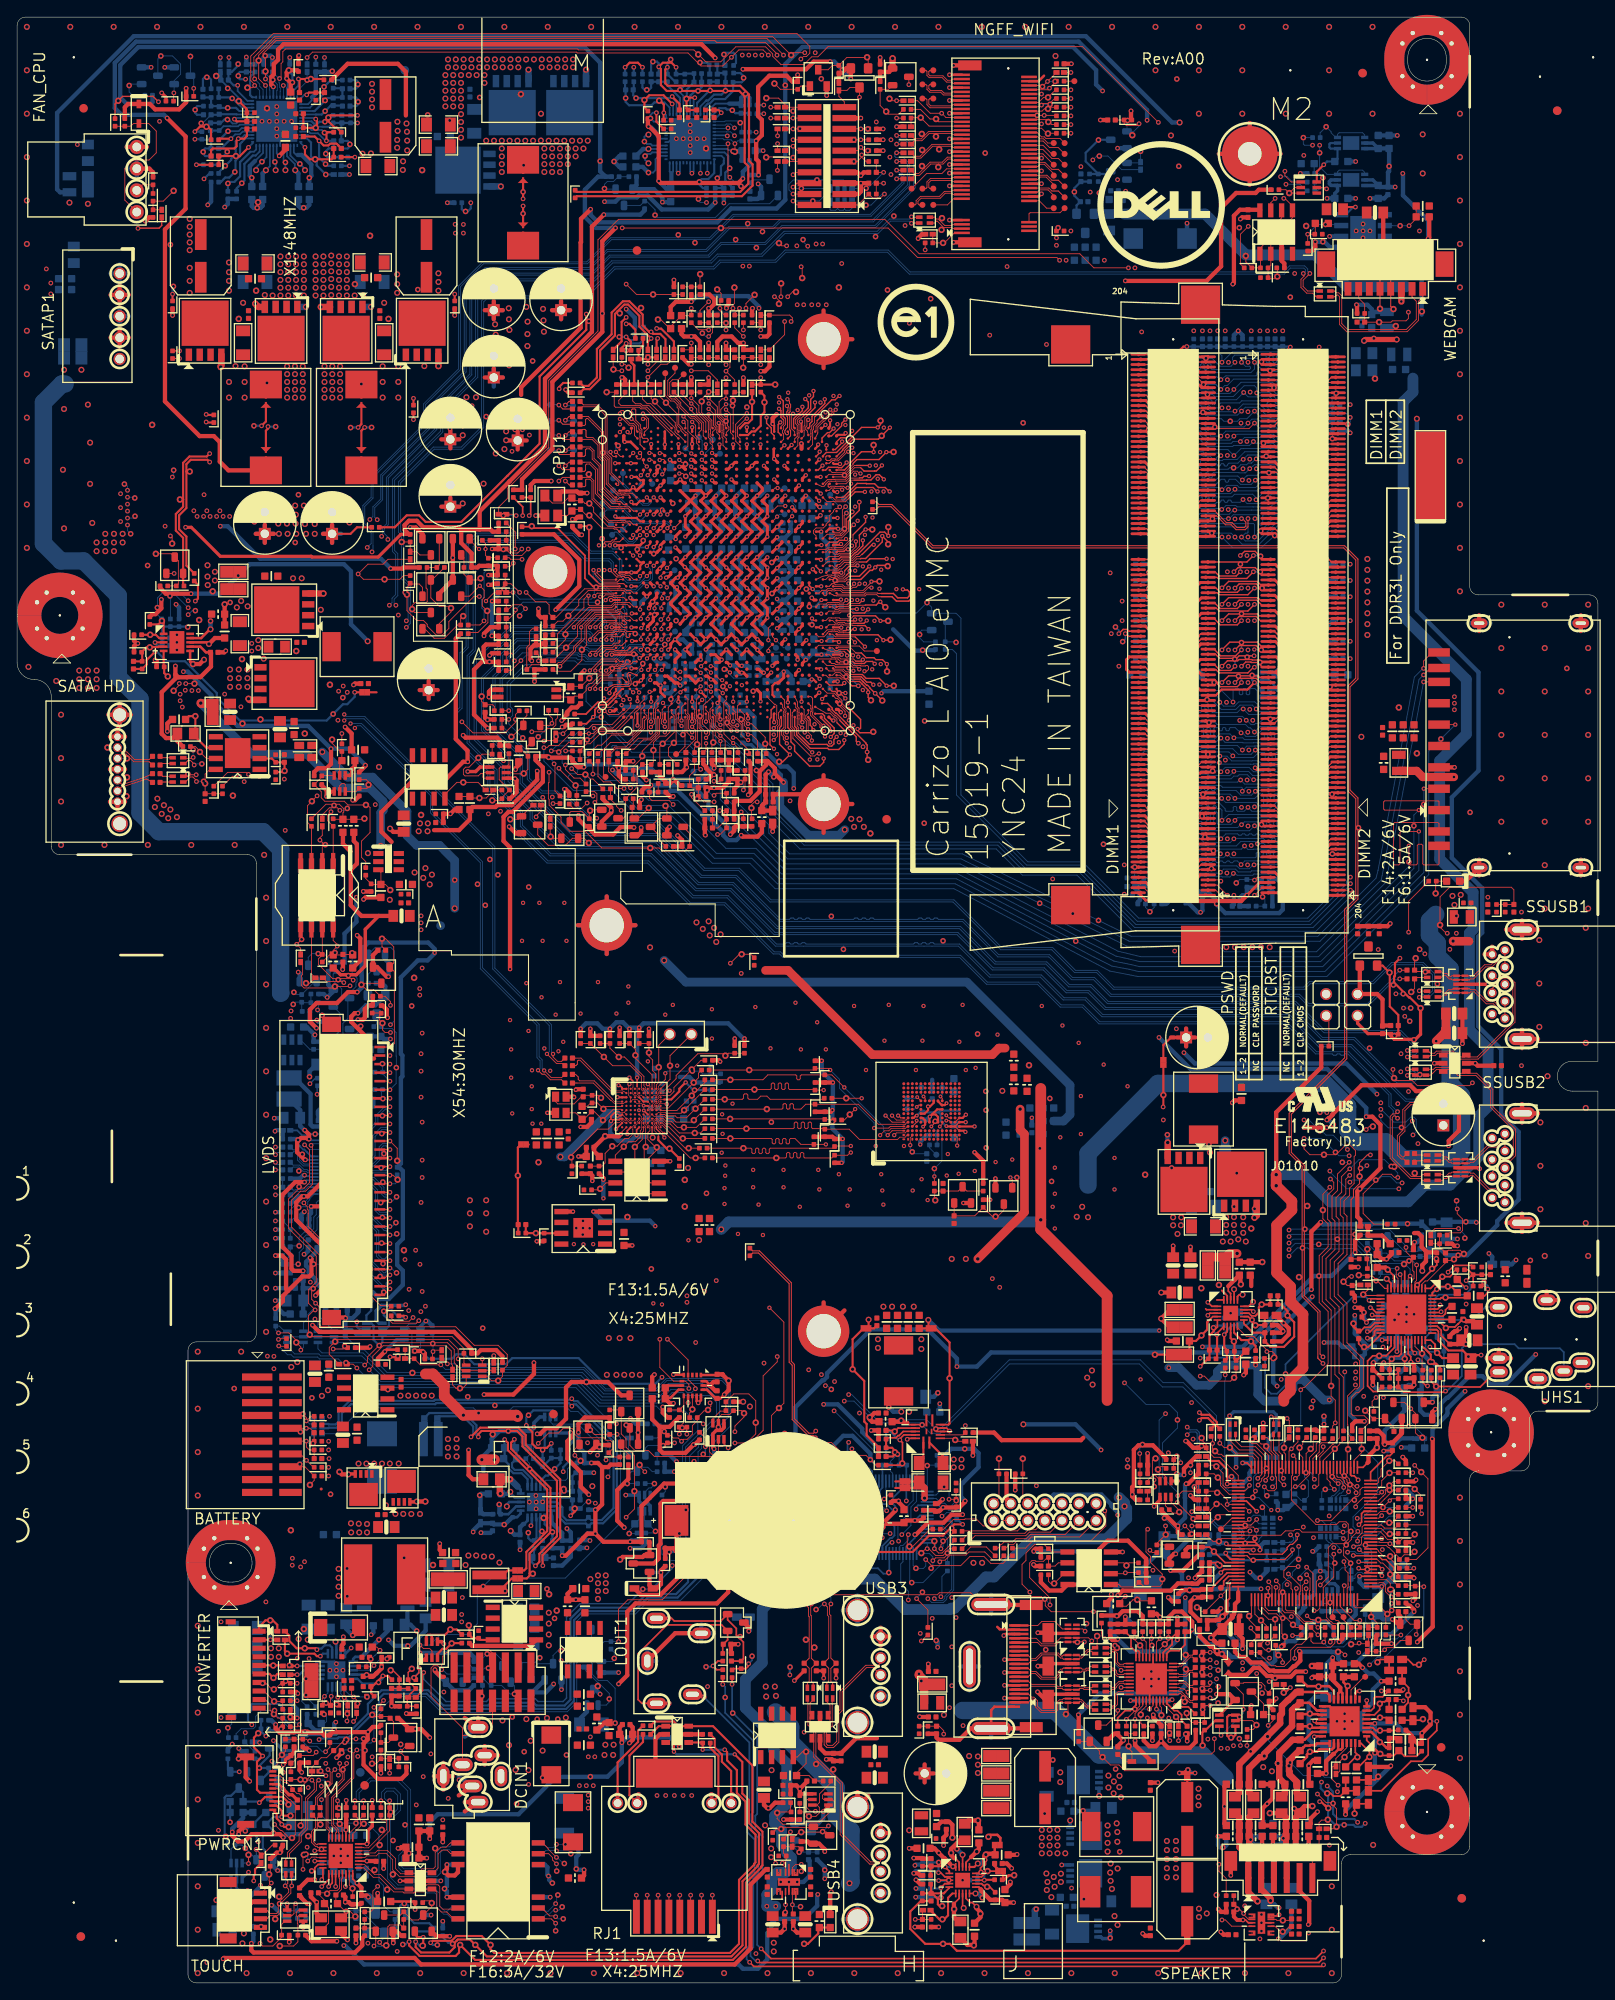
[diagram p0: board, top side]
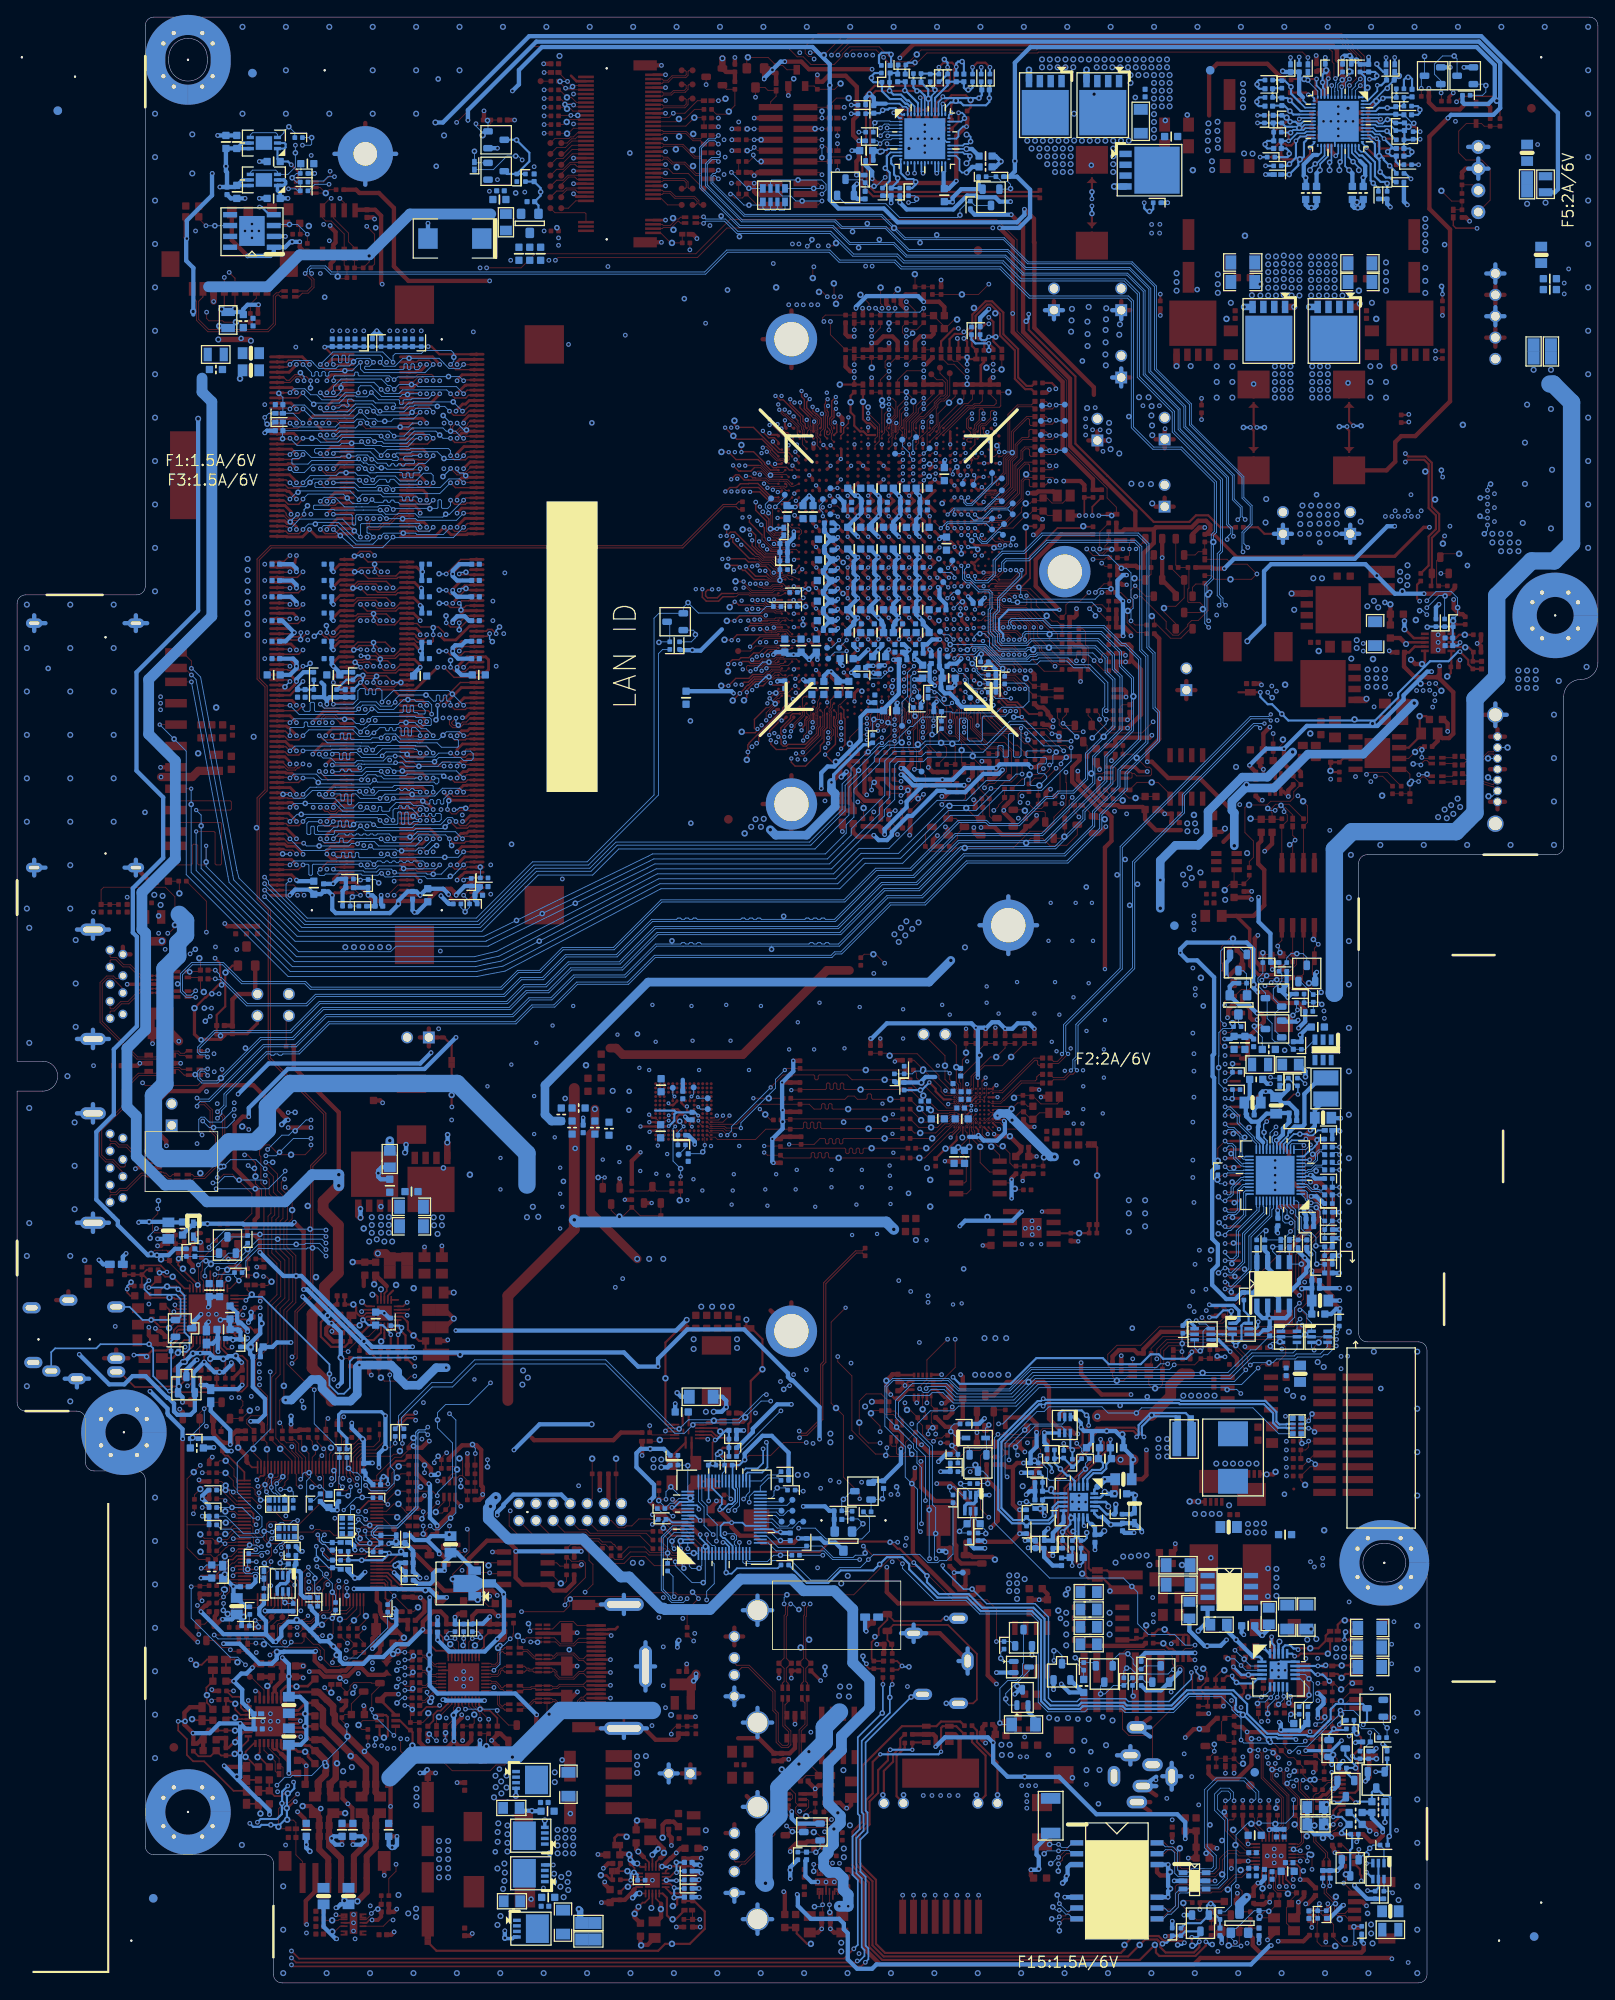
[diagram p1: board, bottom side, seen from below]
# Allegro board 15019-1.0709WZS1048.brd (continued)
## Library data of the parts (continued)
R358 = R402H16: tolerance: 64.56015.6DL
R376 = R603H22: tolerance: 63.10033.15L
R389 R79726 = R805H24: tolerance: 64.10025.16L
R396 R403 R415 R419 = R603H22: tolerance: 64.3R305.55L
R412 = R402H16: tolerance: 64.24915.6DL
R428 R429 = R402H16: tolerance: 63.47034.1DL
R495 R1617 R1623 = R402H16: tolerance: 63.30134.1DL
R511 = R402H16: tolerance: 64.12025.6DL
R558 = R402H16: tolerance: 64.16915.6DL
R617 R79721 = R402H16: tolerance: 63.33334.1DL
R724 R730 R735 R1751 R79612 = R603H22: tolerance: 64.75R05.55L
R1592 = R603H22: tolerance: 64.36R05.55L
R1593 R1594 R1596 R1598 R2085-R2090 = R402H16: tolerance: 64.47015.6DL
R1603 R1816 = R402H16: tolerance: 64.20015.6DL
R1671 = R603H22: tolerance: 63.20634.15L
R1677 R90067 = R402H16: tolerance: 63.47334.1DL
R1767 R1846 = R603H22: tolerance: 63.15234.15L
R1833 R1838 = R402H16: tolerance: 64.17825.6DL
R1847 = R603H22: tolerance: 64.10035.L0L
R1848 = R603H22: tolerance: 63.10333.15L
R1850 = R603H22: tolerance: 64.56025.55L
R1867 R1869 R1871 R1873 R2004 R2008 R2063 = R402H16: tolerance: 63.20234.1DL
R2003 = R402H16: tolerance: 64.19605.6DL
R2081 = R603H22: tolerance: 64.18005.55L
R2082 = R402H16: tolerance: 64.43015.6DL
R4707 R4708 = R402H16: tolerance: 64.11015.6DL
R79619 = R805H24: tolerance: 63.1R031.16L
R79630 = R805H24: tolerance: 63.20131.16L
R79675 = R402H16: tolerance: 063.10434.01DV
R90006 R90007 = R402H14: tolerance: 63.10034.1DL
R90030 = R402H16: tolerance: 64.25525.6DL
R90076 = R402H16: tolerance: 64.68005.6DL
RJ1 = 23-01120-2A03-A: tolerance: 062.10032.0041
RN7 RN10 = ARES8-CN24-MUH20: tolerance: 66.10336.08L
RN8 RN9 = ARES2H18: tolerance: 66.10336.04L
RN12 = SMD-ARES8-1H26: tolerance: 66.10236.A8L
RN13 RN4301 = ARES8-CN24-UH20: tolerance: 66.33036.A8L
RT1-RT3 = NTC-402H22-U: tolerance: 69.60011.121
RV1 = TVS5436-1121H105: tolerance: 069.A0007.0001
SATAP1 = CI2505P1H00-LF-U: tolerance: 021.60197.0105
SPI1 = SOIC8-1H86: tolerance: 72.25640.D01
SPK1 = A1501WV0-6PS-5E: tolerance: 21.D0278.106
SPR1 = SPR10637H367: tolerance: 34.39S07.003
SRCON1 = SKT-SOIC8-092117H235: tolerance: 62.10089.001
SSUSB1 SSUSB2 = SKT-USB11-138165-1: tolerance: 022.10005.0391
TC1 = CT7343H75: tolerance: 77.23371.13L
TC7 TC8 = ECAP-100D6D3H237: tolerance: 09.1071D.A5L
TOUCH1 = 3703K-Q05N-11L: tolerance: 020.F0146.0005
TP6 TP8 TP9 TP24-TP26 TP28 TP37-TP39 TP62-TP84 TP174-TP184 TP186-TP190 TP192-TP196 TP198 TP199 TP208 TP210-TP215 TP4124-TP4130 TP4142-TP4149 TP5001-TP5017 = TPAD28: tolerance: ZZ.PAD28.XXX
TR1 TR3 TR4 TR10 TR14 = L125100-4P-4H28: tolerance: 68.01012.20B
TR9 TR12 = L125100-4P-1H37: tolerance: 68.01012.201
TR16-TR19 = L125100-4P-1H28: tolerance: 68.10129.201
U1 U105 = SOT-6-1H50: tolerance: 84.06402.B3D
U3 U5 U31 U116 U117 = DFN10G2510H26: tolerance: 75.01045.073
U6 = QFN48J6-G465H40: tolerance: 71.03661.003
U7 = SOIC8H69: tolerance: 72.25106.001
U10-U12 = SOT-6H58: tolerance: 75.09904.07C
U16 = QFN32J4-G2D85H36: tolerance: 71.08111.U03
U21 = QFN32-G3D55H40: tolerance: 74.03131.013
U25 = SOIC8H69: tolerance: 72.24C64.R01
U26 = QFN48J6-G4D55H40: tolerance: 71.02136.003
U52 U54 = SON14J3020-G2610H34: tolerance: 74.22966.093
U55 = QFN20G3D5-G2D15H40: tolerance: 74.24727.A73
U109 = LQFP128H63: tolerance: 071.08739.000G
U118 = QFN40J5-G3D65H32: tolerance: 071.08407.0003
U119 = SOT-89-4541-3PH63: tolerance: 074.01117.0038
U120 = QFN20-G2D1H32: tolerance: 074.00554.0073
U178 = SOIC8H69: tolerance: 074.03702.0021
U902 = CSP97G60-1H41: tolerance: 071.07882.000U
U903 = BGA153G115130-1H40: tolerance: 072.KMBG4.0C0U
U4101 = LQFP64H63: tolerance: 071.00948.000G
U6701 = LGA16G3-1H40: tolerance: 074.01010.00B3
U9001 = SOIC8-G2D3H70: tolerance: 74.09025.D3D
U9003 = SOIC8H69: tolerance: 72.25512.J01
UHS1 = 2SJ3082-038111F: tolerance: 022.10002.0881
UR5-UR7 = R402H16: tolerance: 64.33005.6DL
USB3 USB4 = SKT-USB6-135063: tolerance: 022.10005.01E1
WEBCM1 = A1251WR0-8PS-5E: tolerance: 20.F1245.008
X1 = OSC-3225-4P-4H36: tolerance: 82.30026.281
X2 = SMD49-6914-0403H56: tolerance: 82.30001.G11
X4 = OSC-3225-4P-4H36: tolerance: 82.30020.G71
X54 = SMD-OSC19H20: tolerance: 82.30060.171
XF1 XF2 = XFORM12A127097H91: tolerance: 68.68167.30D

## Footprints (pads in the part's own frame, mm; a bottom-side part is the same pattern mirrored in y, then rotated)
0R0402-PAD
  custom 0.14x0.14 smd: 1(0,0.445) 2(0,-0.445)
0R0402-PAD-1
  custom 0.14x0.14 smd: 1(0,0.445) 2(0,-0.445)
0R0603-PAD
  custom 0.216x0.216 smd: 1(0,0.851) 2(0,-0.673)
0R0603-PAD-1-U
  custom 0.216x0.216 smd: 1(0,0.762) 2(0,-0.762)
0R0805-PAD
  rect 1.397x1.562 smd: 1(0,0.965)
  rect 1.397x1.569 smd: 2(0,-0.965)
0R1206-PAD-1
  rect 1.651x2.057 smd: 1(0,1.397) 2(0,-1.397)
2DC3115-000111F
  oval 1.422x2.413 hole 0.711x1.702: 1(-1.1,1.46)
  oval 1.473x2.413 hole 0.762x1.702: 2(2.5,0) 5(4.375,0.7) 7(-4.375,0.7)
  oval 1.524x2.413 hole 0.813x1.702: 3(0,-1.13)
  oval 2.413x1.473 hole 1.702x0.762: 4(1.35,3.375) 6(1.35,-3.375)
2SJ3082-038111F
  round 0.254 hole 1.27 unplated: (0,0) (0,-6)
  oval 1.321x2.134 hole 0.61x1.422: 1(3.8,3.1) 2(-3.7,-4.5) 3(3.7,-6.8) 4(-2.7,-6.6) 5(-2.2,3.1) 6(-3.8,3.1) MS1(-4.6,-1.5) MS2(4.6,-2.5)
15-02070-5A61-A
  round 1.041 hole 0.762: 1(3.81,-0.25) 2(2.54,-0.25) 3(1.27,-0.25) 4(0,-0.25) 5(-1.27,-0.25) 6(-2.54,-0.25) 7(-3.81,-0.25)
  round 1.93 hole 1.524: 8(6.37,0) 9(-6.37,0)
23-01120-2A03-A
  rect 0.813x3.988 smd: 1(-4.445,13.3) 2(-3.175,13.3) 3(-1.905,13.3) 4(-0.635,13.3) 5(0.635,13.3) 6(1.905,13.3) 7(3.175,13.3) 8(4.445,13.3)
  round 1.321 hole 0.914: 9(-6.645,0) 10(-4.355,0) 11(4.355,0) 12(6.645,0)
  rect 8.992x3.404 smd: 13(0,-3.5)
156-5101902601
  round 0.254 hole 1.702 unplated: (-12.65,0) (12.65,0)
  rect 0.991x2.54 smd: 1(-7.57,8.245) 2(-5.07,8.245) 3(-2.57,8.245) 4(-0.07,8.245) 5(2.43,8.245) 6(4.93,8.245) 7(7.43,8.245) 8(9.055,8.245) 9(-10.07,8.245) 10(10.875,8.245) 11(-11.755,8.245)
  oval 1.118x1.93 hole 0.406x1.219: 12(-14.3,3.55) 13(14.3,3.55) 14(-14.3,-8.35) 15(14.3,-8.35)
3703K-Q05N-11L
  rect 0.61x1.549 smd: 1(-2,3.775) 2(-1,3.775) 3(0,3.775) 4(1,3.775) 5(2,3.775)
  rect 1.194x2.007 smd: 6(-3.3,0) 7(3.3,0)
50290-0100N-001
  rect 0.838x3.556 smd: 1A(-6.75,-3.9) 2A(-5.25,-3.9) 3A(-3.75,-3.9) 4A(-2.25,-3.9) 5A(-0.75,-3.9) 6A(0.75,-3.9) 7A(2.25,-3.9) 8A(3.75,-3.9) 9A(5.25,-3.9) 10A(6.75,-3.9)
  rect 0.838x2.642 smd: 1B(-6.75,0) 2B(-5.25,0) 3B(-3.75,0) 4B(-2.25,0) 5B(-0.75,0) 6B(0.75,0) 7B(2.25,0) 8B(3.75,0) 9B(5.25,0) 10B(6.75,0)
50524-0300N-001
  rect 0.305x1.295 smd: 1(-14.5,5.65) 2(-13.5,5.65) 3(-12.5,5.65) 4(-11.5,5.65) 5(-10.5,5.65) 6(-9.5,5.65) 7(-8.5,5.65) 8(-7.5,5.65) 9(-6.5,5.65) 10(-5.5,5.65) 11(-4.5,5.65) 12(-3.5,5.65) 13(-2.5,5.65) 14(-1.5,5.65) 15(-0.5,5.65) 16(0.5,5.65) 17(1.5,5.65) 18(2.5,5.65) 19(3.5,5.65) 20(4.5,5.65) 21(5.5,5.65) 22(6.5,5.65) 23(7.5,5.65) 24(8.5,5.65) 25(9.5,5.65) 26(10.5,5.65) 27(11.5,5.65) 28(12.5,5.65) 29(13.5,5.65) 30(14.5,5.65)
  rect 1.803x2.21 smd: 31(-17.15,0) 32(17.15,0)
51530-01041-W01
  rect 0.305x0.838 smd: 1(-2.25,3.175) 2(-1.75,3.175) 3(-1.25,3.175) 4(-0.75,3.175) 5(-0.25,3.175) 6(0.25,3.175) 7(0.75,3.175) 8(1.25,3.175) 9(1.75,3.175) 10(2.25,3.175)
  rect 0.813x2.007 smd: 11(-3.95,0) 12(3.95,0)
88314-077N
  rect 0.838x3.556 smd: 1(-4.5,-3.225) 2(-3,-3.225) 3(-1.5,-3.225) 4(0,-3.225) 5(1.5,-3.225) 6(3,-3.225) 7(4.5,-3.225)
  rect 0.838x2.642 smd: 8(-4.5,0.675) 9(-3,0.675) 10(-1.5,0.675) 11(0,0.675) 12(1.5,0.675) 13(3,0.675) 14(4.5,0.675)
2199230-7
  round 0.254 hole 1.6 unplated: (-10,0)
  round 0.254 hole 1.118 unplated: (10,0)
  rect 0.305x1.854 smd: 1(9.25,-5.423) 2(9,2.423) 3(8.75,-5.423) 4(8.5,2.423) 5(8.25,-5.423) 6(8,2.423) 7(7.75,-5.423) 16(5.5,2.423) 17(5.25,-5.423) 18(5,2.423) 19(4.75,-5.423) 20(4.5,2.423) 21(4.25,-5.423) 22(4,2.423) 23(3.75,-5.423) 24(3.5,2.423) 25(3.25,-5.423) 26(3,2.423) 27(2.75,-5.423) 28(2.5,2.423) 29(2.25,-5.423) 30(2,2.423) 31(1.75,-5.423) 32(1.5,2.423) 33(1.25,-5.423) 34(1,2.423) 35(0.75,-5.423) 36(0.5,2.423) 37(0.25,-5.423) 38(0,2.423) 39(-0.25,-5.423) 40(-0.5,2.423) 41(-0.75,-5.423) 42(-1,2.423) 43(-1.25,-5.423) 44(-1.5,2.423) 45(-1.75,-5.423) 46(-2,2.423) 47(-2.25,-5.423) 48(-2.5,2.423) 49(-2.75,-5.423) 50(-3,2.423) 51(-3.25,-5.423) 52(-3.5,2.423) 53(-3.75,-5.423) 54(-4,2.423) 55(-4.25,-5.423) 56(-4.5,2.423) 57(-4.75,-5.423) 58(-5,2.423) 59(-5.25,-5.423) 60(-5.5,2.423) 61(-5.75,-5.423) 62(-6,2.423) 63(-6.25,-5.423) 64(-6.5,2.423) 65(-6.75,-5.423) 66(-7,2.423) 67(-7.25,-5.423) 68(-7.5,2.423) 69(-7.75,-5.423) 70(-8,2.423) 71(-8.25,-5.423) 72(-8.5,2.423) 73(-8.75,-5.423) 74(-9,2.423) 75(-9.25,-5.423)
  rect 1.194x2.743 smd: 76(10.35,-4.5) 77(-10.35,-4.5)
14300002
  round 1.397 hole 0.991: 1(1.27,0) 2(-1.27,0)
A1251WR0-8PS-5E
  rect 0.813x1.6 smd: 1(-4.375,2.9) 2(-3.125,2.9) 3(-1.875,2.9) 4(-0.625,2.9) 5(0.625,2.9) 6(1.875,2.9) 7(3.125,2.9) 8(4.375,2.9)
  rect 2.108x2.997 smd: 9(-6.925,0) 10(6.925,0)
A1501WV0-6PS-5E
  rect 0.711x3.505 smd: 1(3.75,2) 2(2.25,2) 3(0.75,2) 4(-0.75,2) 5(-2.25,2) 6(-3.75,2)
  rect 1.499x2.311 smd: 7(5.8,0) 8(-5.8,0)
A2541WV0-1EX2PA-6T
  round 1.397 hole 0.991: 1(-1.27,0) 2(1.27,0)
AAA-BAT-034-K01
  round 0.254 hole 1.067 unplated: (-7.5,0)
  round 0.254 hole 1.372 unplated: (0,0)
  rect 2.794x3.607 smd: 1(6.2,0)
  rect 2.997x2.591 smd: 2(-15.1,0)
AFTE14P-75
  round 0.356 smd: 1(0,0)
ARES2H18
  rect 0.356x0.66 smd: 1(-0.325,-0.599) 2(0.325,-0.599) 3(0.325,0.599) 4(-0.325,0.599)
ARES8-CN24-MUH20
  rect 0.61x0.66 smd: 1(-0.9,-0.486) 4(0.9,-0.486) 5(0.9,0.486) 8(-0.9,0.486)
  rect 0.305x0.66 smd: 2(-0.25,-0.486) 3(0.25,-0.486) 6(0.25,0.486) 7(-0.25,0.486)
ARES8-CN24-UH20
  rect 0.61x0.66 smd: 1(-0.9,-0.486) 4(0.9,-0.486) 5(0.9,0.486) 8(-0.9,0.486)
  rect 0.305x0.66 smd: 2(-0.25,-0.486) 3(0.25,-0.486) 6(0.25,0.486) 7(-0.25,0.486)
AS0A621-J4R6-7H-U
  round 0.254 hole 1.118 unplated: (-33.4,0)
  round 0.254 hole 1.6 unplated: (33.4,0)
  custom 0.114x0.114 smd: 1(31.65,4.1) 2(31.35,-4.1) 3(31.05,4.1) 4(30.751,-4.1) 5(30.45,4.1) 6(30.15,-4.1) 7(29.85,4.1) 8(29.55,-4.1) 9(29.251,4.1) 10(28.95,-4.1) 11(28.65,4.1) 12(28.35,-4.1) 13(28.051,4.1) 14(27.751,-4.1) 15(27.45,4.1) 16(27.15,-4.1) 17(26.851,4.1) 18(26.551,-4.1) 19(26.25,4.1) 20(25.95,-4.1) 21(25.65,4.1) 22(25.35,-4.1) 23(25.051,4.1) 24(24.75,-4.1) 25(24.45,4.1) 26(24.15,-4.1) 27(23.851,4.1) 28(23.55,-4.1) 29(23.25,4.1) 30(22.95,-4.1) 31(22.651,4.1) 32(22.351,-4.1) 33(22.05,4.1) 34(21.75,-4.1) 35(21.451,4.1) 36(21.151,-4.1) 37(20.85,4.1) 38(20.55,-4.1) 39(20.25,4.1) 40(19.95,-4.1) 41(19.65,4.1) 42(19.35,-4.1) 43(19.049,4.1) 44(18.749,-4.1) 45(18.45,4.1) 46(18.15,-4.1) 47(17.85,4.1) 48(17.549,-4.1) 49(17.25,4.1) 50(16.95,-4.1) 51(16.65,4.1) 52(16.349,-4.1) 53(16.049,4.1) 54(15.75,-4.1) 55(15.45,4.1) 56(15.15,-4.1) 57(14.849,4.1) 58(14.549,-4.1) 59(14.25,4.1) 60(13.95,-4.1) 61(13.649,4.1) 62(13.349,-4.1) 63(13.05,4.1) 64(12.75,-4.1) 65(12.45,4.1) 66(12.149,-4.1) 67(11.85,4.1) 68(11.55,-4.1) 69(11.25,4.1) 70(10.95,-4.1) 71(10.649,4.1) 72(10.349,-4.1) 73(7.65,4.1) 74(7.35,-4.1) 75(7.049,4.1) 76(6.749,-4.1) 77(6.45,4.1) 78(6.15,-4.1) 79(5.85,4.1) 80(5.549,-4.1) 81(5.25,4.1) 82(4.95,-4.1) 83(4.65,4.1) 84(4.349,-4.1) 85(4.05,4.1) 86(3.75,-4.1) 87(3.45,4.1) 88(3.15,-4.1) 89(2.849,4.1) 90(2.549,-4.1) 91(2.25,4.1) 92(1.95,-4.1) 93(1.649,4.1) 94(1.349,-4.1) 95(1.05,4.1) 96(0.75,-4.1) 97(0.45,4.1) 98(0.149,-4.1) 99(-0.15,4.1) 100(-0.45,-4.1) 101(-0.75,4.1) 102(-1.051,-4.1) 103(-1.351,4.1) 104(-1.65,-4.1) 105(-1.95,4.1) 106(-2.25,-4.1) 107(-2.551,4.1) 108(-2.851,-4.1) 109(-3.15,4.1) 110(-3.45,-4.1) 111(-3.751,4.1) 112(-4.051,-4.1) 113(-4.35,4.1) 114(-4.65,-4.1) 115(-4.95,4.1) 116(-5.251,-4.1) 117(-5.55,4.1) 118(-5.85,-4.1) 119(-6.15,4.1) 120(-6.451,-4.1) 121(-6.751,4.1) 122(-7.051,-4.1) 123(-7.35,4.1) 124(-7.65,-4.1) 125(-7.951,4.1) 126(-8.251,-4.1) 127(-8.55,4.1) 128(-8.85,-4.1) 129(-9.15,4.1) 130(-9.451,-4.1) 131(-9.75,4.1) 132(-10.05,-4.1) 133(-10.35,4.1) 134(-10.651,-4.1) 135(-10.95,4.1) 136(-11.25,-4.1) 137(-11.55,4.1) 138(-11.85,-4.1) 139(-12.151,4.1) 140(-12.451,-4.1) 141(-12.75,4.1) 142(-13.05,-4.1) 143(-13.351,4.1) 144(-13.651,-4.1) 145(-13.95,4.1) 146(-14.25,-4.1) 147(-14.55,4.1) 148(-14.851,-4.1) 149(-15.15,4.1) 150(-15.45,-4.1) 151(-15.75,4.1) 152(-16.051,-4.1) 153(-16.35,4.1) 154(-16.65,-4.1) 155(-16.95,4.1) 156(-17.25,-4.1) 157(-17.551,4.1) 158(-17.851,-4.1) 159(-18.15,4.1) 160(-18.45,-4.1) 161(-18.751,4.1) 162(-19.051,-4.1) 163(-19.35,4.1) 164(-19.65,-4.1) 165(-19.95,4.1) 166(-20.251,-4.1) 167(-20.55,4.1) 168(-20.85,-4.1) 169(-21.15,4.1) 170(-21.451,-4.1) 171(-21.751,4.1) 172(-22.051,-4.1) 173(-22.35,4.1) 174(-22.65,-4.1) 175(-22.951,4.1) 176(-23.251,-4.1) 177(-23.55,4.1) 178(-23.85,-4.1) 179(-24.151,4.1) 180(-24.451,-4.1) 181(-24.75,4.1) 182(-25.05,-4.1) 183(-25.35,4.1) 184(-25.651,-4.1) 185(-25.95,4.1) 186(-26.25,-4.1) 187(-26.55,4.1) 188(-26.851,-4.1) 189(-27.151,4.1) 190(-27.451,-4.1) 191(-27.75,4.1) 192(-28.05,-4.1) 193(-28.351,4.1) 194(-28.651,-4.1) 195(-28.95,4.1) 196(-29.25,-4.1) 197(-29.55,4.1) 198(-29.851,-4.1) 199(-30.15,4.1) 200(-30.45,-4.1) 201(-30.75,4.1) 202(-31.05,-4.1) 203(-31.349,4.1) 204(-31.649,-4.1)
  rect 4.496x4.597 smd: 205(32.8,12) 206(-32.8,12)
AS0A626-J8R6-7H
  round 0.254 hole 1.067 unplated: (-33.4,0)
  round 0.254 hole 1.6 unplated: (33.4,0)
  custom 0.114x0.114 smd: 1(31.65,4.1) 2(31.35,-4.1) 3(31.05,4.1) 4(30.75,-4.1) 5(30.45,4.1) 6(30.15,-4.1) 7(29.85,4.1) 8(29.55,-4.1) 9(29.25,4.1) 10(28.95,-4.1) 11(28.65,4.1) 12(28.35,-4.1) 13(28.05,4.1) 14(27.75,-4.1) 15(27.45,4.1) 16(27.15,-4.1) 17(26.85,4.1) 18(26.55,-4.1) 19(26.25,4.1) 20(25.95,-4.1) 21(25.65,4.1) 22(25.35,-4.1) 23(25.05,4.1) 24(24.75,-4.1) 25(24.45,4.1) 26(24.15,-4.1) 27(23.85,4.1) 28(23.55,-4.1) 29(23.25,4.1) 30(22.95,-4.1) 31(22.65,4.1) 32(22.35,-4.1) 33(22.05,4.1) 34(21.75,-4.1) 35(21.45,4.1) 36(21.15,-4.1) 37(20.85,4.1) 38(20.55,-4.1) 39(20.25,4.1) 40(19.95,-4.1) 41(19.65,4.1) 42(19.35,-4.1) 43(19.05,4.1) 44(18.75,-4.1) 45(18.45,4.1) 46(18.15,-4.1) 47(17.85,4.1) 48(17.55,-4.1) 49(17.25,4.1) 50(16.95,-4.1) 51(16.65,4.1) 52(16.35,-4.1) 53(16.05,4.1) 54(15.75,-4.1) 55(15.45,4.1) 56(15.15,-4.1) 57(14.85,4.1) 58(14.55,-4.1) 59(14.25,4.1) 60(13.95,-4.1) 61(13.65,4.1) 62(13.35,-4.1) 63(13.05,4.1) 64(12.75,-4.1) 65(12.45,4.1) 66(12.15,-4.1) 67(11.85,4.1) 68(11.55,-4.1) 69(11.25,4.1) 70(10.95,-4.1) 71(10.65,4.1) 72(10.35,-4.1) 73(7.65,4.1) 74(7.35,-4.1) 75(7.05,4.1) 76(6.75,-4.1) 77(6.45,4.1) 78(6.15,-4.1) 79(5.85,4.1) 80(5.55,-4.1) 81(5.25,4.1) 82(4.95,-4.1) 83(4.65,4.1) 84(4.35,-4.1) 85(4.05,4.1) 86(3.75,-4.1) 87(3.45,4.1) 88(3.15,-4.1) 89(2.85,4.1) 90(2.55,-4.1) 91(2.25,4.1) 92(1.95,-4.1) 93(1.65,4.1) 94(1.35,-4.1) 95(1.05,4.1) 96(0.75,-4.1) 97(0.45,4.1) 98(0.15,-4.1) 99(-0.15,4.1) 100(-0.45,-4.1) 101(-0.75,4.1) 102(-1.05,-4.1) 103(-1.35,4.1) 104(-1.65,-4.1) 105(-1.95,4.1) 106(-2.25,-4.1) 107(-2.55,4.1) 108(-2.85,-4.1) 109(-3.15,4.1) 110(-3.45,-4.1) 111(-3.75,4.1) 112(-4.05,-4.1) 113(-4.35,4.1) 114(-4.65,-4.1) 115(-4.95,4.1) 116(-5.25,-4.1) 117(-5.55,4.1) 118(-5.85,-4.1) 119(-6.15,4.1) 120(-6.45,-4.1) 121(-6.75,4.1) 122(-7.05,-4.1) 123(-7.35,4.1) 124(-7.65,-4.1) 125(-7.95,4.1) 126(-8.25,-4.1) 127(-8.55,4.1) 128(-8.85,-4.1) 129(-9.15,4.1) 130(-9.45,-4.1) 131(-9.75,4.1) 132(-10.05,-4.1) 133(-10.35,4.1) 134(-10.65,-4.1) 135(-10.95,4.1) 136(-11.25,-4.1) 137(-11.55,4.1) 138(-11.85,-4.1) 139(-12.15,4.1) 140(-12.45,-4.1) 141(-12.75,4.1) 142(-13.05,-4.1) 143(-13.35,4.1) 144(-13.65,-4.1) 145(-13.95,4.1) 146(-14.25,-4.1) 147(-14.55,4.1) 148(-14.85,-4.1) 149(-15.15,4.1) 150(-15.45,-4.1) 151(-15.75,4.1) 152(-16.05,-4.1) 153(-16.35,4.1) 154(-16.65,-4.1) 155(-16.95,4.1) 156(-17.25,-4.1) 157(-17.55,4.1) 158(-17.85,-4.1) 159(-18.15,4.1) 160(-18.45,-4.1) 161(-18.75,4.1) 162(-19.05,-4.1) 163(-19.35,4.1) 164(-19.65,-4.1) 165(-19.95,4.1) 166(-20.25,-4.1) 167(-20.55,4.1) 168(-20.85,-4.1) 169(-21.15,4.1) 170(-21.45,-4.1) 171(-21.75,4.1) 172(-22.05,-4.1) 173(-22.35,4.1) 174(-22.65,-4.1) 175(-22.95,4.1) 176(-23.25,-4.1) 177(-23.55,4.1) 178(-23.85,-4.1) 179(-24.15,4.1) 180(-24.45,-4.1) 181(-24.75,4.1) 182(-25.05,-4.1) 183(-25.35,4.1) 184(-25.65,-4.1) 185(-25.95,4.1) 186(-26.25,-4.1) 187(-26.55,4.1) 188(-26.85,-4.1) 189(-27.15,4.1) 190(-27.45,-4.1) 191(-27.75,4.1) 192(-28.05,-4.1) 193(-28.35,4.1) 194(-28.65,-4.1) 195(-28.95,4.1) 196(-29.25,-4.1) 197(-29.55,4.1) 198(-29.85,-4.1) 199(-30.15,4.1) 200(-30.45,-4.1) 201(-30.75,4.1) 202(-31.05,-4.1) 203(-31.35,4.1) 204(-31.65,-4.1)
  rect 4.496x4.597 smd: 205(-37.45,12) 206(37.45,12)
ASP-137098-05
  rect 0.737x2.794 smd: 1(-5.715,-2.035) 2(-5.715,2.035) 3(-4.445,-2.035) 4(-4.445,2.035) 5(-3.175,-2.035) 6(-3.175,2.035) 7(-1.905,-2.035) 8(-1.905,2.035) 9(-0.635,-2.035) 10(-0.635,2.035) 11(0.635,-2.035) 12(0.635,2.035) 13(1.905,-2.035) 14(1.905,2.035) 15(3.175,-2.035) 16(3.175,2.035) 17(4.445,-2.035) 18(4.445,2.035) 19(5.715,-2.035) 20(5.715,2.035)
BGA153G115130-1H40
  oval 0.229x0.356 smd: A1(-3.25,3.25) A2(-2.75,3.25) A3(-2.25,3.25) A4(-1.75,3.25) A5(-1.25,3.25) A6(-0.75,3.25)
  round 0.356 smd: A7(-0.25,3.25) A8(0.25,3.25) A9(0.75,3.25) A10(1.25,3.25) A11(1.75,3.25) A12(2.25,3.25) A13(2.75,3.25) A14(3.25,3.25) B2(-2.75,2.75) B3(-2.25,2.75) B4(-1.75,2.75) B5(-1.25,2.75) B6(-0.75,2.75) B7(-0.25,2.75) B8(0.25,2.75) B9(0.75,2.75) B10(1.25,2.75) B11(1.75,2.75) B12(2.25,2.75) B13(2.75,2.75) B14(3.25,2.75) C2(-2.75,2.25) C3(-2.25,2.25) C4(-1.75,2.25) C5(-1.25,2.25) C6(-0.75,2.25) C7(-0.25,2.25) C8(0.25,2.25) C9(0.75,2.25) C10(1.25,2.25) C11(1.75,2.25) C12(2.25,2.25) C13(2.75,2.25) C14(3.25,2.25) D1(-3.25,1.75) D2(-2.75,1.75) D3(-2.25,1.75) D4(-1.75,1.75) D12(2.25,1.75) D13(2.75,1.75) D14(3.25,1.75) E1(-3.25,1.25) E2(-2.75,1.25) E3(-2.25,1.25) E5(-1.25,1.25) E6(-0.75,1.25) E7(-0.25,1.25) E8(0.25,1.25) E9(0.75,1.25) E10(1.25,1.25) E12(2.25,1.25) E13(2.75,1.25) E14(3.25,1.25) F1(-3.25,0.75) F2(-2.75,0.75) F3(-2.25,0.75) F5(-1.25,0.75) F10(1.25,0.75) F12(2.25,0.75) F13(2.75,0.75) F14(3.25,0.75) G1(-3.25,0.25) G2(-2.75,0.25) G3(-2.25,0.25) G5(-1.25,0.25) G10(1.25,0.25) G12(2.25,0.25) G13(2.75,0.25) G14(3.25,0.25) H1(-3.25,-0.25) H2(-2.75,-0.25) H3(-2.25,-0.25) H5(-1.25,-0.25) H10(1.25,-0.25) H12(2.25,-0.25) H13(2.75,-0.25) H14(3.25,-0.25) J1(-3.25,-0.75) J2(-2.75,-0.75) J3(-2.25,-0.75) J5(-1.25,-0.75) J10(1.25,-0.75) J12(2.25,-0.75) J13(2.75,-0.75) J14(3.25,-0.75) K1(-3.25,-1.25) K2(-2.75,-1.25) K3(-2.25,-1.25) K5(-1.25,-1.25) K6(-0.75,-1.25) K7(-0.25,-1.25) K8(0.25,-1.25) K9(0.75,-1.25) K10(1.25,-1.25) K12(2.25,-1.25) K13(2.75,-1.25) K14(3.25,-1.25) L1(-3.25,-1.75) L2(-2.75,-1.75) L3(-2.25,-1.75) L12(2.25,-1.75) L13(2.75,-1.75) L14(3.25,-1.75) M2(-2.75,-2.25) M3(-2.25,-2.25) M4(-1.75,-2.25) M5(-1.25,-2.25) M6(-0.75,-2.25) M7(-0.25,-2.25) M8(0.25,-2.25) M9(0.75,-2.25) M10(1.25,-2.25) M11(1.75,-2.25) M12(2.25,-2.25) M13(2.75,-2.25) M14(3.25,-2.25) N2(-2.75,-2.75) N3(-2.25,-2.75) N4(-1.75,-2.75) N5(-1.25,-2.75) N6(-0.75,-2.75) N7(-0.25,-2.75) N8(0.25,-2.75) N9(0.75,-2.75) N10(1.25,-2.75) N11(1.75,-2.75) N12(2.25,-2.75) N13(2.75,-2.75) N14(3.25,-2.75) P2(-2.75,-3.25) P3(-2.25,-3.25) P4(-1.75,-3.25) P5(-1.25,-3.25) P6(-0.75,-3.25) P7(-0.25,-3.25) P8(0.25,-3.25) P9(0.75,-3.25) P10(1.25,-3.25) P11(1.75,-3.25) P12(2.25,-3.25) P13(2.75,-3.25) P14(3.25,-3.25)
  oval 0.356x0.229 smd: B1(-3.25,2.75) C1(-3.25,2.25) M1(-3.25,-2.25) N1(-3.25,-2.75) P1(-3.25,-3.25)
BGA968M2937H74
  round 0.4 smd: A2(-12,16.9) A3(-11.1,16.9) A31(11.1,16.9) A32(12,16.9) AB5(-9.7,0) AB6(-8.9,0) AB7(-8.1,0) AB8(-7.3,0) AB9(-6.5,0) AB10(-5.4,0) AB12(-4.2,0) AB13(-3,0) AB15(-1.8,0) AB16(-0.6,0) AB18(0.6,0) AB19(1.8,0) AB21(3,0) AB22(4.2,0) AB24(5.4,0) AB25(6.5,0) AB26(7.3,0) AB27(8.1,0) AB28(8.9,0) AB29(9.7,0) AD5(-9.7,-1.2) AD6(-8.9,-1.2) AD7(-8.1,-1.2) AD8(-7.3,-1.2) AD9(-6.5,-1.2) AD10(-5.4,-1.2) AD12(-4.2,-1.2) AD13(-3,-1.2) AD15(-1.8,-1.2) AD16(-0.6,-1.2) AD18(0.6,-1.2) AD19(1.8,-1.2) AD21(3,-1.2) AD22(4.2,-1.2) AD24(5.4,-1.2) AD25(6.5,-1.2) AD26(7.3,-1.2) AD27(8.1,-1.2) AD28(8.9,-1.2) AD29(9.7,-1.2) AE5(-9.7,-2.4) AE6(-8.9,-2.4) AE7(-8.1,-2.4) AE8(-7.3,-2.4) AE9(-6.5,-2.4) AE10(-5.4,-2.4) AE12(-4.2,-2.4) AE13(-3,-2.4) AE15(-1.8,-2.4) AE16(-0.6,-2.4) AE18(0.6,-2.4) AE19(1.8,-2.4) AE21(3,-2.4) AE22(4.2,-2.4) AE24(5.4,-2.4) AE25(6.5,-2.4) AE26(7.3,-2.4) AE27(8.1,-2.4) AE28(8.9,-2.4) AE29(9.7,-2.4) AG5(-9.7,-3.6) AG6(-8.9,-3.6) AG7(-8.1,-3.6) AG8(-7.3,-3.6) AG9(-6.5,-3.6) AG10(-5.4,-3.6) AG12(-4.2,-3.6) AG13(-3,-3.6) AG15(-1.8,-3.6) AG16(-0.6,-3.6) AG18(0.6,-3.6) AG19(1.8,-3.6) AG21(3,-3.6) AG22(4.2,-3.6) AG24(5.4,-3.6) AG25(6.5,-3.6) AG26(7.3,-3.6) AG27(8.1,-3.6) AG28(8.9,-3.6) AG29(9.7,-3.6) AH5(-9.7,-4.8) AH6(-8.9,-4.8) AH7(-8.1,-4.8) AH8(-7.3,-4.8) AH9(-6.5,-4.8) AH10(-5.4,-4.8) AH12(-4.2,-4.8) AH13(-3,-4.8) AH15(-1.8,-4.8) AH16(-0.6,-4.8) AH18(0.6,-4.8) AH19(1.8,-4.8) AH21(3,-4.8) AH22(4.2,-4.8) AH24(5.4,-4.8) AH25(6.5,-4.8) AH26(7.3,-4.8) AH27(8.1,-4.8) AH28(8.9,-4.8) AH29(9.7,-4.8) AK5(-9.7,-6) AK6(-8.9,-6) AK7(-8.1,-6) AK8(-7.3,-6) AK9(-6.5,-6) AK10(-5.4,-6) AK12(-4.2,-6) AK13(-3,-6) AK15(-1.8,-6) AK16(-0.6,-6) AK18(0.6,-6) AK19(1.8,-6) AK21(3,-6) AK22(4.2,-6) AK24(5.4,-6) AK25(6.5,-6) AK26(7.3,-6) AK27(8.1,-6) AK28(8.9,-6) AK29(9.7,-6) AL5(-9.7,-7.2) AL6(-8.9,-7.2) AL7(-8.1,-7.2) AL8(-7.3,-7.2) AL9(-6.5,-7.2) AL10(-5.4,-7.2) AL12(-4.2,-7.2) AL13(-3,-7.2) AL15(-1.8,-7.2) AL16(-0.6,-7.2) AL18(0.6,-7.2) AL19(1.8,-7.2) AL21(3,-7.2) AL22(4.2,-7.2) AL24(5.4,-7.2) AL25(6.5,-7.2) AL26(7.3,-7.2) AL27(8.1,-7.2) AL28(8.9,-7.2) AL29(9.7,-7.2) AN5(-9.7,-8.4) AN6(-8.9,-8.4) AN7(-8.1,-8.4) AN8(-7.3,-8.4) AN9(-6.5,-8.4) AN10(-5.4,-8.4) AN12(-4.2,-8.4) AN13(-3,-8.4) AN15(-1.8,-8.4) AN16(-0.6,-8.4) AN18(0.6,-8.4) AN19(1.8,-8.4) AN21(3,-8.4) AN22(4.2,-8.4) AN24(5.4,-8.4) AN25(6.5,-8.4) AN26(7.3,-8.4) AN27(8.1,-8.4) AN28(8.9,-8.4) AN29(9.7,-8.4) AP5(-9.7,-9.6) AP6(-8.9,-9.6) AP7(-8.1,-9.6) AP8(-7.3,-9.6) AP9(-6.5,-9.6) AP10(-5.4,-9.6) AP12(-4.2,-9.6) AP13(-3,-9.6) AP15(-1.8,-9.6) AP16(-0.6,-9.6) AP18(0.6,-9.6) AP19(1.8,-9.6) AP21(3,-9.6) AP22(4.2,-9.6) AP24(5.4,-9.6) AP25(6.5,-9.6) AP26(7.3,-9.6) AP27(8.1,-9.6) AP28(8.9,-9.6) AP29(9.7,-9.6) AR5(-9.7,-10.8) AR6(-8.9,-10.8) AR7(-8.1,-10.8) AR8(-7.3,-10.8) AR9(-6,-10.5) AR11(-4.8,-10.5) AR12(-3.6,-10.5) AR14(-2.4,-10.5) AR15(-1.2,-10.5) AR17(0,-10.5) AR19(1.2,-10.5) AR20(2.4,-10.5) AR22(3.6,-10.5) AR23(4.8,-10.5) AR25(6,-10.5) AR26(7.3,-10.8) AR27(8.1,-10.8) AR28(8.9,-10.8) AR29(9.7,-10.8) AT9(-6,-11.3) AT11(-4.8,-11.3) AT12(-3.6,-11.3) AT14(-2.4,-11.3) AT15(-1.2,-11.3) AT17(0,-11.3) AT19(1.2,-11.3) AT20(2.4,-11.3) AT22(3.6,-11.3) AT23(4.8,-11.3) AT25(6,-11.3) AU5(-9.7,-12) AU6(-8.9,-12) AU7(-8.1,-12) AU8(-7.2,-12.1) AU9(-6,-12.1) AU11(-4.8,-12.1) AU12(-3.6,-12.1) AU14(-2.4,-12.1) AU15(-1.2,-12.1) AU17(0,-12.1) AU19(1.2,-12.1) AU20(2.4,-12.1) AU22(3.6,-12.1) AU23(4.8,-12.1) AU25(6,-12.1) AU26(7.2,-12.1) AU27(8.1,-12) AU28(8.9,-12) AU29(9.7,-12) AV5(-9.7,-13.2) AV7(-8.4,-12.9) AV8(-7.2,-12.9) AV9(-6,-12.9) AV11(-4.8,-12.9) AV12(-3.6,-12.9) AV14(-2.4,-12.9) AV15(-1.2,-12.9) AV17(0,-12.9) AV19(1.2,-12.9) AV20(2.4,-12.9) AV22(3.6,-12.9) AV23(4.8,-12.9) AV25(6,-12.9) AV26(7.2,-12.9) AV27(8.4,-12.9) AV29(9.7,-13.2) AW7(-8.4,-13.7) AW8(-7.2,-13.7) AW9(-6,-13.7) AW11(-4.8,-13.7) AW12(-3.6,-13.7) AW14(-2.4,-13.7) AW15(-1.2,-13.7) AW17(0,-13.7) AW19(1.2,-13.7) AW20(2.4,-13.7) AW22(3.6,-13.7) AW23(4.8,-13.7) AW25(6,-13.7) AW26(7.2,-13.7) AW27(8.4,-13.7) B1(-12.9,16) B2(-12,16) B32(12,16) B33(12.9,16) BA1(-12.9,-15.1) BA33(12.9,-15.1) BB1(-12.9,-16) BB2(-12,-16) BB32(12,-16) BB33(12.9,-16) BC2(-12,-16.9) BC3(-11.1,-16.9) BC31(11.1,-16.9) BC32(12,-16.9) C1(-12.9,15.1) C33(12.9,15.1) E7(-8.4,13.7) E8(-7.2,13.7) E9(-6,13.7) E11(-4.8,13.7) E12(-3.6,13.7) E14(-2.4,13.7) E15(-1.2,13.7) E17(0,13.7) E19(1.2,13.7) E20(2.4,13.7) E22(3.6,13.7) E23(4.8,13.7) E25(6,13.7) E26(7.2,13.7) E27(8.4,13.7) F5(-9.7,13.2) F7(-8.4,12.9) F8(-7.2,12.9) F9(-6,12.9) F11(-4.8,12.9) F12(-3.6,12.9) F14(-2.4,12.9) F15(-1.2,12.9) F17(0,12.9) F19(1.2,12.9) F20(2.4,12.9) F22(3.6,12.9) F23(4.8,12.9) F25(6,12.9) F26(7.2,12.9) F27(8.4,12.9) F29(9.7,13.2) G5(-9.7,12) G6(-8.9,12) G7(-8.1,12) G8(-7.2,12.1) G9(-6,12.1) G11(-4.8,12.1) G12(-3.6,12.1) G14(-2.4,12.1) G15(-1.2,12.1) G17(0,12.1) G19(1.2,12.1) G20(2.4,12.1) G22(3.6,12.1) G23(4.8,12.1) G25(6,12.1) G26(7.2,12.1) G27(8.1,12) G28(8.9,12) G29(9.7,12) H9(-6,11.3) H11(-4.8,11.3) H12(-3.6,11.3) H14(-2.4,11.3) H15(-1.2,11.3) H17(0,11.3) H19(1.2,11.3) H20(2.4,11.3) H22(3.6,11.3) H23(4.8,11.3) H25(6,11.3) J5(-9.7,10.8) J6(-8.9,10.8) J7(-8.1,10.8) J8(-7.3,10.8) J9(-6,10.5) J11(-4.8,10.5) J12(-3.6,10.5) J14(-2.4,10.5) J15(-1.2,10.5) J17(0,10.5) J19(1.2,10.5) J20(2.4,10.5) J22(3.6,10.5) J23(4.8,10.5) J25(6,10.5) J26(7.3,10.8) J27(8.1,10.8) J28(8.9,10.8) J29(9.7,10.8) K5(-9.7,9.6) K6(-8.9,9.6) K7(-8.1,9.6) K8(-7.3,9.6) K9(-6.5,9.6) K10(-5.4,9.6) K12(-4.2,9.6) K13(-3,9.6) K15(-1.8,9.6) K16(-0.6,9.6) K18(0.6,9.6) K19(1.8,9.6) K21(3,9.6) K22(4.2,9.6) K24(5.4,9.6) K25(6.5,9.6) K26(7.3,9.6) K27(8.1,9.6) K28(8.9,9.6) K29(9.7,9.6) L5(-9.7,8.4) L6(-8.9,8.4) L7(-8.1,8.4) L8(-7.3,8.4) L9(-6.5,8.4) L10(-5.4,8.4) L12(-4.2,8.4) L13(-3,8.4) L15(-1.8,8.4) L16(-0.6,8.4) L18(0.6,8.4) L19(1.8,8.4) L21(3,8.4) L22(4.2,8.4) L24(5.4,8.4) L25(6.5,8.4) L26(7.3,8.4) L27(8.1,8.4) L28(8.9,8.4) L29(9.7,8.4) N5(-9.7,7.2) N6(-8.9,7.2) N7(-8.1,7.2) N8(-7.3,7.2) N9(-6.5,7.2) N10(-5.4,7.2) N12(-4.2,7.2) N13(-3,7.2) N15(-1.8,7.2) N16(-0.6,7.2) N18(0.6,7.2) N19(1.8,7.2) N21(3,7.2) N22(4.2,7.2) N24(5.4,7.2) N25(6.5,7.2) N26(7.3,7.2) N27(8.1,7.2) N28(8.9,7.2) N29(9.7,7.2) P5(-9.7,6) P6(-8.9,6) P7(-8.1,6) P8(-7.3,6) P9(-6.5,6) P10(-5.4,6) P12(-4.2,6) P13(-3,6) P15(-1.8,6) P16(-0.6,6) P18(0.6,6) P19(1.8,6) P21(3,6) P22(4.2,6) P24(5.4,6) P25(6.5,6) P26(7.3,6) P27(8.1,6) P28(8.9,6) P29(9.7,6) T5(-9.7,4.8) T6(-8.9,4.8) T7(-8.1,4.8) T8(-7.3,4.8) T9(-6.5,4.8) T10(-5.4,4.8) T12(-4.2,4.8) T13(-3,4.8) T15(-1.8,4.8) T16(-0.6,4.8) T18(0.6,4.8) T19(1.8,4.8) T21(3,4.8) T22(4.2,4.8) T24(5.4,4.8) T25(6.5,4.8) T26(7.3,4.8) T27(8.1,4.8) T28(8.9,4.8) T29(9.7,4.8) U5(-9.7,3.6) U6(-8.9,3.6) U7(-8.1,3.6) U8(-7.3,3.6) U9(-6.5,3.6) U10(-5.4,3.6) U12(-4.2,3.6) U13(-3,3.6) U15(-1.8,3.6) U16(-0.6,3.6) U18(0.6,3.6) U19(1.8,3.6) U21(3,3.6) U22(4.2,3.6) U24(5.4,3.6) U25(6.5,3.6) U26(7.3,3.6) U27(8.1,3.6) U28(8.9,3.6) U29(9.7,3.6) W5(-9.7,2.4) W6(-8.9,2.4) W7(-8.1,2.4) W8(-7.3,2.4) W9(-6.5,2.4) W10(-5.4,2.4) W12(-4.2,2.4) W13(-3,2.4) W15(-1.8,2.4) W16(-0.6,2.4) W18(0.6,2.4) W19(1.8,2.4) W21(3,2.4) W22(4.2,2.4) W24(5.4,2.4) W25(6.5,2.4) W26(7.3,2.4) W27(8.1,2.4) W28(8.9,2.4) W29(9.7,2.4) Y5(-9.7,1.2) Y6(-8.9,1.2) Y7(-8.1,1.2) Y8(-7.3,1.2) Y9(-6.5,1.2) Y10(-5.4,1.2) Y12(-4.2,1.2) Y13(-3,1.2) Y15(-1.8,1.2) Y16(-0.6,1.2) Y18(0.6,1.2) Y19(1.8,1.2) Y21(3,1.2) Y22(4.2,1.2) Y24(5.4,1.2) Y25(6.5,1.2) Y26(7.3,1.2) Y27(8.1,1.2) Y28(8.9,1.2) Y29(9.7,1.2)
  round 0.3 smd: A4(-10.4,16.5) A5(-9.6,16.9) A6(-8.8,16.5) A7(-8,16.9) A8(-7.2,16.5) A9(-6.4,16.9) A10(-5.6,16.5) A11(-4.8,16.9) A12(-4,16.5) A13(-3.2,16.9) A14(-2.4,16.5) A15(-1.6,16.9) A16(-0.8,16.5) A17(0,16.9) A18(0.8,16.5) A19(1.6,16.9) A20(2.4,16.5) A21(3.2,16.9) A22(4,16.5) A23(4.8,16.9) A24(5.6,16.5) A25(6.4,16.9) A26(7.2,16.5) A27(8,16.9) A28(8.8,16.5) A29(9.6,16.9) A30(10.4,16.5) AA1(-12.9,0.8) AA2(-12.1,0.8) AA3(-11.3,0.8) AA4(-10.5,0.8) AA30(10.5,0.8) AA31(11.3,0.8) AA32(12.1,0.8) AA33(12.9,0.8) AB1(-12.5,0) AB2(-11.7,0) AB4(-10.5,0) AB30(10.5,0) AB32(11.7,0) AB33(12.5,0) AC1(-12.9,-0.8) AC2(-12.1,-0.8) AC3(-11.3,-0.8) AC4(-10.5,-0.8) AC30(10.5,-0.8) AC31(11.3,-0.8) AC32(12.1,-0.8) AC33(12.9,-0.8) AD1(-12.5,-1.6) AD2(-11.7,-1.6) AD4(-10.5,-1.6) AD30(10.5,-1.6) AD32(11.7,-1.6) AD33(12.5,-1.6) AE1(-12.9,-2.4) AE2(-12.1,-2.4) AE3(-11.3,-2.4) AE4(-10.5,-2.4) AE30(10.5,-2.4) AE31(11.3,-2.4) AE32(12.1,-2.4) AE33(12.9,-2.4) AF1(-12.5,-3.2) AF2(-11.7,-3.2) AF4(-10.5,-3.2) AF30(10.5,-3.2) AF32(11.7,-3.2) AF33(12.5,-3.2) AG1(-12.9,-4) AG2(-12.1,-4) AG3(-11.3,-4) AG4(-10.5,-4) AG30(10.5,-4) AG31(11.3,-4) AG32(12.1,-4) AG33(12.9,-4) AH1(-12.5,-4.8) AH2(-11.7,-4.8) AH4(-10.5,-4.8) AH30(10.5,-4.8) AH32(11.7,-4.8) AH33(12.5,-4.8) AJ1(-12.9,-5.6) AJ2(-12.1,-5.6) AJ3(-11.3,-5.6) AJ4(-10.5,-5.6) AJ30(10.5,-5.6) AJ31(11.3,-5.6) AJ32(12.1,-5.6) AJ33(12.9,-5.6) AK1(-12.5,-6.4) AK2(-11.7,-6.4) AK4(-10.5,-6.4) AK30(10.5,-6.4) AK32(11.7,-6.4) AK33(12.5,-6.4) AL1(-12.9,-7.2) AL2(-12.1,-7.2) AL3(-11.3,-7.2) AL4(-10.5,-7.2) AL30(10.5,-7.2) AL31(11.3,-7.2) AL32(12.1,-7.2) AL33(12.9,-7.2) AM1(-12.5,-8) AM2(-11.7,-8) AM4(-10.5,-8) AM30(10.5,-8) AM32(11.7,-8) AM33(12.5,-8) AN1(-12.9,-8.8) AN2(-12.1,-8.8) AN3(-11.3,-8.8) AN4(-10.5,-8.8) AN30(10.5,-8.8) AN31(11.3,-8.8) AN32(12.1,-8.8) AN33(12.9,-8.8) AP1(-12.5,-9.6) AP2(-11.7,-9.6) AP4(-10.5,-9.6) AP30(10.5,-9.6) AP32(11.7,-9.6) AP33(12.5,-9.6) AR1(-12.9,-10.4) AR2(-12.1,-10.4) AR3(-11.3,-10.4) AR4(-10.5,-10.4) AR30(10.5,-10.4) AR31(11.3,-10.4) AR32(12.1,-10.4) AR33(12.9,-10.4) AT1(-12.5,-11.2) AT2(-11.7,-11.2) AT4(-10.5,-11.2) AT30(10.5,-11.2) AT32(11.7,-11.2) AT33(12.5,-11.2) AU1(-12.9,-12) AU2(-12.1,-12) AU3(-11.3,-12) AU4(-10.5,-12) AU30(10.5,-12) AU31(11.3,-12) AU32(12.1,-12) AU33(12.9,-12) AV1(-12.5,-12.8) AV2(-11.7,-12.8) AV4(-10.5,-12.8) AV30(10.5,-12.8) AV32(11.7,-12.8) AV33(12.5,-12.8) AW1(-12.9,-13.6) AW2(-12.1,-13.6) AW3(-11.3,-13.6) AW4(-10.5,-13.6) AW30(10.5,-13.6) AW31(11.3,-13.6) AW32(12.1,-13.6) AW33(12.9,-13.6) AY1(-12.5,-14.4) AY2(-11.7,-14.4) AY4(-10.4,-14.5) AY5(-9.6,-14.5) AY6(-8.8,-14.5) AY7(-8,-14.5) AY8(-7.2,-14.5) AY9(-6.4,-14.5) AY10(-5.6,-14.5) AY11(-4.8,-14.5) AY12(-4,-14.5) AY13(-3.2,-14.5) AY14(-2.4,-14.5) AY15(-1.6,-14.5) AY16(-0.8,-14.5) AY17(0,-14.5) AY18(0.8,-14.5) AY19(1.6,-14.5) AY20(2.4,-14.5) AY21(3.2,-14.5) AY22(4,-14.5) AY23(4.8,-14.5) AY24(5.6,-14.5) AY25(6.4,-14.5) AY26(7.2,-14.5) AY27(8,-14.5) AY28(8.8,-14.5) AY29(9.6,-14.5) AY30(10.4,-14.5) AY32(11.7,-14.4) AY33(12.5,-14.4) B4(-10.4,15.7) B5(-9.6,16.1) B6(-8.8,15.7) B7(-8,16.1) B8(-7.2,15.7) B9(-6.4,16.1) B10(-5.6,15.7) B11(-4.8,16.1) B12(-4,15.7) B13(-3.2,16.1) B14(-2.4,15.7) B15(-1.6,16.1) B16(-0.8,15.7) B17(0,16.1) B18(0.8,15.7) B19(1.6,16.1) B20(2.4,15.7) B21(3.2,16.1) B22(4,15.7) B23(4.8,16.1) B24(5.6,15.7) B25(6.4,16.1) B26(7.2,15.7) B27(8,16.1) B28(8.8,15.7) B29(9.6,16.1) B30(10.4,15.7) BA3(-11.2,-15.3) BA5(-9.6,-15.3) BA7(-8,-15.3) BA9(-6.4,-15.3) BA11(-4.8,-15.3) BA13(-3.2,-15.3) BA15(-1.6,-15.3) BA17(0,-15.3) BA19(1.6,-15.3) BA21(3.2,-15.3) BA23(4.8,-15.3) BA25(6.4,-15.3) BA27(8,-15.3) BA29(9.6,-15.3) BA31(11.2,-15.3) BB4(-10.4,-15.7) BB5(-9.6,-16.1) BB6(-8.8,-15.7) BB7(-8,-16.1) BB8(-7.2,-15.7) BB9(-6.4,-16.1) BB10(-5.6,-15.7) BB11(-4.8,-16.1) BB12(-4,-15.7) BB13(-3.2,-16.1) BB14(-2.4,-15.7) BB15(-1.6,-16.1) BB16(-0.8,-15.7) BB17(0,-16.1) BB18(0.8,-15.7) BB19(1.6,-16.1) BB20(2.4,-15.7) BB21(3.2,-16.1) BB22(4,-15.7) BB23(4.8,-16.1) BB24(5.6,-15.7) BB25(6.4,-16.1) BB26(7.2,-15.7) BB27(8,-16.1) BB28(8.8,-15.7) BB29(9.6,-16.1) BB30(10.4,-15.7) BC4(-10.4,-16.5) BC5(-9.6,-16.9) BC6(-8.8,-16.5) BC7(-8,-16.9) BC8(-7.2,-16.5) BC9(-6.4,-16.9) BC10(-5.6,-16.5) BC11(-4.8,-16.9) BC12(-4,-16.5) BC13(-3.2,-16.9) BC14(-2.4,-16.5) BC15(-1.6,-16.9) BC16(-0.8,-16.5) BC17(0,-16.9) BC18(0.8,-16.5) BC19(1.6,-16.9) BC20(2.4,-16.5) BC21(3.2,-16.9) BC22(4,-16.5) BC23(4.8,-16.9) BC24(5.6,-16.5) BC25(6.4,-16.9) BC26(7.2,-16.5) BC27(8,-16.9) BC28(8.8,-16.5) BC29(9.6,-16.9) BC30(10.4,-16.5) C3(-11.2,15.3) C5(-9.6,15.3) C7(-8,15.3) C9(-6.4,15.3) C11(-4.8,15.3) C13(-3.2,15.3) C15(-1.6,15.3) C17(0,15.3) C19(1.6,15.3) C21(3.2,15.3) C23(4.8,15.3) C25(6.4,15.3) C27(8,15.3) C29(9.6,15.3) C31(11.2,15.3) D1(-12.5,14.4) D2(-11.7,14.4) D4(-10.4,14.5) D5(-9.6,14.5) D6(-8.8,14.5) D7(-8,14.5) D8(-7.2,14.5) D9(-6.4,14.5) D10(-5.6,14.5) D11(-4.8,14.5) D12(-4,14.5) D13(-3.2,14.5) D14(-2.4,14.5) D15(-1.6,14.5) D16(-0.8,14.5) D17(0,14.5) D18(0.8,14.5) D19(1.6,14.5) D20(2.4,14.5) D21(3.2,14.5) D22(4,14.5) D23(4.8,14.5) D24(5.6,14.5) D25(6.4,14.5) D26(7.2,14.5) D27(8,14.5) D28(8.8,14.5) D29(9.6,14.5) D30(10.4,14.5) D32(11.7,14.4) D33(12.5,14.4) E1(-12.9,13.6) E2(-12.1,13.6) E3(-11.3,13.6) E4(-10.5,13.6) E30(10.5,13.6) E31(11.3,13.6) E32(12.1,13.6) E33(12.9,13.6) F1(-12.5,12.8) F2(-11.7,12.8) F4(-10.5,12.8) F30(10.5,12.8) F32(11.7,12.8) F33(12.5,12.8) G1(-12.9,12) G2(-12.1,12) G3(-11.3,12) G4(-10.5,12) G30(10.5,12) G31(11.3,12) G32(12.1,12) G33(12.9,12) H1(-12.5,11.2) H2(-11.7,11.2) H4(-10.5,11.2) H30(10.5,11.2) H32(11.7,11.2) H33(12.5,11.2) J1(-12.9,10.4) J2(-12.1,10.4) J3(-11.3,10.4) J4(-10.5,10.4) J30(10.5,10.4) J31(11.3,10.4) J32(12.1,10.4) J33(12.9,10.4) K1(-12.5,9.6) K2(-11.7,9.6) K4(-10.5,9.6) K30(10.5,9.6) K32(11.7,9.6) K33(12.5,9.6) L1(-12.9,8.8) L2(-12.1,8.8) L3(-11.3,8.8) L4(-10.5,8.8) L30(10.5,8.8) L31(11.3,8.8) L32(12.1,8.8) L33(12.9,8.8) M1(-12.5,8) M2(-11.7,8) M4(-10.5,8) M30(10.5,8) M32(11.7,8) M33(12.5,8) N1(-12.9,7.2) N2(-12.1,7.2) N3(-11.3,7.2) N4(-10.5,7.2) N30(10.5,7.2) N31(11.3,7.2) N32(12.1,7.2) N33(12.9,7.2) P1(-12.5,6.4) P2(-11.7,6.4) P4(-10.5,6.4) P30(10.5,6.4) P32(11.7,6.4) P33(12.5,6.4) R1(-12.9,5.6) R2(-12.1,5.6) R3(-11.3,5.6) R4(-10.5,5.6) R30(10.5,5.6) R31(11.3,5.6) R32(12.1,5.6) R33(12.9,5.6) T1(-12.5,4.8) T2(-11.7,4.8) T4(-10.5,4.8) T30(10.5,4.8) T32(11.7,4.8) T33(12.5,4.8) U1(-12.9,4) U2(-12.1,4) U3(-11.3,4) U4(-10.5,4) U30(10.5,4) U31(11.3,4) U32(12.1,4) U33(12.9,4) V1(-12.5,3.2) V2(-11.7,3.2) V4(-10.5,3.2) V30(10.5,3.2) V32(11.7,3.2) V33(12.5,3.2) W1(-12.9,2.4) W2(-12.1,2.4) W3(-11.3,2.4) W4(-10.5,2.4) W30(10.5,2.4) W31(11.3,2.4) W32(12.1,2.4) W33(12.9,2.4) Y1(-12.5,1.6) Y2(-11.7,1.6) Y4(-10.5,1.6) Y30(10.5,1.6) Y32(11.7,1.6) Y33(12.5,1.6)
C402H20
  custom 0.152x0.152 smd: 1(0,0.445) 2(0,-0.445)
C402H22
  custom 0.152x0.152 smd: 1(0,0.445) 2(0,-0.445)
C603H35
  custom 0.216x0.216 smd: 1(0,0.762) 2(0,-0.762)
C603H36
  custom 0.216x0.216 smd: 1(0,0.762) 2(0,-0.762)
C603H38
  custom 0.216x0.216 smd: 1(0,0.762) 2(0,-0.762)
C603H40
  custom 0.216x0.216 smd: 1(0,0.762) 2(0,-0.762)
C805H50
  rect 1.397x1.143 smd: 1(0,0.965) 2(0,-0.965)
C805H54
  rect 1.397x1.143 smd: 1(0,0.965) 2(0,-0.965)
C805H58
  rect 1.397x1.143 smd: 1(0,0.965) 2(0,-0.965)
C1206H71
  rect 1.651x1.27 smd: 1(0,1.397) 2(0,-1.397)
C1206H75
  rect 1.651x1.27 smd: 1(0,1.397) 2(0,-1.397)
C1808H87
  rect 2.286x1.27 smd: 1(0,2.032) 2(0,-2.032)
CI1410M1HRL-NH
  rect 0.61x1.549 smd: 1(-4.5,3.325) 2(-3.5,3.325) 3(-2.5,3.325) 4(-1.5,3.325) 5(-0.5,3.325) 6(0.5,3.325) 7(1.5,3.325) 8(2.5,3.325) 9(3.5,3.325) 10(4.5,3.325)
  rect 0.61x1.194 smd: 11(-5.6,0) 12(5.6,0)
CI2505P1H00-LF-U
  round 1.422 hole 1.016: 1(-5,0) 2(-2.5,0) 3(0,0) 4(2.5,0) 5(5,0)
CON2C-U
  custom 0.171x0.171 smd: 1(0,0.533) 2(0,-0.533)
CSP97G60-1H41
  round 0.271 smd: A1(-2.25,2.25) A2(-1.75,2.25) A3(-1.25,2.25) A4(-0.75,2.25) A5(-0.25,2.25) A6(0.25,2.25) A7(0.75,2.25) A8(1.25,2.25) A9(1.75,2.25) A10(2.25,2.25) B1(-2.25,1.75) B2(-1.75,1.75) B3(-1.25,1.75) B4(-0.75,1.75) B5(-0.25,1.75) B6(0.25,1.75) B7(0.75,1.75) B8(1.25,1.75) B9(1.75,1.75) B10(2.25,1.75) C1(-2.25,1.25) C2(-1.75,1.25) C3(-1.25,1.25) C4(-0.75,1.25) C5(-0.25,1.25) C6(0.25,1.25) C7(0.75,1.25) C8(1.25,1.25) C9(1.75,1.25) C10(2.25,1.25) D1(-2.25,0.75) D2(-1.75,0.75) D3(-1.25,0.75) D4(-0.75,0.75) D5(-0.25,0.75) D6(0.25,0.75) D7(0.75,0.75) D8(1.25,0.75) D9(1.75,0.75) D10(2.25,0.75) E1(-2.25,0.25) E2(-1.75,0.25) E3(-1.25,0.25) E4(-0.75,0.25) E5(-0.25,0.25) E7(0.75,0.25) E8(1.25,0.25) E9(1.75,0.25) E10(2.25,0.25) F1(-2.25,-0.25) F2(-1.75,-0.25) F3(-1.25,-0.25) F4(-0.75,-0.25) F7(0.75,-0.25) F8(1.25,-0.25) F9(1.75,-0.25) F10(2.25,-0.25) G1(-2.25,-0.75) G2(-1.75,-0.75) G3(-1.25,-0.75) G4(-0.75,-0.75) G5(-0.25,-0.75) G6(0.25,-0.75) G7(0.75,-0.75) G8(1.25,-0.75) G9(1.75,-0.75) G10(2.25,-0.75) H1(-2.25,-1.25) H2(-1.75,-1.25) H3(-1.25,-1.25) H4(-0.75,-1.25) H5(-0.25,-1.25) H6(0.25,-1.25) H7(0.75,-1.25) H8(1.25,-1.25) H9(1.75,-1.25) H10(2.25,-1.25) J1(-2.25,-1.75) J2(-1.75,-1.75) J3(-1.25,-1.75) J4(-0.75,-1.75) J5(-0.25,-1.75) J6(0.25,-1.75) J7(0.75,-1.75) J8(1.25,-1.75) J9(1.75,-1.75) J10(2.25,-1.75) K1(-2.25,-2.25) K2(-1.75,-2.25) K3(-1.25,-2.25) K4(-0.75,-2.25) K5(-0.25,-2.25) K6(0.25,-2.25) K7(0.75,-2.25) K8(1.25,-2.25) K9(1.75,-2.25) K10(2.25,-2.25)
CT7343H75
  rect 2.413x2.286 smd: 1(0,3.15) 2(0,-3.15)
D1608-035030AKH28
  rect 0.559x0.991 smd: A(0,0.691) K(0,-0.691)
D4724AKH44
  rect 2.007x1.549 smd: A(0,2.221) K(0,-2.221)
DFN6F2030-G1619H26
  rect 0.406x0.838 smd: 1(0.65,1.589) 2(0,1.589) 3(-0.65,1.589) 4(-0.65,-1.589) 5(0,-1.589) 6(0.65,-1.589)
  rect 1.6x1.93 smd: 7(0,0)
DFN10G3-G265175H32
  rect 0.305x0.914 smd: 1(1,1.549) 2(0.5,1.549) 3(0,1.549) 4(-0.5,1.549) 5(-1,1.549) 6(-1,-1.549) 7(-0.5,-1.549) 8(0,-1.549) 9(0.5,-1.549) 10(1,-1.549)
  rect 2.642x1.753 smd: 11(0,0)
DFN10G2510H26
  rect 0.305x0.787 smd: 1(1,0.494) 5(-1,0.494) 6(-1,-0.494) 10(1,-0.494)
  rect 0.254x0.787 smd: 2(0.521,0.494) 4(-0.521,0.494) 7(-0.521,-0.494) 9(0.521,-0.494)
  rect 0.025x0.025 smd: 3(0,0.494)
  rect 0.406x1.753 smd: 8(0,-0.494)
DO214AAAK-1121H97
  rect 2.311x2.032 smd: A(0,2.322) K(0,-2.322)
ECAP-100D6D3H237
  rect 1.397x1.397 hole 0.991: 1(0,-1.27)
  round 1.397 hole 0.991: 2(0,1.27)
ECAP-100D6D3H355
  rect 1.397x1.397 hole 0.991: 1(0,-1.27)
  round 1.397 hole 0.991: 2(0,1.27)
ECAP-100D6D3H375
  rect 1.397x1.397 hole 0.991: 1(0,-1.27)
  round 1.397 hole 0.991: 2(0,1.27)
FUSE-1608H22
  custom 0.216x0.216 smd: 1(0,0.762) 2(0,-0.762)
GAP-CLOSE-PWR
  rect 0.66x0.762 smd: 1(-0.305,0) 2(0.305,0)
GAP-CLOSE-PWR-3
  rect 0.66x0.762 smd: 1(-0.305,0) 2(0.305,0)
GEN8D5X8R5X4D5-8-F-A
  round 0.254 hole 5.004x4.521 unplated: (0,0)
  round 0.864 hole 0.508: 1(3.136,1.664) 2(1.918,2.882) 3(-1.918,2.882) 4(-3.136,1.664) 5(-3.136,-1.664) 6(-1.918,-2.882) 7(1.918,-2.882) 8(3.136,-1.664)
GEN315R138-8-F-A-1
  round 0.254 hole 3.505 unplated: (0,0)
  round 0.864 hole 0.508: 1(2.667,1.54) 2(1.54,2.667) 3(-1.54,2.667) 4(-2.667,1.54) 5(-2.667,-1.54) 6(-1.54,-2.667) 7(1.54,-2.667) 8(2.667,-1.54)
GEN315R138-8-F-A-2-S
  round 0.254 hole 3.505 unplated: (0,0)
  round 0.864 hole 0.508: 1(2.667,1.54) 2(1.54,2.667) 3(-1.54,2.667) 4(-2.667,1.54) 5(-2.667,-1.54) 6(-1.54,-2.667) 7(1.54,-2.667) 8(2.667,-1.54)
GEN315R178-8-F-A-1
  round 0.254 hole 4.521 unplated: (0,0)
  round 0.864 hole 0.508: 1(2.882,1.664) 2(1.664,2.882) 3(-1.664,2.882) 4(-2.882,1.664) 5(-2.882,-1.664) 6(-1.664,-2.882) 7(1.664,-2.882) 8(2.882,-1.664)
HF1804H
  round 1.651 hole 1.016: 1(-3.81,0) 2(-1.27,0) 3(1.27,0) 4(3.81,0)
HL5507F
  round 0.254 hole 1.016 unplated: (5,0)
  round 1.321 hole 0.914: 1(-6,-1) 2(-6,1) 3(-4,-1) 4(-4,1) 5(-2,-1) 6(-2,1) 7(0,-1) 8(0,1) 9(2,-1) 10(2,1) 11(4,-1) 12(4,1) 13(6,-1) 14(6,1)
HOLE237R158
  round 6.02 hole 4.013: 1(0,0)
JAC331-0140A8B-9H
  oval 1.321x2.235 hole 0.61x1.524: 1(-4.95,2.1) 4(5,2.1) P(3.25,-3.15) Q(-3.9,-2.1)
  oval 2.235x1.422 hole 1.524x0.711: 5(0,3.17)
L402H22
  custom 0.14x0.14 smd: 1(0,0.445) 2(0,-0.445)
L402H24
  custom 0.14x0.14 smd: 1(0,0.445) 2(0,-0.445)
L603H38
  custom 0.216x0.216 smd: 1(0,0.762) 2(0,-0.762)
L1608-UH38
  custom 0.216x0.216 smd: 1(0,0.762) 2(0,-0.762)
L3030-2709H41
  rect 2.946x1.778 smd: 1(0,1.235) 2(0,-1.235)
L7066-1830-UH119
  rect 3.505x2.921 smd: 1(0,2.78) 2(0,-2.78)
L8080-6522-1H166
  rect 7.036x3.327 smd: 1(0,3.108) 2(0,-3.108)
L20125H42
  rect 1.397x1.143 smd: 1(0,0.965) 2(0,-0.965)
L115100-2H158
  rect 3.759x3.251 smd: 1(0,5.022) 2(0,-5.022)
L125100-4P-1H28
  rect 0.762x0.432 smd: 1(0.625,0.341) 2(-0.625,0.341) 3(-0.625,-0.341) 4(0.625,-0.341)
L125100-4P-1H36
  rect 0.762x0.432 smd: 1(0.625,0.341) 2(-0.625,0.341) 3(-0.625,-0.341) 4(0.625,-0.341)
L125100-4P-1H37
  rect 0.762x0.432 smd: 1(0.625,0.341) 2(-0.625,0.341) 3(-0.625,-0.341) 4(0.625,-0.341)
L125100-4P-4H28
  rect 0.762x0.432 smd: 1(-0.625,0.341) 2(0.625,0.341) 3(0.625,-0.341) 4(-0.625,-0.341)
L686647-127318H119
  rect 3.683x2.413 smd: 1(0,2.986) 2(0,-2.986)
L686647H119
  rect 2.159x3.429 smd: 1(-3.111,0) 2(3.111,0)
LED1608AKH30
  custom 0.216x0.216 smd: A(0,0.762) K(0,-0.762)
LFCSP52J6-G4D8H40
  rect 0.203x0.356 smd: 1(2.4,2.812) 13(-2.4,2.812) 27(-2.4,-2.812) 39(2.4,-2.812)
  rect 0.203x0.381 smd: 2(2,2.812) 3(1.6,2.812) 4(1.2,2.812) 5(0.8,2.812) 6(0.4,2.812) 7(0,2.812) 8(-0.4,2.812) 9(-0.8,2.812) 10(-1.2,2.812) 11(-1.6,2.812) 12(-2,2.812) 28(-2,-2.812) 29(-1.6,-2.812) 30(-1.2,-2.812) 31(-0.8,-2.812) 32(-0.4,-2.812) 33(0,-2.812) 34(0.4,-2.812) 35(0.8,-2.812) 36(1.2,-2.812) 37(1.6,-2.812) 38(2,-2.812)
  rect 0.356x0.203 smd: 14(-2.812,2.4) 26(-2.812,-2.4) 40(2.812,-2.4) 52(2.812,2.4)
  rect 0.381x0.203 smd: 15(-2.812,2) 16(-2.812,1.6) 17(-2.812,1.2) 18(-2.812,0.8) 19(-2.812,0.4) 20(-2.812,0) 21(-2.812,-0.4) 22(-2.812,-0.8) 23(-2.812,-1.2) 24(-2.812,-1.6) 25(-2.812,-2) 41(2.812,-2) 42(2.812,-1.6) 43(2.812,-1.2) 44(2.812,-0.8) 45(2.812,-0.4) 46(2.812,0) 47(2.812,0.4) 48(2.812,0.8) 49(2.812,1.2) 50(2.812,1.6) 51(2.812,2)
  rect 4.801x4.801 smd: 53(0,0)
LGA16G3-1H40
  rect 0.305x0.559 smd: 1(1,1.221) 2(0.5,1.221) 3(0,1.221) 4(-0.5,1.221) 5(-1,1.221) 9(-1,-1.221) 10(-0.5,-1.221) 11(0,-1.221) 12(0.5,-1.221) 13(1,-1.221)
  rect 0.559x0.305 smd: 6(-1.221,0.5) 7(-1.221,0) 8(-1.221,-0.5) 14(1.221,-0.5) 15(1.221,0) 16(1.221,0.5)
LQFP64H63
  rect 0.203x1.524 smd: 1(3,4.242) 2(2.6,4.242) 3(2.2,4.242) 4(1.8,4.242) 5(1.4,4.242) 6(0.999,4.242) 7(0.599,4.242) 8(0.199,4.242) 9(-0.199,4.242) 10(-0.599,4.242) 11(-0.999,4.242) 12(-1.4,4.242) 13(-1.8,4.242) 14(-2.2,4.242) 15(-2.6,4.242) 16(-3,4.242) 33(-3,-4.242) 34(-2.6,-4.242) 35(-2.2,-4.242) 36(-1.8,-4.242) 37(-1.4,-4.242) 38(-0.999,-4.242) 39(-0.599,-4.242) 40(-0.199,-4.242) 41(0.199,-4.242) 42(0.599,-4.242) 43(0.999,-4.242) 44(1.4,-4.242) 45(1.8,-4.242) 46(2.2,-4.242) 47(2.6,-4.242) 48(3,-4.242)
  rect 1.524x0.203 smd: 17(-4.242,3) 18(-4.242,2.6) 19(-4.242,2.2) 20(-4.242,1.8) 21(-4.242,1.4) 22(-4.242,0.999) 23(-4.242,0.599) 24(-4.242,0.199) 25(-4.242,-0.199) 26(-4.242,-0.599) 27(-4.242,-0.999) 28(-4.242,-1.4) 29(-4.242,-1.8) 30(-4.242,-2.2) 31(-4.242,-2.6) 32(-4.242,-3) 49(4.242,-3) 50(4.242,-2.6) 51(4.242,-2.2) 52(4.242,-1.8) 53(4.242,-1.4) 54(4.242,-0.999) 55(4.242,-0.599) 56(4.242,-0.199) 57(4.242,0.199) 58(4.242,0.599) 59(4.242,0.999) 60(4.242,1.4) 61(4.242,1.8) 62(4.242,2.2) 63(4.242,2.6) 64(4.242,3)
LQFP128H63
  rect 0.203x1.524 smd: 1(6.2,7.747) 2(5.8,7.747) 3(5.4,7.747) 4(5,7.747) 5(4.6,7.747) 6(4.2,7.747) 7(3.8,7.747) 8(3.4,7.747) 9(3,7.747) 10(2.6,7.747) 11(2.2,7.747) 12(1.8,7.747) 13(1.4,7.747) 14(0.999,7.747) 15(0.599,7.747) 16(0.199,7.747) 17(-0.199,7.747) 18(-0.599,7.747) 19(-0.999,7.747) 20(-1.4,7.747) 21(-1.8,7.747) 22(-2.2,7.747) 23(-2.6,7.747) 24(-3,7.747) 25(-3.4,7.747) 26(-3.8,7.747) 27(-4.2,7.747) 28(-4.6,7.747) 29(-5,7.747) 30(-5.4,7.747) 31(-5.8,7.747) 32(-6.2,7.747) 65(-6.2,-7.747) 66(-5.8,-7.747) 67(-5.4,-7.747) 68(-5,-7.747) 69(-4.6,-7.747) 70(-4.2,-7.747) 71(-3.8,-7.747) 72(-3.4,-7.747) 73(-3,-7.747) 74(-2.6,-7.747) 75(-2.2,-7.747) 76(-1.8,-7.747) 77(-1.4,-7.747) 78(-0.999,-7.747) 79(-0.599,-7.747) 80(-0.199,-7.747) 81(0.199,-7.747) 82(0.599,-7.747) 83(0.999,-7.747) 84(1.4,-7.747) 85(1.8,-7.747) 86(2.2,-7.747) 87(2.6,-7.747) 88(3,-7.747) 89(3.4,-7.747) 90(3.8,-7.747) 91(4.2,-7.747) 92(4.6,-7.747) 93(5,-7.747) 94(5.4,-7.747) 95(5.8,-7.747) 96(6.2,-7.747)
  rect 1.524x0.203 smd: 33(-7.747,6.2) 34(-7.747,5.8) 35(-7.747,5.4) 36(-7.747,5) 37(-7.747,4.6) 38(-7.747,4.2) 39(-7.747,3.8) 40(-7.747,3.4) 41(-7.747,3) 42(-7.747,2.6) 43(-7.747,2.2) 44(-7.747,1.8) 45(-7.747,1.4) 46(-7.747,0.999) 47(-7.747,0.599) 48(-7.747,0.199) 49(-7.747,-0.199) 50(-7.747,-0.599) 51(-7.747,-0.999) 52(-7.747,-1.4) 53(-7.747,-1.8) 54(-7.747,-2.2) 55(-7.747,-2.6) 56(-7.747,-3) 57(-7.747,-3.4) 58(-7.747,-3.8) 59(-7.747,-4.2) 60(-7.747,-4.6) 61(-7.747,-5) 62(-7.747,-5.4) 63(-7.747,-5.8) 64(-7.747,-6.2) 97(7.747,-6.2) 98(7.747,-5.8) 99(7.747,-5.4) 100(7.747,-5) 101(7.747,-4.6) 102(7.747,-4.2) 103(7.747,-3.8) 104(7.747,-3.4) 105(7.747,-3) 106(7.747,-2.6) 107(7.747,-2.2) 108(7.747,-1.8) 109(7.747,-1.4) 110(7.747,-0.999) 111(7.747,-0.599) 112(7.747,-0.199) 113(7.747,0.199) 114(7.747,0.599) 115(7.747,0.999) 116(7.747,1.4) 117(7.747,1.8) 118(7.747,2.2) 119(7.747,2.6) 120(7.747,3) 121(7.747,3.4) 122(7.747,3.8) 123(7.747,4.2) 124(7.747,4.6) 125(7.747,5) 126(7.747,5.4) 127(7.747,5.8) 128(7.747,6.2)
LVDFH-02004-TP00
  rect 0.305x1.295 smd: 1(-4.75,-1.95) 2(-4.25,-1.95) 3(-3.75,-1.95) 4(-3.25,-1.95) 5(-2.75,-1.95) 6(-2.25,-1.95) 7(-1.75,-1.95) 8(-1.25,-1.95) 9(-0.75,-1.95) 10(-0.25,-1.95) 11(0.25,-1.95) 12(0.75,-1.95) 13(1.25,-1.95) 14(1.75,-1.95) 15(2.25,-1.95) 16(2.75,-1.95) 17(3.25,-1.95) 18(3.75,-1.95) 19(4.25,-1.95) 20(4.75,-1.95)
  rect 1.194x2.692 smd: 21(-7.15,0) 22(7.15,0)
  rect 2.261x1.346 smd: 23(3.9,1.975) 24(0,1.975) 25(-3.9,1.975)
NTC-402H22-U
  custom 0.14x0.14 smd: 1(0,0.445) 2(0,-0.445)
NTC-402H24-U
  custom 0.14x0.14 smd: 1(0,0.445) 2(0,-0.445)
OSC-3225-4P-4H36
  rect 1.397x1.067 smd: 1(-1.171,-0.756) 2(1.171,-0.756) 3(1.171,0.756) 4(-1.171,0.756)
POLYSW-2114H30
  rect 1.6x0.965 smd: 1(0,0.94) 2(0,-0.94)
PPAK-8P-3232H36
  rect 0.406x0.914 smd: 1(-0.975,-2.396) 2(-0.325,-2.396) 3(0.325,-2.396) 4(0.975,-2.396)
  rect 3.353x2.692 smd: 5(0,0)
  rect 0.025x0.025 smd: 6(0.65,0.838) 7(0,0.838) 8(-0.65,0.838)
PPAK-8P-5262H40
  rect 0.762x1.448 smd: 1(-1.905,-3.684) 2(-0.635,-3.684) 3(0.635,-3.684) 4(1.905,-3.684)
  rect 5.512x5.309 smd: 5(0,0)
  rect 0.025x0.025 smd: 6(0.635,2.146) 7(-0.635,2.146) 8(-1.905,2.146)
QFN16J3H24
  rect 0.254x1.422 smd: 1(0.525,1.297) 2(-0.175,1.297) 8(-0.525,-1.297) 9(0.175,-1.297)
  rect 1.092x0.203 smd: 3(-1.462,0.8) 4(-1.462,0.4) 5(-1.462,0) 6(-1.462,-0.4) 7(-1.462,-0.8) 10(1.462,-0.8) 11(1.462,-0.4) 12(1.462,0) 13(1.462,0.4) 14(1.462,0.8)
  rect 0.203x0.66 smd: 15(0.165,0) 16(-0.435,0)
QFN20-G1D75H32
  rect 0.203x0.914 smd: 1(0.8,1.551) 2(0.4,1.551) 3(0,1.551) 4(-0.4,1.551) 5(-0.8,1.551) 11(-0.8,-1.551) 12(-0.4,-1.551) 13(0,-1.551) 14(0.4,-1.551) 15(0.8,-1.551)
  rect 0.914x0.203 smd: 6(-1.551,0.8) 7(-1.551,0.4) 8(-1.551,0) 9(-1.551,-0.4) 10(-1.551,-0.8) 16(1.551,-0.8) 17(1.551,-0.4) 18(1.551,0) 19(1.551,0.4) 20(1.551,0.8)
  rect 1.753x1.753 smd: 21(0,0)
QFN20-G2D1H32
  rect 0.305x1.092 smd: 1(0.999,1.956) 5(-0.999,1.956) 11(-0.999,-1.956) 15(0.999,-1.956)
  rect 0.305x1.143 smd: 2(0.5,1.93) 3(0,1.93) 4(-0.5,1.93) 12(-0.5,-1.93) 13(0,-1.93) 14(0.5,-1.93)
  rect 1.092x0.305 smd: 6(-1.956,0.999) 10(-1.956,-0.999) 16(1.956,-0.999) 20(1.956,0.999)
  rect 1.143x0.305 smd: 7(-1.93,0.5) 8(-1.93,0) 9(-1.93,-0.5) 17(1.93,-0.5) 18(1.93,0) 19(1.93,0.5)
  rect 2.108x2.108 smd: 21(0,0)
QFN20G3D5-G2D15H40
  rect 0.305x0.914 smd: 1(1,1.801) 5(-1,1.801) 11(-1,-1.801) 15(1,-1.801)
  rect 0.305x0.965 smd: 2(0.5,1.775) 3(0,1.775) 4(-0.5,1.775) 12(-0.5,-1.775) 13(0,-1.775) 14(0.5,-1.775)
  rect 0.914x0.305 smd: 6(-1.801,1) 10(-1.801,-1) 16(1.801,-1) 20(1.801,1)
  rect 0.965x0.305 smd: 7(-1.775,0.5) 8(-1.775,0) 9(-1.775,-0.5) 17(1.775,-0.5) 18(1.775,0) 19(1.775,0.5)
  rect 2.159x2.159 smd: 21(0,0)
QFN32-G3D55H40
  rect 0.305x0.838 smd: 1(1.75,2.591) 8(-1.75,2.591) 17(-1.75,-2.591) 24(1.75,-2.591)
  rect 0.305x0.94 smd: 2(1.25,2.54) 3(0.751,2.54) 4(0.25,2.54) 5(-0.25,2.54) 6(-0.751,2.54) 7(-1.25,2.54) 18(-1.25,-2.54) 19(-0.751,-2.54) 20(-0.25,-2.54) 21(0.25,-2.54) 22(0.751,-2.54) 23(1.25,-2.54)
  rect 0.838x0.305 smd: 9(-2.591,1.75) 16(-2.591,-1.75) 25(2.591,-1.75) 32(2.591,1.75)
  rect 0.94x0.305 smd: 10(-2.54,1.25) 11(-2.54,0.751) 12(-2.54,0.25) 13(-2.54,-0.25) 14(-2.54,-0.751) 15(-2.54,-1.25) 26(2.54,-1.25) 27(2.54,-0.751) 28(2.54,-0.25) 29(2.54,0.25) 30(2.54,0.751) 31(2.54,1.25)
  rect 3.531x3.531 smd: 33(0,0)
QFN32J4-G2D85H36
  rect 0.203x0.864 smd: 1(1.4,2.085) 2(1,2.085) 3(0.6,2.085) 4(0.2,2.085) 5(-0.2,2.085) 6(-0.6,2.085) 7(-1,2.085) 8(-1.4,2.085) 17(-1.4,-2.085) 18(-1,-2.085) 19(-0.6,-2.085) 20(-0.2,-2.085) 21(0.2,-2.085) 22(0.6,-2.085) 23(1,-2.085) 24(1.4,-2.085)
  rect 0.864x0.203 smd: 9(-2.085,1.4) 10(-2.085,1) 11(-2.085,0.6) 12(-2.085,0.2) 13(-2.085,-0.2) 14(-2.085,-0.6) 15(-2.085,-1) 16(-2.085,-1.4) 25(2.085,-1.4) 26(2.085,-1) 27(2.085,-0.6) 28(2.085,-0.2) 29(2.085,0.2) 30(2.085,0.6) 31(2.085,1) 32(2.085,1.4)
  rect 2.845x2.845 smd: 33(0,0)
QFN40J5-G3D65H32
  rect 0.203x0.94 smd: 1(1.8,2.538) 10(-1.8,2.538) 21(-1.8,-2.538) 30(1.8,-2.538)
  rect 0.203x0.965 smd: 2(1.4,2.526) 3(1,2.526) 4(0.6,2.526) 5(0.2,2.526) 6(-0.2,2.526) 7(-0.6,2.526) 8(-1,2.526) 9(-1.4,2.526) 22(-1.4,-2.526) 23(-1,-2.526) 24(-0.6,-2.526) 25(-0.2,-2.526) 26(0.2,-2.526) 27(0.6,-2.526) 28(1,-2.526) 29(1.4,-2.526)
  rect 0.94x0.203 smd: 11(-2.538,1.8) 20(-2.538,-1.8) 31(2.538,-1.8) 40(2.538,1.8)
  rect 0.965x0.203 smd: 12(-2.526,1.4) 13(-2.526,1) 14(-2.526,0.6) 15(-2.526,0.2) 16(-2.526,-0.2) 17(-2.526,-0.6) 18(-2.526,-1) 19(-2.526,-1.4) 32(2.526,-1.4) 33(2.526,-1) 34(2.526,-0.6) 35(2.526,-0.2) 36(2.526,0.2) 37(2.526,0.6) 38(2.526,1) 39(2.526,1.4)
  rect 3.658x3.658 smd: 41(0,0)
QFN48J6-G4D55H40
  rect 0.203x1.016 smd: 1(2.2,3) 2(1.8,3) 3(1.4,3) 4(1,3) 5(0.6,3) 6(0.2,3) 7(-0.2,3) 8(-0.6,3) 9(-1,3) 10(-1.4,3) 11(-1.8,3) 12(-2.2,3) 25(-2.2,-3) 26(-1.8,-3) 27(-1.4,-3) 28(-1,-3) 29(-0.6,-3) 30(-0.2,-3) 31(0.2,-3) 32(0.6,-3) 33(1,-3) 34(1.4,-3) 35(1.8,-3) 36(2.2,-3)
  rect 1.016x0.203 smd: 13(-3,2.2) 14(-3,1.8) 15(-3,1.4) 16(-3,1) 17(-3,0.6) 18(-3,0.2) 19(-3,-0.2) 20(-3,-0.6) 21(-3,-1) 22(-3,-1.4) 23(-3,-1.8) 24(-3,-2.2) 37(3,-2.2) 38(3,-1.8) 39(3,-1.4) 40(3,-1) 41(3,-0.6) 42(3,-0.2) 43(3,0.2) 44(3,0.6) 45(3,1) 46(3,1.4) 47(3,1.8) 48(3,2.2)
  rect 4.547x4.547 smd: 49(0,0)
QFN48J6-G465H40
  rect 0.203x0.965 smd: 1(2.2,3.025) 2(1.8,3.025) 3(1.4,3.025) 4(1,3.025) 5(0.6,3.025) 6(0.2,3.025) 7(-0.2,3.025) 8(-0.6,3.025) 9(-1,3.025) 10(-1.4,3.025) 11(-1.8,3.025) 12(-2.2,3.025) 25(-2.2,-3.025) 26(-1.8,-3.025) 27(-1.4,-3.025) 28(-1,-3.025) 29(-0.6,-3.025) 30(-0.2,-3.025) 31(0.2,-3.025) 32(0.6,-3.025) 33(1,-3.025) 34(1.4,-3.025) 35(1.8,-3.025) 36(2.2,-3.025)
  rect 0.965x0.203 smd: 13(-3.025,2.2) 14(-3.025,1.8) 15(-3.025,1.4) 16(-3.025,1) 17(-3.025,0.6) 18(-3.025,0.2) 19(-3.025,-0.2) 20(-3.025,-0.6) 21(-3.025,-1) 22(-3.025,-1.4) 23(-3.025,-1.8) 24(-3.025,-2.2) 37(3.025,-2.2) 38(3.025,-1.8) 39(3.025,-1.4) 40(3.025,-1) 41(3.025,-0.6) 42(3.025,-0.2) 43(3.025,0.2) 44(3.025,0.6) 45(3.025,1) 46(3.025,1.4) 47(3.025,1.8) 48(3.025,2.2)
  rect 4.648x4.648 smd: 49(0,0)
R402H14
  custom 0.14x0.14 smd: 1(0,0.445) 2(0,-0.445)
R402H16
  custom 0.14x0.14 smd: 1(0,0.445) 2(0,-0.445)
R603H22
  custom 0.216x0.216 smd: 1(0,0.762) 2(0,-0.762)
R805H24
  rect 1.397x1.143 smd: 1(0,0.965) 2(0,-0.965)
R1206H26
  rect 1.651x1.27 smd: 1(0,1.397) 2(0,-1.397)
R1206H28
  rect 1.651x1.27 smd: 1(0,1.397) 2(0,-1.397)
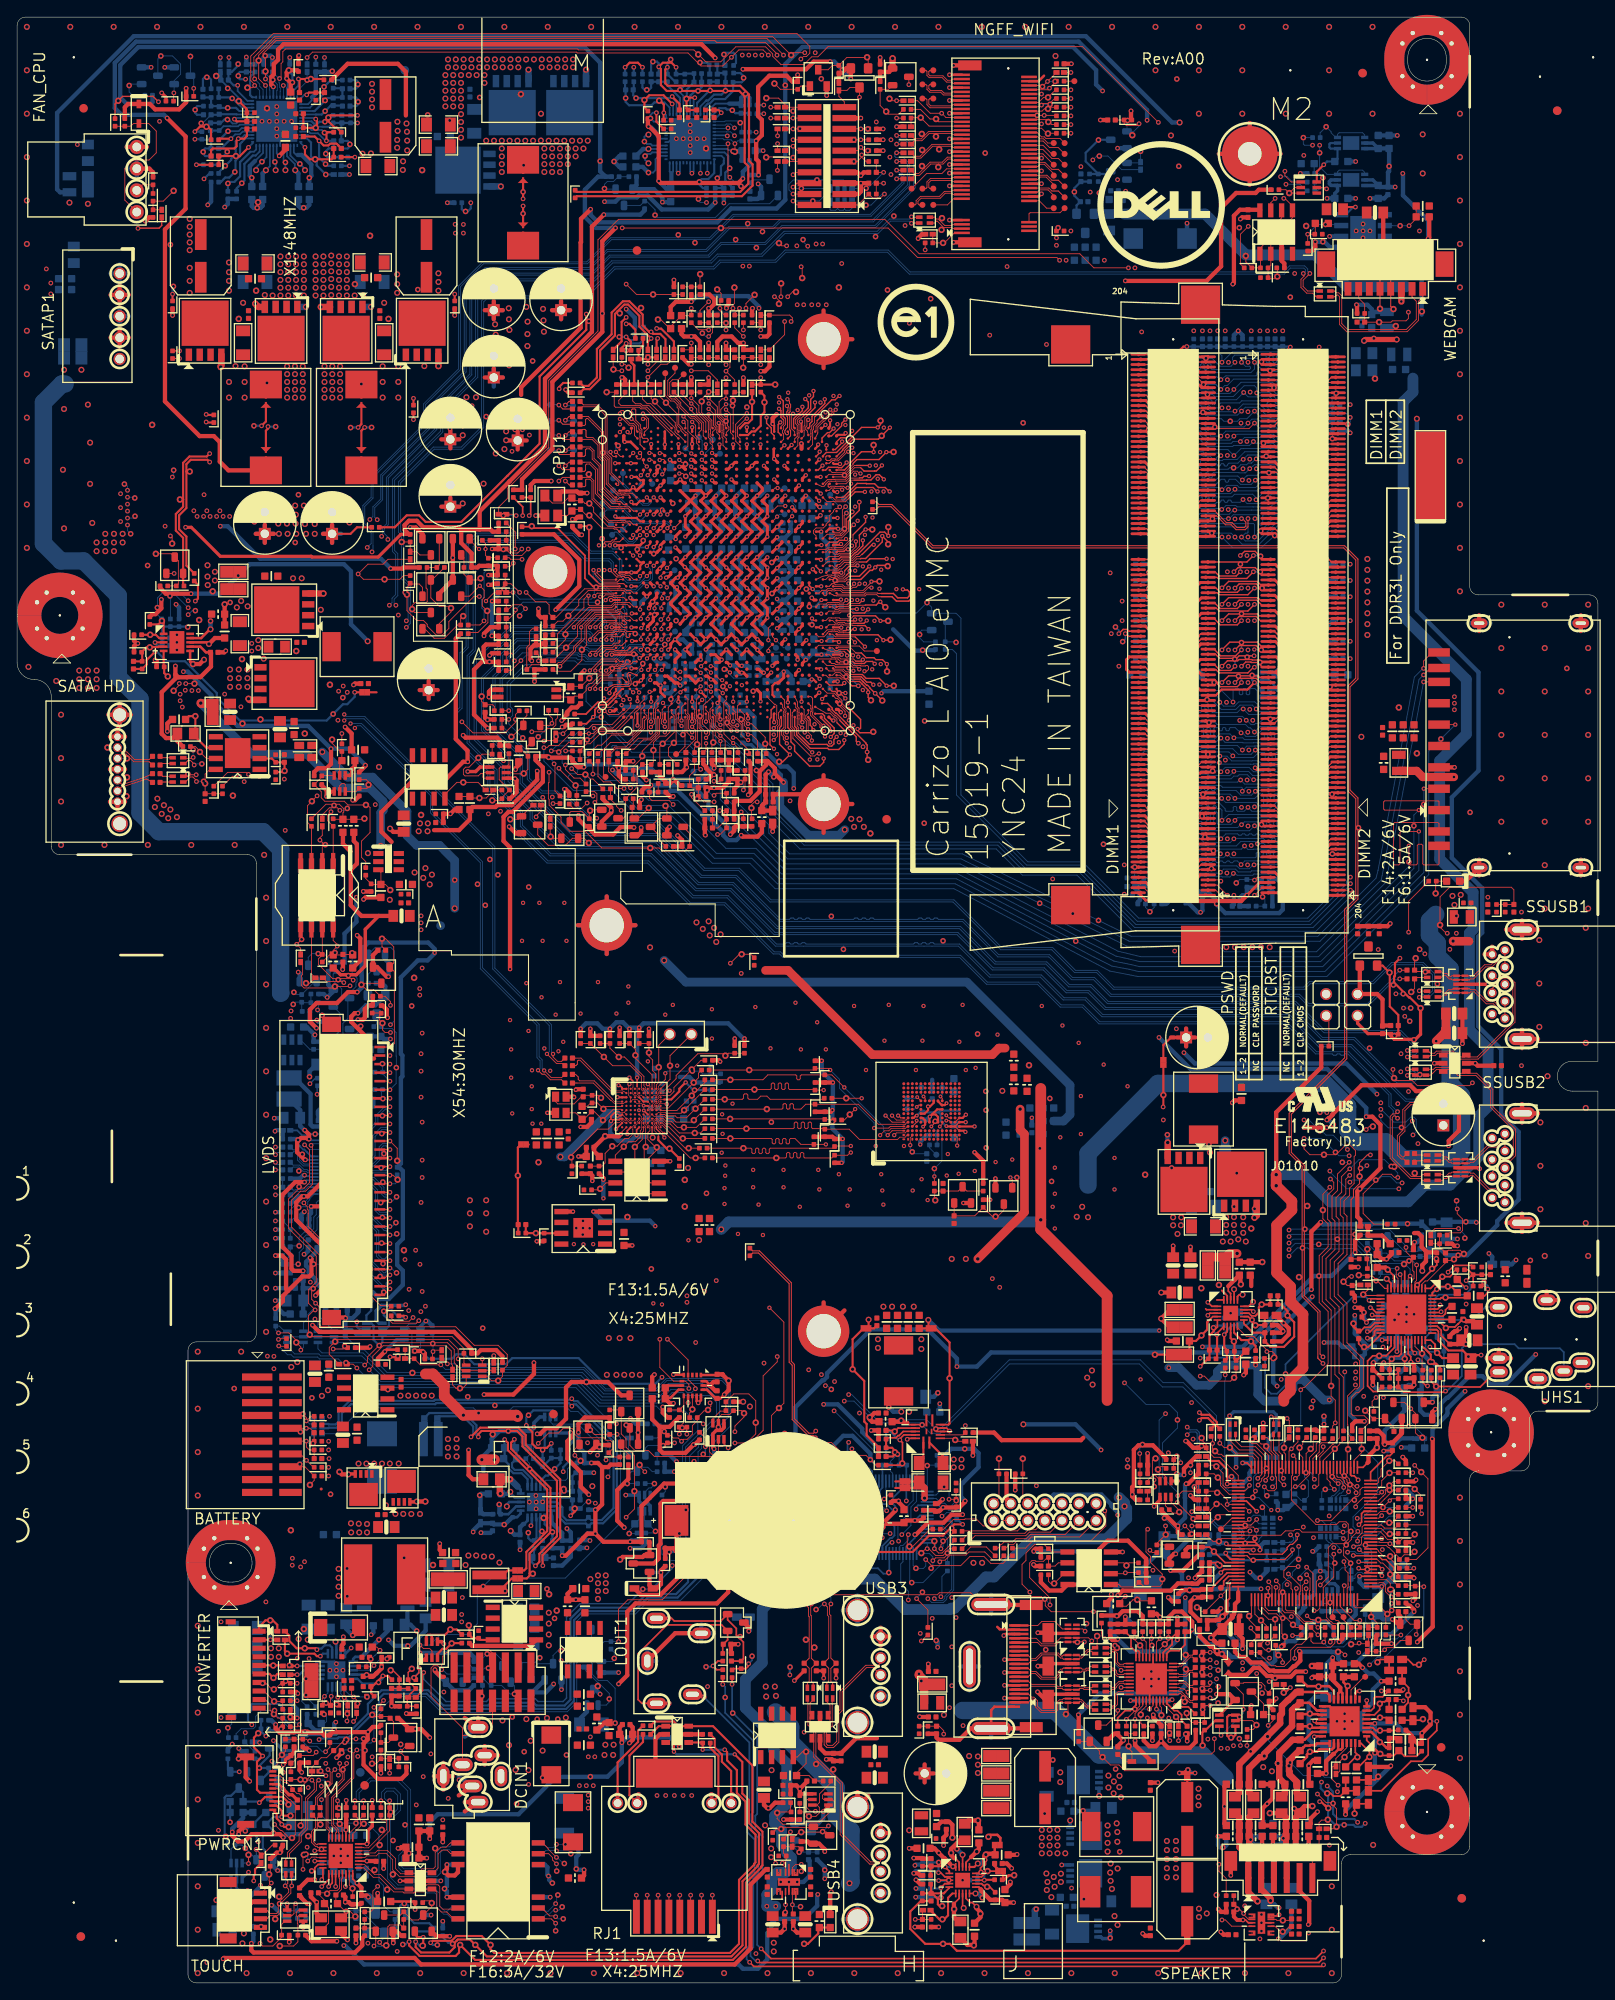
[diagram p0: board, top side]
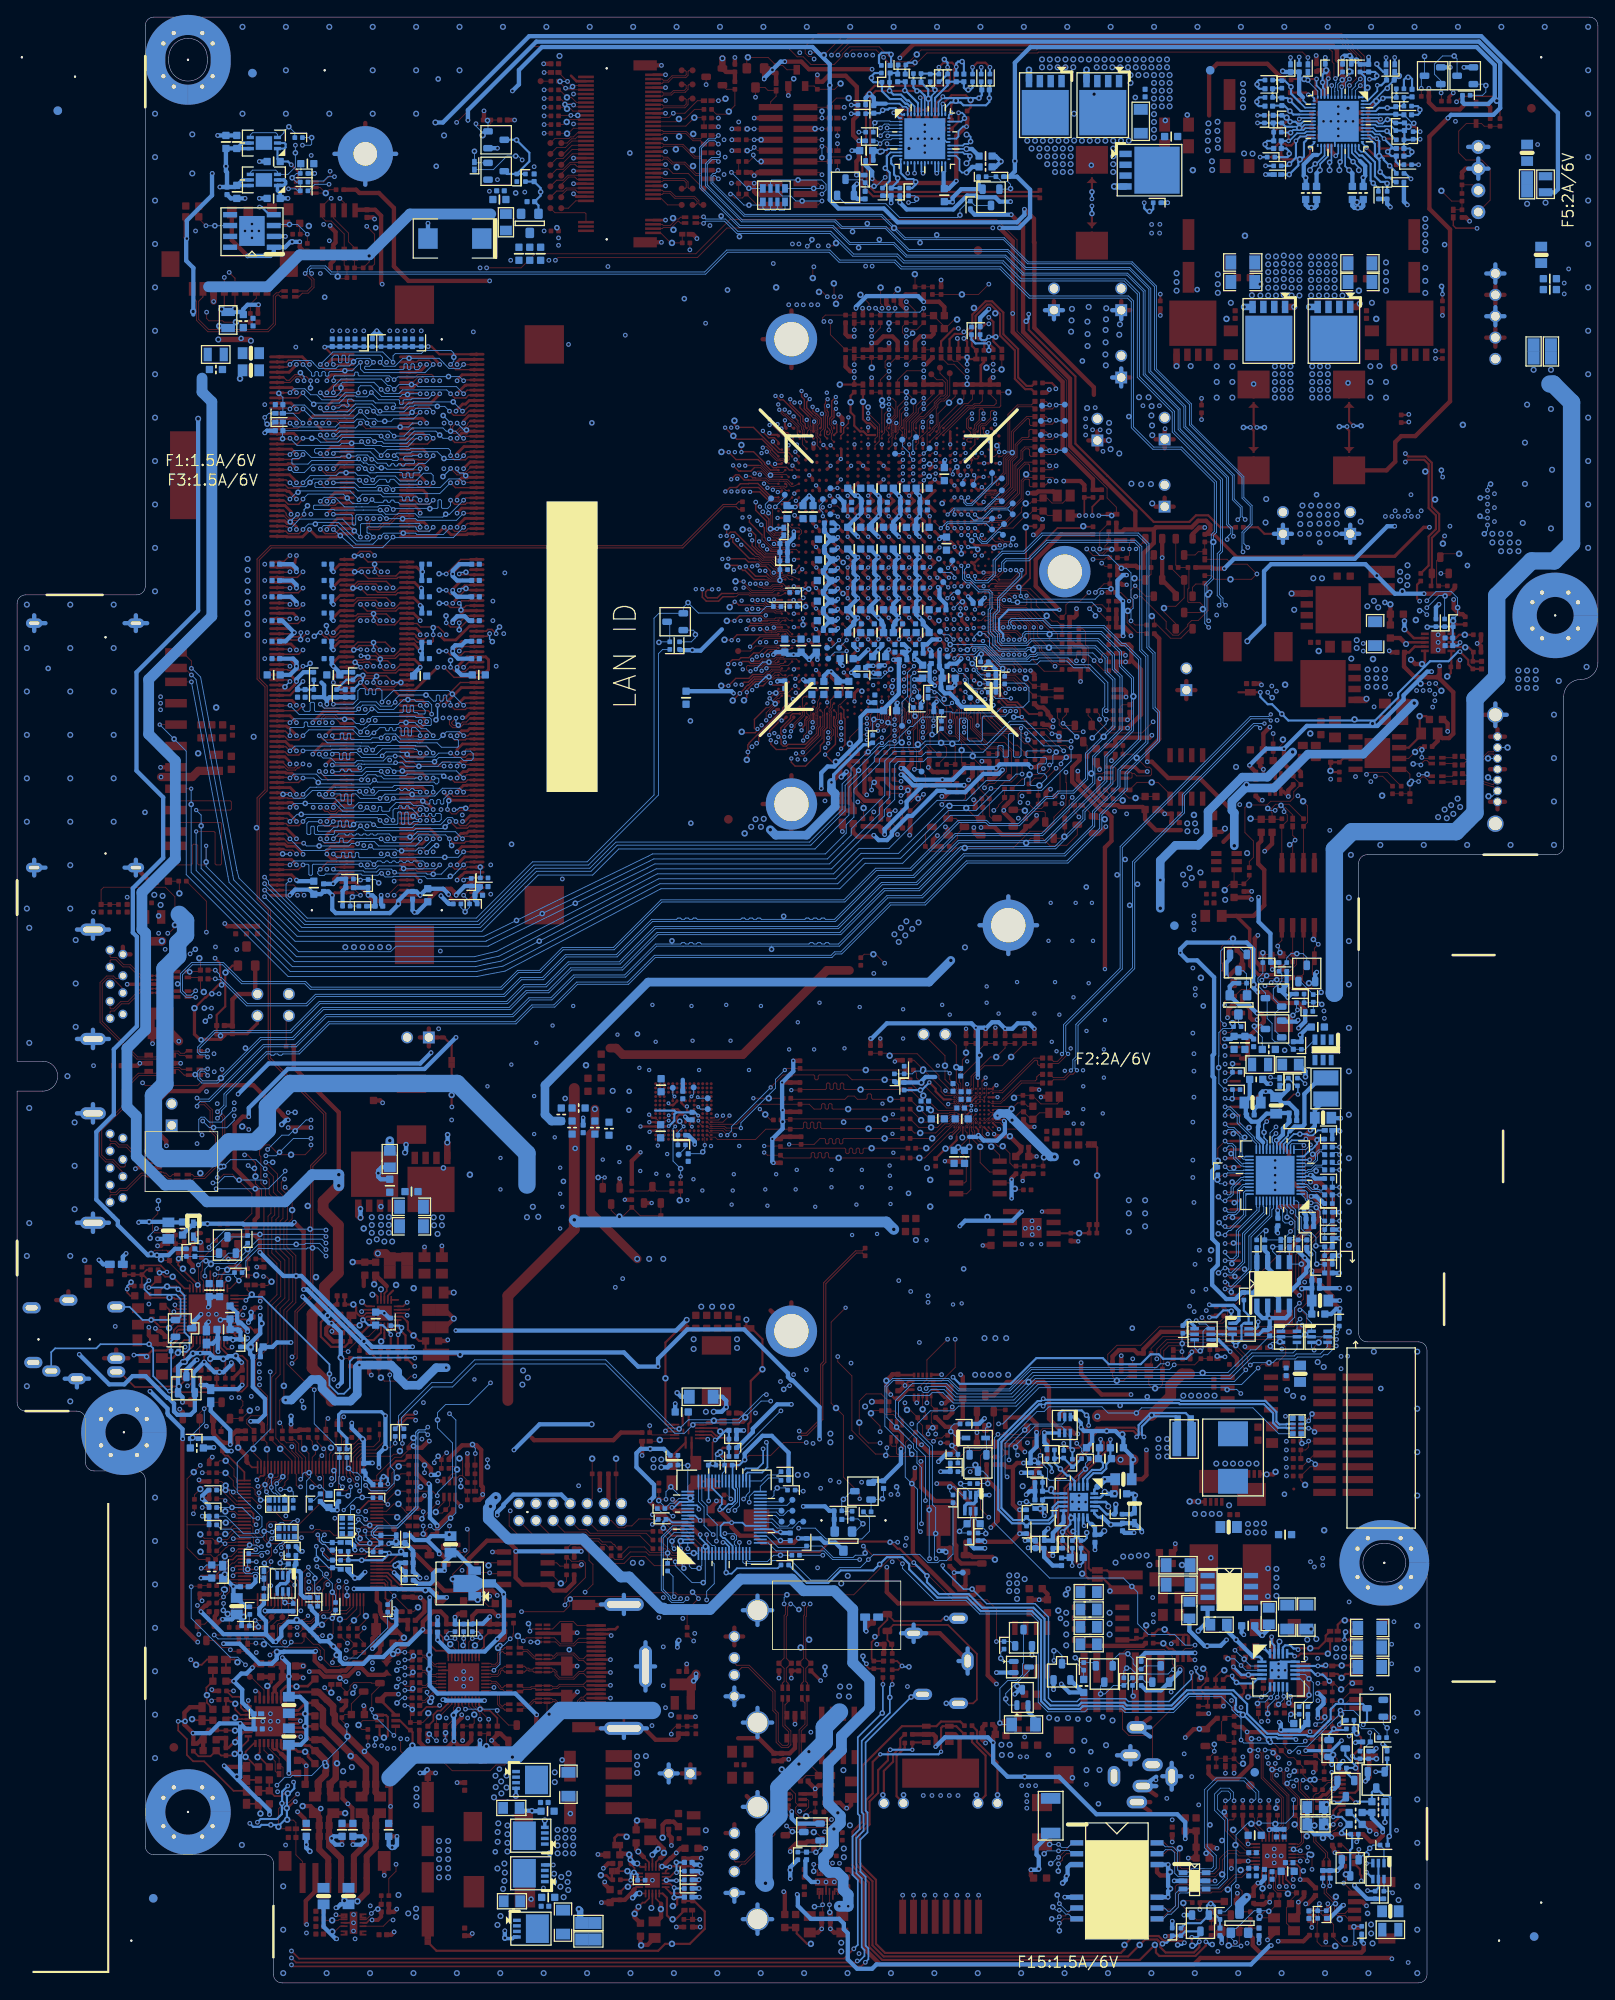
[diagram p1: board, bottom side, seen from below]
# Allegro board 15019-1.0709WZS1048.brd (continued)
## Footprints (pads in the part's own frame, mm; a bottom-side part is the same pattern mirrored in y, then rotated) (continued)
R3720H40
  rect 4.013x1.041 smd: 1(0,0.867) 2(0,-0.867)
SE331721H237
  rect 1.422x3.556 smd: 1(0,2.574) 2(0,-2.574)
SE361414H241
  rect 1.372x3.607 smd: 1(0,2.499) 2(0,-2.499)
SKT-HDMI22-150077
  rect 0.305x2.007 smd: 1(4.21,3.37) 2(3.71,3.37) 3(3.21,3.37) 4(2.71,3.37) 5(2.21,3.37) 6(1.71,3.37) 7(1.21,3.37) 8(0.71,3.37) 9(0.21,3.37) 10(-0.29,3.37) 11(-0.79,3.37) 12(-1.29,3.37) 13(-1.79,3.37) 14(-2.29,3.37) 15(-2.79,3.37) 16(-3.29,3.37) 17(-3.79,3.37) 18(-4.29,3.37) 19(-4.79,3.37)
  oval 4.928x1.524 hole 4.216x0.813: 20(0,-2.53)
  oval 1.524x4.674 hole 0.813x3.962: 21(-7.25,0) 22(7.25,0)
SKT-SOIC8-092117H235
  rect 0.508x1.702 smd: 1(1.905,4.1) 2(0.635,4.1) 3(-0.635,4.1) 4(-1.905,4.1) 5(-1.905,-4.1) 6(-0.635,-4.1) 7(0.635,-4.1) 8(1.905,-4.1)
SKT-USB6-135063
  round 1.346 hole 0.94: 1(3.5,-2.71) 2(1,-2.71) 3(-1,-2.71) 4(-3.5,-2.71)
  round 2.718 hole 2.311: 5(6.57,0) 6(-6.57,0)
SKT-USB11-138165-1
  round 1.067 hole 0.711: 1(3.5,3.5) 2(1,3.5) 3(-1,3.5) 4(-3.5,3.5) 5(-4,2) 6(-2,2) 7(0,2) 8(2,2) 9(4,2)
  oval 1.422x3.023 hole 0.711x2.311: 10(-6.4,0) 11(6.4,0)
SMD49-6914-0403H56
  rect 1.168x0.559 smd: 1(-3.38,-0.427) 2(3.38,-0.427) 3(3.38,0.427) 4(-3.38,0.427)
SMD-ARES8-1H26
  rect 0.686x1.016 smd: 1(-1.295,-0.787) 4(1.295,-0.787) 5(1.295,0.787) 8(-1.295,0.787)
  rect 0.508x1.016 smd: 2(-0.406,-0.787) 3(0.406,-0.787) 6(0.406,0.787) 7(-0.406,0.787)
SMD-OSC19H20
  rect 1.194x0.838 smd: 1(-0.945,-0.617) 2(0.945,-0.617) 3(0.945,0.617) 4(-0.945,0.617)
SOD80CH36
  rect 0.762x1.168 smd: 1(0,1.067) 2(0,-1.067)
SOD323AKH38
  rect 0.559x1.016 smd: A(0,1.143) K(0,-1.143)
SOD323AKH42
  rect 0.559x1.016 smd: A(0,1.143) K(0,-1.143)
SOD523AKH28
  rect 0.559x1.016 smd: A(0,0.762) K(0,-0.762)
SOIC8-1H86
  rect 0.635x1.651 smd: 1(-1.905,-3.493) 2(-0.635,-3.493) 3(0.635,-3.493) 4(1.905,-3.493) 5(1.905,3.493) 6(0.635,3.493) 7(-0.635,3.493) 8(-1.905,3.493)
SOIC8-G2D3H70
  rect 0.635x1.651 smd: 1(-1.905,-2.553) 2(-0.635,-2.553) 3(0.635,-2.553) 4(1.905,-2.553) 5(1.905,2.553) 6(0.635,2.553) 7(-0.635,2.553) 8(-1.905,2.553)
  rect 2.311x2.311 smd: 9(0,0)
SOIC8-G3530H63
  rect 0.635x1.651 smd: 1(-1.905,-2.555) 2(-0.635,-2.555) 3(0.635,-2.555) 4(1.905,-2.555) 5(1.905,2.555) 6(0.635,2.555) 7(-0.635,2.555) 8(-1.905,2.555)
  rect 3.505x2.997 smd: 9(0,0)
SOIC8H69
  rect 0.635x1.651 smd: 1(-1.905,-2.54) 2(-0.635,-2.54) 3(0.635,-2.54) 4(1.905,-2.54) 5(1.905,2.54) 6(0.635,2.54) 7(-0.635,2.54) 8(-1.905,2.54)
SON14J3020-G2610H34
  rect 0.025x0.025 smd: 1(1.2,1.105) 6(-0.8,1.105) 9(-0.8,-1.105) 14(1.2,-1.105)
  custom 0.151x0.151 smd: 2(0.8,1.105) 7(-1.2,1.105) 8(-1.2,-1.105) 13(0.8,-1.105)
  rect 0.203x0.813 smd: 3(0.4,1.105) 4(0,1.105) 5(-0.4,1.105) 10(-0.4,-1.105) 11(0,-1.105) 12(0.4,-1.105)
  rect 2.591x0.889 smd: 15(0,0)
SOT23-2D4-312H44
  custom 0.191x0.191 smd: 1(-0.984,-0.953) 2(0.984,-0.953) 3(0,0.953)
SOT23-2D4-312H46
  custom 0.191x0.191 smd: 1(-0.984,-0.953) 2(0.984,-0.953) 3(0,0.953)
SOT23-2D4-312H48
  custom 0.191x0.191 smd: 1(-0.984,-0.953) 2(0.984,-0.953) 3(0,0.953)
SOT23-2D8-312H58
  custom 0.254x0.254 smd: 1(-1.016,-1.118) 2(1.016,-1.118) 3(0,1.118)
SOT23CBE2D4H44
  custom 0.191x0.191 smd: B(-0.984,-0.953) C(0,0.953) E(0.984,-0.953)
SOT23DGS2D4H35
  custom 0.191x0.191 smd: D(0,0.953) G(-0.984,-0.953) S(0.984,-0.953)
SOT23DGS2D4H44
  custom 0.191x0.191 smd: D(0,0.953) G(-0.984,-0.953) S(0.984,-0.953)
SOT23DGS2D4H48
  custom 0.191x0.191 smd: D(0,0.953) G(-0.984,-0.953) S(0.984,-0.953)
SOT23DGS2D8H50
  custom 0.254x0.254 smd: D(0,1.118) G(-1.016,-1.118) S(1.016,-1.118)
SOT323CBE2D2H44
  custom 0.152x0.152 smd: B(-0.65,-0.902) C(0,0.902) E(0.65,-0.902)
SOT-6-1H50
  rect 0.584x1.219 smd: 1(-0.95,-1.194) 2(0,-1.194) 3(0.95,-1.194) 4(0.95,1.194) 5(0,1.194) 6(-0.95,1.194)
SOT-6H44
  rect 0.584x1.016 smd: 1(-0.953,-1.346) 2(0,-1.346) 3(0.953,-1.346) 4(0.953,1.346) 5(0,1.346) 6(-0.953,1.346)
SOT-6H58
  rect 0.584x1.016 smd: 1(-0.953,-1.346) 2(0,-1.346) 3(0.953,-1.346) 4(0.953,1.346) 5(0,1.346) 6(-0.953,1.346)
SOT-23-10H44
  rect 0.762x1.143 smd: 1(-0.984,-0.953) 2(0.984,-0.953) 3(0,0.953)
SOT-89-4541-3PH63
  rect 0.991x1.499 smd: 1(-1.5,0) 3(1.5,0)
  custom 0.502x0.502 smd: 2(0,0)
SOT-363H44
  rect 0.406x1.016 smd: 1(-0.65,-0.94) 2(0,-0.94) 3(0.65,-0.94) 4(0.65,0.94) 5(0,0.94) 6(-0.65,0.94)
SPR10637H367
  rect 10.287x3.404 smd: 1(-2.146,0)
STF256R109H99
  round 6.502 hole 2.769: 1(0,0)
TPAD28
  round 0.711 smd: 1(0,0)
TVS5436-1121H105
  rect 2.337x2.007 smd: 1(0,2.299) 2(0,-2.299)
unnamed
  round 1.016 smd: (0,0)
XFORM12A127097H91
  rect 0.635x1.524 smd: 1(-4.445,-4.699) 2(-3.175,-4.699) 3(-1.905,-4.699) 4(1.905,-4.699) 5(3.175,-4.699) 6(4.445,-4.699) 7(4.445,4.699) 8(3.175,4.699) 9(1.905,4.699) 10(-1.905,4.699) 11(-3.175,4.699) 12(-4.445,4.699)

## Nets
0.775V_TRACK_GATE: Q6704.3 Q6704.4 R4707.2
3V_5V_POK: PC96.1 PR190.1 R31.2 R77.2 R1762.1
3V_VA: C483.1 C485.1 C493.1 C495.2 L21.2 U6.23 U6.25
19V_AMP_AVCC: C208.1 R376.2 U21.12
19V_AMP_PVCC: C543.1 C545.1 C551.1 C552.1 L10.2 R376.1 U21.13 U21.14 U21.27 U21.28
+3VL: PG4904.2
+5VL: PG4901.2 PR4918.1
AGND: C134.2 C140.2 C144.2 C145.1 C146.2 C147.1 C154.2 C155.2 C157.2 C159.2 C160.2 C267.2 C268.2 C450.2 C483.2 C485.2 C493.2 C495.1 C1491.2 LOUT1.5 LOUT1.P Q28.S R215.2 R216.2 R221.2 R268.2 R281.2 R300.2 R301.2 R1182.2 R1193.2 U6.22 U6.28 U6.42 UHS1.5
AVCC33_2136: C292.1 C293.1 C298.1 L17.2 U26.5
AVCC_EC: C4102.1 L4101.2 R79721.1 R79723.1 U4101.52
DVCC1_O2: C9009.1 C9013.1 C9014.1 C9022.1 C9023.1 C9038.1 C9039.1 C9040.1 PG9001.2 U902.C3 U902.D3 U902.D5 U902.D8 U902.G1 U902.G7 U902.H2 U902.H4 U902.J4 U9001.6
DVCC1D8V: C9037.1 R90002.1 R90010.2 R90011.2 R90013.2 R90014.2 R90015.2 R90016.2 R90017.2 R90018.2 R90019.2 R90020.2 R90021.2 R90067.1
DVCC1D8V_O2: R90071.2 R90072.2
DVCC3: R90001.1 R90008.2 R90009.2
DVCC3_O2: C9007.1 C9010.1 C9011.1 C9012.1 C9017.1 C9018.1 C9020.1 C9021.1 R90032.1 R90040.1 R90041.1 R90046.1 R90047.1 R90051.1 R90055.1 R90056.1 R90065.1 R90069.2 R90070.2 R90074.1 R90075.1 U902.C6 U902.D4 U902.E7 U902.F2 U902.G2 U902.H1 U902.J3 U902.K5 U902.K8 U9001.2 U9001.3 U9003.3 U9003.8
DVCC33_2136: C283.1 C284.1 C289.1 C290.2 C291.1 L16.2 R54.1 R69.1 R1074.1 U26.18 U26.22
GND: AFTP1.1 BAT2.9B BAT2.10B BT1.2 BTRST1.1 C1.2 C2.2 C3.2 C6.2 C7.2 C9.2 C11.2 C14.1 C15.2 C20.2 C32.2 C33.2 C35.2 C36.2 C37.2 C38.2 C39.2 C40.2 C46.2 C48.2 C50.2 C52.2 C55.2 C57.2 C58.2 C60.2 C61.2 C65.1 C66.2 C67.2 C72.2 C73.1 C74.1 C75.2 C76.1 C77.2 C78.2 C84.2 C87.2 C88.2 C95.2 C99.2 C100.2 C101.2 C103.2 C104.2 C105.1 C106.2 C109.2 C110.2 C112.2 C121.1 C126.1 C127.2 C129.2 C131.2 C132.1 C170.2 C190.2 C194.2 C197.1 C202.2 C204.2 C209.2 C213.2 C222.2 C225.2 C226.2 C227.2 C235.2 C236.2 C238.2 C239.2 C243.2 C247.2 C248.2 C255.2 C256.2 C258.2 C262.2 C263.2 C283.2 C284.2 C289.2 C290.1 C291.2 C292.2 C293.2 C295.2 C296.2 C297.2 C298.2 C299.1 C315.2 C316.1 C326.2 C330.2 C337.2 C353.2 C356.2 C392.2 C395.2 C474.2 C478.2 C509.2 C516.2 C521.2 C525.1 C531.1 C542.2 C543.2 C545.2 C548.1 C549.1 C550.1 C551.2 C552.2 C562.2 C565.2 C570.2 C572.2 C574.2 C579.2 C580.2 C582.2 C583.2 C584.2 C585.2 C587.2 C589.2 C591.2 C592.2 C593.2 C595.2 C597.2 C714.1 C721.1 C857.2 C862.2 C863.2 C864.2 C865.1 C866.2 C869.2 C871.2 C872.2 C1608.2 C1609.1 C1615.2 C1616.2 C1617.2 C1638.2 C1639.2 C1644.2 C1645.2 C1646.2 C1647.2 C1648.2 C1649.2 C1650.2 C1651.2 C1652.2 C1653.2 C1654.2 C1655.2 C1656.2 C1657.2 C1658.2 C1659.2 C1660.2 C1661.2 C1662.2 C1663.2 C1664.2 C1665.2 C1666.2 C1667.2 C1668.2 C1669.2 C1670.2 C1671.2 C1672.2 C1673.2 C1674.2 C1677.2 C1678.2 C1679.2 C1680.2 C1681.2 C1682.2 C1683.2 C1684.2 C1685.2 C1686.2 C1687.2 C1688.2 C1689.2 C1690.2 C1691.2 C1692.2 C1693.2 C1694.2 C1695.2 C1696.2 C1697.2 C1698.2 C1699.2 C1700.2 C1701.2 C1702.2 C1703.2 C1704.2 C1705.2 C1706.2 C1707.2 C1708.2 C1714.2 C1715.2 C1716.2 C1721.1 C1722.1 C1723.2 C1724.2 C1725.2 C1726.2 C1727.1 C1728.2 C1729.2 C1730.2 C1731.1 C1732.2 C1733.1 C1734.2 C1735.2 C1736.2 C1737.1 C1738.2 C1739.2 C1741.2 C1742.2 C1743.2 C1744.2 C1745.2 C1746.1 C1747.2 C1748.1 C1752.1 C1753.1 C1754.1 C1755.2 C1756.2 C1758.1 C1760.2 C1764.1 C1768.1 C1769.2 C1770.2 C1771.2 C1773.2 C1774.2 C1796.2 C1797.2 C1798.2 C1799.2 C1800.2 C1801.2 C1802.2 C1803.2 C1804.2 C1806.2 C1807.2 C1820.1 C1821.2 C1823.2 C1824.2 C1826.1 C1827.2 C1828.2 C1829.2 C1830.2 C1831.2 C1832.2 C1833.2 C1834.2 C1835.2 C1836.2 C1837.2 C1870.1 C1871.2 C1872.2 C1873.2 C1874.2 C1875.2 C1876.2 C1877.2 C1925.2 C1926.2 C1927.2 C1928.2 C1929.2 C1930.2 C1934.2 C1935.2 C1936.2 C1937.2 C1938.2 C1939.2 C1940.2 C1941.2 C1942.2 C1943.2 C1944.2 C1945.2 C1946.2 C1947.2 C1948.2 C1949.2 C1950.2 C1951.2 C1952.2 C1953.2 C1954.2 C1956.2 C1957.2 C1958.2 C1959.2 C1960.2 C1961.2 C1962.2 C1963.2 C1964.2 C1965.2 C1966.2 C1967.2 C1968.2 C1969.2 C1970.2 C1971.2 C1972.2 C1973.2 C1974.2 C1975.2 C1976.2 C1977.2 C1978.2 C1979.1 C1980.1 C1981.1 C1982.1 C3131.2 C3366.2 C3367.2 C3376.1 C3377.2 C3378.2 C3379.2 C3380.1 C3381.1 C3382.2 C3383.2 C3452.2 C3453.2 C3454.2 C3459.2 C3460.2 C4101.1 C4102.2 C6701.2 C6702.2 C6703.2 C6712.2 C6714.2 C6715.2 C6718.2 C6719.2 C6720.2 C6721.2 C6722.1 C6724.1 C6726.2 C6727.2 C6728.2 C6729.2 C9006.1 C9007.2 C9009.2 C9010.2 C9011.2 C9012.2 C9013.2 C9014.2 C9015.2 C9016.2 C9017.2 C9018.2 C9019.2 C9020.2 C9021.2 C9022.2 C9023.2 C9024.2 C9025.2 C9031.2 C9032.2 C9034.2 C9035.2 C9036.2 C9037.2 C9038.2 C9039.2 C9040.2 C9041.2 CONVT1.10 CONVT1.11 CONVT1.12 CPU1.A8 CPU1.A12 CPU1.A16 CPU1.A20 CPU1.A24 CPU1.A28 CPU1.A32 CPU1.AB1 CPU1.AB2 CPU1.AB4 CPU1.AB10 CPU1.AB13 CPU1.AB16 CPU1.AB19 CPU1.AB22 CPU1.AD4 CPU1.AD9 CPU1.AD12 CPU1.AD15 CPU1.AD18 CPU1.AD21 CPU1.AD24 CPU1.AE10 CPU1.AE13 CPU1.AE16 CPU1.AE19 CPU1.AE22 CPU1.AF1 CPU1.AF4 CPU1.AG9 CPU1.AG12 CPU1.AG15 CPU1.AG18 CPU1.AG21 CPU1.AH4 CPU1.AH10 CPU1.AH13 CPU1.AH16 CPU1.AH19 CPU1.AH22 CPU1.AK1 CPU1.AK4 CPU1.AK12 CPU1.AK15 CPU1.AK18 CPU1.AK21 CPU1.AL10 CPU1.AL16 CPU1.AL19 CPU1.AL22 CPU1.AM4 CPU1.AN9 CPU1.AN10 CPU1.AN15 CPU1.AN18 CPU1.AN21 CPU1.AN25 CPU1.AN28 CPU1.AP1 CPU1.AP2 CPU1.AP4 CPU1.AP7 CPU1.AP22 CPU1.AP27 CPU1.AP30 CPU1.AP33 CPU1.AR6 CPU1.AR25 CPU1.AR28 CPU1.AT4 CPU1.AT19 CPU1.AT22 CPU1.AT30 CPU1.AU5 CPU1.AU8 CPU1.AU11 CPU1.AU14 CPU1.AU20 CPU1.AU23 CPU1.AU27 CPU1.AV4 CPU1.AV7 CPU1.AV9 CPU1.AV12 CPU1.AV15 CPU1.AV25 CPU1.AV30 CPU1.AV33 CPU1.AW22 CPU1.AY4 CPU1.AY6 CPU1.AY8 CPU1.AY10 CPU1.AY12 CPU1.AY14 CPU1.AY16 CPU1.AY20 CPU1.AY22 CPU1.AY24 CPU1.AY26 CPU1.AY28 CPU1.AY30 CPU1.B2 CPU1.B8 CPU1.B12 CPU1.B33 CPU1.BB1 CPU1.BB33 CPU1.BC4 CPU1.BC8 CPU1.BC12 CPU1.BC16 CPU1.BC20 CPU1.BC24 CPU1.BC28 CPU1.BC32 CPU1.C3 CPU1.D4 CPU1.D6 CPU1.D8 CPU1.D10 CPU1.D12 CPU1.D14 CPU1.D16 CPU1.D18 CPU1.D20 CPU1.D22 CPU1.D24 CPU1.D26 CPU1.D28 CPU1.D30 CPU1.F1 CPU1.F2 CPU1.F4 CPU1.F9 CPU1.F19 CPU1.F22 CPU1.F25 CPU1.F30 CPU1.F33 CPU1.G7 CPU1.G17 CPU1.G20 CPU1.G23 CPU1.G26 CPU1.H4 CPU1.H30 CPU1.J5 CPU1.J15 CPU1.J19 CPU1.J22 CPU1.J25 CPU1.J28 CPU1.K1 CPU1.K2 CPU1.K4 CPU1.K10 CPU1.K22 CPU1.K27 CPU1.K30 CPU1.K33 CPU1.L5 CPU1.L12 CPU1.L15 CPU1.L18 CPU1.L21 CPU1.L24 CPU1.L25 CPU1.L28 CPU1.M4 CPU1.M30 CPU1.N10 CPU1.N13 CPU1.N16 CPU1.N19 CPU1.N22 CPU1.N27 CPU1.P1 CPU1.P2 CPU1.P4 CPU1.P5 CPU1.P12 CPU1.P15 CPU1.P18 CPU1.P21 CPU1.P30 CPU1.P33 CPU1.T4 CPU1.T10 CPU1.T13 CPU1.T16 CPU1.T19 CPU1.T22 CPU1.T30 CPU1.U5 CPU1.U12 CPU1.U15 CPU1.U18 CPU1.U21 CPU1.U24 CPU1.V1 CPU1.V2 CPU1.V4 CPU1.W10 CPU1.W13 CPU1.W16 CPU1.W19 CPU1.W22 CPU1.Y4 CPU1.Y5 CPU1.Y12 CPU1.Y15 CPU1.Y18 CPU1.Y21 CPU1.Y24 D4.2 D16.A D19.1 D21.A D24.2 DCIN1.2 DCIN1.4 DCIN1.5 DCIN1.6 DCIN1.7 DCIN2.5 DCIN2.6 DCIN2.7 DCIN2.12 DCIN2.13 DCIN2.14 DIMM1.2 DIMM1.3 DIMM1.8 DIMM1.9 DIMM1.13 DIMM1.14 DIMM1.19 DIMM1.20 DIMM1.25 DIMM1.26 DIMM1.31 DIMM1.32 DIMM1.37 DIMM1.38 DIMM1.43 DIMM1.44 DIMM1.48 DIMM1.49 DIMM1.54 DIMM1.55 DIMM1.60 DIMM1.61 DIMM1.65 DIMM1.66 DIMM1.71 DIMM1.72 DIMM1.127 DIMM1.128 DIMM1.133 DIMM1.134 DIMM1.138 DIMM1.139 DIMM1.144 DIMM1.145 DIMM1.150 DIMM1.151 DIMM1.155 DIMM1.156 DIMM1.161 DIMM1.162 DIMM1.167 DIMM1.168 DIMM1.172 DIMM1.173 DIMM1.178 DIMM1.179 DIMM1.184 DIMM1.185 DIMM1.189 DIMM1.190 DIMM1.195 DIMM1.196 DIMM1.205 DIMM1.206 DIMM2.2 DIMM2.3 DIMM2.8 DIMM2.9 DIMM2.13 DIMM2.14 DIMM2.19 DIMM2.20 DIMM2.25 DIMM2.26 DIMM2.31 DIMM2.32 DIMM2.37 DIMM2.38 DIMM2.43 DIMM2.44 DIMM2.48 DIMM2.49 DIMM2.54 DIMM2.55 DIMM2.60 DIMM2.61 DIMM2.65 DIMM2.66 DIMM2.71 DIMM2.72 DIMM2.127 DIMM2.128 DIMM2.133 DIMM2.134 DIMM2.138 DIMM2.139 DIMM2.144 DIMM2.145 DIMM2.150 DIMM2.151 DIMM2.155 DIMM2.156 DIMM2.161 DIMM2.162 DIMM2.167 DIMM2.168 DIMM2.172 DIMM2.173 DIMM2.178 DIMM2.179 DIMM2.184 DIMM2.185 DIMM2.189 DIMM2.190 DIMM2.195 DIMM2.196 DIMM2.205 DIMM2.206 FANC3.1 H1.1 H2.1 H3.1 H4.1 H5.1 H6.1 H6.2 H6.3 H6.4 H6.5 H6.6 H6.7 H6.8 H7.1 H7.2 H7.3 H7.4 H7.5 H7.6 H7.7 H7.8 H9.1 H9.2 H9.3 H9.4 H9.5 H9.6 H9.7 H9.8 H10.1 H10.2 H10.3 H10.4 H10.5 H10.6 H10.7 H10.8 H11.1 H11.2 H11.3 H11.4 H11.5 H11.6 H11.7 H11.8 HDD1.1 HDD1.4 HDD1.7 HDD1.8 HDD1.9 HDMI1.2 HDMI1.5 HDMI1.8 HDMI1.11 HDMI1.17 HDMI1.20 HDMI1.21 HDMI1.22 HDMI2.3 HDMI2.9 HDMI2.12 HDMI2.15 HDMI2.18 HDMI2.20 HDMI2.21 HDMI2.22 HDMI2.23 HDMI2.24 HDMI2.25 HDT1.3 HDT1.5 HDT1.7 HDT1.17 HS6.1 LED2.K LED3.K LPC1.12 LPC1.14 LVDS1.7 LVDS1.14 LVDS1.31 LVDS1.32 MEMCD1.3 MEMCD1.6 MEMCD1.12 MEMCD1.13 MEMCD1.14 MEMCD1.15 NGFF1.7 NGFF1.18 NGFF1.23 NGFF1.24 NGFF1.29 NGFF1.30 NGFF1.33 NGFF1.36 NGFF1.39 NGFF1.45 NGFF1.57 NGFF1.63 NGFF1.69 NGFF1.75 NGFF1.76 NGFF1.77 PC34.2 PC48.2 PC49.2 PC50.2 PC51.2 PC52.2 PC96.2 PC126.1 PC2127.1 PC4301.2 PC4302.2 PC4303.2 PC4304.2 PC4305.2 PC4401.2 PC4405.2 PC4406.2 PC4407.2 PC4602.2 PC4606.2 PC4607.1 PC4608.2 PC4609.1 PC4614.2 PC4616.2 PC4619.1 PC4622.2 PC4701.2 PC4702.2 PC4703.2 PC4705.2 PC4706.2 PC4707.2 PC4708.2 PC4709.2 PC4711.2 PC4712.2 PC4713.2 PC4801.2 PC4802.2 PC4803.2 PC4804.2 PC4808.2 PC4901.2 PC4902.2 PC4903.2 PC4904.2 PC4905.2 PC4906.2 PC4909.2 PC4910.2 PC4912.2 PC4914.1 PC4915.2 PC4916.2 PC4917.2 PC4918.2 PC5001.2 PC5009.2 PC5011.2 PC5012.2 PC5014.2 PC5016.2 PC5017.2 PC5018.2 PC5019.2 PC5020.2 PC5021.2 PC5022.2 PC5202.2 PC5204.2 PC5205.2 PC5209.2 PC5210.2 PC5211.2 PC5212.2 PC5213.2 PC5214.2 PC5233.1 PC5237.2 PC5240.2 PC5241.2 PC5242.2 PC5243.2 PC5245.2 PC5246.2 PC5247.2 PC5248.2 PC5401.2 PC5402.2 PC5403.2 PC5404.2 PC5405.2 PC5413.2 PC5420.2 PC5421.2 PC5422.1 PC5423.1 PC5424.2 PC5427.2 PC5428.2 PC5429.2 PL4301.2 PL4302.2 PL4303.2 PQ4204.E PQ4206.S PQ4406.1 PQ4406.4 PQ4408.S PQ5003.S PQ5004.S PQ5005.1 PQ5005.4 PR4413.1 PR4433.2 PR4451.2 PR4603.2 PR4605.1 PR4610.1 PR4611.1 PR4613.1 PR4614.2 PR4627.2 PR4629.1 PR4630.1 PR4635.2 PR4802.1 PR4806.2 PR4807.2 PR4816.2 PR4917.2 PR4919.2 PR4920.2 PR4922.2 PR4924.2 PR4925.2 PR5009.2 PR5209.2 PR5223.2 PR5274.1 PR5285.2 PR5292.1 PR5298.2 PR5402.2 PR5411.1 PR5412.2 PR5416.1 PR5419.2 PR5421.1 PR5423.1 PR5472.2 PSWD1.1 PT4701.2 PT4702.2 PT4703.2 PT4704.2 PT4708.2 PT4709.2 PT4712.2 PT4801.2 PT4901.2 PT4902.2 PT4903.2 PT5007.2 PT5401.2 PT5402.2 PT5403.2 PT5405.2 PU4.1 PU5.2 PU5.9 PU4405.1 PU4405.2 PU4405.3 PU4601.32 PU4601.53 PU4703.1 PU4703.2 PU4703.3 PU4704.1 PU4704.2 PU4704.3 PU4705.1 PU4705.2 PU4705.3 PU4706.1 PU4706.2 PU4706.3 PU4801.1 PU4801.2 PU4801.3 PU4803.11 PU4901.21 PU4903.1 PU4903.2 PU4903.3 PU4905.1 PU4905.2 PU4905.3 PU5001.1 PU5001.3 PU5001.14 PU5001.21 PU5007.1 PU5007.2 PU5007.3 PU5201.2 PU5201.5 PU5201.6 PU5201.14 PU5206.1 PU5402.1 PU5402.2 PU5402.3 PU5403.1 PU5403.2 PU5403.3 PU5407.15 PU5407.17 PU5407.19 PU5407.20 PU5407.23 PU5407.24 PU5407.32 PU5407.53 PWRCN1.4 PWRCN1.11 PWRCN1.12 Q1.S Q3.S Q5.S Q10.E Q12.1 Q12.4 Q13.1 Q13.4 Q18.1 Q18.4 Q22.E Q24.3 Q31.E Q36.1 Q36.4 Q37.1 Q37.4 Q38.E Q45.E Q46.3 Q50.2 Q51.S Q52.E Q57.3 Q63.1 Q64.S Q65.1 Q65.4 Q68.S Q79.S Q100.E Q101.E Q102.E Q103.S Q104.S Q105.S Q107.S Q128.E Q1208.E Q1209.S Q1212.S Q1213.E Q1214.E Q1217.1 Q1217.4 Q1226.1 Q1226.4 Q1227.S Q1240.S Q1241.E Q1244.S Q1245.S Q1246.S Q1247.S Q1248.S Q1249.S Q4701.4 Q6701.1 Q6701.4 Q9648.S Q9650.S Q90001.S Q90002.S R1.2 R19.2 R27.2 R30.2 R33.2 R37.1 R73.1 R78.2 R107.2 R115.2 R122.2 R132.2 R144.2 R152.2 R154.2 R163.2 R172.2 R178.1 R181.2 R210.2 R215.1 R216.1 R300.1 R301.1 R360.2 R368.2 R370.2 R406.2 R412.1 R433.2 R501.2 R507.1 R511.2 R512.2 R513.2 R523.2 R533.2 R542.1 R545.2 R656.2 R666.2 R709.2 R722.2 R732.2 R762.2 R1079.2 R1179.1 R1182.1 R1193.1 R1209.2 R1592.2 R1603.2 R1604.2 R1605.2 R1606.2 R1607.2 R1608.2 R1609.2 R1619.2 R1623.1 R1629.2 R1631.2 R1635.2 R1644.1 R1648.2 R1649.2 R1658.1 R1660.2 R1663.2 R1670.2 R1685.2 R1688.2 R1690.1 R1691.1 R1700.1 R1702.2 R1703.2 R1705.2 R1707.2 R1709.2 R1724.2 R1727.2 R1729.2 R1779.2 R1781.2 R1782.2 R1817.2 R1819.2 R1834.2 R1848.2 R1850.2 R1853.2 R1867.2 R1869.2 R1871.2 R1873.2 R1988.1 R1999.2 R2001.2 R2003.2 R2004.2 R2008.2 R2056.2 R2058.2 R2060.2 R2062.2 R2063.2 R2082.2 R2085.2 R2086.2 R2089.2 R2090.2 R4706.2 R79622.2 R79647.1 R79648.1 R79650.2 R79651.2 R79652.2 R79653.2 R79654.2 R79659.2 R79668.2 R79677.2 R79678.1 R79679.1 R79680.1 R79681.1 R79705.2 R79720.2 R79722.2 R80215.2 R80218.2 R80225.2 R80227.1 R90012.2 R90031.2 R90039.1 R90048.2 R90050.2 R90052.2 R90053.2 R90054.2 R90064.2 R90073.2 RJ1.13 RV1.1 SATAP1.2 SATAP1.4 SPI1.4 SPK1.5 SPK1.7 SPK1.8 SPR1.1 SRCON1.4 SSUSB1.4 SSUSB1.7 SSUSB1.10 SSUSB1.11 SSUSB2.4 SSUSB2.7 SSUSB2.10 SSUSB2.11 TC1.2 TC7.2 TC8.2 TOUCH1.2 U3.3 U3.8 U5.3 U5.8 U6.49 U7.4 U10.2 U11.2 U12.2 U16.33 U21.8 U21.9 U21.10 U21.17 U21.20 U21.21 U21.24 U21.33 U25.1 U25.2 U25.4 U25.7 U26.6 U26.49 U31.3 U31.8 U52.11 U52.15 U54.11 U54.15 U55.14 U55.21 U109.4 U109.35 U109.71 U116.3 U116.8 U117.3 U117.8 U118.8 U118.15 U118.35 U118.41 U120.20 U178.4 U902.A1 U902.A2 U902.B10 U902.C1 U902.C2 U902.C5 U902.D6 U902.D7 U902.E2 U902.E3 U902.E4 U902.E5 U902.F3 U902.F4 U902.F7 U902.G3 U902.G4 U902.G5 U902.J1 U902.J5 U902.J7 U902.K3 U902.K9 U903.A6 U903.C4 U903.E7 U903.G5 U903.H10 U903.J5 U903.K8 U903.N2 U903.N5 U903.P4 U903.P6 U4101.10 U4101.21 U4101.45 U4101.53 U6701.5 U6701.10 U6701.12 U6701.13 U6701.15 U6701.16 U9001.1 U9001.5 U9001.8 U9001.9 U9003.4 UHS1.MS1 UHS1.MS2 USB3.4 USB3.5 USB3.6 USB4.4 USB4.5 USB4.6 WEBCM1.6 WEBCM1.8 WEBCM1.9 WEBCM1.10 X1.2 X1.4 X2.2 X2.3 X4.2 X4.4 X54.2 X54.4
GND_AUD: C144.1 C145.2 U6.40
VBAT1: BT1.1 R1683.2 TP189.1
VBAT1_R: D23.1 D33.1 R1683.1 TP188.1
VBAT2: D33.2 R707.2
VBAT_SB_N: C871.1 PU4.2 R1721.2
VBAT_SIO: C1821.1 R707.1 U109.66
VCC: C20.1 C714.2 C1832.1 C1833.1 D31.A F5.1 F13.1 LPC1.8 R101.2 R183.1 R185.1 R617.1 R1838.2 R1849.1 R2080.1 R6705.1 U1.1 U1.2 U1.5 U1.6 U52.13 U52.14
VCC3: C474.1 C478.1 C509.1 C516.1 C1714.1 C1729.1 C1730.1 C1834.1 C1835.1 C1975.1 C1976.1 C3367.1 C3379.1 C3380.2 CPU1.AP19 CPU1.AP21 D1.K D19.2 DIMM1.199 DIMM2.199 F1.1 F6.2 L16.1 L17.1 L21.1 LPC1.4 PR4624.1 PR4632.1 PR5463.1 R12.1 R24.1 R32.1 R41.1 R46.1 R47.1 R57.1 R58.1 R71.1 R134.1 R138.1 R143.1 R159.2 R160.1 R162.2 R165.1 R206.1 R213.1 R294.1 R308.2 R316.2 R334.2 R341.2 R350.2 R351.2 R366.1 R377.1 R381.2 R482.1 R508.1 R517.1 R524.1 R530.2 R634.2 R680.2 R689.2 R1183.2 R1593.1 R1594.1 R1596.1 R1598.1 R1634.1 R1650.1 R1657.2 R1659.1 R1661.1 R1662.1 R1673.2 R1674.2 R1684.1 R1687.1 R1699.1 R1701.1 R1716.2 R1749.2 R1757.1 R1776.1 R1829.2 R1837.2 R1845.2 R1846.1 R1860.1 R1868.1 R1870.1 R1872.1 R1926.2 R1986.2 R2025.2 R2026.1 R2055.1 R2061.1 R2077.1 R2087.1 R2088.1 R6701.1 R6703.1 R6704.1 R79655.2 R79672.2 R79676.2 R79694.2 R79714.2 R90009.1 R90070.1 RN7.5(B) RN7.6(B) RN7.7(B) RN7.8(B) U6.11 U25.3 U25.8 U52.8 U52.9 U118.11 U118.37 U119.3 U4101.4
VCC3_CAM: C1.1 C1770.1 C1771.1 F1.2 F3.2 R24.2 R1784.2 WEBCM1.3
VCC5_33_CT1: C1837.1 U52.12
VCC5_33_CT2: C1836.1 U52.10
VCC5_33_EN: C1831.1 R1878.1 U52.3 U52.5
VCC5_DDC_HDMI: C6721.1 D31.K R2083.1 R2084.1
VCC5_PANEL: C2.1 C3.1 C6.1 F2.2 LVDS1.2 LVDS1.3 Q9647.S R481.1 R1163.1 R80233.2
VCC5_USB: C227.1 C249.2 C1769.1 F12.1 F14.1 F15.1 Q43.1 Q43.2 Q43.3 R433.1 R1729.1 R1782.1
VCC_FAN: C48.1 F5.2 FANC3.2 R80.1 R101.1
VCC_VTT: PC5001.1 PC5016.1 PR5018.1 PR5019.1 PU5001.2 PU5001.20
VDD_095_FB_H: Q14.S R110.2 R1612.2
VDD_095_FB_H_CTL: PR83.2 Q14.D R110.1
VDD_095_FB_L: R1861.2 R80227.2
VDDCR_APU_FB_H: PR4604.2 PR4628.2 R1611.2
VDDCR_APU_FB_L: PR4606.2 PR4611.2 R528.2
VDDCR_CPU_SENSE: CPU1.G12 R1611.1
VDDCR_GFX_FB_H: PR5410.2 PR5420.2 R1953.2
VDDCR_GFX_FB_L: PR5416.2 PR5422.2 R1954.2
VDDCR_GFX_SENSE: CPU1.H11 R1953.1
VDDCR_NB_FB_H: PR4642.2 PR4643.2 R1613.2
VDDCR_NB_FB_L: PC4601.2 PC4605.2 PR4606.1 PU4601.52 R529.2
VDDCR_NB_SENSE: CPU1.J12 R1613.1
VDDGFX_EN: C1930.1 PU5407.9 Q1240.D R1986.1
VDDGFX_EN_1: Q1240.G Q1241.C R1987.1
VDDGFX_EN_2: Q1241.B R1988.2 R1989.2
VDDGFX_PD: CPU1.AD8 TP214.1
VDDGFX_PWROK: PR5466.1 PU5407.2
VDDNB: C326.1 C1653.1 C1654.1 C1655.1 C1656.1 C1665.1 C1666.1 C1667.1 C1668.1 C1669.1 C1670.1 C1671.1 C1672.1 CPU1.AL12 CPU1.AL13 CPU1.AL15 CPU1.AL18 CPU1.AL21 CPU1.AN13 CPU1.AN16 CPU1.AN19 CPU1.AN22 PC5427.1 PG4704.1 PL4702.2 PR4643.1 PT4703.1 PT4704.1 Q6703.1 Q6703.2 R79724.2 U178.3
VDDNB_TRACK_GATE: Q6703.3 Q6703.4 R4708.2
VDDP_SENSE: CPU1.AY18 R1612.1
VSS_SENSE: CPU1.H12 R528.1 R529.1 R1861.1 R1954.1 R80225.1
0D95V_S0: C94.2 C95.1 C101.1 C1695.1 C1696.1 C1697.1 C1704.1 C1705.1 C1706.1 C1707.1 C1708.1 CPU1.AE5 CPU1.AE6 CPU1.AU17 CPU1.AU19 CPU1.AV17 CPU1.AV19 CPU1.AW17 CPU1.AW19 R178.2 R527.2 R557.2 R558.1 R586.1 R1989.1 U2.1 U2.2 U2.3
0D95V_S0_EN: R174.2 U2.4
0D95V_S5: C1702.1 C1703.1 CPU1.AN12 CPU1.AP12 PC4802.1 PG4801.2 PL4802.2 PR83.1 PT4801.1 R559.2 U2.5 U2.6 U2.7 U2.8
0P95V_MAIN_APU_M: Q52.B R527.1
1D5V_S3_PG_1: D20.1 R1774.1
1D5V_S5: PR5291.1 PR5296.1 R205.1 R1601.2
1D8V_S0: C315.1 C316.2 C1673.1 C1674.1 CPU1.AP16 CPU1.AP18 PU4601.6 PU5407.6 Q1210.S R495.1 R504.1 R542.2 R1610.2 R1617.1 R1628.2 R1630.2 R1632.2 R1698.1 R1720.2 R1998.2 R2000.2 R2002.2 R2022.2 R2023.1 R2028.1 R2031.2 R2032.2 R90011.1 R90072.1 U105.4
1D8V_S5: C1677.1 C1828.1 C1957.1 CPU1.AP10 CPU1.AR9 PC52.1 PC5205.1 PC5210.1 PC5211.1 PC5212.1 PC5213.1 PG5211.1 PG5212.1 PL5202.2 PR5290.1 PR5473.1 PU5.1 R1595.1 R1677.1 R90010.1 R90071.1 U105.1 U105.2 U105.5 U105.6
1D35V_S3: C46.1 C55.1 C60.1 C337.1 C353.1 C356.1 C392.1 C1678.1 C1679.1 C1680.1 C1681.1 C1682.1 C1683.1 C1684.1 C1685.1 C1686.1 C1687.1 C1688.1 C1689.1 C1690.1 C1691.1 C1692.1 C1693.1 C1694.1 C1723.1 C1725.1 C1871.1 C1872.1 C1873.1 C1874.1 C1875.1 C1876.1 C1961.1 C1962.1 C1963.1 C1964.1 C1965.1 C1966.1 C1967.1 C1968.1 C1969.1 C1970.1 C1972.1 C1973.1 C1974.1 C1978.1 CPU1.AB24 CPU1.AB27 CPU1.AB30 CPU1.AB33 CPU1.AD25 CPU1.AD28 CPU1.AD30 CPU1.AE24 CPU1.AE27 CPU1.AF30 CPU1.AF33 CPU1.AG25 CPU1.AG28 CPU1.AH24 CPU1.AH27 CPU1.AH30 CPU1.AK25 CPU1.AK28 CPU1.AK30 CPU1.AK33 CPU1.AL27 CPU1.AM30 CPU1.P25 CPU1.P28 CPU1.T24 CPU1.T27 CPU1.U25 CPU1.U28 CPU1.V30 CPU1.V33 CPU1.W24 CPU1.W27 CPU1.Y25 CPU1.Y28 CPU1.Y30 DIMM1.75 DIMM1.76 DIMM1.81 DIMM1.82 DIMM1.87 DIMM1.88 DIMM1.93 DIMM1.94 DIMM1.99 DIMM1.100 DIMM1.105 DIMM1.106 DIMM1.111 DIMM1.112 DIMM1.117 DIMM1.118 DIMM1.123 DIMM1.124 DIMM2.75 DIMM2.76 DIMM2.81 DIMM2.82 DIMM2.87 DIMM2.88 DIMM2.93 DIMM2.94 DIMM2.99 DIMM2.100 DIMM2.105 DIMM2.106 DIMM2.111 DIMM2.112 DIMM2.117 DIMM2.118 DIMM2.123 DIMM2.124 PC5012.1 PG5001.1 PL5001.2 PR5020.1 PR5021.1 PT5007.1 R120.1 R121.2 R1584.1 R1586.1 R1588.1 R1633.1 R1696.2 R2057.1 R2059.1
1P5_5930_EN: PC5245.1 PU5206.8 R31.1 R1930.2
1P5_5930_FB: PC5244.2 PR5292.2 PR5293.1 PU5206.2
1P5_5930_PG: PR5295.2 PU5206.7
1P5_5930_VCNTL: PC5243.1 PR5294.2 PU5206.6
1P5V_LPS_APU: BTRST1.2 C1736.1 C1741.1 CPU1.AR17 R1185.2 R1721.1
1P5V_S3_PG: PR5005.2 PU5001.10 R1774.2
1P8V_PWR_PG: PR5206.2 PU5201.4 R1763.1 R1930.1
3D3V_AUX_EC: L4101.1 PR8519.1 PR8520.1 Q9649.D R79706.1 R79707.2 R80230.2 U4101.11 U4101.22 U4101.38 U4101.44 U4101.56
3D3V_RUN_FFS: C6701.1 C6702.1 C6703.1 R6701.2 U6701.1 U6701.7 U6701.8 U6701.14
1117_ADJ: R1592.1 R2081.2 U119.1
A20GATE: CPU1.BC19 R350.1 R80231.2
AC_IN: PQ5004.D PQ5005.2 PR5281.2
AC_IN_KBC#: TP4124.1 U4101.29
AC_OK#: PQ5004.G PR4427.2 R80209.1 U55.5 U4101.37
AC_OK#_ECIO: R80209.2 U109.99
AC_PRES: CPU1.AG3 R582.1
AC_PROTECT: PQ4408.G PR5287.1 PR5289.2 PR5297.2 PR5298.1 U55.3
AD+_2: C260.2 PQ4205.C R1847.2 R1850.1 U110.4
AD+_G_1: PQ5005.5 PQ5005.6 PR5272.2
AD+_G_2: PR5272.1 PR5275.2 PU5204.4
AD+_TO_SYS: PG4907.1 PR5275.1 PR5276.1 PU5204.1 PU5204.2 PU5204.3 R79643.2 R79644.2 R79645.2 R79646.2 R79656.2
AD_IA: PR5288.2 R80216.1 U4101.48
AD_IA_HW1: PQ5006.2 R79637.1 U109.106 U4101.59
AD_IA_HW2: PQ5006.5 R79638.1 U109.107 U4101.60
AD_JK: C260.1 C262.1 C597.1 D16.K DCIN1.1 DCIN2.1 DCIN2.2 DCIN2.3 DCIN2.8 DCIN2.9 DCIN2.10 PQ4205.E PR4214.1 R1847.1 U110.1 U110.2 U110.3
AD_OFF: R2013.1 R80211.1 U4101.36
AD_OFF_ECIO: R80211.2 U109.97
AD_OFF_L: PQ4204.C PQ4205.B
ADAPTOR_PSID: D19.3 R1846.2 R1851.2 R80213.1 U109.119
ADAPTOR_PSID_R: Q47.S R1851.1
AGPIO3: CPU1.AL5 R2008.1 R2010.2
AGPIO8: CPU1.AJ4 R79650.1
AGPIO11: CPU1.AN5 R2063.1 R2064.2
AGPIO13: CPU1.AD5 R79673.1
AGPIO14: CPU1.AL8 TP198.1
AGPIO15: CPU1.AN8 TP199.1
AGPIO24: CPU1.AL9 R79671.1
AGPIO40: CPU1.AG8 R79651.1
AGPIO66: CPU1.AT15 R159.1
AGPIO84: CPU1.BC18 R79714.1
AGPIO88: CPU1.BC11 TP186.1
AGPIO89: CPU1.BB14 R79672.1
AMP_GND: C192.2 C193.2 C208.2 C531.2 R344.1 R346.1 R347.1 R355.2 R358.2 R365.2 R666.1 U21.4
AMP_SPKR_L: C199.1 R355.1 R356.2
AMP_SPKR_R: C210.1 R365.1 R367.2
APU_ALERT#: CPU1.B17 R1616.2
APU_DBRDY: CPU1.C13 HDT1.14
APU_DBREQ: HDT1.16 R1746.1
APU_DBREQ#: C1739.1 CPU1.A11 R1704.2 R1746.2
APU_DIS_1: C866.1 Q104.G R1185.1
APU_DIS_2: Q104.D Q105.G R1186.1
APU_DIS_3: Q105.D R1981.1
APU_LVDS_BL_ADJ: CPU1.F11 R502.2
APU_M_VREF_SUS: C1608.1 C1609.2 R115.1 R1588.2 R1912.1
APU_M_VREFDQ_SUS: C15.1 C1727.2 C1728.1 C1731.2 C1959.1 C1960.1 C1981.2 C1982.2 DIMM1.1 DIMM2.1 R78.1 R81.1 R1633.2 R1697.1 R2057.2 R2058.1
APU_PROCHOT#: CPU1.A15 PQ4408.D PR24.2 PR4455.1 PR5464.2 R1615.2 R80226.1 U4101.14
APU_PWNBTN_N: CPU1.AE1 R1653.2
APU_PWRGD: C1722.2 CPU1.C19 R495.2 R1720.1 R1744.2 R1904.1
APU_PWRGD_BUF: HDT1.10 R1744.1
APU_S5_MUX_CTRL: CPU1.AH8 R4230.1
APU_S5_MUX_CTRL_D: Q4701.2 Q4701.3 R4702.2
APU_S5_MUX_CTRL_R: PC5429.1 Q4701.5 R4230.2 R79674.2 R79675.2
APU_SATA_LED_N: CPU1.BB15 Q9646.4 R1754.1 R2077.2
APU_SIC: CPU1.B18 R93.2 U109.51
APU_SID: CPU1.C17 R1614.2 U109.50
APU_SPKR: CPU1.BA17 R208.1
APU_SVC: CPU1.D17 R1628.1 R1902.1
APU_SVD: CPU1.D19 R1630.1 R1903.1
APU_SVT: CPU1.C15 R1632.1 R1901.1
APU_TCK: CPU1.D13 HDT1.2 RN12.2(A)
APU_TDI: CPU1.H15 HDT1.6 RN12.1(A)
APU_TDO: CPU1.H14 HDT1.8
APU_TEST0: CPU1.AH6 R1658.2 R1664.2
APU_TEST1: CPU1.AK8 R1665.2 R1690.2
APU_TEST2: CPU1.AE3 R1666.2 R1691.2
APU_TEST4: CPU1.P24 TP176.1
APU_TEST5: CPU1.N24 TP177.1
APU_TEST6: CPU1.AN24 TP178.1
APU_TEST9: CPU1.AB8 TP179.1
APU_TEST10: CPU1.Y9 TP180.1
APU_TEST11: CPU1.B11 R1607.1
APU_TEST14: CPU1.B10 R1604.1
APU_TEST15: CPU1.D11 TP181.1
APU_TEST16: CPU1.A10 R1605.1
APU_TEST17: CPU1.C11 R1606.1
APU_TEST28_H: CPU1.A13 TP182.1
APU_TEST28_L: CPU1.B13 TP183.1
APU_TEST31: CPU1.P26 TP184.1
APU_TEST37: CPU1.A17 R545.1 R1610.1
APU_TEST410: CPU1.AK24 TP37.1
APU_TEST411: CPU1.AL24 TP175.1
APU_TMS: CPU1.G15 HDT1.4 RN12.3(A)
APU_TRST: C1870.2 CPU1.J14 R1743.2 RN12.4(A)
APU_VDD_33_18_SEL: R93.1 R1614.1 R1615.1 R1616.1 R2022.1 R2025.1
APU_VDDIO_AZ: C395.1 C1638.1 C1639.1 CPU1.AR19 R1595.2 R1601.1
APU_VRM_PWRGD: PR4624.2 PU4601.7
AUD_BEEP_C: C130.2 U6.2
AUD_BEEP_R: C130.1 R207.2 R208.2 R210.1
AUD_DMIC_CLK: C121.2 L54.2 WEBCM1.4
AUD_DMIC_CLK_R: R212.1 U6.12
AUD_DMIC_CLK_R_1: L54.1 R212.2
AUD_DMIC_DATA: C132.2 R222.1 WEBCM1.5
AUD_DMIC_DATA_R: R222.2 U6.13
AUD_DVDD: C127.1 C131.1 R205.2 R206.2 R79649.2 U6.7
AUD_GP3: R213.2 U6.3
AUD_LINK_BCLK: C126.2 R79684.1 U6.5
AUD_LINK_RST_N: C61.1 R314.1 R79682.1 U6.6
AUD_LINK_RST_N_2: Q63.4 Q63.6
AUD_LINK_RST_N_R: C170.1 Q31.B R314.2
AUD_LINK_SDIN: CPU1.AR8 R209.1 R79678.2
AUD_LINK_SDIN_1: R209.2 U6.8
AUD_LINK_SDO: C1780.2 Q56.D R618.2 R79685.1
AUD_LINK_SDO_1: C1780.1 Q56.G R617.2
AUD_LINK_SDO_N: Q56.S R618.1 U6.4
AUD_LINK_SYNC: R79683.1 U6.9
AUD_REGREF: C129.1 U6.10
AZ_BCLK_M: CPU1.AU6 R79681.2 R79684.2
AZ_RST_N_M: CPU1.AU9 R79682.2
AZ_SDIN1: CPU1.AP6 R79679.2
AZ_SDIN2: CPU1.AR5 R79680.2
AZ_SDOUT_M: CPU1.AR7 R79685.2
AZ_SYNC_M: CPU1.AT9 R79683.2
BAT_ALERT: BAT2.8B R79648.2
BAT_IN#: R2014.1 R80210.1 RN4301.4(A) U4101.5
BAT_IN#_1: BAT2.6B PC4304.1 PL4301.1 RN4301.5(B)
BAT_IN#_ECIO: R80210.2 U109.98
BATA_SCL_1: BAT2.4B PC4305.1 PL4302.1 RN4301.7(B)
BATA_SDA_1: BAT2.5B PC4301.1 PL4303.1 RN4301.6(B)
BATT_AMBER_LED#: R79710.2 U4101.9
BATT_AMBER_LED#_C: PWRCN1.10 R389.2 R79710.1
BATT_WHITE_LED#: R79711.2 U4101.58
BATT_WHITE_LED#_C: PWRCN1.8 Q38.C Q1214.C R79711.1 R79726.2
BIST_DISABLE: R531.2 R533.1 R536.1 U109.112
BIST_DISABLE_1: Q12.5 R536.2
BIST_EN: Q12.3 Q12.6 Q13.2 R524.2
BIST_EN_INV: Q13.3 Q13.6 R513.1 R517.2 R80232.2 U26.2
BIST_EN_SIO: R1826.1 R80232.1 U109.25
BIST_ENABLE: R515.1 U109.113
BIST_ENABLE_1: Q13.5 R514.2 R515.2 R523.1
BIST_PIN25: Q9650.G R682.2 U109.24
BKLT_ADJ: C33.1 C87.1 R133.2 R79621.2
BKLT_EN: C88.1 Q22.C R138.2 R139.2 R79625.2
BKLT_EN1: Q22.B R135.2
BOARD1: CPU1.BB9 R1661.2 R1663.1
BOARD2: CPU1.AW15 R152.1 R1662.2
BOARD3: CPU1.AU15 R1659.2 R1660.1
BQ24737_CSON_1: PC5236.2 PC5238.1 PG4908.1 PR5277.2
BQ24737_CSOP_1: PC5236.1 PG4906.1 PR5283.2
BQ24737_REGN: PC5233.2 PD4401.A PR5297.1 U55.16
BT+: BAT2.1B BAT2.2B BAT2.3B PC4302.1 PC4303.1 PC4401.1 PC5240.1 PC5241.1 PC5242.1 PG4908.2 PR5269.2 PU5205.5 PU5205.6 PU5205.7 PU5205.8
BT+_R: PG4906.2 PL5003.2 PR5269.1
BUFFER1_M4: Q51.G Q52.C R526.1
BUZZER_SPKR_R: C203.1 R207.1
C_GPP_TXN3: C41.1 CPU1.N3
C_GPP_TXP3: C42.1 CPU1.N4
CAGND: C4.1 C5.2 C8.2 C10.2 C43.2 C3455.2 C3456.2 C3457.2 C3458.2 R37.2 R61.2 R82.2 R79623.2 R79627.2 R79628.2 U120.15 U120.21
CBN: C150.2 U6.21
CBP: C150.1 U6.24
CFG: R1594.2 U118.23
CHG_AGND: PC4403.2 PC4404.2 PC4408.2 PC5232.2 PC5238.2 PC5239.2 PQ5006.1 PQ5006.4 PR4412.2 PR5268.2 PR5274.2 PR5468.2
CHG_ON#: PQ5003.G PR5273.2 R80207.1 U4101.17
CHG_ON#_ECIO: R80207.2 U109.101
CHG_SMB2_CLK: PR4425.2 R715.1 RN4301.2(A) U55.9 U4101.35
CHG_SMB2_DATA: PR4426.2 R716.1 RN4301.3(A) U55.8 U4101.34
CK_48M_SIO: C1733.2 R310.2 R1645.1 R2067.2
CK_GLAN_DN: CPU1.U2 U16.16
CK_GLAN_DP: CPU1.U1 U16.15
CK_M_DDR0_A_DN: CPU1.AE32 DIMM1.103
CK_M_DDR0_A_DP: CPU1.AE33 DIMM1.101
CK_M_DDR0_B_DN: CPU1.AD33 DIMM2.103
CK_M_DDR0_B_DP: CPU1.AD32 DIMM2.101
CK_M_DDR1_A_DN: CPU1.AE31 DIMM1.104
CK_M_DDR1_A_DP: CPU1.AE30 DIMM1.102
CK_M_DDR1_B_DN: CPU1.AC32 DIMM2.104
CK_M_DDR1_B_DP: CPU1.AC33 DIMM2.102
CK_P_33M_EC: R79699.1 U4101.2
CK_P_33M_SIO: C1734.1 R1646.1 R1867.1 R1868.2 R1877.2 R79699.2 U109.44
CK_PCIEX1_WLAN_DN: CPU1.W3 R23.2
CK_PCIEX1_WLAN_DP: CPU1.W4 R22.2
CK_PE_100M_16PORT_DN: CPU1.U3 TP5002.1
CK_PE_100M_16PORT_DP: CPU1.U4 TP5001.1
CLINK_CLK_LAN: NGFF1.42 TP67.1
CLINK_DATA_LAN: NGFF1.40 TP66.1
CLINK_RST_LAN_N: NGFF1.38 TP65.1
CLK_48M_SIO_C: R310.1 U109.34
COMP_OUT1: R4708.1 R79725.1 U178.1 U178.6
COMP_OUT2: R4707.1 U178.7
COMPNB_R: PC4611.1 PR4623.2
CORETYPE: CPU1.K24 TP213.1
CPU_BST1_SW1: PC4704.1 PR4701.2
CPU_BST2_SW2: PC4710.1 PR4703.2
CPU_FAN_CTRL_SIO: R68.1 U109.6
CPU_FAN_TACH_SIO: R74.1 U109.5
CPU_VCORE: C330.1 C1644.1 C1645.1 C1646.1 C1647.1 C1648.1 C1649.1 C1650.1 C1651.1 C1652.1 C1657.1 C1658.1 C1659.1 C1660.1 C1661.1 C1662.1 C1663.1 C1664.1 CPU1.AB7 CPU1.AB9 CPU1.AB12 CPU1.AB15 CPU1.AB18 CPU1.AB21 CPU1.AD6 CPU1.AD10 CPU1.AD13 CPU1.AD16 CPU1.AD19 CPU1.AD22 CPU1.AE7 CPU1.AE12 CPU1.AE15 CPU1.AE18 CPU1.AE21 CPU1.AG6 CPU1.AG10 CPU1.AG13 CPU1.AG16 CPU1.AG19 CPU1.AG22 CPU1.AH7 CPU1.AH12 CPU1.AH15 CPU1.AH18 CPU1.AH21 CPU1.AK6 CPU1.AK9 CPU1.AK10 CPU1.AK13 CPU1.AK16 CPU1.AK19 CPU1.AK22 CPU1.AL7 CPU1.AN6 CPU1.U8 CPU1.W7 CPU1.W12 CPU1.W15 CPU1.W18 CPU1.W21 CPU1.Y8 CPU1.Y10 CPU1.Y13 CPU1.Y16 CPU1.Y19 CPU1.Y22 G5.1 PG4702.1 PL4701.2 PR4628.1 PT4702.1 PT4708.1 PT4709.1
CPVEE: C1491.1 U6.20
D2_M: D23.2 R1672.1
DC_19V: C258.1 PC5235.2 PR4431.1 PR5270.1 PR5282.1 PR5284.1 PR5285.1 PU5204.5 PU5204.6 PU5204.7 PU5204.8 PU5205.4 R1848.1 R79643.1 R79644.1 R79645.1 R79646.1 R79656.1 U110.5 U110.6 U110.7 U110.8
DC_IN_D: PQ5005.3 PR5282.2
DCBATOUT: C32.1 C6718.1 C6719.1 C6720.1 F16.1 L10.1 PC4405.1 PC4406.1 PC4407.1 PC4701.1 PC4702.1 PC4703.1 PC4705.1 PC4707.1 PC4708.1 PC4709.1 PC4711.1 PC4903.1 PC5019.1 PC5020.1 PC5021.1 PC5022.1 PC5235.1 PC5401.1 PC5402.1 PC5403.1 PC5404.1 PG4905.1 PG5205.1 PG5210.1 PR4458.1 PR4616.1 PR4814.1 PR4815.1 PR4901.1 PR4927.1 PR4929.1 PR4930.1 PR4931.1 PR4932.1 PR4933.1 PR5007.1 PR5276.2 PR5424.1 PT4701.1 PT4712.1 PT5405.1 PU4403.5 PU4403.6 PU4403.7 PU4403.8 PU4702.5 PU4702.6 PU4702.7 PU4702.8 PU4901.11 PU5006.5 PU5006.6 PU5006.7 PU5006.8 PU5205.1 PU5205.2 PU5205.3 PU5207.5 PU5207.6 PU5207.7 PU5207.8 PU5401.5 PU5401.6 PU5401.7 PU5401.8 R20.1 R26.1 R171.1 R179.1 R657.1 R733.1 R1777.1 R1778.1 R1780.1 R4702.1 R79631.1
DCIN_EN: R2087.2 U118.13
DDCBUF: R1598.2 R2089.1 U118.14
DDR3_DRAMRST_N: CPU1.T33 R99.1 R2054.1
DDR3_DRAMRST_N_A_1: C1726.1 DIMM1.30 R99.2
DDR3_DRAMRST_N_B_1: C1958.1 DIMM2.30 R2054.2
DDR_VREF_S3: PR5032.1
DIFFNB_R: PC4610.1 PR4622.2
DIMM_APU_VREF: CPU1.T32 R1912.2
DIMM_DQ_APU_VREF_MA: CPU1.B19 R81.2
DIMM_DQ_APU_VREF_MB: CPU1.A19 R1697.2
DIMM_TMPIN2+: C231.2 R397.1 RT1.1 U109.86
DIMM_TMPIN2-: C231.1 R399.2 RT1.2
DP0_AUXN: C305.1 CPU1.E8 R1074.2
DP0_AUXP: C304.1 CPU1.F8 R1079.1
DP0_HPD: CPU1.G8 R510.2 R512.1 R530.1
DP0_TXN0: C301.1 CPU1.E1
DP0_TXN1: C303.1 CPU1.E4
DP0_TXP0: C300.1 CPU1.E2
DP0_TXP1: C302.1 CPU1.E3
DP_2K_ZVSS: CPU1.A9 R1603.1
DP_150_ZVSS: CPU1.B9 R107.1
DP_AUXN: NGFF1.20 TP73.1
DP_AUXP: NGFF1.22 TP72.1
DP_HPD: NGFF1.31 TP78.1
DP_ML0N: NGFF1.32 TP69.1
DP_ML0P: NGFF1.34 TP68.1
DP_ML1N: NGFF1.26 TP71.1
DP_ML1P: NGFF1.28 TP70.1
DP_ML2N: NGFF1.25 TP76.1
DP_ML2P: NGFF1.27 TP77.1
DP_ML3N: NGFF1.19 TP74.1
DP_ML3P: NGFF1.21 TP75.1
DP_STEREOSYNC: CPU1.E11 R1618.1 R1619.1
DP_STEREOSYNC_PU: R1618.2 R2023.2 R2026.2
DPLVDS_AUXN: C305.2 U26.3
DPLVDS_AUXP: C304.2 U26.4
DPLVDS_BL_EN: R1985.2 R79686.1 U26.44
DPLVDS_EDIDCLK: C1827.1 R32.2 R35.2 U26.46
DPLVDS_EDIDCLK_C: R35.1 U25.6
DPLVDS_EDIDSDA: C7.1 R46.2 R1858.2 U26.45
DPLVDS_EDIDSDA_C: R1858.1 U25.5
DPLVDS_FWCLK: C9.1 R47.2 U26.48
DPLVDS_FWSDA: C11.1 R58.2 U26.47
DPLVDS_HPD: R510.1 U26.1
DPLVDS_ISPCLK: Q7.1 Q95.4 R69.2 U26.13
DPLVDS_ISPDAT: Q4.1 Q95.1 R54.2 U26.14
DPLVDS_PANEL_VCC: R39.2 U26.20
DPLVDS_PIN12: R511.1 U26.12
DPLVDS_PIN16: R507.2 U26.16
DPLVDS_PWMIN: R501.1 R502.1 R503.2 U26.21
DPLVDS_PWMOUT: R1984.2 U26.19
DRX0N: C301.2 U26.8
DRX0P: C300.2 U26.7
DRX1N: C303.2 U26.10
DRX1P: C302.2 U26.9
EAPD_DEPOP: R635.1 U6.14
EAPD_DEPOP_1: R634.1 R635.2 R636.1
EAPD_DEPOP_2: Q63.2 R636.2
EC_3P3_CTL: C6724.2 PR8521.2 Q9648.G
EC_3P3_CTL_2: C6725.1 Q9649.G R80229.2
EC_3P3_CTL_3: Q9648.D R80228.1 R80229.1
EC_A20GATE: R80231.1 U109.43
EC_EUP: R674.1 R675.1 U109.127
EC_EUP_EN: C542.1 Q1227.G R674.2 R1199.2
EC_HDMI_PD_N: Q1249.G R2091.2 U109.105
EC_IMS: R79691.2 U109.52
EC_LAN_DISABLE_N: R1194.1 R1840.1 U109.58
EC_PSID: R80213.2 U4101.12
EC_PWREN: PR8521.1 R702.2 R1834.1 U109.57
EC_SCI: R79709.1 U4101.15
EC_SMB2_CLK: PR8519.2 R80220.1 U4101.32
EC_SMB2_DATA: PR8520.2 R80219.1 U4101.33
EC_VCORF: C4101.2 U4101.20
ECIO_APU_PROCHOT#: R80226.2 U109.8
ECIO_IO_SMI_N: R80223.2 U109.9
ECIO_LPC_PME_N: R80224.1 U109.70
EGPIO67: CPU1.AT17 R79653.1
EGPIO70: CPU1.AT12 R79654.1
EGPIO119: CPU1.AW7 TP8.1
EGPIO131: CPU1.BB18 R79670.1
EGPIO132: CPU1.BB16 R79635.1
EGPIO145: CPU1.BB10 R79652.1
EMMC_CLK: R90004.1 R90037.1
EMMC_CLK_C: R90037.2 U902.G10
EMMC_CLK_M: R90004.2 U903.M6
EMMC_CMD: R90005.1 R90013.1 R90038.1
EMMC_CMD_C: R90038.2 U902.H10
EMMC_CMD_M: R90005.2 U903.M5
EMMC_D0: R90033.2 U902.F10
EMMC_D1: R90034.2 U902.F9
EMMC_D2: R90035.2 U902.G9
EMMC_D3: R90036.2 U902.H9
EMMC_D4: R90042.2 U902.J10
EMMC_D5: R90043.2 U902.J9
EMMC_D6: R90044.2 U902.G8
EMMC_D7: R90045.2 U902.H8
EMMC_DATA_0: R90014.1 R90033.1 U903.A3
EMMC_DATA_1: R90015.1 R90034.1 U903.A4
EMMC_DATA_2: R90016.1 R90035.1 U903.A5
EMMC_DATA_3: R90017.1 R90036.1 U903.B2
EMMC_DATA_4: R90018.1 R90042.1 U903.B3
EMMC_DATA_5: R90019.1 R90043.1 U903.B4
EMMC_DATA_6: R90020.1 R90044.1 U903.B5
EMMC_DATA_7: R90021.1 R90045.1 U903.B6
EMMC_E9: TP5014.1 U903.E9
EMMC_E10: TP5015.1 U903.E10
EMMC_F10: TP5016.1 U903.F10
EMMC_K10: TP5017.1 U903.K10
EMMC_RCLK: R90006.1 TP5013.1
EMMC_RCLK_M: R90006.2 R90012.1 U903.H5
EMMC_RESET#: C9036.1 Q90002.D R90007.1 R90067.2
EMMC_RESET#_1: C9041.1 Q90001.D Q90002.G R90066.1
EMMC_RESET#_M: R90007.2 U903.K5
EMMC_RESET_SIO: Q90001.G RN13.3(A)
EMMC_REXT: R90039.2 U902.E8
EMMC_VCC: C9032.1 C9034.1 R90001.2 U903.E6 U903.F5 U903.J10 U903.K9
EMMC_VCC1N: R90040.2 U902.H7
EMMC_VCC2N: R90041.2 U902.J8
EMMC_VCCQ: C9031.1 C9035.1 R90002.2 U903.C6 U903.M4 U903.N4 U903.P3 U903.P5
EMMC_VDDI: C9006.2 U903.C2
EQ: R1593.2 R2085.1 U118.17
EVAL_PE_L: CPU1.AR14 TP5003.1
EVAL_PWREN: CPU1.BC13 TP5004.1
EVAL_PWRGD: CPU1.BC17 R79694.1
EXT_RST#: R79705.1 R79706.2 U4101.41
F_USB0N: C6729.1 CPU1.AR1 TR10.1
F_USB0P: C6728.1 CPU1.AR2 TR10.4
F_USB1N: C6726.1 CPU1.AR4 TR14.1
F_USB1P: C6727.1 CPU1.AR3 TR14.4
F_USB3N: CPU1.AN4 TR9.4
F_USB3P: CPU1.AN3 TR9.1
F_USB4N: CPU1.AM2 TR1.1
F_USB4P: CPU1.AM1 TR1.4
F_USB5N: CPU1.AL1 TR12.4
F_USB5P: CPU1.AL2 TR12.1
F_USB6N: CPU1.AL4 TR3.4
F_USB6P: CPU1.AL3 TR3.1
F_USB7N: CPU1.AJ2 TR4.4
F_USB7P: CPU1.AK2 TR4.1
FALL_INT2: Q6701.2 Q6701.3 R6703.2
FCH_0.775_S5: C1953.1 C1954.1 C1956.1 C6712.1 C6714.1 C6715.1 CPU1.AP13 CPU1.AR12 Q6703.5 Q6703.6 Q6704.5 Q6704.6
FCH_S5_POWER_COMP: Q4701.1 R4706.1 R79724.1 R79725.2 U178.2 U178.5
FFS_INT1: CPU1.AJ1 R6702.2 R79658.2 U109.110
FFS_INT1_C: R79658.1 U6701.11
FFS_INT2_APU: CPU1.AK5 R79657.2
FFS_INT2_C: Q6701.5 R6704.2 R6706.1 R79657.1 R79668.1 U6701.9
FFS_INT2_Q: Q6701.6 R6705.2 R6706.2 SATAP1.5
FP_RST_N: C1735.1 CPU1.AF2 R1679.1 R2004.1 R2012.2
FWH_ID0: LPC1.6 R1700.2
GFX_SVC: CPU1.B16 R1994.1 R1998.1
GFX_SVD: CPU1.A18 R1995.1 R2000.1
GFX_SVT: CPU1.B15 R1993.1 R2002.1
GFX_VCORE: C1934.1 C1935.1 C1936.1 C1937.1 C1938.1 C1939.1 C1940.1 C1941.1 C1942.1 C1943.1 C1944.1 C1945.1 C1946.1 C1947.1 C1948.1 C1949.1 C1950.1 C1951.1 C1952.1 CPU1.F12 CPU1.F15 CPU1.G11 CPU1.G14 CPU1.J8 CPU1.J9 CPU1.J11 CPU1.K7 CPU1.K12 CPU1.K13 CPU1.K15 CPU1.K16 CPU1.K19 CPU1.L8 CPU1.L13 CPU1.L16 CPU1.L19 CPU1.L22 CPU1.N7 CPU1.N12 CPU1.N15 CPU1.N18 CPU1.N21 CPU1.P8 CPU1.P13 CPU1.P16 CPU1.P19 CPU1.P22 CPU1.T7 CPU1.T12 CPU1.T15 CPU1.T18 CPU1.T21 CPU1.U13 CPU1.U16 CPU1.U19 CPU1.U22 PG5402.1 PL5401.2 PR5410.1 PT5401.1 PT5402.1 PT5403.1
GFX_VRM_PWRGD: PR5463.2 PU5407.7
GP11: R679.1 U109.31
GP14: R90068.1 U109.28
GP24: R297.1 U109.20
GP26: R1188.1 U109.18
GP27: R1864.1 U109.17
GP32: R307.2 U109.14
GP33: R80222.1 U109.13
GP34: R80221.1 U109.12
GP63: R1863.1 U109.3
GPU_DMINUS: C524.2 R651.2 RT2.2
GPU_DPLUS: C524.1 R658.1 RT2.1 U109.85
HDMI1_CLK_APU: CPU1.F7 R79639.2
HDMI1_CLK_APU_SRC: R79639.1 U118.38
HDMI1_CLK_CON: HDMI1.15 HDMI2.5 R2083.2 U117.1 U117.10 U118.32
HDMI1_DATA_APU: CPU1.E7 R79640.2
HDMI1_DATA_APU_N0: C3371.1 CPU1.A3
HDMI1_DATA_APU_N1: C3372.1 CPU1.A4
HDMI1_DATA_APU_N2: C3373.1 CPU1.C5
HDMI1_DATA_APU_N3: C3374.1 CPU1.B5
HDMI1_DATA_APU_P0: C3368.1 CPU1.A2
HDMI1_DATA_APU_P1: C3370.1 CPU1.B4
HDMI1_DATA_APU_P2: C3369.1 CPU1.D5
HDMI1_DATA_APU_P3: C3375.1 CPU1.A5
HDMI1_DATA_APU_SRC: R79640.1 U118.39
HDMI1_DATA_CON: HDMI1.16 HDMI2.4 R2084.2 U117.2 U117.9 U118.33
HDMI1_DATA_CON_N0: HDMI1.3 HDMI2.17 TR16.2 U116.2 U116.9
HDMI1_DATA_CON_N1: HDMI1.6 HDMI2.14 TR17.2 U116.5 U116.6
HDMI1_DATA_CON_N2: HDMI1.9 HDMI2.11 TR18.2 U31.4 U31.7
HDMI1_DATA_CON_N3: HDMI1.12 HDMI2.8 TR19.2 U31.1 U31.10
HDMI1_DATA_CON_P0: HDMI1.1 HDMI2.19 TR16.3 U116.1 U116.10
HDMI1_DATA_CON_P1: HDMI1.4 HDMI2.16 TR17.3 U116.4 U116.7
HDMI1_DATA_CON_P2: HDMI1.7 HDMI2.13 TR18.3 U31.5 U31.6
HDMI1_DATA_CON_P3: HDMI1.10 HDMI2.10 TR19.3 U31.2 U31.9
HDMI1_DATA_IC_N0: C3371.2 U118.2
HDMI1_DATA_IC_N1: C3372.2 U118.5
HDMI1_DATA_IC_N2: C3373.2 U118.7
HDMI1_DATA_IC_N3: C3374.2 U118.10
HDMI1_DATA_IC_P0: C3368.2 U118.1
HDMI1_DATA_IC_P1: C3370.2 U118.4
HDMI1_DATA_IC_P2: C3369.2 U118.6
HDMI1_DATA_IC_P3: C3375.2 U118.9
HDMI1_DET_APU: CPU1.F5 U118.3
HDMI1_DET_CON: HDMI1.19 HDMI2.1 U117.4 U117.7 U118.28
HDMI_LANE0_IC_DN: TR16.1 U118.29
HDMI_LANE0_IC_DP: TR16.4 U118.30
HDMI_LANE1_IC_DN: TR17.1 U118.26
HDMI_LANE1_IC_DP: TR17.4 U118.27
HDMI_LANE2_IC_DN: TR18.1 U118.24
HDMI_LANE2_IC_DP: TR18.4 U118.25
HDMI_LANE3_IC_DN: TR19.1 U118.21
HDMI_LANE3_IC_DP: TR19.4 U118.22
HDT_C_M1: HDT1.11 R1702.1
HDT_C_M2: HDT1.13 R1703.1
HDT_C_M3: HDT1.15 R1705.1
HDT_PW_M3: Q50.1 R1701.2
HDT_PW_M4: Q50.3 Q1210.G R504.2
HDT_RST0: HDT1.18 R1747.1
HDT_RST1: HDT1.20 R1748.1
HDT_TRST: HDT1.9 R1743.1
HDT_VDDIO_SUS: HDT1.1 HDT1.19 Q1210.D R1698.2 R1704.1 RN12.5(B) RN12.6(B) RN12.7(B) RN12.8(B)
HM_VCCP: G5.2 R1832.1
HM_VCCP_R: C558.2 R1832.2 U109.95
HPOL_CON: C134.1 Q57.1 R220.2 R221.1 R223.2 R225.2 UHS1.1
HPOR_CON: C159.1 Q57.2 R262.2 R281.1 R284.2 R627.2 UHS1.2
HPOUT-JD: R267.1 UHS1.6
HPOUT-L: R220.1 U6.26
HPOUT-R: R284.1 U6.27
HSI_C_DN3: CPU1.P6 R1712.2
HSI_C_DP3: CPU1.P7 R1711.2
HSI_LAN_DN1: C1808.2 CPU1.T5
HSI_LAN_DN1_R: C1808.1 U16.18
HSI_LAN_DP1: C1805.2 CPU1.T6
HSI_LAN_DP1_R: C1805.1 U16.17
HSO_C_BLAN_DN1: C45.1 CPU1.R3
HSO_C_BLAN_DP1: C44.1 CPU1.R4
HSO_C_DN3: C41.2 R1714.2
HSO_C_DP3: C42.2 R1713.2
HSO_C_LAN_DN1: C45.2 U16.14
HSO_C_LAN_DP1: C44.2 U16.13
ICH_RSMRST_N_R: R374.2 U109.82
ILIM_R: PR4619.2 PR4620.1 PR4637.2
ILIMNB_R: PR4639.2 PR4640.2 PR4644.1
IMS: LVDS1.4 R79659.1 R79661.2 R79691.1
INIT_3V: LPC1.2 R1699.2
IO_SMI_N: CPU1.BB13 R313.2 R80223.1 U4101.13
ISEN1: R51.2 U120.17
ISEN2: R53.2 U120.16
ISEN3: R56.2 U120.14
ISEN4: R59.2 U120.13
ISET: R1596.2 R2086.1 U118.34
ISP_CLK1: Q7.3 Q7.6 R1860.2
ISP_DAT1: Q4.3 Q4.6 R57.2
ISW: C10.1 R79630.2 U120.19
ISW_1: Q1250.1 Q1250.2 Q1250.3 R27.1 R79622.1 R79630.1
JACK_PSID: DCIN1.3 DCIN2.4 DCIN2.11 L15.1
JDREF: R268.1 U6.35
JENK#: TP4125.1 U4101.28
KBCLK: RN10.3(A) U109.78
KBRST_N: CPU1.AY15 R1845.1 U109.42
KDAT: RN10.4(A) U109.77
LAD0_FWH0: CPU1.BB11 LPC1.5 R79703.2 RN7.4(A) U109.38
LAD0_FWH0_EC: R79703.1 U4101.62
LAD1_FWH1: CPU1.BA11 LPC1.7 R79702.2 RN7.3(A) U109.39
LAD1_FWH1_EC: R79702.1 U4101.63
LAD2_FWH2: CPU1.AY11 LPC1.9 R79701.2 RN7.2(A) U109.40
LAD2_FWH2_EC: R79701.1 U4101.64
LAD3_FWH3: CPU1.BA13 LPC1.11 R79700.2 RN7.1(A) U109.41
LAD3_FWH3_EC: R79700.1 U4101.1
LAN_DISABLE_N: CPU1.AH2 R774.1 R777.2 R1670.1
LAN_DISABLE_N_1: C591.1 Q102.B R774.2 R1180.1
LAN_DISABLE_N_2: Q101.B Q102.C R764.1 R1180.2
LAN_DISABLE_N_3: Q100.C Q101.C R775.2 R776.1
LAN_DISABLE_N_4: C593.1 PC140.2 Q44.G R776.2
LAN_DISABLE_V3: C863.1 Q100.B R1183.1 R1194.2
LAN_LEDACT_R#: RJ1.10 UR5.2
LAN_MDI0_C_DN: RJ1.2 XF1.2
LAN_MDI0_C_DP: RJ1.1 XF1.1
LAN_MDI0_DN: U10.3 U16.2 XF1.11
LAN_MDI0_DP: U10.4 U16.1 XF1.12
LAN_MDI1_C_DN: RJ1.6 XF1.6
LAN_MDI1_C_DP: RJ1.3 XF1.5
LAN_MDI1_DN: U10.1 U16.5 XF1.7
LAN_MDI1_DP: U10.6 U16.4 XF1.8
LAN_MDI2_C_DN: RJ1.5 XF2.5
LAN_MDI2_C_DP: RJ1.4 XF2.6
LAN_MDI2_DN: PR5250.2 U11.3 XF2.8
LAN_MDI2_DN_R: PR5250.1 U16.7
LAN_MDI2_DP: PR5249.2 U11.4 XF2.7
LAN_MDI2_DP_R: PR5249.1 U16.6
LAN_MDI3_C_DN: RJ1.8 XF2.1
LAN_MDI3_C_DP: RJ1.7 XF2.2
LAN_MDI3_DN: PR5248.2 U11.1 XF2.12
LAN_MDI3_DN_R: PR5248.1 U16.10
LAN_MDI3_DP: PR5247.2 U11.6 XF2.11
LAN_MDI3_DP_R: PR5247.1 U16.9
LAN_RSET: R412.2 U16.31
LAN_XTALI: C1800.1 R407.2 U16.28 X4.1
LAN_XTALO: C1799.1 R407.1 U16.29 X4.3
LANCLK_REQ_N: CPU1.BC15 R413.2 R1674.1
LANCLK_REQ_U_N: R413.1 U16.12
LDO_VDD33_18: C9015.1 C9016.1 U902.F8 U902.K2
LDR: R65.2 U120.1
LDR_1: Q1250.4 R65.1
LDRQ#: CPU1.BA1 R316.1 R79704.2 U109.2
LDRQ#_EC: R79704.1 U4101.61
LDT_RST: C1721.2 CPU1.D15 R1617.2 R1745.2
LDT_RST#_BUF: HDT1.12 R1745.1
LED_5VSB: LED2.A R1767.2
LEDC_ISET: R82.1 U120.12
LFRAMEJ_FW4: CPU1.AV14 LPC1.13 R1871.1 R1872.2 R1875.2 R79698.2 U109.37
LFRAMEJ_FW4_EC: R79698.1 U4101.3
LINE2-VREFO: R261.1 R272.1 U6.29
LINEOUT-JD: LOUT1.Q R266.1
LINEOUT-L: R429.1 U6.19
LINEOUT-R: R428.1 U6.18
LINEOUT_C-L: L62.1 R429.2
LINEOUT_C-R: L20.1 R428.2
LINEOUT_CON-L: C268.1 L62.2 LOUT1.4 Q46.1
LINEOUT_CON-R: C267.1 L20.2 LOUT1.1 Q46.2
LINK_ACTIVITY_N: U12.4 U16.27 UR5.1
LINK_PWR: R79618.2 RJ1.9
LPC_CLK0_R: CPU1.AW14 R1646.2
LPC_CLK1: C66.1 LPC1.1 R123.1 R1869.1 R1870.2 R1876.2
LPC_CLK1_R: CPU1.AY13 R123.2
LPC_PD_N: CPU1.AE9 TP9.1
LPC_PME_N: R568.1 R1843.2 R79709.2 R80224.2
LPC_TPM: CPU1.AW12 TP187.1
LPF: C3455.1 U120.9
LVDS_BL_ADJ: R131.1 R132.1 R133.1 R134.2 R1984.1
LVDS_BL_EN_1: R79686.2 U109.54
LVDS_DET_A*: LVDS1.17 R482.2 U109.116
LVDS_DET_B*: Q103.D R483.2 U109.117
LVDS_DET_B_C*: C869.1 LVDS1.1 Q103.G
LVDS_PU_5: LVDS1.5 R1163.2
LVDS_PU_5_1: Q9647.D R484.1
LVDS_PU_5_2: Q9647.G Q9650.D R80233.1
LVDS_PU_6: LVDS1.6 R484.2
LVDS_PU_24: LVDS1.24 R481.2
LX: D32.A L61.2 Q1250.5 Q1250.6 Q1250.7 Q1250.8 R79619.1
M1_SMB_CLK: NGFF1.60 R14.2
M1_SMB_DATA: NGFF1.58 R1622.2
M_CAS_A_N: CPU1.AK32 DIMM1.115 DIMM2.115
M_DATA_A0: CPU1.A25 DIMM1.5 DIMM2.5
M_DATA_A1: CPU1.C25 DIMM1.7 DIMM2.7
M_DATA_A2: CPU1.C27 DIMM1.15 DIMM2.15
M_DATA_A3: CPU1.D27 DIMM1.17 DIMM2.17
M_DATA_A4: CPU1.B24 DIMM1.4 DIMM2.4
M_DATA_A5: CPU1.B25 DIMM1.6 DIMM2.6
M_DATA_A6: CPU1.B27 DIMM1.16 DIMM2.16
M_DATA_A7: CPU1.A27 DIMM1.18 DIMM2.18
M_DATA_A8: CPU1.A29 DIMM1.21 DIMM2.21
M_DATA_A9: CPU1.C29 DIMM1.23 DIMM2.23
M_DATA_A10: CPU1.B32 DIMM1.33 DIMM2.33
M_DATA_A11: CPU1.D32 DIMM1.35 DIMM2.35
M_DATA_A12: CPU1.B28 DIMM1.22 DIMM2.22
M_DATA_A13: CPU1.B29 DIMM1.24 DIMM2.24
M_DATA_A14: CPU1.A31 DIMM1.34 DIMM2.34
M_DATA_A15: CPU1.C31 DIMM1.36 DIMM2.36
M_DATA_A16: CPU1.E30 DIMM1.39 DIMM2.39
M_DATA_A17: CPU1.E31 DIMM1.41 DIMM2.41
M_DATA_A18: CPU1.G33 DIMM1.51 DIMM2.51
M_DATA_A19: CPU1.G32 DIMM1.53 DIMM2.53
M_DATA_A20: CPU1.C33 DIMM1.40 DIMM2.40
M_DATA_A21: CPU1.D33 DIMM1.42 DIMM2.42
M_DATA_A22: CPU1.G30 DIMM1.50 DIMM2.50
M_DATA_A23: CPU1.G31 DIMM1.52 DIMM2.52
M_DATA_A24: CPU1.J30 DIMM1.57 DIMM2.57
M_DATA_A25: CPU1.J31 DIMM1.59 DIMM2.59
M_DATA_A26: CPU1.L33 DIMM1.67 DIMM2.67
M_DATA_A27: CPU1.L32 DIMM1.69 DIMM2.69
M_DATA_A28: CPU1.H32 DIMM1.56 DIMM2.56
M_DATA_A29: CPU1.H33 DIMM1.58 DIMM2.58
M_DATA_A30: CPU1.L30 DIMM1.68 DIMM2.68
M_DATA_A31: CPU1.L31 DIMM1.70 DIMM2.70
M_DATA_A32: CPU1.AN31 DIMM1.129 DIMM2.129
M_DATA_A33: CPU1.AP32 DIMM1.131 DIMM2.131
M_DATA_A34: CPU1.AT32 DIMM1.141 DIMM2.141
M_DATA_A35: CPU1.AU32 DIMM1.143 DIMM2.143
M_DATA_A36: CPU1.AN33 DIMM1.130 DIMM2.130
M_DATA_A37: CPU1.AN32 DIMM1.132 DIMM2.132
M_DATA_A38: CPU1.AR31 DIMM1.140 DIMM2.140
M_DATA_A39: CPU1.AT33 DIMM1.142 DIMM2.142
M_DATA_A40: CPU1.AU30 DIMM1.147 DIMM2.147
M_DATA_A41: CPU1.AV32 DIMM1.149 DIMM2.149
M_DATA_A42: CPU1.BA33 DIMM1.157 DIMM2.157
M_DATA_A43: CPU1.AY32 DIMM1.159 DIMM2.159
M_DATA_A44: CPU1.AU33 DIMM1.146 DIMM2.146
M_DATA_A45: CPU1.AU31 DIMM1.148 DIMM2.148
M_DATA_A46: CPU1.AW31 DIMM1.158 DIMM2.158
M_DATA_A47: CPU1.AY33 DIMM1.160 DIMM2.160
M_DATA_A48: CPU1.BC31 DIMM1.163 DIMM2.163
M_DATA_A49: CPU1.BB30 DIMM1.165 DIMM2.165
M_DATA_A50: CPU1.BB28 DIMM1.175 DIMM2.175
M_DATA_A51: CPU1.AY27 DIMM1.177 DIMM2.177
M_DATA_A52: CPU1.BB32 DIMM1.164 DIMM2.164
M_DATA_A53: CPU1.BA31 DIMM1.166 DIMM2.166
M_DATA_A54: CPU1.BC29 DIMM1.174 DIMM2.174
M_DATA_A55: CPU1.BB29 DIMM1.176 DIMM2.176
M_DATA_A56: CPU1.BB27 DIMM1.181 DIMM2.181
M_DATA_A57: CPU1.BB26 DIMM1.183 DIMM2.183
M_DATA_A58: CPU1.BB24 DIMM1.191 DIMM2.191
M_DATA_A59: CPU1.AY23 DIMM1.193 DIMM2.193
M_DATA_A60: CPU1.BA27 DIMM1.180 DIMM2.180
M_DATA_A61: CPU1.BC27 DIMM1.182 DIMM2.182
M_DATA_A62: CPU1.BC25 DIMM1.192 DIMM2.192
M_DATA_A63: CPU1.BB25 DIMM1.194 DIMM2.194
M_DQS_A_DN0: CPU1.A26 DIMM1.10 DIMM2.10
M_DQS_A_DN1: CPU1.A30 DIMM1.27 DIMM2.27
M_DQS_A_DN2: CPU1.E32 DIMM1.45 DIMM2.45
M_DQS_A_DN3: CPU1.J32 DIMM1.62 DIMM2.62
M_DQS_A_DN4: CPU1.AR33 DIMM1.135 DIMM2.135
M_DQS_A_DN5: CPU1.AW33 DIMM1.152 DIMM2.152
M_DQS_A_DN6: CPU1.AY29 DIMM1.169 DIMM2.169
M_DQS_A_DN7: CPU1.AY25 DIMM1.186 DIMM2.186
M_DQS_A_DP0: CPU1.B26 DIMM1.12 DIMM2.12
M_DQS_A_DP1: CPU1.B30 DIMM1.29 DIMM2.29
M_DQS_A_DP2: CPU1.F32 DIMM1.47 DIMM2.47
M_DQS_A_DP3: CPU1.K32 DIMM1.64 DIMM2.64
M_DQS_A_DP4: CPU1.AR32 DIMM1.137 DIMM2.137
M_DQS_A_DP5: CPU1.AW32 DIMM1.154 DIMM2.154
M_DQS_A_DP6: CPU1.BA29 DIMM1.171 DIMM2.171
M_DQS_A_DP7: CPU1.BA25 DIMM1.188 DIMM2.188
M_MA_DM0: CPU1.D25 DIMM1.11 DIMM2.11
M_MA_DM1: CPU1.D29 DIMM1.28 DIMM2.28
M_MA_DM2: CPU1.E33 DIMM1.46 DIMM2.46
M_MA_DM3: CPU1.J33 DIMM1.63 DIMM2.63
M_MA_DM4: CPU1.AR30 DIMM1.136 DIMM2.136
M_MA_DM5: CPU1.AW30 DIMM1.153 DIMM2.153
M_MA_DM6: CPU1.BC30 DIMM1.170 DIMM2.170
M_MA_DM7: CPU1.BC26 DIMM1.187 DIMM2.187
M_MAA_A0: CPU1.AG31 DIMM1.98 DIMM2.98
M_MAA_A1: CPU1.AC30 DIMM1.97 DIMM2.97
M_MAA_A2: CPU1.AC31 DIMM1.96 DIMM2.96
M_MAA_A3: CPU1.AB32 DIMM1.95 DIMM2.95
M_MAA_A4: CPU1.AA32 DIMM1.92 DIMM2.92
M_MAA_A5: CPU1.AA33 DIMM1.91 DIMM2.91
M_MAA_A6: CPU1.AA31 DIMM1.90 DIMM2.90
M_MAA_A7: CPU1.Y33 DIMM1.86 DIMM2.86
M_MAA_A8: CPU1.AA30 DIMM1.89 DIMM2.89
M_MAA_A9: CPU1.W32 DIMM1.85 DIMM2.85
M_MAA_A10: CPU1.AG32 DIMM1.107 DIMM2.107
M_MAA_A11: CPU1.Y32 DIMM1.84 DIMM2.84
M_MAA_A12: CPU1.W33 DIMM1.83 DIMM2.83
M_MAA_A13: CPU1.AL31 DIMM1.119 DIMM2.119
M_MAA_A14: CPU1.W30 DIMM1.80 DIMM2.80
M_MAA_A15: CPU1.V32 DIMM1.78 DIMM2.78
M_ODT_A0: CPU1.AL30 DIMM1.116
M_ODT_A1: CPU1.AM32 DIMM1.120
M_ODT_B0: CPU1.AJ32 DIMM2.116
M_ODT_B1: CPU1.AM33 DIMM2.120
M_RAS_A_N: CPU1.AH33 DIMM1.110 DIMM2.110
M_SBS_A0: CPU1.AH32 DIMM1.109 DIMM2.109
M_SBS_A1: CPU1.AG33 DIMM1.108 DIMM2.108
M_SBS_A2: CPU1.W31 DIMM1.79 DIMM2.79
M_SCKE_A0: CPU1.U32 DIMM1.73 DIMM2.73
M_SCKE_A1: CPU1.U33 DIMM1.74 DIMM2.74
M_SCS_A_N0: CPU1.AJ33 DIMM1.114
M_SCS_A_N1: CPU1.AL32 DIMM1.121
M_SCS_B_N0: CPU1.AJ30 DIMM2.114
M_SCS_B_N1: CPU1.AL33 DIMM2.121
M_WE_A_N: CPU1.AJ31 DIMM1.113 DIMM2.113
MCLK: RN10.1(A) U109.80
MCT_R: R79612.2 RV1.2 XF1.3 XF1.4 XF2.3 XF2.4
MCT_R_1: C3131.1 R79612.1
MDAT: RN10.2(A) U109.79
MEM_MA_EVENT_L: CPU1.AG30 DIMM1.198 DIMM2.198 Q1207.E R1584.2
MEM_MA_ZVDDIO: CPU1.AD29 R1696.1
MEM_MB_ZVDDIO: CPU1.AF32 R121.1
MEM_VREFCA_SUS: C65.2 C1746.2 C1979.2 C1980.2 DIMM1.126 DIMM2.126 R120.2 R122.1 R2059.2 R2060.1
MIC2-L: C139.1 U6.47
MIC2-L-1: C139.2 R225.1
MIC2-R: C138.1 U6.48
MIC2-R-1: C138.2 R627.1
MIC2-VREFO-L: R223.1 U6.1
MIC2-VREFO-R: R262.1 U6.30
MIC-CAP: C154.1 U6.36
MINI_POWER_CTRL: R15.1 RN8.4(B) U109.55
MODEL_ID_DET: R79722.1 R79723.2 U4101.50
MPCIE_DISABLE_N: R1620.1 RN8.3(B) U109.56
NB_VRM_PWRGD: PR4632.2 PU4601.8 R79674.1
NC#7: R90032.2 U9003.7
NGFF_ALERT#: CPU1.BB19 R1717.1 R1749.1
NGFF_ALERT_N: NGFF1.62 R1717.2
NGFF_BT_DISABLE: R1621.1 R1933.1 U109.125
NGFF_CLKREQ0_N: NGFF1.53 R1931.1
NGFF_CLKREQ0_NGFF#: Q1229.S R1931.2 R1932.2
NGFF_CLKREQ1_APU#: CPU1.BB17 Q1229.D
NGFF_CLKREQ1_N: NGFF1.68 R1925.2
NGFF_CLKREQ1_N_TP: R1925.1 TP208.1
NGFF_DETECT_PCIE: CPU1.BA19 R1155.2 R1926.1
NGFF_DETECT_PCIE_C: NGFF1.51 R1155.1 R1709.1
NGFF_DETECT_USB: R1154.2 R1935.2 U109.126
NGFF_DETECT_USB_C: NGFF1.1 R1154.1 R1209.1
NGFF_PCIE0_RXN: NGFF1.43 R1712.1
NGFF_PCIE0_RXP: NGFF1.41 R1711.1
NGFF_PCIE0_TXN: NGFF1.37 R1714.1
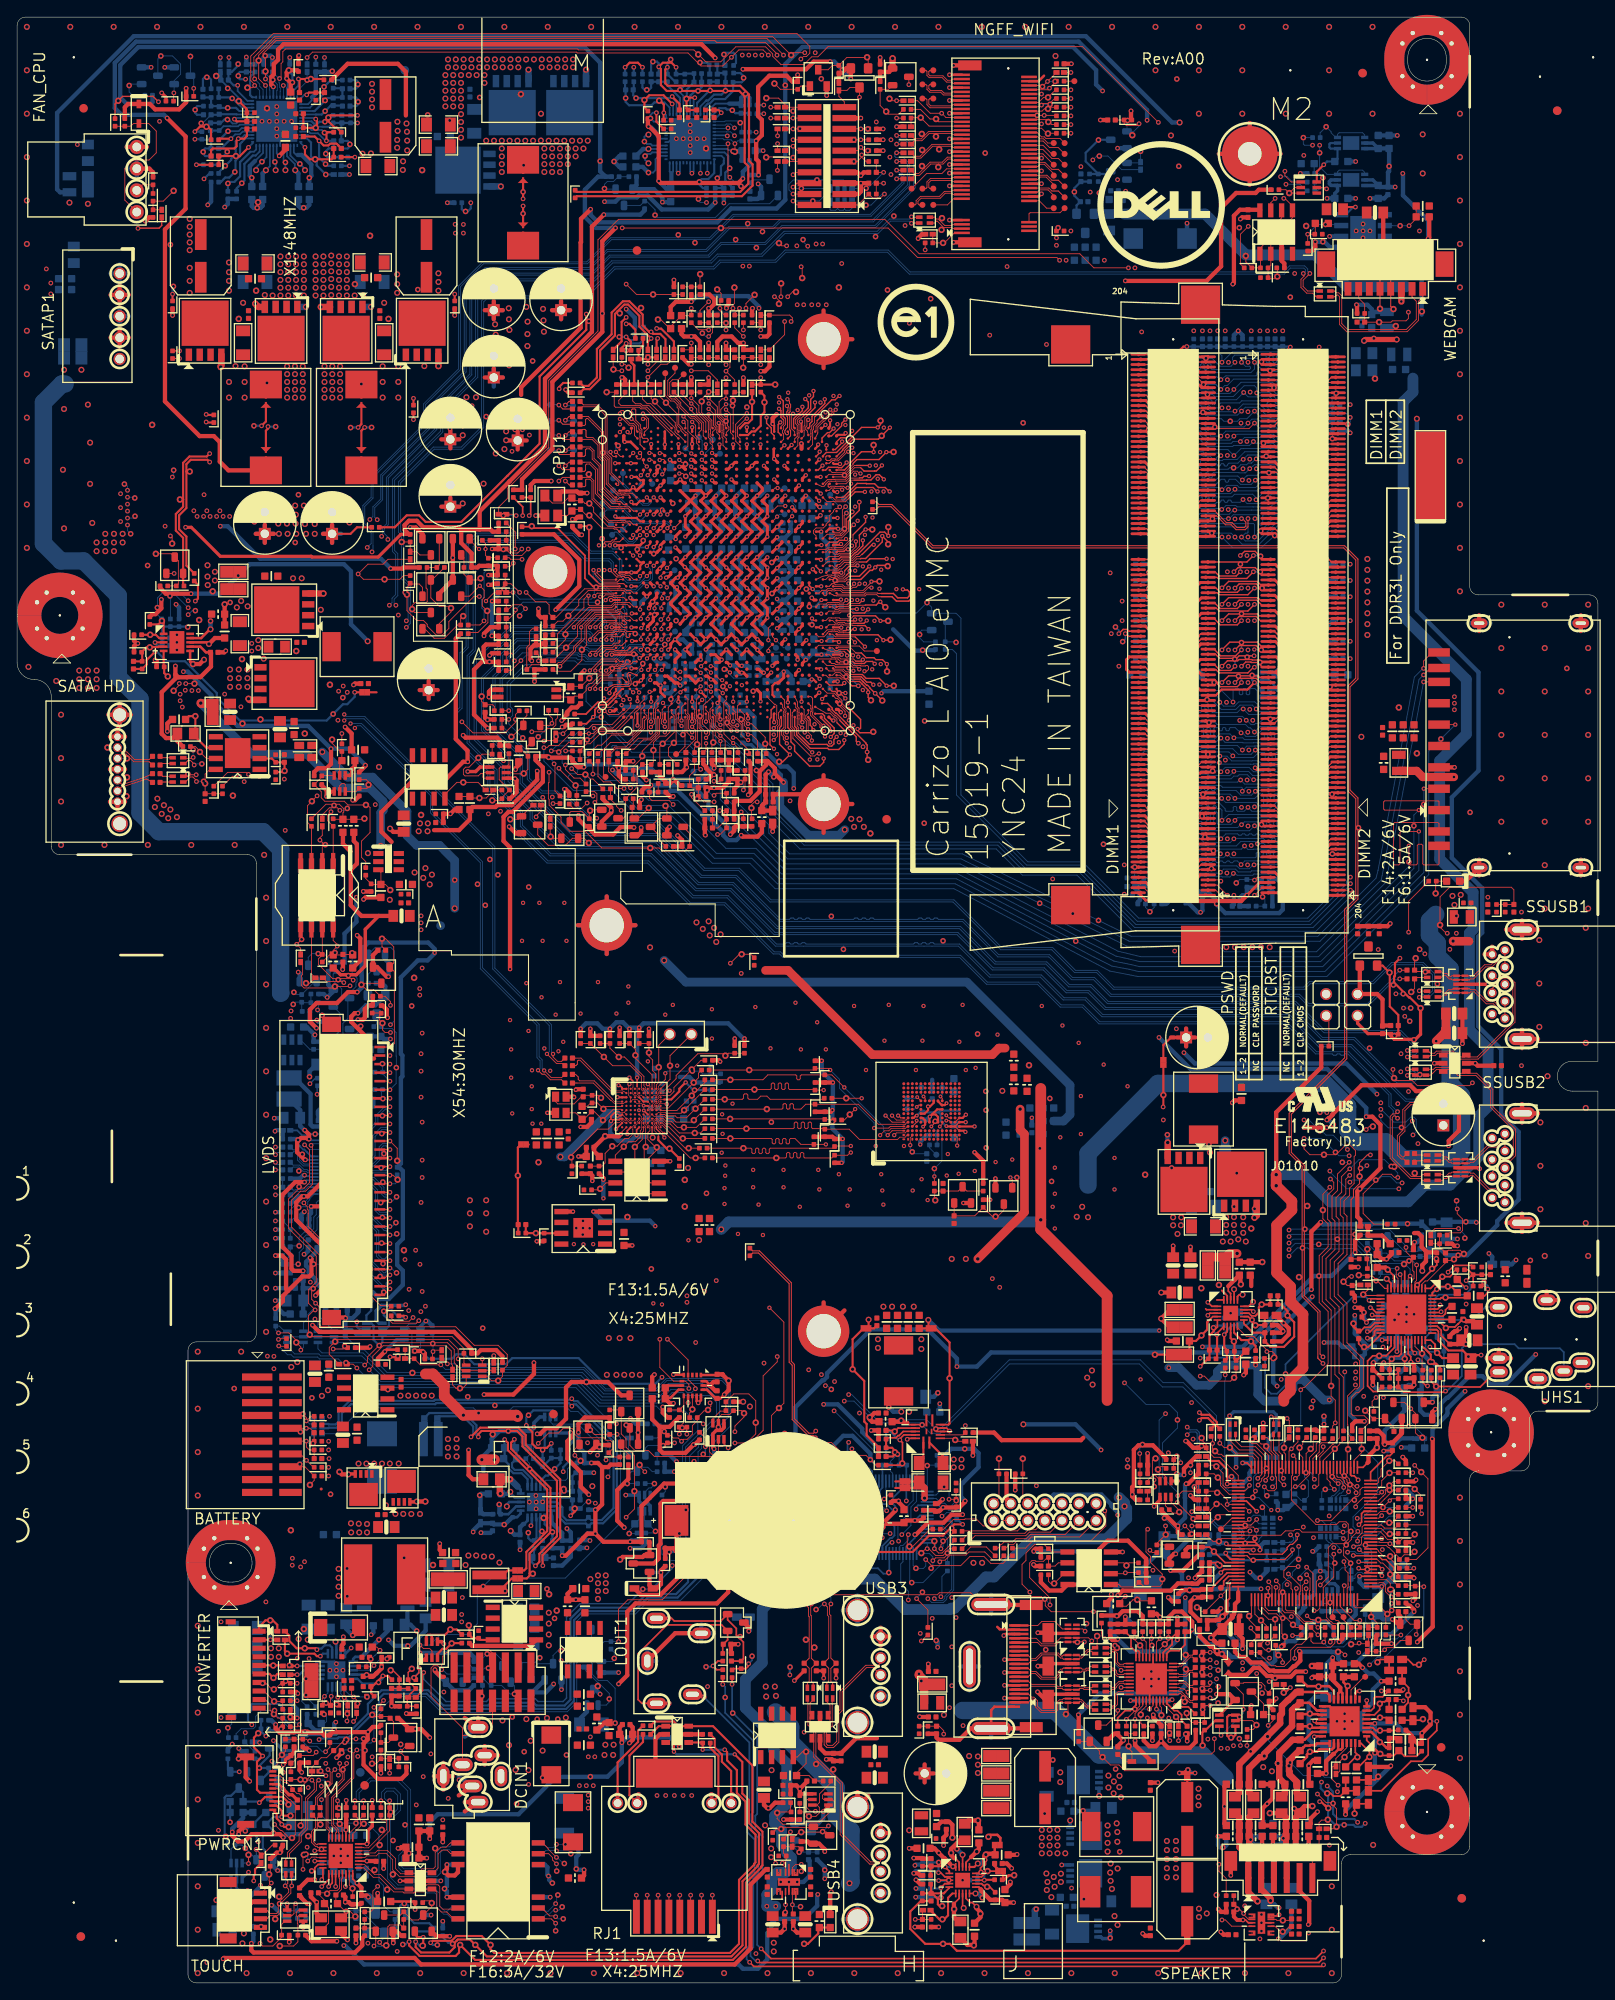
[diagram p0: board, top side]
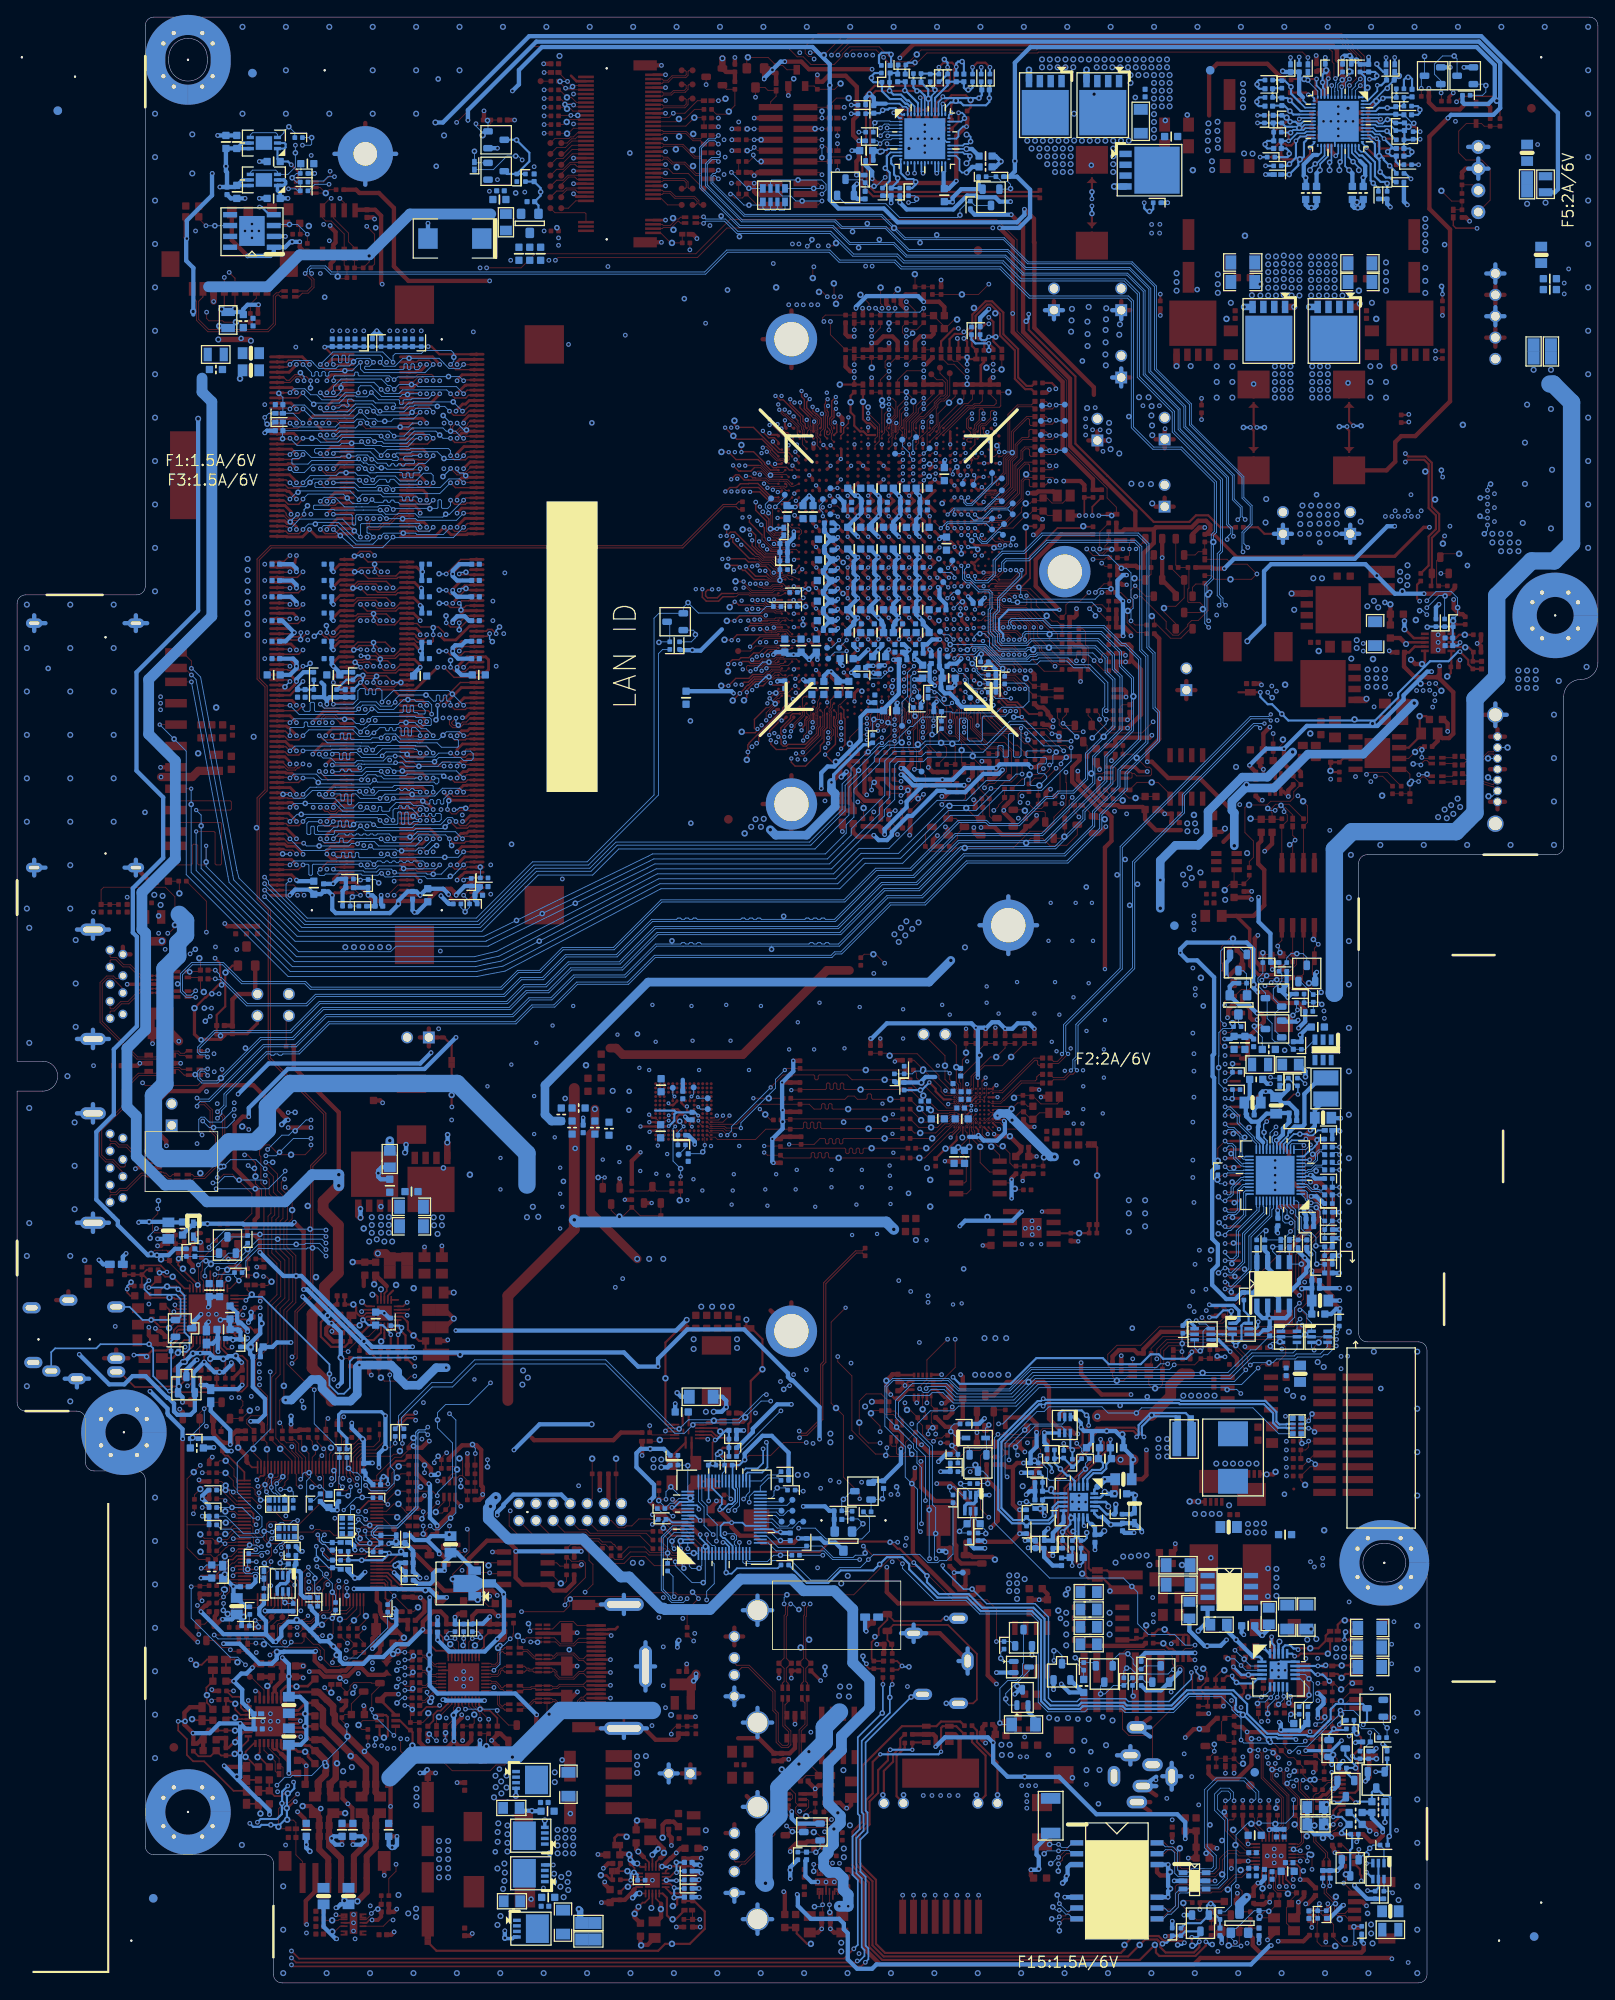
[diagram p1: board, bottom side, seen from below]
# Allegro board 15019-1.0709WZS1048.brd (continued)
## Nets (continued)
NGFF_PCIE0_TXP: NGFF1.35 R1713.1
NGFF_PCIE1_RXN: NGFF1.67 TP82.1
NGFF_PCIE1_RXP: NGFF1.65 TP81.1
NGFF_PCIE1_TXN: NGFF1.61 TP80.1
NGFF_PCIE1_TXP: NGFF1.59 TP79.1
NGFF_PEWAKE0_N: NGFF1.55 NGFF1.70 R1718.2 R1719.1
NGFF_POWER_CTRL_1: Q3.G R15.2
NGFF_POWER_CTRL_V2: C864.1 Q128.B R1716.1
NGFF_REFCLKN0: NGFF1.49 R23.1
NGFF_REFCLKN1: NGFF1.73 TP84.1
NGFF_REFCLKP0: NGFF1.47 R22.1
NGFF_REFCLKP1: NGFF1.71 TP83.1
NGFF_W_DISABLE1_N: NGFF1.56 R1620.2
NGFF_W_DISABLE2_N: NGFF1.54 R1621.2
OGPIO0: R90047.2 R90048.1 U902.B9
OGPIO1: R90073.1 R90074.2 U902.C8
OGPIO2: R90050.1 R90075.2 U902.B8
OGPIO3: R90051.2 R90054.1 U902.A8
OGPIO4: R90052.1 R90055.2 U902.C7
OGPIO5: R90053.1 R90056.2 U902.B7
OSD_BIST_N: R535.1 R744.2
OSD_BIST_N_1: Q12.2 R535.2
OSD_DN: C238.1 CPU1.AL6 R1755.1 R1758.1
OSD_DN_R: PWRCN1.2 R1755.2
OSD_MENU: C585.1 CPU1.AH1 R755.1 R758.1 R80206.1
OSD_MENU_R: PWRCN1.1 R758.2
OSD_MENU_SIO: R80206.2 U109.109
OSD_UP: C582.1 CPU1.AJ3 R742.2 R743.1 R744.1
OSD_UP_R: PWRCN1.3 R743.2
OZ554_ENA: C3458.1 R79625.1 R79627.1 U120.3
OZ554_PWM: C8.1 R79621.1 R79623.1 U120.5
OZ554_VIN: C3457.1 R5.2 U120.4
P_GFX_TXN0: C1811.1 CPU1.M1
P_GFX_TXN1: C1813.1 CPU1.L2
P_GFX_TXN2: C1814.1 CPU1.L3
P_GFX_TXN3: C122.1 CPU1.J2
P_GFX_TXP0: C1809.1 CPU1.M2
P_GFX_TXP1: C1810.1 CPU1.L1
P_GFX_TXP2: C1812.1 CPU1.L4
P_GFX_TXP3: C1815.1 CPU1.J1
P_RX_ZVDD: CPU1.U6 R557.1 R2003.1
P_TX_ZVDD: CPU1.U7 R558.2
PANEL_ON_1: R33.1 R39.1 R41.2 R42.1
PANEL_ON_2: Q10.B R42.2
PANEL_ON_3: C14.2 Q5.D R19.1 R20.2 U1.3
PANEL_ON_4: Q1.G Q5.G Q10.C R26.2 R30.1
PANEL_ON_5: Q1.D R8.1
PANEL_SEL1_CABLE: CONVT1.7 R1730.2 R1734.2
PANEL_SEL1_CABLE_EC: R1730.1 U109.102
PANEL_SEL2_CABLE: CONVT1.8 R287.2 R1731.2
PANEL_SEL2_CABLE_EC: R287.1 U109.103
PANEL_SEL3_CABLE: CONVT1.9 R1732.2 R1733.2
PANEL_SEL3_CABLE_EC: R1732.1 U109.104
PB_IN_N_1: C197.2 R379.2 R385.2 R79669.1 U109.72
PB_IN_N_2: R79669.2 U109.111
PB_IN_SW1: PWRCN1.6 R1756.1 R1760.2
PCB_VER_ID: R79720.1 R79721.2 U4101.49
PCH_AUD_RST_N: R289.1 R637.1 U109.19
PCH_AUD_RST_N_1: Q63.5 R637.2
PCH_CLK48_F: CPU1.BC10 R1645.2
PCH_SATA_LED_1: Q38.B Q1213.C R1759.2
PCH_SATA_LED_R: Q1213.B R1754.2
PCIE_RST#: NGFF1.52 NGFF1.66 RN13.1(A)
PCIE_RST_N: CPU1.AN7 R1678.2
PCIE_RST_N_A: C1738.1 R1678.1
PCIRST1#: R79690.1 RN13.6(B) U109.30
PCIRST3#: R79689.1 RN13.7(B) RN13.8(B) U109.81
PD4405_A: PD4405.A PQ4409.B
PD4405_K: PD4405.K PR4458.2
PD_N: Q1249.D U118.36
PEG_RXN0: CPU1.P9 TP5006.1
PEG_RXN1: CPU1.N5 TP5008.1
PEG_RXN2: CPU1.N8 TP5010.1
PEG_RXN3: CPU1.L6 TP5012.1
PEG_RXP0: CPU1.P10 TP5005.1
PEG_RXP1: CPU1.N6 TP5007.1
PEG_RXP2: CPU1.N9 TP5009.1
PEG_RXP3: CPU1.L7 TP5011.1
PEG_TXN0: C1811.2 TP4143.1
PEG_TXN1: C1813.2 TP4145.1
PEG_TXN2: C1814.2 TP4147.1
PEG_TXN3: C122.2 TP4149.1
PEG_TXP0: C1809.2 TP4142.1
PEG_TXP1: C1810.2 TP4144.1
PEG_TXP2: C1812.2 TP4146.1
PEG_TXP3: C1815.2 TP4148.1
PLTRST*_EC: R79697.1 U4101.6
PLTRST*_SIO: C76.2 R351.1 R352.1 U109.46
PLTRST_LAN_N: RN13.2(A) U16.19
PLTRST_N: C77.1 CPU1.BB12 LPC1.3 R352.2 R79697.2
PME#_M: CPU1.AD7 R568.2
PORTC_SPK_L: R345.1 U6.43
PORTC_SPK_L_1: R345.2 R356.1
PORTC_SPK_R: R359.1 U6.44
PORTC_SPK_R_1: R359.2 R367.1
PQ4206_D: PQ4206.D PR4214.2
PQ4406_2: PQ4406.2 PR4462.2
PQ4406_3: PQ4406.3 PR4455.2
PQ4406_5: PC4426.1 PQ4406.5 PR4413.2
PQ4406_6: PC4426.2 PQ4406.6 PR4450.1
PQ4409_C: PQ4409.C PR4451.1 PR4462.1
PQ4409_E: PQ4409.E PR4431.2 PR4433.1
PRE: R2088.2 R2090.1 U118.16
PSID_D: L15.2 Q47.D R1852.1
PSID_D_1: Q45.B R1852.2 R1853.1
PSID_G: Q45.C Q47.G R1849.2
PW_CLEAR: CPU1.AE2 PSWD1.2 R184.1
PWR_1D8V_BOOT: PR5205.1 PU5201.10
PWR_1D8V_BOOT_A: PC5217.1 PR5205.2
PWR_1D8V_EN: PC34.1 PR57.2 PR62.2 PR5223.1 PU5201.13 R77.1
PWR_1D8V_FB: PC5203.2 PR5201.2 PR5209.1 PU5201.12
PWR_1D8V_FB_1: PC5203.1 PG5211.2 PR5201.1
PWR_1D8V_LX: PC5217.2 PL5202.1 PR5204.1 PU5201.8 PU5201.9 PU5201.15 PU5201.16
PWR_1D8V_SNB: PC5202.1 PR5204.2
PWR_1D8V_VCC: PC5204.1 PU5201.11
PWR_1D8V_VOUT: PG5212.2 PU5201.7
PWR_3D3V_BOOT2: PR4902.2 PU4901.7
PWR_3D3V_BOOT2_R: PC4907.2 PR4902.1
PWR_3D3V_ENTRIP2: PC4918.1 PR4924.1 PU4901.4
PWR_3D3V_FB: PC4911.2 PG4902.1 PR4914.1
PWR_3D3V_FB2: PC4911.1 PR4914.2 PR4917.1 PU4901.5
PWR_3D3V_LDO3: PC4914.2 PG4904.1 PU4901.15
PWR_3D3V_LGATE2: PU4901.10 PU4903.4
PWR_3D3V_PHASE2: PC4907.1 PL4903.2 PR4911.1 PU4901.9 PU4902.1 PU4902.2 PU4902.3 PU4903.5 PU4903.6 PU4903.7 PU4903.8
PWR_3D3V_SNB: PC4916.1 PR4911.2
PWR_3D3V_UGATE2: PU4901.8 PU4902.4
PWR_5V3V_EMN: PR4918.2 PR4920.1 PU4901.13
PWR_5V3V_ENLDO: PR4901.2 PU4901.12
PWR_5V3V_LDO5: PC4906.1 PG4901.1 PU4901.14
PWR_5V3V_PGOOD: PU4901.6 R1762.2
PWR_5V3V_TON: PR4919.1 PU4901.3
PWR_5V_BOOT1: PR4903.1 PU4901.19
PWR_5V_BOOT1_R: PC4908.1 PR4903.2
PWR_5V_BYP1: PC4912.1 PC4913.1 PG4903.2 PR4921.2 PU4901.20
PWR_5V_ENTRIP1: PC4917.1 PR4925.1 PU4901.2
PWR_5V_FB1: PC4913.2 PR4921.1 PR4922.1 PU4901.1
PWR_5V_LGATE1: PU4901.16 PU4905.4
PWR_5V_PHASE1: PC4908.2 PL4904.1 PR4912.1 PU4901.17 PU4904.1 PU4904.2 PU4904.3 PU4905.5 PU4905.6 PU4905.7 PU4905.8
PWR_5V_SNB: PC4915.1 PR4912.2
PWR_5V_UGATE1: PU4901.18 PU4904.4
PWR_CHG_ACDET: PC5232.1 PR4412.1 PR5270.2 U55.6
PWR_CHG_ACN: PC4402.1 PC4404.1 PG4905.2 U55.1
PWR_CHG_ACP: PC4402.2 PC4403.1 PG4907.2 U55.2
PWR_CHG_AD_OFF: PQ4206.G PR4210.1 R80230.1 U4101.19
PWR_CHG_AD_OFF_R: PQ4204.B PR4210.2
PWR_CHG_BTST: PR5279.1 U55.17
PWR_CHG_BTST_1: PC5234.1 PD4401.K PR5279.2
PWR_CHG_CMPIN: PR5287.2 PR5467.2 PR5468.1 PR5469.2 PR5470.1 U55.4
PWR_CHG_CMPIN_R: PQ5006.6 PR5470.2
PWR_CHG_CMPIN_RR: PQ5006.3 PR5469.1
PWR_CHG_HIDRV: PU4403.4 U55.18
PWR_CHG_ILIM: PQ5003.D PR5268.1 PR5278.2 U55.10
PWR_CHG_IOUT: PC5239.1 PR5288.1 PR5467.1 U55.7
PWR_CHG_LODRV: PC5237.1 PU4405.4 U55.15
PWR_CHG_NC: PR5286.1 U55.11
PWR_CHG_PHASE: PC5234.2 PL5003.1 PU4403.1 PU4403.2 PU4403.3 PU4405.5 PU4405.6 PU4405.7 PU4405.8 U55.19
PWR_CHG_SRN: PR5277.1 U55.12
PWR_CHG_SRP: PR5283.1 U55.13
PWR_CHG_VCC: PC4408.1 PR5284.2 U55.20
PWR_COMP_R: PC4626.1 PR4645.2
PWR_CPU_BST1: PR4701.1 PU4601.28
PWR_CPU_BST2: PR4703.1 PU4601.37
PWR_CPU_COMP: PC4626.2 PC4627.2 PU4601.48
PWR_CPU_COMPNB: PC4611.2 PC4612.2 PU4601.18
PWR_CPU_CSCOMP: PC4603.2 PC4615.2 PC4618.1 PR4601.2 PR4619.1 PR4626.2 PR4637.1 PU4601.45
PWR_CPU_CSCOMPNB: PC4613.1 PC4617.2 PC4624.2 PR4609.2 PR4638.2 PR4639.1 PR4640.1 PU4601.21
PWR_CPU_CSN1: PG4702.2 PR4618.2
PWR_CPU_CSN1NB: PG4704.2 PR4612.2
PWR_CPU_CSP1: PC4628.2 PR4615.1 PU4601.40
PWR_CPU_CSP1NB: PC4623.1 PR4608.1 PU4601.26
PWR_CPU_CSP2: PR4631.1 PU4601.41
PWR_CPU_CSP2NB: PR4633.1 PU4601.25
PWR_CPU_CSREF: PC4606.1 PC4628.1 PR4618.1 PU4601.42
PWR_CPU_CSREFNB: PC4622.1 PC4623.2 PR4612.1 PU4601.24
PWR_CPU_CSSUM: PC4615.1 PC4618.2 PR4620.2 PR4641.1 PU4601.43
PWR_CPU_CSSUMNB: PC4613.2 PC4617.1 PR4625.1 PR4644.2 PU4601.23
PWR_CPU_DIFF: PR4634.1 PR4636.1 PU4601.50
PWR_CPU_DIFFNB: PR4621.1 PR4622.1 PU4601.16
PWR_CPU_DROOP: PC4603.1 PR4601.1 PU4601.46
PWR_CPU_DROOPNB: PC4624.1 PR4638.1 PU4601.20
PWR_CPU_FB: PC4621.2 PC4627.1 PR4636.2 PR4645.1 PU4601.49
PWR_CPU_FBNB: PC4610.2 PC4612.1 PR4621.2 PR4623.1 PU4601.17
PWR_CPU_HG1: PU4601.29 PU5207.4
PWR_CPU_HG2: PU4601.36 PU4702.4
PWR_CPU_ILIM: PR4626.1 PU4601.44
PWR_CPU_ILIMNB: PR4609.1 PU4601.22
PWR_CPU_IOUT: PC4609.2 PR4614.1 PU4601.47
PWR_CPU_IOUTNB: PC4616.1 PR4627.1 PU4601.19
PWR_CPU_LG1: PU4601.31 PU4705.4 PU4706.4
PWR_CPU_LG2: PU4601.34 PU4703.4 PU4704.4
PWR_CPU_PHCONFIG: PR4635.1 PU4601.38
PWR_CPU_ROSC: PR4610.2 PU4601.11
PWR_CPU_SNBNB: PC4712.1 PR4704.2
PWR_CPU_SNBVDD1: PC4706.1 PR4702.2
PWR_CPU_SR: PR4603.1 PU4601.39
PWR_CPU_SW1: PC4704.2 PG4701.1 PL4701.1 PR4702.1 PU4601.30 PU4705.5 PU4705.6 PU4705.7 PU4705.8 PU4706.5 PU4706.6 PU4706.7 PU4706.8 PU5207.1 PU5207.2 PU5207.3
PWR_CPU_SW2: PC4710.2 PG4703.1 PL4702.1 PR4704.1 PU4601.35 PU4702.1 PU4702.2 PU4702.3 PU4703.5 PU4703.6 PU4703.7 PU4703.8 PU4704.5 PU4704.6 PU4704.7 PU4704.8
PWR_CPU_SWN1: PG4701.2 PR4615.2 PR4641.2
PWR_CPU_SWN1NB: PG4703.2 PR4608.2 PR4625.2
PWR_CPU_TEENSE: PC4607.2 PR4605.2 PR4613.2 PU4601.1
PWR_CPU_TSENSENB: PC4619.2 PR4629.2 PR4630.2 PU4601.14
PWR_CPU_VCC: PC4602.1 PR4602.2 PU4601.10
PWR_CPU_VDD: PC4601.1 PR4604.1 PU4601.51
PWR_CPU_VDDNB: PC4605.1 PR4642.1 PU4601.15
PWR_CPU_VRMP: PC4614.1 PR4616.2 PU4601.12
PWR_DCBATOUT_1D8V: PC5209.1 PC5214.1 PG5205.2 PG5210.2 PU5201.1
PWR_DCBATOUT_3V: PC4901.1 PC4902.1 PR4927.2 PR4929.2 PU4902.5 PU4902.6 PU4902.7 PU4902.8
PWR_DCBATOUT_5V: PC4904.1 PC4905.1 PR4930.2 PR4931.2 PR4932.2 PR4933.2 PT4901.1 PU4904.5 PU4904.6 PU4904.7 PU4904.8
PWR_DCBATOUT_VDDP: PC4713.1 PC4801.1 PC4808.1 PR4814.2 PR4815.2 PU4802.5 PU4802.6 PU4802.7 PU4802.8
PWR_DIFF_R: PC4621.1 PR4634.2
PWR_FCH_REF: PC51.1 PR5472.1 PR5473.2 PU5.3
PWR_FCH_S5: PC50.1 PC5428.1 PU5.4 Q4701.6 Q6704.1 Q6704.2
PWR_FCH_VCNTL: PC49.1 PR5475.2 PU5.6
PWR_GFX_BST1: PR5404.1 PU5407.28
PWR_GFX_BST1_SW1: PC5411.1 PR5404.2
PWR_GFX_COMP: PC5416.2 PC5417.2 PU5407.48
PWR_GFX_COMP_FB: PC5417.1 PR5415.2
PWR_GFX_CSCOMP: PC5414.1 PC5419.2 PC5425.2 PR5414.1 PR5417.2 PR5425.1 PR5428.2 PU5407.45
PWR_GFX_CSN1: PG5402.2 PR4685.2
PWR_GFX_CSP1: PC5426.1 PR5408.1 PU5407.40
PWR_GFX_CSP2: PR5429.1 PU5407.41
PWR_GFX_CSREF: PC5413.1 PC5426.2 PR4685.1 PU5407.42
PWR_GFX_CSSUM: PC5414.2 PC5425.1 PR5409.1 PR5426.2 PU5407.43
PWR_GFX_DIFF: PR5407.1 PR5413.1 PU5407.50
PWR_GFX_DIFF_R: PC5415.1 PR5407.2
PWR_GFX_DROOP: PC5419.1 PR5417.1 PU5407.46
PWR_GFX_FB: PC5415.2 PC5416.1 PR5413.2 PR5415.1 PU5407.49
PWR_GFX_HG1: PU5401.4 PU5407.29
PWR_GFX_ILIM: PR5428.1 PU5407.44
PWR_GFX_ILIM_R: PR5414.2 PR5425.2 PR5426.1
PWR_GFX_IOUT: PC5423.2 PR5402.1 PU5407.47
PWR_GFX_LG1: PU5402.4 PU5403.4 PU5407.31
PWR_GFX_PHCONFIG: PR5412.1 PU5407.38
PWR_GFX_ROSC: PR5411.2 PU5407.11
PWR_GFX_SNB1: PC5405.1 PR5401.2
PWR_GFX_SR: PR5419.1 PU5407.39
PWR_GFX_SW1: PC5411.2 PG5401.1 PL5401.1 PR5401.1 PU5401.1 PU5401.2 PU5401.3 PU5402.5 PU5402.6 PU5402.7 PU5402.8 PU5403.5 PU5403.6 PU5403.7 PU5403.8 PU5407.30
PWR_GFX_SWN1: PG5401.2 PR5408.2 PR5409.2
PWR_GFX_TSENSE: PC5422.2 PR5421.2 PR5423.2 PU5407.1
PWR_GFX_VCC: PC5420.1 PR5418.2 PU5407.10
PWR_GFX_VDD: PC5418.1 PR5420.1 PU5407.51
PWR_GFX_VR_HOT: PR5464.1 PU5407.13
PWR_GFX_VRMP: PC5424.1 PR5424.2 PU5407.12
PWR_GFX_VSS: PC5418.2 PR5422.1 PU5407.52
PWR_LED_YELLOW_C: PWRCN1.9 Q1212.D R1751.2 R1761.1
PWR_LED_YELLOW_C2: R724.2 R1751.1
PWR_VDDP_BOOT: PR4812.1 PU4803.10
PWR_VDDP_BOOT_R: PC4806.2 PR4812.2
PWR_VDDP_CS: PR4802.2 PU4803.2
PWR_VDDP_EN: PC48.1 PC4804.1 PU4803.3 R125.1 R1763.2 R1764.1
PWR_VDDP_FB: PC4805.2 PR4803.2 PR4816.1 PU4803.4
PWR_VDDP_FB_R: PC4805.1 PG4801.1 PR4803.1
PWR_VDDP_LGATE: PU4801.4 PU4803.6
PWR_VDDP_PG: PR4805.2 PU4803.1
PWR_VDDP_PHASE: PC4806.1 PC4807.1 PL4802.1 PU4801.5 PU4801.6 PU4801.7 PU4801.8 PU4802.1 PU4802.2 PU4802.3 PU4803.8
PWR_VDDP_RF: PR4807.1 PU4803.5
PWR_VDDP_SNB: PC4807.2 PR4806.1
PWR_VDDP_UGATE: PU4802.4 PU4803.9
PWR_VDDQ_BOOT: PR5006.1 PU5001.18
PWR_VDDQ_BOOT_L: PC5010.1 PR5006.2
PWR_VDDQ_CS: PC5003.2 PR5003.2 PU5001.13
PWR_VDDQ_EN: C1796.1 PU5001.8 R1808.2 R1810.2
PWR_VDDQ_FB: PC5013.2 PR5009.1 PR5023.2 PU5001.6
PWR_VDDQ_LGATE: PU5001.15 PU5007.4
PWR_VDDQ_PHASE: PC5010.2 PL5001.1 PR5034.1 PU5001.16 PU5006.1 PU5006.2 PU5006.3 PU5007.5 PU5007.6 PU5007.7 PU5007.8
PWR_VDDQ_SENSE: PC5013.1 PG5001.2 PR5023.1 PU5001.5
PWR_VDDQ_SNB: PC5017.1 PR5034.2
PWR_VDDQ_TON: PR5007.2 PU5001.9
PWR_VDDQ_UGATE: PU5001.17 PU5006.4
PWR_VDDQ_VDD: PC5003.1 PC5018.1 PR5002.1 PR5003.1 PU5001.11
PWR_VDDQ_VDDP: PC5009.1 PR5004.1 PU5001.12
PWR_VDDQ_VTTIN: PC5011.1 PR5020.2 PR5021.2 PU5001.19
PWR_VDDQ_VTTREF: PC5014.1 PR5032.2 PU5001.4
PWR_VTT_EN: C1797.1 PU5001.7 R1809.2 R1810.1
PWRBTN_N: C1760.1 R385.1 R1756.2 U4101.47
PWRCN_DET_N: C6722.2 PWRCN1.5 R1669.1 U109.124
PWRGD_3V: C194.1 R368.1 R369.1 R1668.1 R1857.2
PWRGD_3V_B_1: Q37.5 Q37.6 R380.2
PWRGD_3V_D: Q78.S Q1246.D
PWRGD_3V_G: Q1246.G R1668.2
PWRGD_3V_LL: Q37.3 R369.2
PWRGD_PS_L: C525.2 Q1226.2 R656.1 R657.2
PWRGD_PS_L1: Q1226.5 Q1226.6 R1831.2
PWRGD_PS_L2: Q1226.3 R1842.1
PWROK3_1: R309.2 U109.29
PWROK3_1_R: R309.1 R366.2 R1857.1
PWROK3_2: R373.1 U109.75
PWROK3_2_R: R373.2 R381.1 R384.1
RDY#: TP4126.1 U4101.23
REMOTE1+: C211.2 R404.1 RT3.1 U109.87
REMOTE1-: C211.1 R400.2 RT3.2
REXT: R2082.1 U118.18
RING2: C157.1 Q24.2 R261.2 U6.31 UHS1.3
ROM_RST#: CPU1.AW11 R1647.1
RSMRST*_R: Q37.2 R384.2
RSMRST_N: Q1247.G R374.1 R382.2
RSMRST_N_1: Q1247.D Q1248.G R2066.1
RSMRST_N_FCH: C78.1 CPU1.AE4 Q1248.D R1677.2
RST#: C9019.1 R90046.2 U902.H5
RSVD_AN30: CPU1.AN30 TP212.1
RSVD_U30: CPU1.U30 TP210.1
RSVD_U31: CPU1.U31 TP211.1
RT: R79628.1 U120.10
RT9025_ADJ: C9008.1 PG9001.1 R90030.1
RT9025_ADJ_FB: C9008.2 R90030.2 R90031.1 U9001.7
RTL_ISOLATE_N: Q36.6 R377.2 R1817.1 U16.20
RTL_ISOLATE_N_1: C1798.1 Q36.5 R406.1 R1816.2
RTL_ISOLATE_N_2: Q36.2 Q36.3 R378.2
RTN1: CONVT1.1 R51.1
RTN2: CONVT1.2 R53.1
RTN3: CONVT1.5 R56.1
RTN4: CONVT1.6 R59.1
RUN_0P95_EN1: Q18.2 Q18.3 R179.2 R181.1
RUN_0P95_EN2: Q18.6 R171.2 R172.1 R175.1
RUN_0P95_EN3: C1768.2 D20.3 Q18.5 R1776.2
RUN_0P95_EN4: C94.1 C857.1 R174.1 R175.2
RUN_EN1: Q65.2 Q65.3 R732.1 R733.2
RUN_EN2: Q65.6 R722.1 R1178.1 R1778.2
RUN_EN_1P8V: C862.1 R1178.2 R1179.2 U105.3
RUNPWR_R6: C865.2 Q65.5 R718.2
S0A3_GPIO: CPU1.AE8 R1724.1 R1813.1 R2021.2
S0A3_GPIO_G: Q1243.G R2021.1
S_LVDS_BL_EN: R135.1 R139.1 R143.2 R144.1 R1985.1
S_TXE0+: LVDS1.18 U26.31
S_TXE0-: LVDS1.19 U26.32
S_TXE1+: LVDS1.15 U26.29
S_TXE1-: LVDS1.16 U26.30
S_TXE2+: LVDS1.12 U26.27
S_TXE2-: LVDS1.13 U26.28
S_TXE3+: LVDS1.8 U26.23
S_TXE3-: LVDS1.9 U26.24
S_TXEC+: LVDS1.10 U26.25
S_TXEC-: LVDS1.11 U26.26
S_TXO0+: LVDS1.29 U26.41
S_TXO0-: LVDS1.30 U26.42
S_TXO1+: LVDS1.27 U26.39
S_TXO1-: LVDS1.28 U26.40
S_TXO2+: LVDS1.25 U26.37
S_TXO2-: LVDS1.26 U26.38
S_TXO3+: LVDS1.20 U26.33
S_TXO3-: LVDS1.21 U26.34
S_TXOC+: LVDS1.22 U26.35
S_TXOC-: LVDS1.23 U26.36
SA0_DIM1: DIMM1.197 R163.1 R165.2
SA0_DIM2: DIMM2.197 R2055.2 R2056.1
SA1_DIM1: DIMM1.201 R1634.2 R1635.1
SA1_DIM2: DIMM2.201 R2061.2 R2062.1
SATA__RXN0_C: C149.2 HDD1.5
SATA__RXP0_C: C151.2 HDD1.6
SATA__TXN0_C: C142.2 HDD1.3
SATA__TXP0_C: C141.2 HDD1.2
SATA_CALRN: CPU1.AW2 R586.2
SATA_CALRP: CPU1.AW1 R1644.2
SATA_LED_N_C_1: Q9646.3 Q9646.6 R80201.2
SATA_X1: C9025.1 R90057.2 U902.F1 X54.3
SATA_X2: R90057.1 R90076.1 U902.E1
SATA_X2_R: C9024.1 R90076.2 X54.1
SATAHDR_RX_DN0: CPU1.AV1 L4103.4
SATAHDR_RX_DN0_EMI: C149.1 L4103.3
SATAHDR_RX_DN1: C9029.1 CPU1.AW4
SATAHDR_RX_DN1_R: C9029.2 U902.B2
SATAHDR_RX_DP0: CPU1.AV2 L4103.1
SATAHDR_RX_DP0_EMI: C151.1 L4103.2
SATAHDR_RX_DP1: C9028.1 CPU1.AW3
SATAHDR_RX_DP1_R: C9028.2 U902.B1
SATAHDR_TX_DN0: CPU1.AU4 L4102.1
SATAHDR_TX_DN0_EMI: C142.1 L4102.2
SATAHDR_TX_DN1: C9027.1 CPU1.AY1
SATAHDR_TX_DN1_R: C9027.2 U902.D2
SATAHDR_TX_DP0: CPU1.AU3 L4102.4
SATAHDR_TX_DP0_EMI: C141.1 L4102.3
SATAHDR_TX_DP1: C9026.1 CPU1.AY2
SATAHDR_TX_DP1_R: C9026.2 U902.D1
SB3V: C579.1 C595.1 C1615.1 C1617.1 C1701.1 C1715.1 C1716.1 C1925.1 CPU1.AP15 CPU1.AR15 F3.1 PC1.1 PC140.1 PR5005.1 PR5206.1 PR5475.1 Q44.S Q1211.S R10.1 R137.2 R184.2 R297.2 R305.2 R307.1 R312.2 R313.1 R364.1 R371.2 R378.1 R380.1 R382.1 R483.1 R514.1 R526.2 R531.1 R582.2 R679.2 R682.1 R683.1 R717.1 R731.1 R742.1 R755.2 R764.2 R775.1 R777.1 R1664.1 R1665.1 R1666.1 R1669.2 R1675.2 R1676.2 R1679.2 R1708.1 R1731.1 R1733.1 R1734.1 R1752.1 R1758.2 R1784.1 R1785.1 R1813.2 R1825.2 R1826.2 R1831.1 R1840.2 R1843.1 R1863.2 R1864.2 R1874.1 R1875.1 R1876.1 R1877.1 R1933.2 R1935.1 R1987.2 R2010.1 R2012.1 R2029.2 R2030.2 R2064.1 R2065.2 R2066.2 R2091.1 R6702.1 R79635.2 R79661.1 R79670.2 R79671.2 R79673.2 R79675.1 R79689.2 R79690.2 R80201.1 R80202.1 R90008.1 R90066.2 R90068.2 R90069.1 RN9.1(A) RN9.2(A) U54.8 U54.9
SB3V_EN: C1700.1 PR5431.2 R1980.2 R1981.2 U54.3 U54.5
SB5_33_CT1: C1929.1 U54.12
SB5_33_CT2: C1928.1 U54.10
SB5V: C103.1 C1926.1 C1927.1 PC4608.1 PC4803.1 PC5421.1 PR57.1 PR4602.1 PR4631.2 PR4633.2 PR5002.2 PR5004.2 PR5294.1 PR5295.1 PR5418.1 PR5429.2 PU4601.33 PU4803.7 PU5407.25 PU5407.26 PU5407.33 R118.2 R119.1 R125.2 R389.1 R724.1 R735.1 R1759.1 R1767.1 R1833.2 R79726.1 RN10.5(B) RN10.6(B) RN10.7(B) RN10.8(B) U54.13 U54.14 U178.8
SCALAR_SIO_PU: R276.2 R289.2 R305.1 R317.2 R1188.2 R1844.1 R2013.2 R2014.2 R79637.2 R79638.2 R80221.2 R80222.2 RN8.1(A) RN8.2(A)
SD_CD_BD: CPU1.BC2 MEMCD1.11
SD_CLK_BD: MEMCD1.5 R1735.2
SD_CLK_CH_C: CPU1.BB4 R1735.1
SD_CMD_BD: MEMCD1.2 R570.2
SD_CMD_CH_C: CPU1.AY5 R570.1 R1650.2
SD_DATA0_BD: MEMCD1.7 R585.2
SD_DATA0_CH_C: CPU1.BC3 R585.1
SD_DATA1_BD: MEMCD1.8 R584.2
SD_DATA1_CH_C: CPU1.BA3 R584.1
SD_DATA2_BD: MEMCD1.9 R1686.2
SD_DATA2_CH_C: CPU1.BC5 R1686.1
SD_DATA3_BD: MEMCD1.1 R571.2
SD_DATA3_CH_C: CPU1.BA5 R571.1
SD_LED_BD: CPU1.BB6 R111.1
SD_LED_BD_A: LED3.A R111.2
SD_PWRCTL_CH: CPU1.BB5 TP190.1
SD_WP_BD: CPU1.BB2 MEMCD1.10
SENSE_B: R266.2 R267.2 U6.33
SER_IRQ: CPU1.BC14 R680.1 U109.36
SIDE_USB3_RX2+: L5.3 SSUSB1.6 U3.2 U3.9
SIDE_USB3_RX2-: L5.2 SSUSB1.5 U3.1 U3.10
SIDE_USB3_RX3+: L57.3 SSUSB2.6 U5.2 U5.9
SIDE_USB3_RX3-: L57.2 SSUSB2.5 U5.1 U5.10
SIDE_USB3_TX2+: L4.3 SSUSB1.9 U3.5 U3.6
SIDE_USB3_TX2-: L4.2 SSUSB1.8 U3.4 U3.7
SIDE_USB3_TX3+: L56.3 SSUSB2.9 U5.5 U5.6
SIDE_USB3_TX3-: L56.2 SSUSB2.8 U5.4 U5.7
SIO_AGND: C558.1 C1816.1 C1817.1 C1818.1 C1825.2 R399.1 R400.1 R651.1 R709.1 R1830.2 R1835.2 R1841.2 U109.83 U109.84
SIO_AMD_SVID_EN: R308.1 U109.26
SIO_ATXPG: R294.2 R1842.2 U109.16
SIO_AVCC3: C562.1 C565.1 L60.1 U109.96
SIO_CE_N: R1823.1 U7.1 U109.27
SIO_CLK_DB: R79688.1 U109.48
SIO_COPEN#: R370.1 U109.65
SIO_DAT_DB: R79687.1 U109.49
SIO_DEBUG_RX: R341.1 TP25.1 U109.122
SIO_DEBUG_TX: R1829.1 TP26.1 U109.121
SIO_EUP_EN#: PR62.1 Q1227.D R668.1 R1199.1 R1764.2 R1980.1
SIO_GREEN: Q9646.2 Q9646.5 R80202.2 U109.23
SIO_GREEN_PWM: R723.1 U109.15
SIO_GREEN_PWM_C_1: Q1212.G Q9646.1 R723.2 R729.1 R1752.2
SIO_HDD_LED: R1753.1 R1757.2 U109.11
SIO_HDD_LED_1: Q1214.B R1753.2
SIO_HOLD#: R644.1 U7.7
SIO_INT#: R80208.1 R80212.1 U4101.39
SIO_INT_C: R80208.2 U109.100
SIO_LVDS_BL_ADJ: R131.2 R312.1 R503.1 U109.10
SIO_MAIN_VCC3: Q107.D R1837.1 U109.89
SIO_MEM_EVENT_L: R683.2 R1585.1 U109.53
SIO_MEM_EVENT_L_B: Q1207.B R1586.2
SIO_MEM_EVENT_L_C: Q1207.C R1585.2
SIO_PCIRSTIN#: R317.1 U109.128
SIO_PSON_N: Q107.G R1844.2 U109.73
SIO_PWNBTN_N: R375.2 R379.1 R1653.1
SIO_SCK: C1823.1 R306.2 R650.1 U7.6
SIO_SCK_R: R306.1 U109.22
SIO_SI: R655.1 U7.5 U109.21
SIO_SMB2_CLK: R715.2 R80220.2 U109.63
SIO_SMB2_DATA: R716.2 R80219.2 U109.62
SIO_SMCLK0: R60.2 R79633.2 RN9.4(B) U109.60
SIO_SMCLK0_D: Q95.3 R60.1
SIO_SMDAT0: R43.2 R79634.2 RN9.3(B) U109.61
SIO_SMDAT0_D: Q95.6 R43.1
SIO_SO: R645.1 U7.2 U109.45
SIO_VCORE: C548.2 C549.2 U109.33
SIO_VIN1: R80215.1 R80216.2 U109.94
SIO_VIN2: TP28.1 U109.93
SIO_VIN3: C1816.2 R1830.1 R1833.1 U109.92
SIO_VIN4: C1817.2 R689.1 R1835.1 U109.91
SIO_VIN5: C1818.2 R1838.1 R1841.1 U109.90
SIO_VREF: C1825.1 R397.2 R404.2 R658.2 U109.88
SIO_WP#: R1824.1 U7.3
SIO_WRST#: C190.1 R353.2 U109.47
SIO_YELLOW: Q68.G R731.2 R1761.2 U109.7
SKEW1: CPU1.AT14 R1687.2 R1688.1
SKEW2: CPU1.BB7 R154.1 R160.2
SKEW3: CPU1.BC7 R1684.2 R1685.1
SLEEVE: C160.1 Q24.1 Q28.D R272.2 U6.32 UHS1.4
SLEEVE_G: Q28.G Q31.C R319.2 R322.1
SLP_S3_N: R718.1 R1184.2 R1809.1 R1878.2 R2017.1 R2053.1 R2078.2 R79712.1 U109.68
SLP_S3_N_1: D20.2 R1184.1
SLP_S3_N_EC: R79712.2 U4101.30
SLP_S3_N_G: Q78.G R2053.2
SLP_S3_N_R: CPU1.AK7 Q1244.G R2078.1
SLP_S3_N_R3: TP215.1 U109.76
SLP_S3_N_R_1: Q1243.S Q1244.D R2019.1
SLP_S3_N_R_2: Q1243.D Q1245.G R2018.1 R2019.2
SLP_S3_N_R_3: Q1245.D R2017.2 R2065.1
SLP_S5_N: CPU1.AH5 Q1217.5 R372.2 R1808.1 R79713.1
SLP_S5_N_C: R372.1 U109.74
SLP_S5_N_EC: R79713.2 U4101.51
SMB0_CLK: CPU1.BA15 DIMM1.202 DIMM2.202 Q7.4 R162.1 U6701.4
SMB0_CVT_CLK: C3456.1 R79633.1 U120.6
SMB0_CVT_DATA: C43.1 R79634.1 U120.7
SMB0_DATA: CPU1.AY17 DIMM1.200 DIMM2.200 Q4.4 R1673.1 U6701.6
SMB1_CLK: CPU1.AG5 R14.1 R1675.1
SMB1_DATA: CPU1.AG4 R1622.1 R1676.1
SMBUS_ISP: C1877.1 Q4.2 Q4.5 Q7.2 Q7.5 R2079.2 R79676.1 R79677.1 U109.115
SMBUS_ISP_G: Q95.2 Q95.5 R2079.1 R2080.2
SMBUS_MS: R334.1 R80217.2 R80218.1 U109.123
SNB: C35.1 R79619.2
SPEED_100*_CON: RJ1.12 UR6.2
SPEED_100_N: U12.6 U16.26 UR6.1
SPEED_1000*_CON: RJ1.11 UR7.2
SPEED_1000_N: U12.1 U16.25 UR7.1
SPI_33_18_PU1: R1736.1 R1738.1 R2030.1 R2031.1
SPI_33_18_PU2: C1758.2 R1737.1 R2029.1 R2032.1 SPI1.8 SRCON1.8
SPI_CLK: CPU1.BC6 R1741.2
SPI_CLK_1: R1741.1 SPI1.6 SRCON1.6
SPI_CS0_N: CPU1.BB8 R1738.2 SPI1.1 SRCON1.1
SPI_CS#: U902.J6 U9003.1
SPI_DATAIN: CPU1.BA9 R1740.1
SPI_DATAOUT: CPU1.AY7 R1739.2
SPI_MISO: U902.G6 U9003.2
SPI_MISO_ROM_1: R1740.2 SPI1.2 SRCON1.2
SPI_MOSI: U902.H6 U9003.5
SPI_MOSI_1: R1739.1 SPI1.5 SRCON1.5
SPI_SCK: U902.K6 U9003.6
SPI_WP#: R1647.2 R1736.2 SPI1.3 SRCON1.3
SPKR_DET: R1203.1 R1825.1 U109.59
SPKR_DET_C: PC2127.2 R1203.2 SPK1.6
SPKR_IN_L: C199.2 C203.2 U21.6
SPKR_IN_R: C210.2 U21.31
SPKR_L+_C: C226.1 L31.2 R396.1 SPK1.1
SPKR_L+_SNB: C222.1 R396.2
SPKR_L-_C: C236.1 L32.2 R403.1 SPK1.2
SPKR_L-_SNB: C239.1 R403.2
SPKR_OUT_L+: C224.2 C225.1 L31.1 U21.16
SPKR_OUT_L-: C228.2 C235.1 L32.1 U21.18
SPKR_OUT_R+: C223.2 C247.1 L33.1 U21.25
SPKR_OUT_R-: C229.2 C255.1 L34.1 U21.23
SPKR_R+_C: C248.1 L33.2 R415.1 SPK1.4
SPKR_R+_SNB: C243.1 R415.2
SPKR_R-_C: C256.1 L34.2 R419.1 SPK1.3
SPKR_R-_SNB: C263.1 R419.2
SST_HOLDJ_1: R576.2 R1737.2 SPI1.7 SRCON1.7
SST_HOLDJ_1_R: CPU1.BA7 R576.1
SSTCMP: R45.1 U120.11
SSTCMP_1: C5.1 R45.2
STATUS: R61.1 U120.8
SUS_LED_GREEN_C: PWRCN1.7 Q68.D R729.2 R730.2
SUS_LED_GREEN_C2: R730.1 R735.2
SUSCLK_32_APU: CPU1.AG7 R1934.2
SUSCLK_32_APU_C: R1710.1 R1873.1 R1874.2 R1934.1
SUSCLK_NGFF: NGFF1.50 R1710.2
SVC_VDD: PU4601.5 R1629.1 R1902.2
SVC_VDD_GFX: PU5407.5 R1994.2 R1999.1
SVD_VDD: PU4601.3 R1631.1 R1903.2
SVD_VDD_GFX: PU5407.3 R1995.2 R2001.1
SVT_VDD: PU4601.4 R1901.2
SVT_VDD_GFX: PU5407.4 R1993.2
SW_ON_N_SIO: R364.2 R375.1 U109.69
SWR_LX: L2.2 U26.17
SWR_V12: C295.1 C296.1 C297.1 C299.2 L2.1 U26.11 U26.15 U26.43
SYNC: TP24.1 U21.11
SYS_3VSB: R371.1 U109.67
SYS_FAN_TACH1_1: FANC3.3 R76.2 R80.2
SYS_FAN_TACH1_2: R73.2 R74.2 R76.1
SYS_PRES: BAT2.7B R79647.2
SYS_PWRGD: CPU1.BC9 Q79.D R124.2 R1657.1 R2028.2
SYS_PWRGD_G: Q78.D Q79.G R717.2
SYS_PWRGD_HV: Q14.G Q1209.D R119.2
SYS_PWRGD_HV_1: Q1208.C Q1209.G R118.1
SYS_PWRGD_HV_2: C67.1 Q1208.B R124.1
SYSTEM_FAN_PWM1_1: D1.A FANC3.4 R68.2 R71.2
T_DP_BLON: CPU1.G5 TP174.1
T_DP_DIGON: CPU1.G6 TP6.1
TCK: TP4130.1 U4101.27
TDI: TP4128.1 U4101.25
TDO: TP4127.1 U4101.24
TEMPIN0: CPU1.E15 TP192.1
TEMPIN1: CPU1.E14 TP193.1
TEMPIN2: CPU1.E12 TP194.1
TEMPINR: CPU1.F14 TP195.1
TEST18_M: CPU1.A14 R1608.1 R1748.2
TEST19_M: CPU1.B14 R1609.1 R1747.2
TMS: TP4129.1 U4101.26
TP_DET: R1785.2 TOUCH1.1 U109.118
TP_NGFF_COEX1: NGFF1.48 TP39.1
TP_NGFF_COEX2: NGFF1.46 TP38.1
TP_NGFF_COEX3: NGFF1.44 TP196.1
TP_NGFF_LED1: NGFF1.6 TP63.1
TP_NGFF_LED2: NGFF1.16 TP64.1
TP_NGFF_MLDIR: NGFF1.17 TP62.1
TPA3131_BSNL: C228.1 U21.19
TPA3131_BSNR: C229.1 U21.22
TPA3131_BSPL: C224.1 U21.15
TPA3131_BSPR: C223.1 U21.26
TPA3131_FAULT#: R383.2 U21.30
TPA3131_GAIN: R358.1 R361.2 U21.3
TPA3131_GVDD: C192.1 R357.2 R361.1 U21.2
TPA3131_LINN: C200.2 U21.5
TPA3131_LINN_1: C200.1 R346.2
TPA3131_MUTE: R360.1 R638.2 U21.7
TPA3131_PLIMIT: C193.1 R347.2 R357.1 U21.1
TPA3131_RINN: C198.2 U21.32
TPA3131_RINN_1: C198.1 R344.2
TPA3131_SD: Q63.3 Q64.G R638.1 R639.2
TPA3131_SD1#: C521.1 Q64.D R383.1 R643.2 U21.29
UART0_RXD: CN1.2 U902.A9
UART0_TXD: CN1.1 U902.A10
USB3_TX2_EMI_DN: C91.2 L4.1
USB3_TX2_EMI_DP: C1757.2 L4.4
USB3_TX3_EMI_DN: C113.2 L56.1
USB3_TX3_EMI_DP: C111.2 L56.4
USB30_RXN2: CPU1.Y7 L5.1
USB30_RXN3: CPU1.AB6 L57.1
USB30_RXP2: CPU1.Y6 L5.4
USB30_RXP3: CPU1.AB5 L57.4
USB30_TXN2: C91.1 CPU1.AC2
USB30_TXN3: C113.1 CPU1.AC3
USB30_TXP2: C1757.1 CPU1.AC1
USB30_TXP3: C111.1 CPU1.AC4
USB_COMP_M: CPU1.AP5 R1648.1
USB_EN: C249.1 C1764.2 Q43.4 R1783.2
USB_EN1: Q1217.2 Q1217.3 R1780.2 R1781.1
USB_EN2: Q1217.6 R1777.2 R1779.1 R1783.1
USB_PCH_DN3_NN: C1774.1 TOUCH1.4 TR9.3
USB_PCH_DN4_NN: TR1.2 WEBCM1.2
USB_PCH_DN5_NN: NGFF1.5 TR12.3
USB_PCH_DP3_PP: C1773.1 TOUCH1.3 TR9.2
USB_PCH_DP4_PP: TR1.3 WEBCM1.1
USB_PCH_DP5_PP: NGFF1.3 TR12.2
USBCLK_TP: CPU1.AP8 R2067.1
USBOC01*: C589.1 CPU1.AH9 R762.1 R1725.2
USBOC02*: C1756.1 CPU1.AG1 R1727.1 R1728.2
USBP0N_EXT: D24.6 TR10.2 USB3.2
USBP0P_EXT: D24.1 TR10.3 USB3.3
USBP1N_EXT: D24.3 TR14.2 USB4.2
USBP1P_EXT: D24.4 TR14.3 USB4.3
USBP6N_EXT: D4.1 SSUSB1.2 TR3.3
USBP6P_EXT: D4.6 SSUSB1.3 TR3.2
USBP7N_EXT: D4.3 SSUSB2.2 TR4.3
USBP7P_EXT: D4.4 SSUSB2.3 TR4.2
USBSS_CALRN: CPU1.AD2 R1649.1
USBSS_CALRP: CPU1.AD1 R559.1
USBVCC01: C1747.1 C1748.2 C1752.2 C1754.2 C1755.1 D24.5 F12.2 L55.2 R1725.1 TC7.1 USB3.1 USB4.1
USBVCC01_E: C872.1 L55.1
USBVCC23: C104.1 C105.2 C106.1 C1753.2 D4.5 F14.2 R1728.1 SSUSB1.1 SSUSB2.1 TC8.1
USBVCCTP: C592.1 F15.2 TOUCH1.5
V_0P675_S3: C1724.1 C1732.1 C1971.1 C1977.1 DIMM1.203 DIMM1.204 DIMM2.203 DIMM2.204 PR5018.2 PR5019.2
V_1P5_HDMI: C3366.1 C3376.2 C3377.1 C3378.1 C3381.2 C3382.1 C3383.1 R2081.1 R79649.1 U118.12 U118.19 U118.20 U118.31 U118.40 U119.2
V_1P05_LAN: C202.1 C204.1 C213.1 C570.1 C574.1 C580.1 C583.1 C584.1 C1801.1 U16.3 U16.8 U16.22 U16.24 U16.30
V_1P5_PWR: PC5244.1 PC5246.1 PC5248.1 PR5291.2 PR5293.2 PR5296.2 PU5206.3 PU5206.4
V_1P8_VDDIO: PC5247.1 PR5290.2 PU5206.5 PU5206.9
V_3_CARD_BD: C72.1 C73.2 C74.2 C75.1 F6.1 MEMCD1.4 R79655.1
V_3P0_BAT_VREG: C99.1 C100.1 C1737.2 D23.3 PU4.3 R322.2
V_3P3_A: C550.2 C1699.1 C1820.2 C1824.1 C1826.2 C1830.1 C6725.2 L60.2 PC4909.1 PG4902.2 PL4903.1 PR190.2 PR4425.1 PR4426.1 PR4427.1 PR4450.2 PR4805.1 PR5273.1 PR5278.1 PR5281.1 PR5286.2 PR5289.1 PR5431.1 PT4902.1 Q9649.S R276.1 R319.1 R353.1 R639.1 R643.1 R644.2 R645.2 R650.2 R655.2 R668.2 R675.2 R702.1 R1186.2 R1672.2 R1760.1 R1823.2 R1824.2 R2018.2 R79687.2 R79688.2 R79707.1 R80212.2 R80217.1 R80228.2 U7.8 U52.6 U52.7 U54.6 U54.7 U109.1 U109.32 U109.64
V_3P3_LAN: C84.1 C209.1 C572.1 C587.1 C1802.1 C1803.1 C1804.1 C1806.1 C1807.1 C3453.1 C3454.1 Q44.D R1816.1 R1819.1 R79618.1 U10.5 U11.5 U12.5 U16.11 U16.23 U16.32
V_3P3_PCIVAUX: C1742.1 C1743.1 C1744.1 C1745.1 NGFF1.2 NGFF1.4 NGFF1.72 NGFF1.74 Q1211.D Q1229.G R1.1 R1707.1 R1708.2 R1932.1 TC1.1
V_5_CODEC: C146.1 C147.2 C450.1 L19.1 U6.39
V_5_LCD1: L1.1 U1.4
V_5_LCD2: F2.1 L1.2 R8.2
V_5HDD: C109.1 C110.1 C112.1 R183.2 R185.2 SATAP1.1 SATAP1.3
V_5P0_A: C1698.1 C1829.1 D21.K L19.2 PC4910.1 PG4903.1 PL4904.2 PT4903.1 Q43.5 Q43.6 Q43.7 Q43.8 R79708.1 U52.1 U52.2 U52.4 U54.1 U54.2 U54.4 U9001.4
V_5P0_HDMI_CONN: C721.2 HDMI1.18 HDMI2.2 L46.1
V_5P0_HDMI_CONN_L: F13.2 L46.2
V_19_INV: C3459.1 C3460.1 F16.2 L61.1 R5.1 R79631.2
V_VCORE_EN: PU4601.9 Q51.D R508.2
VBYP_2: PU5201.3 R79708.2
VCORE_PWROK: PR5466.2 PU4601.2 R1623.2 R1904.2
VOUT_INV: C36.1 C37.1 C38.1 C39.1 C40.1 CONVT1.3 CONVT1.4 D32.K U120.18
VR_HOT: PR24.1 PU4601.13
VREF: C4.2 U120.2
VREF_1: C140.1 U6.41
VREG_PCIAUX_PCH: Q3.D Q128.C R10.2 R13.1
VREG_PCIAUX_PCH_1: C1616.1 PC1.2 Q1211.G R13.2
VRP: C155.1 U6.38
WAKE_N: R137.1 R1654.1 R1718.1 R1719.2 U16.21
WAKE_N_APU: CPU1.AG2 R1654.2
WEBCAM_DET: PC126.2 R12.2 U109.114 WEBCM1.7
WR2_EN: R90064.1 R90065.2 U902.J2
X32K_X1: C57.1 CPU1.AT1 R1671.1 X2.1
X32K_X2: C58.1 CPU1.AT2 R1671.2 X2.4
X48M_X1: C52.1 CPU1.T2 R113.1 X1.3
X48M_X2: C50.1 CPU1.T1 R113.2 X1.1
XRF_TDC2: C3452.1 XF1.9 XF1.10 XF2.9 XF2.10

Pads without a net: BAT2 1A 2A 3A 4A 5A 6A 7A 8A 9A 10A; CPU1 A6 A7 A21 A22 A23 AA1 AA2 AA3 AA4 AB25 AB26 AB28 AB29 AD26 AD27 AE25 AE26 AE28 AE29 AG24 AG26 AG27 AG29 AH25 AH26 AH28 AH29 AK26 AK27 AK29 AL25 AL26 AL28 AL29 AN1 AN2 AN26 AN27 AN29 AP9 AP24 AP25 AP26 AP28 AP29 AR11 AR20 AR22 AR23 AR26 AR27 AR29 AT11 AT20 AT23 AT25 AU1 AU2 AU7 AU12 AU22 AU25 AU26 AU28 AU29 AV5 AV8 AV11 AV20 AV22 AV23 AV26 AV27 AV29 AW8 AW9 AW20 AW23 AW25 AW26 AW27 AY9 AY19 AY21 B1 B6 B7 B20 B21 B22 B23 BA21 BA23 BB20 BB21 BB22 BB23 BC21 BC22 BC23 C1 C7 C9 C21 C23 D1 D2 D7 D9 D21 D23 E9 E17 E19 E20 E22 E23 E25 E26 E27 F17 F20 F23 F26 F27 F29 G1 G2 G3 G4 G9 G19 G22 G25 G27 G28 G29 H1 H2 H9 H17 H19 H20 H22 H23 H25 J3 J4 J6 J7 J17 J20 J23 J26 J27 J29 K5 K6 K8 K9 K18 K21 K25 K26 K28 K29 L9 L10 L26 L27 L29 M32 M33 N1 N2 N25 N26 N28 N29 N30 N31 N32 N33 P27 P29 P32 R1 R2 R30 R31 R32 R33 T8 T9 T25 T26 T28 T29 U9 U10 U26 U27 U29 W1 W2 W5 W6 W8 W9 W25 W26 W28 W29 Y1 Y2 Y26 Y27 Y29; DIMM1 77 122 125; DIMM2 77 122 125; HDMI1 13 14; HDMI2 6 7; LPC1 10; NGFF1 64; PU5 5 7 8; PU4601 27; PU5407 8 14 16 18 21 22 27 34 35 36 37; Q6703 7; Q6704 7; RN13 4 5; RN4301 1 8; TOUCH1 6 7; U6 15 16 17 34 37 45 46; U12 3; U109 108 120; U117 5 6; U902 A3 A4 A5 A6 A7 B3 B4 B5 B6 C4 C9 C10 D9 D10 E9 E10 H3 K1 K4 K7 K10; U903 A1 A2 A7 A8 A9 A10 A11 A12 A13 A14 B1 B7 B8 B9 B10 B11 B12 B13 B14 C1 C3 C5 C7 C8 C9 C10 C11 C12 C13 C14 D1 D2 D3 D4 D12 D13 D14 E1 E2 E3 E5 E8 E12 E13 E14 F1 F2 F3 F12 F13 F14 G1 G2 G3 G10 G12 G13 G14 H1 H2 H3 H12 H13 H14 J1 J2 J3 J12 J13 J14 K1 K2 K3 K6 K7 K12 K13 K14 L1 L2 L3 L12 L13 L14 M1 M2 M3 M7 M8 M9 M10 M11 M12 M13 M14 N1 N3 N6 N7 N8 N9 N10 N11 N12 N13 N14 P1 P2 P7 P8 P9 P10 P11 P12 P13 P14; U4101 7 8 16 18 31 40 42 43 46 54 55 57; U6701 2 3

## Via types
v1: diameter 0.762, hole 0.381, TOP to BOTTOM, 537 vias
v2: diameter 0.66, hole 0.33, TOP to BOTTOM, 813 vias
v3: diameter 0.508, hole 0.254, TOP to BOTTOM, 864 vias
v4: diameter 0.559, hole 0.305, TOP to BOTTOM, 2475 vias
v5: diameter 0.711, hole 0.356, TOP to BOTTOM, 1 via
v6: diameter 0.457, hole 0.203, TOP to BOTTOM, 16 vias
v7: diameter 0.711, hole 0.406, TOP to BOTTOM, 867 vias

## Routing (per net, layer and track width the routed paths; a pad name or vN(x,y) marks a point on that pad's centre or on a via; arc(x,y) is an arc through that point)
0.775V_TRACK_GATE: length 7.5
  BOTTOM w0.102: Q6704.4 157.71,216.22 157.44,216.48 154.72,216.48 154.53,216.28 Q6704.3 154.32,215.91 153.78,216.46 153.78,216.59 v2(153.2,217.17) 152.5,216.47 R4707.2
3V_5V_POK: length 245.5
  TOP w0.102: v4(105.11,7.43) PC96.1 ; PC96.1 PR190.1 ; PC96.1 105.95,8.45 R1762.1 ; v4(27.08,141.4) 27.04,141.4 26.8,141.63 24.63,141.63 R31.2
  L3 w0.127: v4(37.15,82.21) 37.15,77.04 43.62,70.56 61.14,70.56 63.49,72.91 86.21,72.91 87.95,71.17 v4(94.13,71.17)
  L4 w0.127: v4(105.11,7.43) 105.11,8.38 102.01,11.48 102.01,29.11 96.93,34.19 96.93,39.47 93.57,42.83 93.57,44.38 92.34,45.62 92.34,54.95 91.49,55.8 91.49,60.12 94.24,62.87 94.72,62.87 95.61,63.75 v4(95.61,66.93) 95.61,68.11 94.13,69.6 v4(94.13,71.17) ; v4(37.15,82.21) 37.56,82.62 37.56,83.7 39.75,85.89 39.75,105.86 39.03,106.57 39.03,115.32 37.64,116.71 37.64,117.41 38.62,118.39 38.62,121.36 37.37,122.61 37.37,134.24 37.37,134.24 37.37,134.55 37.37,135.41 31.18,141.6 27.29,141.6 v4(27.08,141.4) 26.1,142.38 26.1,147.23 23.28,150.05 23.28,151.48 20.7,154.06 20.7,158.72 20.02,159.39 v4(20.02,160.08)
  BOTTOM w0.102: v2(20.86,160.55) 20.49,160.55 v4(20.02,160.08) ; R77.2 100.43,61.98 100.43,62.14 95.64,66.93 v4(95.61,66.93)
3V_VA: length 10.2
  TOP w0.203: v4(159.75,75.21) U6.25 ; U6.23 159.06,76.43 158.86,76.23 158.86,75.82 158.48,75.44 v4(158.02,75.44)
  BOTTOM w0.254: C485.1 160.99,77.67 161.09,77.57 v2(161.2,77.57)
  BOTTOM w0.508: v4(158.02,75.44) 158.16,75.3 L21.2 ; C483.1 159.93,75.39 v4(159.75,75.21) 159.66,75.3 L21.2 ; L21.2 158.86,76.16 C495.2 159.15,76.45 C493.1 C485.1
19V_AMP_AVCC: length 4.2
  TOP w0.305: U21.12 155.6,34.64 v1(155.71,34.74) 155.66,34.74 155.23,35.18 R376.2
  TOP w0.508: C208.1 R376.2
19V_AMP_PVCC: length 31.3
  TOP w0.305: 154.6,27.29 U21.27 ; 154.6,27.29 154.91,27.29 155.1,27.49 U21.28 ; 154.6,27.29 154.11,26.8 ; U21.14 154.6,33.89 154.85,34.14 155.1,33.89 U21.13
  TOP w0.508: v4(153.96,38.05) L10.2 ; L10.2 C545.1 153.96,35.43 154.85,34.54 154.85,34.14 ; L10.2 154.21,37.34 R376.1 ; C552.1 152.81,24.51 152.81,24.51 v4(153.2,24.51) 153.2,25.95 154.03,26.78 154.09,26.78 154.11,26.8
  BOTTOM w0.508: v4(153.2,24.51) C551.1 151.81,27.86 151.15,28.52 151.15,32.73 151.9,33.48 C543.1 v2(153.2,35.86) 153.2,37.29 v4(153.96,38.05)
+3VL: length 2.5
  TOP w0.305: v1(113.67,17.09) 113.67,17.12 113.88,17.32 114.71,17.32 115.07,16.97 115.07,16.18 PG4904.2
+5VL: length 2.7
  TOP w0.305: PG4901.2 115.4,12.18 PR4918.1 115.53,12.06 116.03,12.57 116.66,12.57 v1(116.68,12.6)
AGND: length 52.3
  TOP w0.203: v4(161.48,73.86) 161.59,73.98 U6.28 ; C140.2 167.57,79.15 167.16,78.73 167.16,78.31 166.86,78.02 166.44,78.02 166.43,78.03 U6.42 ; U6.22 158.99,76.83 158.36,76.2 v4(158.02,76.2)
  TOP w0.508: C160.2 v4(158.66,69.95) ; C268.2 83.54,38.61 C267.2 v4(84.39,39.62) ; C147.1 167.67,75.72 168.05,76.1 168.1,76.1 168.26,76.26 168.48,76.26 168.8,76.58 v4(168.82,76.58) ; LOUT1.P 77.01,40.91 LOUT1.5 ; C1491.2 157.19,79 v4(156.55,79) ; UHS1.5 174.82,73.09 ; UHS1.5 173.4,74.11 ; UHS1.5 171.98,73.09 ; C159.2 163.42,70.74 C157.2 v4(163.48,69.95) 163.25,69.72 R281.2 ; v4(165.97,67.13) 165.62,66.78 165.62,66.03 Q28.S
  BOTTOM w0.508: 73.76,36.19 LOUT1.5 ; LOUT1.5 73.76,39.13 ; LOUT1.5 74.83,37.66 ; C483.2 161.51,76.37 C493.2 ; C483.2 162.1,74.8 R301.2 ; C483.2 161.51,73.9 v4(161.48,73.86) ; v4(158.02,76.2) 158.02,76.43 158.82,77.23 C495.1 159.24,77.43 159.24,78.36 C485.2 ; LOUT1.P 80.08,41.93 ; LOUT1.P 80.08,39.89 ; LOUT1.P 78.61,40.91 ; LOUT1.P 81.55,40.91 ; v4(158.66,69.95) 159.14,69.47 R300.2 162.82,69.95 v4(163.48,69.95) ; v4(172.25,85.34) 172.63,84.96 R1193.2 ; C450.2 v4(168.56,87.05)
  vias: v2(84.62,40.51) v4(80.81,34.67) v4(86.47,3.43) v4(169.58,79.43) v4(173.52,76.81)
AVCC33_2136: length 21.3
  TOP w0.508: v4(33.47,83.31) 32.37,83.31 32.11,83.57 32.11,85.06 31.02,86.16 31.02,92.18 32.54,93.69 v4(33.63,93.69)
  BOTTOM w0.203: v4(33.63,93.69) 33.84,93.9 U26.5
  BOTTOM w0.508: C298.1 C293.1 v4(33.47,83.31) ; C298.1 33.48,81.27 C292.1 L17.2 ; C298.1 34.6,81.28 v2(34.65,81.23)
AVCC_EC: length 18.7
  TOP w0.508: L4101.2 107.35,55.31 C4102.1 107.87,55.18 107.96,55.27 108.01,55.27 v4(108.36,55.63) 109.82,55.63 R79723.1 110.33,55.69 110.9,56.26 110.9,56.34 v4(110.95,56.39)
  BOTTOM w0.203: v4(108.36,55.63) 108.11,55.63 107.45,56.28 U4101.52
  BOTTOM w0.508: v4(110.95,56.39) 110.46,56.88 110.46,58.29 110.7,58.53 110.71,58.53 112.52,60.34 112.52,61.98 112.02,62.48 v2(110.9,62.48) 109.32,62.48 R79721.1
DVCC1_O2: length 20.7
  TOP w0.076: U902.C3 71.56,103.86 71.56,105.05 v3(71.66,105.16) ; U902.H2 71.45,101.11 71.7,100.86 72.06,100.86 U902.H4 ; U902.D8 74.06,103.36 74.06,104.92 v3(73.82,105.16) ; U902.D5 72.56,103.36 72.06,103.36 U902.D3
  TOP w0.089: U902.H2 U902.G1 ; U902.C3 U902.D3 ; U902.J4 U902.H4
  TOP w0.203: U902.G1 70.67,101.47 v3(70.26,101.47) ; v6(73.34,102.08) U902.G7
  TOP w0.254: PG9001.2 59.88,98.09
  L3 w0.508: v3(71.66,105.16) v3(73.82,105.16)
  BOTTOM w1.016: v3(70.26,101.47) 70.01,101.73 69.13,101.73 64.05,96.65 v7(63.58,96.65)
  vias: v1(61.02,96.01)
DVCC1D8V: length 42.5
  TOP w0.508: R90019.2 v3(96.49,95.95) ; R90067.1 113.06,96.16 v3(112.05,97.18) ; v3(96.62,98.74) R90021.2 95.41,99 R90017.2 R90018.2 ; R90015.2 v3(94.17,107.89) ; R90020.2 R90013.2 95.22,101.92 v3(95.41,102.11) ; v3(95.47,105.35) R90014.2 R90016.2
  L4 w0.508: v3(96.49,95.95) 110.82,95.95 v3(112.05,97.18)
  BOTTOM w0.508: v3(96.49,95.95) 96.62,96.08 v3(96.62,98.74) 95.41,99.95 v2(95.41,100.76) v3(95.41,102.11) 95.47,102.17 v3(95.47,105.35) 94.17,106.65 v3(94.17,107.89)
  vias: v2(113.42,97.71) v2(119.69,97.64)
DVCC1D8V_O2:
  vias: v2(120.86,103.48)
DVCC3:
  vias: v1(118.42,107.37)
DVCC3_O2: length 63.2
  TOP w0.076: 70.45,101.93 70.52,101.86 70.91,101.86 71.06,101.86 ; 71.06,101.86 U902.F2 ; 71.06,101.86 U902.G2 ; U902.H1 70.93,101.11 71.18,100.86 71.45,100.86 71.7,100.61 U902.J3 ; v6(73.32,102.64) 73.1,102.86 72.56,102.86 U902.D4 ; U902.C6 73.06,103.86 72.7,103.86 72.56,104.01 72.56,104.9
  TOP w0.152: U902.K8 74.32,100.1 74.32,98.97 v7(74.38,98.91) ; 70.45,101.93 70.04,101.93 69.87,101.76
  TOP w0.203: U902.K5 72.5,99.8 v3(72.5,99.19) ; v3(72.56,105.92) 72.56,104.9 ; v6(73.32,102.64) 73.35,102.61 U902.E7 ; U902.H1 70.59,101.11 70.46,100.99 69.65,100.99 v3(69.5,100.84) 69.5,101.39 69.87,101.76
  TOP w0.508: R90075.1 v3(72.8,111.76) ; R90074.1 v3(85.12,110.49) ; v3(68.61,93.98) 68.61,94.17 R90046.1 ; R90056.1 v3(69.38,111.63) ; R90055.1 v3(65.95,111.63) ; R90051.1 v3(71.66,111.63)
  L4 w0.406: v6(73.32,102.64) 73.67,102.64 74.07,102.23
  L4 w0.508: 74.07,102.23 74.07,100.76 v3(72.5,99.19)
  BOTTOM w0.508: R90047.1 82.2,105.35 R90040.1 79.32,105.35 78.67,105.99 77.55,105.99 ; v3(72.8,111.76) 73.31,112.27 83.22,112.27 85,110.49 v3(85.12,110.49) ; v3(72.8,111.76) 72.56,111.51 v3(72.56,105.92) ; v3(72.8,111.76) 71.79,111.76 v3(71.66,111.63) 70.9,112.39 70.14,112.39 v3(69.38,111.63) 68.54,111.63 67.9,112.27 66.58,112.27 v3(65.95,111.63) ; v3(68.61,93.98) v3(68.61,91.8) ; v3(69.5,100.84) 69.4,100.74 69.4,99.47 70.31,98.55 71.86,98.55 v3(72.5,99.19) 72.7,98.98 73.59,98.98
  vias: v1(71.43,89.61) v1(78.14,93.95) v1(78.14,90.83) v7(78.52,95.35)
DVCC33_2136: length 72.3
  TOP w0.508: v4(37.63,98.59) 36.15,97.12 36.15,94.16 34.02,92.02 v4(33.56,92.02) 33.36,92.02 32.67,91.33 32.67,89.28 33.64,88.32 33.64,88.31 35.97,85.98 35.97,81.48 v4(34.93,80.44) ; v4(34.58,76.96) 35.36,76.17 51.14,76.17 53.18,74.13 R69.1 53.88,73.66 54.26,74.04 56.06,74.04 56.8,73.3 R54.1
  L3 w0.508: v4(34.93,80.44) 34.91,80.44 34.2,79.72 34.2,77.22 34.45,76.96 v4(34.58,76.96)
  BOTTOM w0.203: v4(37.63,98.59) 37.58,98.54 U26.18 ; U26.22 39.18,98.34
  BOTTOM w0.508: 39.71,100.76 39.71,100.2 39.78,100.13 39.78,98.95 39.18,98.34 ; 39.71,100.76 38.77,101.7 C291.1 37.57,101.78 C284.1 C290.2 36.14,100.69 36.86,99.96 36.86,99.26 37.52,98.6 37.62,98.6 v4(37.63,98.59) ; 39.71,100.76 40.52,100.76 41.12,101.36 C289.1 41.21,101.64 41.21,102.82 C283.1 40.75,103.63 L16.2 ; v4(33.56,92.02) 32.94,92.02 32.43,91.52 32.37,91.52 32.04,91.19 R1074.1
GND: length 2089.7
  TOP w0.076: U902.C5 72.66,103.61 72.41,103.86 72.2,103.86 72.06,104.01 72.06,104.79 72.08,104.81 72.08,105.5 72.06,105.52 ; U902.G5 73.06,101.36 73.06,100.99 72.81,100.74 U902.J5 ; U902.F7 73.81,102.26 74.06,102.51 74.06,102.86 U902.D7 ; U902.K9 74.81,100.23 74.56,100.48 74.56,100.53 74.56,100.76 74.45,100.86 74.06,100.86 U902.J7
  TOP w0.089: v3(76.36,104.39) 76.08,104.11 U902.B10 ; v3(110.02,97.97) 110.02,98.96 U903.N2
  TOP w0.127: v6(105.28,100.88) 105.27,100.87 105.27,100.7 U903.C4 ; U903.A6 103.41,101.21 103.14,101.47 v3(103.11,101.47) ; U903.N5 U903.P6
  TOP w0.152: U902.K9 74.81,99.92 75.75,98.98 v3(75.75,98.91)
  TOP w0.203: U902.D7 U902.D6 U902.C5 ; v4(132.74,36.43) 132.74,37.01 132.94,37.21 U118.15 ; U118.8 133.74,36.57 v4(132.74,35.57) ; PU5001.14 144.46,78.76 v4(144.68,78.55) ; U902.A2 U902.A1 70.81,104.74 70.52,105.03 v3(70.39,105.03) ; v3(71.66,105.92) 72.06,105.52 ; v4(139.35,79.63) 139.82,79.16 PU5001.1 ; PU5201.5 109.07,64.52 v4(109.13,64.57) 108.78,64.92 PU5201.6 ; PU5201.14 104.34,63.72 104.22,63.6 v4(104.17,63.6) ; PU5001.3 139.61,78.36 v4(139.35,78.11) ; U118.35 132.54,34.04 132.74,34.24 v4(132.74,34.71) ; U109.71 143.87,56.38 v4(145.07,55.18) ; v3(71.41,99.31) 71.41,99.69 71.81,100.1 U902.K3 ; U902.J1 v3(70.09,99.89) ; U109.35 156.06,59.45 156.17,59.33 156.47,59.33 156.88,58.93 156.88,58.91 v4(156.94,58.85) ; U52.11 v4(145.63,7.04) ; U109.4 v4(157.11,47.58) ; U54.11 v4(90.33,11.81)
  TOP w0.25: v3(71.9,176.2) CPU1.H4 72.9,175.8 CPU1.J5 ; CPU1.AK4 71.91,158.6 v3(71.9,158.58) ; v3(85.55,147.96) 85.55,148.35 CPU1.BC20 ; CPU1.AV30 93.2,152.5 v3(92.99,152.5) ; v3(76.4,178.2) 76.7,177.9 CPU1.F9 ; CPU1.BC24 88.6,148.5 88.55,148.45 88.55,147.55 v3(88.6,147.5) ; CPU1.V4 CPU1.V2 CPU1.V1 70.26,168.2 v3(69.99,168.2) ; v3(90.64,179.93) 90.63,179.93 CPU1.D26 ; v3(74.2,149.9) CPU1.AY6 ; CPU1.AF4 72.02,161.8 v3(71.77,162.05) ; CPU1.AT30 93.97,153.8 94.09,153.68 v3(94.09,153.68) ; v3(75.8,147.6) 75.8,147.6 CPU1.BC8 ; CPU1.BC28 91.8,148.47 91.8,148.46 91.8,147.6 v3(91.9,147.5) ; v3(71.94,160.22) 71.96,160.22 71.98,160.2 CPU1.AH4 ; v3(72.6,149.96) 72.6,150.04 CPU1.AY4 ; CPU1.AY16 82.2,149.99 v3(81.97,149.76) ; v3(94.13,155.4) 94.13,155.4 CPU1.AP30 ; CPU1.AT4 v3(71.9,153.8) ; CPU1.F4 v3(71.83,177.8) CPU1.F2 ; CPU1.AV33 95.58,152.28 v3(96.03,152.28) ; CPU1.K1 70.5,174.6 71.3,174.6 CPU1.K2 ; CPU1.AF1 69.52,161.8 v3(69.51,161.79) ; v3(70.01,171.58) 70.19,171.4 CPU1.P1 CPU1.P2 CPU1.P4 72.9,171 CPU1.P5 ; CPU1.AK1 v3(69.6,158.6) ; v3(96.01,171.4) CPU1.P33 ; v3(94.05,174.25) 94.02,174.27 94.02,174.27 93.69,174.6 CPU1.K30 ; CPU1.B33 96.03,181.13 96.86,181.13 96.96,181.23 v3(96.96,181.33) ; CPU1.AY12 v3(79,149.9) ; CPU1.BC32 95.39,147.71 95.4,147.7 v3(95.54,147.7) ; v3(93.9,178.24) 93.5,177.84 CPU1.F30 ; v3(93.75,179.99) 93.7,179.94 93.7,179.8 CPU1.D30 ; CPU1.AV25 88.73,152.1 88.4,151.77 88.4,150.7 CPU1.AY24 ; CPU1.L5 72.9,173.4 CPU1.M4 72.1,173 71.89,173.21 v3(71.89,173.27) ; CPU1.F33 95.59,177.71 v3(96.3,177.71) ; CPU1.T30 v3(94.1,169.8) ; v3(82.31,147.83) 82.2,147.94 CPU1.BC16 ; CPU1.AY30 93.85,150.95 v3(93.88,150.95) ; CPU1.Y5 72.93,165.83 72.93,165.43 CPU1.AB4 72.3,165 72.28,165.01 v3(71.9,165.01) 71.35,165.01 71.34,165 CPU1.AB2 71.26,165 71.23,165.03 70.53,165.03 CPU1.AB1 ; CPU1.AY10 v3(77.4,149.9) ; CPU1.AY20 v3(85.4,149.91) ; v3(71.89,163.41) 71.89,163.4 CPU1.AD4 ; CPU1.AP1 v3(69.6,155.4) ; v3(88.42,182.4) 88.6,182.22 CPU1.A24 ; CPU1.AP33 v3(96.5,155.4) ; CPU1.K33 95.67,174.43 v3(95.98,174.43) ; v3(69.99,177.8) CPU1.F1 ; v3(71.97,157) CPU1.AM4 ; CPU1.BC12 v3(79,147.6) ; CPU1.AY28 v3(91.8,149.9) ; v3(90.2,149.82) CPU1.AY26
  TOP w0.254: U903.J5 107.77,101.33 107.5,101.6 107.07,101.6 ; v3(111.03,101.57) 110.66,101.21 U903.P6 ; U903.G5 106.77,101.3 v3(106.81,101.35) 107.07,101.6 ; CPU1.AP1 CPU1.AP2 CPU1.AP4 ; v3(91.72,182.68) 91.8,182.6 91.8,181.54 CPU1.A28 ; v3(95.14,182.82) 95.14,182.13 95,181.99 CPU1.A32 ; CPU1.BC4 v3(72.6,147.12) ; 107.07,101.6 107.67,102.21 U903.K8 ; CPU1.A12 v3(79,182.01) ; CPU1.Y5 72.9,166.2 CPU1.Y4 ; R80227.1 21.17,163.59 21.17,161.98 v4(20.86,161.67) ; v3(112.05,100.2) 112.04,100.2 110.28,100.2 U903.P4 ; PU5201.2 108.36,61.62 PC5214.2 ; U903.H10 107.27,102.97 106.84,102.54 v3(106.61,102.54) 106.61,102.11 106.21,101.71 U903.E7 ; U902.C2 U902.C1 70.28,103.61 v3(70.26,103.63) ; v3(72.1,175) 71.7,174.6 CPU1.K2 ; CPU1.A16 82.2,182.42 v3(82.11,182.51) ; CPU1.AY14 80.57,150.5 v3(80,151.06)
  TOP w0.305: v4(115.48,40.64) 115.66,40.82 HDMI2.3 HDMI1.17 ; CPU1.D14 v3(80.6,180.01) ; U21.8 v4(157.94,33.04) ; U21.21 152.1,30.36 151.85,30.61 v4(151.85,30.66) 152.05,30.86 U21.20 ; NGFF1.75 v4(109.12,223.25) ; CPU1.B12 v3(79,180.06) CPU1.D12 ; v4(137.83,187.45) 138.63,186.65 DIMM1.14 ; v3(77,157.18) 77.6,157.78 CPU1.AL10 ; v3(77,157.18) 77.58,156.6 CPU1.AN10 ; v3(77,157.18) 76.5,156.68 CPU1.AN9 76.5,156.28 v3(76.2,155.98) ; HDMI1.5 HDMI2.15 v4(115.56,34.82) ; v4(115.56,37.82) HDMI2.9 HDMI1.11 ; NGFF1.18 119.56,209 v4(119.88,209.32) ; CPU1.D8 v3(75.8,180.01) CPU1.B8 CPU1.A8 ; U21.24 151.87,28.86 v4(151.81,28.8) ; v3(73.85,153.62) 74.1,153.87 CPU1.AR6 ; v3(88.6,178.3) 88.55,178.35 88.55,179.45 CPU1.D24 ; v3(72.1,175) CPU1.K4 73.3,175.4 CPU1.J5 ; v4(157.1,34.15) 156.87,34.15 156.6,33.89 U21.10 ; v3(75.3,151.8) 75.3,151 CPU1.AY8 ; R80225.2 71.85,189.62 72.22,189.25 72.22,187.06 R1603.2 ; HDMI2.20 114.39,32.32 113.99,31.92 HDMI1.22 ; LVDS1.14 v4(43.63,96.5) ; CPU1.T4 v3(72.9,170.2) ; NGFF1.39 v4(109.12,214.25) ; v4(31.11,22.72) 31.11,22.77 30.63,23.25 PWRCN1.4 ; v4(155.35,30.61) 153.6,32.36 U21.17 ; U6701.13 80.03,68.18 v4(79.71,67.87) 79.53,68.05 U6701.12 ; CPU1.D16 v3(82.2,180.01) ; U10.2 v4(44.81,11.94) ; U6701.16 80.64,70.4 81.09,69.94 v4(81.09,69.9) U6701.15 ; C3454.2 v4(38.51,21.36) ; NGFF1.33 v4(109.12,212.75) ; CPU1.D10 77.4,179.96 77.4,179.96 v3(77.4,180.04) ; R533.2 43.26,74.09 v4(43.03,73.86) ; CPU1.P30 93.71,171.4 v4(94.01,171.7) ; NGFF1.24 v4(119.88,210.5) ; v3(71.1,180.3) CPU1.C3 CPU1.D4 ; LVDS1.7 40.04,103.5 39.25,104.29 v4(38.87,104.29) ; v3(74.2,180.04) CPU1.D6 ; CPU1.D20 v3(85.4,180.01) ; CPU1.M30 93.81,172.69 v4(93.93,172.69) ; CPU1.A20 v3(85.4,182.01) ; CPU1.V4 72.9,168.2 CPU1.U5 ; CPU1.D18 v3(83.8,180.01) ; v4(76.81,71.17) 77.98,71.17 U6701.5 ; NGFF1.57 v4(109.12,218.75) ; NGFF1.36 v4(119.88,213.5) ; NGFF1.7 v4(109.12,206.25) ; Q64.S 142.47,33.1 Q63.1 ; NGFF1.23 v4(109.12,210.25) ; NGFF1.30 v4(119.88,212) ; CPU1.AP7 74.9,155.34 v3(74.52,154.96) ; NGFF1.63 v4(109.12,220.25) ; CPU1.H30 v3(94.03,176.2) ; HDMI1.2 v4(115.56,33.32) ; NGFF1.69 v4(109.12,221.75) ; CPU1.AU5 73.3,152.69 v3(73.01,152.4) 72.81,152.2 CPU1.AV4 ; C213.2 v4(41.56,21.36) ; NGFF1.45 v4(109.12,215.75) ; U6701.10 v4(78.53,67.87) ; v3(87,180.01) CPU1.D22 ; NGFF1.29 v4(109.12,211.75) ; HDMI1.8 v4(115.56,36.32)
  TOP w0.33: DIMM2.139 148.1,146.75 148.88,145.97 v4(148.88,145.92) ; DIMM1.161 132.35,140.15 132.39,140.11 132.77,140.11 133.32,139.56 133.32,139.51 v4(133.51,139.32) ; DIMM2.55 147.8,174.35 148.56,173.59 148.56,173.55 v4(148.75,173.35) ; DIMM2.190 152.9,131.45 152.5,131.05 152.5,131 v4(152.31,130.81) ; DIMM2.145 149.26,144.95 150.21,144 150.21,143.95 v4(150.4,143.76) ; v4(133.51,130.81) 133.51,130.86 132.62,131.75 DIMM1.189 ; DIMM1.26 138.09,183.05 138.07,183.07 137.59,183.07 137.26,182.74 137.26,182.69 v4(137.07,182.5) ; DIMM1.184 137.63,133.25 137.26,133.62 137.26,133.67 v4(137.07,133.86) ; DIMM1.49 132.24,176.15 132.3,176.09 132.99,176.09 133.32,175.75 133.32,175.7 v4(133.51,175.51) ; v4(152.31,129.03) 152.5,129.22 152.5,129.27 152.88,129.65 DIMM2.196 ; v4(152.31,133.86) 152.38,133.98 153.45,135.05 DIMM2.178 ; v4(133.51,187.45) 133.51,187.55 132.91,188.15 DIMM1.9 ; v4(152.31,140.97) 152.5,141.16 152.5,141.21 152.83,141.54 153.52,141.54 153.62,141.65 DIMM2.156 ; DIMM2.134 153.06,148.25 152.5,147.68 152.5,147.64 v4(152.31,147.45) ; v4(152.31,173.61) 152.31,173.66 153.17,174.52 153.43,174.52 153.55,174.65 DIMM2.54 ; DIMM2.72 153.49,169.25 153.43,169.19 151.6,169.19 150.97,169.82 150.97,169.86 v4(150.78,170.05) 149.92,169.19 147.63,169.19 147.27,169.55 DIMM2.71 ; v4(150.78,189.36) 150.97,189.55 150.97,189.59 151.63,190.25 DIMM2.2 ; DIMM1.54 137.47,174.65 137.07,174.24 v4(137.07,173.48) ; DIMM2.60 153.66,172.85 152.94,172.13 v4(152.94,171.83) ; DIMM2.167 147.54,138.35 147.99,137.9 v4(147.99,137.54) ; DIMM2.172 153.22,136.85 152.5,136.13 152.5,136.08 v4(152.31,135.89) ; DIMM1.60 138.47,172.85 137.83,172.21 v4(137.83,171.96) ; v4(148.75,184.28) 148.75,184.4 148,185.15 DIMM2.19 ; v4(150.02,182.5) 149.99,182.47 149.99,182.4 149.88,182.28 149.88,182.26 149.55,181.93 149.52,181.93 149.27,181.67 147.75,181.67 147.63,181.55 DIMM2.31 ; DIMM1.3 133.2,189.95 133.51,189.64 v4(133.51,189.36) ; v4(148.75,133.86) 148.75,134.37 148.37,134.75 DIMM2.179 ; DIMM2.155 145.1,141.95 v4(144.89,142.16) ; v4(133.51,132.33) 133.32,132.52 133.32,132.57 132.94,132.95 DIMM1.185 ; DIMM2.48 153.12,176.45 152.31,175.64 v4(152.31,175.51) ; DIMM2.3 148.2,189.95 148.75,189.4 v4(148.75,189.36) ; v4(150.78,182.5) 150.76,182.52 150.76,182.91 150.38,183.29 150.31,183.35 DIMM2.25 ; v4(137.07,177.16) 137.26,177.36 137.26,177.4 137.59,177.74 138.07,177.74 138.15,177.65 DIMM1.44 ; DIMM2.185 148.26,132.95 148.75,132.46 v4(148.75,132.08) 148.56,131.89 148.56,131.84 148.22,131.51 147.75,131.51 147.51,131.75 DIMM2.189 ; v4(137.07,175.51) 137.26,175.7 137.26,175.75 137.95,176.45 DIMM1.48 ; DIMM1.13 132.44,186.95 132.49,186.91 132.58,186.91 133.51,185.97 v4(133.51,185.93) ; v4(137.07,178.69) 137.07,179.01 137.51,179.45 DIMM1.38 ; v4(133.64,183.9) 133.64,183.94 132.86,184.72 132.51,184.72 132.08,185.15 DIMM1.19 ; v4(152.31,184.15) 152.5,184.34 152.5,184.39 152.96,184.85 DIMM2.20 ; v4(152.31,189.36) 152.5,189.17 152.5,189.12 153.17,188.45 DIMM2.8 ; DIMM1.2 136.39,190.25 135.54,189.4 v4(135.54,189.36) ; DIMM2.161 147.84,140.15 148.88,139.11 v4(148.88,139.06) ; DIMM2.128 153.43,150.05 152.83,150.05 152.38,149.59 v4(152.31,149.48) ; DIMM1.61 132.97,172.55 133.51,172 v4(133.51,171.96) ; v4(152.31,139.06) 152.5,139.26 152.5,139.3 153.04,139.85 DIMM2.162 ; v4(148.01,128.6) 147.99,128.62 147.99,129.15 147.18,129.95 DIMM2.195 ; v4(137.07,139.32) 137.26,139.51 137.26,139.56 137.59,139.89 138.07,139.89 138.11,139.85 DIMM1.162 ; v4(135.54,185.93) 135.73,185.74 135.73,185.69 136.57,184.85 DIMM1.20 ; DIMM1.145 132.88,144.95 133.51,144.32 v4(133.51,143.89) ; v4(148.75,149.61) 148.75,149.73 148.13,150.35 DIMM2.127 ; v4(152.31,178.82) 152.5,179.01 152.5,179.05 152.89,179.45 DIMM2.38 ; v4(137.83,128.91) 138.45,129.65 DIMM1.196 ; v4(147.99,177.16) 147.2,177.95 DIMM2.43 ; DIMM2.61 147.57,172.55 147.63,172.49 148.14,172.49 148.75,171.88 v4(148.75,171.83) ; DIMM2.13 147.65,186.95 147.72,186.88 147.97,186.88 148.56,186.29 148.56,186.25 v4(148.75,186.06) ; DIMM2.65 147.5,171.35 148.75,170.1 v4(148.75,170.05) ; DIMM1.128 138.07,150.05 138.07,150.05 137.59,150.05 137.19,149.65 137.19,149.61 v4(137.07,149.48) ; v4(153.07,142.62) 153.07,142.86 153.66,143.45 DIMM2.150 ; v4(135.54,133.86) 135.73,134.05 135.73,134.09 136.69,135.05 DIMM1.178 ; DIMM2.133 147.33,148.55 147.52,148.74 149.15,148.74 150.21,147.68 150.21,147.64 v4(150.4,147.45) ; v4(137.07,189.36) 137.26,189.17 137.26,189.12 137.7,188.68 138.13,188.68 138.36,188.45 DIMM1.8 ; v4(152.31,170.05) 152.31,170.35 152.7,170.75 153.39,170.75 153.69,171.05 DIMM2.66 ; DIMM1.144 137.69,145.25 137.26,145.69 137.26,145.73 v4(137.07,145.92) ; DIMM1.155 132.14,141.95 132.37,141.72 132.8,141.72 133.51,141.02 v4(133.51,140.97) ; v4(148.75,178.95) 148.75,179.2 148.24,179.71 147.23,179.71 147.18,179.75 DIMM2.37 ; v4(148.75,135.89) 148.56,136.08 148.56,136.13 148.22,136.46 147.43,136.46 147.34,136.55 DIMM2.173 ; v4(152.31,137.54) 152.5,137.73 152.5,137.78 152.83,138.11 153.31,138.11 153.37,138.05 DIMM2.168 ; v4(132.88,148.03) 132.53,148.03 132.08,148.47 132.03,148.55 DIMM1.133 ; DIMM2.9 147.72,188.15 148.2,188.15 148.75,187.6 v4(148.75,187.45) ; v4(152.31,186.06) 152.31,186.1 152.85,186.65 DIMM2.14 ; DIMM1.150 138.2,143.45 138.07,143.32 137.59,143.32 137.26,143.65 137.26,143.7 v4(137.07,143.89) ; DIMM1.65 132.59,171.35 133.51,170.43 v4(133.51,170.31) ; v4(132.75,177.16) 132.75,177.19 131.98,177.95 DIMM1.43 ; v4(148.75,175.51) 148.75,175.64 148.31,176.09 147.54,176.09 147.48,176.15 DIMM2.49 ; DIMM1.151 132.27,143.15 132.48,142.94 132.98,142.94 133.51,142.41 v4(133.51,142.37) ; v4(135.03,139.32) 134.84,139.13 134.84,139.08 134.13,138.37 132.3,138.37 132.28,138.35 DIMM1.167 ; v4(152.31,144.15) 152.5,144.34 152.5,144.38 152.83,144.72 153.08,144.72 153.62,145.25 DIMM2.144 ; v4(151.53,132.05) 151.72,132.24 151.72,132.32 152.4,132.99 153.43,132.99 153.68,133.25 DIMM2.184 ; v4(133.51,173.48) 133.54,173.51 133.54,173.86 133.05,174.35 DIMM1.55 ; DIMM1.25 132.14,183.35 132.75,182.75 v4(132.75,182.5) ; v4(152.31,145.92) 152.5,146.11 152.5,146.16 153.21,146.88 153.31,146.88 153.48,147.05 DIMM2.138 ; v4(152.31,180.72) 152.31,180.97 152.62,181.29 153.31,181.29 153.35,181.25 DIMM2.32 ; DIMM2.44 153.39,177.65 153.31,177.74 152.83,177.74 152.5,177.4 152.5,177.36 v4(152.31,177.16) ; DIMM1.156 138.56,141.65 138.46,141.54 137.59,141.54 137.26,141.21 137.26,141.16 v4(137.07,140.97) ; DIMM1.138 138.11,147.05 138.07,147 137.59,147 137.26,147.34 137.26,147.38 v4(137.07,147.57) 137.26,147.76 137.26,147.81 137.69,148.25 DIMM1.134 ; DIMM1.173 131.99,136.55 132.65,135.89 v4(132.88,135.89) ; v4(136.3,137.29) 136.3,137.33 137.12,138.15 138.19,138.15 138.29,138.05 DIMM1.168 ; DIMM1.37 132.7,179.75 133.51,178.94 v4(133.51,178.69) ; v4(133.51,129.03) 133.32,129.22 133.32,129.27 132.99,129.6 132.94,129.6 132.6,129.95 132.39,129.95 132.39,129.95 DIMM1.195 ; DIMM1.71 132.28,169.55 132.39,169.44 134.22,169.44 135.03,170.26 v4(135.03,170.31) 136.09,169.25 DIMM1.72 ; DIMM1.179 132.14,134.75 132.37,134.52 132.74,134.52 132.77,134.49 133.05,134.49 133.64,133.9 v4(133.64,133.86) ; DIMM2.26 153.33,183.05 153.31,183.07 152.55,183.07 152.31,182.83 v4(152.31,182.5) ; v4(133.51,180.72) 133.51,180.77 132.95,181.33 132.39,181.33 132.17,181.55 DIMM1.31 ; v4(133.51,145.92) 133.51,145.97 132.98,146.49 132.3,146.49 132.05,146.75 DIMM1.139 ; v4(137.83,130.81) 138.27,131.25 138.28,131.25 138.47,131.45 DIMM1.190 ; DIMM1.66 138.45,171.05 138.28,170.88 137.38,170.88 137.07,170.56 v4(137.07,170.31) ; v4(133.51,149.48) 133.51,149.53 132.69,150.35 DIMM1.127 ; DIMM1.172 138.27,136.85 v4(137.83,137.29) ; v4(148.88,142.49) 148.69,142.68 148.69,142.73 148.27,143.15 DIMM2.151 ; v4(137.07,180.72) 137.07,180.85 137.47,181.25 137.55,181.25 137.59,181.29 138.07,181.29 138.11,181.25 DIMM1.32
  TOP w0.356: CPU1.F22 86.4,177.9 v3(86,177.5) 85.6,177.1 CPU1.G20 ; v3(79.4,174) CPU1.L12 CPU1.N13 v3(79.4,171.6) CPU1.P12 CPU1.T13 v3(79.4,169.2) CPU1.U12 ; CPU1.N27 90.71,172.59 v3(90.71,172.64) ; CPU1.L24 v3(88.95,173.95) ; CPU1.L25 89.5,173.6 v3(89.9,174) ; v3(88.25,153.31) 87.83,152.9 CPU1.AU23 ; CPU1.AR25 88.8,154.5 v3(88.4,154.1) ; CPU1.J22 87.2,174.9 CPU1.K22 v3(86.6,174) CPU1.L21 CPU1.N22 v3(86.6,171.6) CPU1.P21 CPU1.T22 v3(86.6,169.2) CPU1.U21 ; CPU1.K27 91.1,174.8 v3(91.5,175.2) ; CPU1.AT22 86.8,153.7 87.21,153.29 v3(87.38,153.29) ; v3(84.2,162) CPU1.AG18 CPU1.AH19 v3(84.2,159.73) CPU1.AK18 ; CPU1.G26 v3(89.8,177.5) ; CPU1.AL16 CPU1.AK15 v3(81.8,159.73) CPU1.AH16 CPU1.AG15 v3(81.8,162) ; v3(81.33,175.8) 81.63,175.5 CPU1.J15 ; CPU1.L28 91.9,173.6 v3(92.3,174) ; CPU1.J28 91.9,176 v3(92.3,176.4) ; CPU1.AV25 89.09,152.1 89.72,152.73 v3(89.72,153.42) ; v3(83.6,175.9) 84,175.5 CPU1.J19 ; v4(94.39,35.66) C6728.2 C6726.2 ; v3(69.39,148.81) 69.92,148.81 CPU1.BB1 ; CPU1.AB10 77.6,164.77 77.31,164.47 v3(77.31,164.41) 77.11,164.41 CPU1.AD9 76.5,163.75 76.95,163.3 v3(77.22,163.3) 77.22,163.03 77.6,162.65 CPU1.AE10 76.5,161.5 CPU1.AG9 76.5,161.3 CPU1.AH10 ; CPU1.AP27 91.35,155.15 v3(91.35,154.81) ; CPU1.AL22 CPU1.AK21 v3(86.6,159.73) CPU1.AH22 CPU1.AG21 v3(86.6,162) ; CPU1.AN18 v3(84.23,155.97) ; CPU1.AE22 CPU1.AD21 v3(86.6,164.4) CPU1.AB22 CPU1.Y21 v3(86.6,166.8) CPU1.W22 ; v3(92.3,154.8) 91.9,154.4 CPU1.AR28 ; CPU1.W16 v3(81.8,166.8) CPU1.Y15 CPU1.AB16 v3(81.8,164.4) CPU1.AD15 CPU1.AE16 ; v4(90.97,35.37) C6727.2 ; CPU1.G17 83.2,177.1 v3(83.6,177.5) 84,177.9 CPU1.F19 ; CPU1.Y24 v3(88.95,166.75) ; C6729.2 v4(95.84,35.66) ; v3(92.36,157.1) 91.9,156.64 CPU1.AN28 ; v3(84.2,174) CPU1.L18 CPU1.N19 v3(84.2,171.6) CPU1.P18 CPU1.T19 v3(84.2,169.2) CPU1.U18 ; CPU1.U24 v3(88.95,169.15) ; CPU1.AN25 89.5,156.8 v3(89.9,157.2) ; CPU1.W10 v3(77.05,167.95) ; CPU1.J25 v3(88.6,175.9) ; CPU1.AK12 v3(79.4,159.73) CPU1.AH13 ; CPU1.AP22 86.65,155.95 v3(86.65,155.96) 86.64,155.96 CPU1.AN21 ; v3(96.4,148.67) 96.39,148.68 96.39,148.69 96.08,149 CPU1.BB33 ; CPU1.AE13 CPU1.AD12 v3(79.4,164.4) CPU1.AB13 CPU1.Y12 v3(79.4,166.8) CPU1.W13 ; v3(77.07,168.94) 77.07,169.27 CPU1.T10 ; CPU1.AT19 84.6,153.3 v3(84.8,153.3) 85,153.3 CPU1.AU20 ; CPU1.W19 v3(84.2,166.8) CPU1.Y18 CPU1.AB19 v3(84.2,164.4) CPU1.AD18 CPU1.AE19 ; CPU1.AL19 84.2,158.4 ; v3(80,152.5) 79.8,152.5 CPU1.AV12 78.6,152.9 CPU1.AU11 ; CPU1.AV15 81.4,152.5 v3(81.2,152.5) 80.8,152.9 CPU1.AU14 ; CPU1.AG12 v3(79.4,162) ; CPU1.F25 v3(88.6,178.3) ; v3(87,149.94) CPU1.AY22 87,150.9 CPU1.AW22 ; v3(91.5,153.6) 91.1,153.2 CPU1.AU27 ; v3(81.8,174) CPU1.L15 CPU1.N16 v3(81.8,171.6) CPU1.P15 CPU1.T16 v3(81.8,169.2) CPU1.U15 ; CPU1.G23 v3(87.4,177.5) ; CPU1.AN15 v3(80.6,156)
  TOP w0.38: v3(77.6,151.79) 77.6,151.8 77.3,152.1 CPU1.AV9 76.5,152.6 76.4,152.6 76.1,152.9 CPU1.AU8 ; CPU1.N10 CPU1.L12 CPU1.K10 ; CPU1.AD24 v3(88.95,164.35) ; CPU1.G7 74.9,176.7 v3(74.6,176.4) ; 84.2,158.4 CPU1.AK18 ; CPU1.AV7 74.85,152.1 75.15,151.8 v3(75.3,151.8) ; CPU1.AH13 CPU1.AG12
  TOP w0.381: C6722.1 32.19,22.01 31.83,22.01 31.12,22.72 v4(31.11,22.72) ; C238.2 31.76,26.33 31.62,26.33 31.41,26.12 31.41,25.79 v4(31.15,25.53)
  TOP w0.406: Q36.4 v4(31.61,9.26) ; Q6701.4 82.73,64.95 82.42,64.64 81.82,64.64 81.42,64.25 Q6701.1 81.42,62.63 v4(81.57,62.48) ; v4(171.15,95.25) 171.03,95.38 U5.3 U5.8 ; v4(36.23,138.82) 36.81,139.4 Q65.1 ; HDMI2.23 121.28,33.78 U116.8 U116.3 ; U31.8 U31.3 120.95,37.36 HDMI2.24 ; Q18.4 58.21,140.95 v4(58.28,140.89) ; CPU1.B2 71,180.4 v3(71.1,180.3) ; R1779.2 91.81,22.11 Q1217.4 ; Q37.1 v4(135.8,58.72) ; HDMI2.25 120.74,40.89 U117.8 U117.3 ; v4(52.74,141.73) 53.67,141.73 54.19,142.26 Q18.1 ; Q65.4 38.95,141.27 39.15,141.48 v4(39.15,141.99) ; v4(133.07,55.76) 133.07,55.82 133.75,56.5 Q37.4 ; v4(47.16,37.8) 47.64,37.8 PQ5005.1 ; v4(94.34,20.04) 94.95,20.65 Q1217.1 ; PQ5005.4 49.68,39.93 v4(49.93,39.67) ; Q36.1 v4(33.48,6.49) ; U3.8 U3.3 v4(172.12,116.84)
  TOP w0.508: SPK1.5 150.09,10.73 151.21,9.6 151.21,6.93 v4(151.11,6.83) ; Q64.S 141.86,33.78 v4(140.37,33.78) ; 183,158.17 MEMCD1.15 183,160 ; R1619.2 v4(76.87,199.24) ; C6719.2 68.74,30.45 68.46,30.18 68.44,30.18 R1850.2 ; PR4630.1 v4(18.19,195.1) ; 99.61,21.86 USB4.5 98.35,22.31 ; v4(143.16,206.38) 143.35,206.57 C103.2 ; C247.2 151.16,23.37 v4(151.16,25.4) 151.16,25.53 151.67,26.04 C552.2 ; C579.2 v4(42.2,10.49) ; C197.1 137.83,56.52 v4(137.32,57.02) ; v4(135.59,50.19) 135.38,50.19 134.84,49.65 Q107.S ; HDD1.7 11.75,146.69 ; HDD1.7 12.63,145.81 ; HDD1.7 10.87,145.81 ; Q1245.S 47.44,169.51 46.67,170.28 v4(46.01,170.28) ; v4(63.74,147.7) 64.02,147.98 64.02,148.12 R1644.1 64.36,148.68 64.9,149.22 65.5,149.22 C58.2 ; C101.2 R178.1 v4(50.71,136.78) 51.21,137.29 C857.2 ; R722.2 35.66,140.1 36.23,139.53 36.23,138.82 v4(36.23,138.82) ; C1742.2 v4(123.38,224.54) ; C1758.1 38.13,118.75 38.11,118.72 v4(38.11,118.57) ; 12.63,142 HDD1.4 10.87,142 ; C9016.2 66.62,96.71 C9015.2 v3(65.69,96.7) ; v4(117.03,15.04) 116.97,14.99 PC4914.1 ; DCIN1.6 49.88,25.74 ; DCIN1.6 48.79,24.18 ; DCIN1.6 50.97,24.18 ; DCIN1.6 49.88,22.62 ; v4(142.22,102.97) 142.5,103.25 PC5012.2 ; C258.2 v4(65.39,44.83) R1848.2 64.42,45.52 C6718.2 ; R1604.2 71.15,187.58 70.9,187.83 v4(70.77,187.83) ; R1604.2 R1603.2 R1606.2 R1605.2 R1607.2 ; R1604.2 R107.2 ; 12,147.05 HDD1.9 ; HDD1.9 12,149.69 ; HDD1.9 10.68,148.37 ; HDD1.9 13.32,148.37 ; R1782.2 C1769.2 91.19,23.11 v4(91.6,22.71) ; X1.2 63.75,174.5 65.52,174.5 65.71,174.31 C52.2 v4(66.71,174.31) ; X4.2 37.91,5.79 v4(38.67,5.03) ; C127.2 C129.2 159.7,84.68 v4(160.27,84.68) 160.83,85.24 C131.2 ; R1179.1 40.53,127.7 v4(40.52,127.71) ; PC4906.2 115.83,13.97 v4(116.39,13.41) ; SSUSB1.11 177.99,123.24 ; SSUSB1.11 176.12,122.17 ; SSUSB1.11 176.12,124.31 ; SSUSB1.11 174.25,123.24 ; v4(56.93,143) 56.48,143.45 R181.2 ; v4(27.21,23.6) 26.75,24.06 PWRCN1.11 ; v4(57.59,135.28) 58.37,134.49 58.99,134.49 Q1246.S ; PR5209.2 PC5204.2 v4(99.96,64.64) ; D4.2 v4(165.86,107.6) ; SATAP1.2 13.07,197.5 ; SATAP1.2 10.93,197.5 ; SATAP1.2 12,198.57 ; SATAP1.2 12,196.43 ; v4(44.03,4.67) 44.03,5.54 43.94,5.62 Q100.E 44.42,6.03 44.93,5.52 C593.2 ; v4(106.64,37.31) 106.65,37.3 C721.1 ; v4(91.6,22.71) R1779.2 ; v4(91.6,22.71) 92.43,23.53 C1764.1 ; v4(58.28,140.89) 58.45,140.72 58.45,139.31 57.7,138.56 R172.2 ; Q1209.S 76.04,134.18 76.08,134.79 76.08,134.97 v4(76.36,135.25) ; R132.2 44.18,32.36 44.15,32.38 v4(43.82,32.38) C87.2 C33.2 ; PC4903.2 116.24,11.56 v4(116.24,11.81) ; C121.1 v4(156.95,83.76) ; PWRCN1.12 26.75,18.54 25.94,17.73 v4(25.94,17.4) ; C3378.2 v4(129.69,42.83) ; C3378.2 129.68,41.97 C3383.2 C3366.2 ; C3378.2 R2082.2 ; v4(37.4,26.36) 37.94,26.9 C582.2 ; X54.2 v3(62.06,101.8) ; C105.1 C104.2 v4(169.15,109.89) ; SATAP1.4 12,193.57 ; SATAP1.4 10.93,192.5 ; SATAP1.4 12,191.43 ; SATAP1.4 13.07,192.5 ; R360.2 162.06,34.16 v4(162.21,34.32) ; 10.87,138.19 HDD1.1 ; HDD1.1 11.75,137.31 ; HDD1.1 12.63,138.19 ; R1209.2 105.9,204.6 105.44,204.14 v4(105.44,204.09) ; 98.75,210.57 98.75,209.59 98.46,209.3 HDT1.3 ; 98.75,210.57 C1739.2 ; 98.75,210.57 v4(98.74,210.57) HDT1.5 ; C1799.2 38.41,10.07 v4(38.41,9.45) 38.81,9.45 39.05,9.21 R412.1 40.17,9.21 R1819.2 ; v4(48.29,28.7) 47.31,29.69 Q22.E 44.67,30.96 C88.2 ; C9025.2 67.22,100.66 66.71,100.15 v3(65.95,100.15) ; R1873.2 R1724.2 R79651.2 v3(55.58,167.77) ; 65.63,123.75 H4.1 ; H4.1 69,120.38 ; H4.1 72.37,123.75 ; H4.1 69,127.12 ; MEMCD1.12 169.52,128.91 LED3.K ; MEMCD1.12 171.1,129.58 ; MEMCD1.12 171.1,131.4 ; Q1247.S v4(50.99,166.75) Q1248.S 49.4,162.56 Q1244.S ; PC4802.2 39.53,152.02 v4(39.38,151.86) ; C872.2 108.75,17.32 108.43,17.01 R433.2 v4(108.43,16.08) ; PC5001.2 v7(133.9,80.77) ; C871.2 159.86,112.01 C1736.2 159.8,115.06 159.16,115.7 BTRST1.1 157.13,115.95 PU4.1 ; R90039.1 82.13,107.95 v3(82.28,107.8) ; v3(88.42,182.4) 88.42,183.06 v3(88.87,183.51) ; C1747.2 C1754.1 95.35,26.16 v4(94.7,26.16) ; v3(91.78,180.11) 91.8,180.09 CPU1.D28 ; PC96.2 v4(105.06,6.54) ; SSUSB1.10 177.99,110.44 ; SSUSB1.10 176.12,111.51 ; SSUSB1.10 176.12,109.37 ; v4(104.94,12.83) 105.44,12.83 105.7,12.57 PR4922.2 ; Q101.E 49.09,5.46 v4(50.63,5.46) ; R1690.1 C1735.2 R2004.2 55.41,158.62 54.64,157.86 v4(54.64,157.61) ; Q79.S 68.42,135.86 69.53,136.96 v4(69.53,137.19) 69.53,137.52 69.05,138 69.04,138 68.55,138.49 C61.2 ; SSUSB2.10 176.12,90.01 ; SSUSB2.10 176.12,87.87 ; SSUSB2.10 177.99,88.94 ; SSUSB2.10 174.25,88.94 ; HS6.1 147.86,214 ; HS6.1 140.64,214 ; HS6.1 144.25,217.61 ; HS6.1 144.25,210.39 ; v4(24.42,155.85) 24.24,155.68 PC4803.2 ; C248.2 151.38,18.63 151.38,19.23 v4(152.18,20.03) ; PR4802.1 13.69,157.04 14,156.72 ; C256.2 C236.2 145.77,18.48 145.77,20.43 v4(146.29,20.95) 146.91,21.58 146.91,23.18 C255.2 C235.2 ; C1831.2 C1829.2 140.9,8.31 v4(140.57,8.64) ; X54.4 65.13,103.69 v3(65.18,103.63) ; C6703.2 74.33,70.92 v4(74.58,71.17) ; HDMI2.23 120.31,33.17 v4(119.43,34.05) ; v4(16.15,154.79) 16.33,154.61 PR4807.2 ; v3(67.09,111.63) R90052.2 R90053.2 ; R90054.2 v3(70.52,111.76) ; C67.2 72.87,138.24 v4(73.06,138.43) ; C227.2 87.41,20.83 87.79,20.45 v4(87.92,20.45) 88.08,20.45 88.71,21.08 R1781.2 ; v4(80.55,134.29) 80.49,134.35 C1734.2 R1867.2 ; R1702.2 v4(101.35,214.38) ; C1925.2 89.39,5.89 v4(89.82,6.32) C1928.2 ; R370.2 137.64,62.61 136.85,63.4 v4(136.75,63.4) ; R90031.2 61.62,86.77 v3(60.82,86.77) ; C869.2 41.64,120.24 Q103.S 42.12,118.86 43.25,117.73 v4(43.47,117.73) ; C545.2 151.65,35.81 v4(151.52,35.69) ; C226.2 141.3,18.63 v4(141.3,20.65) 141.3,23.03 C225.2 ; HDMI1.21 114.05,44.22 HDMI2.21 ; C3379.2 135.8,41.98 C3381.1 v4(135.79,42.79) ; X4.4 35.06,8.12 v4(35.06,9.45) 35.01,9.45 34.39,10.07 C1800.2 ; 49.94,35.81 49.59,35.81 48.9,36.5 v4(48.9,36.65) ; NGFF1.76 v4(109.59,203.65) ; PC5016.2 v4(135.29,86.23) ; R1999.2 83.28,196.41 83.01,196.14 v4(83.01,195.94) ; R2008.2 55.55,155.57 v4(55.29,155.32) ; Q1249.S 128.41,29.16 C3377.2 128.8,29.04 v4(129.47,28.37) 128.81,27.71 C6721.2 ; 51.69,21.94 DCIN1.2 51.69,23.03 ; C862.2 40.77,127 v4(40.55,126.77) ; v4(78.9,189.38) 78.62,189.38 77.88,190.12 R1629.2 ; v4(108.3,56.58) 107.79,56.07 C4102.2 ; v4(58.33,141.96) 58.33,142.11 58.71,142.49 C1768.1 ; v4(64.99,171.25) 65.32,171.25 65.58,171.51 C50.2 ; PR4613.1 v4(51.21,195.1) ; PC5243.2 18.07,147.83 17.58,147.35 v4(17.58,146.43) ; Q50.2 v4(94.74,220.83) ; U9001.5 v3(65.06,90.25) ; R2003.2 60.1,175.26 60.56,175.72 v4(62.52,175.72) ; H3.1 93.24,139.06 C1639.2 C1638.2 ; H3.1 94.38,134.56 ; H3.1 97.75,137.93 ; H3.1 94.38,141.3 ; BT1.2 97.11,52.76 v4(95.66,52.76) ; C1870.1 99.09,211.84 98.74,211.48 v4(98.74,211.46) 98.71,211.46 98.33,211.84 HDT1.7 ; v3(66.39,153.54) 65.95,153.09 C57.2 ; R79668.2 76.12,66.15 75.56,66.71 v4(75.56,67.39) ; v4(119.46,37.06) 119.52,37.06 119.53,37.07 HDMI2.24 ; v4(143.42,39.12) 143.42,40.3 142.98,40.73 C565.2 142.98,42.81 C562.2 ; C549.1 C548.1 159.35,64.58 159.93,64 159.93,63.12 v4(160.05,62.99) 160.24,63.18 C550.1 162.02,64.26 C170.2 162.05,64.55 Q31.E ; C1830.2 141.21,5.64 v4(140.88,5.97) ; R1705.2 v4(101.35,216.92) ; R79681.1 64.61,139.26 64.2,139.66 v4(64.06,139.66) ; C3376.1 v4(136.93,28.3) ; 52.39,31 DCIN1.7 53.95,31 ; 180.42,79.89 UHS1.MS2 179,80.91 ; R1709.2 v4(102.93,217.17) ; R1663.2 R79652.2 77.82,141.67 v4(78.36,142.21) 78.27,142.31 C77.2 ; C574.2 v4(42.9,13.39) ; v4(39.15,141.99) 39.53,142.37 C865.1 ; C126.1 163.41,86.06 163.43,86.09 163.43,86.56 v4(163.53,86.66) ; 14,156.72 13.69,156.4 PR4816.2 ; 14,156.72 v4(14.13,156.72) ; v4(34.2,9.25) 33.97,9.25 33.24,9.97 33.24,10.03 C572.2 ; v4(105.19,12.06) 105.7,11.56 PR4917.2 ; PQ5003.S 72.67,65.77 72.68,65.76 72.68,64.4 v4(72.67,64.39) PQ4408.S ; U12.2 75.22,29.08 74.71,28.57 74.71,25.27 ; 96.82,78.68 H5.1 94.39,79.62 ; 171.1,160 MEMCD1.13 171.1,158.17 ; C1927.2 91.27,5.89 v4(90.84,6.32) C1929.2 ; C1737.1 C99.2 C100.2 160.38,123.63 v4(160.69,123.95) ; C95.2 44.03,134.67 v7(43.64,135.05) ; SPK1.7 v4(142.04,12.58) ; C1806.2 72.04,29.91 C1802.2 72.04,28.45 v4(71.66,28.07) ; v4(143.54,71.12) 143.8,71.37 C1796.2 ; v4(87.03,192.63) 87.76,192.63 88.04,192.91 R1631.2 ; v4(160.95,42.54) 161.07,42.54 161.64,41.97 Q1227.S 161.86,42.89 161.64,43.12 C542.2 ; v4(43.35,112.93) 43.26,113.02 43.26,113.87 42.79,114.34 R79659.2 ; 12.82,214.81 FANC3.1 15.18,214.81 ; PC5011.2 v4(137.32,86.11) ; v4(38.39,146.94) 39.15,146.18 C1702.2 ; v4(44.58,15.75) 44.84,15.75 44.97,15.88 C1803.2 C1807.2 ; v4(39.28,138.38) 39.54,138.38 R732.2 ; v4(72.09,142.94) R1685.2 71.22,142.88 R154.2 ; v4(168.56,86.23) 168.18,86.23 167.93,86.49 R210.2 ; SSUSB2.11 177.99,101.74 ; SSUSB2.11 176.12,100.67 ; SSUSB2.11 176.12,102.81 ; v3(67.32,93.83) 67.32,94.45 C9019.2 R90064.2 ; R762.2 C589.2 107.6,28.7 107.86,28.45 110.27,28.45 111.6,29.78 HDMI1.22 118.55,29.78 HDMI2.22 ; HDMI2.25 v4(119.46,40.97) ; X2.2 55.45,151.3 55.22,151.08 v4(55.22,150.45) X2.3 ; v4(118.96,48.95) 119.13,48.77 C1823.2 ; R1817.2 v4(31.85,4.78) ; v4(15.02,206.12) 15.46,206.57 R73.1 ; R80215.2 140.5,43.43 v4(140.88,43.81) ; v4(116.81,57.66) R1700.1 ; R90073.2 v3(83.98,110.49) ; v4(133.75,42.78) 133.36,43.18 R1592.2 ; R1649.2 64.99,170.27 65.85,169.42 v4(66.07,169.42) ; NGFF1.77 v4(109.59,224.35) ; R79650.2 R1670.2 v4(60.55,152.27) ; R1.2 v4(101,225.27) ; R90050.2 v3(73.95,111.63) ; v4(43.03,73.86) 42.24,73.07 PR5285.2 ; C1700.2 92.51,16.55 92.77,16.29 Q105.S 93.85,16.29 94.52,15.62 v4(94.52,15.37) ; Q1208.E 72.66,134.27 73.03,134.65 v4(73.03,135.18) ; v4(49.46,51.38) 49.46,50.67 C32.2 ; Q90002.S v3(110.74,91.25) ; PC5014.2 134.73,75.11 v4(134.6,75.23) ; R1609.2 R1608.2 C1721.1 v4(78.9,187.86) ; v4(144.43,32.44) 144.43,32.41 144.36,32.33 C521.2 ; v4(104.4,15.75) PC4912.2 ; TOUCH1.2 27.57,9.5 v4(27.08,9.02) ; D24.2 v4(93.97,30.28) ; HDT1.17 v4(98.74,218.19) ; R2063.2 55.1,147.83 v4(55.05,147.78) 54.77,148.06 C1738.2 ; R2086.2 v4(132.87,28.36) ; C9024.2 65.45,104.56 v3(65.39,104.5) ; 52.39,20.06 DCIN1.5 52.39,21.16 ; C132.1 156.55,80.4 v4(156.55,79.76) ; C9007.2 v3(71.99,86.28) ; PC4910.2 v4(133.51,23.43) ; PR4611.1 64.56,186.06 v4(64.2,186.42) ; R1691.1 C78.2 61.27,159.77 61.02,160.02 v4(61.02,160.78) ; C585.2 32.42,26.99 C238.2 ; PR5298.2 67.87,62.93 PQ5004.S 67.79,62.86 v4(67.06,62.13) ; C6701.2 81.72,69.28 v4(81.09,69.9) 81.51,70.32 C6702.2 ; H1.1 97.75,192.31 ; H1.1 94.38,195.68 ; H1.1 94.38,188.94 ; R545.2 v4(80.93,191.87) ; LVDS1.32 38.36,77.85 v4(38.44,77.77) ; v4(132.97,31.36) 132.97,31.05 133.88,30.13 C3380.1 ; v3(55.15,163.58) 55.66,163.58 55.79,163.7 R1658.1 ; PC5009.2 147.51,76.96 148.12,76.35 148.12,76.28 v4(148.16,76.23) 148.12,76.23 147.96,76.07 PC5018.2 ; R144.2 v4(42.58,24.54) ; 183,131.4 MEMCD1.14 183,129.58 ; MEMCD1.3 v4(168.21,142.22) ; C1722.1 R2001.2 v4(82.96,191.87) ; Q90001.S v3(114.49,94.11) ; v4(131.73,5.78) 131.99,5.52 PC4909.2 ; R368.2 C194.2 v4(132.3,61.95) ; Q46.3 85.63,41.59 v4(85.63,41.15) ; U9003.4 v3(76.42,96.14) ; R1623.1 88.04,189.1 87.51,188.57 v4(87.03,188.57) ; X1.4 v4(60.69,171.68) ; C864.2 v4(126.78,217.96) ; v4(95.28,10.67) 95.16,10.54 LED2.K ; C714.1 105.65,31.11 v4(105.62,31.14) ; R1703.2 v4(101.35,215.65) ; R1869.2 C66.2 v4(81.57,139.83) 82.58,139.83 83.28,140.53 R152.2 R1660.2 84.3,140.08 83.92,139.7 R1688.2 ; R1871.2 76.42,138.81 76.77,138.81 v4(76.78,138.82) ; U7.4 v4(129.37,50.42) ; C863.2 v4(39.66,4.67)
  L3 w0.508: 183,129.58 MEMCD1.14 ; MEMCD1.14 183,131.4 ; MEMCD1.14 181.68,130.49 ; MEMCD1.13 172.42,159.09 ; MEMCD1.13 171.1,160 ; MEMCD1.13 171.1,158.17 ; MEMCD1.13 169.78,159.09 ; 174.25,88.94 SSUSB2.10 ; SSUSB2.10 177.99,88.94 ; SSUSB2.10 176.12,90.01 ; SSUSB2.10 176.12,87.87 ; 28.14,50.03 H9.5 ; H9.5 28.92,50.81 ; H9.5 28.14,51.6 ; 7.67,162.33 H7.5 7.67,160.75 ; H7.6 7.33,162.67 ; H7.6 6.54,163.46 ; H7.6 5.75,162.67 ; 168.67,21.66 H10.5 168.49,22.27 ; MEMCD1.15 183,160 ; MEMCD1.15 181.68,159.09 ; MEMCD1.15 183,158.17 ; 12.63,142 HDD1.4 10.87,142 ; 6.54,156.54 H7.3 ; H7.3 7.33,157.33 ; H7.3 5.75,157.33 ; 3.46,156.54 H7.2 ; H7.2 2.67,157.33 ; H7.2 4.25,157.33 ; 162.12,222.29 H6.7 161.33,223.08 ; 11.08,146.48 HDD1.7 10.87,145.81 ; 1.54,158.46 H7.1 ; H7.1 2.33,157.67 ; H7.1 2.33,159.25 ; 21.08,47.49 H9.1 ; H9.1 21.86,46.7 ; H9.1 21.86,48.27 ; 175.78,66.58 H11.5 175.96,65.97 ; 1.54,161.54 H7.8 ; H7.8 2.33,160.75 ; H7.8 2.33,162.33 ; MEMCD1.12 171.1,131.4 ; MEMCD1.12 169.78,130.49 ; MEMCD1.12 172.42,130.49 ; MEMCD1.12 171.1,129.58 ; SSUSB1.11 177.99,123.24 ; SSUSB1.11 176.12,122.17 ; SSUSB1.11 174.25,123.24 ; SSUSB1.11 176.12,124.31 ; SSUSB1.10 177.99,110.44 ; SSUSB1.10 176.12,111.51 ; SSUSB1.10 176.12,109.37 ; SSUSB1.10 174.25,110.44 ; H6.1 167.45,221.86 ; H6.1 165.88,221.86 ; H6.1 166.66,221.08 ; 23.08,52.82 H9.7 22.29,52.03 ; SSUSB2.11 176.12,102.81 ; SSUSB2.11 177.99,101.74 ; SSUSB2.11 176.12,100.67 ; SSUSB2.11 174.25,101.74 ; DCIN1.6 50.97,24.18 ; DCIN1.6 48.79,24.18 ; DCIN1.6 49.88,22.62 ; DCIN1.6 49.88,25.74 ; HS6.1 146.19,214 ; HS6.1 144.25,212.06 ; HS6.1 144.25,215.94 ; HS6.1 142.31,214 ; 170.96,60.97 H11.2 170.35,61.15 ; 163.34,16.33 H10.2 162.73,16.51 ; 167.88,222.29 H6.2 168.67,223.08 ; 162.12,227.71 H6.6 161.33,226.92 ; 52.39,29.9 DCIN1.7 52.39,29.36 ; SATAP1.4 12,193.57 ; SATAP1.4 10.93,192.5 ; SATAP1.4 12,191.43 ; SATAP1.4 13.07,192.5 ; H9.8 21.86,51.6 ; H9.8 21.08,50.81 ; H9.8 21.86,50.03 ; v4(156.01,156.97) 155.86,157.12 v4(150.99,157.12) ; 166.66,16.33 H10.3 166.06,16.51 ; 167.88,227.71 H6.3 168.67,226.92 ; 28.14,46.7 H9.4 ; H9.4 28.14,48.27 ; H9.4 28.92,47.49 ; 168.67,18.34 H10.4 168.49,18.94 ; SATAP1.2 12,198.57 ; SATAP1.2 13.07,197.5 ; SATAP1.2 10.93,197.5 ; SATAP1.2 12,196.43 ; 163.34,221.08 H6.8 ; H6.8 162.55,221.86 ; H6.8 164.12,221.86 ; 165.88,228.14 H6.4 ; H6.4 167.45,228.14 ; H6.4 166.66,228.92 ; 2.67,162.67 H7.7 ; H7.7 4.25,162.67 ; H7.7 3.46,163.46 ; H6.5 164.12,228.14 ; H6.5 163.34,228.92 ; H6.5 162.55,228.14 ; HDD1.1 12.63,138.19 ; HDD1.1 11.75,137.31 ; HDD1.1 10.87,138.19 ; 22.29,46.27 H9.2 23.08,45.48 ; 174.04,60.97 H11.3 173.43,61.15 ; 27.71,46.27 H9.3 26.92,45.48 ; 26.92,52.82 H9.6 27.71,52.03 ; 175.78,63.5 H11.4 175.96,62.89 ; v4(165.34,74.4) 165.34,76.33 164.32,77.34 v4(162.59,77.34) ; 51.69,23.03 DCIN1.2 51.69,24.12 ; 7.67,159.25 H7.4 7.67,157.67
  L4 w0.508: 169.78,159.09 MEMCD1.13 ; MEMCD1.13 171.1,158.17 ; MEMCD1.13 171.1,160 ; MEMCD1.13 172.42,159.09 ; 174.25,110.44 SSUSB1.10 ; SSUSB1.10 176.12,109.37 ; SSUSB1.10 176.12,111.51 ; SSUSB1.10 177.99,110.44 ; 167.88,222.29 H6.2 168.67,223.08 ; MEMCD1.15 183,160 ; MEMCD1.15 181.68,159.09 ; MEMCD1.15 183,158.17 ; SATAP1.2 12,198.57 ; SATAP1.2 13.07,197.5 ; SATAP1.2 12,196.43 ; SATAP1.2 10.93,197.5 ; 12,191.43 SATAP1.4 ; SATAP1.4 13.07,192.5 ; SATAP1.4 10.93,192.5 ; SATAP1.4 12,193.57 ; HS6.1 146.19,214 ; HS6.1 144.25,215.94 ; HS6.1 144.25,212.06 ; HS6.1 142.31,214 ; DCIN1.6 50.97,24.18 ; DCIN1.6 49.88,25.74 ; DCIN1.6 49.88,22.62 ; DCIN1.6 48.79,24.18 ; 166.66,221.08 H6.1 ; H6.1 165.88,221.86 ; H6.1 167.45,221.86 ; 27.71,52.03 H9.6 26.92,52.82 ; MEMCD1.14 183,131.4 ; MEMCD1.14 181.68,130.49 ; MEMCD1.14 183,129.58 ; 167.88,227.71 H6.3 168.67,226.92 ; 5.75,162.67 H7.6 5.93,163.28 ; 163.34,16.33 H10.2 162.73,16.51 ; 23.08,52.82 H9.7 22.29,52.03 ; H7.2 4.25,157.33 ; H7.2 2.67,157.33 ; H7.2 3.46,156.54 ; SSUSB2.11 177.99,101.74 ; SSUSB2.11 176.12,100.67 ; SSUSB2.11 176.12,102.81 ; SSUSB2.11 174.25,101.74 ; 163.34,221.08 H6.8 ; H6.8 162.55,221.86 ; H6.8 164.12,221.86 ; 26.92,45.48 H9.3 27.71,46.27 ; 21.86,46.7 H9.1 ; H9.1 21.86,48.27 ; H9.1 21.08,47.49 ; 168.67,21.66 H10.5 168.49,22.27 ; 21.86,50.03 H9.8 ; H9.8 21.08,50.81 ; H9.8 21.86,51.6 ; H9.4 28.14,48.27 ; H9.4 28.14,46.7 ; H9.4 28.92,47.49 ; SSUSB2.10 177.99,88.94 ; SSUSB2.10 176.12,87.87 ; SSUSB2.10 174.25,88.94 ; SSUSB2.10 176.12,90.01 ; 2.33,157.67 H7.1 ; H7.1 2.33,159.25 ; H7.1 1.54,158.46 ; 165.88,228.14 H6.4 ; H6.4 167.45,228.14 ; H6.4 166.66,228.92 ; 52.39,29.9 DCIN1.7 52.39,29.36 ; 170.96,60.97 H11.2 170.35,61.15 ; 176.12,122.17 SSUSB1.11 ; SSUSB1.11 176.12,124.31 ; SSUSB1.11 174.25,123.24 ; SSUSB1.11 177.99,123.24 ; 174.04,60.97 H11.3 173.43,61.15 ; H6.5 164.12,228.14 ; H6.5 162.55,228.14 ; H6.5 163.34,228.92 ; v4(165.34,74.4) 165.25,74.4 163.94,73.08 v4(163.94,72.9) ; 175.78,63.5 H11.4 175.96,62.89 ; 171.1,129.58 MEMCD1.12 ; MEMCD1.12 169.78,130.49 ; MEMCD1.12 171.1,131.4 ; MEMCD1.12 172.42,130.49 ; H9.5 28.92,50.81 ; H9.5 28.14,51.6 ; H9.5 28.14,50.03 ; 166.06,16.51 H10.3 166.66,16.33 ; H4.1 71.57,123.75 ; H4.1 66.43,123.75 ; H4.1 69,126.32 ; H4.1 69,121.18 ; 162.12,222.29 H6.7 161.33,223.08 ; H7.7 4.25,162.67 ; H7.7 3.46,163.46 ; H7.7 2.67,162.67 ; 162.12,227.71 H6.6 161.33,226.92 ; H7.8 2.33,162.33 ; H7.8 1.54,161.54 ; H7.8 2.33,160.75 ; 51.69,21.94 DCIN1.2 51.69,23.03 ; 168.67,18.34 H10.4 168.49,18.94 ; 23.08,45.48 H9.2 22.29,46.27 ; 5.75,157.33 H7.3 5.93,156.72 ; 175.96,65.97 H11.5 175.78,66.58
  BOTTOM w0.203: U4101.53 105.45,55.88 105.21,55.65 v4(105.21,55.42) ; v4(104.07,56.39) U4101.45 104.07,60.54 R79705.2 ; PU5407.17 v4(79.97,211.73) ; v4(102.4,51.54) 102.18,51.54 101.67,51.03 U4101.10 ; v4(95.66,52.76) 96.22,52.76 96.55,53.08 U4101.21 ; PU5407.23 77.57,211.93 v4(77.37,211.73) 77.17,211.93 PU5407.24 ; PU5407.19 79.17,211.93 v4(78.97,211.73) 78.77,211.93 PU5407.20 ; PU5407.32 76.21,215.37 76.61,215.77 v4(77.15,215.77) ; U26.6 34.24,94.3 34.16,94.39 33.75,94.39 v4(33.63,94.51) ; v4(30.39,216.08) 30.79,215.68 PU4601.32 ; v4(80.77,211.73) PU5407.15
  BOTTOM w0.305: U120.20 38.44,38.53 v4(39.1,39.19) ; v4(60.13,53.49) 60.24,53.6 U55.14
  BOTTOM w0.356: Q12.4 39.65,75.88 39.15,76.38
  BOTTOM w0.406: Q12.1 42.36,77.18 42.02,77.52 42.02,78.64 42.65,79.27 45.39,79.27 v4(45.47,79.35) ; PQ4406.4 74.09,55.81 73.82,56.08 73.03,56.08 72.79,56.33 PQ4406.1 v4(71.23,57.07) ; v4(152.52,48.18) 153,48.18 153.26,47.93 Q1226.1 153.31,47.62 153.31,46.96 153.56,46.71 154.17,46.71 154.56,46.32 Q1226.4 ; Q13.4 47.2,76.81 v4(47.84,77.44) ; v4(43.03,73.86) 44.41,75.24 Q13.1
  BOTTOM w0.508: 174.25,88.94 SSUSB2.10 ; SSUSB2.10 177.99,88.94 ; SSUSB2.10 176.12,90.01 ; SSUSB2.10 176.12,87.87 ; Q1212.S 29.97,13.66 v4(30.49,13.14) C1773.2 C1774.2 ; C293.2 C298.2 v4(30.23,81.28) ; C1679.2 90.65,160.85 C1692.2 90.65,160.21 C1682.2 ; C1679.2 89.19,161.67 v3(88.93,161.93) ; C1679.2 90.65,162.5 C1691.2 90.41,163.06 90.41,163.27 89.82,163.85 C1678.2 ; 171.1,129.58 MEMCD1.12 ; MEMCD1.12 171.1,131.4 ; MEMCD1.12 172.42,130.49 ; v3(77.22,163.3) 77.05,163.12 77.05,162.06 76.3,161.3 C330.2 ; v3(77.4,149.9) 77.72,149.58 C1733.1 ; 51.69,23.03 DCIN1.2 51.69,24.12 ; R79720.2 108.62,60.58 108.87,60.33 v7(109.61,60.33) ; HDMI1.22 116.68,29.78 ; HDMI1.22 111.3,29.78 ; HDMI1.22 113.99,28.66 ; C1760.2 28.28,28.19 28.35,28.12 v4(28.38,28.12) ; U25.2 38.64,78 38.44,77.8 v4(38.44,77.77) ; R1635.2 134.46,126.24 134.59,126.37 134.64,126.4 135.4,127.16 v4(135.4,127.2) ; v4(85.63,41.15) 85.76,41.27 R1182.1 ; 96.64,30.46 USB3.6 ; USB3.6 98.35,28.74 ; USB3.6 100.07,30.46 ; USB3.6 98.35,32.17 ; 15.18,214.81 FANC3.1 12.82,214.81 ; v4(41.44,40.74) 41.69,41 C35.2 ; C20.2 33.92,111.84 34.83,110.92 v4(34.86,110.92) 34.7,110.77 R19.2 C14.1 ; D21.A 164.37,87.2 163.84,86.66 v4(163.53,86.66) ; 65.63,123.75 H4.1 ; H4.1 72.37,123.75 ; H4.1 69,127.12 ; H4.1 69,120.38 ; Q24.3 165.18,71.75 164.04,72.9 v4(163.94,72.9) ; PR5416.1 72.3,194.82 v4(71.28,195.83) ; v4(163.48,78.23) 164.31,77.41 164.31,76.83 Q57.3 ; PC5420.2 v4(87.31,214.38) ; C3367.2 136.55,52.27 137.01,51.82 ; 174.25,123.24 SSUSB1.11 ; SSUSB1.11 176.12,124.31 ; SSUSB1.11 176.12,122.17 ; SSUSB1.11 177.99,123.24 ; SSUSB1.10 177.99,110.44 ; SSUSB1.10 176.12,111.51 ; SSUSB1.10 176.12,109.37 ; SSUSB1.10 174.25,110.44 ; v4(104.94,12.83) 105.19,13.08 PR4925.2 ; C1654.2 83.6,158.81 C1671.2 83.79,159.32 v3(84.2,159.73) 85.12,160.65 C1648.2 85.12,161.08 v3(84.2,162) 84.68,162.48 C1659.2 84.68,163.92 v3(84.2,164.4) 84.68,164.88 C1658.2 84.68,166.32 v3(84.2,166.8) 85.12,167.72 C1650.2 ; PQ4206.S v4(66.23,38.33) ; 87.33,153.29 86.72,153.9 C395.2 ; 87.33,153.29 87.19,153.29 86.86,152.96 R79653.2 ; 87.33,153.29 v3(87.38,153.29) ; C1977.2 138.72,125.48 v4(138.5,125.26) 138.17,125.26 C1971.2 ; PC5233.1 55.39,52.65 54.31,52.65 v4(54.29,52.68) ; v4(48.9,36.65) 48.9,36.47 Q45.E 51.13,34.24 52.88,34.24 R1853.2 ; C290.1 C284.2 35.25,102.02 36.17,102.95 36.96,102.95 C291.2 ; v3(76.4,178.2) 76.49,178.11 C1950.2 ; C1678.2 89.22,164.08 v3(88.95,164.35) ; C1678.2 90.65,164.91 C1690.2 90.41,165.47 90.41,165.68 89.7,166.39 C1681.2 ; PR5411.1 PC5424.2 v4(82.71,208.25) ; C1687.2 94.74,172.69 v4(93.93,172.69) ; C1741.2 84.67,153.17 v3(84.8,153.3) ; v3(81.8,169.2) 82.46,169.86 C1935.2 82.46,170.94 v3(81.8,171.6) 81.63,171.77 C1941.2 C1946.2 81.63,173.83 v3(81.8,174) 82.46,174.66 C1948.2 ; C1976.2 142.4,126.17 v4(142.4,127.25) ; C1707.2 90.58,152.91 90.08,153.42 v3(89.72,153.42) 88.93,152.63 C1695.2 C1704.2 ; v3(88.4,154.1) 88.68,154.38 C1714.2 ; USB3.4 101.06,34.56 ; USB3.4 102.09,33.53 ; USB3.4 101.06,32.5 ; USB3.4 100.03,33.53 ; v3(77.07,168.94) 76.84,169.16 C1646.2 ; HS6.1 147.86,214 ; HS6.1 140.64,214 ; HS6.1 144.25,210.39 ; R511.2 R507.1 31.06,99.77 30.31,99.77 v4(30.18,99.64) ; MEMCD1.15 183,160 ; MEMCD1.15 181.68,159.09 ; MEMCD1.15 183,158.17 ; v3(85.4,149.91) 85.29,149.8 C1697.2 ; R523.2 48.03,77.44 v4(47.84,77.44) ; PR5274.1 65.86,51.79 67,51.79 v4(67.04,51.75) ; C1682.2 89.19,159.38 v3(88.93,159.64) ; C1682.2 90.65,158.56 C1693.2 ; MEMCD1.13 171.1,160 ; MEMCD1.13 171.1,158.17 ; MEMCD1.13 169.78,159.09 ; MEMCD1.13 172.42,159.09 ; 100.03,10.53 USB4.4 ; USB4.4 101.06,9.5 ; USB4.4 102.09,10.53 ; v4(30.09,101.17) 31.15,101.17 C296.2 ; C9.2 R512.2 v4(30.23,87.12) ; v4(152.95,74.93) 154.59,74.93 155.11,74.41 C509.2 156.53,74.09 C516.2 ; v3(74.52,154.96) 74.52,154.9 75.07,154.35 75.87,154.35 C1828.2 ; C291.2 38.31,104.29 v4(38.87,104.29) 39.25,104.29 39.45,104.09 C283.2 40.23,102.22 C289.2 ; C291.2 37.17,103.63 36.23,104.57 R501.2 ; C3381.1 v4(135.79,42.79) ; C1705.2 92.77,152.27 v3(92.99,152.5) ; v3(96.5,155.4) 96.2,155.7 C1684.2 94.86,155.4 v3(94.13,155.4) 93.55,155.4 C1685.2 93.2,155.7 v3(92.3,154.8) 92.3,154.87 C1683.2 91.35,155.57 v3(91.35,154.81) ; C76.1 148.81,55.63 C190.2 148.19,55.32 v4(147.53,55.32) 147.53,56.15 R1834.2 ; PC4917.2 105.76,13.84 105.17,13.84 v4(105.08,13.75) ; R30.2 36.42,116.78 Q5.S 37,116.01 v4(36.29,115.31) 35.9,115.7 R33.2 ; C1681.2 90.52,167.32 C1689.2 90.52,168.08 C1680.2 ; C1681.2 89.2,166.5 v3(88.95,166.75) ; v4(26.83,225.32) PC4607.1 PR4605.1 ; PC5427.2 v4(156.65,208.79) ; C1680.2 90.52,169.74 C356.2 C1694.2 ; C1680.2 89.19,168.91 v3(88.95,169.15) ; v4(24.29,207.77) 24.67,208.15 PR4603.2 PR4635.2 ; C1715.2 82.08,149.66 v3(81.97,149.76) ; v7(82.74,1.14) 82.71,1.17 ; C1665.2 87.09,156.4 v3(86.65,155.96) ; v4(162.62,79.07) 162.52,79.17 C478.2 C474.2 ; 107.69,24.51 TC7.2 ; TC7.2 109.8,24.51 ; TC7.2 108.75,25.57 ; TC7.2 108.75,23.46 ; v4(143.42,39.12) 140.62,41.91 140.62,43.56 v4(140.88,43.81) ; C11.2 v4(30.23,83.06) ; v4(32.9,118.26) 33.08,118.08 Q10.E ; R115.2 C1609.1 C1608.2 94.1,169.14 v3(94.1,169.8) ; R300.1 162.34,66.92 160.05,64.63 v4(160.05,62.99) ; PR4610.1 v4(31.91,225.27) ; PR4413.1 73.57,51.41 73.01,50.85 v4(71.74,50.85) ; v3(77,157.18) 77.93,157.18 78.5,156.61 78.94,156.61 C1668.2 C1954.2 ; Q1.S 36.88,112.47 35.26,112.47 v4(35.09,112.65) ; C1930.2 86.66,208.72 Q1240.S 87.07,210.15 v4(86.72,210.49) ; v4(157.11,47.58) 157.11,46.89 157.64,46.35 C1826.1 ; C1820.1 144.23,59.68 144.23,58.98 v4(144.22,58.97) 144.03,58.97 C1821.2 ; v4(135.59,50.19) 135.62,50.22 135.62,50.42 137.01,51.82 ; C1706.2 101.39,151.13 v3(101.15,150.89) ; v3(96.03,152.28) 95.97,152.34 C1708.2 ; Q9648.S 84.84,58.74 C6724.1 81.57,60.77 v4(81.57,62.48) ; 110.34,37.03 HDMI1.20 ; HDMI1.20 111.46,34.21 ; HDMI1.20 111.46,39.85 ; HDMI1.20 112.58,37.03 ; R2062.2 146.91,127.76 C1975.2 R2056.2 147.44,129.16 148.01,128.6 v4(148.01,128.6) 148.02,128.59 C1732.2 ; PR5009.2 141.45,77.79 v4(142.02,78.36) 142.15,78.49 C1797.2 ; 178,69.67 UHS1.MS1 ; UHS1.MS1 176.58,70.69 ; UHS1.MS1 179.42,70.69 ; PC5428.2 v4(156.65,213.11) ; 137.01,51.82 138.46,51.82 139.01,52.36 R709.2 ; C9037.2 v3(118.75,101.22) ; 149.39,152.15 149.07,151.83 149.07,150.43 ; C7.2 34.07,85.65 33.67,85.25 v4(33.58,85.25) ; v4(95.66,52.76) 95.55,52.64 C4101.1 ; v4(152.31,129.03) 152.18,128.91 C1724.2 ; v4(161.53,216.15) C1956.2 C6715.2 ; C292.2 v4(30.21,79.83) ; C863.2 v4(39.66,4.67) ; C1656.2 78.27,158.31 C326.2 78.96,159.29 v3(79.4,159.73) 79.79,160.12 C1644.2 79.79,161.61 v3(79.4,162) 79.85,162.45 C1660.2 79.85,163.95 v3(79.4,164.4) 79.85,164.85 C1664.2 79.85,166.35 v3(79.4,166.8) 79.79,167.19 C1652.2 ; v4(37.47,87.73) 37.57,87.83 37.57,88.46 C297.2 ; R80218.2 158.72,42.53 C1824.2 159.85,42.54 v4(160.95,42.54) ; DCIN1.6 50.97,24.18 ; DCIN1.6 49.88,22.62 ; DCIN1.6 48.79,24.18 ; DCIN1.6 49.88,25.74 ; v4(38.44,77.77) 36.53,77.77 36.1,78.21 U25.4 ; v4(38.44,77.77) 38.41,77.75 C1877.2 38.63,76.38 39.15,76.38 ; v4(38.44,77.77) 39.25,77.77 39.91,78.44 U25.1 ; 98.35,5.74 USB4.6 ; USB4.6 98.35,9.17 ; USB4.6 96.64,7.46 ; USB4.6 100.07,7.46 ; v4(99.96,64.64) PC5204.2 PR5209.2 ; Q68.S 26.93,23.88 v4(27.21,23.6) ; PQ4204.E v4(70.39,36.31) ; R79678.1 R79680.1 R79679.1 70.45,153.67 R1648.2 71.34,154.36 v3(71.9,153.8) ; C1957.2 75.56,151.54 v3(75.3,151.8) 75.22,151.88 C1677.2 ; PR4924.2 v4(105.19,11.05) ; 149.07,150.43 R2060.2 ; 149.07,150.43 148.75,150.11 ; C6.2 40.61,110.74 C2.2 C3.2 42.63,110.74 42.93,110.44 v4(43.69,110.44) ; v4(63.7,34.32) D19.1 ; v4(133.75,42.78) R2089.2 R2090.2 R2085.2 131.67,42.04 130.49,42.04 v4(129.69,42.83) ; C1703.2 78.21,154.17 78.21,152.35 77.65,151.79 v3(77.6,151.79) ; C1716.2 80.87,155.19 C1666.2 80.9,155.7 v3(80.6,156) 81.19,156.59 C1667.2 ; R1193.1 174.91,84.07 v4(175.42,84.58) ; 12,147.05 HDD1.9 ; HDD1.9 12,149.69 ; HDD1.9 10.68,148.37 ; v4(33.63,94.51) 33.49,94.51 33.09,94.11 R1079.2 ; v3(106.81,101.35) 106.45,100.98 C9031.2 ; C1688.2 91.85,173.55 v3(92.3,174) 93,173.3 93,172.87 C1686.2 ; C9032.2 107.09,105.66 ; 96.64,43.6 USB3.5 ; USB3.5 98.35,45.31 ; USB3.5 100.07,43.6 ; USB3.5 98.35,41.88 ; v4(94.34,20.04) 94.34,19.25 93.73,18.64 Q104.S ; MEMCD1.14 183,131.4 ; MEMCD1.14 183,129.58 ; MEMCD1.14 181.68,130.49 ; v4(158.33,208.79) C6714.2 159.99,208.79 C6712.2 ; v4(50.35,208.28) PR5423.1 ; Q9650.S 43.05,119.79 43.47,119.38 v4(43.47,117.73) ; v4(31.15,25.53) 31.15,26.19 31.4,26.45 Q1213.E ; R656.2 C525.1 152.51,48.88 152.51,48.29 152.52,48.28 v4(152.52,48.18) 152,48.18 151.8,47.98 151.8,45.47 151.42,45.09 R79677.2 ; v4(148.75,149.61) 148.75,150.11 ; 148.75,150.11 148.43,150.43 R122.2 C1746.1 C65.1 ; v4(33.61,90.23) 33.27,89.88 C299.1 C295.2 ; C1651.2 82.46,167.46 v3(81.8,166.8) 82.27,166.33 C1662.2 82.27,164.87 v3(81.8,164.4) 82.27,163.93 C1661.2 82.27,162.47 v3(81.8,162) 82.46,161.34 C1645.2 82.46,160.38 v3(81.8,159.73) 82.27,159.26 C1672.2 82.46,158.81 C1653.2 ; 52.39,28.81 DCIN1.7 52.39,29.9 ; R79654.2 79.22,149.68 v3(79,149.9) ; v3(84.2,169.2) 85.12,170.12 C1936.2 85.12,170.68 v3(84.2,171.6) 84.04,171.76 C1937.2 C1945.2 84.04,173.84 v3(84.2,174) 85.08,174.88 C1951.2 ; PR4919.2 v4(105.19,12.06) ; C1669.2 83.79,156.41 v3(84.23,155.97) 84.87,155.33 C1674.2 ; v4(162.59,77.34) 162.85,77.09 R301.1 ; v4(156.01,181.36) 155.76,181.61 C1726.2 ; v4(76.92,59.82) PR4451.2 PR4433.2 ; 98.35,22.31 USB4.5 100.07,20.6 ; 176.12,100.67 SSUSB2.11 ; SSUSB2.11 176.12,102.81 ; SSUSB2.11 177.99,101.74 ; v4(44.03,4.67) 44.03,5.32 C591.2 ; Q128.E v4(128.79,214.66) ; Q38.E 30.48,23.06 30.81,22.73 31.1,22.73 v4(31.11,22.72) ; R1988.1 72.49,210.34 Q1241.E 74.52,209.87 75.52,208.86 v4(75.52,208.36) 76.44,208.36 PC5421.2 ; v3(86.6,169.2) 87.71,170.31 C1938.2 87.79,170.41 v3(86.6,171.6) 86.2,172 C1939.2 C1944.2 86.2,173.6 v3(86.6,174) 86.91,174 C1949.2 ; v4(91.3,11.81) 92.03,11.81 92.74,12.52 92.74,14.29 C866.2 ; 113.99,43.16 HDMI1.21 ; HDMI1.21 113.99,45.4 ; HDMI1.21 116.68,44.28 ; TC1.2 v4(136.91,205.88) ; C1947.2 79.79,174.39 v3(79.4,174) 79.34,173.94 C1952.2 C1943.2 79.34,171.66 v3(79.4,171.6) 79.79,171.21 C1934.2 79.79,169.59 v3(79.4,169.2) ; Q102.E v4(48.45,7.94) ; C1655.2 87.79,158.31 C1670.2 87.09,159.24 v3(86.6,159.73) 86.86,159.73 C1647.2 87.79,160.81 v3(86.6,162) 87.09,162.49 C1663.2 87.09,163.91 v3(86.6,164.4) 87.09,164.89 C1657.2 87.09,166.31 v3(86.6,166.8) 86.82,166.8 C1649.2 ; PU5.2 v4(153.6,204.34) ; C1696.2 72.23,161.59 v3(71.77,162.05) ; PC4918.2 v4(105.16,10.03) ; Q52.E v4(15.68,224.12) ; v4(38.03,83.06) 38.64,83.67 U25.7 38.64,85.34 39,85.7 C1827.2 ; C1940.2 C1942.2 88.23,173.23 v3(88.95,173.95) ; R90012.2 106.46,99.19 105.7,98.42 v3(105.7,98.09) ; PC5202.2 v4(107.98,67.77) ; Q51.S v4(17.28,224.12) ; C1953.2 79.18,152.5 v3(80,152.5) ; PC5237.2 v4(58.86,50.67) ; U11.2 v4(49.59,11.94)
  vias: v1(15.81,182.3) v1(23.3,223.11) v1(25.26,138.91) v1(26.32,154.89) v1(27.97,197.99) v1(28.48,147.83) v1(29.24,219.33) v1(32.04,52.96) v1(39.53,198.75) v1(45.27,85.72) v1(46.46,117.6) v1(58.96,220.98) v1(80.63,214.63) v1(96.17,198.37) v1(99.86,134.49) v1(130.51,216.18) v1(144.43,88.27) v1(150.86,205.56) v1(158.91,187.71) v1(161.7,149.22) v2(17.94,203.38) v2(25.41,69.55) v2(36.69,57.18) v2(46.18,114.3) v2(46.64,29.72) v2(50.63,217.91) v2(54.49,76.61) v2(59.88,128.22) v2(74.23,83.54) v2(80.68,92.38) v2(88.27,100.71) v2(94.11,222.78) v2(106.92,197.05) v2(112.4,111.02) v2(113.29,214.1) v2(117.74,182.52) v2(120.25,19.81) v2(120.38,38.99) v2(121.06,93.78) v2(127.13,133.22) v2(135.72,222.76) v2(135.95,212.55) v2(142.43,90.83) v2(143.04,205.36) v2(149,197.23) v2(149.46,20.4) v2(156.98,135.15) v2(170.04,136.96) v2(177.1,84.53) v2(181.36,153.8) v3(57.69,112.65) v3(57.82,109.22) v3(57.82,105.92) v3(57.95,101.73) v3(59.09,121.92) v3(59.22,126.36) v3(59.6,116.97) v3(59.85,111.38) v3(60.23,104.9) v3(60.23,102.23) v3(60.26,106.78) v3(60.32,100.53) v3(61.12,126.36) v3(61.35,100.53) v3(61.37,115.32) v3(61.5,121.92) v3(61.7,109.33) v3(62.39,106.71) v3(63.03,113.28) v3(63.36,109) v3(63.53,117.09) v3(63.91,110.11) v3(64.04,126.36) v3(64.3,121.92) v3(65.16,86.44) v3(65.95,113.41) v3(66.28,86.41) v3(67.42,86.44) v3(67.98,117.09) v3(68.09,168.2) v3(68.3,151.4) v3(68.72,165.3) v3(70.14,113.41) v3(70.55,182.35) v3(71.53,116.59) v3(71.53,114.68) v3(73.82,107.82) v3(75.85,113.28) v3(76.74,114.43) v3(77.25,107.31) v3(78.57,86.89) v3(81.31,113.92) v3(81.31,110.49) v3(82.51,101.63) v3(82.46,97.13) v3(82.56,99.34) v3(82.79,92.99) v3(82.79,91.14) v3(82.89,95.63) v3(82.86,94.44) v3(83.73,102.87) v3(84.36,87.63) v3(86.14,95.12) v3(86.14,93.09) v3(86.39,114.17) v3(86.77,91.06) v3(87.28,87.5) v3(88.17,109.35) v3(88.55,146.05) v3(88.93,143.76) v3(89.17,184.91) v3(89.7,95.12) v3(89.7,93.09) v3(90.08,146.33) v3(90.24,186.06) v3(90.43,144.51) v3(91.09,114.68) v3(91.35,184.02) v3(91.6,90.81) v3(91.73,109.22) v3(92.54,145.79) v3(92.69,185.75) v3(92.77,143.13) v3(93.32,147.26) v3(93.63,112.39) v3(93.65,143.15) v3(93.76,95.12) v3(93.89,92.84) v3(94.02,184.9) v3(94.55,145.82) v3(94.62,183.75) v3(94.65,109.22) v3(95.15,145.15) v3(95.54,185.67) v3(95.92,184.68) v3(96.01,182.37) v3(96.17,145.16) v3(96.17,94.61) v3(96.38,146.22) v3(96.93,182.27) v3(97.2,149.71) v3(97.19,90.93) v3(97.44,92.84) v3(97.59,175.42) v3(97.88,178.98) v3(97.87,153.52) v3(97.88,147.14) v3(97.95,114.3) v3(98.08,176.47) v3(98.44,155.17) v3(98.97,151.26) v3(99.35,106.81) v3(99.98,174.5) v3(100.07,153.69) v3(100.5,177.55) v3(100.49,97.92) v3(100.72,175.99) v3(100.92,151.9) v3(101,179.1) v3(101.07,154.3) v3(101.13,94.61) v3(101.25,92.71) v3(101.43,181.97) v3(101.4,174.5) v3(101.38,91.06) v3(101.51,110.24) v3(102.01,114.43) v3(103.79,97.92) v3(104.81,92.71) v3(105.19,106.81) v3(105.85,94.03) v3(105.95,110.24) v3(106.08,114.3) v3(106.56,91.59) v3(108.8,94.46) v3(108.92,96.98) v3(110.19,94.67) v3(110.27,110.11) v3(110.65,114.43) v3(111.03,106.81) v3(112.07,95) v3(112.17,107.06) v3(114.51,96.04) v3(114.74,110.95) v3(116.46,96.33) v3(119.92,114.3) v3(121.19,90.81) v3(121.45,95.38) v3(121.45,92.33) v3(121.45,88.27) v3(122.08,98.93) v3(122.33,112.01) v3(124.24,109.98) v3(124.49,103.76) v3(124.49,99.31) v3(127.16,107.44) v3(128.43,96.52) v3(128.43,92.84) v3(129.95,104.9) v4(3.42,200.53) v4(3.94,198.88) v4(3.94,197.61) v4(7.06,215.09) v4(12.11,174.23) v4(12.11,172.61) v4(12.11,170.98) v4(18.7,157.73) v4(18.7,156.84) v4(18.7,155.96) v4(19.34,149.28) v4(19.68,151.24) v4(20.68,172.24) v4(22.21,172.24) v4(23.56,29.45) v4(23.56,17.85) v4(23.73,172.24) v4(23.87,42.25) v4(23.87,31.05) v4(24.14,39.62) v4(24.14,37.34) v4(24.29,150.79) v4(26.2,149.3) v4(27.47,156.72) v4(27.47,155.83) v4(28.37,141.14) v4(28.66,217.81) v4(29.12,44.58) v4(29.52,217.81) v4(30.39,219.53) v4(30.39,218.67) v4(30.39,217.81) v4(30.39,216.94) v4(31.25,217.81) v4(31.28,140.84) v4(31.38,134.85) v4(32.11,217.81) v4(32.8,37.97) v4(33.94,15.88) v4(34.17,37.95) v4(35.61,23.03) v4(36.12,25.68) v4(36.46,63.37) v4(36.46,62.36) v4(36.51,61.34) v4(36.46,60.33) v4(36.46,59.31) v4(36.56,66.29) v4(37.07,14.86) v4(37.55,147.73) v4(37.6,24.31) v4(37.78,96.23) v4(37.78,95.36) v4(37.78,94.5) v4(37.78,93.64) v4(37.78,92.77) v4(37.88,15.67) v4(37.88,14.86) v4(37.88,14.05) v4(38.71,26.43) v4(38.69,14.86) v4(39.87,26.5) v4(44.62,160.04) v4(45.88,81.15) v4(46.64,85.72) v4(47.12,116.34) v4(47.12,115.57) v4(47.15,84.07) v4(47.28,124.84) v4(47.28,124.03) v4(47.28,123.22) v4(47.28,108.71) v4(47.28,106.68) v4(47.28,103.63) v4(47.28,91.31) v4(47.4,118.75) v4(47.4,111.12) v4(47.4,100.71) v4(47.4,96.27) v4(47.4,94.23) v4(47.53,24.13) v4(48.42,26.8) v4(49.82,19.08) v4(49.94,34.04) v4(50.45,21.59) v4(51.26,205.76) v4(51.29,204.72) v4(51.72,23.75) v4(52.03,43.1) v4(52.03,42.24) v4(52.1,45.09) v4(52.23,205.74) v4(52.23,204.72) v4(59.95,56.26) v4(60.71,57.02) v4(60.74,56.26) v4(60.74,55.47) v4(61.5,56.29) v4(65.44,88.32) v4(65.8,23.08) v4(66.23,89.15) v4(66.23,88.32) v4(66.2,87.55) v4(66.62,23.08) v4(66.85,26.45) v4(66.84,21.97) v4(66.84,21.21) v4(66.84,20.45) v4(67.01,88.29) v4(67.09,28.78) v4(67.43,23.08) v4(67.61,26.45) v4(74.89,21.93) v4(75.9,21.93) v4(76.92,21.93) v4(77.94,21.93) v4(77.96,215.77) v4(78.77,217.4) v4(78.77,216.59) v4(78.77,215.77) v4(78.77,214.96) v4(78.77,214.15) v4(78.95,21.93) v4(79.59,215.77) v4(80.4,215.77) v4(89.36,11.81) v4(99,144.63) v4(102.14,213.61) v4(102.27,215.65) v4(102.27,211.58) v4(103.92,205.61) v4(104.43,194.18) v4(110.65,12.01) v4(113.83,192.79) v4(115.86,200.81) v4(120.47,191.7) v4(121.19,129.16) v4(122.77,201.55) v4(123.32,204.98) v4(123.4,11.1) v4(124.49,212.5) v4(127.24,201.55) v4(127.92,164.97) v4(128.05,157.86) v4(128.79,210.98) v4(128.94,154.05) v4(129.32,161.67) v4(129.32,159.38) v4(129.57,130.81) v4(129.57,127.38) v4(129.73,209.63) v4(131.61,193.17) v4(131.87,35.57) v4(132.9,136.65) v4(133.6,35.57) v4(135.03,182.5) v4(135.06,177.16) v4(135.16,148.01) v4(135.39,137.29) v4(135.54,187.45) v4(136.3,132.33) v4(136.3,130.84) v4(137.07,185.93) v4(137.07,183.77) v4(137.07,136.02) v4(137.7,193.29) v4(138.72,193.29) v4(139.61,193.29) v4(140.37,37.47) v4(140.37,35.56) v4(140.5,193.29) v4(140.83,132.11) v4(141.38,193.29) v4(141.4,143.07) v4(141.54,149.83) v4(141.64,187.57) v4(141.64,186.44) v4(141.64,180.98) v4(141.64,178.72) v4(141.64,145.61) v4(141.64,141.74) v4(141.64,133.86) v4(141.58,129.86) v4(141.74,172.38) v4(141.74,138.58) v4(141.77,189.61) v4(141.77,184.28) v4(141.77,174.73) v4(141.77,169.16) v4(141.77,136.02) v4(142.4,132.11) v4(142.53,171.28) v4(143.09,147.72) v4(143.23,182.5) v4(143.29,137.54) v4(143.46,177.15) v4(143.92,180.35) v4(143.94,140.74) v4(144.05,183.83) v4(144.03,146.33) v4(144,130.81) v4(144.05,189.61) v4(144.05,169.16) v4(144.05,135.36) v4(144.15,175.79) v4(144.23,173.58) v4(144.15,144.25) v4(144.15,139.42) v4(144.3,186.13) v4(144.25,178.28) v4(144.25,149) v4(144.43,193.29) v4(144.43,133.08) v4(144.61,147.73) v4(144.81,137.59) v4(144.86,171.32) v4(145.03,177.15) v4(145.45,193.29) v4(145.63,8) v4(145.63,6.07) v4(146.34,193.29) v4(147.23,193.29) v4(148.12,193.29) v4(148.12,147.45) v4(148.46,203.84) v4(148.75,181.1) v4(148.75,130.3) v4(148.88,143.76) v4(148.88,141.73) v4(149.13,205.74) v4(149.89,187.45) v4(150.34,177.11) v4(150.35,137.54) v4(150.58,213.82) v4(150.62,171.84) v4(150.79,142.49) v4(151.14,5.84) v4(152.18,187.45) v4(152.38,191.39) v4(153.58,16.13) v4(154.47,30.61) v4(155.35,31.5) v4(155.35,29.72) v4(156.01,184.66) v4(156.01,165.99) v4(156.01,164.08) v4(156.01,162.18) v4(156.01,159.38) v4(156.01,154.94) v4(156.24,30.61) v4(156.7,204.98) v4(157.51,205.79) v4(157.51,204.98) v4(157.51,204.17) v4(158.33,204.98) v4(161.58,102.87) v4(161.68,78.23) v4(161.93,106.6) v4(161.96,108.71) v4(162.59,78.23) v4(162.83,104.29) v4(164.12,204.98) v4(168.21,150.48) v4(168.21,149.72) v4(168.21,148.96) v4(172.12,127.03) v4(176.06,125.29) v4(176.06,107.31) v6(72.78,102.11) v7(1.14,228.86) v7(1.14,223.78) v7(1.14,218.7) v7(1.14,213.62) v7(1.14,208.54) v7(1.14,203.46) v7(1.14,198.38) v7(1.14,193.3) v7(1.14,188.22) v7(1.14,183.14) v7(1.14,178.06) v7(1.14,172.98) v7(1.14,167.9) v7(1.33,153.97) v7(4.58,152.32) v7(5.14,148.38) v7(5.14,143.3) v7(5.14,138.22) v7(5.14,133.14) v7(5.37,177.04) v7(5.49,184.15) v7(5.49,170.18) v7(6.22,228.86) v7(8.29,184.66) v7(8.54,180.21) v7(8.54,175.39) v7(8.8,170.81) v7(10.22,133.14) v7(11.3,228.86) v7(15.3,133.14) v7(16.38,228.86) v7(20.2,206.39) v7(20.2,205.47) v7(20.2,204.56) v7(20.2,203.64) v7(20.2,202.73) v7(20.38,133.14) v7(21.14,73.86) v7(21.14,67.18) v7(21.14,62.1) v7(21.14,57.02) v7(21.14,41.78) v7(21.14,36.7) v7(21.14,31.62) v7(21.14,26.54) v7(21.14,21.46) v7(21.14,16.38) v7(21.14,11.3) v7(21.14,6.22) v7(21.14,1.14) v7(21.46,228.86) v7(23.32,9.69) v7(24.93,153.67) v7(24.93,152.65) v7(24.93,151.64) v7(25.46,133.14) v7(25.94,153.67) v7(25.94,152.65) v7(25.94,151.64) v7(26.22,73.86) v7(26.45,196.57) v7(26.54,228.86) v7(26.86,1.14) v7(26.96,153.67) v7(26.96,152.65) v7(26.96,151.64) v7(28.23,157.1) v7(28.23,156.18) v7(28.86,154.94) v7(28.91,131.98) v7(28.99,197.49) v7(29.14,126.97) v7(29.14,121.89) v7(29.14,116.81) v7(29.14,111.73) v7(29.14,106.65) v7(29.14,101.57) v7(29.14,96.49) v7(29.14,91.41) v7(29.14,86.33) v7(29.14,81.25) v7(29.14,76.17) v7(29.9,197.42) v7(30.82,201.99) v7(30.82,201.08) v7(30.82,200.17) v7(30.82,199.25) v7(30.82,198.34) v7(30.82,197.42) v7(31.62,228.86) v7(31.73,201.99) v7(31.73,201.08) v7(31.73,200.17) v7(31.73,199.25) v7(31.73,198.34) v7(31.73,197.42) v7(31.94,1.14) v7(32.09,72.06) v7(32.29,164.34) v7(32.65,201.99) v7(32.65,201.08) v7(32.65,200.17) v7(32.65,199.25) v7(32.65,198.34) v7(32.65,197.42) v7(32.8,72.64) v7(33.31,164.34) v7(33.56,201.99) v7(33.56,201.08) v7(33.56,200.17) v7(33.56,199.25) v7(33.56,198.34) v7(33.56,197.42) v7(34.93,201.99) v7(34.93,201.08) v7(34.93,200.17) v7(34.93,199.25) v7(34.93,198.34) v7(34.93,197.42) v7(35.85,201.99) v7(35.85,201.08) v7(35.85,200.17) v7(35.85,199.25) v7(35.85,198.34) v7(35.85,197.42) v7(36.7,228.86) v7(36.76,202.1) v7(36.76,201.18) v7(36.76,200.27) v7(36.76,199.35) v7(36.76,198.44) v7(36.76,197.47) v7(37.02,1.14) v7(37.68,201.99) v7(37.68,201.08) v7(37.68,200.17) v7(37.68,199.25) v7(37.68,198.34) v7(37.68,197.42) v7(38.59,201.99) v7(38.59,201.08) v7(38.59,200.17) v7(38.59,199.25) v7(38.59,198.34) v7(38.59,197.42) v7(39.5,197.42) v7(40.42,214.02) v7(40.49,197.46) v7(41.41,214.05) v7(41.54,222.19) v7(41.54,221.27) v7(41.54,220.36) v7(41.54,219.45) v7(41.78,228.86) v7(42.1,1.14) v7(42.96,196.57) v7(43.16,55.88) v7(44.27,54.88) v7(45.19,54.88) v7(46.13,54.86) v7(46.86,228.86) v7(47.15,54.86) v7(47.18,1.14) v7(50.12,223.22) v7(50.12,222.3) v7(50.12,221.39) v7(50.12,220.47) v7(50.12,219.56) v7(50.43,225.04) v7(50.43,224.13) v7(51.04,223.22) v7(51.04,222.3) v7(51.04,221.39) v7(51.04,220.47) v7(51.04,219.56) v7(51.34,225.04) v7(51.34,224.13) v7(51.94,228.86) v7(51.95,223.22) v7(51.95,222.3) v7(51.95,221.39) v7(51.95,220.47) v7(51.95,219.56) v7(51.95,218.64) v7(51.95,217.73) v7(51.95,216.81) v7(51.95,215.9) v7(52.26,225.04) v7(52.26,224.13) v7(52.26,1.14) v7(52.87,223.22) v7(53.17,225.04) v7(53.17,224.13) v7(53.78,223.22) v7(54.08,225.04) v7(54.08,224.13) v7(54.69,223.22) v7(54.69,222.3) v7(55,225.04) v7(55,224.13) v7(55.91,225.04) v7(55.91,224.13) v7(56.83,225.04) v7(56.83,224.13) v7(57.02,228.86) v7(57.34,1.14) v7(57.74,225.04) v7(57.74,224.13) v7(58.66,225.04) v7(58.66,224.13) v7(59.57,225.04) v7(60.49,225.04) v7(61.4,225.04) v7(61.4,224.13) v7(62.1,228.86) v7(62.31,225.04) v7(62.31,224.13) v7(62.42,1.14) v7(63.23,225.04) v7(63.23,224.13) v7(64.14,225.04) v7(64.14,224.13) v7(65.06,225.04) v7(65.06,224.13) v7(67.18,228.86) v7(67.5,1.14) v7(72.26,228.86) v7(72.58,1.14) v7(77.34,228.86) v7(77.66,1.14) v7(82.42,228.86) v7(87.5,228.86) v7(87.82,1.14) v7(92.58,228.86) v7(92.9,1.14) v7(97.66,228.86) v7(97.98,1.14) v7(101.38,79.12) v7(102.4,79.12) v7(102.74,228.86) v7(103.06,1.14) v7(103.67,79.12) v7(104.94,79.12) v7(107.82,228.86) v7(108.14,1.14) v7(109.61,61.24) v7(110.52,61.24) v7(110.52,60.33) v7(112.9,228.86) v7(113.22,1.14) v7(117.98,228.86) v7(118.3,1.14) v7(119.92,17.91) v7(119.92,16.99) v7(119.92,16.08) v7(119.92,15.16) v7(120.45,12.8) v7(120.51,10.87) v7(120.58,11.81) v7(120.84,17.91) v7(120.84,16.99) v7(120.84,16.08) v7(120.84,15.16) v7(121.04,10.03) v7(121.32,12.4) v7(121.42,11.25) v7(121.75,17.91) v7(121.75,16.99) v7(121.75,16.08) v7(121.75,15.16) v7(122.16,12.78) v7(122.16,11.81) v7(122.66,15.16) v7(123.06,228.86) v7(123.38,1.14) v7(128.14,228.86) v7(128.46,1.14) v7(133.22,228.86) v7(133.22,223.78) v7(133.54,1.14) v7(134.56,16.6) v7(134.56,15.54) v7(134.56,14.48) v7(134.56,13.42) v7(134.56,12.35) v7(135.03,216.15) v7(135.62,16.6) v7(135.62,15.54) v7(135.62,14.48) v7(135.62,13.42) v7(135.62,12.35) v7(138.3,228.86) v7(138.3,223.78) v7(138.3,218.7) v7(138.62,1.14) v7(141.1,86.74) v7(141.49,89.6) v7(141.49,88.68) v7(141.49,87.77) v7(142.02,86.74) v7(142.41,89.6) v7(142.41,88.68) v7(142.41,87.77) v7(142.91,87) v7(143.38,228.86) v7(143.38,223.78) v7(143.38,218.7) v7(143.49,89.59) v7(143.49,88.67) v7(143.49,87.76) v7(143.7,1.14) v7(143.8,86.74) v7(148.46,228.86) v7(148.46,218.7) v7(148.78,1.14) v7(153.54,228.86) v7(153.54,223.78) v7(153.54,218.7) v7(153.86,11.3) v7(153.86,6.22) v7(153.86,1.14) v7(158.62,228.86) v7(158.62,218.7) v7(158.7,16.14) v7(164.5,216.28) v7(164.5,211.71) v7(168.86,218.7) v7(168.86,213.62) v7(168.86,208.54) v7(168.86,203.46) v7(168.86,198.38) v7(168.86,193.3) v7(168.86,188.22) v7(168.86,183.14) v7(168.86,178.06) v7(168.86,172.98) v7(168.86,167.9) v7(168.86,162.82) v7(168.86,56.78) v7(168.86,51.7) v7(168.86,46.62) v7(168.86,41.54) v7(168.86,36.46) v7(168.86,31.38) v7(168.86,26.3) v7(173.7,161.26) v7(173.7,156.18) v7(173.7,151.1) v7(173.7,146.02) v7(173.7,140.94) v7(173.7,135.86) v7(178.14,122.01) v7(178.14,116.93) v7(178.14,111.85) v7(178.27,100.68) v7(178.27,95.6) v7(178.27,90.52) v7(178.78,161.26) v7(178.78,156.18) v7(178.78,151.1) v7(178.78,146.02) v7(178.78,140.94) v7(178.78,135.86) v7(178.78,130.78) v7(178.78,125.7) v7(178.78,85.06) v7(178.78,68.04) v7(179.11,106.09) v7(183.58,123.44) v7(183.58,109.98) v7(183.58,102.36) v7(183.58,88.9) v7(183.86,161.26) v7(183.86,156.18) v7(183.86,151.1) v7(183.86,146.02) v7(183.86,140.94) v7(183.86,135.86) v7(183.86,125.7) v7(183.86,85.06) v7(183.86,69.82)
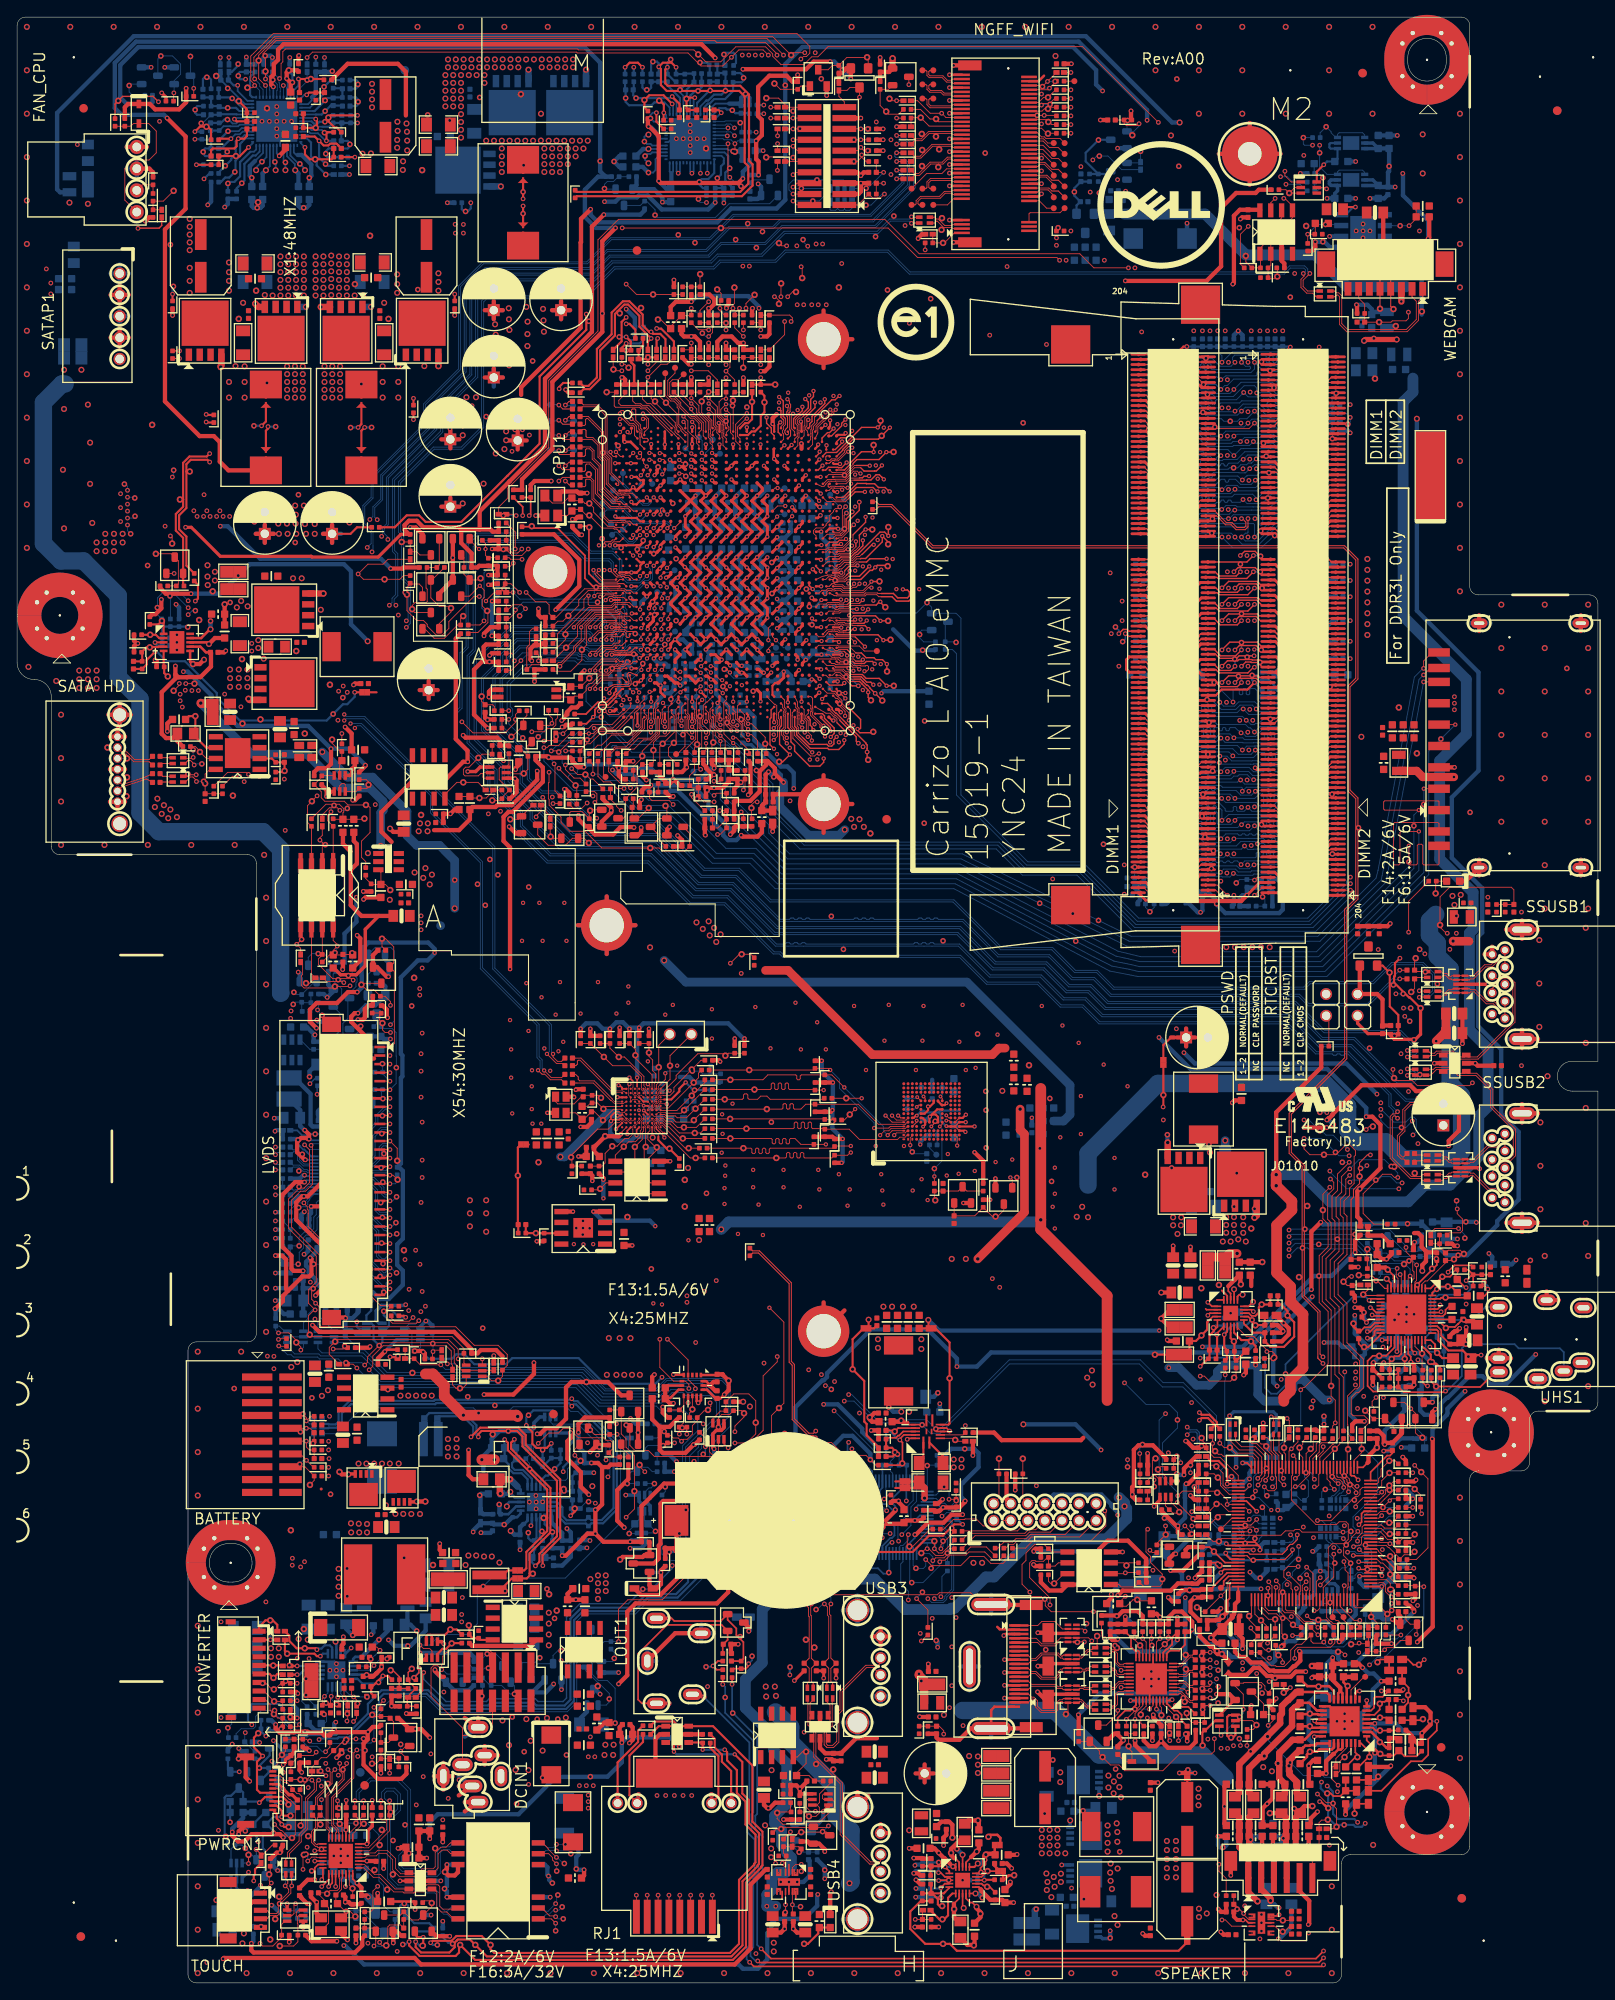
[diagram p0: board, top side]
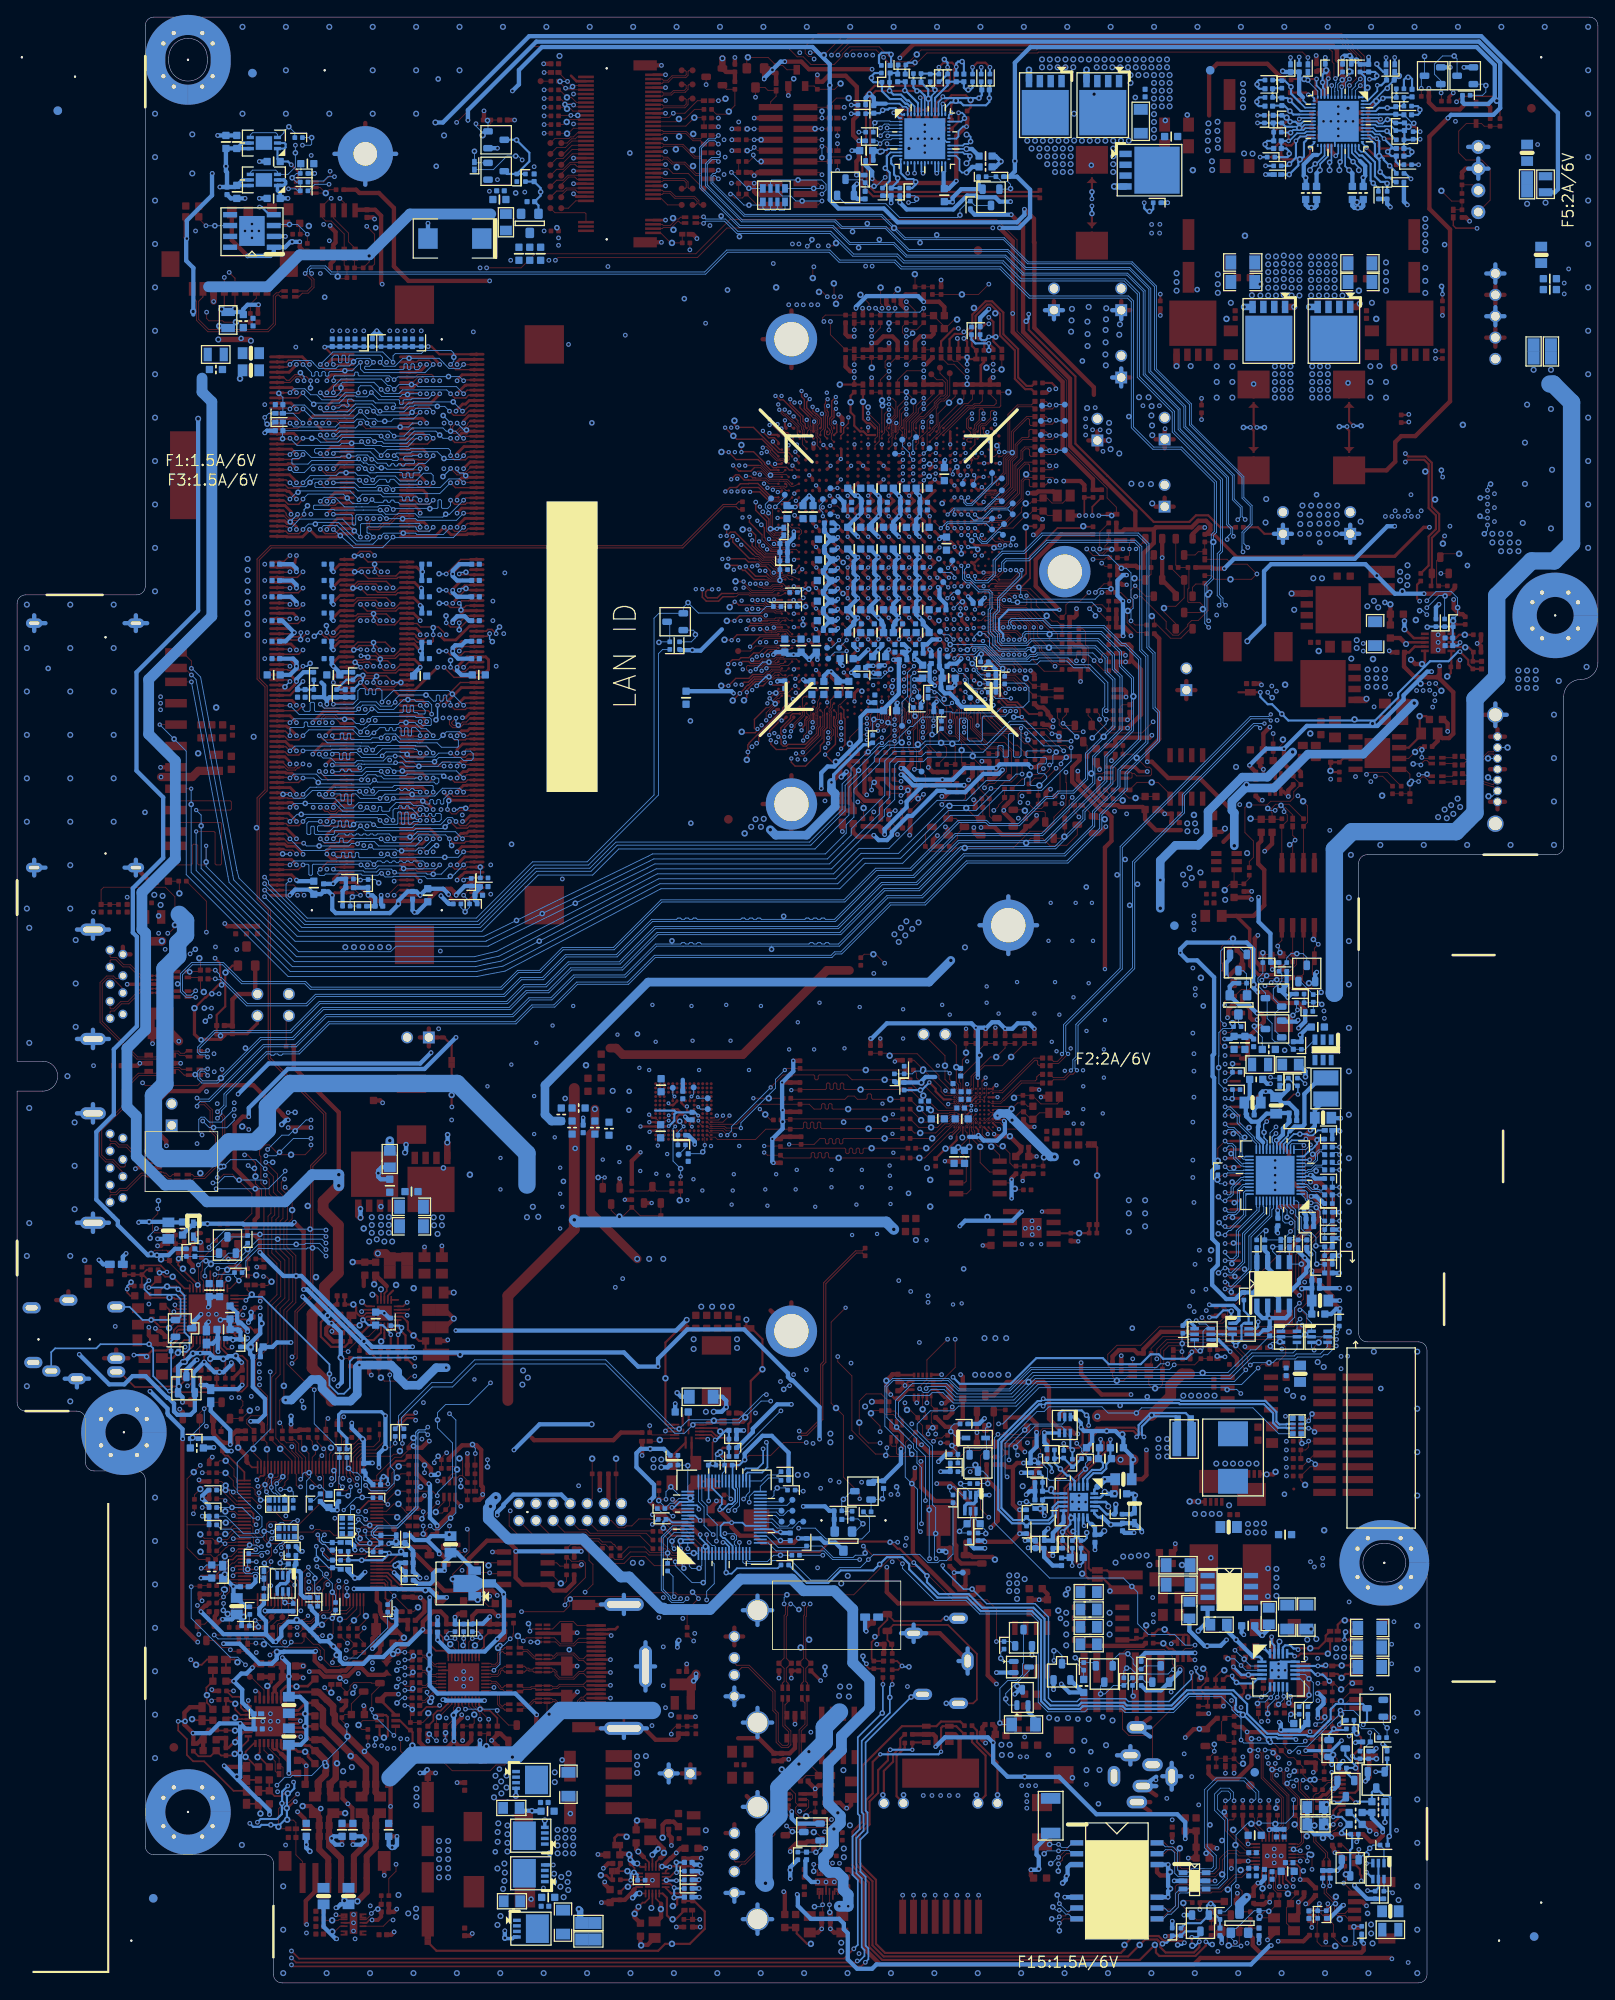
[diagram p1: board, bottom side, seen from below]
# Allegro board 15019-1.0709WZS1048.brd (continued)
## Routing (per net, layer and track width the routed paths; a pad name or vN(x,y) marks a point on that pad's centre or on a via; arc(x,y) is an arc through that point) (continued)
GND_AUD: length 6.2
  TOP w0.203: C145.2 168.63,77.09 168.61,77.09 168.26,76.75 167.33,76.75 v1(167.21,76.63) 167.2,76.63 166.59,77.23 U6.40
  TOP w0.508: C144.1 170.44,77.42 169.56,77.42 169.31,77.66 C145.2
VBAT1: length 7
  TOP w0.508: BT1.1 77.17,50.61 v4(77.11,50.55) 76.8,50.85 TP189.1 R1683.2
  BOTTOM w0.508: v4(77.11,50.55) 76.43,50.55 v2(76.31,50.42)
VBAT1_R: length 6.6
  TOP w0.508: R1683.1 75.34,48.25 v4(75.34,48.01) 75.34,46.66 74.84,46.15 D33.1 74.01,46.52 D23.1
  BOTTOM w0.305: TP188.1 v4(75.34,48.01)
VBAT2: length 82.7
  TOP w0.508: D33.2 73.01,45.39 75.27,45.39 80.17,50.29 80.17,58.8 79.94,59.03 v4(79.94,60.26) ; R707.2 137.98,61.59 136.56,60.17 v4(136.56,59.44)
  L3 w0.508: v4(79.94,60.26) 94.34,60.26 95.79,58.8 107.27,58.8 108.14,57.94 111.51,57.94 113.28,59.7 134.39,59.7 134.65,59.44 v4(136.56,59.44)
  BOTTOM w0.508: v2(135.71,59.56) 135.84,59.44 v4(136.56,59.44)
VBAT_SB_N: length 9.4
  TOP w0.254: PU4.2 159.8,119.02 v1(160.61,118.21) 160.64,118.18 160.64,114.25 161.64,113.25 C871.1 R1721.2
VBAT_SIO: length 8.5
  TOP w0.203: v4(141.61,58.38) U109.66
  TOP w0.254: v4(141.61,58.38) 141.61,60.06 140.61,61.07 139.69,61.07 R707.1
  BOTTOM w0.254: v4(141.61,58.38) 141.61,59.03 141.82,59.23 v2(142.12,59.23) 142.26,59.23 142.46,59.03 C1821.1
VCC: length 742.2
  TOP w0.203: U52.13 147.54,7.84 v4(147.68,7.98)
  TOP w0.508: v4(130.83,28.36) 130.83,27.82 D31.A ; v4(54.64,68.83) 58.07,68.83 60.49,71.25 v4(60.49,72.57) ; R6705.1 v7(84.97,68) ; R1838.2 138.53,47.12 138.13,46.71 137.53,46.71 137.51,46.74 135.85,46.74 135.01,45.9 129.37,45.9 v4(128.81,45.34) ; R2080.1 v4(55.79,73.38)
  L3 w0.508: v4(55.79,73.38) 56.6,72.57 v4(60.49,72.57) ; 54.52,67.21 54.52,68.71 v4(54.64,68.83) ; v7(163.81,183.01) 162.64,183.01 149.28,196.37 149.28,198.78 136.05,212.01 v7(136.05,217.67) ; v4(59.86,23.23) 58.31,23.23 55.07,19.99 47.56,19.99 v4(46.72,20.83)
  L3 w2.032: 32.01,111.15 32.01,78.11 32.8,77.32 32.8,76.47 35.63,73.64 35.63,72.94 41.36,67.21 56.6,67.21 57.46,68.07 61.94,68.07 64.1,65.91 65.37,65.91 67.91,68.45 72.3,68.45 74.84,65.91 76.1,65.91
  L4 w0.508: v4(47.15,38.61) 47.04,38.61 46.29,37.86 46.29,21.26 v4(46.72,20.83) ; v4(130.83,28.36) 130.83,29.91 131.49,30.57 131.49,31.12 130.24,32.37 130.03,32.37 129.64,32.76 129.64,34.08 129.86,34.3 129.86,34.84 128.01,36.69 128.01,43.65 128.81,44.45 v4(128.81,45.34) 128.81,46.35 128.04,47.12 128.04,50.03 128.81,50.79 v4(128.81,54.74) ; v4(59.86,23.23) 59.96,23.23 62.26,25.53 71.79,25.53 73.76,27.5 73.76,28.89 72.47,30.18 72.47,43.96 72.78,44.27 74.28,44.27 79.28,49.28 79.28,50.93 78.01,52.2 78.01,53.72 79.84,55.55 79.84,59.43 78.57,60.7 78.57,61.44 79.82,62.69 79.82,64.93 v4(80.3,65.41)
  L4 w2.032: 95.54,59.18 97.09,57.63 97.09,48.67 103.67,42.09 103.67,34.87 105.16,33.38 107.68,33.38 ; 147.67,10.77 148.39,11.49 148.39,22.73
  BOTTOM w0.508: R1849.1 53.45,38.12 52.97,38.61 v4(47.15,38.61) ; v4(128.81,54.74) 128.81,55.05 128.07,55.79 128.07,55.96 126.9,57.13 121.32,57.13 LPC1.8 ; C1833.1 147.14,9.19 147.54,8.79 v4(147.68,8.79) ; v7(136.05,217.67) 135.17,217.67 125.07,227.77 13.66,227.77 4.68,218.79 4.68,209.85 5.04,209.5 F5.1 ; v4(130.83,28.36) 130.83,26.79 130.72,26.67 ; v7(163.81,183.01) 163.81,160.55 171.03,153.34 171.03,141.83 167.9,138.71 167.9,131.62 171.46,128.07 171.46,122.89 170.98,122.4 170.98,111.94 173.68,109.23 173.68,101.61 173.68,101.61 175.72,99.57 175.72,91.65 173.77,89.69 173.21,89.13 173.21,88.66 169.69,85.14 v2(168.64,85.14) 167.27,85.14 166.52,85.89 R617.1
  BOTTOM w2.032: 141.36,24 138.69,26.67 126.63,26.67 121.42,31.88 110.65,31.88 ; 5.62,187.07 5.24,187.07 3.08,184.91 3.08,168.4 5.11,166.37 7.78,166.37 11.84,162.31 11.84,152.76 14.38,150.22 14.38,136.91 16.59,134.7 28.79,134.7 30.84,132.64 30.84,115.8 30.87,115.82
  vias: v4(32.01,112.85) v4(32.06,113.72) v4(109.12,32.2) v7(5.49,188.73) v7(6.13,208.29) v7(7.53,188.73) v7(8.29,208.15) v7(85.76,67.44) v7(92.62,59.44) v7(93.63,59.44) v7(108.47,31.36) v7(145.83,25.25) v7(146.85,24.77)
VCC3: length 1327.4
  TOP w0.203: U6.11 160.79,81.86 v7(160.28,82.37) ; U118.11 134.54,38.51 134.89,38.86 135.97,38.86 136.68,39.56 C3379.1 ; U118.37 v4(133.34,32.03)
  TOP w0.33: DIMM2.199 145.42,128.75 v4(143.92,127.25) ; DIMM1.199 132.12,128.75 v4(133.61,127.25)
  TOP w0.356: CPU1.AP19 v3(85.4,156) CPU1.AP21
  TOP w0.508: R366.1 130.92,56.52 130.51,56.92 v4(130.51,57.15) 130.51,57.65 130.49,57.68 130.49,57.99 130.69,58.19 130.69,62.36 131.23,62.9 132.93,62.9 134.46,61.36 R381.2 ; R12.1 156.81,196.28 v4(156.75,196.34) ; R308.2 163.53,58.67 v4(163.71,58.85) ; v4(133.88,28.31) 134.68,27.51 137.24,27.51 137.93,28.19 R634.2 ; v4(133.88,28.31) C3380.2 ; v4(133.88,28.31) 133.27,27.7 132.51,27.7 131.85,28.36 R1596.1 ; R143.1 45.56,24.46 44.98,23.88 42.2,23.88 40.55,25.53 40.55,28.02 41.03,28.5 41.03,29.34 ; v4(30.18,78.89) 30.23,78.89 31.1,79.76 31.1,80.37 31.71,80.98 ; v4(81.57,142.11) 81.57,142.37 81.31,142.62 R79672.2 R162.2 R1674.2 ; R160.1 70.83,140.84 70.42,141.25 v4(70.42,142.14) 70.42,142.21 70.26,142.37 R1684.1 ; R138.1 42.36,29.95 41.64,29.95 v4(41.05,29.36) 41.03,29.34 ; v4(130.36,219.02) 130.36,218.05 R1716.2 ; v4(34.3,84.84) 34.45,84.68 34.45,82.91 34.2,82.65 33.38,82.65 31.71,80.98 ; 164.88,85.6 164.88,84.43 164.45,84 v7(164.45,83.31) ; 164.88,85.6 165.01,85.47 166.09,85.47 R213.1 ; 164.88,85.6 164.37,86.11 164.37,87.33 163.96,87.73 163.48,87.73 ; R2025.2 76.49,196.09 77.1,196.7 v4(78.9,196.7) R2026.1 ; 41.03,29.34 36.93,29.34 R1757.1 36.55,28.96 35.97,28.96 35.64,29.29 34.09,29.29 33.99,29.39 v4(33.69,29.39) 32.47,29.39 32.4,29.31 30.72,29.31 30.26,29.77 v4(30.26,30.23) ; 75.2,65.06 75.2,62.37 75.56,62.01 78.21,62.01 v4(79.16,62.96) 79.19,62.99 79.32,62.99 R6703.1 ; 75.2,65.06 76.36,65.06 77.45,66.15 R6704.1 ; 75.2,65.06 74.33,65.94 R6701.1 ; v4(27.41,4.62) 27.41,3.81 27.67,3.56 39.56,3.56 40.39,4.39 40.39,5.25 R1183.2 ; v4(30.23,85.09) 31.02,85.09 31.48,84.63 31.48,81.2 31.71,80.98 ; v4(41.31,74.45) 41.18,74.32 R57.1 ; R1868.1 R159.2 R1687.1 84.04,138.3 85.8,138.3 86.9,139.4 86.9,141.76 87.66,142.52 R1749.2 ; v4(154.72,39.9) 155.1,40.28 R1829.2 R341.2 R334.2 ; v4(163.48,43.43) 163.48,43.64 163.01,44.12 162.86,44.12 R316.2 ; R1673.2 R1674.2 ; R1674.2 83.28,143 R1662.1 R1659.1 ; R71.1 12.61,219.46 12.99,219.84 D1.K 15.53,219.84 16.16,219.2 18.96,219.2 19.78,220.03 R508.1 v4(19.78,221.67) ; R1749.2 87.85,142.94 88.68,142.11 88.68,141.48 v4(89.7,140.46) ; R1749.2 R1926.2 ; v4(45.55,31.52) 45.59,31.48 R134.1 ; v4(35.03,111.71) 34.27,112.47 34.27,113.88 35.04,114.65 37.44,114.65 38.72,115.93 v4(39.81,115.93) ; v4(157.66,65.71) 156.62,65.71 156.24,65.33 R680.2 ; R1594.1 128.62,42.99 v4(128.68,42.93) 128.82,42.93 129.39,43.49 131.16,43.49 131.72,42.94 R1593.1 R2088.1 R1598.1 R2087.1 134.77,42.78 135.43,43.45 136.31,43.45 137.51,42.25 v4(137.51,41.35) 137.26,41.09 C3379.1 ; v4(70.39,34.98) 71.41,35.99 71.41,43.43 72.37,44.4 81.9,44.4 83.22,45.72 v4(83.22,48.64) ; R1699.1 115.79,56.58 LPC1.4 ; v4(143.92,127.25) 143.26,126.59 137.01,126.59 135.69,127.91 134.87,127.91 134.78,128.01 134.23,128.01 133.84,127.62 133.84,127.49 v4(133.61,127.25) ; R1657.2 R1661.1 75.22,141.22 75.85,140.59 75.85,140.4 R1872.1 76.41,140.34 76.72,140.64 v4(76.72,140.78) 76.89,140.78 77.55,140.12 77.79,140.12 R1870.1 ; v3(57.69,118.62) 57.69,132.84 56.93,133.61 56.93,136.43 57.5,137.01 58,137.01 61.53,140.53 61.53,142.21 60.68,143.07 R1776.1 62.04,143.51 62.19,143.36 64.76,143.36 R1650.1 64.99,142.91 65.21,142.69 65.56,142.34 65.59,142.34 65.69,142.24 v4(66.33,142.24) ; v4(91.35,223.24) R1701.1 90.75,222.44 90.05,223.14 88.03,223.14 86.72,221.83 86.72,218.42 87.16,217.99 87.16,216.18 v4(86.49,215.52) 86.49,213.39 86.77,213.11 v4(86.77,211.52) ; v3(134.98,48.25) 135.05,48.25 135.06,48.26 136.46,48.26 138.3,50.1 R1837.2 ; v4(110.65,54.78) 109.34,54.78 108.41,53.85 106.59,53.85 105.19,52.45 v4(105.06,52.45)
  TOP w0.965: v4(168.15,141.09) 164.51,141.09 163.79,141.81 F6.2
  TOP w1.016: 87.59,118.47 90.23,118.47 100.08,108.61 114.13,108.61 114.89,109.37 115.63,109.37
  L3 w0.254: v3(85.4,156) 86.05,155.35 87.84,155.35 89.01,154.17 89.01,150.93 89.21,150.73 89.21,144.65 89.7,144.17 v4(89.7,140.46)
  L3 w0.508: v4(86.16,58.58) 86.51,58.58 89.02,56.07 91.27,56.07 92.38,54.97 98.07,54.97 99.08,53.95 100.34,53.95 101.18,53.11 101.56,53.11 101.63,53.19 101.65,53.19 102.41,53.95 103.94,53.95 105.06,52.83 v4(105.06,52.45) ; v4(163.71,58.85) 159.41,58.85 157.06,56.49 155.86,56.49 154,54.64 v4(153.55,54.64) ; v4(33.69,29.39) 33.36,29.39 31.91,27.94 31.91,25.35 31.42,24.87 31.38,24.87 v4(31.15,24.64) ; v4(79.16,62.96) 79.19,62.99 79.41,62.99 80.25,63.83 v4(87.41,63.83) ; 133.61,127.32 132.89,128.04 127.78,128.04 121.53,134.29 97.49,134.29 v7(96.86,134.92) ; 133.61,127.32 v4(133.61,127.25) ; 133.61,127.32 133.61,127.39 134.87,128.65 136.64,128.65 138.6,130.61 142.53,130.61 143.16,129.97 146.9,129.97 147.23,129.64 150.5,129.64 150.78,129.92 153.11,129.92 153.84,130.65 153.84,142.38 157.26,145.8 v7(157.32,145.8) ; v4(93.4,225.84) 91.78,227.46 32.06,227.46 v4(29.88,225.27) 29.09,224.49 22.56,224.49 19.78,221.71 v4(19.78,221.67) ; v4(130.82,200.66) 130.82,216.79 130.36,217.25 v4(130.36,219.02) ; v4(162.85,65.12) 162.82,65.15 162.16,65.15 161.68,65.63 157.74,65.63 v4(157.66,65.71) ; v4(35.03,111.71) 35.14,111.71 35.54,111.3 35.54,109.27 37.5,107.31 37.5,105.85 38.14,105.21 v4(38.31,105.21) ; v4(156.55,78.11) 156.78,78.34 156.82,78.34 157.21,78.73 157.21,80.04 156.82,80.42 156.82,80.97 158.22,82.37 v7(160.28,82.37) ; v4(37.78,80.6) 37.78,77.22 40.55,74.45 v4(41.31,74.45) 41.31,73.69 43.86,71.13 60.91,71.13 63.25,73.48 86.7,73.48 87.41,72.77 v4(87.41,72.52) ; v4(86.82,195.94) 86.82,196.11 86.14,196.79 86.14,199.64 86.82,200.33 86.82,206.17 87.43,206.78 87.43,210.86 v4(86.77,211.52) ; v4(130.51,57.15) 130.13,57.53 121.95,57.53 121.56,57.13 117.75,57.13 116.7,56.09 LPC1.4 115.24,57.13 113.76,57.13 111.41,54.78 v4(110.65,54.78) ; v3(48.87,120.52) 50.77,118.62 v3(57.69,118.62) 84.23,118.62 v4(84.74,118.11) ; v4(70.39,34.98) v4(62.79,34.98) 49,34.98 v4(45.55,31.52) 43.39,29.36 v4(41.05,29.36)
  L3 w1.016: v4(156.75,196.34) 158.66,194.44 158.66,189.51 163.06,185.1 164.82,185.1 167.29,182.62 167.29,141.84 168.05,141.09 v4(168.15,141.09)
  L4 w0.508: 86.14,58.58 86.14,62.56 v4(87.41,63.83) v4(87.41,72.52) 87.41,74.4 83.04,78.77 83.04,81.99 79.81,85.22 v7(79.81,86.92) ; 86.14,58.58 v4(86.16,58.58) ; 86.14,58.58 85.12,57.57 85.12,50.55 v4(83.22,48.64) ; v4(156.75,196.34) 154.38,198.71 154.31,198.71 153.68,199.34 143.16,199.34 142.95,199.56 141.55,199.56 141.34,199.34 132.13,199.34 v4(130.82,200.66) ; v4(154.72,39.9) 154.72,42.25 154.19,42.79 154.19,43.33 153.9,43.62 153.9,48.48 153.73,48.65 153.73,49.23 153.17,49.79 153.17,54.09 153.55,54.47 v4(153.55,54.64) ; v4(133.34,32.03) 133.36,32.05 134.57,32.05 134.65,31.98 135.11,31.98 135.28,31.81 135.82,31.81 136.21,32.2 136.21,33.36 135.99,33.58 135.99,34.44 136.9,35.36 136.9,40.7 137.51,41.31 v4(137.51,41.35) 137.51,41.99 136.06,43.45 135.06,43.45 133.97,44.54 133.97,46.33 134.98,47.35 v3(134.98,48.25) ; v4(30.23,85.09) 30.89,85.75 30.89,87.48 v4(30.23,88.14) 30.89,88.8 30.89,89.51 v4(30.23,90.17) ; v4(163.48,43.43) 162.88,42.84 162.88,41.21 162.82,41.15 162.82,40.39 162.9,40.31 162.9,32.72 162.89,32.71 162.89,28.89 150.49,16.49 150.49,7.67 148.43,5.61 148.22,5.61 147.76,5.16 v4(147.61,5.16) ; v4(81.57,142.11) 86.6,142.11 88.25,140.46 v4(89.7,140.46) ; v4(128.68,42.93) 128.82,42.93 130.46,44.57 130.46,51.59 130.82,51.95 130.82,56.84 v4(130.51,57.15) ; v4(91.35,223.24) 93.4,225.3 v4(93.4,225.84) 94.83,227.26 122.12,227.26 v4(130.36,219.02) ; v4(27.41,4.62) 27.59,4.8 27.59,7.63 28.23,8.26 28.23,9.68 29.34,10.79 29.88,10.79 30.72,11.63 30.72,12.01 32.9,14.19 32.9,22.89 v4(31.15,24.64) ; v4(163.71,58.85) 163.63,58.77 163.32,58.77 162.67,59.42 162.67,59.97 162.87,60.17 162.87,63.5 162.87,65.1 v4(162.85,65.12)
  BOTTOM w0.203: v4(105.06,52.45) 105.06,52.07 104.07,51.08 U4101.4
  BOTTOM w0.381: v4(89.7,140.46) 89.44,140.72 89.44,141.35 85.92,144.87 85.33,144.87 85.1,145.1 R79714.2
  BOTTOM w0.508: v4(147.61,5.16) 147.71,5.16 149.13,6.58 C1835.1 ; PR4624.1 28.86,225.3 v2(29.04,225.48) 29.67,225.48 v4(29.88,225.27) PR4632.1 ; 155.89,40.81 160.85,40.81 v4(163.48,43.43) ; 155.89,40.81 155.87,40.82 155.87,42.33 156.65,43.1 156.65,43.82 156.12,44.36 R294.1 ; 155.89,40.81 154.99,39.9 v4(154.72,39.9) 154.08,40.54 154.08,41.44 153.27,42.25 151.76,42.25 150.72,41.21 ; R517.1 v4(30.23,90.17) ; v4(38.31,105.21) 38.72,105.21 L16.1 ; v4(37.78,80.6) 36.29,80.6 34.98,81.9 34.98,82.27 34.13,83.12 34.13,83.59 33.82,83.9 33.82,84.35 v4(34.3,84.84) 35.09,85.62 R46.1 ; v4(37.78,80.6) 37.37,80.19 U25.3 ; v4(37.78,80.6) 40.5,80.6 ; R32.1 39.91,86.02 U25.8 39.91,81.19 40.5,80.6 ; 30.21,78.87 v4(30.18,78.89) ; 30.21,78.87 30.26,78.82 R1860.1 ; 30.21,78.87 30.61,78.87 31.22,78.26 L17.1 ; v4(137.51,41.35) 139.24,39.62 140.62,39.62 140.7,39.55 140.72,39.55 142.15,38.13 143.69,38.13 144.48,37.34 146.84,37.34 147.23,37.72 147.23,38.61 v2(147.97,39.36) 148.6,39.98 149.53,39.98 149.92,40.37 149.92,40.41 150.72,41.21 ; R58.1 R47.1 v4(30.23,85.09) ; v4(133.61,127.25) 133.61,127.32 132.6,128.33 R165.1 130.84,128.33 C1730.1 130.78,128.14 131.41,127.5 C1729.1 131.41,126.71 131.16,126.46 R1634.1 ; R41.1 34.26,112.48 v4(35.03,111.71) ; R377.1 27.64,4.85 v4(27.41,4.62) ; R530.2 v4(30.23,88.14) ; C1975.1 143.99,128.14 R2055.1 v4(143.92,127.25) 143.42,127.25 143.1,126.94 C1976.1 R2061.1 ; U119.3 133.56,50.34 C3367.1 134.27,49.91 134.98,49.2 v3(134.98,48.25) 135.94,48.25 136.33,47.86 136.33,47.04 136.66,46.71 138.13,46.71 138.53,47.12 R689.2 ; C509.1 157.74,74.41 L21.1 ; C509.1 157.73,74.79 156.55,75.98 v4(156.55,78.11) ; C509.1 157.73,73.58 C516.1 157.42,69.75 155.99,68.33 155.99,66.5 156.78,65.71 v4(157.66,65.71) ; 150.72,41.21 149.89,42.04 149.89,43.02 150.5,43.63 150.5,43.85 R79676.2 ; v4(81.57,142.11) 81.24,142.11 79.9,140.78 v4(76.72,140.78) 75.49,140.78 74.12,142.14 v4(70.42,142.14) 69.98,142.57 66.66,142.57 v4(66.33,142.24) ; v4(133.34,32.03) 133.88,31.49 v4(133.88,28.31) ; v4(86.82,195.94) 86.82,196.11 85.57,197.36 79.56,197.36 v4(78.9,196.7) ; R1986.2 v4(86.77,211.52) ; R1846.1 60.28,33.98 ; 60.28,33.98 D19.2 ; 60.28,33.98 61.85,33.98 62.79,34.92 v4(62.79,34.98) ; v4(39.81,115.93) 40.34,116.46 40.34,117.79 40.32,117.81 40.32,120.94 41.1,121.72 48.12,121.72 48.87,120.97 v3(48.87,120.52) 48.87,120.46 48.04,119.63 46.9,119.63 44.92,117.65 44.92,108.69 45.09,108.51 45.09,106.07 44.91,105.89 44.91,95.87 R482.1 44.7,95.44 45.14,95 45.14,87.07 44.48,86.41 44.48,84 45.14,83.34 45.14,81.66 43.49,80.01 42.43,80.01 41.66,80.78 R524.1 40.69,80.78 40.5,80.6 ; v4(156.75,196.34) 158.02,196.34 158.53,195.83 R24.1 158.83,195.5 F1.1 ; v4(30.26,30.23) 29.75,30.73 R2077.1 ; C1714.1 86.46,154.94 v3(85.4,156) ; PR5463.1 v4(86.49,215.52)
  BOTTOM w1.016: v7(96.86,134.92) 96.22,134.28 92.6,134.28 89.26,137.62 89.26,139.14 89.7,139.57 v4(89.7,140.46)
  vias: v2(163.86,81.66)
VCC3_CAM: length 10
  TOP w0.61: v7(161.45,192.28) 157.77,192.28 157.64,192.15 v7(157.64,192.13)
  TOP w0.762: WEBCM1.3 v4(162,196.72)
  L3 w0.762: v7(161.45,192.28) 162,192.83 v4(162,196.72)
  vias: v2(158.78,192.41)
VCC5_33_CT1: length 2.5
  TOP w0.102: C1837.1 148.97,7.32 v1(148.13,7.32) 147.43,7.32 147.31,7.44 U52.12
VCC5_33_CT2: length 2.9
  TOP w0.102: C1836.1 148.93,6.6 148.32,5.99 v1(148.12,5.99) 147.84,5.99 147.19,6.64 U52.10
VCC5_33_EN: length 11.6
  TOP w0.102: U52.5 142.14,6.64 141.41,7.37 v4(141,7.37) ; R1878.1 C1831.1 142.48,9.19 v4(143.54,8.13) 143.54,8 144.11,7.44 U52.3
  L3 w0.127: v4(141,7.37) 141.77,8.13 v4(143.54,8.13)
  BOTTOM w0.102: v4(143.54,8.13) 143.04,8.64 v2(142.78,8.64)
VCC5_DDC_HDMI: length 6.5
  TOP w0.102: C6721.1 129.64,25.91 D31.K 130.46,27.05 130.08,27.43 v1(130.08,27.69) 130.08,28.89 R2083.1 R2084.1
VCC5_PANEL: length 13.5
  TOP w0.508: 41.77,108.15 41.36,108.15 40.98,108.53 40.98,110.57 39.1,112.45 39.1,113.06 39.5,113.46 v4(39.89,113.46)
  BOTTOM w0.508: R80233.2 42.71,116.97 43.09,116.59 Q9647.S 41.92,114.38 40.83,114.38 39.91,113.46 v4(39.89,113.46)
  vias: v2(43.67,109.58) v4(43.63,108.5) v4(43.63,107.5)
VCC5_USB: length 190.7
  L3 w0.508: v7(87.54,18.44) 87.54,17.91 86.65,17.02 86.65,13.72 86.27,13.34 86.27,6.14 83.43,3.3 44.86,3.3 v4(44.48,3.68)
  L4 w1.27: v7(87.54,18.44) 88.96,19.86 88.96,24.23 v7(88.3,24.89) ; v7(26.37,4.62) 26.37,3.78 26.88,3.28 44.08,3.28 v4(44.48,3.68)
  L4 w2.032: 87.41,45.59 87.41,36.59 86.11,35.29 86.11,32.92 88.3,30.73 v7(88.3,24.89)
  BOTTOM w2.032: 125.33,93.34 125.33,97.05 133.51,105.23 153.04,105.23 155.71,102.57 155.71,99.8 157.11,98.4 160.21,98.4 162.16,96.44 168.18,96.44 169.04,97.31 169.04,103.81 167.7,105.16 167.7,118.64 166.2,120.14 166.2,121.67 165.29,122.58 165.29,124.28 166.02,125.02
  vias: v2(168.44,124.84) v7(87.79,47.62) v7(88.55,46.74) v7(104.4,17.86) v7(111.92,49.15) v7(112.94,49.15) v7(124.01,89.64) v7(124.65,90.81) v7(125.23,70.82) v7(125.33,89.59) v7(125.79,71.65) v7(125.86,70) v7(167.98,127.18) v7(168.21,126.12) v7(168.94,127.3)
VCC_FAN: length 7.4
  TOP w0.508: R80.1 15.91,211.84 15.47,212.27 FANC3.2
  BOTTOM w0.508: FANC3.2 15.18,212.27 ; FANC3.2 14,213.45 ; FANC3.2 14,211.09 ; FANC3.2 12.82,212.27
VCC_VTT: length 2.2
  TOP w0.203: PU5001.2 139.21,78.76 139.1,78.87 ; PU5001.20 140.39,79.91
  vias: v1(138.59,81.28)
VDD_095_FB_H: length 80.5
  TOP w0.254: 19.43,173.56 19.43,177.85 20.17,178.59 22.2,178.59 v4(22.54,178.93) ; 19.43,173.56 v1(19.06,173.56) ; 19.43,173.56 19.43,172.72 18.58,171.86 18.58,169.93 19.43,169.07 Q14.S 19.43,163.54 R110.2 ; R1612.2 70.75,192.06 70.75,194.33 v4(71.28,194.87)
  L3 w0.254: v4(71.28,194.87) 71.09,194.68 64.45,194.68 53.5,183.72 53.5,181.38 51.51,179.39 49.28,179.39 48.96,179.39 48.16,178.58 22.89,178.58 v4(22.54,178.93)
VDD_095_FB_H_CTL: length 7
  TOP w0.102: v1(16.24,167.21) 18.06,167.21 Q14.D 18.87,166.39 18.87,163.68 R110.1 PR83.2
VDD_095_FB_L: length 76.7
  TOP w0.254: v4(71.28,194.11) 71.67,194.11 72.36,193.42 R1861.2 ; R80227.2 19.81,165.83 19.81,169.23 18.96,170.08 18.96,171.7 19.81,172.56 19.81,176.83 ; v1(20.2,176.83) 19.81,176.83 ; 19.81,176.83 19.81,177.69 20.33,178.21 22.27,178.21 v4(22.54,177.94)
  L3 w0.254: v4(71.28,194.11) 71.09,194.3 64.61,194.3 53.88,183.57 53.88,181.22 51.67,179.01 49.12,179.01 48.31,178.2 22.79,178.2 v4(22.54,177.94)
VDDCR_APU_FB_H: length 142.7
  TOP w0.254: v1(73.02,195.97) 72.73,195.68 ; 72.73,195.68 71.66,196.75 70.9,196.75 69.58,195.43 69.58,192.9 67.85,191.17 67.85,187.83 66.87,186.85 66.23,186.85 PR4628.2 ; 72.73,195.68 73.21,195.2 73.21,193.93 73.98,193.17 v4(74.2,193.17) 74.43,192.94 75.27,192.94 75.88,192.33 75.88,191.1 R1611.2
  L3 w0.254: v4(87.16,225.55) 87.16,225.49 86.96,225.3 86.96,223.59 91.45,219.1 94.08,216.48 94.08,203.64 v4(94.27,203.45)
  L4 w0.254: v4(23.78,225.27) 24.1,225.59 24.1,226.22 25.9,228.02 85.58,228.02 86.95,226.64 86.95,225.75 v4(87.16,225.55) ; v4(74.2,193.17) 73.98,193.17 73.64,193.51 73.64,198.03 77.01,201.39 92.65,201.39 94.27,203.01 v4(94.27,203.45)
  BOTTOM w0.254: PR4604.2 v4(23.78,225.27)
VDDCR_APU_FB_L: length 140.4
  TOP w0.254: PR4611.2 66.29,186.47 67.02,186.47 68.23,187.68 68.23,191.01 69.96,192.74 69.96,195.27 70.28,195.59 ; v1(70.52,195.35) 70.28,195.59 ; 70.28,195.59 71.06,196.37 71.5,196.37 72.83,195.04 72.83,193.78 v4(74.2,192.41) 73.82,192.02 R528.2
  L3 w0.254: v4(86.39,225.55) 86.58,225.36 86.58,223.43 93.7,216.32 93.7,203.64 v4(93.51,203.45)
  L4 w0.254: v4(24.8,225.27) 24.48,225.59 24.48,226.06 26.06,227.64 85.42,227.64 86.57,226.48 86.57,225.73 v4(86.39,225.55) ; v4(93.51,203.45) 93.51,202.79 92.49,201.78 76.85,201.78 73.26,198.18 73.26,193.35 v4(74.2,192.41)
  BOTTOM w0.254: PR4606.2 v4(24.8,225.27)
VDDCR_CPU_SENSE: length 17.8
  TOP w0.102: R1611.1 75.41,189.74 74.94,189.74 v4(73.82,188.62) ; CPU1.G12 79.19,177.1 v3(78.89,177.4)
  L4 w0.127: v4(73.82,188.62) 73.35,188.15 73.35,187.66 75.62,185.39 75.62,183.44 78.47,180.59 78.47,177.81 v3(78.89,177.4)
  BOTTOM w0.102: v2(78.22,177.69) 78.59,177.69 v3(78.89,177.4)
VDDCR_GFX_FB_H: length 55.2
  TOP w0.254: v4(71.28,191.82) 70.77,191.31 R1953.2
  L3 w0.254: v4(71.28,191.82) 71.09,192.01 70.25,192.01 69.99,191.76 69.99,191.06 70.42,190.63 86.87,190.63 87.66,191.42 87.66,196.42 87.34,196.74 87.34,197.83 88.07,198.56 88.07,211.12 87.84,211.35 87.84,216.47 86.85,217.46 86.85,219.18 v4(87.38,219.71)
  BOTTOM w0.254: PR5410.2 73.31,192.28 72.85,191.82 v4(71.28,191.82) v2(71.28,191.01) ; PR5420.2 v4(87.38,219.71)
VDDCR_GFX_FB_L: length 55.7
  TOP w0.254: R1954.2 71.81,191.05 71.81,192.05 v4(71.28,192.58)
  L3 w0.254: v4(71.28,192.58) 71.09,192.39 70.09,192.39 69.61,191.91 69.61,190.9 70.26,190.25 87.03,190.25 88.04,191.26 88.04,196.58 87.72,196.9 87.72,197.67 88.45,198.4 88.45,211.28 88.22,211.51 88.22,216.62 87.23,217.61 87.23,218.54 v4(87.38,218.69)
  BOTTOM w0.254: v2(70.47,192.58) v4(71.28,192.58) 71.66,192.2 72.1,192.2 72.3,192.39 PR5416.2 ; PR5422.2 v4(87.38,218.69)
VDDCR_GFX_SENSE: length 18.1
  TOP w0.102: R1953.1 v4(70.77,189.38) 71.13,189.38 71.53,188.98 v1(71.56,188.98) ; CPU1.H11 77.91,176.59 v3(77.5,176.59)
  L4 w0.127: v3(77.5,176.59) 76.82,177.28 76.82,178.48 76.22,179.08 76.22,181.68 74.67,183.22 74.67,184.11 73.29,185.49 73.29,185.7 72.6,186.39 72.39,186.6 72.07,186.92 72.07,188.09 v4(70.77,189.38)
VDDCR_NB_FB_H: length 149.5
  TOP w0.254: v4(74.85,193.57) 74.87,193.55 75.37,193.55 76.87,192.05 R1613.2 ; PR4643.2 44.2,170.31 45.6,171.7 47.04,171.7 47.8,170.94 51.99,170.94 57.38,176.33 57.38,176.33 61.15,180.09 61.15,187.95 66.61,193.41 v4(66.61,195.25)
  L3 w0.254: v4(84.94,200.86) 85.14,201.06 85.14,203.34 85.58,203.78 85.58,224.62 84.87,225.33 v4(84.87,225.55) ; v4(66.61,195.25) 68.44,197.08 71.8,197.08 74.85,194.03 v4(74.85,193.57)
  L4 w0.254: v4(74.85,193.57) 75.32,194.04 75.32,198.99 77.04,200.71 77.35,200.71 84.78,200.71 v4(84.94,200.86) ; v4(35.97,225.27) 35.97,225.8 36.92,226.75 84.91,226.75 85.12,226.54 85.12,225.81 v4(84.87,225.55)
  BOTTOM w0.254: v2(66.91,194.41) 66.61,194.71 v4(66.61,195.25) ; PR4642.2 v4(35.97,225.27)
VDDCR_NB_FB_L: length 116.3
  TOP w0.254: R529.2 74.84,192.28 v4(74.96,192.41)
  L3 w0.254: v4(25.81,222.02) 25.28,222.55 25.28,223.24 25.89,223.85 33.48,223.85 v4(34.96,225.32) ; v4(85.7,200.86) 85.52,201.04 85.52,203.18 85.96,203.63 85.96,224.77 85.63,225.1 v4(85.63,225.55)
  L4 w0.254: v4(74.96,192.41) 75.7,193.14 75.7,198.83 77.2,200.33 85.16,200.33 v4(85.7,200.86) ; v4(34.96,225.32) 36.76,227.13 85.07,227.13 85.5,226.69 85.5,225.68 v4(85.63,225.55)
  BOTTOM w0.203: v4(25.81,222.02) 25.81,221.35 26.95,220.21 PU4601.52
  BOTTOM w0.254: v2(25.86,224.51) 25.86,224.33 25.12,223.58 PR4606.1 24.73,223.52 PC4601.2 25.34,222.02 v4(25.81,222.02) ; v4(34.96,225.32) PC4605.2
VDDCR_NB_SENSE: length 21.1
  TOP w0.102: v3(78.89,175.8) 79.18,175.5 CPU1.J12 ; R1613.1 76.07,189.38 75.34,189.38 v4(73.82,187.86)
  L4 w0.127: v3(78.89,175.8) 79.42,176.33 79.42,180.29 77.95,181.76 77.62,181.76 76,183.38 76,185.67 v4(73.82,187.86)
  BOTTOM w0.102: v3(78.89,175.8) 78.87,175.8 78.4,176.27 v2(78.26,176.27) ; v4(73.82,187.86) v2(73.82,187.05)
VDDGFX_EN: length 12.2
  TOP w0.102: v4(83.41,211.25) 83.2,211.47 v4(83.2,215.19)
  BOTTOM w0.102: C1930.1 R1986.1 ; R1986.1 86.09,210.96 87.97,210.96 Q1240.D ; R1986.1 85.34,210.21 v2(84.72,210.21) 84.45,210.21 v4(83.41,211.25) ; PU5407.9 82.98,214.97 v4(83.2,215.19)
VDDGFX_EN_1: length 20.5
  BOTTOM w0.102: Q1240.G 88.07,208.17 83.33,208.17 81.72,206.55 74.94,206.55 v2(74.66,206.83) 74.66,207.47 73.65,208.47 R1987.1 72.93,207.96 Q1241.C
VDDGFX_EN_2: length 5.1
  BOTTOM w0.102: R1988.2 R1989.2 70.36,211.33 69.8,210.77 69.07,210.77 68.74,210.44 v2(68.74,209.93) 68.8,209.87 Q1241.B
VDDGFX_PD: length 1.5
  TOP w0.102: v3(76.03,163.27) 76.03,163.42 75.7,163.75 CPU1.AD8
  BOTTOM w0.102: TP214.1 76.56,163.8 v3(76.03,163.27)
VDDGFX_PWROK: length 4.3
  BOTTOM w0.102: PR5466.1 84.81,217.38 84.63,217.56 v2(84.63,217.64) 84.5,217.64 84.29,217.84 82.86,217.84 82.78,217.77 81.69,217.77 81.69,217.77 PU5407.2
VDDNB: length 269.4
  TOP w0.254: PT4703.1 39.02,169.54 39.78,170.31 PR4643.1
  TOP w0.356: v3(80.6,157.2) CPU1.AN13 v3(79.4,157.2) CPU1.AL12 ; v3(80.6,157.2) CPU1.AL15 v3(81.8,157.2) CPU1.AN16 v3(83,157.2) CPU1.AL18 v3(84.2,157.2) CPU1.AN19 v3(85.4,157.2) CPU1.AL21 86.6,157.2 v3(86.65,157.2) 87.2,156.65 CPU1.AN22 ; v3(80.6,157.2) CPU1.AL13
  TOP w0.508: 36.86,168.49 PT4703.1 ; PT4703.1 35.81,169.54 ; PT4703.1 36.86,170.6 ; 28.99,168.49 PT4704.1 ; PT4704.1 30.04,169.54 ; PT4704.1 28.99,170.6 ; PT4704.1 27.93,169.54 ; v4(148.37,205.61) 148.37,205.49 147.73,204.85 147.73,203.62 147.99,203.37 U178.3 147.99,201.49 148.31,201.17 R79724.2 ; PL4702.2 24.74,176.97 23.72,177.99 23.72,180.28 23.02,180.97 21.37,180.97 17.31,185.04 17.31,205.16 19.72,207.57 19.72,216.03 v4(17.56,218.19)
  L4 w0.508: v4(132.24,217.93) 132.24,216.3 140.22,208.32 142.35,206.2 144,204.54 147.3,204.54 v4(148.37,205.61) 148.37,205.91 150.96,208.5 153.01,208.5 v4(153.3,208.79) ; PT4704.1 28.99,170.6 ; PT4704.1 30.04,169.54 ; PT4704.1 27.93,169.54 ; PT4703.1 36.86,170.6 ; PT4703.1 35.81,169.54 ; PT4703.1 37.92,169.54
  BOTTOM w0.406: Q6703.2 153.76,210.95 153.58,210.76 153.58,210.5 153.76,210.31 154.51,210.31 Q6703.1 154.53,209.68 154.21,209.36 PC5427.1
  BOTTOM w0.508: 28.99,168.49 PT4704.1 ; PT4704.1 28.99,170.6 ; PT4704.1 27.93,169.54 ; PT4704.1 30.04,169.54 ; 35.81,169.54 PT4703.1 ; PT4703.1 36.86,168.49 ; PT4703.1 37.92,169.54 ; PT4703.1 36.86,170.6 ; PC5427.1 v4(153.3,208.79) ; v4(17.56,218.19) 17.18,218.57 12.23,218.57 11.44,219.35 11.44,224.65 13.92,227.13 124.23,227.13 132.24,219.12 v4(132.24,217.93)
  vias: v2(32.55,168.53) v2(32.93,174.12) v7(27.77,170.97) v7(30.51,172.85) v7(30.59,171.78) v7(30.56,170.74) v7(30.64,169.54) v7(31.53,172.85) v7(31.61,171.78) v7(31.58,170.74) v7(31.66,169.54) v7(32.55,172.85) v7(32.62,171.78) v7(32.6,170.74) v7(32.67,169.54) v7(33.56,172.85) v7(33.69,170.69) v7(33.76,171.78) v7(33.82,169.54) v7(34.58,172.85) v7(34.83,171.83) v7(34.83,170.69) v7(34.83,169.54) v7(38.82,173.61) v7(38.9,170.87)
VDDNB_TRACK_GATE: length 29
  TOP w0.102: v4(144.08,205.52) 143.16,204.6 143.16,201.1 R4708.2
  L3 w0.127: v4(144.08,205.52) 146.72,208.15 146.72,211.61 150.59,215.48 151.8,215.48 152.27,215.01 v4(152.43,215.01)
  BOTTOM w0.102: Q6703.4 157.71,211.84 157.45,212.09 154.72,212.09 154.53,211.9 Q6703.3 153.31,211.6 152.43,212.47 v2(152.43,214.12) v4(152.43,215.01)
VDDP_SENSE: length 73
  TOP w0.102: CPU1.AY18 v3(83.8,149.9) ; R1612.1 69.76,188.81 v1(69.79,188.77) 69.94,188.62 v4(70.77,188.62)
  L3 w0.127: v4(70.77,188.62) 73.06,186.33 85.23,186.33 86.27,185.29 86.27,182.05 90.52,177.79 90.52,174.79 91.13,174.19 91.13,171.44 91.08,171.39 91.08,169.49 88.98,167.39 78.19,167.39 77.73,166.92 77.73,158.28 79.54,156.47 81.39,156.47 82.88,154.99 82.88,154.13 83.27,153.73 83.59,153.73 83.84,153.49 83.84,149.94 v3(83.8,149.9)
VSS_SENSE: length 22.7
  TOP w0.267: R529.1 R528.1 ; R528.1 73.63,189.99 R80225.1 R1954.1 73.25,191.52 R1861.1 ; R528.1 v4(73.82,189.38) ; CPU1.H12 79.19,176.3 v3(78.89,176.6)
  L4 w0.267: v4(73.82,189.38) 73.6,189.16 73.6,189.16 72.9,188.46 72.9,187.27 72.98,187.19 74.12,186.05 74.12,185.76 75.27,184.6 75.27,183.37 77.99,180.65 77.99,177.49 v3(78.89,176.6)
  BOTTOM w0.267: v4(73.82,189.38) v2(73.82,190.2)
0D95V_S0: length 239.3
  TOP w0.356: CPU1.AE5 v3(73.7,162.2) CPU1.AE6
  TOP w0.508: v4(70.03,205.33) 68.49,203.79 v4(68.49,195.33) 68.49,193.17 62.64,187.32 62.64,179.47 59.09,175.91 R557.2 R558.1 ; v4(60.87,141.78) 60.87,140.77 57.89,137.79 56.19,137.79 55.98,137.58 53.29,137.58 C94.2 52.99,136.14 51.72,134.87 48.8,134.87 ; R586.1 64.87,147.19 64.24,147.19 63.99,146.94 v4(63.79,146.94)
  L3 w0.457: 77,160.05 77,158.12 79.69,155.42 80.65,155.42 81.87,154.19 81.87,154 83.42,152.45 v3(83.42,151.71) ; 77,160.05 77,162.48 76.64,162.84 76.64,164.85 77.34,165.54 77.34,167.27 77.85,167.78 87.95,167.78 88.71,168.53 89.19,168.53 90.08,169.42 90.08,171.25 89.32,172.01 89.32,173.04 89.66,173.38 90.44,173.38 90.74,173.68 90.74,174.02 90.13,174.63 90.13,175.6 86.42,179.31 86.42,179.83 85.53,180.72 77.54,180.72 73.83,184.43 73.27,184.43 69,188.7 69,192.17 70.26,193.42 71.49,193.42 71.92,193.84 71.92,196.1 71.54,196.47 69.63,196.47 v4(68.49,195.33) ; 77,160.05 75.64,161.4 75.17,161.4 74.37,162.2 v3(73.7,162.2)
  L4 w0.508: v4(63.79,146.94) 63.63,146.79 63.3,146.79 62.49,145.97 61.41,145.97 60.87,145.43 v4(60.87,141.78)
  BOTTOM w0.508: C1696.1 73.12,161.62 v3(73.7,162.2) ; 68.87,211.33 68.23,211.96 v2(68.23,213.16) 68.23,224.66 66.4,226.5 14.18,226.5 12.07,224.38 12.07,220.6 12.83,219.84 15.64,219.84 15.84,220.04 R527.2 ; 68.87,211.33 67.98,211.33 66.45,209.8 66.45,206.63 67.75,205.33 v4(70.03,205.33) ; 68.87,211.33 R1989.1
  vias: v1(47.28,136.65) v2(86.14,151.13) v2(106.21,147.65) v2(106.15,135.69) v3(84.82,151.84) v7(47,134.75) v7(47.15,135.66) v7(48.04,134.75) v7(48.06,135.66) v7(79.51,124.08) v7(80.25,123.32) v7(80.93,124.21) v7(81.06,122.56) v7(81.57,123.44) v7(81.82,121.79) v7(82.33,122.68) v7(97.62,136.19) v7(97.95,135.25) v7(98.59,136.14) v7(99.09,135.25)
0D95V_S0_EN: length 6.2
  TOP w0.102: 50.07,138.56 50.07,139.06 51.47,140.46 v1(52.22,140.46) 53.94,140.46 R174.2
0D95V_S5: length 121.9
  TOP w0.254: PG4801.2 42.07,151
  TOP w0.356: CPU1.AN12 v3(78.2,156) CPU1.AP12
  TOP w0.508: PT4801.1 48.17,152.31 ; PT4801.1 47.11,151.26 ; PT4801.1 49.22,151.26 ; PT4801.1 48.17,150.2 ; v4(20.35,162.53) 17.41,162.53 16.73,163.21 PR83.1 ; v3(63.03,160.66) 65.79,163.42 65.79,166.51 62.82,169.48 R559.2
  L3 w0.254: v3(69.6,157.15) 70.27,156.48 77.72,156.48 v3(78.2,156) 78.2,150.89 77.78,150.47 75.61,150.47 75.09,149.94 75.09,149.53 74.34,148.78 73.73,148.78 72.98,148.04 72.12,148.04 67.19,143.11 65.97,143.11 65.46,142.6 65.46,141.89 65.11,141.54 63.11,141.54 61.83,142.83 57.64,142.83 57.08,142.27 v7(42.35,142.27)
  BOTTOM w0.254: v3(69.6,157.15) 69.6,157.83 70.08,158.32 70.08,159.57 68.99,160.66 v3(63.03,160.66)
  BOTTOM w0.508: v7(41.03,156.97) 41.03,157 39.07,158.95 39.07,165.18 38.26,165.99 27.21,165.99 v2(25.88,164.66) 23.76,162.53 v4(20.35,162.53) ; C1703.1 78.01,155.81 v3(78.2,156)
0P95V_MAIN_APU_M: length 4.3
  BOTTOM w0.102: Q52.B 13.27,222.15 v2(13.11,222) 13.11,221.23 13.5,220.85 R527.1
1D5V_S3_PG_1: length 5.5
  TOP w0.102: D20.1 62.35,147.13 v4(62.59,147.37) 62.64,147.42 62.64,147.96 62.2,148.4 R1774.1
  BOTTOM w0.102: v4(62.59,147.37) 62.57,147.37 v2(60.99,145.8)
1D5V_S5: length 187.7
  TOP w0.508: R205.1 157.2,89.28 156.84,89.64 156.84,92.63 159.55,95.33 159.55,100.41 158.61,101.35 v4(157.89,101.35) ; R1601.2 v4(88.43,134.72)
  L3 w1.016: v7(51.21,125.73) 56.29,120.65 73.57,120.65 v7(74.07,121.16)
  L4 w1.016: v4(88.43,134.72) 85.19,131.48 77,131.48 74.07,128.56 v7(74.07,121.16) 74.07,118.62 76.11,116.59 127.67,116.59 v4(133.64,110.62)
  BOTTOM w0.508: v4(133.64,110.62) 137.32,106.93 153.32,106.93 157.89,102.36 v4(157.89,101.35)
  BOTTOM w1.016: v7(35.72,144.02) 38.67,141.07 41.61,141.07 45.63,137.06 45.63,134.24 46.77,133.1 49.44,133.1 51.21,131.32 v2(51.21,129.03) v7(51.21,125.73)
1D8V_S0: length 394.1
  TOP w0.356: CPU1.AP16 v3(83,156) CPU1.AP18
  TOP w0.406: 42.32,124.84 40.75,123.27 40.75,119 39.71,117.96 37.85,117.96 37.07,118.75 R2032.2
  TOP w0.508: R1698.1 R504.1 96.49,223.46 97.04,224 Q1210.S v4(97.57,222.76) ; R2028.1 73.19,141.2 v4(73.64,140.74) ; R2031.2 39.4,133.6 39.76,133.25 39.76,130.94 39.05,130.23 39.05,126.09 40.29,124.84 C315.1 ; v4(84.95,223.9) 92.33,223.9 93.22,224.79 v4(95.16,224.79) ; R1720.2 R495.1 v4(85,191.87) 84.39,191.87 83.62,192.63 82.56,192.63 81.95,192.02 R1610.2 ; v4(80.93,187.81) R1632.2 R1617.1 ; v4(86.06,195.94) 86.01,195.88 R1630.2 ; R2022.2 77.76,192.91 78.04,192.63 v4(78.9,192.63) 79.31,192.63 79.92,192.02 R1628.2 ; R2023.1 81.02,197.55 81.59,196.97 81.59,196.42 81.1,195.94 v4(80.93,195.94) R2002.2 R1998.2 ; R2000.2 v4(85,187.81) ; v4(81.69,225.22) 80.09,226.82 31.17,226.82 30.54,226.19 30.54,225 30.04,224.5 30.04,223.3 29.75,223.01 29.75,222.08 v4(29.99,221.85)
  L3 w0.457: v4(85,187.81) 86.81,185.99 86.81,182.06 89.56,179.32 89.75,179.32 90.92,178.15 90.92,174.96 91.72,174.16 91.72,173.7 92.08,173.33 92.08,158.16 90.44,156.51 87.67,156.51 87.61,156.58 83.58,156.58 v3(83,156)
  L3 w0.508: v4(80.93,195.94) 81.1,195.94 83.37,198.2 83.37,208.77 82.54,209.6 82.54,215.52 v4(83.12,216.1) 82.54,216.68 82.54,217.3 84.95,219.71 v4(84.95,223.9) ; v4(85,187.81) 84.34,187.15 81.59,187.15 v4(80.93,187.81) ; v4(85,191.87) 85.17,191.87 86.06,192.77 v4(86.06,195.94)
  L3 w0.762: v3(83,156) 83,155.67 83.73,154.94 85,154.94 86.1,153.85 86.1,152.82 87.82,151.1 87.82,143.49 88.6,142.7 88.6,142.7 88.73,142.57 88.73,140.03 v4(90.46,138.3)
  L3 w1.016: v7(43.62,126.72) 47.56,126.72 54.77,119.51 75.6,119.51 v7(75.73,119.63)
  L4 w0.508: v4(84.95,223.9) 83.01,223.9 v4(81.69,225.22) ; v4(73.64,140.74) 73.69,140.79 74.58,140.79 75.84,139.54 77.47,139.54 81.05,135.95 86.76,135.95 89.11,138.3 v4(90.46,138.3) ; v4(85,191.87) v4(85,187.81) ; v4(80.93,187.81) 81.59,188.47 81.59,195.28 v4(80.93,195.94) 80.93,194.49 79.07,192.63 v4(78.9,192.63)
  L4 w1.016: v4(90.46,138.3) 90.46,135.14 85.66,130.34 78.68,130.34 75.98,127.64 75.98,119.89 v7(75.73,119.63)
  BOTTOM w0.203: v4(83.12,216.1) 83.05,216.17 PU5407.6 ; v4(29.99,221.85) PU4601.6
  BOTTOM w0.508: v4(95.16,224.79) 95.64,224.79 v2(96.6,223.82) 97.57,222.86 v4(97.57,222.76) ; C1674.1 83.35,155.66 v3(83,156)
  BOTTOM w1.016: v7(75.73,119.63) 78.27,117.09 111.16,117.09 123.22,105.03 123.22,101.6 122.46,100.84 R90072.1
1D8V_S5: length 470.9
  TOP w0.254: v7(106.64,77.57) 106.66,77.55 PG5212.1 PC5211.1 ; PC5213.1 100.3,76.58 PG5211.1 v7(99.65,77.6)
  TOP w0.356: CPU1.AR9 77,154.8 CPU1.AP10 v3(77,156)
  TOP w0.508: 43.82,133.5 42.63,134.7 42.63,136.99 46.61,140.97 50.3,140.97 52.2,142.88 v4(52.74,142.88) 52.71,142.9 52.71,144.17 51.34,145.54 51.34,157.29 R1677.1 ; PC52.1 159.88,203.91 v4(158.02,202.06) ; v4(84.74,134.27) 84.9,134.11 86.65,134.11 87.16,134.62 R1595.1 ; v4(151.93,203.71) 151.93,203.07 151.48,202.63 PR5473.1
  TOP w1.016: PR5290.1 21.55,149.68 v7(21.5,149.73) ; v7(117.38,102.23) 117.38,99.82 117.89,99.31 117.89,90.17 v7(112.43,84.71)
  L3 w0.508: v4(52.74,142.88) 55.64,142.88 56.42,143.66 57.2,143.66 57.38,143.48 62.79,143.48 63.53,144.23 63.53,145.08 63.94,145.49 64.16,145.49 64.55,145.88 64.55,146.1 67.95,149.5 v3(70.75,149.5)
  L3 w2.032: 42.02,130.86 42.02,127.46 41.97,127.41 41.97,125.7 45.7,121.98 45.7,89.08 50.07,84.71 106.84,84.71
  L4 w0.508: v4(136.56,108.84) 135.03,107.32 135.03,100.58 133.17,98.72 133.17,80.23 134.63,78.77 134.63,77.29 v3(133.66,76.33) ; v4(159.14,103.99) 159.16,104.01 160.43,104.01 161.74,105.32 164.01,105.32 164.5,105.81 164.5,110.26 166.17,111.94 166.17,114.43 166.17,136.25 165.44,136.98 165.44,194.76 162.43,197.76 161.31,197.76 158.02,201.05 v4(158.02,202.06) ; v3(70.75,149.5) 70.65,149.4 70.65,145.11 69.68,144.15 v4(69.68,141.91)
  BOTTOM w0.508: v4(69.68,141.91) 70.14,141.45 71.92,141.45 74.05,139.32 76.29,139.32 76.45,139.48 77.32,139.48 80.26,136.54 80.73,136.54 82.63,134.64 82.63,134.27 83.2,133.71 84.17,133.71 v4(84.74,134.27) ; v4(159.14,103.99) 155.56,107.57 137.83,107.57 v4(136.56,108.84) ; v4(151.93,203.71) v2(152.81,203.71) 153,203.71 153.64,203.07 PU5.1 154.96,202.45 155.35,202.06 v4(158.02,202.06) ; v3(70.75,149.5) 70.96,149.29 74.45,149.29 74.98,149.81 74.98,150.01 75.84,150.88 76.43,150.88 76.88,151.33 C1957.1 76.88,152.51 C1677.1 76.74,153.52 77.06,153.84 C1828.1 77.06,155.94 v3(77,156) ; v7(106.64,77.57) 107.88,76.33 v3(133.66,76.33)
  BOTTOM w1.016: v7(42.55,133.04) 42.55,136.91 42.83,137.19 42.83,138.24 41.27,139.8 37.9,139.8 33.94,143.76 27.47,143.76 v7(21.5,149.73)
  vias: v7(41.05,132.18) v7(100.74,75.31) v7(100.74,74.3) v7(105.82,75.31) v7(105.82,74.17) v7(109.38,84.71) v7(111.03,84.71)
1D35V_S3: length 284.9
  TOP w0.25: CPU1.AB33 96.4,165 96.4,165 v3(96.45,165) ; CPU1.V30 94.11,168.2 v3(94.13,168.22) ; CPU1.AK30 94.06,158.6 v3(94.09,158.62) ; CPU1.V33 95.56,168.26 96.34,168.26 v3(96.43,168.35) ; CPU1.AK33 96.42,158.6 v3(96.45,158.57) ; CPU1.Y30 93.92,166.6 94.02,166.5 v3(94.08,166.5) ; CPU1.AF33 96.37,161.8 v3(96.42,161.85) ; v3(93.12,165.4) 93.12,165.38 CPU1.AB30 ; CPU1.AM30 v3(94.14,157) ; CPU1.AD30 v3(94.1,163.4) ; v3(94.1,160.2) CPU1.AH30
  TOP w0.254: PG5001.1 134.15,109.73 135.03,110.62
  TOP w0.33: v4(152.3,159.64) 152.3,159.66 152.31,159.66 152.31,159.87 152.69,160.25 DIMM2.94 ; v4(147.99,161.29) 147.99,161.55 147.18,162.35 DIMM2.87 ; v4(147.99,163.19) 147.99,163.35 147.18,164.15 DIMM2.81 ; v4(137.83,157.73) 137.83,157.99 138.29,158.45 DIMM1.100 ; v4(147.99,155.96) 147.99,156.21 147.25,156.95 DIMM2.105 ; 152.96,165.67 153.31,165.67 153.33,165.65 DIMM2.76 ; 152.96,165.67 152.83,165.67 152.5,165.34 152.5,165.29 v4(152.31,165.1) ; 152.96,165.67 152.5,166.13 152.5,166.18 v4(152.31,167) ; DIMM1.94 138.62,160.25 137.96,159.59 137.96,159.51 v4(137.83,159.38) ; v4(147.99,165.1) 147.99,165.23 147.26,165.95 DIMM2.75 ; DIMM1.106 138.52,156.65 138.52,156.65 v4(137.83,155.83) ; v4(152.31,155.96) 152.5,156.15 152.5,156.19 152.95,156.65 DIMM2.106 ; DIMM1.124 138.47,151.25 v4(135.8,153.92) ; DIMM1.75 133.04,165.95 134.02,164.97 v4(134.02,164.85) ; 147.29,153.35 v4(147.99,154.05) 147.99,154.51 147.34,155.15 DIMM2.111 ; 147.29,153.35 147.34,153.35 147.99,152.71 v4(147.99,152.15) 147.39,151.55 DIMM2.123 ; 147.29,153.35 DIMM2.117 ; DIMM1.82 138.48,163.85 137.83,163.19 v4(137.7,163.19) ; DIMM1.81 132.94,164.15 134.02,163.07 v4(134.02,162.94) ; DIMM2.88 153.02,162.05 152.5,161.53 152.5,161.48 v4(152.31,161.29) ; DIMM1.117 130.15,153.35 129.83,153.67 129.83,154.81 130.16,155.15 DIMM1.111 132.33,155.15 133.51,153.97 v4(133.51,153.92) ; v4(137.83,161.16) 137.83,161.29 138.59,162.05 DIMM1.88 ; v4(134.02,161.42) 134.02,161.46 133.4,162.08 132.34,162.08 132.07,162.35 DIMM1.87 ; v4(135.03,149.48) 135.03,149.53 133.01,151.55 DIMM1.123 ; DIMM2.93 147.18,160.55 147.99,159.75 v4(147.99,159.38) ; DIMM1.118 138.62,153.05 137.83,153.84 v4(137.83,153.92) 137.83,154.18 138.5,154.85 DIMM1.112 ; v4(152.31,154.05) 152.5,154.24 152.5,154.29 153.06,154.85 DIMM2.112 ; DIMM2.118 153.04,153.05 152.5,152.51 152.5,152.46 v4(152.31,152.27) 152.5,151.96 152.5,151.91 153.16,151.25 DIMM2.124 ; v4(135.54,157.73) 135.35,157.54 135.35,157.5 134.98,157.13 133.66,157.13 132.03,158.75 DIMM1.99 ; v4(137.55,165.1) 137.7,165.1 138.25,165.65 DIMM1.76 ; DIMM1.105 132.94,156.95 134.02,155.88 v4(134.02,155.83) ; DIMM2.99 147.23,158.75 v4(147.99,157.99) ; DIMM2.100 153.02,158.45 v4(152.56,157.99) ; DIMM1.93 132.65,160.55 134.02,159.18 v4(134.02,159.13) ; v4(152.31,163.19) 152.5,163.39 152.5,163.43 152.91,163.85 DIMM2.82
  TOP w0.356: CPU1.AH24 v3(88.95,160.75) 89.5,161.3 CPU1.AG25 ; v3(88.93,158.5) 89,158.5 CPU1.AK25 ; CPU1.AE27 91.1,162.8 v3(91.5,163.2) 91.9,163.6 CPU1.AD28 ; CPU1.AL27 91.1,158 v3(91.5,158.4) 91.9,158.8 CPU1.AK28 ; CPU1.AD25 89.5,163.7 v3(88.95,163.15) CPU1.AE24 ; CPU1.T27 91.1,170 v3(91.5,170.4) 91.9,170.8 CPU1.P28 ; CPU1.W27 91.1,167.6 v3(91.5,168) 91.9,168.4 CPU1.U28 ; CPU1.Y25 89.5,166.1 v3(88.95,165.55) CPU1.AB24 ; CPU1.AF30 93.25,161.8 v4(93,162.05) ; CPU1.AG28 91.9,161.2 v3(91.5,160.8) 91.1,160.4 CPU1.AH27 ; CPU1.W24 v3(88.95,167.95) 89.5,168.5 CPU1.U25 ; CPU1.T24 v4(88.95,170.35) 89.5,170.9 CPU1.P25 ; CPU1.Y28 91.9,166.03 v3(91.47,165.61) 91.1,165.24 CPU1.AB27
  TOP w0.508: 135.76,110.62 PT5007.1 ; PT5007.1 136.81,109.56 ; PT5007.1 137.87,110.62 ; PT5007.1 136.81,111.67 ; 135.03,110.62 135.42,110.62
  TOP w1.016: PR5021.1 PR5020.1 141.46,84.91 141.89,85.34 v7(142.78,85.34)
  L3 w0.508: v4(142.91,193.29) 145.96,190.25 153.11,190.25 156.75,186.61 156.75,176.91 155.86,176.02 155.86,171.83 152.31,168.28 v4(152.31,167)
  L3 w1.016: v4(134.15,100.97) 131.22,98.04 131.22,86.87 132.9,85.19 141.74,85.19 141.89,85.34 v7(142.78,85.34)
  L4 w1.016: PT5007.1 136.81,110.49 133.21,106.88 133.21,101.9 v4(134.15,100.97)
  BOTTOM w0.508: C46.1 132.11,159.38 132.62,159.89 133.51,159.89 134.02,159.38 v4(134.02,159.13) ; C1694.1 89.42,170.81 v4(88.95,170.35) 89.37,169.93 C356.1 ; v4(137.83,161.16) 137.64,160.97 C1872.1 ; C1874.1 137.64,163.13 v4(137.7,163.19) ; C1966.1 153.96,159.38 v4(152.56,157.99) 153.58,156.97 C1964.1 ; C1974.1 148.18,159.58 v4(147.99,159.38) ; C1873.1 137.64,156.02 v4(137.83,155.83) 137.64,155.64 C1871.1 ; v4(133.51,153.92) 133.51,153.54 133,153.03 C1725.1 ; v4(134.02,162.94) 134.02,162.69 133.51,162.18 C392.1 ; v3(88.95,163.15) 89.29,162.81 C1691.1 ; R1586.1 107.39,155.93 v2(105.98,155.93) 105.93,155.88 105.01,155.88 102.52,158.37 ; v4(147.99,163.19) 148.18,163.39 C1968.1 ; v4(147.99,165.1) 148.18,165.29 C1967.1 ; C1876.1 137.64,165.19 v4(137.55,165.1) 137.64,165.01 C1875.1 ; v4(152.31,161.29) 152.31,161.54 152.94,162.18 C1963.1 ; v3(88.95,160.75) 89.17,160.53 C1692.1 ; v4(152.31,165.1) 152.31,165.48 152.81,165.99 C1961.1 ; C1965.1 152.69,154.94 152.31,154.56 v4(152.31,154.05) 152.31,153.8 153.07,153.03 C1972.1 ; R1633.1 142.4,192.79 v4(142.91,193.29) 143.42,192.79 R2057.1 ; C1970.1 148.18,156.15 v4(147.99,155.96) ; C1969.1 148.18,161.48 v4(147.99,161.29) ; C1962.1 152.81,164.08 152.31,163.58 v4(152.31,163.19) ; C1723.1 133.38,154.94 134.02,155.57 v4(134.02,155.83) 134.02,156.21 133.73,156.5 132.97,156.5 132.49,156.97 C60.1 ; C337.1 133.26,165.99 134.02,165.23 v4(134.02,164.85) 134.02,164.59 133.51,164.08 C353.1 ; v4(152.31,152.27) 152.31,152.53 151.48,153.35 R2059.1 ; v3(88.93,158.5) 89.19,158.24 C1693.1 ; v3(88.95,167.95) 89.26,167.64 C1689.1 ; v3(88.95,165.55) 89.27,165.23 C1690.1 ; R120.1 146.91,153.35 C1973.1 147.23,153.29 v4(147.99,154.05) 148.18,154.24 C1978.1 ; v4(137.83,153.92) 138.59,153.16 C55.1
  vias: v3(97.29,163.73) v3(97.34,156.87) v3(97.38,160) v3(97.7,168.15) v3(98.08,172.72) v3(98.08,165.23) v3(98.33,161.8) v3(98.37,171.07) v3(98.71,159.51) v3(98.84,158.37) v3(98.98,165.73) v3(98.97,160.78) v3(99.22,169.42) v3(99.22,163.7) v3(100.11,171.45) v3(100.21,161.72) v3(100.33,159.36) v3(100.62,157.1) v3(100.71,168.82) v3(100.92,163.12) v3(101.12,165.34) v3(102.47,166.59) v3(102.67,169.28) v3(102.9,163.07) v3(105.57,163.07) v4(141.64,165.1) v4(141.77,163.19) v4(141.77,161.29) v4(141.77,159.38) v4(141.77,155.96) v4(141.77,154.05) v4(141.77,152.15) v4(143.92,167) v4(143.92,165.1) v4(144.05,163.19) v4(144.05,161.29) v4(144.05,159.38) v4(144.05,155.96) v4(144.05,154.05) v4(144.05,152.15) v4(144.81,159.38) v7(141.51,121.18) v7(142.53,121.18) v7(143.54,121.18) v7(144.56,121.18) v7(145.58,121.18) v7(146.59,121.18) v7(158.02,166.6) v7(158.02,165.33) v7(158.02,164.06) v7(158.02,162.79) v7(158.02,161.52) v7(158.02,160.25) v7(158.02,158.98) v7(158.02,157.71)
1P5_5930_EN: length 5.8
  TOP w0.102: PU5206.8 22.56,141.99 22,141.43 v1(22,140.34) PC5245.1 R31.1 R1930.2
1P5_5930_FB: length 5.2
  TOP w0.254: PR5292.2 31.16,141.67 v1(31.3,141.81) 31.3,142.79 PC5244.2 PR5293.1 29.81,143.26 PU5206.2
1P5_5930_PG: length 3.6
  TOP w0.102: PR5295.2 20.86,144.65 21.39,144.12 v1(21.39,144.02) 22.16,143.26 PU5206.7
1P5_5930_VCNTL: length 6.8
  TOP w0.254: PU5206.6 22.13,144.53 20.68,145.97 PR5294.2 20.86,146.35 v1(20.86,148.21) 20.1,148.21 PC5243.1
1P5V_LPS_APU: length 328.6
  TOP w0.254: v1(164.24,114.05) 162.99,115.3 162.89,115.3 161.15,117.04 161.15,117.75 161.25,117.85 161.25,119.3 v4(161.83,119.89)
  TOP w0.356: CPU1.AR17 83.1,154.5 v3(83.45,154.15)
  TOP w0.381: v1(164.24,114.05) 164.24,111 163.65,110.4 161.16,110.4 160.75,110.81 R1721.1 160.69,111.06 C1736.1 158.08,111.06 156.88,112.27 156.88,113.16
  L3 w0.254: v3(83.45,154.15) 83.57,154.03 83.72,154.03 84.28,153.46 84.28,150.35 86.77,147.85 86.77,141.94 88.08,140.63 88.08,139.78 94.08,133.78 121.32,133.78 135.42,119.68 161.63,119.68 v4(161.83,119.89)
  L3 w0.508: v4(168.44,122.81) 166.78,121.16 164.5,121.16 163.23,119.89 v4(161.83,119.89)
  L4 w0.508: v4(94.52,12.19) 94.52,10.03 93.76,9.27 93.76,4.5 95.37,2.9 149.12,2.9 151.81,5.58 151.81,16.45 154.41,19.05 155.73,19.05 163.53,26.85 163.53,28.28 163.82,28.56 164.68,28.56 165.07,28.95 165.07,29.5 163.79,30.78 163.79,38.81 165.64,40.67 165.64,59.41 163.51,61.54 163.51,63.77 163.51,66.36 164.24,67.09 164.24,69.97 166,71.72 166,78.14 165.87,78.26 165.87,79.6 170.11,83.84 170.11,91.63 168.77,92.98 168.77,108.58 169.81,109.62 169.81,121.44 v4(168.44,122.81)
  BOTTOM w0.508: v4(94.52,12.19) v2(94.52,13.21) 94.52,13.53 R1185.2 ; v3(83.45,154.15) 84.04,154.15 C1741.1
1P5V_S3_PG: length 157.6
  TOP w0.102: PR5005.2 147.01,73.06 v1(147.12,73.18) 147.12,73.63 146.9,73.86 v4(146.26,73.86) 146.26,74.04 145.08,75.23 145.08,75.28 144.75,75.61 144.71,75.61 144.68,75.64 143.85,75.64 142.82,76.67 PU5001.10 ; v4(60.23,146.38) 61.7,146.38 62.1,146.77 62.64,146.77 63.05,147.18 63.05,147.81 63.25,148.01 63.25,148.73 R1774.2
  L3 w0.127: v4(146.26,73.86) 148.29,73.86 150.29,75.86 150.29,95.7 149.38,96.61 149.38,100.79 148.79,101.37 148.79,104.9 145.73,107.97 133.03,107.97 119.17,121.83 88.67,121.83 82.52,127.98 80.89,127.98 76.33,132.54 76.19,132.69 74.78,134.09 74.78,135.9 71.75,138.93 68.55,138.93 68.16,139.33 66.64,139.33 65.79,138.48 62.9,138.48 v4(62.64,138.74)
  L4 w0.127: v4(60.23,146.38) 60.23,141.15 v4(62.64,138.74)
1P8V_PWR_PG: length 196.3
  TOP w0.102: PU5201.4 110.69,64.12 PR5206.2 v4(110.97,65.2) ; v4(26.05,141.17) 25.19,141.17 R1930.1
  L3 w0.127: v4(110.97,65.2) 110.97,64.91 110.02,63.96 108.39,63.96 107.49,63.06 105.51,63.06 99.91,63.06 99.35,63.62 99.35,65.91 v4(98.59,66.67) ; v4(37.09,82.97) 37.09,82.96 36.68,82.55 36.68,78.01 36.74,77.95 36.74,76.91 43.47,70.18 61.3,70.18 63.65,72.53 86.05,72.53 86.98,71.6 88.22,70.36 v4(95.66,70.36)
  L4 w0.127: v4(95.66,70.36) 96.46,70.36 98.59,68.23 v4(98.59,66.67) ; v4(37.09,82.97) 37.09,82.97 37.09,83.77 39.37,86.05 39.37,101.23 38.16,102.44 38.16,104.39 38.78,105.01 38.78,106.16 38.65,106.29 38.65,115.14 37.26,116.54 37.26,120.86 36.99,121.13 36.99,134.4 36.99,135.09 31.78,140.3 27.52,140.3 26.64,141.17 v4(26.05,141.17) 25.72,141.5 25.72,147.07 22.9,149.89 22.9,151.32 20.31,153.9 20.31,158.56 19.55,159.32 19.55,161.24 v4(20.02,161.71)
  BOTTOM w0.102: v4(20.02,161.71) 18.95,162.78 17.16,162.78 16.42,162.05 16.42,160.92 v2(16.42,160.91) 16.42,160.08 R1763.1
3D3V_AUX_EC: length 55.9
  TOP w0.508: v4(101.38,53.85) 102.78,55.24 v4(102.78,55.37) ; v4(101.38,53.85) 101.51,53.72 103.67,53.72 R79707.2 104.05,54.1 v4(105.06,54.1) 105.76,54.1 L4101.1 ; v4(101.38,53.85) 101.38,53.31 100.39,52.32 98.69,52.32 97.87,51.51 94.11,51.51 v4(93.58,52.04)
  BOTTOM w0.203: v4(105.06,54.1) 105.64,54.68 U4101.56 ; U4101.22 99.74,53.48 100.11,53.85 v4(101.38,53.85) 102.27,53.85 102.67,53.44 102.67,52.35 102.37,52.04 102.18,52.04 101.27,51.13 U4101.11 ; R79706.1 101.27,60.53 U4101.38 101.27,57.94 100.96,57.63 100.96,56.41 101.35,56.02 101.75,56.02 102.4,55.37 v4(102.78,55.37) 102.78,55.75 102.52,56.01 102.52,56.77 103.67,57.91 U4101.44
  BOTTOM w0.254: v2(99.86,61.21) 100.49,60.58 R79706.1
  BOTTOM w0.508: v4(93.58,52.04) 93.54,52.01 R80230.2 91,52.01 90.51,51.51 89.24,51.51 Q9649.D ; PR8519.1 PR8520.1 94.71,62.04 96.68,64.01 97.77,64.01 99.86,61.92 v2(99.86,61.21)
3D3V_RUN_FFS: length 21.8
  TOP w0.305: v4(82.76,68.83) 82.32,68.39 C6701.1 81.73,68.39 80.72,69.4 U6701.14 ; R6701.2 75.95,68.45 76.46,68.45 77.41,69.4 U6701.8 ; C6703.1 76.13,69.9 U6701.7 ; C6702.1 81.83,71.12 U6701.1
  TOP w0.508: v4(82.76,68.83) 83.27,69.34 v1(83.27,70.46) 82.57,71.16 82.57,71.21 C6702.1 ; C6703.1 R6701.2 76.39,67.82 v4(76.81,67.82)
  L3 w0.508: v4(76.81,67.82) 76.84,67.82 77.55,68.53 82.46,68.53 v4(82.76,68.83)
1117_ADJ: length 7.1
  TOP w0.102: R1592.1 131.22,44.7 v1(131.1,44.83) 130.59,44.83 129.83,44.07 129.34,44.07 R2081.2 129.04,44.58 v4(129.7,45.24)
  BOTTOM w0.102: U119.1 129.7,45.24 v4(129.7,45.24)
A20GATE: length 181.9
  TOP w0.102: v4(161.58,94.23) 161.2,94.23 160.82,94.61 159.8,94.61 157.53,92.34 157.53,90.03 158.78,88.77 R350.1 ; R80231.2 155.2,64.6 155.2,70.88 154.71,71.37 154.71,79.09 153.66,80.13 153.66,84.56 154.71,85.6 154.71,89.32 154.37,89.66 154.37,91.87 155.01,92.52 155.01,94.35 155.91,95.25 v4(155.96,95.25) ; v3(85.55,146.69) 85.15,147.09 85.15,147.5 84.6,148.05 CPU1.BC19
  L3 w0.127: v4(167.67,120.93) 167.01,120.27 166.02,120.27 162.76,117.01 161.41,117.01 159.56,118.86 135.08,118.86 120.98,132.96 93.42,132.96 87.26,139.12 87.26,140.29 85.95,141.6 85.95,144.46 86.23,144.74 86.23,146.47 86.01,146.69 v3(85.55,146.69)
  L4 w0.127: v4(161.58,94.23) 162.03,94.69 162.03,98.08 162.85,98.89 162.85,99.42 163.49,100.06 163.49,100.33 163.79,100.63 163.79,100.64 163.94,100.79 163.94,101.63 164.57,102.26 164.57,103.84 167.15,106.42 167.15,110.45 167.96,111.25 167.96,119.86 167.67,120.14 v4(167.67,120.93)
  BOTTOM w0.102: v4(161.58,94.23) 161.58,94.77 v2(160.82,95.53) 160.03,96.32 157.03,96.32 v4(155.96,95.25)
AC_IN: length 48.3
  TOP w0.102: v4(47.15,39.52) 47.56,39.12 48.29,39.12 48.55,38.86 PQ5005.2 ; PQ5004.D 67.55,64.17 PR5281.2 69.36,64.19 v4(70.21,64.19)
  BOTTOM w0.102: v4(70.21,64.19) 70.62,63.78 70.62,53.82 64.17,47.37 55.53,47.37 v2(54.54,46.38) 53.86,45.69 53.86,42.01 52.61,40.77 49.54,40.77 48.29,39.52 v4(47.15,39.52)
AC_IN_KBC#: length 2.6
  BOTTOM w0.102: U4101.29 95.77,56.28 TP4124.1
AC_OK#: length 124.4
  TOP w0.102: v4(146.34,39.75) 147.16,40.58 R80209.1 ; PQ5004.G 65.25,62.42 65.25,61.75 v4(65.28,61.72) 65.91,61.09 v1(65.95,61.09)
  L3 w0.127: v4(65.28,61.72) 65.28,61.39 66.31,60.35 68.02,60.35 68.68,59.7 68.68,58.99 69.5,58.17 72.59,58.17 80.44,50.32 86.53,50.32 90.14,46.71 95.68,46.71 96.7,45.69 100.04,45.69 102.36,43.37 109.27,43.37 v4(109.89,42.75) 110.1,42.53 124.71,42.53 126.47,40.78 127.31,40.78 135.91,40.78 136.56,40.13 137.35,40.13 138.57,41.35 142.3,41.35 144.03,39.62 146.21,39.62 v4(146.34,39.75)
  L4 w0.127: v4(101.76,55.24) 102.27,54.74 105.2,54.74 110.27,49.67 110.27,44.07 109.89,43.69 v4(109.89,42.75)
  BOTTOM w0.102: v4(101.76,55.24) 101.27,55.74 101.24,55.74 100.68,56.29 100.68,57.82 100.87,58.01 U4101.37 ; U55.5 61.74,58.66 61.88,58.8 64.17,58.8 64.42,59.05 64.42,60.15 65.11,60.83 PR4427.2 65.5,61.5 v4(65.28,61.72)
AC_OK#_ECIO: length 4.6
  TOP w0.102: U109.99 145.25,43.75 146.46,42.55 v1(147.23,42.55) R80209.2
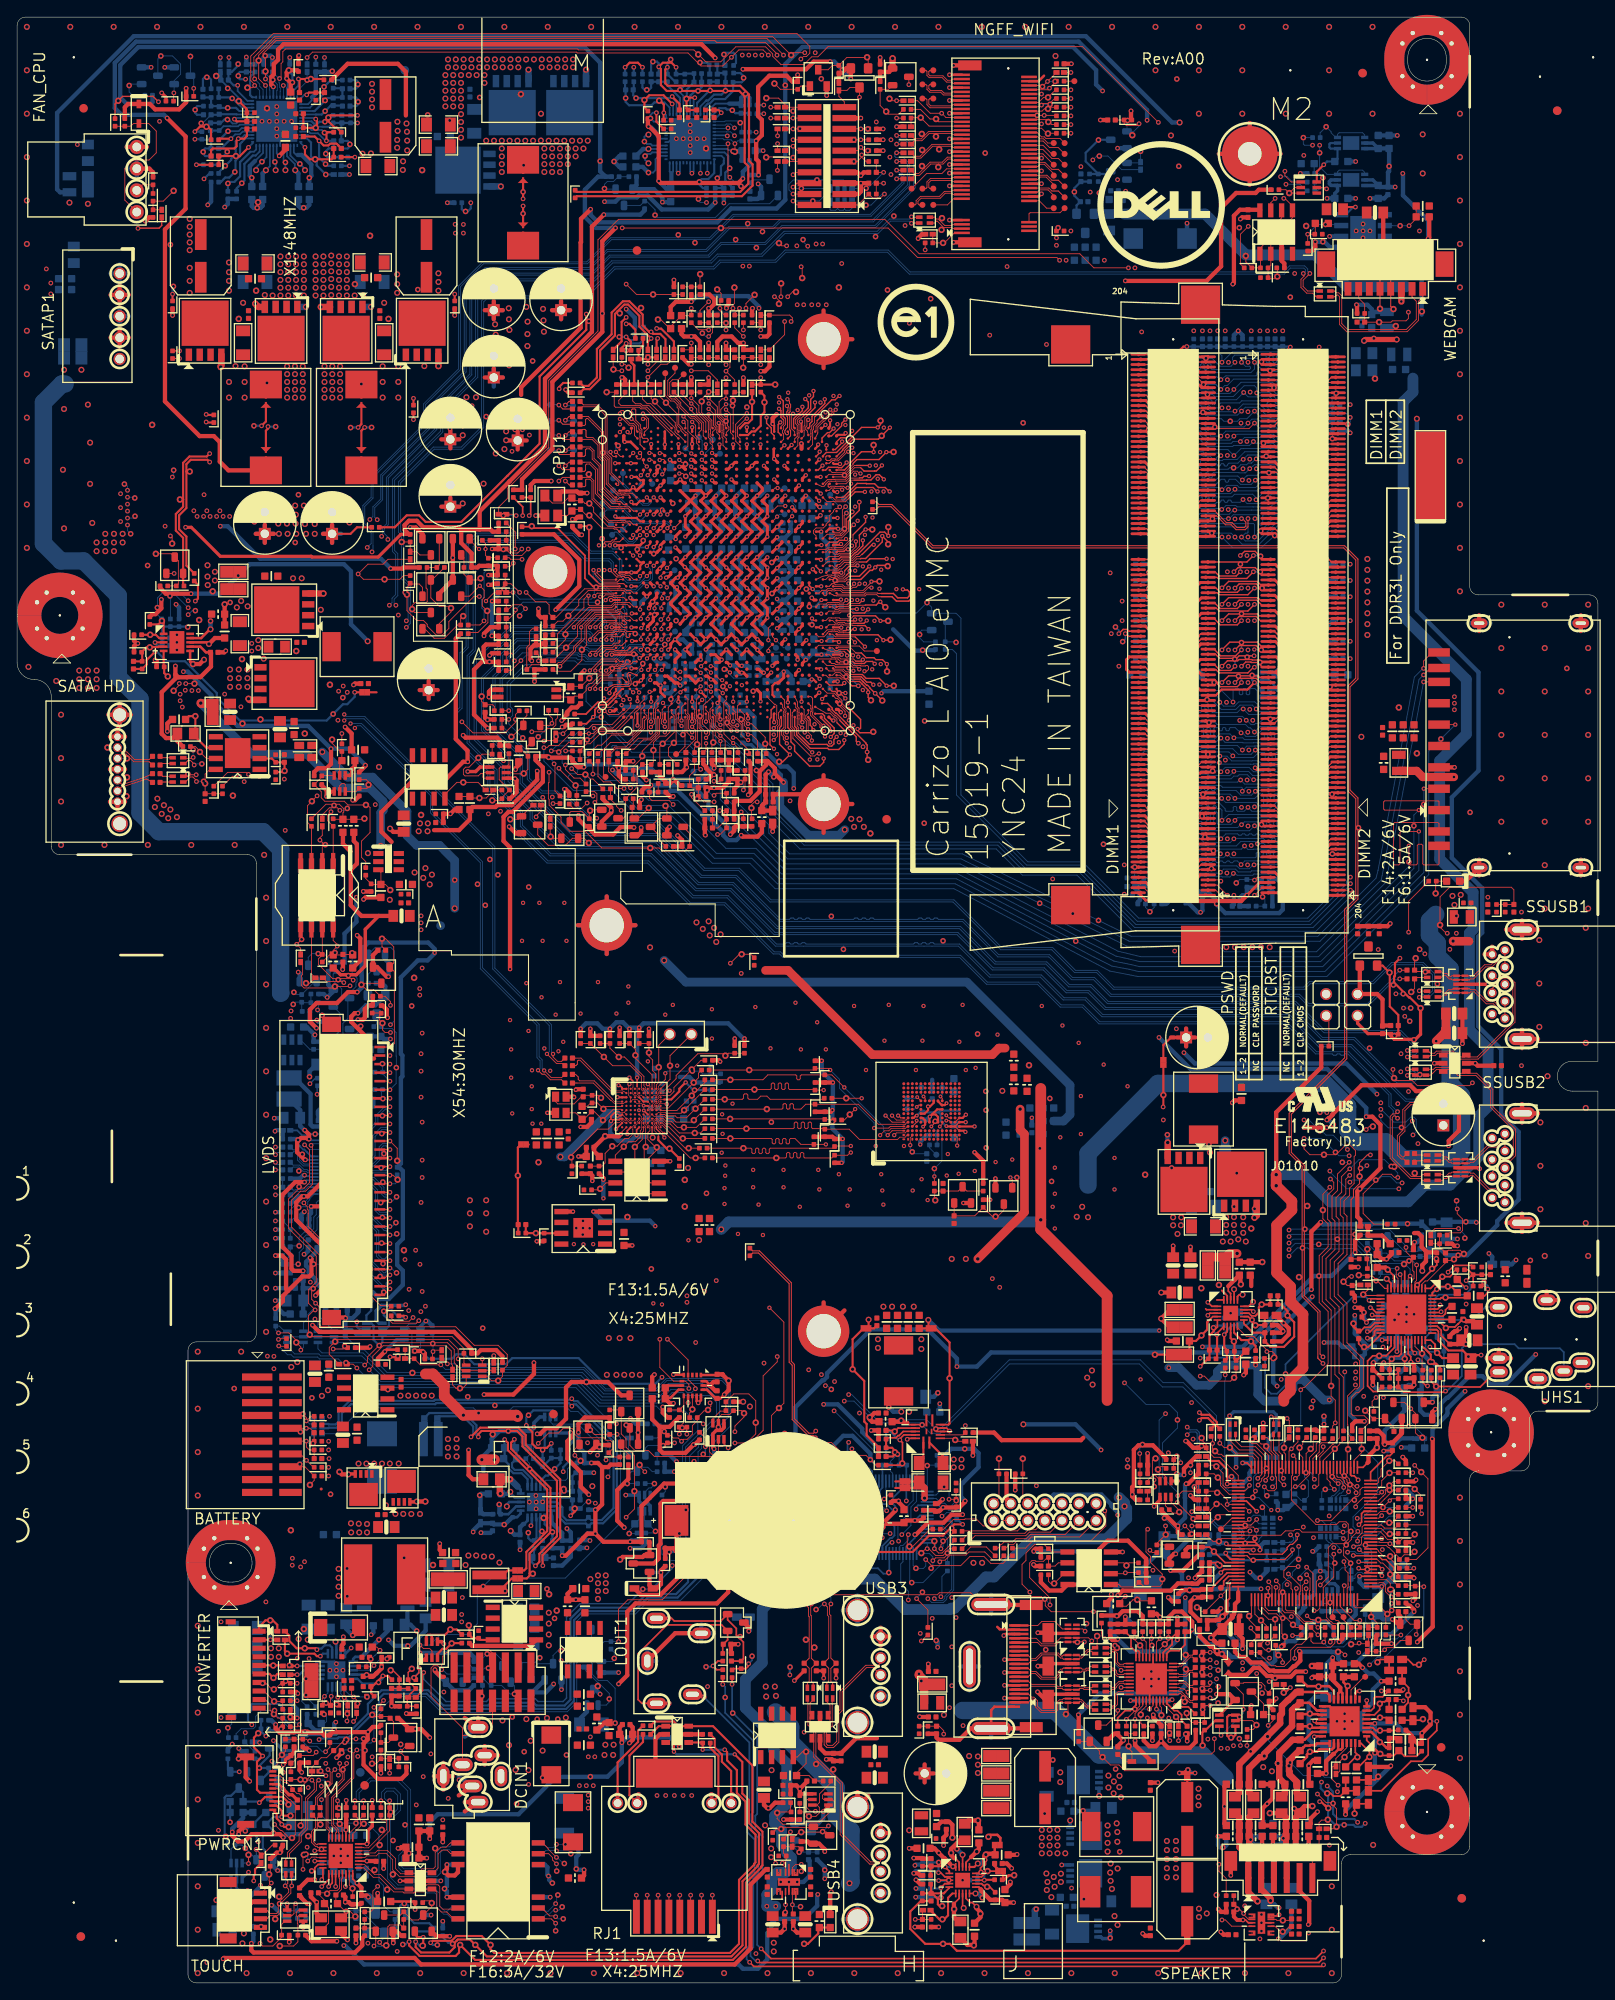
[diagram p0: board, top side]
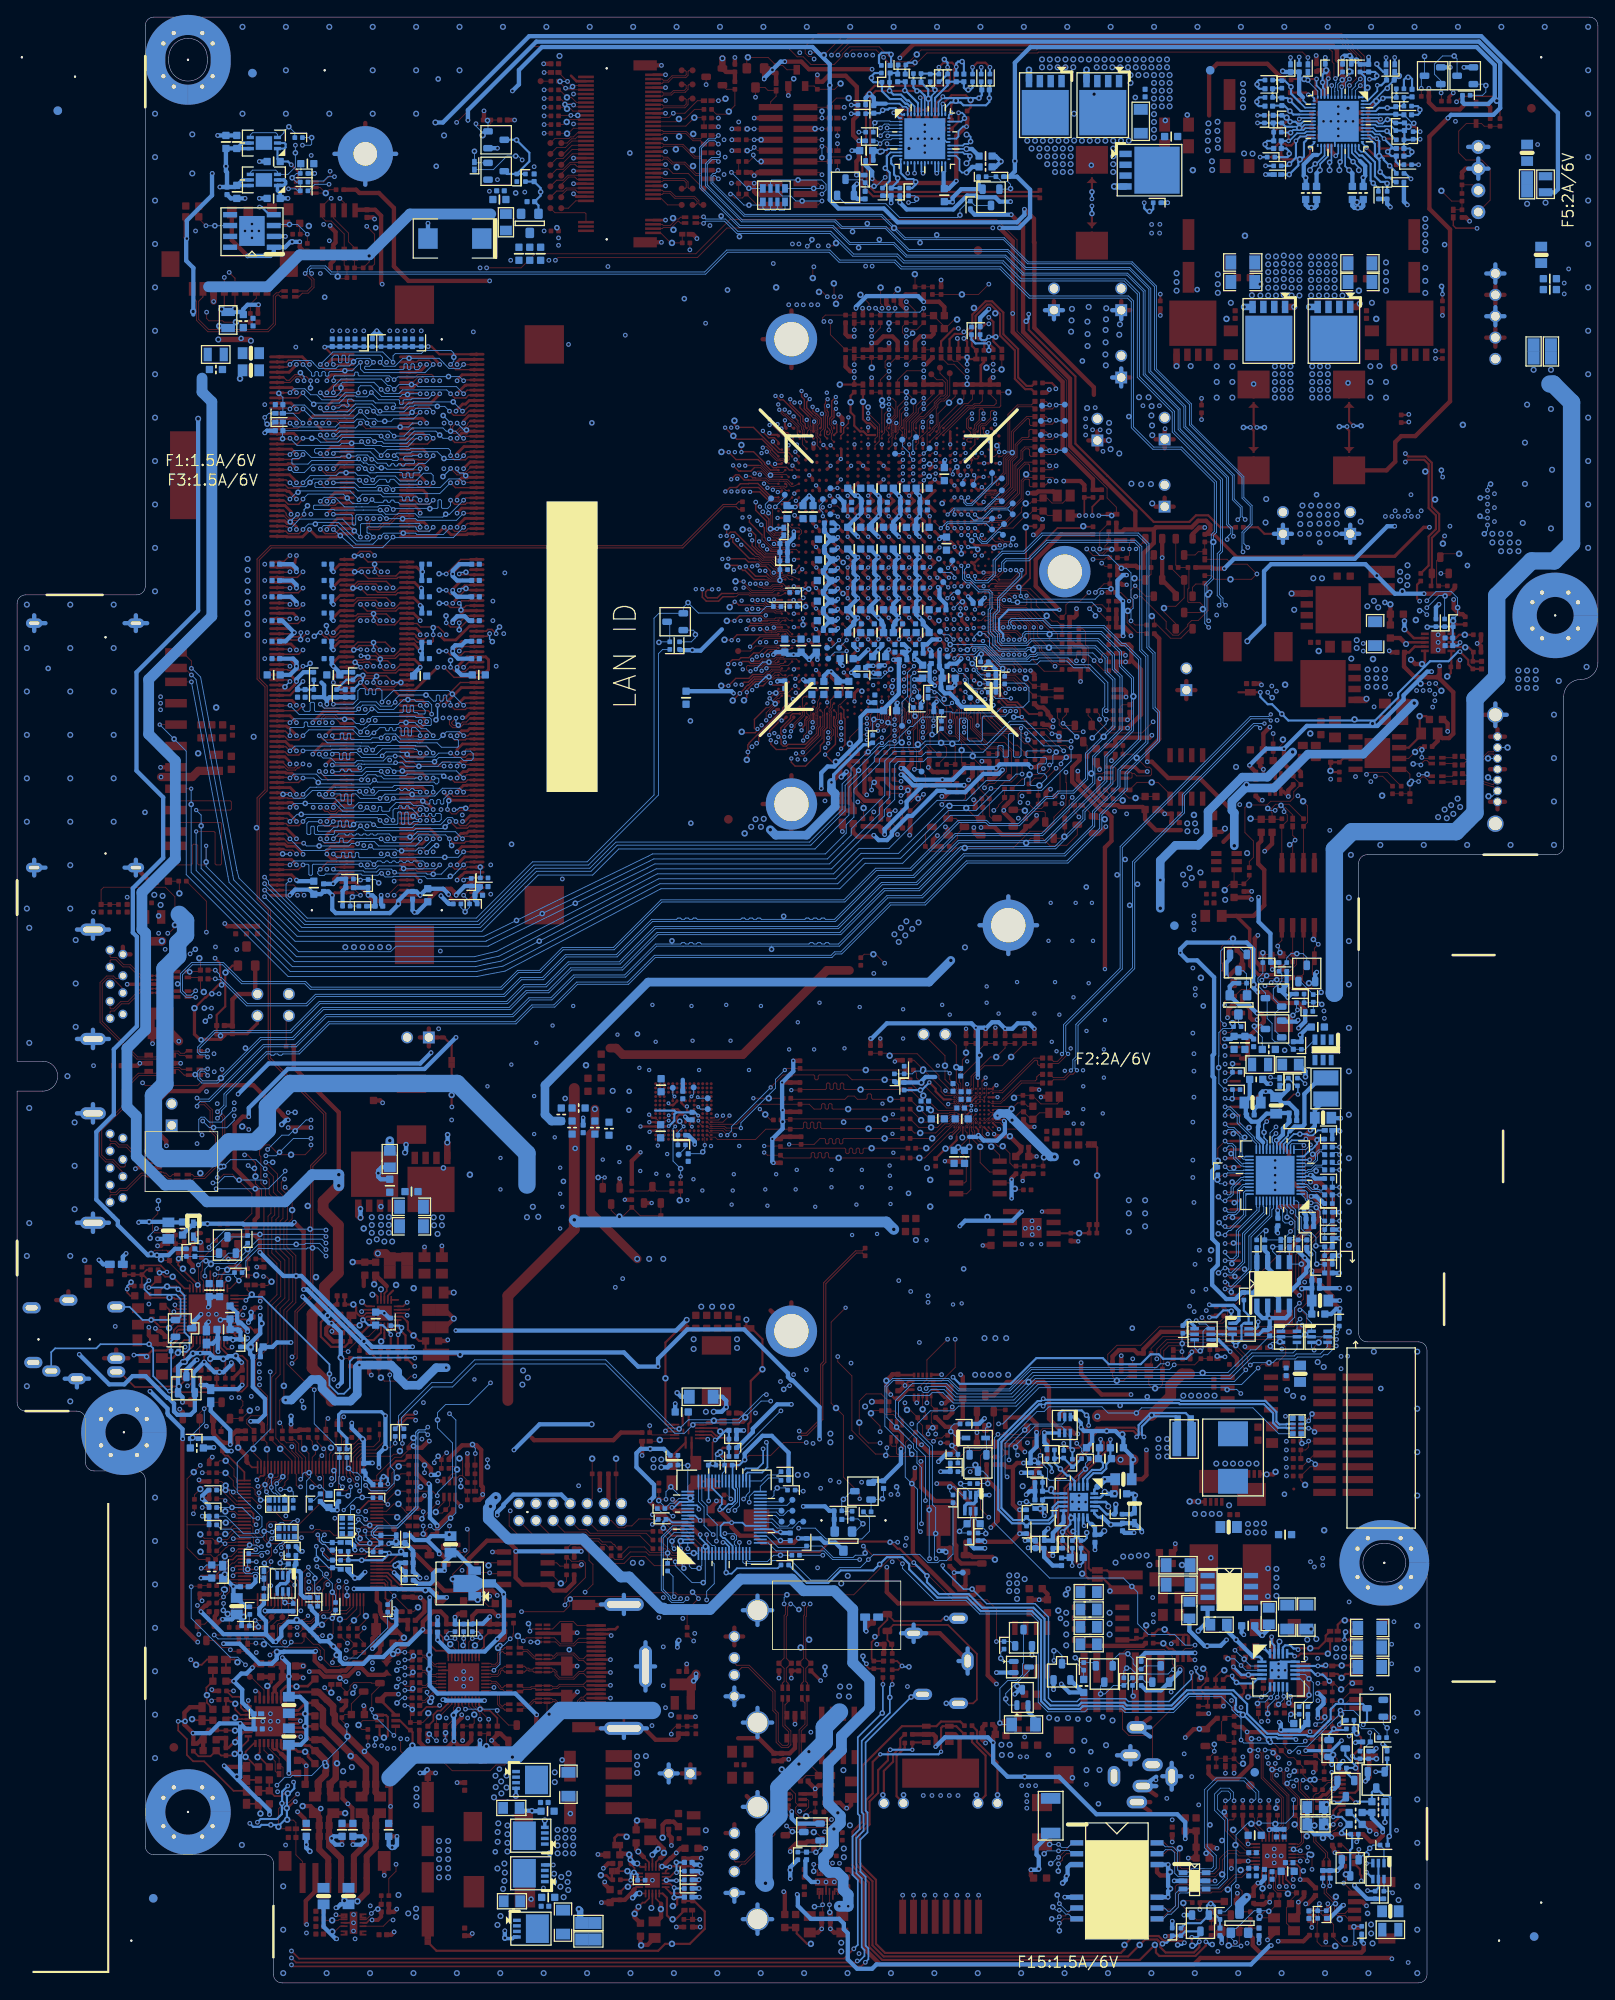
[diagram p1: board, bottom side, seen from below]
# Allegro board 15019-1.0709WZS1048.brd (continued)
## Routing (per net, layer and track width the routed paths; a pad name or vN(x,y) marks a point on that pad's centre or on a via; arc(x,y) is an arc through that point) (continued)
AC_PRES: length 12.1
  TOP w0.102: CPU1.AG3 71.41,161.29 71.03,161.29 71.03,161.3 70.77,161.3 70.77,161.29 70.23,161.29 70.23,161.3 69.97,161.3 69.59,160.92 66.87,160.92 64.17,158.22 v1(64.17,157.78) 64.17,157.16 R582.1
AC_PROTECT: length 22.2
  TOP w0.102: v4(60.99,63.13) 62.2,64.34 63.36,64.34 63.87,64.85 64.97,64.85 65.23,64.58 65.23,64.22 65.68,63.78 68.61,63.78 68.91,63.49 69.43,63.49 69.71,63.21 69.71,62.5 PR5298.1 69.76,61.53 PR5289.2 PR5297.2 71.53,61.85 70.7,62.68 PQ4408.G
  BOTTOM w0.102: U55.3 60.74,59.36 v2(59.98,60.12) 59.98,60.78 59.53,61.23 PR5287.1 60.05,61.85 60.1,61.85 60.41,62.16 60.41,62.54 v4(60.99,63.13)
AD+_2: length 1.1
  BOTTOM w0.508: v4(68.23,33.78) 67.71,34.3 PQ4205.C
  vias: v1(67.95,34.72)
AD+_G_1: length 6.2
  TOP w0.254: 48.34,40.73 48.08,40.73 47.9,40.55 PQ5005.6 ; 48.34,40.73 48.55,40.53 PQ5005.5 ; 48.34,40.73 50.08,40.73 v1(50.71,41.35) 51.46,41.35 PR5272.2
AD+_G_2: length 4.1
  TOP w0.254: v1(52.87,41.83) 52.93,41.77 PR5272.1 52.93,40.7 53.31,40.32 PR5275.2 54.2,40.13 55.66,40.13
AD+_TO_SYS: length 3.5
  TOP w0.254: PR5276.1 56.57,46 57.89,47.32 PG4907.1
  vias: v2(57.11,45.85) v7(57.14,43.31) v7(57.14,42.04) v7(57.14,40.77)
AD_IA: length 116.4
  L3 w0.127: v4(67.67,56.13) 68.68,56.13 70.87,53.95 76.09,53.95 80.26,49.78 84.35,49.78 85.12,49.02 85.47,49.02 88.3,46.19 88.78,46.19 88.79,46.21 95.47,46.21 96.49,45.19 99.83,45.19 102.22,42.8 106.94,42.8 v4(107.09,42.65) 107.72,42.02 116.37,42.02 118.77,39.62 122.26,39.62 122.47,39.41 137.35,39.41 138.78,40.84 140.95,40.84 143.56,38.23 146.05,38.23 146.28,38 v4(146.57,38)
  L4 w0.127: v4(107.09,42.65) 107.09,43.79 106.12,44.76 106.12,47.9 103.67,50.35 103.67,52.32 v4(103.54,52.45)
  BOTTOM w0.102: v4(103.54,52.45) 104.6,53.52 104.6,55.68 105.27,56.34 U4101.48 ; R80216.1 141.64,41.54 145.18,38 v4(146.57,38) ; v4(67.67,56.13) 67.5,56.3 v2(66.88,56.3) 66.64,56.3 PR5288.2
AD_IA_HW1: length 129.6
  TOP w0.102: v4(152.23,40.73) 152.05,40.91 152.04,40.91 151.42,41.53 R79637.1 150.94,42.07 150.56,42.07 149.32,43.31 148.37,43.31 148.06,43.62 U109.106
  L3 w0.127: v4(152.23,40.73) 151.85,41.11 149.06,41.11 148.68,40.73 143.64,40.73 142.5,41.87 137.37,41.87 136.78,41.28 127.1,41.28 127.1,41.28 126.68,41.28 124.92,43.04 110.68,43.04 109.84,43.88 107.67,43.88 v4(106.59,44.96) ; v4(68.92,61.19) 71.06,61.19 74.63,57.62 86.17,57.62 88.42,55.37 90.98,55.37 92.09,54.27 97.67,54.27 99.35,52.59 99.35,51.56 v4(99.32,51.54)
  L4 w0.127: v4(106.59,44.96) 106.59,48.15 105.61,49.13 105.61,52.57 105.26,52.92 102.64,52.92 102.51,53.05 101.97,53.05 101.7,52.77 101.7,52.32 101.72,52.29 101.72,51.9 101.45,51.63 101.04,51.63 100.66,52.01 100.27,52.01 99.8,51.54 v4(99.32,51.54)
  BOTTOM w0.102: v4(106.59,44.96) 107.04,44.5 108.39,44.5 108.8,44.9 108.8,45.15 109.61,45.96 109.61,52.16 108.29,53.48 U4101.59 ; PQ5006.2 62.39,65.66 62.67,65.38 66.4,65.38 67.08,64.7 v2(67.08,64.69) 67.47,64.31 67.48,64.31 68.92,62.87 v4(68.92,61.19)
AD_IA_HW2: length 126.1
  TOP w0.102: U109.107 148.46,43.7 148.62,43.54 149.42,43.54 150.65,42.3 151.53,42.3 v4(152.23,41.59) R79638.1
  L3 w0.127: v4(67.93,61.75) 70.86,61.75 74.74,57.87 86.28,57.87 88.52,55.63 91.09,55.63 92.19,54.52 97.77,54.52 99.82,52.48 100.87,52.48 v4(101.25,52.1) ; v4(152.23,41.59) 152,41.36 148.96,41.36 148.58,40.98 143.75,40.98 142.61,42.13 137.27,42.13 136.68,41.54 127,41.54 126.79,41.54 125.03,43.29 110.78,43.29 109.95,44.13 108.17,44.13 v4(107.35,44.96)
  L4 w0.127: v4(101.25,52.1) 101.25,52.87 101.69,53.3 102.62,53.3 102.66,53.26 105.41,53.26 105.91,52.75 105.91,50.87 105.86,50.82 105.86,49.24 106.84,48.26 106.84,45.47 v4(107.35,44.96)
  BOTTOM w0.102: v4(67.93,61.75) 68.1,61.92 68.1,62.63 v2(68.16,62.69) 68.16,62.87 65.87,65.15 62.77,65.15 62.39,64.77 PQ5006.5 ; v4(107.35,44.96) 107.58,44.73 108.3,44.73 108.57,45 108.57,45.24 109.38,46.06 109.38,52.07 108.37,53.08 U4101.60
AD_JK: length 60.9
  TOP w0.508: DCIN1.1 54.71,27.7 ; DCIN1.1 56.28,26.63 ; DCIN1.1 54.71,25.56
  TOP w1.27: v7(55.86,61.21) v1(54.39,61.21)
  L3 w0.508: 54.71,25.56 DCIN1.1 ; DCIN1.1 56.28,26.63 ; DCIN1.1 54.71,27.7
  L3 w1.27: v7(67.32,58.12) 67.19,58.24 62.82,58.24 60.94,60.12 56.95,60.12 v7(55.86,61.21)
  L4 w0.508: DCIN1.1 56.28,26.63 ; DCIN1.1 54.71,25.56 ; DCIN1.1 54.71,27.7
  L4 w1.27: v7(67.32,58.12) 67.39,58.12 68.71,56.79 68.71,51.03 64.3,46.61 64.3,39.5 64.93,38.86 64.93,31.75 v7(64.22,31.04)
  BOTTOM w0.508: DCIN1.1 56.28,26.63 ; DCIN1.1 54.71,25.56 ; DCIN1.1 54.71,27.7 ; 65.95,30.99 66.69,31.73 PQ4205.E
  vias: v2(57.95,31.11) v2(58.45,20.95) v2(59.34,27.05) v2(60.87,30.86) v2(61.5,24) v2(63.28,30.86) v2(64.3,26.67) v7(56.8,30.71) v7(57.56,27.81) v7(58.33,24.92) v7(59.6,30.86) v7(59.85,24.89) v7(60.1,28.32) v7(61.5,27.18) v7(62.01,30.99)
AD_OFF: length 90.2
  TOP w0.102: R2013.1 144.43,39.81 R80211.1 144.38,41.39 v4(144.38,41.53) ; v1(72.85,60.6) 72.85,60.6 72.85,60.42 v4(73.46,59.81)
  L3 w0.127: v4(73.46,59.81) 74.38,58.89 82.12,58.89 82.92,59.69 86.93,59.69 89.47,57.15 91.72,57.15 92.44,56.43 98.2,56.43 99.35,55.28 v4(101,55.28) ; v4(109.38,45.09) 111.54,45.09 111.72,45.26 116.06,45.26 117.66,43.66 123.86,43.66 123.94,43.58 125.1,43.58 126.89,41.79 136.57,41.79 137.28,42.49 143.33,42.49 144.29,41.53 v4(144.38,41.53)
  L4 w0.127: v4(101,55.28) 101.06,55.28 102.71,53.63 105.94,53.63 109,50.58 109,45.47 v4(109.38,45.09)
  BOTTOM w0.102: U4101.36 100.47,58.01 100.45,58 100.45,55.82 v4(101,55.28)
AD_OFF_ECIO: length 3.9
  TOP w0.102: U109.97 144.45,43.2 v1(144.18,42.93) 144.18,42.48 R80211.2
AD_OFF_L: length 6.7
  BOTTOM w0.102: PQ4205.B 68.93,32.5 69.3,32.87 v2(69.3,33.22) 69.3,33.86 68.05,35.12 67.97,35.12 66.57,36.52 PQ4204.C
ADAPTOR_PSID: length 116.5
  TOP w0.102: v4(105.82,40.01) 106.52,40.7 R80213.1 ; U109.119 153.25,42.75 153.74,42.27 153.8,42.27 154.03,42.04 154.38,42.04 154.54,41.87 154.54,40.37 154.21,40.04 154.21,39.76 153.71,39.27 149.88,39.27 149.51,38.9 v4(149.51,37.97)
  L3 w0.127: v4(149.51,37.97) 147.93,37.97 146.97,37.02 144.76,37.02 143.72,35.98 143.12,35.98 139.9,39.19 139.47,39.19 138.03,37.76 121.79,37.76 121.57,37.97 118.08,37.97 117.09,38.96 113.86,38.96 112.45,40.37 106.19,40.37 v4(105.82,40.01) 105.14,39.32 91.49,39.32 91.09,39.72 89.97,40.84 89.65,40.84 84.52,45.96 71.87,45.96 63.66,37.75 v4(63.66,37.72)
  BOTTOM w0.102: R1846.2 R1851.2 60.94,37.35 D19.3 62.72,38.31 63.27,38.86 v2(63.66,38.86) 63.66,38.85 v4(63.66,37.72)
ADAPTOR_PSID_R: length 2.8
  BOTTOM w0.102: v2(61.17,38.05) 60.6,37.47 R1851.1 59.13,37.47 Q47.S
AGPIO3: length 21
  TOP w0.102: CPU1.AL5 73,157.5 v3(73,157.18) ; R2010.2 R2008.1 57.84,155.57 58.07,155.35 58.07,154.81 v4(58.2,154.69)
  BOTTOM w0.102: v3(73,157.18) 73,157.53 72.66,157.86 v2(72.33,157.86) 71.79,157.86 71.2,157.27 71.2,156.42 69.77,154.99 66.9,154.99 66.48,155.41 65.87,155.41 65.67,155.61 59.12,155.61 v4(58.2,154.69)
AGPIO8: length 14.8
  TOP w0.102: R79650.1 62.91,153.47 64.8,153.47 66.1,154.76 v1(66.1,155.98) 66.65,156.54 66.65,158.77 67.79,159.91 70.31,159.91 70.32,159.9 70.68,159.9 70.69,159.91 71.11,159.91 71.12,159.9 71.66,159.9 71.79,159.77 72.15,159.4 CPU1.AJ4
AGPIO11: length 27.3
  TOP w0.102: CPU1.AN5 73.3,156.28 v3(73,155.98) ; R2064.2 R2063.1 v4(57.54,147.83)
  BOTTOM w0.102: v3(73,155.98) 72.8,156.18 71.86,156.18 69.97,154.29 65.66,154.29 65.28,154.67 62.15,154.67 61.36,153.87 59.58,153.87 57.71,152 57.71,149.32 58,149.03 58,148.29 v4(57.54,147.83) 57.54,147.3 v2(59.17,145.67)
AGPIO13: length 24.5
  TOP w0.102: R79673.1 58.3,169.76 v4(58.3,167.77) ; CPU1.AD5 73.3,163.79 73.69,163.4 v3(73.7,163.4)
  L3 w0.127: v4(58.3,167.77) 59.75,169.21 64.09,169.21 67.03,166.27 67.03,165.14 67.04,165.13 67.12,165.04 67.13,165.03 67.19,164.97 67.2,164.96 67.57,164.59 72.04,164.59 73.23,163.4 v3(73.7,163.4)
  BOTTOM w0.102: v2(56.9,167.72) 56.95,167.77 v4(58.3,167.77)
AGPIO14: length 2.7
  TOP w0.102: v3(75.4,157.18) 75.7,157.48 CPU1.AL8
  BOTTOM w0.102: v3(75.4,157.18) 75.95,157.73 76.61,157.73 TP198.1
AGPIO15: length 1.8
  TOP w0.102: CPU1.AN8 75.7,156.28 v3(75.4,155.98)
  BOTTOM w0.102: TP199.1 76.11,155.27 v3(75.4,155.98)
AGPIO24: length 21.8
  TOP w0.102: v4(58.96,154.71) 58.96,154.69 58.45,154.17 57.82,153.54 R79671.1 ; v3(76.2,157.18) 76.5,157.48 CPU1.AL9
  BOTTOM w0.102: v3(76.2,157.18) 76.2,156.99 v2(75.8,156.59) 71.66,156.59 69.86,154.79 66.81,154.79 66.42,155.18 65.77,155.18 65.57,155.38 59.63,155.38 v4(58.96,154.71)
AGPIO40: length 25.2
  TOP w0.102: R79651.1 57.25,167.7 57.94,167.01 59.07,167.01 v4(59.82,167.77) ; v3(75.4,160.82) 75.4,161.1 CPU1.AG8
  L3 w0.127: v3(75.4,160.82) 75.19,160.82 74.55,161.47 73.82,161.47 72.3,162.99 71.62,162.99 70.49,164.11 67.4,164.11 66.22,165.29 66.22,166.36 63.88,168.7 60.76,168.7 v4(59.82,167.77)
  BOTTOM w0.102: v2(74.37,161.59) 74.63,161.59 v3(75.4,160.82)
AGPIO66: length 21.4
  TOP w0.102: CPU1.AT15 81.45,154.05 v3(81.19,154.05) ; R159.1 v4(82.23,137.16)
  L3 w0.127: v4(82.23,137.16) 82.16,137.23 82.16,137.27 82.08,137.34 82.08,143.12 81.64,143.56 81.64,148.39 83,149.75 83,151.12 82.8,151.32 81.97,151.32 81.85,151.45 81.85,153.39 v3(81.19,154.05)
  BOTTOM w0.102: v2(82.91,136.7) 82.46,137.16 v4(82.23,137.16)
AGPIO84: length 3.9
  TOP w0.102: CPU1.BC18 v3(83.8,147.58)
  BOTTOM w0.102: R79714.1 84.87,147.7 v2(84.74,147.83) 84.05,147.83 v3(83.8,147.58)
AGPIO88: length 4.9
  TOP w0.102: CPU1.BC11 78.16,148.06 78.16,144.68 77.25,143.76 TP186.1
AGPIO89: length 5.8
  TOP w0.102: CPU1.BB14 80.6,148.93 80.9,148.63 80.9,148.37 80.89,148.37 80.89,147.88 81.03,147.74 81.03,147.47 81.09,147.41 81.09,146.7 81.1,146.69 81.44,146.35 81.44,145.16 v1(81.47,145.14) 81.31,144.98 R79672.1
AMP_GND: length 49.4
  TOP w0.305: U21.4 v4(158.9,30.36)
  TOP w0.508: R358.2 163.23,28.89 C192.2 ; C208.2 157.01,37.34 v4(157.46,36.88) ; R355.2 v4(159.65,35.31) ; v4(155.46,19.71) 155.48,19.73 R365.2 ; R346.1 164.78,32.26 165.41,31.62 165.41,30.22 v4(164.41,29.22) 164.37,29.18 R347.1 163.93,28 163.48,28.45 C192.2 ; C193.2 C192.2 ; R344.1 160.64,25.27 v4(160.76,25.4)
  BOTTOM w0.508: v4(157.46,36.88) 158.15,36.2 158.76,36.2 v4(159.65,35.31) 158.66,34.32 158.66,32.82 158.22,32.38 158.21,32.38 R666.1 157.32,29.84 C531.2 158.26,29.72 v4(158.9,30.36) ; 159.16,23.8 156.84,21.48 156.77,21.48 155.46,20.17 v4(155.46,19.71) ; 159.16,23.8 v4(160.76,25.4) ; 159.16,23.8 158.9,24.07 v2(158.9,26.91) v4(158.9,30.36) ; v4(164.41,29.22) 162.45,29.22 161.32,30.36 v4(158.9,30.36)
AMP_SPKR_L: length 5.2
  TOP w0.203: C199.1 162.46,32.38 162.46,32.47 162.78,32.79 v1(162.78,33.67) 162.78,33.69 162.85,33.76 162.85,34.54 R355.1 R356.2
AMP_SPKR_R: length 5.1
  TOP w0.203: v1(153.32,22.18) 153.72,22.18 154.04,21.86 154.86,21.86 R365.1 ; R365.1 R367.2 ; R365.1 C210.1
APU_ALERT#: length 15.4
  TOP w0.102: v4(85,192.63) 83.98,193.65 R1616.2 ; v3(82.96,183.44) 83.13,183.27 83.13,182.2 83.3,182.03 83.3,181.72 83,181.42 CPU1.B17
  L4 w0.127: v4(85,192.63) 84.46,192.1 84.46,184.94 v3(82.96,183.44)
  BOTTOM w0.102: v3(82.96,183.44) v2(82.96,182.73)
APU_DBRDY: length 54.6
  TOP w0.102: v3(79,182.64) 79.41,182.23 79.41,181.07 79.8,180.67 CPU1.C13 ; v4(91.76,200.79) 91.88,200.67 v1(91.88,199.47) ; HDT1.14 v4(90.81,215.65)
  L3 w0.127: v4(90.81,215.65) 93,213.46 93,202.03 v4(91.76,200.79)
  L4 w0.127: v4(91.76,200.79) 86.65,200.79 85.47,199.61 79.35,199.61 76.14,196.4 76.14,187.67 77.76,186.06 77.76,184.53 79,183.29 v3(79,182.64)
APU_DBREQ: length 3.7
  TOP w0.102: R1746.1 v4(90.81,216.92) HDT1.16
  BOTTOM w0.102: v4(90.81,216.92) 91.49,216.92 91.52,216.94 v2(91.62,216.94)
APU_DBREQ#: length 75.7
  TOP w0.102: R1704.2 C1739.1 v4(101.4,210.57) ; R1746.2 v4(89,216.1) ; v3(77.98,182.64) 78.2,182.42 CPU1.A11 ; v4(90.06,203.24) 89.48,203.24 v1(89.16,203.56)
  L3 w0.127: v4(100.55,217.73) 100.55,211.26 101.25,210.57 v4(101.4,210.57) ; v4(90.06,203.24) 90.06,207.7 89.83,207.93 89.83,215.27 v4(89,216.1)
  L4 w0.127: v3(77.98,182.64) 77.24,183.38 77.24,185.85 75.34,187.75 75.34,190.16 72.26,193.25 72.26,198.17 76.56,202.47 89.29,202.47 v4(90.06,203.24) ; v4(89,216.1) 89.01,216.12 98.94,216.12 v4(100.55,217.73)
APU_DIS_1: length 3.7
  BOTTOM w0.102: R1185.1 C866.1 91.54,15.3 v2(91.52,15.29) 91.4,15.42 91.35,15.42 91.03,15.74 Q104.G
APU_DIS_2: length 9.2
  TOP w0.102: R1186.1 88.84,18.01 v1(89.42,18.01) 89.61,18.2 93.13,18.2 Q105.G 93.26,18.19 94.78,18.19 v4(94.95,18.36)
  BOTTOM w0.102: Q104.D 94.22,17.65 v2(94.27,17.7) 94.29,17.7 v4(94.95,18.36)
APU_DIS_3: length 4.9
  TOP w0.102: Q105.D 94.72,17.64 v1(91.77,17.64) 91.52,17.64 R1981.1
APU_LVDS_BL_ADJ: length 158.8
  TOP w0.102: CPU1.F11 77.78,177.9 v3(77.5,178.18)
  L3 w0.127: v4(18.17,176.19) 18.3,176.31 18.88,176.31 19.85,177.29 48.03,177.29 49.31,178.56 51.85,178.56 54.49,181.19 54.49,183.54 60.26,189.32 67.55,189.32 71.87,185 72.83,184.04 73.42,184.04 76.22,181.24 76.22,179.46 v3(77.5,178.18)
  L4 w0.127: v4(38.31,105.97) 38.16,106.12 38.16,115.1 36.74,116.52 36.74,119.98 36.61,120.11 36.61,134.93 31.62,139.92 25.94,139.92 24.96,140.9 24.96,146.75 22.13,149.58 22.13,150.96 20.14,152.95 18.99,152.95 17.95,153.98 17.95,163.59 17.15,164.4 17.15,165.56 18.87,167.28 18.87,169.49 18.69,169.66 18.69,171.65 17.93,172.41 17.93,175.95 v4(18.17,176.19)
  BOTTOM w0.102: v2(18.32,176.99) 18.32,176.34 v4(18.17,176.19) ; v4(38.31,105.97) 38.2,105.85 R502.2
APU_M_VREF_SUS: length 5.4
  BOTTOM w0.254: v2(95.72,164.1) 95.72,164.59 95.73,164.6 R1588.2 R115.1 C1609.2 C1608.1 95.73,168.91 R1912.1
APU_M_VREFDQ_SUS: length 76
  TOP w0.254: DIMM1.1 135.59,190.55 136.49,191.45 v4(136.89,191.45) ; R1697.1 R81.1 ; R81.1 v1(88.72,187.01) ; R81.1 v4(87.03,187.81) ; DIMM2.1 148.17,190.55 v4(149,191.39)
  L3 w0.254: v4(136.89,191.45) 136.44,191.01 132.88,191.01 129.67,187.81 v4(87.03,187.81)
  BOTTOM w0.254: v4(149,191.39) 148.94,191.45 C1960.1 C1959.1 C1982.2 C1981.2 R2058.1 R2057.2 R1633.2 C15.1 C1728.1 C1731.2 C1727.2 R78.1 v4(136.89,191.45)
APU_PROCHOT#: length 534.7
  TOP w0.102: PQ4408.D 71.72,64.9 71.72,62.88 72.32,62.28 73.9,62.28 74.6,61.58 82.82,61.58 83.12,61.87 84.54,61.87 87.31,64.64 87.31,71.02 88.96,72.67 v4(88.96,73.28) ; v4(33.94,225.27) 34.58,225.91 65.46,225.91 65.56,225.81 78.52,225.81 80.04,224.28 82.58,224.28 v4(83.6,225.3) 84.47,226.16 87.3,226.16 v4(87.92,225.55) ; CPU1.A15 81.3,182 81.3,182.83 80.93,183.2 v3(80.93,183.51) ; R1615.2 79.73,193.42 80.91,193.42 v4(80.93,193.4)
  L3 w0.127: v4(137.45,67.89) 118.93,67.89 106.69,80.14 93.76,80.14 88.96,75.34 v4(88.96,73.28) ; v4(83.6,225.3) 84.15,224.75 84.15,221.21 81.88,218.95 81.88,209.51 v4(80.68,208.31) ; v4(137.09,47.4) 137.54,47.84 140.01,47.84 140.65,48.48 142.09,48.48 142.64,49.02 147.9,49.02 148.56,49.68 149.67,49.68 150.01,50.03 153.56,50.03 153.89,49.7 153.89,49.7 153.91,49.68 154.99,49.68 v4(155.7,50.39) ; v4(87.92,225.55) 87.92,223.27 94.74,216.45 94.74,198.08 v4(93,196.34)
  L4 w0.127: v3(80.93,183.51) 80.21,184.24 80.21,185.43 79.92,185.72 79.92,189.74 ; 79.92,189.74 78.18,191.48 78.18,193.7 80.21,195.73 80.21,197 80.63,197.42 86.37,197.42 88.17,195.62 92.36,195.62 93,196.26 v4(93,196.34) 93.47,196.81 93.95,196.81 94.23,196.54 94.23,196.15 94.5,195.87 104.47,195.87 106.07,194.27 151.55,194.27 154.49,191.33 154.49,131.48 153.84,130.83 153.84,126.54 149.53,122.24 149.53,109.28 147.39,107.14 147.39,106.38 147.39,106.38 147.39,98.27 148.24,97.42 148.24,89.75 147.39,88.9 147.39,78.72 140.23,71.55 140.23,70.98 137.45,68.2 v4(137.45,67.89) 137.83,67.51 137.83,65.02 138.72,64.14 138.72,53.22 138.05,52.55 138.05,52.52 137.8,52.27 137.8,48.08 137.12,47.4 v4(137.09,47.4) ; 79.92,189.74 79.92,192.38 v4(80.93,193.4) ; v4(85.38,49.53) 86.94,51.1 86.94,62.16 89.31,64.53 89.31,72.92 v4(88.96,73.28)
  BOTTOM w0.102: v4(155.7,50.39) 155.77,50.46 156.56,50.46 156.79,50.23 R80226.1 ; v4(33.94,225.27) PR24.2 ; PR4455.1 75.47,50.16 76.23,49.4 77.03,49.4 77.26,49.17 78.4,49.17 79.37,50.14 84.77,50.14 v4(85.38,49.53) 86.32,48.59 88.75,48.59 90.21,47.13 92.12,47.13 94.42,49.43 96.58,49.43 96.93,49.07 99.91,49.07 100.07,49.24 U4101.14 ; PR5464.2 79.95,209.11 79.74,208.89 v2(79.74,208.71) 79.74,208.51 79.94,208.31 v4(80.68,208.31)
APU_PWNBTN_N: length 14.6
  TOP w0.102: v3(67.55,162.26) 67.89,162.6 69.85,162.6 69.85,162.6 CPU1.AE1 ; R1653.2 v4(58.05,162.69)
  BOTTOM w0.102: v4(58.05,162.69) 58.84,161.89 67.19,161.89 v3(67.55,162.26) 67.55,163.09 v2(67.76,163.3)
APU_PWRGD: length 40.7
  TOP w0.102: R1744.2 89,212.08 v4(88.98,212.06) ; R495.2 R1720.1 R1904.1 v4(87.03,189.33) ; R495.2 85,189.11 84.97,189.08 v1(84.97,188.98) ; R495.2 C1722.2 ; CPU1.C19 84.6,180.67 84.3,180.97 84.3,181.28 84.31,181.29 84.31,181.77 84.3,181.77 84.3,182.03 85.29,183.02 v3(85.4,183.02)
  L3 w0.127: v4(88.98,212.06) 88.98,211.84 89.07,211.75 89.07,207.61 89.1,207.58 89.1,198.41 88.16,197.48 88.16,197.09 88.81,196.44 88.81,191.11 v4(87.03,189.33)
  L4 w0.127: v3(85.4,183.02) 85.4,183.06 86.56,184.22 86.56,188.86 v4(87.03,189.33)
APU_PWRGD_BUF: length 5.5
  TOP w0.102: HDT1.10 R1744.1 89.89,213.45 89.7,213.64 87.71,213.64 v1(87.66,213.59)
APU_S5_MUX_CTRL: length 478.7
  TOP w0.102: v4(75.34,159.51) 75.7,159.87 CPU1.AH8 ; v4(170.31,105.31) 169.98,104.98 163.87,104.98 163.26,105.59 161.42,105.59 v1(161.15,105.87) 161.02,105.99 v4(161.02,106.88)
  L3 w0.127: v4(75.34,159.51) 74.71,160.15 73.38,160.15 73.27,160.26 72.68,160.26 72,160.93 68.88,160.93 68.36,161.46 66.45,161.46 65.95,161.96 61.59,161.96 61.53,162.01 61.02,162.01 59.02,164.02 39.96,164.02 38.27,165.7 27.25,165.7 25.02,167.93 15.8,167.93 12.45,164.58 12.45,154.7 15.39,151.76 15.39,140.94 17.77,138.56 28.87,138.56 35.59,131.84 35.59,116.7 36.88,115.42 36.88,109.89 40.11,106.65 40.11,80.34 44.79,75.67 51.72,75.67 52.97,76.91 88.39,76.91 92.93,81.45 107.56,81.45 119.65,69.35 148.2,69.35 148.71,69.86 153.54,69.86 155.39,68.01 160.1,68.01 160.37,68.28 160.37,68.97 157.13,72.21 157.13,72.92 155.05,75.01 155.05,75.76 155.01,75.8 155.01,80.4 155.05,80.44 155.05,88.39 155.79,89.13 155.79,92.53 162.64,99.39 162.64,103.82 162.36,104.1 162.36,104.12 161.02,105.46 v4(161.02,106.88)
  L4 w0.127: v4(170.31,105.31) 171.11,106.1 171.11,107.79 171.1,107.8 171.1,128.09 168.12,131.08 168.12,136.73 167.58,137.26 167.58,196.43 160.56,203.45 157.33,203.45 156.5,204.28 153.87,206.92 153.87,208.91 153.49,209.3 149.64,209.3 v4(148.5,210.44)
  BOTTOM w0.102: v4(148.5,210.44) 150.15,210.44 150.91,209.68 R4230.1
APU_S5_MUX_CTRL_D: length 4.3
  TOP w0.102: Q4701.2 149.53,210.06 v1(148.88,209.41) ; Q4701.3 v1(148.88,209.41) ; v1(148.88,209.41) 148.48,209.8 R4702.2
APU_S5_MUX_CTRL_R: length 7.2
  TOP w0.102: Q4701.5 153.09,210.06 v4(153.25,209.91)
  BOTTOM w0.102: v4(153.25,209.91) 152.41,209.91 152.18,209.68 R4230.2 R79674.2 152.31,210.69 v2(152.81,211.2) 152.31,211.71 R79675.2 151.8,211.77 PC5429.1
APU_SATA_LED_N: length 352.8
  TOP w0.102: v3(82.31,146.56) 81.7,147.17 81.7,148.23 81.4,148.53 CPU1.BB15
  L3 w0.254: v3(82.31,146.56) 82.46,146.41 82.51,146.41 82.79,146.12 82.79,145.09 82.68,144.97 82.68,138.32 84.68,136.32 85.68,136.32 87.81,134.19 89.36,134.19 92.59,130.96 120.15,130.96 134.25,116.86 159.04,116.86 159.99,115.91 159.99,114.75 164.39,110.34 164.39,109.58 164.48,109.49 164.48,97.98 164.01,97.51 161.79,97.51 156.76,92.49 156.76,87.25 156.05,86.54 156.05,83.52 156.7,82.87 156.7,82.43 155.85,81.58 155.85,80.21 155.74,80.1 155.74,76.1 157.81,74.03 157.81,73.64 158.2,73.25 158.2,72.16 161.09,69.27 161.09,67.48 160.01,66.4 155.23,66.4 154.48,67.14 144.84,67.14 142.34,64.64 140.14,64.64 138.36,62.86 136.32,62.86 135.38,63.81 121.62,63.81 119.3,61.48 112.54,61.48 110.78,59.72 108.87,59.72 108.27,60.31 108.27,60.31 108.01,60.58 96.53,60.58 94.55,62.56 92.41,62.56 v4(91.85,63.12) ; v4(90.43,36.03) 88.01,36.03 82.72,30.73 67.88,30.73 65.71,32.91 48.9,32.91 43.32,27.33 41.68,27.33 37.6,23.25 36.95,23.25 36.08,22.38 34.55,22.38 v4(34.07,22.86) 34.07,21.4 33.69,21.02 33.69,20.68 31.5,18.5 31.5,18.32 31.19,18.01 30.67,18.01 30.45,17.78 28.1,17.78 27.08,16.76 27.08,15.11 27.8,14.39 27.8,13.67 v4(27.08,12.95)
  L4 w0.254: v4(34.07,22.86) 33.94,22.99 33.94,24.84 30.54,28.24 30.54,28.57 30.23,28.88 v4(29.12,28.88) ; v4(90.43,36.03) 90.43,37.07 90.1,37.4 90.1,48.38 87.92,50.56 87.92,58.68 91.85,62.61 v4(91.85,63.12)
  BOTTOM w0.254: v4(27.08,12.95) 26.34,12.21 Q9646.4 ; v4(29.12,28.88) 28.54,29.45 R1754.1 R2077.2 ; v4(90.43,36.03) 90.43,36.93 v2(90.46,36.96)
APU_SIC: length 240.4
  TOP w0.102: v3(82.96,184.07) 83.51,183.53 83.51,181.63 83.5,181.63 83.5,181.37 83.8,181.07 CPU1.B18 ; U109.51 149.66,61.38 v4(149.33,61.7) ; R93.2 v4(85,193.4)
  L3 w0.127: v4(149.33,61.7) 149.02,62.01 148.94,62.01 148.12,62.83 142.59,62.83 140.69,60.92 136.81,60.92 136.75,60.86 v4(136.18,60.86)
  L4 w0.127: v4(136.18,60.86) 136.18,61.34 136.03,61.49 136.03,67.67 139.72,71.36 139.72,71.76 146.81,78.85 146.81,107.28 149.02,109.49 149.02,123.2 149.26,123.43 149.26,128.25 150.82,129.81 150.82,132 151.4,132.57 152.45,132.57 153.56,133.69 153.56,190.89 150.69,193.76 105.86,193.76 104.77,194.86 86.46,194.86 v4(85,193.4) 84.2,192.6 84.2,185.31 v3(82.96,184.07)
  BOTTOM w0.102: v4(136.18,60.86) 136.18,61.17 v2(135.72,61.62)
APU_SID: length 243.7
  TOP w0.102: v4(149.59,59.03) 149.66,59.03 150.06,59.43 U109.50 ; CPU1.C17 83,180.67 82.7,180.97 82.7,181.28 82.71,181.29 82.71,181.77 82.7,181.77 82.7,182.23 82.72,182.26 82.72,182.76 82.15,183.34 82.15,184.99 82.51,185.34 v3(82.96,185.34) R1614.2
  L3 w0.127: v4(137.32,59.69) 142.88,59.69 143.55,60.36 143.61,60.36 143.95,60.71 147.46,60.71 148.29,59.88 148.54,59.88 149.39,59.03 v4(149.59,59.03)
  L4 w0.127: v3(82.96,185.34) 83.94,186.32 83.94,193.01 86.05,195.11 104.88,195.11 105.97,194.02 150.79,194.02 153.82,190.99 153.82,132.17 153,131.35 151.42,131.35 151.07,131 151.07,129.71 149.51,128.14 149.51,123.33 149.28,123.09 149.28,109.39 147.14,107.25 147.14,98.17 147.95,97.36 147.95,89.82 147.14,89.01 147.14,78.82 139.97,71.66 139.97,71.21 136.28,67.52 136.28,63.2 137.32,62.16 v4(137.32,59.69)
  BOTTOM w0.102: v4(137.32,59.69) v2(137.32,60.58)
APU_SPKR: length 133.7
  TOP w0.102: R208.1 167.61,87.76 168.89,87.76 169.15,88.01 169.15,89.38 168.54,89.99 v4(168.54,90.56) ; v3(84.28,147.13) 84.27,147.14 83.66,147.14 83.39,147.41 83.39,147.78 83.51,147.89 83.51,148.31 83.35,148.47 83.35,149.36 CPU1.BA17
  L3 w0.102: v3(84.28,147.13) 84.69,146.72 84.69,144.97 84.49,144.77 84.49,144.66 84.36,144.53 84.36,144.48 83.96,144.08 83.96,139.39 87.09,136.26 88.59,136.26 92.97,131.87 120.53,131.87 134.63,117.77 159.42,117.77 160.9,116.29 160.9,115.54 161.17,115.27 161.5,115.27 162.39,115.27 165.06,112.6 165.06,109.86 165.36,109.55 165.36,95.45 166.61,94.21 166.61,92.49 v4(168.54,90.56)
  BOTTOM w0.102: v4(168.54,90.56) 168.46,90.64 v2(168.46,91.52)
APU_SVC: length 14.3
  TOP w0.102: CPU1.D17 82.61,179.89 82.61,180.72 82.49,180.83 82.49,181.37 82.5,181.37 82.5,181.63 82.49,181.63 82.49,182.32 82.52,182.34 82.52,182.68 81.95,183.25 81.95,184.4 v3(80.93,185.42) ; v4(80.93,189.33) 80.08,190.18 R1628.1 R1902.1
  L4 w0.127: v3(80.93,185.42) 80.42,185.93 80.42,188.82 v4(80.93,189.33)
  BOTTOM w0.102: v2(80.93,186.16) v3(80.93,185.42)
APU_SVD: length 18
  TOP w0.102: v4(87.03,193.4) R1903.1 R1630.1 ; CPU1.D19 84.6,179.87 84.1,180.37 84.1,180.88 84.09,180.89 84.09,181.37 84.1,181.37 84.1,181.68 84.09,181.69 84.09,182.35 v3(85.4,183.66)
  L4 w0.127: v4(87.03,193.4) 86.52,192.89 86.52,189.36 86.18,189.02 86.18,185.39 86.33,185.24 86.33,184.59 v3(85.4,183.66)
  BOTTOM w0.102: v2(85.4,184.37) 85.4,184.3 85.4,184.3 v3(85.4,183.66)
APU_SVT: length 7.7
  TOP w0.102: R1901.1 R1632.1 80.12,185.3 v1(80.12,185.04) 80.12,183.73 81.1,182.75 81.1,181.77 81.14,181.73 81.14,181.27 81.1,181.23 81.1,180.97 81.4,180.67 CPU1.C15
APU_TCK: length 56.1
  TOP w0.102: CPU1.D13 79.8,179.87 79.5,180.17 79.5,180.63 79.13,181 79.07,181 78.5,181.57 78.5,182.76 v3(77.98,183.28) ; HDT1.2 91.27,208.03 v4(90.81,208.48)
  L3 w0.127: v4(90.81,208.48) 91.25,208.04 v4(91.25,203.24)
  L4 w0.127: v4(91.25,203.24) 90.23,202.22 76.66,202.22 72.51,198.07 72.51,193.35 75.6,190.27 75.6,187.86 77.5,185.96 77.5,183.76 v3(77.98,183.28)
  BOTTOM w0.102: RN12.2 96.02,209.63 95.46,209.07 94.44,209.07 93.86,208.48 v2(93.13,208.48) v4(90.81,208.48)
APU_TDI: length 59.4
  TOP w0.102: HDT1.6 91.27,210.57 v4(90.81,210.11) ; CPU1.H15 81.63,176.3 v3(81.33,176.6)
  L3 w0.127: v4(92.06,196.34) 91.29,197.11 91.29,202.25 92.06,203.02 92.06,208.86 v4(90.81,210.11)
  L4 w0.127: v4(92.06,196.34) 91.59,196.81 88.06,196.81 86.69,198.18 79.72,198.18 77.41,195.88 77.41,188.2 79.41,186.2 79.41,185.51 79.7,185.21 79.7,181.5 81.02,180.18 81.02,179.83 80.91,179.73 80.91,177.02 v3(81.33,176.6)
  BOTTOM w0.102: RN12.1 v2(91.78,209.96) 90.96,209.96 v4(90.81,210.11)
APU_TDO: length 61.5
  TOP w0.102: CPU1.H14 80.43,176.3 v3(80.13,176.6) ; HDT1.8 91.09,211.84 v4(90.81,211.56)
  L3 w0.127: v4(92.53,203.2) 92.53,210.12 91.09,211.56 v4(90.81,211.56)
  L4 w0.127: v4(92.53,203.2) 92.02,203.71 89.86,203.71 89.59,203.43 89.59,203.37 88.95,202.73 76.45,202.73 72,198.28 72,193.14 75.09,190.06 75.09,187.65 76.64,186.1 76.64,183.39 77.81,182.22 78.14,182.22 79.88,180.48 79.88,180.13 80.55,179.45 80.55,177.04 80.13,176.62 v3(80.13,176.6)
  BOTTOM w0.102: v4(92.53,203.2) 91.98,203.75 v2(91.98,203.96)
APU_TEST0: length 22.3
  TOP w0.102: v4(58.81,162.69) 57.79,163.7 R1658.2 R1664.2 ; v3(73.8,159.6) 73.8,159.9 CPU1.AH6
  L3 w0.127: v3(73.8,159.6) 73.6,159.6 73.18,160.02 72.33,160.02 72.11,159.8 71.76,159.8 70.94,160.63 68.66,160.63 68.22,161.08 66.29,161.08 65.79,161.58 61.43,161.58 61.37,161.63 59.86,161.63 v4(58.81,162.69)
  BOTTOM w0.102: v4(58.81,162.69) 58.35,163.14 57.02,163.14 v2(56.98,163.1)
APU_TEST1: length 22.5
  TOP w0.102: v3(75.4,158.4) 75.4,158.7 CPU1.AK8 ; v4(59.49,160.78) 59.04,161.24 58.02,161.24 57.44,160.66 R1690.2 R1665.2
  L3 w0.127: v4(59.49,160.78) 60.07,160.21 63.21,160.21 63.31,160.31 67.99,160.31 68.29,160.01 70.16,160.01 70.2,159.97 70.95,159.97 71.57,159.35 72.66,159.35 72.83,159.18 74.62,159.18 v3(75.4,158.4)
  BOTTOM w0.102: v4(59.49,160.78) 58.81,160.1 v2(58.81,159.94)
APU_TEST2: length 12.2
  TOP w0.102: R1666.2 R1691.2 63.28,159.32 63.88,159.32 v1(64.51,159.95) 65.73,161.17 65.73,161.8 66.84,162.9 70.23,162.9 70.23,162.89 70.77,162.89 70.77,162.9 71.03,162.9 71.33,162.6 CPU1.AE3
APU_TEST4: length 1.8
  TOP w0.102: CPU1.P24 v3(88.95,171.55)
  BOTTOM w0.102: v3(88.95,171.55) 89.23,171.83 TP176.1
APU_TEST5: length 2.5
  TOP w0.102: CPU1.N24 89,172.8 v3(89.9,172.8)
  BOTTOM w0.102: v3(89.9,172.8) 89.37,173.33 TP177.1
APU_TEST6: length 3.5
  TOP w0.102: v3(87.92,155.83) 87.92,156.12 CPU1.AN24
  BOTTOM w0.102: v3(87.92,155.83) 88.04,155.7 89.31,155.7 TP178.1
APU_TEST9: length 2.9
  TOP w0.102: CPU1.AB8 75.3,164.6 v3(75.3,164.4)
  BOTTOM w0.102: TP179.1 76.69,165.02 75.73,165.02 75.3,164.6 v3(75.3,164.4)
APU_TEST10: length 1.9
  TOP w0.102: CPU1.Y9 76.5,166 v3(76.06,165.56)
  BOTTOM w0.102: TP180.1 75.55,166.04 76.03,165.56 v3(76.06,165.56)
APU_TEST11: length 6.3
  TOP w0.102: R1607.1 75.22,185.6 75.5,185.32 75.52,185.32 75.9,184.94 75.9,184.92 v1(75.94,184.89) 75.95,184.89 76.39,184.45 76.39,184.43 77.23,183.59 77.23,182.27 77.69,181.81 77.69,181.61 CPU1.B11
APU_TEST14: length 10.3
  TOP w0.102: CPU1.B10 76.9,181.2 76.9,181.23 76.53,181.6 76.47,181.6 73.7,184.37 73.09,184.37 72.91,184.56 70.67,184.56 70.42,184.81 70.42,185.17 71.15,185.9 R1604.1
APU_TEST15: length 10.3
  TOP w0.102: TP181.1 75.85,185.73 76.5,185.08 76.85,185.08 77.25,184.68 77.25,184.33 77.44,184.14 77.44,182.35 77.9,181.89 77.9,181.77 78.27,181.4 78.33,181.4 78.5,181.23 78.5,179.8 CPU1.D11
APU_TEST16: length 6
  TOP w0.102: CPU1.A10 77.2,181.7 77.2,182.02 77.03,182.19 77.03,182.55 74.66,184.92 v1(74.66,185.04) 74.54,185.04 74.2,185.38 R1605.1
APU_TEST17: length 8.2
  TOP w0.102: CPU1.C11 78.2,180.33 77.33,181.2 77.27,181.2 77,181.48 77,181.93 74.15,184.77 73.73,184.77 73.19,185.32 R1606.1
APU_TEST28_H: length 9.4
  TOP w0.102: TP182.1 77,188.34 76.14,187.49 76.14,185.76 76.58,185.32 76.96,185.32 77.46,184.81 77.46,184.4 78.79,183.07 79.2,183.07 79.8,182.48 CPU1.A13
APU_TEST28_L: length 10.3
  TOP w0.102: TP183.1 77.38,187.58 76.7,187.58 76.37,187.25 76.37,185.85 76.55,185.67 76.89,185.67 77.67,184.9 77.67,184.52 78.91,183.28 79.29,183.28 80.1,182.46 80.1,181.72 79.8,181.42 CPU1.B13
APU_TEST31: length 3.1
  TOP w0.102: CPU1.P26 90.3,171.2 v3(90.7,171.6)
  BOTTOM w0.102: TP184.1 90.71,173.22 91.12,172.81 91.12,172.48 90.7,172.06 v3(90.7,171.6)
APU_TEST37: length 11.6
  TOP w0.102: v4(82.96,189.33) 82.11,190.18 R1610.1 R545.1 ; CPU1.A17 82.93,181.97 82.93,182.85 82.36,183.42 82.36,184.1 v3(82.96,184.71)
  L4 w0.127: v3(82.96,184.71) 82.49,185.18 82.49,188.86 v4(82.96,189.33)
  BOTTOM w0.102: v2(83.73,184.53) 83.55,184.71 v3(82.96,184.71)
APU_TEST410: length 3.4
  TOP w0.102: v3(87.92,157.1) 87.92,158.52 CPU1.AK24
  BOTTOM w0.102: TP37.1 v3(87.92,157.1)
APU_TEST411: length 2.6
  TOP w0.102: v3(88.81,157.1) 88.4,157.5 CPU1.AL24
  BOTTOM w0.102: TP175.1 89.7,156.21 v3(88.81,157.1)
APU_TMS: length 60.3
  TOP w0.102: v3(81.33,177.4) 81.63,177.1 CPU1.G15 ; HDT1.4 v4(90.81,209.3)
  L3 w0.127: v4(91.3,196.34) 91.03,196.6 91.03,202.36 91.73,203.05 91.73,208.38 v4(90.81,209.3)
  L4 w0.127: v4(91.3,196.34) 88.17,196.34 86.58,197.93 80.42,197.93 79.7,197.21 79.7,195.94 77.67,193.91 77.67,188.3 79.66,186.31 79.66,185.61 79.95,185.32 79.95,183.64 81.75,181.85 81.75,177.82 v3(81.33,177.4)
  BOTTOM w0.102: RN12.3 96.83,210.79 96.68,210.95 v2(93.61,210.95) 90.84,210.95 90.33,210.44 90.33,209.78 v4(90.81,209.3)
APU_TRST: length 75.4
  TOP w0.102: R1743.2 C1870.2 v4(101.4,211.84) ; CPU1.J14 80.43,175.5 v3(80.13,175.8)
  L3 w0.127: v4(101.4,211.84) 101.8,211.44 101.8,211.39 102.01,211.17 102.01,208.79 96.5,203.28 v4(96.5,201.17)
  L4 w0.127: v3(80.13,175.8) 79.65,176.28 79.65,180.39 78.04,181.99 77.72,181.99 76.39,183.32 76.39,185.99 74.84,187.54 74.84,189.95 71.75,193.04 71.75,198.38 76.35,202.98 88.84,202.98 89.33,203.47 89.33,203.54 89.76,203.96 94.65,203.96 96.5,202.11 v4(96.5,201.17)
  BOTTOM w0.102: RN12.4 99.34,209.96 v2(99.36,209.97) 99.54,209.97 v4(101.4,211.84)
APU_VDD_33_18_SEL: length 23.6
  TOP w0.102: R1614.1 v4(82.96,187.81) ; v4(84.54,195.94) 83.98,195.38 R1616.1 R93.1 ; v1(75,194.61) 75.33,194.61 76.39,193.55 R2025.1 76.49,193.8 R2022.1 78.84,195.07 R1615.1 v4(78.9,195.94)
  L4 w0.127: v4(82.96,187.81) 83.69,188.53 83.69,194.63 84.54,195.48 v4(84.54,195.94)
  BOTTOM w0.102: v4(78.9,195.94) 79.36,195.48 84.08,195.48 v4(84.54,195.94)
APU_VDDIO_AZ: length 22.5
  TOP w0.356: CPU1.AR19 84.2,154.47 84.57,154.1 v3(84.8,154.1)
  TOP w0.508: v4(87.94,141.71) 87.6,141.36 C1639.1 C1638.1 87.26,137.83 87.26,137.78 87.16,137.67 R1595.2 R1601.1
  L3 w0.254: v4(87.94,141.71) 87.97,141.73 87.97,142.44 87.16,143.25 87.16,148.16 86.39,148.92 86.39,150.37 85.49,151.27 85.49,153.48 84.86,154.1 v3(84.8,154.1)
  BOTTOM w0.508: v2(88.55,141.1) v4(87.94,141.71) ; v3(84.8,154.1) 85.49,154.1 C395.1
APU_VRM_PWRGD: length 3.7
  BOTTOM w0.102: PU4601.7 30.39,221.39 30.44,221.44 30.44,222.14 v2(29.93,222.66) 29.82,222.66 29.26,223.22 29.23,223.22 PR4624.2
AUD_BEEP_C: length 5.6
  TOP w0.102: v1(168.16,84.66) 168.02,84.52 C130.2 167.17,84.25 165.04,82.13 164.79,82.13 164.39,81.73 U6.2
AUD_BEEP_R: length 5.9
  TOP w0.102: R207.2 165.55,86.49 R210.1 ; R210.1 166.47,86.11 C130.1 167.48,85.72 167.97,85.72 167.97,85.72 168.88,85.72 v1(169.31,85.29) ; R210.1 R208.2
AUD_DMIC_CLK: length 130.5
  TOP w0.127: v1(161.07,195.83) 160.75,196.15 WEBCM1.4 v4(160.75,199.54) ; v4(158.38,96.88) 158.02,96.88 157.11,95.96 v1(157.11,94.36) 157.11,93.52 156.4,92.81 156.4,91.94 156.12,91.66 C121.2 156.18,84.71 L54.2
  L4 w0.127: v4(160.75,199.54) 162.68,199.54 166.1,196.12 166.1,136.95 166.62,136.43 166.62,111.76 164.94,110.08 164.94,105.62 163.08,103.76 160.81,103.76 160.62,103.57 159.52,103.57 159.12,103.17 159.12,100.93 159.98,100.08 159.98,98.48 v4(158.38,96.88)
AUD_DMIC_CLK_R: length 4
  TOP w0.127: v1(157.02,82.81) 157.02,82.8 157.91,82.8 R212.1 158.62,82.69 160.05,81.26 U6.12
AUD_DMIC_CLK_R_1: length 2.3
  TOP w0.127: R212.2 158.02,84.65 L54.1 157.96,85.79 v1(158.02,85.85)
AUD_DMIC_DATA: length 134.2
  TOP w0.127: R222.1 156.31,81.66 C132.2 155.67,81.6 v1(155.23,82.04) 155.84,82.65 v4(156.17,82.65) ; v4(160.18,200.13) 159.5,199.45 WEBCM1.5 v1(159.5,195.88)
  L4 w0.127: v4(160.18,200.13) 162.45,200.13 166.57,196.01 166.57,136.84 166.87,136.54 166.87,111.65 165.2,109.97 165.2,105.52 162.66,102.98 162.66,100.58 162.44,100.36 162.44,100.09 162.09,99.74 162.09,99.21 161.27,98.4 161.27,97.67 161.27,95.8 159.75,94.28 159.75,90.35 156.56,87.16 156.56,86.47 155.86,85.77 155.86,85.17 156.12,84.92 156.12,82.7 v4(156.17,82.65)
AUD_DMIC_DATA_R: length 3.4
  TOP w0.127: R222.2 158.08,81.09 v1(157.54,80.54) 157.65,80.43 U6.13
AUD_DVDD: length 6.1
  TOP w0.203: U6.7 162.39,83.28
  TOP w0.508: R205.2 R79649.2 158.15,87.44 159.74,87.44 C127.1
  vias: v1(162.31,84.1)
AUD_GP3: length 4.2
  TOP w0.203: U6.3 163.99,81.84 165.59,83.44 v1(165.59,83.57) 165.72,83.57 166.15,84 R213.2
AUD_LINK_BCLK: length 135.9
  TOP w0.102: R79684.1 65.12,137.41 66.07,137.41 v4(66.71,138.05) ; U6.5 163.19,82.13 163.48,82.42 163.48,83.19 163.33,83.34 163.33,84.82 C126.2 163.19,84.9 162.54,85.55 v4(162.54,86.06)
  L3 w0.102: v4(148.85,88.09) 148.85,95.12 148.29,95.68 148.29,100.48 147.81,100.97 147.81,104.49 145.32,106.98 132.34,106.98 118.51,120.82 88.29,120.82 82.11,126.99 80.49,126.99 73.8,133.68 73.8,135.5 71.34,137.95 68.11,137.95 67.82,137.66 67.35,137.66 66.96,138.05 v4(66.71,138.05)
  BOTTOM w0.102: v4(162.54,86.06) 162.54,86.21 160.57,88.19 150.72,88.19 v2(150.72,88.19) 150.71,88.19 148.95,88.19 v4(148.85,88.09)
AUD_LINK_RST_N: length 148.6
  TOP w0.102: v4(70.7,137.19) 70.62,137.19 70.14,137.67 70.14,137.79 69.44,138.49 C61.1 R79682.1 ; U6.6 162.79,82.47 v4(163.02,82.7) ; R314.1 158.78,67.34 158.58,67.55 158.58,68.04 v4(159.04,68.5)
  L3 w0.102: v4(148.85,86.56) 148.01,87.4 148.01,94.84 147.68,95.18 147.68,100.23 147.2,100.71 147.2,104.24 145.06,106.37 132.09,106.37 118.25,120.21 88.03,120.21 81.86,126.38 80.23,126.38 70.7,135.92 v4(70.7,137.19)
  L4 w0.102: v4(163.02,82.7) 160.44,80.11 160.44,73.17 160.72,72.9 160.72,72.19 160.23,71.7 160.23,69.69 v4(159.04,68.5)
  BOTTOM w0.102: v4(148.85,86.56) 149.31,87.02 v2(154.51,87.02) 156.76,87.02 158.84,84.93 158.84,84.78 159.44,84.18 162.36,84.18 163.02,83.52 v4(163.02,82.7)
AUD_LINK_RST_N_2: length 5.5
  TOP w0.254: Q63.4 142.58,29.01 142.27,28.7 v1(142.07,28.7) 141.84,28.7 141.61,28.93 141.61,31.11 141.83,31.33 Q63.6
AUD_LINK_RST_N_R: length 4.7
  TOP w0.102: v1(157.77,66.95) 158.74,65.98 R314.2 158.83,66.03 Q31.B 161.13,64.98 C170.1
AUD_LINK_SDIN: length 150.8
  TOP w0.102: v3(75.45,153.62) 75.7,153.87 CPU1.AR8
  L3 w0.102: v4(67.39,138.86) 68.11,138.86 68.4,138.56 71.6,138.56 74.41,135.75 74.41,133.94 80.74,127.61 82.37,127.61 88.51,121.46 119.02,121.46 132.88,107.6 145.57,107.6 148.42,104.75 148.42,101.22 149.01,100.64 149.01,96.27 149.62,95.66 149.62,85.8 v4(148.85,85.04)
  L4 w0.102: v4(67.39,138.86) 68.61,140.08 68.61,143.89 69.79,145.07 69.79,148.98 68.69,150.09 v3(68.69,150.29)
  BOTTOM w0.102: R209.1 158.23,83.55 158.23,84.48 156.78,85.93 155.15,85.93 155.1,85.88 151.12,85.88 151.01,85.99 v2(150.43,85.99) 149.81,85.99 v4(148.85,85.04) ; v3(75.45,153.62) 75.23,153.62 74.82,153.22 74.3,153.22 73.69,152.61 73.69,152.07 73.03,151.41 71.75,151.41 R79678.2 71.2,151 70.49,150.29 v3(68.69,150.29)
AUD_LINK_SDIN_1: length 5.2
  TOP w0.102: v4(161.86,82.88) 161.99,82.74 U6.8
  BOTTOM w0.102: v2(159.04,82.16) 159.56,82.68 R209.2 159.76,82.91 161.83,82.91 v4(161.86,82.88)
AUD_LINK_SDO: length 134.8
  TOP w0.102: R79685.1 v4(62.72,137.99)
  L3 w0.102: v4(148.85,87.33) 148.34,87.83 148.34,95.02 147.99,95.38 147.99,100.35 147.5,100.84 147.5,104.37 145.19,106.68 132.22,106.68 118.38,120.51 88.16,120.51 81.98,126.69 80.36,126.69 73.49,133.56 73.49,135.37 71.22,137.64 68.74,137.64 68.45,137.35 66.28,137.35 65.64,137.99 v4(62.72,137.99)
  BOTTOM w0.102: v4(148.85,87.33) 149.1,87.58 v2(156.58,87.58) 157.88,87.58 R618.2 158.17,87.29 Q56.D 160.66,87.29 162.35,85.6 163.9,85.6 C1780.2
AUD_LINK_SDO_1: length 5
  BOTTOM w0.102: Q56.G 161.75,85 C1780.1 R617.2 165.83,85 v2(166.1,84.73)
AUD_LINK_SDO_N: length 9.6
  TOP w0.102: U6.4 163.59,82 163.76,82.17 163.76,83.97 v4(163.79,84)
  BOTTOM w0.102: R618.1 159.19,85.38 Q56.S 160.27,85.38 161.17,84.48 162.9,84.48 v2(162.9,84.48) 163.3,84.48 v4(163.79,84)
AUD_LINK_SYNC: length 134.2
  TOP w0.102: v4(67.62,138.12) 67.85,138.35 67.85,139.11 67.58,139.38 R79683.1 ; U6.9 161.59,81.59 161.6,81.59 161.6,82.43 161.4,82.63 161.4,83.49 v4(161.5,83.59)
  L3 w0.102: v4(67.62,138.12) 67.84,138.12 67.98,138.26 71.47,138.26 74.1,135.62 74.1,133.81 80.61,127.3 82.24,127.3 88.41,121.13 118.64,121.13 132.47,107.29 145.45,107.29 148.12,104.62 148.12,101.09 148.6,100.61 148.6,96.01 149.31,95.3 149.31,86.26 v4(148.85,85.8)
  BOTTOM w0.102: v4(148.85,85.8) 149.58,86.53 151.24,86.53 151.36,86.41 v2(152.33,86.41) 152.34,86.41 156.78,86.41 159.59,83.59 v4(161.5,83.59)
AUD_REGREF: length 3.9
  TOP w0.203: v1(160.41,83.44) 161.07,82.78 161.07,82.42 161.19,82.3 U6.10
  TOP w0.508: C129.1 160.15,83.69 v1(160.41,83.44)
AZ_BCLK_M: length 21.8
  TOP w0.102: v4(63.41,142.11) 63.62,141.9 63.62,141.85 v1(65.36,140.11) 65.5,139.97 R79681.2 R79684.2 ; CPU1.AU6 v3(74.1,152.44)
  L3 w0.102: v3(74.1,152.44) 73.44,151.78 73.44,149.94 72.43,148.92 71.62,148.92 71.03,148.34 69.97,148.34 66.69,145.06 66.3,145.06 64.2,142.95 63.98,142.95 63.41,142.38 v4(63.41,142.11)
AZ_RST_N_M: length 23
  TOP w0.102: v4(64.89,142.07) 65.59,141.38 v1(66.5,141.38) 66.56,141.38 67.08,140.85 67.4,140.85 R79682.2 ; v3(77.6,152.6) 77.3,152.6 CPU1.AU9
  L3 w0.102: v4(64.89,142.07) 64.93,142.11 64.93,142.54 65.08,142.69 65.08,142.76 65.81,143.49 65.88,143.49 66.76,144.37 66.76,144.38 70.3,147.92 71.45,147.92 71.85,148.32 72.87,148.32 73.61,149.06 74.22,149.06 74.81,149.65 74.81,150.06 77.35,152.6 v3(77.6,152.6)
AZ_SDIN1: length 4
  TOP w0.102: CPU1.AP6 74.1,155.34 v3(73.72,154.96)
  BOTTOM w0.102: R79679.2 72.17,153.03 72.65,153.51 72.65,153.79 v2(73.22,154.37) 73.72,154.86 v3(73.72,154.96)
AZ_SDIN2: length 4.1
  TOP w0.102: v3(73.05,153.62) 73.05,153.95 CPU1.AR5
  BOTTOM w0.102: v2(72.35,151.99) 71.37,151.99 R79680.2 71.89,152.57 72,152.57 v3(73.05,153.62)
AZ_SDOUT_M: length 23.4
  TOP w0.102: R79685.2 62.95,139.46 62.95,142.52 v4(62.84,142.63) ; v3(74.65,153.62) 74.9,153.87 CPU1.AR7
  L3 w0.102: v3(74.65,153.62) 73.42,152.39 73.42,152.23 73.2,152.01 73.2,149.98 72.46,149.25 71.66,149.25 70.95,148.54 69.88,148.54 66.71,145.36 66.18,145.36 64.07,143.26 63.71,143.26 63.08,142.63 v4(62.84,142.63)
  BOTTOM w0.102: v2(62.22,143.39) 62.24,143.39 62.84,142.79 v4(62.84,142.63)
AZ_SYNC_M: length 24.7
  TOP w0.102: v3(77.6,153.4) 77.3,153.4 CPU1.AT9 ; v4(64.17,142.49) 64.17,141.98 65.18,140.97 65.89,140.97 R79683.2
  L3 w0.102: v4(64.17,142.49) 64.45,142.49 64.77,142.82 64.77,142.89 66.74,144.85 66.77,144.85 70.04,148.12 71.37,148.12 71.77,148.52 72.78,148.52 73.53,149.26 74.14,149.26 74.61,149.73 74.61,150.41 v3(77.6,153.4)
  BOTTOM w0.102: v4(64.17,142.49) 64.03,142.49 63.79,142.73 63.79,143.62 v2(63.39,144.02)
BAT_ALERT: length 4.5
  TOP w0.102: v1(34.27,58.27) 34.27,58.29 34.77,58.79 R79648.2 33.69,60.39 BAT2.8B
BAT_IN#: length 137.6
  TOP w0.102: v4(146.47,38.94) 146.07,38.94 R2014.1 146.21,40.32 R80210.1
  L3 w0.127: v4(146.47,38.94) 146.47,39.22 146.81,39.56 146.81,39.95 146.53,40.22 143.79,40.22 142.41,41.61 142.07,41.61 142.06,41.62 138.48,41.62 137.25,40.39 136.69,40.39 136.04,41.03 127.21,41.03 126.57,41.03 124.82,42.79 110.57,42.79 109.74,43.62 105.48,43.62 v4(104.3,44.81) 101.29,44.81 100.52,45.57 100.15,45.95 96.81,45.95 95.79,46.97 90.24,46.97 86.63,50.58 80.54,50.58 71.91,59.21 v4(69.15,59.21)
  BOTTOM w0.102: RN4301.4 37.34,64.25 40.38,67.28 53.4,67.28 v2(54.01,66.67) 57.31,66.67 58.05,67.41 64.24,67.41 64.8,66.85 65.64,66.85 69.38,63.12 69.38,59.44 v4(69.15,59.21) ; v4(104.3,44.81) 104.3,45.82 103.41,46.71 103.41,49.02 103.67,49.28 U4101.5
BAT_IN#_1: length 6.7
  TOP w0.102: BAT2.6B 33.85,63.39 v4(33.85,63.39) 33.85,62.7 34.2,62.36 PL4301.1 PC4304.1
  BOTTOM w0.102: v4(33.85,63.39) 34.13,63.12 v2(34.63,63.12) 34.73,63.21 RN4301.5
BAT_IN#_ECIO: length 3.9
  TOP w0.102: R80210.2 146.21,41.78 v1(145.58,42.42) 144.85,43.14 U109.98
BATA_SCL_1: length 6.5
  TOP w0.102: BAT2.4B 33.59,66.39 33.85,66.13 v4(33.85,65.76) 34.39,66.29 PL4302.1 PC4305.1
  BOTTOM w0.102: RN4301.7 34.21,65.4 v4(33.85,65.76) 33.64,65.97 33.64,66.38 v2(33.45,66.57)
BATA_SDA_1: length 5.7
  TOP w0.102: PL4303.1 PC4301.1 34.26,64.89 v4(33.85,64.89) 33.85,64.89 BAT2.5B
  BOTTOM w0.102: RN4301.6 33.86,64.9 v4(33.85,64.89) 33.59,64.89 v2(33.16,64.47)
BATT_AMBER_LED#: length 9.1
  BOTTOM w0.203: U4101.9 102.07,48.06 v2(102.01,48.01) 101.89,47.88 101.38,47.88 100.74,48.51 95.98,48.51 R79710.2
BATT_AMBER_LED#_C: length 95
  TOP w0.254: PWRCN1.10 30.39,19.79 30.39,19.25 30.97,18.67 v4(30.97,18.54) 31.27,18.24 v1(31.78,18.24)
  L3 w0.254: v4(35.34,28.47) 35.59,28.22 35.59,27.3 35.57,27.27 35.57,26.77 34.25,25.45 34.25,24.73 33.28,23.77 33.28,20.85 v4(30.97,18.54)
  BOTTOM w0.254: v4(35.34,28.47) 35.47,28.6 37.5,28.6 37.64,28.75 38.86,28.75 41.81,31.7 42.11,31.7 42.43,32.01 42.43,32.45 42.35,32.53 42.35,33.27 42.92,33.83 47.94,33.83 49.72,32.05 55.29,32.05 55.61,32.37 60.28,32.37 60.6,32.05 64.25,32.05 65.17,32.97 65.17,42.44 66.22,43.5 72.22,43.5 73.81,45.09 77.29,45.09 80.6,48.4 80.6,49.01 81.4,49.81 83.22,49.81 v2(84.06,48.97) 84.77,48.26 88.62,48.26 90.08,46.8 92.58,46.8 94.68,48.9 R79710.1 ; R389.2 v4(30.97,18.54)
BATT_WHITE_LED#: length 3.8
  BOTTOM w0.203: R79711.2 108.71,54.23 108.36,53.88 U4101.58
  BOTTOM w0.254: R79711.2 109.38,53.91 v2(109.38,53.21)
BATT_WHITE_LED#_C: length 123.9
  TOP w0.254: PWRCN1.8 30.73,21.25 v4(30.89,21.08) ; v4(110.66,53.64) 109.66,53.64 108.34,52.32 106.71,52.32 104.81,50.42 91.09,50.42 89.87,51.64 82.79,51.64 81.95,50.8 81.69,50.8 v4(80.07,49.17)
  L4 w0.254: v4(30.89,21.08) 30.13,21.08 29.22,22 29.22,24.28 27.72,25.78 27.72,29.97 27.49,30.2 v4(27.47,30.2)
  BOTTOM w0.254: Q38.C 30.2,21.08 v4(30.89,21.08) 31.28,21.08 31.78,20.57 R79726.2 ; R79711.1 110.07,54.23 v4(110.66,53.64) ; v4(80.07,49.17) v2(78.52,47.62) 78.52,46.89 77.12,45.49 73.64,45.49 72.05,43.9 66.06,43.9 64.76,42.61 64.76,33.14 64.08,32.46 60.77,32.46 60.45,32.78 55.44,32.78 55.12,32.46 49.89,32.46 48.11,34.24 42.65,34.24 41.05,32.64 41.05,31.51 38.69,29.15 37.48,29.15 37.33,29.01 34.09,29.01 33.94,28.85 33.28,28.85 31.53,30.61 31.28,30.86 31.28,32 30.64,32.64 27.53,32.64 Q1214.C 27.02,30.65 v4(27.47,30.2)
BIST_DISABLE: length 137.9
  TOP w0.102: U109.112 150.46,45.88 150.4,45.94 150.4,46.48 v4(150.85,46.94) ; v4(49.59,72.31) 47.19,72.31 R531.2 46.45,73.05 R536.1 R533.1
  L3 w0.127: v4(79.15,53.72) 79.37,53.5 81.21,53.5 81.67,53.05 86.67,53.05 90.42,49.3 96.57,49.3 97.72,48.15 101.06,48.15 101.38,47.82 110.35,47.82 110.92,48.39 121.82,48.39 123.08,47.13 130.09,47.13 130.7,46.52 134.31,46.52 135.02,45.81 139.65,45.81 140.58,46.74 144.82,46.74 145.93,47.84 148.12,47.84 148.43,47.54 148.59,47.37 150.42,47.37 v4(150.85,46.94)
  BOTTOM w0.102: v4(79.15,53.72) 79.15,60.3 79.69,60.83 79.69,62.13 80.09,62.53 80.09,63.04 v2(82.08,65.02) 83.22,66.17 83.22,69.72 82.46,70.48 76.06,70.48 74.84,69.27 68.8,69.27 66.28,71.78 50.12,71.78 v4(49.59,72.31)
BIST_DISABLE_1: length 10.2
  TOP w0.254: v4(43.64,73.25) 43.7,73.2 44.37,73.2 R536.2
  L3 w0.254: v4(39.76,77.34) 39.76,76.9 41.94,74.71 41.94,73.95 42.86,73.03 43.42,73.03 v4(43.64,73.25)
  BOTTOM w0.254: v4(39.76,77.34) 39.76,76.78 40.01,76.53 Q12.5 ; v4(43.64,73.25) 44.36,73.25 44.43,73.33 v2(44.56,73.33)
BIST_EN: length 10.6
  BOTTOM w0.254: Q13.2 43.98,75.9 43.96,75.88 Q12.3 42.76,74.96 v2(42.37,74.57) 41.71,75.23 41.71,76.89 41.73,76.9 41.46,77.18 Q12.6 40.88,78.11 41.44,78.66 R524.2
BIST_EN_INV: length 246.2
  TOP w0.102: v4(47.01,77.48) 46.72,77.19 43.91,77.19 43.34,77.76 43.34,78.73 R513.1 43.71,79.25 42.55,79.25 42.32,79.48 42.3,79.48 39.78,81.99 39.78,82.78 34.07,88.49 34.07,90.04 34.07,90.04 34.07,90.42 33.96,90.53 33.96,90.81 33.56,91.21 v4(33.56,91.26) ; R80232.2 164.24,55.02 v4(164.37,54.89)
  L3 w0.127: v4(164.37,54.89) 164.37,46.77 164.16,46.55 164.16,46.16 164.37,45.94 164.37,38.18 164.21,38.01 164.21,37.61 159.01,32.41 145.07,32.41 144.63,31.97 144.12,31.97 143.69,31.53 142.92,31.53 141.18,29.79 130.77,29.79 130.19,30.38 118.2,30.38 116.49,32.08 111.04,32.08 109.53,30.56 101.87,30.56 100.64,31.8 98.93,33.5 93.42,33.5 90.31,30.39 67.74,30.39 65.57,32.56 49.04,32.56 42.92,26.44 v4(41.55,26.44)
  L4 w0.127: v4(41.55,26.44) 41.55,26.45 40.77,27.23 40.77,28.75 40.78,28.97 40.58,29.17 40.58,29.56 40.77,29.75 40.77,30.81 40.14,31.45 40.14,33.86 39.26,34.73 39.26,38.01 39.62,38.37 39.62,40.45 39.26,40.81 39.26,41.11 38.77,41.61 38.77,49.31 37.96,50.12 37.96,51.34 37.64,51.65 37.64,54.15 37.57,54.21 34.83,56.96 34.83,63.86 35.72,64.74 36.23,64.74 39.53,68.05 39.53,68.43 40.56,69.46 40.56,69.47 41.32,70.23 41.95,70.23 45.02,73.29 45.02,73.53 47.01,75.53 v4(47.01,77.48)
  BOTTOM w0.102: U26.2 34.22,92.7 34.02,92.5 34.02,91.72 v4(33.56,91.26) 32.79,91.26 31.97,90.44 R517.2 ; Q13.6 47.2,74.32 46.82,73.94 v2(46.54,73.94) 46.44,73.94 46.21,74.17 46.21,76.24 45.9,76.55 Q13.3 45.86,77.09 46.62,77.09 v4(47.01,77.48)
BIST_EN_SIO: length 7.7
  TOP w0.102: U109.25 159.4,55.98 160.03,56.62 161.08,57.66 R1826.1 161.71,57.66 162.16,58.12 163.23,58.12 v1(163.56,57.78) 164.24,57.1 R80232.1
BIST_ENABLE: length 133
  TOP w0.102: U109.113 v4(150.85,46.13) ; R515.1 49.69,73.09 v4(50.35,72.43)
  L3 w0.127: v4(79.28,52.79) 80.26,52.79 80.72,53.25 81.11,53.25 81.56,52.79 86.56,52.79 90.31,49.04 96.46,49.04 97.61,47.89 100.95,47.89 101.27,47.57 110.46,47.57 111.02,48.13 121.72,48.13 122.97,46.88 129.98,46.88 130.59,46.27 134.2,46.27 134.91,45.55 139.76,45.55 140.69,46.48 145.01,46.48 146.04,47.51 148.09,47.51 148.48,47.12 149.86,47.12 150.36,46.62 v4(150.85,46.13)
  BOTTOM w0.102: v4(50.35,72.43) 50.54,72.43 50.55,72.44 51.19,72.44 51.62,72.01 66.38,72.01 68.89,69.49 74.75,69.49 75.97,70.71 82.55,70.71 83.45,69.82 83.45,65.13 81.06,62.74 81.06,59.18 v2(80.3,58.42) 79.64,57.76 79.64,53.15 v4(79.28,52.79)
BIST_ENABLE_1: length 5.6
  TOP w0.102: R514.2 48.61,73.8 v4(48.67,73.86) 48.84,74.03 R515.2
  BOTTOM w0.102: v4(48.67,73.86) 48.67,74.77 v2(48.64,74.8) 48.67,74.83 48.67,75.96 48.62,76.01 R523.1 48.1,76.01 47.99,75.9 Q13.5
BIST_PIN25: length 200.6
  TOP w0.102: v3(88.04,78.99) 89.73,77.3 89.73,67.83 v1(89.16,67.26) 88.3,66.4 88.3,59.18 86.39,57.28 v3(86.39,56.64) ; R682.2 160.85,56.64 v3(160.64,56.43) 159.79,55.58 U109.24
  L3 w0.127: v3(160.64,56.43) 158.53,54.32 158.53,53.79 157.01,52.27 156.5,52.27 155.74,51.51 155.02,51.51 154.96,51.57 153.67,52.87 150.33,52.87 150.31,52.9 148.8,52.9 148.13,52.22 147.29,52.22 146.67,51.61 141.94,51.61 141.71,51.85 140.8,51.85 139.61,50.66 133.23,50.66 132.75,51.14 121.92,51.14 121.19,51.87 110.97,51.87 110.37,51.27 106.09,51.27 105.29,50.47 99.01,50.47 97.65,51.84 95.36,51.84 94.46,52.73 90.27,52.73 86.39,56.61 v3(86.39,56.64) ; v3(88.04,78.99) 80.81,78.99 78.18,81.62 45.37,81.62 44.48,80.73 43.44,80.73 42.78,81.38 42.78,111.2 v4(43.7,112.12)
  BOTTOM w0.102: Q9650.G 41.91,121.16 43.72,121.16 44.15,120.73 44.15,112.57 v4(43.7,112.12)
BKLT_ADJ: length 4.7
  TOP w0.165: C33.1 44.71,35.45 R79621.2 44.75,35.8 43.98,36.58 v1(43.72,36.58) ; C33.1 45.75,34.46 R133.2 ; C33.1 C87.1
BKLT_EN: length 7.5
  TOP w0.102: v1(41.56,31.37) 41.75,31.18 R79625.2 43.44,31.18 C88.1 44.04,30.58 Q22.C 43.47,28.13 R139.2 R138.2
BKLT_EN1: length 3.2
  TOP w0.102: R135.2 44.89,26.96 v4(44.89,27.1) 45.51,27.72 Q22.B
  BOTTOM w0.102: v2(44.89,27.91) v4(44.89,27.1)
BOARD1: length 8.2
  TOP w0.102: CPU1.BB9 76.6,148.53 76.9,148.23 76.9,146.32 75.57,144.98 v1(75.55,144.98) 75.22,144.65 R1661.2 R1663.1
BOARD2: length 14.8
  TOP w0.102: R1662.2 R152.1 82.14,140.59 v4(81.55,140.59) ; v3(82.58,150.9) 82.56,150.9 82.17,151.3 CPU1.AW15
  L3 w0.127: v3(82.58,150.9) 82.58,149.66 81.39,148.46 81.39,144.83 81.1,144.54 81.1,141.04 v4(81.55,140.59)
  BOTTOM w0.102: v2(82.6,151.68) 82.58,151.66 v3(82.58,150.9)
BOARD3: length 18.7
  TOP w0.102: v4(85,139.57) 85.19,139.76 R1660.1 R1659.2 ; CPU1.AU15 81.82,152.9 82.3,152.43 v3(82.51,152.43)
  L3 w0.127: v3(82.51,152.43) 82.51,151.94 83.23,151.21 83.23,149.52 84.7,148.04 85.13,147.61 85.13,144.79 84.93,144.58 84.93,144.24 84.53,143.84 84.53,140.04 v4(85,139.57)
  BOTTOM w0.102: v2(84.69,140.46) 85,140.16 v4(85,139.57)
BQ24737_CSON_1: length 34.8
  TOP w0.254: 63.56,57.78 63.56,52.1 61.5,50.04 61.5,48.84 v4(61.53,48.82) ; 63.56,57.78 63.56,58.91 59.52,62.95 59.52,64.09 58.66,64.96 54.2,64.96 v4(53.12,63.88) ; 63.56,57.78 v1(63.96,57.78)
  BOTTOM w0.254: PC5236.2 61.5,50.04 PR5277.2 ; PC5236.2 61.53,49.56 v4(61.53,48.82) ; PC5236.2 61.82,49.72 PC5238.1 ; v4(53.12,63.88) 53.37,64.14 53.37,65.09 52.17,66.29 49.39,66.29 PG4908.1
BQ24737_CSOP_1: length 34.9
  TOP w0.254: 55.66,64.58 54.36,64.58 53.98,64.21 v4(53.98,63.88) ; 55.66,64.58 v1(55.66,64.19) ; 55.66,64.58 58.5,64.58 59.14,63.94 59.14,62.79 63.18,58.75 63.18,52.25 61.12,50.2 61.12,49.25 v4(60.66,48.79)
  BOTTOM w0.254: PG4906.1 48.24,66.67 52.33,66.67 53.75,65.25 53.75,64.11 v4(53.98,63.88) ; PR5283.2 60.49,50.04 PC5236.1 60.23,49.23 v4(60.66,48.79)
BQ24737_REGN: length 34.4
  TOP w0.508: PR5297.1 71.53,58.95 70.24,57.66 70.24,54.08 71.04,53.28 v4(71.05,53.28)
  L3 w0.508: v4(71.05,53.28) 70.99,53.23 67.4,53.23 65.51,51.33 54.7,51.33 53.37,52.66 v4(53.37,52.76)
  BOTTOM w0.305: U55.16 58.94,54.92 58.5,54.48 58.12,54.48
  BOTTOM w0.508: 58.12,54.48 57.94,54.48 57.08,53.62 v2(57,53.62) 56.98,53.64 55.77,53.64 PC5233.2 54.24,53.78 PD4401.A 53.37,52.93 v4(53.37,52.76)
BT+:
  vias: v2(34.5,68.45) v7(35.67,68.68) v7(36.38,69.34) v7(50.42,63.63) v7(50.42,62.61) v7(50.42,61.59) v7(51.43,63.63) v7(51.43,62.61) v7(51.43,61.59)
BUFFER1_M4: length 9.8
  TOP w0.102: R526.1 18.31,221.09 v4(18.35,221.13)
  BOTTOM w0.102: Q52.C 16.48,225.11 v2(16.82,225.45) 18.19,225.45 19.13,224.5 19.13,223.32 18.38,222.57 Q51.G 18.38,221.17 v4(18.35,221.13)
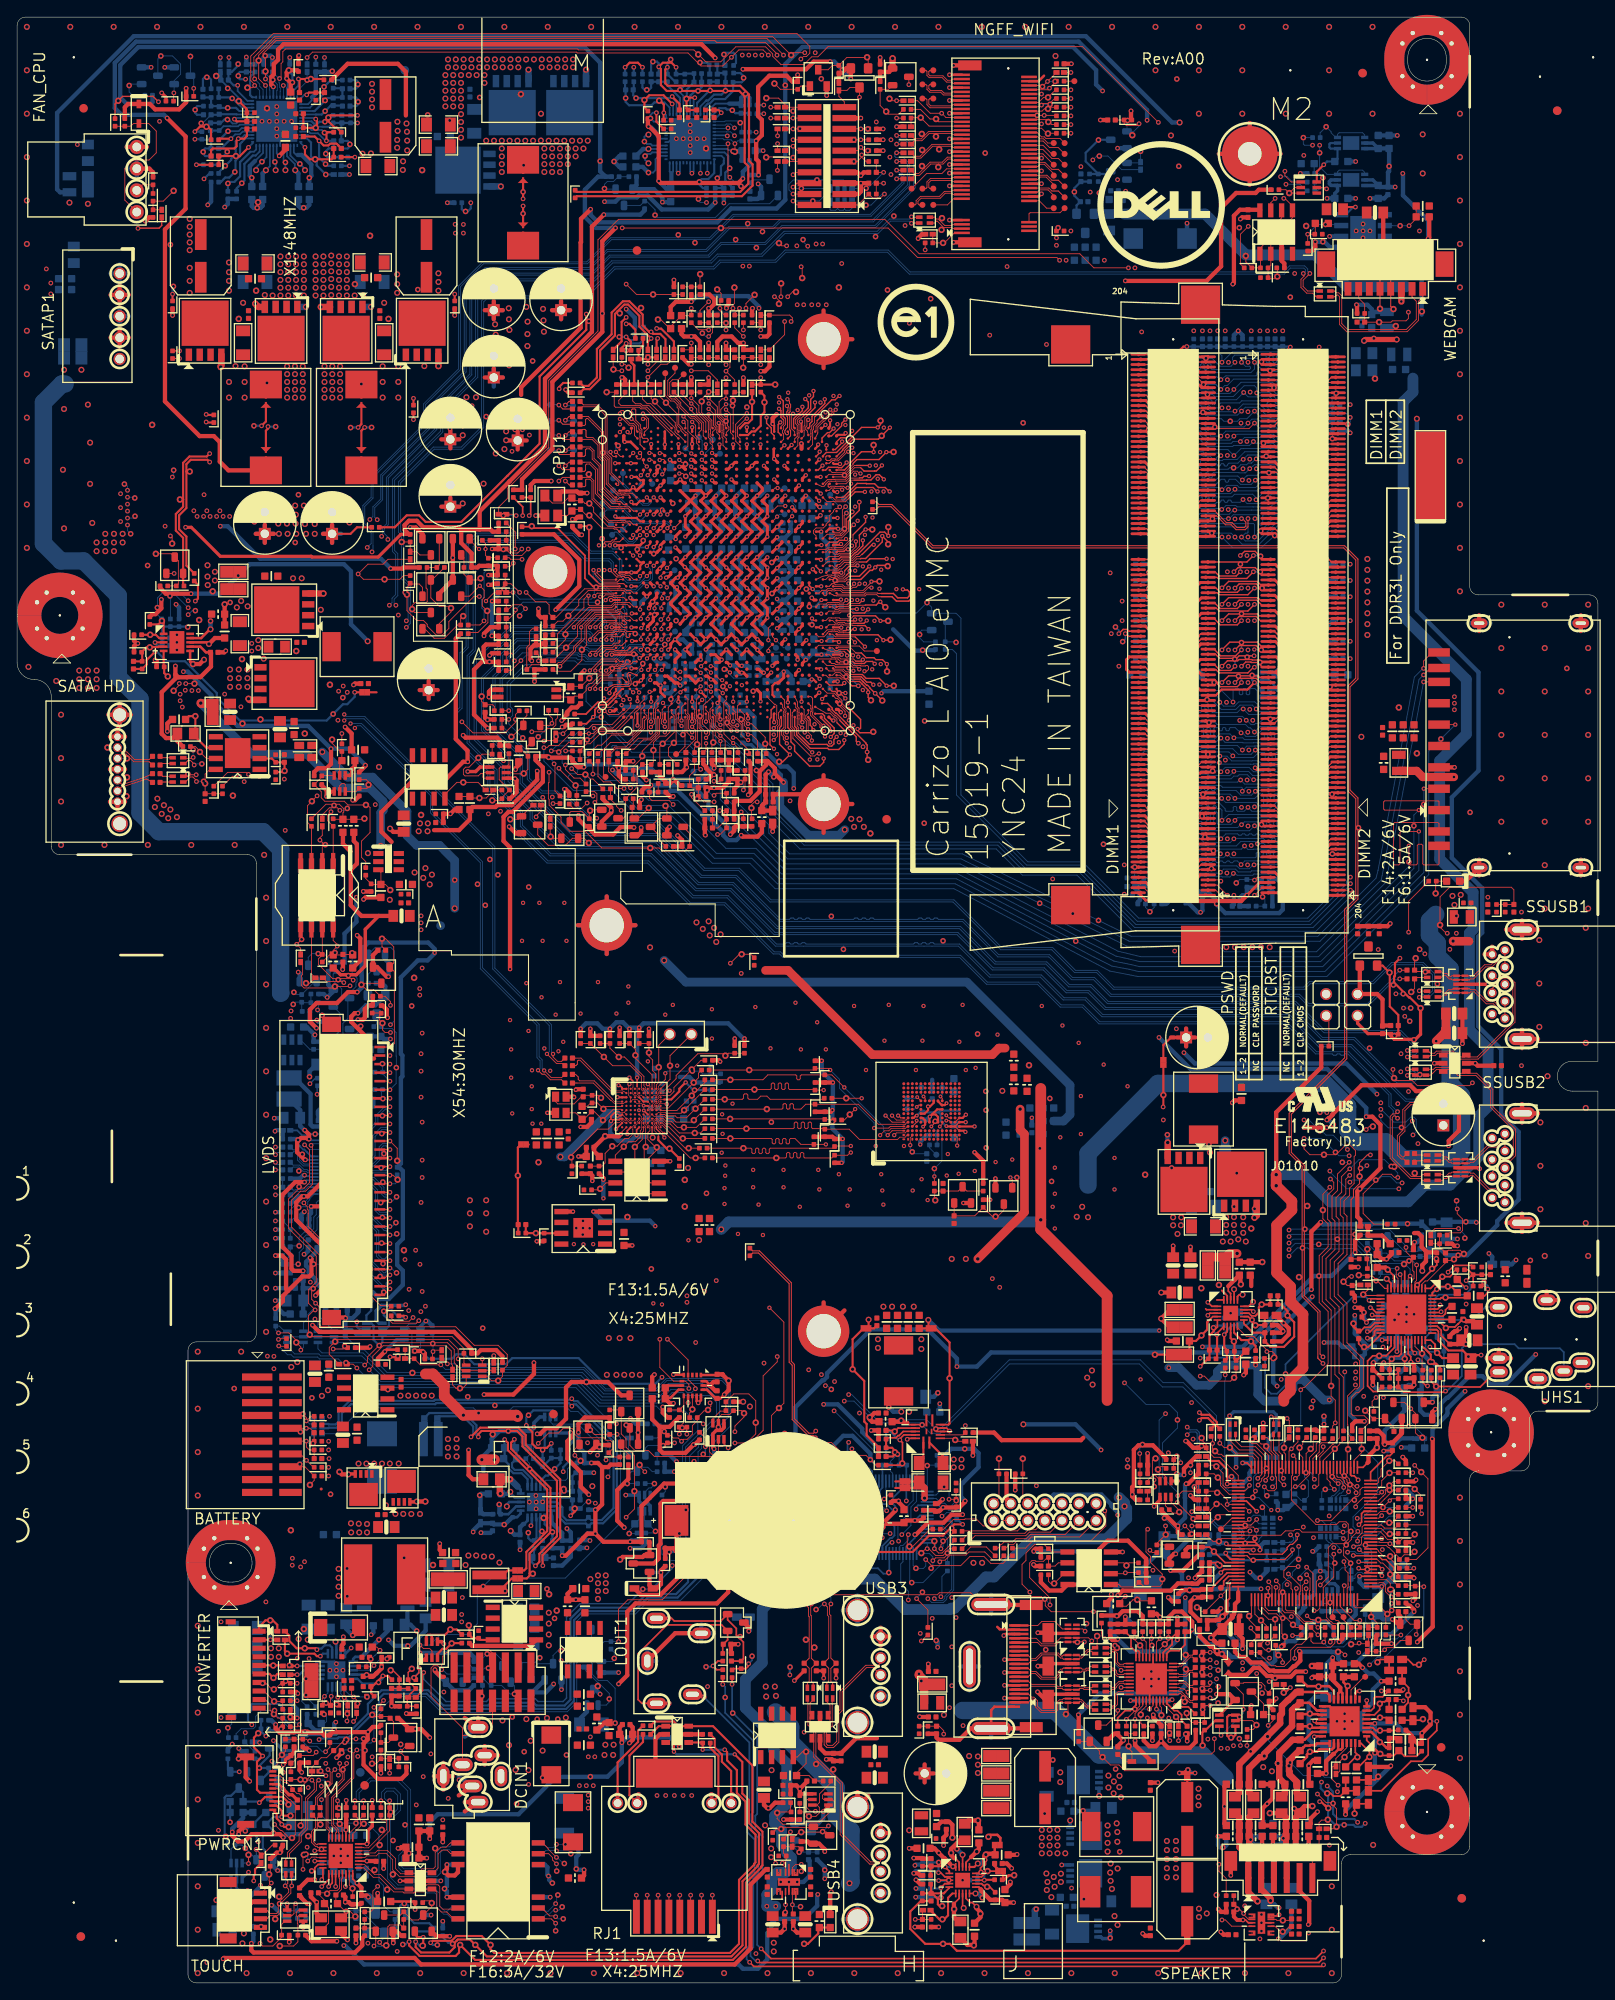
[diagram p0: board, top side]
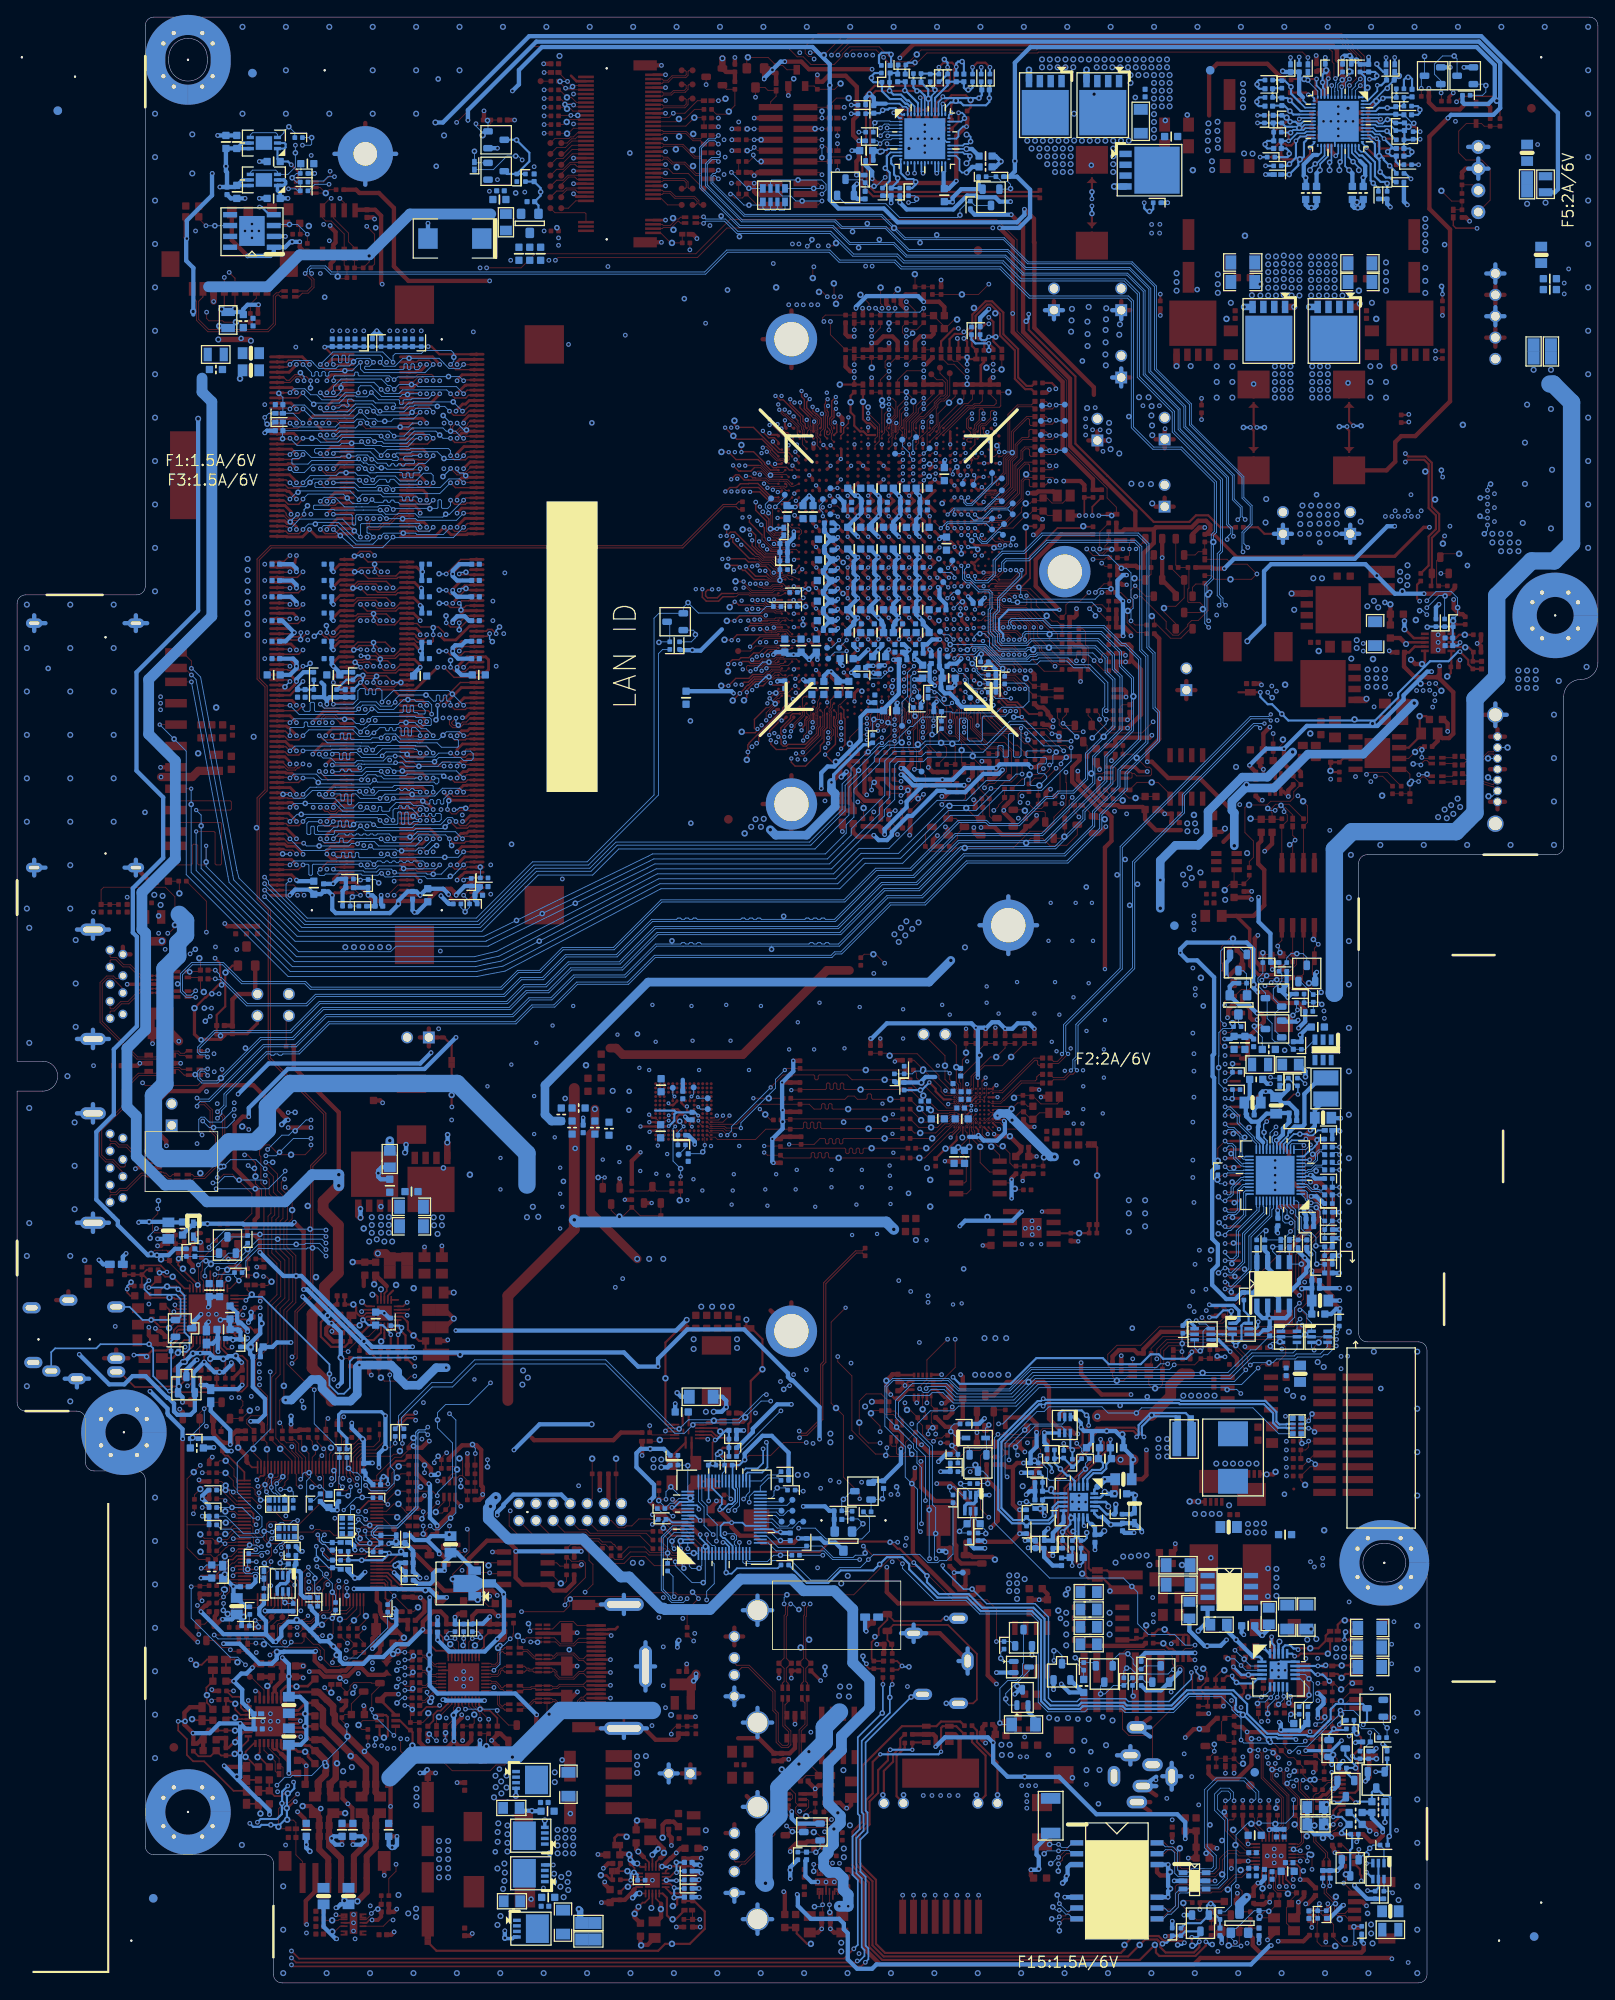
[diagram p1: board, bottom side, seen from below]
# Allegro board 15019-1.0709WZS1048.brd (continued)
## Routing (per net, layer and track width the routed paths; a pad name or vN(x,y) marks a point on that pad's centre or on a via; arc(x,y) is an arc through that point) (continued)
BUZZER_SPKR_R: length 66.5
  TOP w0.102: v4(162.24,33) 162.23,33 162.09,33.15 C203.1 ; v4(168.69,88.27) 165.92,88.27 165.44,87.79 R207.1
  L4 w0.102: v4(162.24,33) 162.24,33.05 161.75,33.53 161.75,36.05 162.01,36.3 162.01,39.98 161.48,40.51 161.48,41.05 161.89,41.47 161.89,45.01 162.54,45.66 162.54,47.76 162.7,47.92 162.7,54.53 162.16,55.07 162.16,58.31 161.42,59.05 161.42,73.12 161.93,73.63 161.93,74.05 161.22,74.76 161.22,79.17 165.49,83.44 165.49,85.06 v4(168.69,88.27)
  BOTTOM w0.102: v2(169.43,87.14) 169.43,87.53 v4(168.69,88.27)
C_GPP_TXN3: length 10.6
  TOP w0.102: C41.1 65.88,176.99 66.01,176.86 66.4,176.86 66.53,176.99 66.53,177.58 66.66,177.71 66.99,177.71 67.7,177 67.7,174.25 69.41,172.53 70.2,172.53 70.25,172.48 70.75,172.48 70.77,172.5 71.03,172.5 71.05,172.48 71.54,172.48 71.7,172.32 CPU1.N3
C_GPP_TXP3: length 10.6
  TOP w0.102: C42.1 67.08,177.93 67.91,177.09 67.91,174.34 69.5,172.75 70.29,172.75 70.34,172.7 70.66,172.7 70.69,172.72 71.11,172.72 71.14,172.7 71.63,172.7 72.13,172.2 CPU1.N4
CAGND: length 7.6
  BOTTOM w0.305: v4(37.37,37.34) 37.13,37.58 U120.15
  BOTTOM w0.508: R82.2 33.94,30.48 C5.2 34.88,29.54 36.99,29.54 37.06,29.61 v2(37.11,29.61) 37.11,30.32 v4(37.29,30.51)
  vias: v4(36.61,36.58) v4(37.37,36.58) v4(37.37,35.81) v4(38.13,36.58)
CBN: length 4.1
  TOP w0.203: C150.2 157.24,76.26 157.68,76.71 158.38,76.71 158.9,77.23 U6.21
  TOP w0.305: v1(156.39,77.15) 156.4,77.15 156.4,76.81 156.94,76.26 C150.2
CBP: length 4.1
  TOP w0.203: C150.1 157.01,74.78 157.39,74.4 v1(157.64,74.4) 158.12,74.4 159.57,75.84 U6.24
CFG: length 7.7
  TOP w0.102: v4(127.29,40.26) 126.96,40.59 126.96,40.82 126.91,40.87 R1594.2 ; U118.23 v4(129.2,36.57)
  BOTTOM w0.102: v4(129.2,36.57) 128.48,37.29 v2(128.48,39.47) 128.07,39.47 v4(127.29,40.26)
CHG_AGND: length 47.2
  TOP w0.508: v4(66.91,57.12) 65.97,58.06 65.97,59.77 64.4,61.34 64.4,63.37 64.78,63.75 v4(64.78,64.39)
  L3 w0.508: v4(60.49,65.02) 62.42,65.02 63.05,64.39 v4(64.78,64.39)
  L4 w0.508: v4(66.68,50.9) 66.63,50.9 66.38,51.16 66.38,52.03 66.94,52.59 66.94,57.1 v4(66.91,57.12)
  BOTTOM w0.406: PQ5006.4 64.73,64.34 v4(64.78,64.39) ; v4(60.49,65.02) 60.49,65.53 61.17,66.22 PQ5006.1
  BOTTOM w0.508: PR4412.2 PC5232.2 ; PC5232.2 66.5,57.53 v4(66.91,57.12) ; PC5232.2 PC5239.2 ; PC4403.2 59.19,63.27 59.19,64.39 59.01,64.57 ; v4(60.49,65.02) 60.49,64.93 60.12,64.57 59.01,64.57 ; v4(66.68,50.9) 65.86,50.9 PR5274.2 PR5268.2 64.8,49.83 63.8,48.83 PC5238.2 ; 59.01,64.57 v2(57.49,64.57) 56.45,64.57 55.53,63.65 PC4404.2 54.57,61.65 PC4408.2 ; v4(64.78,64.39) 64.78,63.22 64.49,62.93 PR5468.2
CHG_ON#: length 115
  TOP w0.102: R80207.1 150.21,40.64 v4(149.26,40.64) ; v4(71.28,54.48) 72.25,55.45 v1(72.25,57.53) 72.25,61.69 71.26,62.68 71.26,63.68 70.7,64.23 PQ5003.G 70.5,67.04 PR5273.2
  L3 w0.127: v4(149.26,40.64) 149.09,40.47 148.67,40.47 146.66,38.47 146.16,38.47 146.03,38.61 144.69,38.61 142.2,41.1 138.68,41.1 137.24,39.66 127.22,39.66 126.82,40.06 126.82,40.07 124.61,42.28 108.14,42.28 107.3,43.12 102.26,43.12 99.94,45.44 96.6,45.44 95.58,46.46 90.03,46.46 87.19,49.31 86.62,49.31 v4(86.39,49.53) 85.85,50.07 80.33,50.07 75.92,54.48 v4(71.28,54.48)
  BOTTOM w0.102: U4101.17 97.11,51.48 96.17,50.55 90.57,50.55 89.56,49.53 v4(86.39,49.53)
CHG_ON#_ECIO: length 6.1
  TOP w0.102: U109.101 146.06,43.97 146.46,43.56 147.67,43.56 v1(149.32,41.91) 149.64,41.59 R80207.2
CHG_SMB2_CLK: length 148.1
  TOP w0.254: v4(138.36,65.84) 138.62,66.09 139.37,66.09 140.04,65.43 140.04,65.14 R715.1
  L3 w0.254: v4(138.36,65.84) 138.12,66.08 136.05,66.08 135.5,65.53 120.3,65.53 117.9,63.13 108.73,63.13 107.83,62.23 105.85,62.23 97.95,62.23 v4(97.7,62.48) 97.06,62.48 96.43,63.12 96.43,64.92 95.92,65.43 90.9,65.43 85.85,70.48 77.85,70.48 77.21,69.85 64.45,69.85 64.07,69.47 64.07,68.46 64.26,68.26 64.82,68.26 v4(64.91,68.35)
  BOTTOM w0.203: v4(97.7,62.48) 97.7,60.83 98.33,60.2 99.73,60.2 100.07,59.86 U4101.35
  BOTTOM w0.254: v2(52.74,68.58) 52.74,68.22 ; 52.74,68.22 64.78,68.22 v4(64.91,68.35) 65.19,68.07 65.57,68.07 70.19,63.46 70.19,55.39 68.57,53.77 67.22,53.77 66.9,53.45 PR4425.2 66.57,53.75 64.17,53.75 63.43,54.48 63.43,55.47 63.13,55.78 62.62,55.78 62.6,55.76 U55.9 ; 52.74,68.22 48.9,68.22 48.77,68.1 38.92,68.1 37.63,66.8 37.63,65.68 37.28,65.34 36.46,65.34 36.4,65.4 RN4301.2
CHG_SMB2_DATA: length 149.8
  TOP w0.254: v4(138.36,66.73) 138.62,66.47 139.53,66.47 140.42,65.59 140.42,65.17 R716.1
  L3 w0.254: v4(64.92,67.48) 64.52,67.88 64.1,67.88 63.69,68.3 63.69,69.63 64.29,70.23 77.05,70.23 77.69,70.87 86.01,70.87 87.66,69.21 91.06,65.81 96.08,65.81 96.81,65.08 96.81,63.63 97.19,63.25 v4(97.32,63.25) 97.82,63.25 98.46,62.61 105.69,62.61 107.67,62.61 108.57,63.51 117.74,63.51 120.14,65.91 135.34,65.91 135.89,66.46 138.09,66.46 v4(138.36,66.73)
  BOTTOM w0.203: v4(97.32,63.25) 97.19,63.12 97.19,60.33 97.8,59.72 99.52,59.72 99.67,59.56 U4101.34
  BOTTOM w0.254: U55.8 63.18,56.26 63.81,55.63 63.81,54.64 64.33,54.13 66.52,54.13 PR4426.2 67.18,54.15 68.41,54.15 69.81,55.55 69.81,63.3 65.41,67.69 65.13,67.69 v4(64.92,67.48) 64.56,67.84 55.91,67.84 ; RN4301.3 36.4,64.9 36.46,64.96 37.44,64.96 38.01,65.53 38.01,66.64 39.08,67.72 48.93,67.72 49.06,67.84 55.91,67.84 ; 55.91,67.84 v2(55.91,67.56)
CK_48M_SIO: length 188
  TOP w0.102: R310.2 158.12,65.44 158.12,65.9 157.66,66.35 156.35,66.35 156.13,66.58 156.13,68.47 156.72,69.06 157,69.06 157.55,69.61 157.55,72.98 155.63,74.9 155.63,79.48 154.59,80.52 154.59,84.18 155.63,85.22 155.63,89.7 155.29,90.05 155.29,91.49 155.94,92.13 155.94,93 156.47,93.53 156.47,96.69 156.62,96.84 156.62,97.38 155.96,98.04 155.48,98.04 154.34,96.9 v1(152.94,96.9) 151.29,96.9 150.61,97.58 v4(150.61,98.04)
  L4 w0.127: v4(156.04,127.09) 156.04,125.93 154.87,124.76 154.87,120.68 151.52,117.34 151.52,107.64 150.28,106.4 150.28,102.24 149.74,101.7 149.74,98.92 v4(150.61,98.04)
  BOTTOM w0.102: 76.82,148.73 76.8,148.72 75.66,148.72 75.53,148.59 70.42,148.59 69.76,149.25 67.27,149.25 66.58,149.94 66.58,151.53 66.59,151.54 66.77,151.72 66.78,151.73 67.13,152.08 69.33,152.08 R2067.2 ; 76.82,148.73 C1733.2 ; 76.82,148.73 R1645.1 76.91,147.64 77.38,148.11 79.07,148.11 80.16,147.01 80.49,147.01 81.77,145.73 81.77,145.26 82.19,144.83 83.17,144.83 83.55,144.45 83.63,144.45 84.68,143.4 84.68,142.89 87.65,139.93 87.65,136.64 91.62,132.67 114.59,132.67 117.64,129.62 124.02,129.62 130.61,123.03 151.99,123.03 v4(156.04,127.09)
CK_GLAN_DN: length 246.4
  TOP w0.102: v3(69.36,168.2) 69.77,168.61 70.51,168.61 CPU1.U2 ; v4(37.75,25.68) 37.75,24.8 38.06,24.5 38.06,23.87 36.16,21.98 36.16,18.14 36.57,17.73 36.57,17.63 36.48,17.53 U16.16
  L3 w0.127: v4(22.59,171.58) 22.83,171.82 22.83,172.4 23.46,173.03 25.7,173.03 26.85,171.87 26.85,170.18 28.51,168.52 38.44,168.52 38.79,168.88 41.95,168.88 42.41,168.41 46.89,168.41 48.59,170.11 53.59,170.11 62.18,178.7 64.28,178.7 65.26,177.73 65.26,173.1 69.36,169 v3(69.36,168.2)
  L4 w0.127: v4(22.59,171.58) 22.59,170.16 26.41,166.34 34.92,166.34 40.59,160.67 40.59,159.29 44.96,154.92 44.96,123.86 41.89,120.8 41.89,78.28 39.71,76.09 39.71,74.07 31.18,65.54 31.18,57.02 35.1,53.1 35.1,50.6 35.4,50.3 35.4,44.46 34.77,43.82 34.77,39.76 33.32,38.32 33.32,32.3 37.87,27.75 37.87,25.8 v4(37.75,25.68)
  BOTTOM w0.102: v3(69.36,168.2) 69.36,168.11 69.71,167.77 70.54,167.77 v2(70.68,167.91)
CK_GLAN_DP: length 245.8
  TOP w0.102: v3(68.72,168.2) 68.72,168.51 68.82,168.61 69.46,168.61 69.68,168.82 69.92,168.82 CPU1.U1 ; v4(38.56,25.68) 38.56,25.48 38.39,25.3 38.09,25.3 37.97,25.17 37.97,24.89 38.27,24.59 38.27,23.78 36.38,21.89 36.38,18.23 36.79,17.82 36.79,17.63 36.88,17.53 U16.15
  L3 w0.127: v3(68.72,168.2) 69.09,168.57 69.09,168.89 64.99,172.99 64.99,177.61 64.17,178.44 62.29,178.44 53.7,169.85 48.7,169.85 47,168.15 42.3,168.15 41.84,168.61 38.9,168.61 38.55,168.25 28.4,168.25 26.58,170.07 26.58,171.76 25.59,172.76 23.57,172.76 23.1,172.29 23.1,171.83 v4(23.35,171.58)
  L4 w0.127: v4(38.56,25.68) 38.14,26.11 38.14,27.86 33.59,32.41 33.59,38.21 35.03,39.65 35.03,43.71 35.67,44.35 35.67,50.41 35.37,50.71 35.37,53.21 31.45,57.13 31.45,65.43 39.97,73.96 39.97,75.98 42.16,78.17 42.16,120.69 45.22,123.75 45.22,155.03 40.86,159.4 40.86,160.78 35.03,166.6 26.53,166.6 26.24,166.88 22.85,170.27 22.85,171.08 v4(23.35,171.58)
  BOTTOM w0.102: v3(68.72,168.2) 68.72,168.72 v2(68.46,168.99)
CK_M_DDR0_A_DN: length 65.9
  TOP w0.102: CPU1.AE32 95.68,162.3 95.91,162.3 95.93,162.28 99.24,162.28 99.37,162.42 100.6,162.42 100.84,162.18 101.13,162.18
  TOP w0.178: v4(129.7,157.86) 130.01,157.55 DIMM1.103 ; 101.13,162.18 102.39,162.18 102.9,161.67 104.35,161.67 104.81,162.13 v3(104.81,163.07)
  L3 w0.178: v4(129.7,157.86) 129.2,158.36 128.9,158.36 128.01,159.25 127.25,159.25 126.63,158.62 126.22,158.62 125.59,159.25 124.86,159.25 124.41,158.8 123.97,158.8 123.52,159.25 122.82,159.25 122.37,158.8 121.94,158.8 121.49,159.25 120.79,159.25 120.34,158.8 117.81,158.8 117.64,158.98 117.64,159.97 117.21,160.4 116.67,160.4 116.31,160.04 116.31,158.98 116.14,158.8 115.65,158.8 115.48,158.98 115.48,161.87 115.12,162.23 114.51,162.23 114.16,161.87 114.16,159 113.95,158.8 113.25,158.8 113.07,158.98 113.07,160.98 112.72,161.34 112.11,161.34 111.75,160.98 111.75,158.98 111.58,158.8 111.22,158.8 111.04,158.98 111.04,160.98 110.69,161.34 110.08,161.34 109.72,160.98 109.72,158.98 109.54,158.8 108.69,158.8 108.09,159.4 108.09,159.65 108.82,160.38 108.82,160.89 108.43,161.28 107.92,161.28 107.19,160.55 106.94,160.55 106.73,160.77 106.73,161.02 107.58,161.87 107.58,162.38 107.19,162.77 106.69,162.77 105.83,161.91 105.58,161.91 104.81,162.69 v3(104.81,163.07)
  BOTTOM w0.178: v4(129.7,157.86) 129.7,157.24 129.39,156.93 v2(129.38,156.93)
CK_M_DDR0_A_DP: length 65.9
  TOP w0.102: 101.13,162.56 100.75,162.56 100.69,162.62 99.29,162.62 99.15,162.48 96.02,162.48 CPU1.AE33
  TOP w0.178: DIMM1.101 130.11,158.15 129.91,158.36 129.43,158.36 v4(128.94,157.86) ; v3(103.67,163.04) 103.74,162.97 104.2,162.97 104.43,162.74 104.43,162.29 104.19,162.05 103.06,162.05 102.55,162.56 101.13,162.56
  L3 w0.178: v3(103.67,163.04) 104.02,163.04 105.45,161.61 105.96,161.61 106.81,162.46 107.06,162.46 107.28,162.25 107.28,162 106.42,161.14 106.42,160.64 106.82,160.25 107.32,160.25 108.05,160.97 108.3,160.97 108.51,160.76 108.51,160.51 107.79,159.78 107.79,159.28 108.57,158.5 109.67,158.5 110.03,158.85 110.03,160.86 110.2,161.04 110.56,161.04 110.74,160.86 110.74,158.85 111.09,158.5 111.7,158.5 112.06,158.85 112.06,160.86 112.24,161.04 112.59,161.04 112.77,160.86 112.77,158.85 113.13,158.5 114.08,158.5 114.46,158.88 114.46,161.75 114.64,161.93 114.99,161.93 115.17,161.75 115.17,158.85 115.53,158.5 116.26,158.5 116.62,158.85 116.62,159.92 116.8,160.1 117.08,160.1 117.33,159.85 117.33,158.85 117.69,158.5 120.47,158.5 120.92,158.95 121.36,158.95 121.81,158.5 122.5,158.5 122.95,158.95 123.39,158.95 123.84,158.5 124.53,158.5 124.98,158.95 125.47,158.95 126.09,158.32 126.75,158.32 127.38,158.95 127.88,158.95 128.94,157.89 v4(128.94,157.86)
  BOTTOM w0.178: v4(128.94,157.86) 128.94,158.25 v2(128.54,158.65)
CK_M_DDR0_B_DN: length 65.4
  TOP w0.102: CPU1.AD33 95.66,163.4 95.69,163.37 96.53,163.37 96.78,163.12 97.65,163.12 97.83,163.3 98.18,163.3 v3(98.59,163.7)
  TOP w0.178: DIMM2.103 147.19,157.55 147.62,157.11 148.41,157.11 148.79,157.49 149.02,157.49 v4(149.51,157.99)
  L3 w0.178: v4(149.51,157.99) 148.71,157.19 147.66,157.19 147.28,157.57 139.53,157.57 138.74,158.36 137.72,158.36 136.44,159.64 131.13,159.64 129.9,160.87 121.51,160.87 120.51,161.87 120.26,161.87 120.08,161.69 119.58,161.69 119.14,162.12 119.14,162.62 119.33,162.8 119.33,163.05 119.07,163.31 118.82,163.31 118.64,163.12 118.14,163.12 117.71,163.56 117.71,164.06 117.89,164.24 117.89,164.49 117.36,165.02 116.7,165.02 116.2,164.52 115.53,164.52 115.02,165.02 103.36,165.02 102.9,164.57 99.45,164.57 v3(98.59,163.7)
  BOTTOM w0.178: v2(150.22,157.56) 150.15,157.56 149.72,157.99 v4(149.51,157.99)
CK_M_DDR0_B_DP: length 65
  TOP w0.102: v3(97.95,163.7) 97.57,163.32 96.86,163.32 96.61,163.57 95.77,163.57 95.64,163.7 95.36,163.7 95.05,163.4 CPU1.AD32
  TOP w0.178: DIMM2.101 147.13,158.15 147.78,157.49 148.25,157.49 v4(148.75,157.99)
  L3 w0.178: v3(97.95,163.7) 97.95,164.08 98.14,164.27 98.73,164.27 99.32,164.87 102.78,164.87 103.23,165.33 115.15,165.33 115.66,164.82 116.07,164.82 116.57,165.33 117.49,165.33 118.19,164.62 118.19,164.11 118.01,163.93 118.01,163.68 118.26,163.43 118.51,163.43 118.7,163.61 119.2,163.61 119.63,163.18 119.63,162.68 119.45,162.49 119.45,162.24 119.7,161.99 119.95,161.99 120.13,162.17 120.64,162.17 121.64,161.18 130.02,161.18 131.25,159.94 136.57,159.94 137.85,158.66 138.87,158.66 139.65,157.87 147.4,157.87 147.78,157.49 148.59,157.49 148.75,157.66 v4(148.75,157.99)
  BOTTOM w0.178: v2(148.8,158.8) 148.75,158.75 v4(148.75,157.99)
CK_M_DDR1_A_DN: length 65.5
  TOP w0.102: CPU1.AE31 94.39,162.51 94.39,162.41 94.5,162.31 94.65,162.31 94.76,162.42 94.76,162.74 94.94,162.92 95.24,162.92 95.3,162.86 95.7,162.86 95.77,162.94 96.32,162.94 96.58,162.69 99.07,162.69 99.63,163.25 v3(99.98,163.25)
  TOP w0.178: DIMM1.104 138.58,157.25 138.19,156.86 136.44,156.86 136.3,157 v4(136.3,157.73)
  L3 w0.178: v4(136.3,157.73) 136.3,158.06 136.04,158.33 131.07,158.33 129.5,159.91 118.63,159.91 117.97,160.57 117.97,161.08 118.29,161.4 118.29,161.58 117.97,161.9 117.79,161.9 117.13,161.24 116.69,161.24 116.19,161.74 116.19,162.18 116.86,162.85 116.86,163.03 116.54,163.35 116.36,163.35 116.03,163.02 115.52,163.02 114.48,164.06 113.82,164.06 113.65,163.88 113.65,162.36 113.29,162 112.68,162 112.32,162.36 112.32,163.88 112.15,164.06 111.79,164.06 111.61,163.88 111.61,162.36 111.26,162 110.65,162 110.29,162.36 110.29,163.88 110.11,164.06 109.76,164.06 109.58,163.88 109.58,162.36 109.23,162 108.62,162 108.26,162.36 108.26,163.88 108.08,164.06 107.35,164.06 106.82,163.53 106.21,163.53 105.68,164.06 103.75,164.06 103.3,163.6 100.34,163.6 v3(99.98,163.25)
  BOTTOM w0.178: v4(136.3,157.73) v2(136.3,158.57)
CK_M_DDR1_A_DP: length 65.8
  TOP w0.102: CPU1.AE30 93.85,162.6 94.19,162.94 94.67,162.94 94.86,163.13 95.33,163.13 95.39,163.07 95.61,163.07 95.69,163.14 96.41,163.14 96.66,162.89 98.98,162.89 99.98,163.89 v3(99.98,163.96)
  TOP w0.178: DIMM1.102 138.52,157.85 138.32,157.66 138.32,157.53 138.03,157.24 137.34,157.24 137.07,157.51 v4(137.07,157.73) ; v1(100.92,163.98) 100.9,163.96 v3(99.98,163.96)
  L3 w0.178: v3(99.98,163.96) 100.03,163.91 103.17,163.91 103.63,164.36 105.81,164.36 106.34,163.83 106.69,163.83 107.23,164.36 108.21,164.36 108.57,164.01 108.57,162.48 108.74,162.31 109.1,162.31 109.28,162.48 109.28,164.01 109.63,164.36 110.24,164.36 110.6,164.01 110.6,162.48 110.77,162.31 111.13,162.31 111.31,162.48 111.31,164.01 111.66,164.36 112.27,164.36 112.63,164.01 112.63,162.48 112.81,162.31 113.16,162.31 113.34,162.48 113.34,164.01 113.7,164.36 114.61,164.36 115.65,163.32 115.9,163.32 116.23,163.65 116.67,163.65 117.17,163.15 117.17,162.72 116.5,162.05 116.5,161.87 116.82,161.55 117,161.55 117.66,162.2 118.09,162.2 118.59,161.7 118.59,161.27 118.27,160.95 118.27,160.7 118.76,160.21 129.62,160.21 131.2,158.64 136.16,158.64 v4(137.07,157.73)
CK_M_DDR1_B_DN: length 66.4
  TOP w0.102: CPU1.AC32 95.45,164.2 95.76,163.9 96.04,163.9 96.07,163.93 96.88,163.93 97.11,164.16 97.48,164.16 97.52,164.2
  TOP w0.178: DIMM2.104 153.06,157.25 152.92,157.11 151.91,157.11 v4(151.04,157.99) ; v1(101.89,165.76) 101.8,165.85 100.67,165.85 100.43,165.61 v3(100.43,165.61) 100.08,165.27 99.8,165.27 98.73,164.2 97.52,164.2
  L3 w0.178: v3(100.43,165.61) 100.63,165.81 102.78,165.81 102.96,165.98 117.84,165.98 121.65,162.18 122.65,162.18 123,161.83 123.75,161.83 124.1,162.18 124.58,162.18 124.92,161.83 125.68,161.83 126.02,162.18 129.95,162.18 131.53,160.6 136.84,160.6 137.32,160.12 137.47,159.97 137.56,159.88 138.58,159.88 139.93,158.53 150.49,158.53 v4(151.04,157.99)
CK_M_DDR1_B_DP: length 65.2
  TOP w0.102: 97.33,164.58 97.11,164.36 97.03,164.36 96.8,164.13 96.07,164.13 96,164.2 CPU1.AC33
  TOP w0.178: v3(99.73,165.74) 98.57,164.58 97.33,164.58 ; v4(151.8,157.99) 151.8,157.76 152.07,157.49 152.77,157.49 153.12,157.85 DIMM2.102
  L3 w0.178: v4(151.8,157.99) 151.8,158.42 151.63,158.58 150.87,158.58 150.62,158.84 140.05,158.84 138.7,160.19 137.75,160.19 137.69,160.19 137.54,160.34 136.97,160.91 131.65,160.91 130.08,162.48 125.89,162.48 125.55,162.14 125.05,162.14 124.7,162.48 123.97,162.48 123.62,162.14 123.12,162.14 122.78,162.48 121.78,162.48 117.97,166.29 102.83,166.29 102.66,166.12 100.11,166.12 v3(99.73,165.74)
  BOTTOM w0.178: v4(151.8,157.99) 151.8,157.2 v2(151.82,157.18)
CK_P_33M_EC: length 15.5
  TOP w0.102: R79699.1 116.27,49.97 115.38,49.09 113.95,49.09 113.15,49.89 111.49,49.89 110.43,48.82 107.04,48.82 v4(106.33,49.53)
  BOTTOM w0.102: U4101.2 104.87,48.84 v2(105.19,48.51) 105.23,48.48 106.04,48.48 106.33,48.77 v4(106.33,49.53)
CK_P_33M_SIO: length 185.2
  TOP w0.102: v4(127.29,55.23) 127.41,55.11 127.41,53.47 125.69,51.74 118.88,51.74 118.01,50.86 R79699.2 ; v4(151.82,58.04) 152.13,58.04 152.33,58.24 152.33,59.51 152.45,59.63 U109.44 152.45,61.49 153.65,62.69 153.65,62.72 153.98,63.04 154.07,63.04 154.41,63.39 154.41,63.45 154.72,63.75 154.72,70.68 154.22,71.17 154.22,78.89 153.18,79.93 153.18,84.76 154.22,85.8 154.22,89.12 153.88,89.46 153.88,92.07 154.53,92.72 154.53,94.64 v4(155.9,96.01) ; v4(81.97,134.37) 82.27,134.37 R1877.2 R1868.2 82.01,135.13 C1734.1 R1867.1 R1646.1
  L3 w0.127: v4(151.82,58.04) 151.34,57.56 150.97,57.56 150.51,57.11 145.8,57.11 145.35,56.66 141.63,56.66 140.79,55.82 139.73,55.82 139.51,55.6 137.28,55.6 136.62,54.95 133.41,54.95 133.15,55.21 129.37,55.21 129.25,55.33 127.38,55.33 v4(127.29,55.23) ; v4(155.9,96.01) 156.71,96.82 156.71,103 151.08,108.63 151.08,111.22 148.05,114.24 133.16,114.24 121.12,126.29 120.15,126.29 118.1,128.34 91.51,128.34 88.28,131.57 86.72,131.57 85.3,133 83.17,133 81.97,134.2 v4(81.97,134.37)
  BOTTOM w0.102: v2(155.09,96.01) v4(155.9,96.01)
CK_PCIEX1_WLAN_DN: length 141.5
  TOP w0.102: CPU1.W3 v3(72.1,167) ; v4(102.93,216.15) R23.2
  L3 w0.127: v4(43.39,168.88) 43.37,168.91 43.37,169.3 43.49,169.42 47.33,169.42 48.43,170.52 53.42,170.52 62.65,179.74 64.36,179.74 65.78,178.32 65.78,176.95 67.19,175.54 67.19,172.57 72.37,167.39 72.37,167.27 v3(72.1,167)
  BOTTOM w0.102: v4(102.93,216.15) 103.33,215.75 104.12,215.75 105.11,214.76 105.11,210.02 100.48,205.38 89.58,205.38 87.59,203.39 86.52,203.39 ; v2(86.52,203.02) 86.52,203.39 ; 86.52,203.39 82.44,203.39 80.98,201.93 69.4,201.93 67.29,199.82 55.13,199.82 53.21,197.9 53.21,188.15 49.12,184.06 49.12,181.74 43.44,176.07 43.44,170.61 42.96,170.13 42.96,169.6 43.39,169.16 v4(43.39,168.88)
CK_PCIEX1_WLAN_DP: length 141.5
  TOP w0.102: v4(102.93,215.14) R22.2 ; CPU1.W4 v3(72.9,167)
  L3 w0.127: v4(42.66,169.25) 42.94,169.25 43.38,169.69 47.22,169.69 48.32,170.78 53.31,170.78 60.15,177.62 62.54,180.01 64.47,180.01 66.05,178.43 66.05,177.06 67.46,175.65 67.46,172.68 72.63,167.5 72.63,167.27 v3(72.9,167)
  BOTTOM w0.102: 84.09,203.61 82.35,203.61 80.89,202.15 69.31,202.15 67.21,200.04 55.04,200.04 52.99,197.99 52.99,188.24 48.9,184.15 48.9,181.83 43.22,176.16 43.22,170.7 42.74,170.22 42.74,169.33 v4(42.66,169.25) ; 84.09,203.61 87.5,203.61 89.49,205.6 100.39,205.6 104.9,210.11 104.9,214.67 104.03,215.54 103.33,215.54 v4(102.93,215.14) ; 84.09,203.61 v2(84.09,203.96)
CK_PE_100M_16PORT_DN: length 5.3
  TOP w0.102: v3(72.1,169.4) 72.1,168.99 71.97,168.86 71.83,168.86 71.7,168.99 CPU1.U3
  BOTTOM w0.102: v3(72.1,169.4) 72.39,169.11 72.39,169.01 72.04,168.65 71.58,168.65 69.55,170.69 TP5002.1
CK_PE_100M_16PORT_DP: length 5
  TOP w0.102: CPU1.U4 v3(72.9,169.4)
  BOTTOM w0.102: v3(72.9,169.4) 72.61,169.11 72.61,168.92 72.13,168.43 71.49,168.43 70.18,169.75 69.96,169.75 TP5001.1
CLINK_CLK_LAN: length 3.3
  TOP w0.102: TP67.1 121.07,214 120.06,215 NGFF1.42
CLINK_DATA_LAN: length 4.9
  TOP w0.102: TP66.1 121.85,213.46 121.1,213.46 120.06,214.5 NGFF1.40
CLINK_RST_LAN_N: length 3.4
  TOP w0.102: TP65.1 120.04,214 NGFF1.38
CLK_48M_SIO_C: length 3.8
  TOP w0.102: U109.34 156.46,61.15 157.36,62.05 v1(157.36,62.48) 157.36,63.59 R310.1
COMP_OUT1: length 10.5
  TOP w0.102: U178.6 147.99,206.5 146.21,204.72 146.21,203.71 145.45,202.95 U178.1 145.51,202.25 R79725.1 R4708.1 143.8,201.36 v1(143.8,202.06)
COMP_OUT2: length 13.2
  TOP w0.102: v4(147.23,208.79) 146.72,208.28 U178.7
  L3 w0.127: v4(147.23,208.79) 147.23,211.58 150.66,215.01 v4(151.61,215.01)
  BOTTOM w0.102: R4707.1 v2(150.53,215.9) 150.53,215.14 150.66,215.01 v4(151.61,215.01)
COMPNB_R: length 2.6
  BOTTOM w0.254: PC4611.1 39.68,219.58 39.91,219.81 v2(39.91,220.09) 39.91,220.34 39.66,220.6 PR4623.2
CORETYPE: length 1.6
  TOP w0.102: CPU1.K24 88.7,174.9 v3(89,174.9)
  BOTTOM w0.102: TP213.1 89.02,174.88 v3(89,174.9)
CPU_BST1_SW1: length 2.9
  BOTTOM w0.508: PR4701.2 34.2,208.03 33.87,207.7 v2(33.54,207.7) 33.15,207.7 32.93,207.92 PC4704.1
CPU_BST2_SW2: length 3
  BOTTOM w0.508: PC4710.1 28.74,207.92 28.49,207.68 v2(28.1,207.68) 27.69,207.68 27.47,207.9 PR4703.2
CPU_FAN_CTRL_SIO: length 314.4
  TOP w0.165: U109.6 157.14,48.38 v4(157.01,48.51) ; R68.1 11.46,219.84 v1(11.83,220.21) 12.35,220.73 15.91,220.73 v4(16.54,220.09)
  L3 w0.165: v4(30.06,71.86) 35.1,66.81 38.59,66.81 40.34,65.06 57.56,65.06 60.38,62.23 65.51,62.23 66.42,61.32 67.62,61.32 68.3,60.64 71.04,60.64 74.46,57.22 80.89,57.22 82.33,55.78 85.04,55.78 89.91,50.91 91.65,50.91 92.48,50.08 96.89,50.08 98.04,48.93 101.38,48.93 101.7,48.61 109.89,48.61 111.44,50.16 113.41,50.16 113.75,49.82 119.44,49.82 120.09,49.17 122.14,49.17 122.84,48.47 129.95,48.47 131.12,47.3 134.63,47.3 135.34,46.59 139.33,46.59 140.26,47.52 144.5,47.52 145.6,48.62 148.06,48.62 148.73,49.28 149.83,49.28 150.18,49.63 153.39,49.63 153.74,49.28 154.54,49.28 155.15,48.67 156.85,48.67 v4(157.01,48.51)
  L4 w0.165: v4(16.54,220.09) 16.02,219.56 16.02,205.49 14.57,204.04 14.57,183.5 17.15,180.92 17.15,172.09 17.91,171.32 17.91,170.19 17.36,169.64 17.36,166.34 16.75,165.72 16.75,164.23 17.55,163.43 17.55,153.66 17.92,153.29 17.92,149.05 22.39,144.58 22.39,139.93 24.9,137.41 30.59,137.41 33.43,134.56 33.43,122.57 33.97,122.03 33.97,118.96 34.15,118.78 34.15,108.15 35.65,106.65 35.65,98.46 35.69,98.41 35.69,91.01 36.31,90.4 36.31,89.99 35.72,89.4 35.71,89.4 32.92,86.61 32.92,77.36 32.3,76.74 32.3,74.27 32.3,73.78 31.31,72.79 30.38,71.86 v4(30.06,71.86)
CPU_FAN_TACH_SIO: length 306.9
  TOP w0.165: U109.5 159.37,47.98 159.71,47.64 v4(159.72,47.64) ; v4(14.15,205.28) 14.17,205.31 16.62,205.31 16.92,205.61 R74.1
  L3 w0.165: v4(159.72,47.64) 157.28,45.19 149.64,45.19 148.87,44.42 144.51,44.42 144.2,44.72 140.55,44.72 139.79,43.96 131.4,43.96 131.2,44.16 128.04,44.16 127.31,44.89 122.78,44.89 121.08,46.59 111.66,46.59 111.03,45.95 100.71,45.95 100.31,46.35 96.97,46.35 95.95,47.37 90.7,47.37 86.19,51.89 83.06,51.89 82.15,50.98 81.26,50.98 v4(81.06,51.18) ; v4(30.06,73.3) 30.06,73.13 30.93,72.27 30.93,72.12 35.44,67.61 38.92,67.61 40.67,65.86 57.98,65.86 60.14,63.7 65.82,63.7 69.22,67.1 71.74,67.1 76.46,62.37 79.9,62.37 80.26,62.74 v4(80.55,62.74)
  L4 w0.165: v4(81.06,51.18) 80.44,51.8 80.44,62.63 v4(80.55,62.74) ; v4(30.06,73.3) 30.09,73.3 31.1,74.32 31.1,77.32 31.74,77.95 31.74,91.85 33.14,93.25 33.14,104.51 32.69,104.97 32.69,112.3 32.93,112.54 32.93,114.32 32.23,115.02 32.23,133.2 29.2,136.23 23.28,136.23 19.17,140.34 19.17,142.08 18.65,142.6 18.65,146.65 16.74,148.56 16.74,152.8 15.65,153.89 15.65,157.03 16.29,157.67 16.29,162.66 15.57,163.39 15.57,166.21 16.18,166.83 16.18,181.29 14.15,183.33 v4(14.15,205.28)
  BOTTOM w0.165: v2(80.3,61.85) 80.55,62.1 v4(80.55,62.74)
CPU_VCORE: length 445.2
  TOP w0.254: PR4628.1 63.91,187.2 63.44,186.72 v4(63.44,186.51)
  TOP w0.356: CPU1.AB7 74.9,165.2 75.18,165.48 v3(75.22,165.48) 75.22,165.52 75.7,166 CPU1.Y8 ; CPU1.AB9 76.5,164.8 76.22,164.52 76.11,164.52 76,164.41 v3(75.95,164.41) ; CPU1.AD6 v3(74.5,163.4) ; CPU1.W15 v3(80.6,166.8) CPU1.Y13 v3(80.6,165.6) CPU1.AB15 v3(80.6,164.4) CPU1.AD13 v3(80.6,163.2) CPU1.AE15 v3(80.6,162) CPU1.AG13 CPU1.AH15 v3(80.6,159.73) CPU1.AK13 ; CPU1.W18 v3(83,166.8) CPU1.Y16 v3(83,165.6) CPU1.AB18 v3(83,164.4) CPU1.AD16 v3(83,163.2) CPU1.AE18 v3(83,162) CPU1.AG16 CPU1.AH18 v3(83,159.73) CPU1.AK16 ; CPU1.W21 v3(85.4,166.8) CPU1.Y19 v3(85.4,165.6) CPU1.AB21 v3(85.4,164.4) CPU1.AD19 v3(85.4,163.2) CPU1.AE21 v3(85.4,162) CPU1.AG19 CPU1.AH21 v3(85.4,159.73) CPU1.AK19 ; CPU1.AK22 v3(87.8,159.73) 87.8,160.8 CPU1.AG22 v3(87.8,162) v3(87.8,163.2) CPU1.AD22 v3(87.8,164.4) v3(87.8,165.6) CPU1.Y22 v3(87.8,166.8) ; CPU1.U8 75.3,168.2 v3(75.3,168) 75.3,167.8 CPU1.W7 ; CPU1.AK10 v3(78.2,159.73) CPU1.AH12 CPU1.AG10 v3(78.2,162) CPU1.AE12 v3(78.15,163.25) CPU1.AD10 v3(78.2,164.4) CPU1.AB12 v3(78.15,165.65) CPU1.Y10 v3(78.2,166.8) CPU1.W12
  TOP w0.38: CPU1.AE7 74.84,162.54 74.84,162.14 CPU1.AG6 74.1,161.12 73.95,160.97 v3(73.95,160.82) ; v3(76.2,158.4) 76.5,158.7 CPU1.AK9 ; CPU1.AN6 74.1,156.64 74.6,157.14 v3(74.6,157.18) 74.6,157.2 74.9,157.5 CPU1.AL7 ; CPU1.AH7 74.46,159.75 74.46,159.35 CPU1.AK6 73.8,158.7 v3(73.8,158.4)
  TOP w0.508: 58.99,185.8 58.99,186.69 65.95,193.65 65.95,203.62 66,203.67 66,206.4 v4(67.11,207.52) ; 58.58,179.41 58.58,180.47 ; 58.58,180.47 58.58,181.52 ; 58.58,180.47 59.63,180.47 ; 58.58,180.47 57.53,180.47 ; G5.1 142.02,36.04 143.9,36.04 144.71,36.86 145.34,36.86 146.28,35.91 146.79,35.91 146.87,35.83 149.06,35.83 149.66,36.42 v4(150.81,36.42) ; v4(163.86,39.88) 165.67,41.68 165.67,63.6 v4(165.62,63.65) ; PT4709.1 50.71,181.65 ; PT4709.1 50.71,179.54 ; PT4709.1 51.76,180.59 ; PT4709.1 49.65,180.59 ; 49.65,172.72 PT4702.1 ; PT4702.1 50.71,173.77 ; PT4702.1 51.76,172.72
  L3 w0.254: v4(63.44,186.51) 63.44,186.44 61.25,184.25 v7(59.77,184.25)
  L3 w0.508: v4(150.81,36.42) 152.43,36.42 152.64,36.22 160.21,36.22 v4(163.86,39.88)
  L4 w0.508: 58.58,180.47 59.63,180.47 ; 58.58,180.47 58.58,179.41 ; 58.58,180.47 57.53,180.47 ; 58.58,180.47 58.58,181.52 ; v4(169.45,69.22) 169.48,69.24 169.48,75.39 171.43,77.34 171.43,91.21 169.4,93.24 169.4,108.31 170.44,109.36 170.44,109.88 170.44,127.94 167.55,130.84 167.55,136.49 167.01,137.02 167.01,196.19 160.32,202.88 156.19,202.88 153.81,205.26 150.02,205.26 149.26,204.5 148.18,204.5 147.4,203.71 143.93,203.71 141.9,205.75 139.77,207.87 127.03,220.61 v4(127.03,221.36) ; PT4709.1 51.76,180.59 ; PT4709.1 50.71,181.65 ; PT4709.1 49.65,180.59 ; PT4709.1 50.71,179.54 ; PT4702.1 50.71,173.77 ; PT4702.1 51.76,172.72 ; PT4702.1 49.65,172.72 ; PT4702.1 50.71,171.67
  BOTTOM w0.508: v4(169.45,69.22) 169.42,69.22 167.39,67.19 167.39,66.64 167.33,66.48 165.64,64.79 165.64,63.68 v4(165.62,63.65) ; v4(67.11,207.52) 67.11,206.86 67.98,205.99 81.95,205.99 83.56,207.61 88.88,207.61 89.9,208.62 v2(89.9,222.02) 89.9,224.49 91.91,226.5 123.58,226.5 126.27,223.8 126.27,222.12 v4(127.03,221.36)
  vias: v2(77.12,166.62) v2(77.12,159.38) v2(88.32,166.19) v2(88.35,162.56) v4(50.66,181.84) v4(51.32,184.53) v4(53.25,184.53) v4(57.92,179.2) v4(58.25,181.71) v4(58.83,184.3) v4(59.14,181.71) v4(59.95,183.01) v4(59.95,182.07) v4(59.95,181.1) v7(52.23,184.48) v7(52.18,182.22) v7(52.15,181.08) v7(52.15,173.1) v7(52.26,183.39) v7(52.31,175.36) v7(52.59,185.52) v7(53.45,175.34) v7(53.7,185.52) v7(54.59,175.41) v7(56.01,178.94) v7(57.03,179.45) v7(57.21,182.52) v7(57.23,181.53) v7(57.23,180.49)
CPVEE: length 4
  TOP w0.203: U6.20 158.21,77.63 157.92,77.34 v4(157.92,77.27) 157.39,77.8 C1491.1
  BOTTOM w0.508: v2(157.63,78.45) 157.61,78.44 157.61,77.74 157.92,77.43 v4(157.92,77.27)
D2_M: length 5.2
  TOP w0.508: R1672.1 74.01,51.54 D23.2 73.43,50.06 73.21,49.83 70.87,49.83 v1(70.57,49.53)
DC_19V: length 82.2
  TOP w0.508: v4(52.84,62.36) 52.84,59.41 53.32,58.93 PR5284.1 ; PU5204.5 60.04,39.43 53.25,39.43 PR5282.1
  TOP w1.27: v7(58.58,66.27) 58.43,66.42 v1(52.23,66.42) 49.99,68.66 49.99,69.93 48.67,71.25 47.79,71.25
  L3 w0.508: v4(66.76,63.2) 67.17,62.79 70.45,62.79 72.25,60.99 v4(77.17,60.99)
  L4 w0.508: 63.71,63.55 64.07,63.2 v4(66.76,63.2) ; v4(52.84,62.36) 54.67,62.36 v7(58.58,66.27) ; 65.82,59.44 66.07,59.69 v4(67.5,59.69)
  L4 w1.27: v7(58.58,66.27) 61,66.27 63.71,63.55 63.71,61.54 65.82,59.44 65.82,52.9 65.16,52.24 65.16,49.66 62.22,46.72 v7(62.22,43.31)
  BOTTOM w0.508: PR5270.1 v4(67.5,59.69) ; PR4431.1 76.31,61.85 v4(77.17,60.99)
  vias: v1(46.26,71.37) v1(62.26,45.47) v1(63.15,43.56) v2(62.01,46.1) v2(62.9,42.65) v7(62.22,42.04) v7(62.22,40.77) v7(62.22,39.5)
DC_IN_D: length 3.8
  TOP w0.254: PR5282.2 50.88,39.75 v1(50.86,39.73) 50.22,39.09 49.79,39.09 49.2,38.5 PQ5005.3
DCBATOUT: length 334.1
  TOP w0.203: 112.76,10.97 112.52,11.21 PU4901.11
  TOP w0.254: PG4905.1 57.44,48.26 56.91,47.73 PR5276.2 ; 102.78,57.91 PG5210.1 PG5205.1 102.78,58.67
  TOP w0.508: v4(36.74,144.4) 36.74,142.62 36.23,142.11 35.21,142.11 34.77,141.67 R1778.1 ; R733.1 40.76,142.39 v4(40.76,142.47) ; v4(129.7,199.14) 139.2,199.14 140.9,200.84 140.9,207.67 142.65,209.42 144.94,209.42 145.32,209.8 R4702.1 ; PR5007.1 v4(144.94,72.29) ; PR4616.1 38.68,224.54 44.56,224.54 45.5,223.6 45.5,218.49 ; v4(116.62,9.4) PC4903.1 115.29,9.72 PR4901.1 113.89,9.72 112.87,10.73 112.87,10.82 112.76,10.94 112.76,10.97 ; v4(52.2,145.97) 52.48,145.69 56.17,145.69 56.48,145.38 R179.1 57.5,144.78 R171.1 ; v4(89.7,19.11) R1780.1 R1777.1
  TOP w0.762: L10.1 v4(151.52,37.08)
  L3 w0.508: v4(39.71,127.03) 39.71,132.18 40.72,133.2 40.72,136.66 v4(41.92,137.86) 41.94,137.88 54.05,137.88 v4(55.15,136.78) ; v7(22.31,163.55) 19.95,163.55 18.35,161.95 18.33,161.95 17.94,161.56 17.94,161.54 17.84,161.44 17.84,155.78 19.46,154.15 v4(19.46,153.42) ; 89.7,23.39 v4(89.7,19.11)
  L4 w0.508: v4(68.74,208.41) 66.2,208.41 62.26,204.47 53.75,204.47 v7(49.31,200.03) ; v4(129.7,199.14) 111.66,199.14 107.36,203.43 102.58,203.43 95.24,210.77 89.77,210.77 88.2,209.19 82.58,209.19 v4(81.69,208.31) ; v4(153.58,68.2) 153.58,67.09 152.19,65.7 152.19,62.46 152.48,62.18 152.48,55.44 151.45,54.41 151.45,52.96 150.92,52.43 150.92,51.96 151.62,51.25 v4(151.62,50.5) ; v4(52.2,145.97) 52.2,145.45 54.07,143.57 54.07,137.86 v4(55.15,136.78) ; v4(41.92,137.86) 40.85,138.93 40.85,142.38 v4(40.76,142.47)
  L4 w0.762: v4(151.62,50.5) 151.7,50.42 151.7,45.82 150.05,44.17 150.05,39.95 151.04,38.96 151.04,37.57 v4(151.52,37.08)
  L4 w1.016: v7(135.8,87.63) 136.2,87.22 136.2,85.85 136.08,85.73 136.08,74.32 134.78,73.03 v4(134.78,71.98)
  BOTTOM w0.508: PR4458.1 72.42,65.41 v4(71.79,66.04) ; R657.1 152.01,50.7 152,50.7 151.8,50.5 v4(151.62,50.5) ; v4(39.71,127.03) 39.71,124.16 38.32,122.77 R20.1 R26.1 ; v4(19.46,153.42) 19.97,153.42 22.74,150.65 22.74,150.13 25.8,147.07 34.07,147.07 v4(36.74,144.4) 38.83,144.4 v4(40.76,142.47) ; PR5424.1 v4(81.69,208.31) 80.89,207.5 75.44,207.5 73.82,209.12 72.75,209.12 72.55,208.91 70.52,208.91 70.01,208.41 v4(68.74,208.41)
  BOTTOM w1.016: v4(153.58,68.2) 152.9,68.2 150.51,70.59 149.7,70.59 149.31,70.21 149.31,69.57 147.81,68.07 145.98,68.07 145.19,68.86 145.19,72.03 v4(144.94,72.29) 141.23,72.29 140.47,71.52 140.47,70.92 139.48,69.93 138.01,69.93 135.95,71.98 v4(134.78,71.98)
  vias: v1(22.89,162.81) v1(28.2,208.33) v1(41.31,204.42) v1(47.4,212.09) v1(132.01,94.56) v2(15.27,165.84) v2(46.9,198.12) v2(48.06,218.55) v2(135.11,95.35) v7(7.27,153.54) v7(7.27,152.53) v7(7.27,151.51) v7(8.29,153.54) v7(8.29,152.53) v7(8.29,151.51) v7(9.3,168.53) v7(9.3,167.51) v7(9.3,153.54) v7(9.3,152.53) v7(9.3,151.51) v7(10.32,169.54) v7(10.32,168.53) v7(10.32,167.51) v7(11.34,169.54) v7(11.34,168.53) v7(11.34,167.51) v7(12.35,169.54) v7(12.35,168.53) v7(16.12,137.58) v7(16.42,138.56) v7(16.92,136.78) v7(17.18,137.79) v7(17.69,136.27) v7(17.94,137.29) v7(18.7,136.4) v7(20.2,200.66) v7(20.2,199.14) v7(20.2,197.73) v7(22.28,165.86) v7(22.28,164.54) v7(23.15,165.1) v7(23.15,164.08) v7(24.8,201.29) v7(24.8,200.15) v7(24.8,199.14) v7(24.8,197.99) v7(39.07,53.77) v7(39.1,52.7) v7(39.99,53.72) v7(40.04,52.7) v7(40.95,53.7) v7(40.95,52.7) v7(44.51,217.75) v7(44.53,216.69) v7(44.48,215.63) v7(44.48,214.72) v7(44.48,199.9) v7(44.48,198.75) v7(44.48,197.74) v7(44.86,68.71) v7(45.14,212.12) v7(45.17,213.13) v7(45.58,217.55) v7(45.63,216.59) v7(45.65,215.54) v7(45.65,214.4) v7(45.78,68.71) v7(46.52,129.92) v7(46.69,68.71) v7(47.53,129.29) v7(47.61,68.71) v7(47.79,130.43) v7(48.29,128.52) v7(48.55,129.67) v7(48.52,68.71) v7(49.31,199.01) v7(49.31,197.99) v7(52.48,48.9) v7(52.81,50) v7(52.99,91.57) v7(52.99,90.04) v7(52.99,88.52) v7(53.73,50) v7(54.64,49.89) v7(54.9,91.57) v7(54.9,90.04) v7(54.9,87.88) v7(55.56,49.89) v7(56.45,49.18) v7(67.09,47.24) v7(67.98,47.68) v7(67.98,46.76) v7(67.98,45.85) v7(67.98,44.93) v7(68.74,26.67) v7(68.84,27.86) v7(68.89,47.68) v7(68.89,46.76) v7(68.89,45.85) v7(69.02,71.15) v7(69.25,75.44) v7(69.81,27.86) v7(69.76,26.67) v7(70.14,71.15) v7(70.52,75.44) v7(71.05,71.15) v7(71.79,75.44) v7(71.97,71.15) v7(72.88,71.15) v7(89.82,64.26) v7(89.82,63.25) v7(111.41,26.54) v7(112.44,26.49) v7(112.44,25.53) v7(112.44,24.56) v7(135.29,89.57) v7(135.29,88.65) v7(136.25,89.57) v7(136.2,88.65)
DCIN_EN: length 3.4
  TOP w0.102: R2087.2 134.77,40.07 134.45,39.75 134.43,39.75 v1(134.31,39.63) 133.74,39.06 U118.13
DDCBUF: length 5.8
  TOP w0.102: R1598.2 v4(133.75,40.29) 133.34,39.88 U118.14
  BOTTOM w0.102: R1598.2 134.48,41.09 134.73,40.84 v2(134.73,40.36) 134.58,40.21 133.84,40.21 v4(133.75,40.29)
DDR3_DRAMRST_N: length 74.9
  TOP w0.102: CPU1.T33 95.58,169.72 96.25,169.72 96.58,170.05 96.58,172.34 v4(96.96,172.72)
  L3 w0.127: v4(156.01,183.16) 155.37,182.51 155.37,177.15 152.45,174.23 128.32,174.23 127.29,175.26 99.44,175.26 96.96,172.78 v4(96.96,172.72)
  BOTTOM w0.102: R2054.1 155.53,183.64 v4(156.01,183.16) 156.01,182.63 155.76,182.37 v2(155.74,182.37) 155.04,182.37 R99.1
DDR3_DRAMRST_N_A_1: length 17.1
  TOP w0.102: v4(144.81,182.5) 144.16,181.85 DIMM1.30
  BOTTOM w0.102: v4(144.81,182.5) 145.38,181.94 147.37,181.94 147.7,181.61 C1726.1 ; R99.2 C1726.1 ; C1726.1 153.93,181.57 v2(153.93,180.67)
DDR3_DRAMRST_N_B_1: length 8.7
  TOP w0.102: DIMM2.30 152.19,181.85 v4(151.54,182.5)
  BOTTOM w0.102: v2(154.37,185.98) 153.89,185.51 C1958.1 R2054.2 152.69,183.64 v4(151.54,182.5)
DDR_VREF_S3: length 1.9
  TOP w0.254: PR5032.1 v1(133.15,73.51)
DIFFNB_R: length 2.6
  BOTTOM w0.254: PC4610.1 39.63,221.62 39.89,221.87 v2(39.89,222.12) 39.89,222.43 39.68,222.63 PR4622.2
DIMM_APU_VREF: length 3.2
  TOP w0.254: v3(96.08,170.13) 96.05,170.13 95.99,170.18 95.08,170.18 CPU1.T32
  BOTTOM w0.254: R1912.2 95.97,170.24 v3(96.08,170.13) v2(96.83,170.13)
DIMM_DQ_APU_VREF_MA: length 7.2
  TOP w0.254: R81.2 87.46,185.69 v1(87.46,184.94) 87.46,183.77 87.03,183.34 87.03,182.19 86.36,181.52 85.96,181.52 85.54,181.1 CPU1.B19
DIMM_DQ_APU_VREF_MB: length 5
  TOP w0.254: CPU1.A19 85.19,182.49 85.55,182.49 86.01,182.95 v1(86.01,184.99) R1697.2
DIMM_TMPIN2+: length 193.5
  TOP w0.127: v4(152.82,72.48) 152.71,72.59 152.71,72.61 152.23,73.09 152.23,78.47 150.39,80.31 150.39,82.58 ; 150.39,82.58 v1(150.02,82.58) ; 150.39,82.58 150.39,95.54 148.87,97.06 148.87,101.74 155.35,108.23 155.35,125.6 156.66,126.91 156.66,138.54 155.74,139.47 155.74,151.73 156.66,152.66 156.66,166.48 155.25,167.89 107.09,167.89 102.27,172.72 100.86,172.72 100.54,172.4 RT1.1 ; U109.86 144.07,50.38 144.28,50.16 148.08,50.16 148.62,50.71 148.62,50.94 148.99,51.31 149.26,51.31 149.82,51.87 v4(149.82,52.43)
  L4 w0.127: v4(149.82,52.43) 149.28,52.96 149.28,53.57 149.97,54.25 149.97,56.43 150.31,56.78 150.31,59.55 150.71,59.95 150.71,66.35 150.99,66.62 150.99,71.04 152.45,72.5 152.8,72.5 v4(152.82,72.48)
  BOTTOM w0.127: v4(149.82,52.43) 149.64,52.25 149.64,51.69 149.26,51.31 148.99,51.31 148.32,50.63 C231.2 147.28,50.63 R397.1
DIMM_TMPIN2-: length 184.3
  TOP w0.127: 150.64,90.91 150.64,95.64 149.12,97.16 149.12,101.64 155.61,108.12 155.61,125.5 156.92,126.81 156.92,138.65 155.99,139.57 155.99,151.63 156.92,152.56 156.92,166.59 155.35,168.15 107.2,168.15 102.37,172.97 100.86,172.97 100.54,173.29 RT1.2 ; 150.64,90.91 150.64,80.41 152.48,78.57 152.48,73.59 v4(152.82,73.24) ; 150.64,90.91 v1(150.99,90.91)
  L4 w0.127: v4(152.82,73.24) 150.73,71.15 150.73,66.73 150.46,66.46 150.46,60.06 150.06,59.66 150.06,56.88 149.71,56.53 149.71,54.36 149.03,53.67 v4(149.03,52.43)
  BOTTOM w0.127: R399.2 148.1,51.54 C231.1 148.85,51.52 148.89,51.56 149.15,51.56 149.39,51.79 149.39,52.07 v4(149.03,52.43)
DP0_AUXN: length 175
  TOP w0.102: v3(75.22,178.98) 75.52,178.98 CPU1.E8
  L3 w0.127: v3(75.22,178.98) 74.96,179.23 74.96,180.25 74.52,180.69 73.51,181.7 72.59,181.7 71.28,183.01 71.28,183.86 66.56,188.58 60,188.58 54.82,183.4 54.82,181.06 51.99,178.23 49.44,178.23 48.14,176.93 20.38,176.93 17.81,174.36 13.2,174.36 v4(12.92,174.64)
  L4 w0.127: v4(30.23,92.2) 30.54,92.51 31.33,92.51 32.41,93.6 32.41,103.89 31.49,104.81 31.49,132.9 28.9,135.5 22.98,135.5 17.11,141.36 17.11,147.15 16.01,148.25 16.01,152.49 15.26,153.25 14.92,153.58 14.92,161.42 14.08,162.26 14.08,165.77 15.41,167.1 15.41,172.59 13.63,174.36 13.19,174.36 v4(12.92,174.64)
  BOTTOM w0.102: R1074.2 C305.1 v4(30.23,92.2) ; v2(12.56,175.37) 12.68,175.37 12.92,175.12 v4(12.92,174.64)
DP0_AUXP: length 174.9
  TOP w0.102: v3(75.2,178.18) 75.25,178.23 75.67,178.23 75.8,178.1 CPU1.F8
  L3 w0.127: v4(12.92,173.82) 13.19,174.1 17.92,174.1 20.49,176.66 48.25,176.66 49.55,177.96 52.1,177.96 55.08,180.94 55.08,183.29 60.11,188.32 66.44,188.32 71.01,183.75 71.01,182.9 72.48,181.43 73.4,181.43 74.41,180.42 74.7,180.14 74.7,178.32 74.84,178.18 v3(75.2,178.18)
  L4 w0.127: v4(12.92,173.82) 13.19,174.1 13.52,174.1 15.14,172.48 15.14,167.21 13.81,165.88 13.81,162.15 14.65,161.31 14.65,153.47 15.74,152.38 15.74,148.14 16.85,147.04 16.85,141.25 22.87,135.23 28.79,135.23 31.23,132.79 31.23,104.7 32.14,103.78 32.14,93.71 31.22,92.78 30.54,92.78 v4(30.23,93.09)
  BOTTOM w0.102: v4(30.23,93.09) C304.1 R1079.1 ; v4(12.92,173.82) 13.69,173.82 v2(13.77,173.74)
DP0_HPD: length 176
  TOP w0.102: v3(75.5,176.5) 75.8,176.8 CPU1.G8
  L3 w0.127: v3(75.5,176.5) 75.37,176.5 74.96,176.91 68.74,176.91 67.81,177.84 67.81,180.55 66.92,181.43 66.92,181.78 64.66,184.04 62.76,184.04 60.89,182.17 60.89,181.31 55.81,176.23 50.27,176.23 48.67,174.62 21.5,174.62 18.41,171.54 16.71,171.54 10.54,165.37 10.54,148.19 13.16,145.58 13.16,136.36 15.62,133.89 29.46,133.89 30.39,132.97 30.39,117.05 30.7,116.73 30.7,89.62 v4(30.23,89.15)
  BOTTOM w0.102: v2(75.01,177.37) 75.04,177.37 75.5,176.91 v3(75.5,176.5) ; R512.1 R530.1 31.97,88.27 R510.2 v4(30.23,89.15)
DP0_TXN0: length 164.8
  TOP w0.102: CPU1.E1 69.77,178.6 69.45,178.92 v3(69.45,179.12)
  L3 w0.127: v4(12.92,172.2) 12.92,172.14 13.05,172.01 13.42,172.01 13.55,172.14 13.55,172.62 13.67,172.75 14.93,172.75 15.61,173.43 18.2,173.43 20.76,175.99 48.53,175.99 49.83,177.29 52.5,177.29 55.75,180.55 55.75,183.02 60.39,187.65 64.67,187.65 69.62,182.71 69.62,179.29 v3(69.45,179.12)
  L4 w0.127: v4(12.92,172.2) 13.19,172.47 13.55,172.47 14.47,171.54 14.47,167.48 13.14,166.15 13.14,154.03 15.07,152.11 15.07,147.87 16.18,146.76 16.18,140.97 22.59,134.56 28.51,134.56 30.56,132.51 30.56,104.22 31.44,103.35 31.44,96.05 30.86,95.47 30.58,95.47 30.23,95.81 v4(30.23,96.01)
  BOTTOM w0.102: v4(30.23,96.01) 30.23,95.89 30.36,95.76 30.96,95.76 31.08,95.89 C301.1 ; v3(69.45,179.12) 68.61,179.12 v2(68.54,179.04)
DP0_TXN1: length 163.8
  TOP w0.102: v3(72.9,179) 73.06,178.84 73.06,178.46 72.91,178.31 72.63,178.31 72.5,178.44 CPU1.E4
  L3 w0.127: v4(12.92,170.57) 13.21,170.86 13.99,170.86 15.89,172.76 18.48,172.76 21.04,175.32 48.81,175.32 50.11,176.63 52.77,176.63 56.42,180.27 56.42,182.74 60.66,186.98 64.4,186.98 68.47,182.91 68.47,178.83 69.08,178.22 72.12,178.22 v3(72.9,179)
  L4 w0.127: v4(30.23,97.79) 30.46,97.79 30.77,98.1 30.77,102.8 29.89,103.67 29.89,132.23 28.23,133.89 22.32,133.89 15.51,140.7 15.51,146.48 14.4,147.59 14.4,151.83 12.48,153.76 12.48,166.43 13.81,167.76 13.81,170.48 13.44,170.85 13.19,170.85 v4(12.92,170.57)
  BOTTOM w0.102: v2(13.29,169.54) 12.92,169.92 v4(12.92,170.57) ; C303.1 v4(30.23,97.79)
DP0_TXP0: length 164.8
  TOP w0.102: CPU1.E2 70.6,178.6 v3(70.08,179.12)
  L3 w0.127: v3(70.08,179.12) 69.88,179.31 69.88,182.82 64.78,187.92 60.28,187.92 55.49,183.13 55.49,180.66 52.39,177.56 49.72,177.56 48.42,176.26 20.65,176.26 18.09,173.7 15.5,173.7 14.82,173.01 v4(12.92,173.01)
  L4 w0.127: v4(12.92,173.01) 13.19,172.74 13.66,172.74 14.74,171.65 14.74,167.37 13.41,166.04 13.41,154.15 15.34,152.22 15.34,147.98 16.45,146.87 16.45,141.08 22.7,134.83 28.62,134.83 30.83,132.62 30.83,104.33 31.7,103.46 31.7,95.94 30.97,95.2 30.31,95.2 v4(30.23,95.12)
  BOTTOM w0.102: C300.1 v4(30.23,95.12) ; v2(70.34,179.86) 70.26,179.86 70.08,179.67 v3(70.08,179.12)
DP0_TXP1: length 163.6
  TOP w0.102: CPU1.E3 v3(72.1,179)
  L3 w0.127: v4(12.92,171.39) 13.18,171.13 13.88,171.13 15.78,173.03 18.37,173.03 20.93,175.59 48.7,175.59 50,176.89 52.66,176.89 56.15,180.38 56.15,182.85 60.55,187.25 64.51,187.25 68.74,183.02 68.74,178.94 69.19,178.49 72.01,178.49 72.1,178.58 72.1,179 v3(72.1,179)
  L4 w0.127: v4(12.92,171.39) 13.19,171.11 13.55,171.11 14.07,170.59 14.07,167.65 12.74,166.32 12.74,153.87 14.67,151.94 14.67,147.7 15.78,146.59 15.78,140.81 22.43,134.16 28.34,134.16 30.16,132.34 30.16,103.78 31.03,102.91 31.03,97.7 v4(30.23,96.9)
  BOTTOM w0.102: v4(12.92,171.39) 13.58,171.39 v2(13.8,171.6) ; C302.1 30.83,97.16 30.49,97.16 v4(30.23,96.9)
DP_2K_ZVSS: length 7
  TOP w0.102: R1603.1 72.04,185.99 72.04,185.09 72.37,184.76 72.99,184.76 73.18,184.57 73.93,184.57 CPU1.A9
DP_150_ZVSS: length 11
  TOP w0.102: v1(68.99,186.12) R107.1 69.88,185.86 69.88,184.51 70.04,184.35 72.82,184.35 73.01,184.16 73.57,184.16 76.6,181.13 CPU1.B9
DP_AUXN: length 3.5
  TOP w0.102: NGFF1.20 119.38,209.5 119.67,209.78 120.66,209.78 121.32,209.13 TP73.1
DP_AUXP: length 4.6
  TOP w0.102: NGFF1.22 120.75,210 121.1,209.65 121.85,209.65 TP72.1
DP_HPD: length 6.9
  TOP w0.102: NGFF1.31 108.78,212.25 108.24,211.71 106.46,211.71 TP78.1
DP_ML0N: length 3.7
  TOP w0.102: NGFF1.32 119.45,212.5 119.73,212.78 120.2,212.78 121.32,211.67 TP69.1
DP_ML0P: length 4.8
  TOP w0.102: NGFF1.34 120.29,213 121.1,212.19 121.85,212.19 TP68.1
DP_ML1N: length 3.6
  TOP w0.102: TP71.1 121.32,210.4 120.43,211.28 119.72,211.28 119.44,211 NGFF1.26
DP_ML1P: length 4.7
  TOP w0.102: NGFF1.28 120.52,211.5 121.1,210.92 121.85,210.92 TP70.1
DP_ML2N: length 5.2
  TOP w0.102: NGFF1.25 109.5,210.75 109.36,210.89 106.96,210.89 106.69,210.63 106.69,210.08 106.84,209.93 TP76.1
DP_ML2P: length 5.6
  TOP w0.102: NGFF1.27 109.5,211.25 109.36,211.11 106.87,211.11 106.48,210.72 106.48,210.06 106.35,209.93 TP77.1
DP_ML3N: length 6.5
  TOP w0.102: NGFF1.19 109.5,209.25 109.36,209.39 108.62,209.39 108.04,208.81 105.8,208.81 105.42,208.43 105.42,208.17 105.57,208.03 TP74.1
DP_ML3P: length 6.8
  TOP w0.102: NGFF1.21 109.5,209.75 109.36,209.61 108.53,209.61 107.95,209.03 105.71,209.03 105.21,208.52 105.21,208.15 105.08,208.03 TP75.1
DP_STEREOSYNC: length 30.8
  TOP w0.102: CPU1.E11 77.91,178.99 v3(77.49,178.99) ; R1618.1 R1619.1 v1(74.43,197.55) 72.49,197.55 v4(71.28,198.75)
  L4 w0.127: v4(71.28,198.75) 70.63,198.11 70.63,190.38 72.45,188.57 72.45,187.08 72.66,186.87 73.67,185.86 73.67,185.43 74.9,184.2 74.9,183.32 76.78,181.44 76.78,179.7 v3(77.49,178.99)
DP_STEREOSYNC_PU: length 3.5
  TOP w0.102: v1(79.94,199.92) 79.92,199.9 R2023.2 R2026.2 R1618.2
DPLVDS_AUXN: length 3.3
  BOTTOM w0.102: C305.2 32.31,92.54 32.63,92.54 32.7,92.6 33.49,92.6 34.08,93.19 34.23,93.19 34.32,93.1 U26.3
DPLVDS_AUXP: length 3.6
  BOTTOM w0.102: 33,92.82 33.41,92.82 33.99,93.41 34.23,93.41 34.33,93.5 U26.4 ; 33,92.82 v2(33,93.17) ; 33,92.82 32.61,92.82 32.55,92.75 32.31,92.75 C304.2
DPLVDS_BL_EN: length 196.5
  TOP w0.102: R79686.1 148.88,65.79 v4(148.62,66.04) ; R1985.2 v4(43.59,24.54)
  L3 w0.127: v4(70.14,65.41) 73.95,61.59 94.89,61.59 96.35,60.13 106.72,60.13 106.72,60.13 107.82,60.13 108.52,59.44 108.69,59.27 110.96,59.27 112.73,61.04 119.49,61.04 121.81,63.36 135.19,63.36 136.14,62.42 138.54,62.42 140.33,64.2 142.52,64.2 145.02,66.7 147.97,66.7 v4(148.62,66.04) ; v4(41.79,68.96) 39.66,71.09 39.41,71.09 37.46,73.04 37.46,74.36 35.59,76.23 35.59,77.48 35.5,77.56 35.5,88.5 v4(35.91,88.91)
  L4 w0.127: v4(43.59,24.54) 42.4,25.73 42.4,30.29 41.92,30.77 41.92,31.28 41.28,31.92 41.28,34.33 40.52,35.09 40.52,37.65 40.77,37.9 40.77,40.92 40.52,41.16 40.52,51.09 41.56,52.13 41.56,54.08 40.85,54.79 39.06,54.79 35.97,57.87 35.97,62.62 36.26,62.9 36.65,62.9 36.93,63.18 36.93,63.77 41.79,68.63 v4(41.79,68.96)
  BOTTOM w0.102: v4(70.14,65.41) 69.64,65.41 65.4,69.65 43.62,69.65 v2(43.39,69.42) 43.37,69.44 42.27,69.44 v4(41.79,68.96) ; v4(35.91,88.91) 36.62,88.91 36.89,89.18 36.89,90.43 37.09,90.63 37.09,90.8 37.18,90.89 U26.44
DPLVDS_EDIDCLK: length 10.5
  TOP w0.102: v4(35.82,90.2) 35.46,89.83 35.46,88.45 v4(35.97,87.93)
  BOTTOM w0.102: v4(35.97,87.93) 35.97,87.86 36.9,86.93 R35.2 C1827.1 39,87.86 v2(38.84,88.01) 39.18,88.01 39.94,87.25 R32.2 ; v4(35.82,90.2) 35.82,90.37 36.38,90.93 U26.46
DPLVDS_EDIDCLK_C: length 3
  BOTTOM w0.102: U25.6 37.37,84.89 38.06,85.57 v2(38.06,86.11) 38.03,86.13 37.21,86.13 R35.1
DPLVDS_EDIDSDA: length 7.8
  BOTTOM w0.102: C7.1 R46.2 R1858.2 35.83,87.2 35.59,87.2 35.46,87.34 35.46,89.1 35.94,89.59 v2(36.38,89.59) 36.38,90.43 36.73,90.78 36.73,90.95 36.78,91 U26.45
DPLVDS_EDIDSDA_C: length 3.2
  BOTTOM w0.102: v2(34.7,84.1) 35.87,84.1 U25.5 R1858.1
DPLVDS_FWCLK: length 9.1
  BOTTOM w0.102: R47.2 C9.1 32.1,86.23 v2(33,86.23) 33,87.24 33.62,87.86 34.34,87.86 34.72,88.24 34.72,89.6 35.01,89.89 35.01,91.29 35.22,91.5 U26.48
DPLVDS_FWSDA: length 11
  BOTTOM w0.102: C11.1 R58.2 32.88,84.07 v2(32.9,84.1) 33.02,84.22 33.02,85.48 33.51,85.97 33.51,87.19 33.83,87.5 34.48,87.5 35.1,88.12 35.1,89.48 35.36,89.74 35.36,90.42 35.98,91.04 U26.47
DPLVDS_HPD: length 4.8
  BOTTOM w0.102: R510.1 32.09,89.15 32.52,89.59 32.52,90.27 v2(32.96,90.71) 33.05,90.81 33.75,90.81 34.02,91.07 34.02,91.4 34.25,91.62 34.25,91.77 U26.1
DPLVDS_ISPCLK: length 52.5
  TOP w0.102: Q95.4 52.29,72.54 R69.2 52.29,74.23 50.91,75.62 34.48,75.62 v1(34.25,75.84) 34.09,76 34.09,78.06 34.77,78.74 v4(34.88,78.74) 34.12,79.5 34.12,81.12 35.01,82.01 35.01,85.04 31.76,88.29 31.76,91.71 33.04,92.99 33.58,92.99 34.22,93.64 34.22,97.47 v4(33.65,98.05)
  BOTTOM w0.102: v4(33.65,98.05) 33.78,97.92 33.78,97.92 34.2,97.5 U26.13 ; v4(34.88,78.74) 34.58,78.74 34.04,78.21 34.04,77.75 33.51,77.22 Q7.1
DPLVDS_ISPDAT: length 59.9
  TOP w0.102: v4(34.41,98) 34.58,97.82 34.58,93.45 33.76,92.63 33.18,92.63 32.11,91.56 32.11,88.44 35.36,85.19 35.36,81.86 34.48,80.98 34.48,79.98 v4(34.93,79.53) 35.34,79.12 35.34,77.05 35.62,76.77 51.34,76.77 53.51,74.6 56.29,74.6 57.36,73.53 57.36,72.25 R54.2 56.8,70.96 v1(56.3,70.46) 55.51,70.46 54.99,70.98 Q95.1
  BOTTOM w0.102: Q4.1 36.43,76.94 35.49,77.88 35.49,78.97 v4(34.93,79.53) ; v4(34.41,98) 34.59,98.19 35.83,98.19 35.98,98.04 U26.14
DPLVDS_PANEL_VCC: length 20.1
  L3 w0.127: v4(35.16,113.84) 34.39,113.06 34.39,108.93 36.66,106.66 36.66,101.17 v4(37.68,100.15)
  BOTTOM w0.102: R39.2 35.28,113.95 v4(35.16,113.84) 35.16,113.74 v2(35.69,113.21) ; v4(37.68,100.15) 38.38,99.45 U26.20
DPLVDS_PIN12: length 4
  BOTTOM w0.203: v2(32.88,98.63) 32.88,98.15 33.14,97.88 33.14,97.84 33.47,97.51 33.61,97.51 33.94,97.18 33.94,97.17 34.41,96.7 U26.12
  BOTTOM w0.508: R511.1 32.77,98.73 v2(32.88,98.63)
DPLVDS_PIN16: length 6.2
  BOTTOM w0.203: R507.2 32.77,99.75 33.36,99.16 33.88,99.16 33.96,99.24 33.99,99.24 34.07,99.31 v2(34.88,99.31) 35.59,99.31 36.78,98.13 U26.16
DPLVDS_PWMIN: length 12.6
  TOP w0.165: v4(35.11,103.96) 35.59,103.96 38.76,100.8 v4(38.76,100.78)
  BOTTOM w0.165: R502.1 37.06,104.97 36.64,105.39 36.64,105.57 36.36,105.85 R501.1 35.34,104.97 R503.2 35.11,104.91 v4(35.11,103.96) ; U26.21 38.78,98.01 38.71,98.07 38.71,98.53 39.07,98.89 v2(39.07,99.52) 39.12,99.56 39.12,100.42 v4(38.76,100.78)
DPLVDS_PWMOUT: length 139.9
  TOP w0.165: v4(47.58,36.32) 47.45,36.2 47.45,34.2 R1984.2
  L3 w0.165: v4(79.41,74.93) 79.17,74.7 52.39,74.7 52.1,74.4 44.41,74.4 38.95,79.86 38.95,98.11 v4(37.68,99.39)
  L4 w0.165: v4(79.41,74.93) 80.2,74.14 80.2,67.47 78.9,66.17 78.9,63.8 77.98,62.88 77.98,54.95 76.62,53.59 76.62,48.88 v4(76.68,48.83)
  BOTTOM w0.165: v4(76.68,48.83) 76.68,48.5 74.25,46.08 v2(73.24,46.08) 71.53,44.37 65.86,44.37 64.3,42.8 64.3,33.33 63.89,32.92 60.96,32.92 60.64,33.24 55.25,33.24 54.93,32.92 50.19,32.92 47.58,35.53 v4(47.58,36.32) ; v4(37.68,99.39) 38.12,98.95 38.12,98.39 37.98,98.25 U26.19
DRX0N: length 3.3
  BOTTOM w0.102: C301.2 32.31,95.68 33.06,95.68 33.56,95.18 33.91,95.18 34.08,95.01 34.21,95.01 34.3,95.1 U26.8
DRX0P: length 3.6
  BOTTOM w0.102: v2(32.98,95) 33.2,95.23 ; 33.2,95.23 32.97,95.46 32.31,95.46 C300.2 ; 33.2,95.23 33.47,94.96 33.82,94.96 33.99,94.79 34.22,94.79 34.31,94.7 U26.7
DRX1N: length 4.4
  BOTTOM w0.102: 33.04,96.95 33.04,97.09 32.67,97.46 32.3,97.46 C303.2 ; 33.04,96.95 33.04,96.35 33.58,95.81 34.22,95.81 34.31,95.9 U26.10 ; 33.04,96.95 v2(33.38,96.95)
DRX1P: length 4.1
  BOTTOM w0.102: C302.2 32.18,97.11 32.21,97.11 32.34,97.24 32.58,97.24 32.82,97 32.82,96.26 33.49,95.59 34.23,95.59 34.33,95.5 U26.9
EAPD_DEPOP: length 80.5
  TOP w0.203: R635.1 137.07,32.29 136.39,32.29 136.37,32.31 135.72,32.31 135.56,32.47 v4(135.55,32.47) ; U6.14 158.4,80.03 v4(158.22,79.86)
  L4 w0.203: v4(138.46,73.1) 133.81,68.45 133.81,61.32 132.31,59.82 132.31,54.38 133.36,53.34 133.36,49.64 134.02,48.98 134.02,47.24 133.36,46.58 133.36,44.09 136.29,41.16 136.29,39.92 134.67,38.29 134.67,32.82 134.9,32.59 135.43,32.59 v4(135.55,32.47)
  BOTTOM w0.203: v4(138.46,73.1) 138.51,73.15 145.63,73.15 146.06,72.72 146.06,69.62 146.74,68.94 147.45,68.94 148.45,69.93 v2(148.45,71.25) 148.45,72.38 156.34,80.27 157.81,80.27 v4(158.22,79.86)
EAPD_DEPOP_1: length 3.9
  TOP w0.102: v1(136.88,31.56) 136.88,31.1 137.51,30.47 R634.1 R636.1 138.97,31.28 R635.2
EAPD_DEPOP_2: length 4.1
  TOP w0.254: Q63.2 140.19,30.68 139.09,29.58 R636.2 138.72,29.32 138.72,27.8 v1(138.74,27.78)
EC_3P3_CTL: length 4.1
  BOTTOM w0.102: C6724.2 83.6,56.77 v2(83.73,56.64) 83.82,56.55 Q9648.G PR8521.2
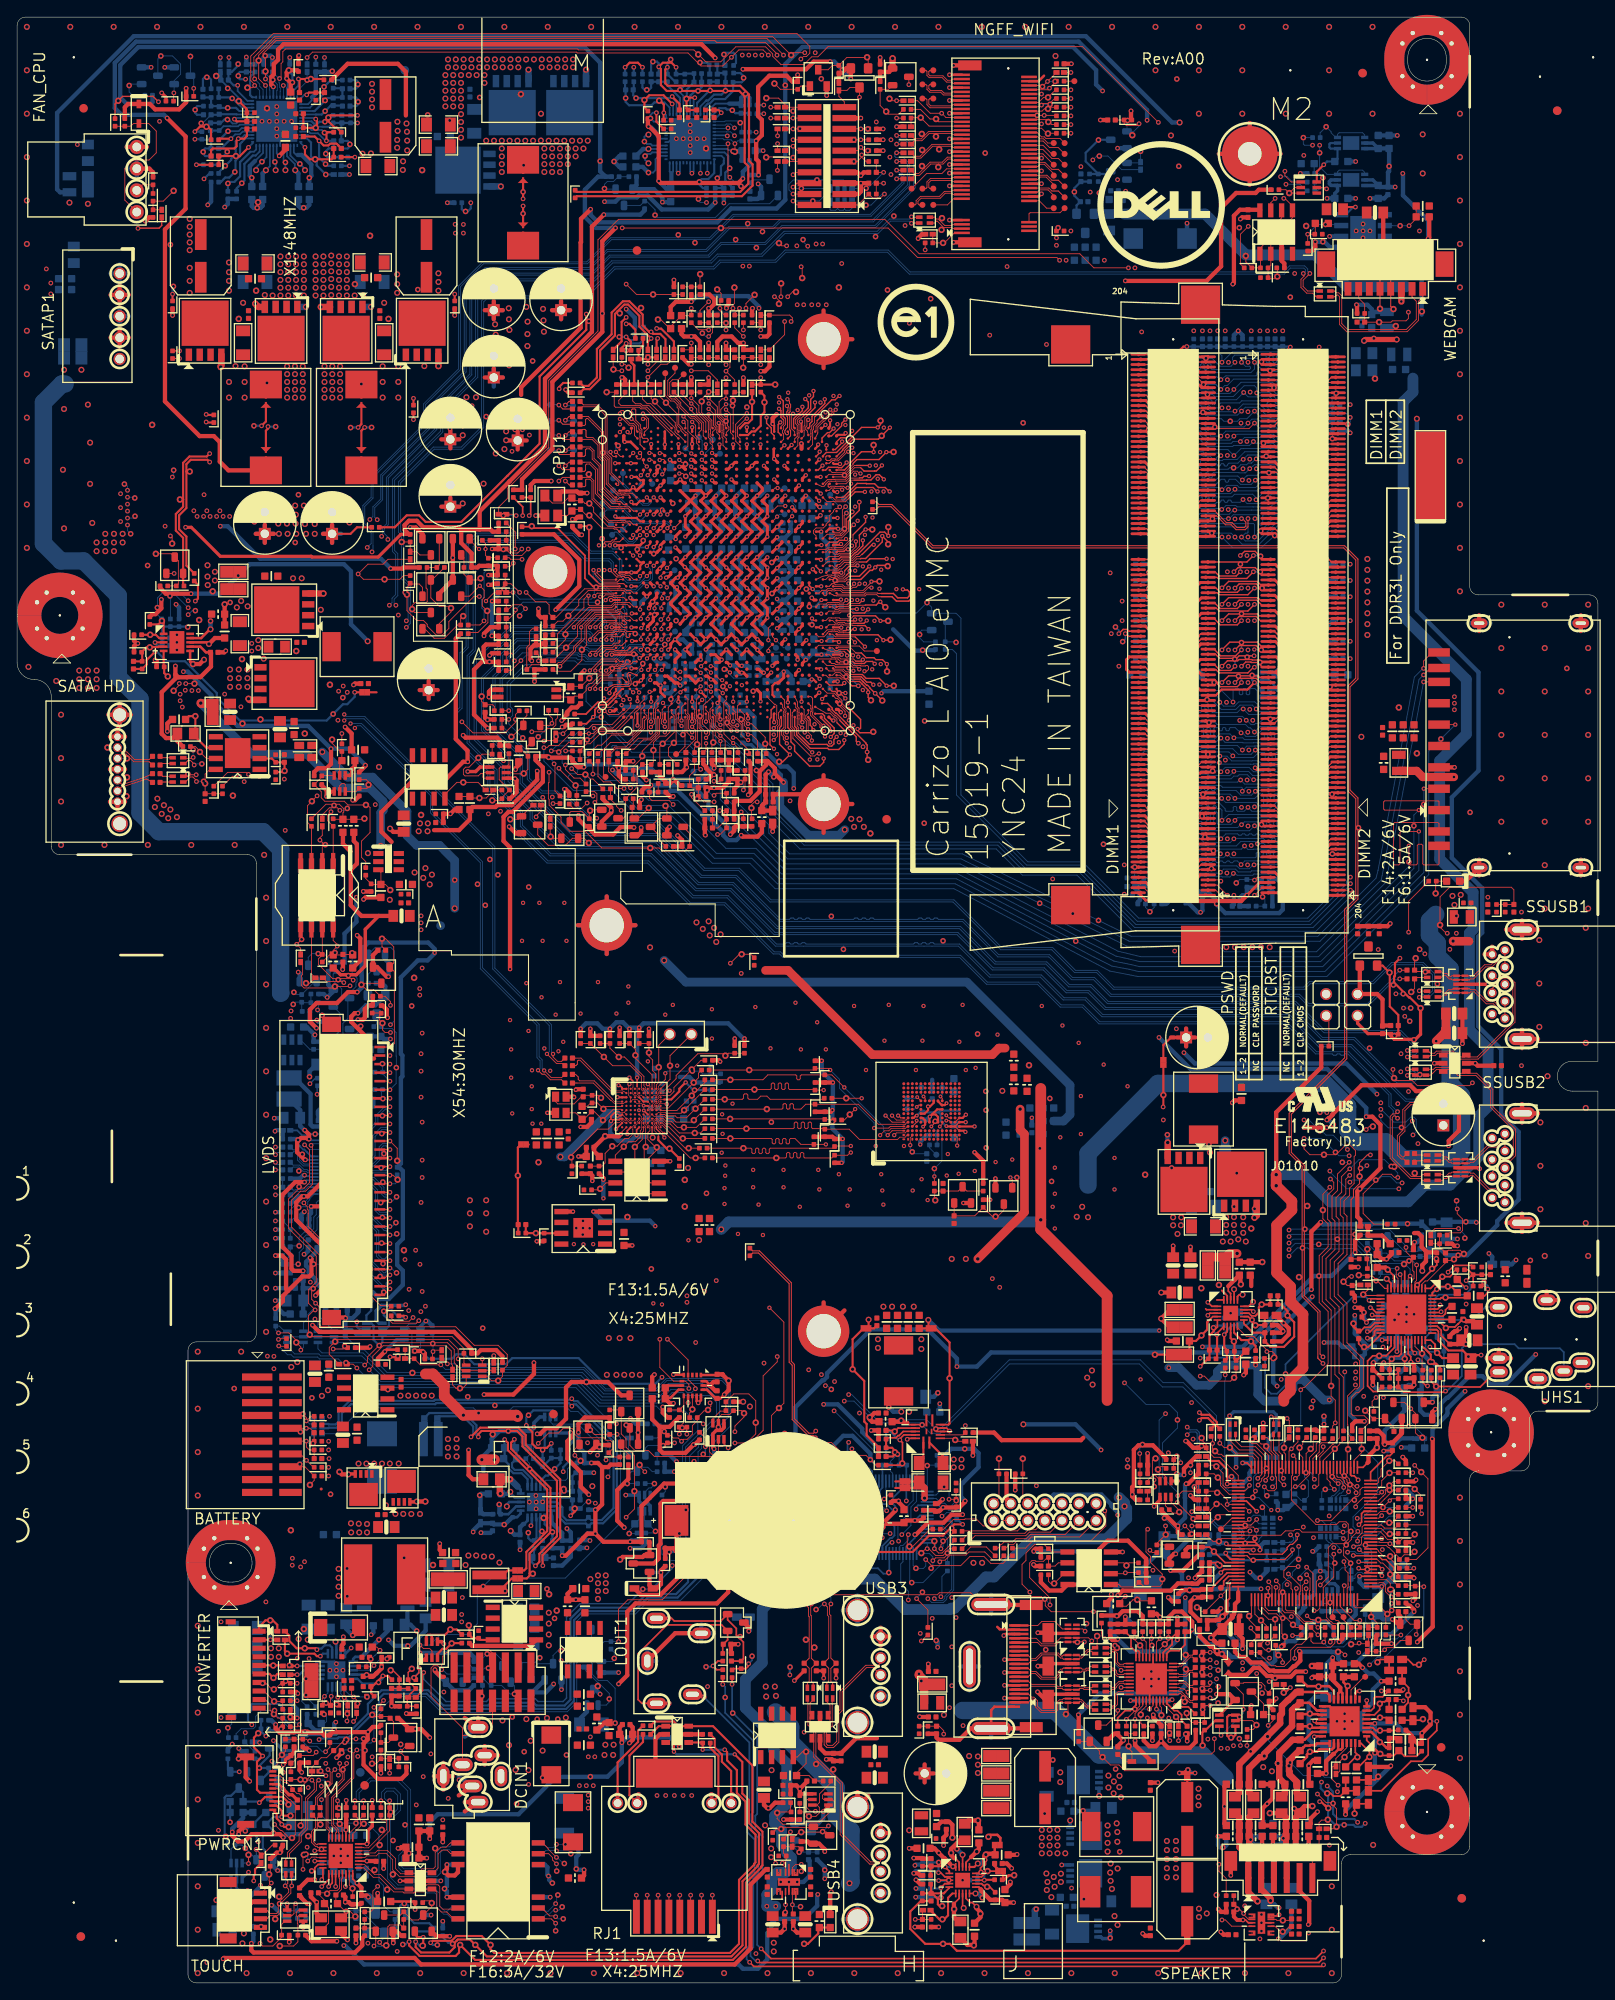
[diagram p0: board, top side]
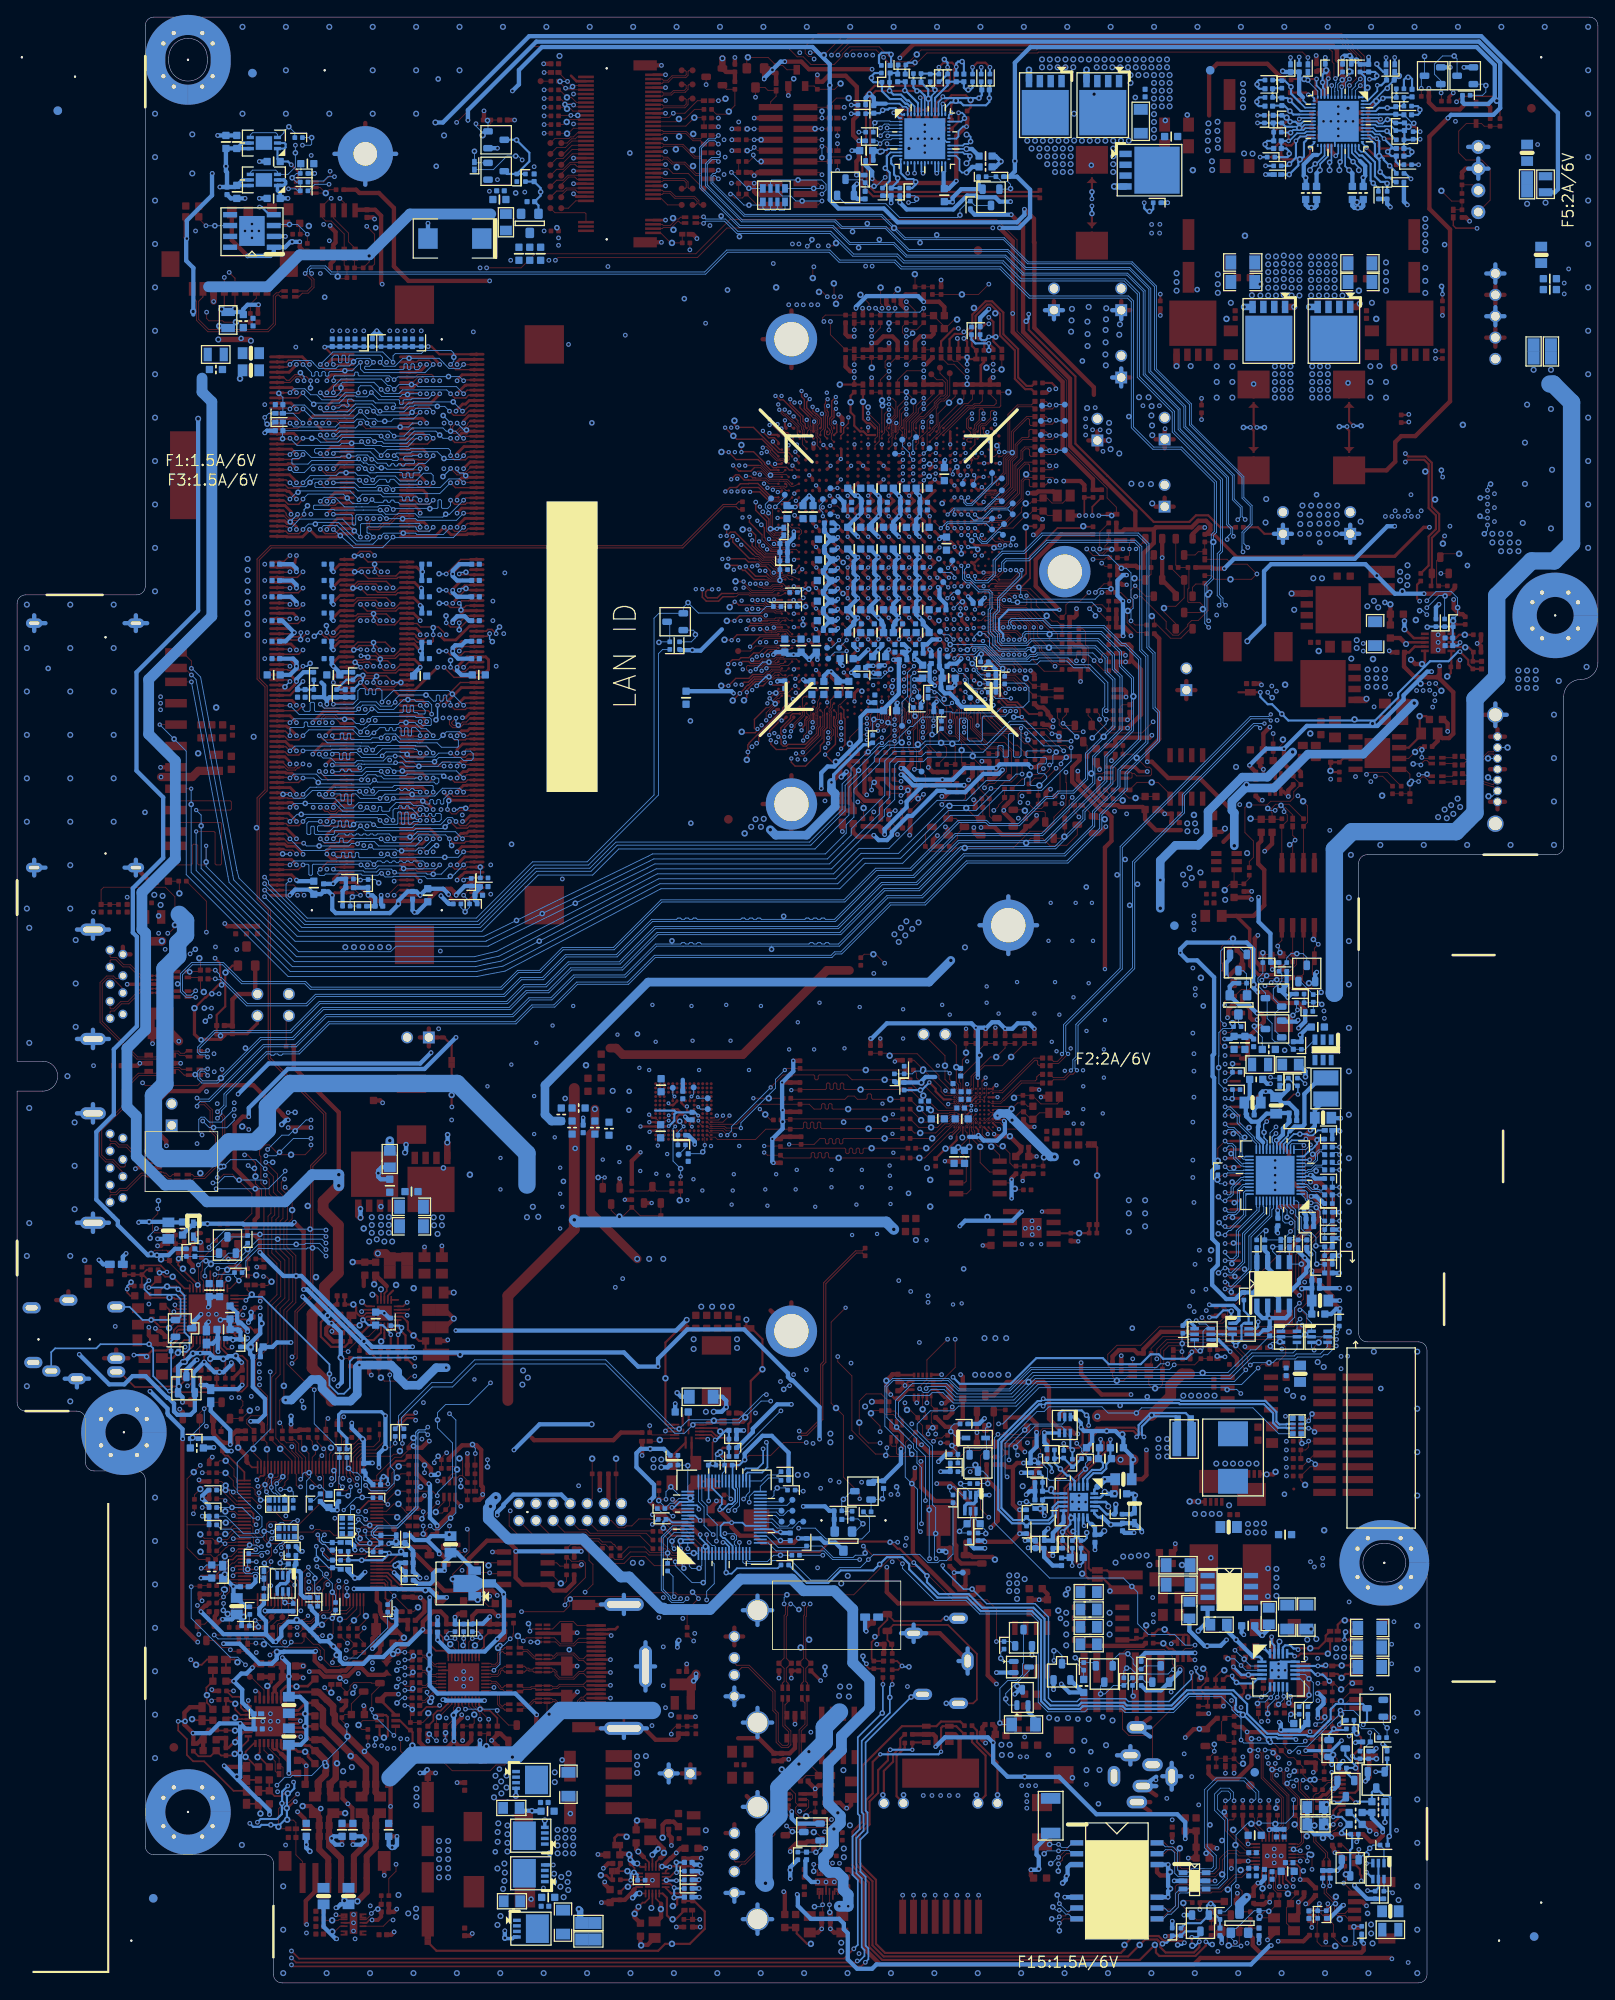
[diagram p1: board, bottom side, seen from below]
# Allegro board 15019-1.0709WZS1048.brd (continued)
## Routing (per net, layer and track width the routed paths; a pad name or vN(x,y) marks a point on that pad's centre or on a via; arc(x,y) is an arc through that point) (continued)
EC_3P3_CTL_2: length 4.4
  BOTTOM w0.102: C6725.1 88.43,54.29 R80229.2 86.58,54.29 v2(86.01,53.72) 86.93,52.81 Q9649.G
EC_3P3_CTL_3: length 4.4
  BOTTOM w0.102: Q9648.D 87.35,57.53 v2(88.3,56.58) 88.49,56.39 R80228.1 88.43,55.18 R80229.1
EC_A20GATE: length 4.3
  TOP w0.102: R80231.1 155.23,63.5 v1(154.21,62.48) 152.85,61.13 U109.43
EC_EUP: length 6.2
  TOP w0.102: R674.1 R675.1 159.16,42.13 v1(158.46,42.83) 158.46,43.38 157.94,43.89 156.62,43.89 156.46,44.05 U109.127
EC_EUP_EN: length 13.9
  TOP w0.102: v4(163.74,40.77) 163.83,40.86 Q1227.G 163.04,41.97 162.53,42.48 C542.1 ; R674.2 158.15,39.81 R1199.2 157.27,39.69 157.21,39.75 v4(157.06,39.75) 156.93,39.62 v1(156.12,39.62)
  L3 w0.127: v4(157.06,39.75) 157.67,39.75 157.73,39.69 159.86,39.69 160.33,40.16 163.13,40.16 v4(163.74,40.77)
EC_HDMI_PD_N: length 46.1
  TOP w0.102: U109.105 147.66,45.96 147.78,46.09 147.78,46.56 147.36,46.99 v4(147.36,47.04) ; R2091.2 Q1249.G 126.65,27.15 126.65,26.8 v1(127.03,26.42) 127.95,25.5 128.96,25.5 129.63,24.83 134.08,24.83 136.05,26.8 139.8,26.8 140.11,27.11 v4(140.11,28.57)
  L4 w0.127: v4(147.36,47.04) 148.62,45.78 148.62,42.95 147.37,41.7 147.37,34.9 146.26,33.78 144.18,33.78 140.11,29.72 v4(140.11,28.57)
EC_IMS: length 29.2
  TOP w0.102: v3(150.96,42.95) 151.39,42.53 151.62,42.53 151.68,42.47 v1(152.28,42.47) 153.21,42.47 153.64,42.04 153.7,42.04 154.08,41.66 R79691.2 ; v4(152.51,46.56) 153.44,47.49 153.44,50.93 153.89,51.38 155.26,51.38 155.79,51.91 155.79,53.68 155.52,53.95 154.72,53.95 154.41,53.64 151.99,53.64 149.13,56.5 149.13,59.28 149.26,59.41 U109.52
  L4 w0.127: v3(150.96,42.95) 150.96,43.99 152.51,45.54 v4(152.51,46.56)
EC_LAN_DISABLE_N: length 165.1
  TOP w0.102: R1194.1 41.37,8.32 41.64,8.59 41.64,10.74 v4(42.2,11.3) ; v4(146.87,59.03) 146.86,59.04 U109.58 146.86,61.78 146.34,62.29 146.34,62.63 v1(146.18,62.79) 145.92,63.05 145.58,63.05 R1840.1
  L3 w0.127: v4(146.87,59.03) 146.87,59.1 146.28,59.69 145.19,59.69 144.72,59.22 144.72,58.05 144.2,57.53 139.12,57.53 138.05,56.45 136.95,56.45 136.22,55.73 135.54,55.73 134.54,56.73 131.84,56.73 130.59,57.98 121.77,57.98 121.37,57.58 117.56,57.58 117.17,57.19 116.25,57.19 115.86,57.58 113.58,57.58 111.28,55.28 110.49,55.28 109.34,54.14 107.34,54.14 104.39,57.09 94.13,57.09 93.73,56.68 92.55,56.68 91.82,57.4 90.08,57.4 88.88,58.6 v4(88.81,58.6) ; v4(42.2,11.3) 45.78,14.88 45.78,16.61 47.02,17.86 50.55,17.86 51.48,18.78 55.72,18.78 58.25,21.31 60.82,21.31 66.15,26.65 66.38,26.65 66.65,26.92 66.69,26.92 68.36,28.6 91.37,28.6 v4(92.11,29.34)
  L4 w0.127: v4(88.81,58.6) 88.26,58.06 88.26,50.7 89.22,49.75 90.45,48.52 90.45,37.54 90.78,37.21 90.78,36.85 92.11,35.52 v4(92.11,29.34)
EC_PSID: length 17.8
  TOP w0.102: R80213.2 106.59,43.64 v4(105.27,44.96)
  L4 w0.127: v4(102.17,52.58) 101.98,52.39 101.98,51.78 101.93,51.73 101.93,50.77 105.19,47.51 105.19,45.03 v4(105.27,44.96)
  BOTTOM w0.102: U4101.12 100.87,51.12 101.06,51.32 101.06,51.64 100.79,51.91 100.79,52.28 101.06,52.55 102.14,52.55 v4(102.17,52.58) ; v4(105.27,44.96) 105.27,45.03 v2(105.95,45.72)
EC_PWREN: length 81
  TOP w0.102: v4(145.96,58.04) 146.42,57.58 147.11,57.58 147.38,57.85 147.38,59.17 147.26,59.29 U109.57 147.26,61.72 146.74,62.23 146.74,63.35 146.27,63.82 R702.2
  L3 w0.127: v4(145.96,58.04) 145.96,57.91 145.12,57.06 141.46,57.06 140.86,56.45 138.41,56.45 138.15,56.2 137.61,56.2 137.42,56 137.11,56 136.46,55.35 135.51,55.35 134.45,56.41 129.35,56.41 129.19,56.25 128.74,56.25 127.9,57.09 124.07,57.09 123.43,56.45 123.43,56.41 123.3,56.29 123.3,55.78 122.46,54.94 113.52,54.94 110.83,52.25 110.81,52.25 110.21,51.65 105.93,51.65 105.13,50.85 99.17,50.85 97.81,52.22 95.52,52.22 94.53,53.2 v4(93.54,53.2)
  BOTTOM w0.102: PR8521.1 85.25,54.42 85.25,52.83 86.14,51.94 90.33,51.94 91.59,53.2 v4(93.54,53.2) ; R1834.1 147.14,57 v2(146.27,57) 145.96,57.31 v4(145.96,58.04)
EC_SCI: length 6.5
  BOTTOM w0.102: U4101.15 99.67,49.53 99.44,49.3 97.19,49.3 96.45,50.04 v2(95.66,50.04) R79709.1
EC_SMB2_CLK: length 71.1
  L4 w0.127: v4(96.81,68.07) 96.81,66.88 96.46,66.54 96.46,61.99 99.3,59.15 99.3,56.26 v4(99.32,56.24)
  BOTTOM w0.102: R80220.1 140.01,65.11 140.01,66.14 136.43,69.72 134.04,69.72 131.35,72.42 116.14,72.42 108.03,64.31 106.89,64.31 v2(105.91,65.29) 105.67,65.53 100.47,65.53 97.93,68.07 v4(96.81,68.07) ; v4(99.32,56.24) 99.31,56.25 99.31,56.91 98.74,57.48 U4101.32 98.03,58.09 97.04,59.08 95.88,59.08 PR8519.2
EC_SMB2_DATA: length 72.8
  L4 w0.127: v4(97.32,68.83) 97.48,68.67 97.48,66.89 96.85,66.26 96.85,62.15 99.68,59.31 99.68,56.94 99.98,56.64 v4(99.98,56.62)
  BOTTOM w0.102: R80219.1 140.37,65.21 140.37,66.34 136.48,70.23 134.12,70.23 131.45,72.9 116.11,72.9 108.03,64.81 v2(107.52,64.81) 106.45,65.89 100.62,65.89 97.67,68.83 v4(97.32,68.83) ; v4(99.98,56.62) 99.98,56.64 99.67,56.96 99.67,57.06 99.27,57.46 U4101.33 97.9,58.72 97.19,59.44 95.98,59.44 PR8520.2
EC_VCORF: length 3.9
  BOTTOM w0.102: U4101.20 96.79,52.68 95.85,51.75 v2(95.66,51.75) C4101.2
ECIO_APU_PROCHOT#: length 3.4
  TOP w0.102: v4(157.01,49.28) 157.1,49.18 U109.8
  BOTTOM w0.102: v4(157.01,49.28) 157.83,49.28 R80226.2 158.02,49.21 v2(158.02,48.39)
ECIO_IO_SMI_N: length 5
  TOP w0.102: R80223.2 161.58,46.48 160.69,47.37 v1(160.69,47.79) 160.69,48.26 159.82,49.12 159.59,49.12 159.14,49.58 U109.9
ECIO_LPC_PME_N: length 7.5
  TOP w0.102: U109.70 144.33,56.78 144.92,57.36 v4(144.92,57.55)
  BOTTOM w0.102: R80224.1 146.4,60.39 v2(146.21,60.2) 145.7,59.69 145.19,59.69 144.69,59.19 144.69,57.79 v4(144.92,57.55)
EGPIO67: length 4.2
  TOP w0.102: CPU1.AT17 83.04,153.7 v3(83.42,153.31)
  BOTTOM w0.102: v2(82.76,153.7) 83.14,153.31 v3(83.42,153.31) 83.42,153.09 83.85,152.65 85.39,152.65 R79653.1
EGPIO70: length 6.4
  TOP w0.102: v3(80,153.28) 79.58,153.7 CPU1.AT12
  BOTTOM w0.102: v3(80,153.28) 80.41,152.87 80.41,150.45 80.58,150.28 80.58,149.69 R79654.1 80.11,148.4 v2(79.92,148.21)
EGPIO119: length 1.6
  TOP w0.102: CPU1.AW7 74.35,151.05 v3(74.02,151.05)
  BOTTOM w0.102: v3(74.02,151.05) 74.02,150.95 TP8.1
EGPIO131: length 15.5
  TOP w0.102: v3(85.55,145.41) 85.4,145.41 84.74,146.08 84.74,147.25 84.09,147.89 84.09,148.35 84.1,148.36 84.1,148.64 83.8,148.95 CPU1.BB18 ; v4(86.61,138.18) 86.29,138.18 85.94,137.82 v1(85.94,137.46) 85.94,136.28 R79670.1
  L3 w0.127: v3(85.55,145.41) 85.55,144.88 85.19,144.52 85.19,144.13 84.79,143.73 84.79,141.06 86.27,139.58 86.27,138.52 v4(86.61,138.18)
EGPIO132: length 15.4
  TOP w0.102: CPU1.BB16 81.9,149 81.9,148.32 81.91,148.31 81.91,147.6 v3(82.31,147.19) ; v4(84.74,137.01) 84.74,136.98 85,136.73 R79635.1
  L3 w0.127: v3(82.31,147.19) 83.09,146.42 83.09,144.97 83.02,144.9 83.02,138.73 v4(84.74,137.01)
  BOTTOM w0.102: v2(83.09,147.45) 82.83,147.19 v3(82.31,147.19)
EGPIO145: length 7.7
  TOP w0.102: CPU1.BB10 77.1,149 77.1,148.37 77.12,148.35 77.12,145.4 76.87,145.15 v1(76.87,145.08) 76.8,145.08 76.23,144.51 76.23,143.57 R79652.1
EMMC_CLK: length 14.4
  TOP w0.102: R90004.1 94.33,103.38 88.13,103.38 87.75,103.76 87.03,103.76 86.65,103.38 85.67,103.38 85.52,103.53 85.52,103.89 85.39,104.01 85.14,104.01 85.01,103.89 85.01,103.53 84.86,103.38 v1(82.81,103.38) R90037.1
EMMC_CLK_C: length 6.2
  TOP w0.102: U902.G10 75.8,101.61 75.96,101.45 77.02,101.45 77.25,101.22 78.33,101.22 v1(79.4,102.29) R90037.2
EMMC_CLK_M: length 15
  TOP w0.102: U903.M6 109.04,101.21 v6(108.74,101.5) ; v3(98.84,103.5) v1(97.04,103.5) R90004.2
  L4 w0.127: v3(98.84,103.5) 103.67,103.5 104.16,103.01 107.45,103.01 108.74,101.72 v6(108.74,101.5)
EMMC_CMD: length 14.3
  TOP w0.102: R90005.1 95.54,101.03 R90013.1 94.46,101.09 v1(83.45,101.09) R90038.1
EMMC_CMD_C: length 6
  TOP w0.102: U902.H10 75.63,101.11 75.93,100.81 76.56,100.81 77.27,100.1 v1(78.04,100.1) 79.5,100.1 R90038.2
EMMC_CMD_M: length 13.9
  TOP w0.102: v6(108.75,100.89) 109.08,100.89 U903.M5 ; R90005.2 96.81,100.97 v1(97.45,101.6) v3(98.08,102.23)
  L4 w0.127: v6(108.75,100.89) 107.65,101.98 104.17,101.98 103.92,102.23 v3(98.08,102.23)
EMMC_D0: length 6.9
  TOP w0.102: R90033.2 80.49,105.35 v1(78.95,103.81) 77.21,102.07 75.35,102.07 U902.F10
EMMC_D1: length 7.6
  TOP w0.076: U902.F9 74.95,102.11 75.2,102.36 76.21,102.36 76.33,102.49
  TOP w0.102: 76.33,102.49 v1(79.18,105.33) 79.74,105.89 79.74,106.44 R90034.2
EMMC_D2: length 7
  TOP w0.076: U902.G9 75.06,101.86 75.84,101.86 75.95,101.75 76.11,101.75
  TOP w0.102: 76.11,101.75 77.71,101.75 v1(78.06,102.11) 80.47,104.52 R90035.2
EMMC_D3: length 6.6
  TOP w0.076: 75.93,100.51 75.57,100.86 75.19,100.86 74.94,101.11 U902.H9
  TOP w0.102: 75.93,100.51 76.44,100.51 77.5,99.44 v1(79.31,99.44) 79.98,99.44 R90036.2
EMMC_D4: length 5.9
  TOP w0.102: U902.J10 75.53,100.61 75.77,100.37 75.96,100.18 76.26,100.18 77.63,98.81 v1(77.91,98.81) R90042.2
EMMC_D5: length 7.6
  TOP w0.076: U902.J9 74.81,100.48 75.06,100.23 75.06,100.01 75.24,99.82
  TOP w0.102: 75.24,99.82 75.55,99.52 75.78,99.52 78.77,96.52 v1(79.41,96.52) R90043.2
EMMC_D6: length 7.2
  TOP w0.076: U902.G8 74.56,101.36 75.49,101.36 75.5,101.36 75.76,101.36
  TOP w0.102: 75.76,101.36 75.98,101.14 76.69,101.14 77.12,100.71 78.96,100.71 79.19,100.94 v1(79.2,100.94) 79.2,100.95 R90044.2
EMMC_D7: length 7.1
  TOP w0.076: U902.H8 74.45,101.11 74.7,100.86 74.76,100.86 74.94,100.86 75.06,100.74 75.06,100.51 75.2,100.36 75.49,100.36 75.69,100.16
  TOP w0.102: 75.69,100.16 78.19,97.66 v1(78.6,97.66) R90045.2
EMMC_DATA_0: length 26.9
  TOP w0.102: R90033.1 v1(83.47,105.66) 87.28,105.66 87.85,106.24 91.13,106.24 91.24,106.12 91.24,105.78 91.36,105.66 91.53,105.66 91.65,105.78 91.65,106.12 91.77,106.24 R90014.1 95.35,106.24 v3(96.81,104.78) ; v3(101.89,99.19) 102.41,99.71 U903.A3
  BOTTOM w0.102: v3(96.81,104.78) 101.38,100.2 101.38,99.69 v3(101.89,99.19)
EMMC_DATA_1: length 26.8
  TOP w0.102: U903.A4 102.19,100.21 102,100.02 v3(100.3,100.02) ; v3(95.16,106.81) 94.97,107 R90015.1 93.19,106.81 v1(85.68,106.81) R90034.1
  BOTTOM w0.102: v3(95.16,106.81) 96.25,105.71 96.25,104.67 100.3,100.63 v3(100.3,100.02)
EMMC_DATA_2: length 27.7
  TOP w0.102: v3(101.63,101.47) 102.4,100.71 U903.A5 ; R90035.1 v1(86.29,104.52) 88.14,104.52 88.26,104.64 88.26,105.16 88.37,105.28 88.54,105.28 88.66,105.16 88.66,104.64 88.78,104.52 88.95,104.52 89.07,104.64 89.07,105.16 89.19,105.28 89.36,105.28 89.47,105.16 89.47,104.64 89.59,104.52 89.76,104.52 89.88,104.64 89.88,105.16 90,105.28 90.17,105.28 90.29,105.16 90.29,104.64 90.41,104.52 93.31,104.52 R90016.1 v3(94.39,104.46)
  L4 w0.127: v3(94.39,104.46) 97.38,101.47 v3(101.63,101.47)
EMMC_DATA_3: length 27.4
  TOP w0.089: 103.3,98.95 103.93,98.95 104.18,99.21 U903.B2
  TOP w0.102: R90036.1 v1(85.35,99.95) 90.83,99.95 90.95,100.07 90.95,100.59 91.06,100.71 91.23,100.71 91.35,100.59 91.35,100.07 91.47,99.95 91.64,99.95 91.76,100.07 91.76,100.59 91.88,100.71 92.05,100.71 92.16,100.59 92.16,100.07 92.28,99.95 92.45,99.95 92.57,100.07 92.57,100.59 92.69,100.71 92.86,100.71 92.98,100.59 92.98,100.07 93.1,99.95 94.46,99.95 R90017.1 97.38,99.89 98.59,98.68 103.03,98.68 103.3,98.95
EMMC_DATA_4: length 28
  TOP w0.089: U903.B3 104.19,99.71 103.94,99.45 102.92,99.45 v3(102.65,99.19)
  TOP w0.102: R90042.1 v1(83.47,98.81) 88.25,98.81 88.37,98.69 88.37,98.29 88.49,98.17 88.65,98.17 88.77,98.29 88.77,98.69 88.89,98.81 89.06,98.81 89.18,98.69 89.18,98.29 89.3,98.17 89.47,98.17 89.59,98.29 89.59,98.69 89.7,98.81 89.87,98.81 89.99,98.69 89.99,98.29 90.11,98.17 90.28,98.17 90.4,98.29 90.4,98.69 90.52,98.81 91.03,98.81 91.73,98.11 R90018.1 v3(94.65,98.11)
  L4 w0.127: v3(94.65,98.11) 95.22,98.11 96.62,96.71 100.17,96.71 v3(102.65,99.19)
EMMC_DATA_5: length 27.4
  TOP w0.089: v3(101,99.19) 101.51,99.69 102.01,99.69 102.27,99.95 103.6,99.95 103.6,99.95 103.93,99.95 104.18,100.21 U903.B4
  TOP w0.102: v3(97.57,97.16) 97.51,97.16 97.19,96.84 R90019.1 95.35,96.52 92.19,96.52 92.07,96.64 92.07,97.04 91.95,97.16 91.78,97.16 91.66,97.04 91.66,96.64 91.54,96.52 91.37,96.52 91.25,96.64 91.25,97.04 91.13,97.16 90.97,97.16 90.85,97.04 90.85,96.64 90.73,96.52 90.56,96.52 90.44,96.64 90.44,97.04 90.32,97.16 90.15,97.16 90.03,97.04 90.03,96.64 89.92,96.52 v1(88.86,96.52) R90043.1
  L4 w0.127: v3(101,99.19) 98.97,97.16 v3(97.57,97.16)
EMMC_DATA_6: length 26.2
  TOP w0.089: 102.9,100.46 103.92,100.46 103.92,100.46 103.93,100.46 104.18,100.71 U903.B5
  TOP w0.102: 102.9,100.46 100.79,100.46 98.44,102.81 R90020.1 92.3,102.81 91.73,102.23 90.97,102.23 90.85,102.35 90.85,102.75 90.73,102.87 90.56,102.87 90.44,102.75 90.44,102.35 90.32,102.23 90.16,102.23 90.04,102.35 90.04,102.75 89.92,102.87 89.75,102.87 89.63,102.75 89.63,102.35 89.51,102.23 v1(87.74,102.23) R90044.1
EMMC_DATA_7: length 28.4
  TOP w0.089: U903.B6 104.27,101.19 104.03,100.95 102.91,100.95 v3(102.4,101.47)
  TOP w0.102: v3(97.57,97.92) 95.73,97.92 R90021.1 95.47,97.66 88.14,97.66 88.02,97.54 88.02,97.15 87.91,97.03 87.74,97.03 87.62,97.15 87.62,97.54 87.5,97.66 87.33,97.66 87.21,97.54 87.21,97.15 87.09,97.03 86.92,97.03 86.81,97.15 86.81,97.54 86.69,97.66 86.52,97.66 86.4,97.54 86.4,97.15 86.28,97.03 86.11,97.03 85.99,97.15 85.99,97.54 85.87,97.66 v1(85,97.66) R90045.1
  L4 w0.127: v3(102.4,101.47) 101.76,100.84 100.49,100.84 v3(97.57,97.92)
EMMC_E9: length 1.8
  TOP w0.102: v6(105.29,102.49) 105.51,102.71 U903.E9
  BOTTOM w0.102: TP5014.1 105.04,102.23 v6(105.29,102.49)
EMMC_E10: length 1.8
  TOP w0.102: v6(105.34,103.63) U903.E10
  BOTTOM w0.102: TP5015.1 105.21,103.5 v6(105.34,103.63)
EMMC_F10: length 1.8
  TOP w0.102: v6(106.08,103.71) 106.27,103.52 U903.F10
  BOTTOM w0.102: TP5016.1 105.82,103.96 v6(106.08,103.71)
EMMC_K10: length 1.7
  TOP w0.102: v6(108.06,103.71) 108.27,103.5 U903.K10
  BOTTOM w0.102: v6(108.06,103.71) 108.26,103.91 TP5017.1
EMMC_RCLK: length 1.5
  BOTTOM w0.102: TP5013.1 106.78,97.7 R90006.1
EMMC_RCLK_M: length 3.9
  TOP w0.102: U903.H5 107.27,100.48 v6(106.99,100.2)
  BOTTOM w0.102: R90006.2 R90012.1 107.67,99.53 v6(106.99,100.2) 107.45,100.66 v2(107.45,100.81)
EMMC_RESET#: length 7.3
  TOP w0.102: v1(107.45,91.57) 107.35,91.67 R90007.1 C9036.1 110.14,92.65 Q90002.D 111.16,92.65 R90067.2
EMMC_RESET#_1: length 9.2
  TOP w0.102: Q90002.G 109.66,91.24 C9041.1 112.07,89.75 R90066.1 114.14,89.66 v1(114.51,89.66) 114.74,89.66 115.48,90.4 Q90001.D
EMMC_RESET#_M: length 7.8
  TOP w0.102: U903.K5 108.27,100.49 v6(107.98,100.2) ; R90007.2 v3(107.35,94.36)
  BOTTOM w0.102: v3(107.35,94.36) v2(107.35,95.28) 108.24,96.16 108.24,99.95 v6(107.98,100.2)
EMMC_RESET_SIO: length 84.9
  TOP w0.102: v3(116.24,94.23) 116.46,94.01 Q90001.G
  L3 w0.127: v3(116.24,94.23) 114.56,92.56 114.56,86.9 131.29,70.17 141.9,70.17 143.33,71.59 152.75,71.59 155.68,68.66 157.56,68.66 v4(157.59,68.63)
  L4 w0.127: v4(154.08,50.93) 154.67,51.51 155.41,51.51 155.8,51.9 155.8,54.2 155.19,54.81 155.19,56.22 155.74,56.77 156.78,56.77 157.79,57.78 157.79,59.21 157.19,59.8 157.19,66.33 157.72,66.86 157.72,67.56 157.53,67.75 157.53,68.57 v4(157.59,68.63)
  BOTTOM w0.102: v4(154.08,50.93) 154.08,51.05 153.63,51.51 153.53,51.51 153.2,51.84 RN13.3 ; v3(116.24,94.23) v2(117,94.23)
EMMC_REXT: length 9
  TOP w0.076: U902.E8 74.31,102.76 74.56,103.01 74.56,103.22 74.7,103.36 74.91,103.36 75.06,103.51 75.06,103.72 75.2,103.86 75.6,103.86
  TOP w0.102: 75.6,103.86 75.65,103.81 76.39,103.81 76.87,104.29 76.87,104.78 v1(78.96,106.87) 80.04,107.95 R90039.2
EMMC_VCC: length 9.5
  TOP w0.254: v6(106.03,100.18) 106.27,100.42 U903.F5 106.27,100.9 105.96,101.21 U903.E6 ; U903.J10 107.77,103.15 108.21,102.71 U903.K9 108.56,102.71 v6(108.77,102.92)
  L4 w0.254: v6(106.03,100.18) 106.48,99.72 108.89,99.72 109.33,100.16 109.33,102.36 v6(108.77,102.92)
  vias: v2(113.37,104.32) v7(115.3,104.37)
EMMC_VCC1N: length 10.4
  TOP w0.076: 75.73,103.36 75.2,103.36 75.06,103.22 75.06,103.01 74.91,102.86 74.7,102.86 74.56,102.72 74.56,102.51 74.41,102.36 74.2,102.36 74.06,102.22 74.06,101.36 U902.H7
  TOP w0.254: v3(78.24,105.36) 77.5,104.62 77.5,104.32 76.55,103.36 75.73,103.36
  BOTTOM w0.254: v3(78.24,105.36) 79.14,104.46 v2(79.28,104.46) R90040.2
EMMC_VCC2N: length 5.7
  TOP w0.076: U902.J8 74.31,100.48 74.56,100.23 74.56,100.01 74.56,99.73 75.04,99.24 75.04,99.04
  TOP w0.254: R90041.2 v1(76.35,97.61) 76.03,97.61 75.04,98.6 75.04,99.04
EMMC_VCCQ: length 11.9
  TOP w0.127: U903.P3 U903.N4 U903.P5
  TOP w0.254: v6(108.75,100.25) 108.79,100.21 U903.M4 U903.N4 ; U903.P3 110.84,99.71 v3(110.98,99.57) ; v6(105.29,101.47) 105.19,101.47 104.92,101.21 U903.C6 ; U903.P5 v3(111.01,100.71)
  BOTTOM w0.254: 107.88,101.85 108.08,101.65 108.08,100.87 108.7,100.25 v6(108.75,100.25) ; 107.88,101.85 108.08,102.06 110.34,102.06 ; 107.88,101.85 106.01,101.85 ; 106.01,101.85 C9031.1 ; 106.01,101.85 105.67,101.85 v6(105.29,101.47)
  vias: v2(113.39,102.11)
EMMC_VDDI: length 4
  TOP w0.089: U903.C2 104.77,99.12 104.52,98.87 104.52,98.3
  TOP w0.102: v3(104.52,98.02) 104.52,98.3
  BOTTOM w0.102: v3(104.52,98.02) 104.52,97.47 v2(104.76,97.23) 104.97,97.02 C9006.2
EQ: length 5.6
  TOP w0.102: R1593.2 v4(131.72,40.29) 132.14,39.88 U118.17
  BOTTOM w0.102: R1593.2 131.04,41.09 130.79,40.84 v2(130.79,40.44) 130.93,40.29 v4(131.72,40.29)
EVAL_PE_L: length 8.3
  TOP w0.102: CPU1.AR14 80.49,154.5 v3(80.04,154.05)
  BOTTOM w0.102: TP5003.1 81.44,149.86 80.79,150.51 80.79,153.3 v3(80.04,154.05)
EVAL_PWREN: length 7.5
  TOP w0.102: CPU1.BC13 79.8,147.95 79.81,147.94 79.81,146.83 80.12,146.52 80.12,144.58 79.74,144.2 79.74,142.24 v4(79.99,141.99)
  BOTTOM w0.102: TP5004.1 79.41,141.99 v4(79.99,141.99)
EVAL_PWRGD: length 47.4
  TOP w0.102: CPU1.BC17 83,147.96 82.99,147.95 82.99,147.12 v3(83.57,146.53) ; v4(83.47,119.3) 84.52,120.35 v1(84.79,120.35) 84.79,120.35 85.87,120.35 R79694.1
  L4 w0.127: v3(83.57,146.53) 85.11,145 86.31,145 90.98,140.32 91.36,139.95 91.36,134.87 85.62,129.13 82.93,129.13 78.66,124.87 78.66,120.37 79.73,119.3 v4(83.47,119.3)
EXT_RST#: length 4.9
  BOTTOM w0.102: U4101.41 102.47,59.62 102.2,59.88 R79706.2 102.2,61.02 v2(103.03,61.85) 103.22,61.66 R79705.1
F_USB0N: length 267
  TOP w0.102: v4(95.24,44.34) 95.08,44.19 95.08,43.13 95.24,42.98 95.24,38.01 C6729.1 95.24,36.79 95.24,35.28 95.45,35.06 TR10.1 ; v3(67.66,153.54) 67.66,153.82 68.49,154.65 70.05,154.65 CPU1.AR1
  L3 w0.102: v3(67.66,153.54) 67,154.2 66.45,154.2 65.93,154.72 61.8,154.72 61.3,154.23 56.55,154.23 55.74,153.42 53.26,153.42 48.95,149.12 37.26,149.12 35.64,147.5 25.03,147.5 21.8,150.72 19.13,150.72 v4(19.08,150.77) ; v4(32.2,48.87) 32.2,42.74 36.96,37.97 44.74,37.97 47.05,40.28 52.62,40.28 55.02,37.88 63.14,37.88 71.68,46.42 84.71,46.42 88.58,42.54 94.46,42.54 94.97,43.05 94.97,44.07 v4(95.24,44.34)
  L4 w0.102: v4(19.08,150.77) 19.16,150.7 19.21,150.7 20.03,149.87 20.03,149.28 23.83,145.48 23.83,140.43 25.47,138.79 31.16,138.79 34.93,135.01 34.93,123.02 35.35,122.6 35.35,119.53 35.53,119.35 35.53,115.42 35.6,115.35 37.03,113.92 37.03,99.02 37.07,98.98 37.07,92.04 38.24,90.88 38.24,87.01 35.86,84.63 35.86,73.63 28.43,66.2 28.43,56.1 32.68,51.85 32.68,49.35 v4(32.2,48.87)
  BOTTOM w0.102: v2(94.9,45.42) 95.24,45.09 v4(95.24,44.34)
F_USB0P: length 267.1
  TOP w0.102: v3(67.03,153.54) 68.39,154.9 70.23,154.9 70.53,154.6 CPU1.AR2 ; TR10.4 94.77,35.06 94.98,35.28 94.98,36.81 C6728.1 94.98,37.99 94.98,42.87 94.83,43.02 94.83,43.98 v4(94.47,44.34)
  L3 w0.102: v4(32.21,49.68) 32.67,49.23 32.67,48.56 32.43,48.32 32.43,42.83 37.06,38.2 44.64,38.2 46.95,40.51 52.71,40.51 55.11,38.11 63.05,38.11 71.58,46.65 84.8,46.65 88.68,42.77 94.37,42.77 94.74,43.14 94.74,44.07 v4(94.47,44.34) ; v4(19.08,150.01) 19.57,150.5 21.71,150.5 24.93,147.27 35.74,147.27 37.36,148.89 49.05,148.89 53.35,153.19 55.84,153.19 56.64,154 61.4,154 61.89,154.5 65.84,154.5 66.36,153.97 66.91,153.97 67.03,153.85 v3(67.03,153.54)
  L4 w0.102: v4(32.21,49.68) 32.46,49.92 32.46,51.75 28.2,56.01 28.2,66.29 35.63,73.72 35.63,84.72 38.01,87.1 38.01,90.78 36.84,91.95 36.84,98.89 36.8,98.93 36.8,113.82 35.5,115.12 35.47,115.16 35.3,115.32 35.3,119.26 35.12,119.44 35.12,122.51 34.7,122.93 34.7,134.92 31.06,138.56 25.38,138.56 23.6,140.34 23.6,145.39 19.8,149.18 19.8,149.78 19.57,150.01 v4(19.08,150.01)
  BOTTOM w0.102: v2(93.51,43.69) 93.63,43.69 94.28,44.34 v4(94.47,44.34)
F_USB1N: length 265.4
  TOP w0.102: 92.95,39.24 92.95,42.95 92.87,43.03 92.87,44.26 v4(92.95,44.34) ; 92.95,39.24 92.95,37.98 C6726.1 92.95,36.82 92.95,35.28 93.16,35.06 TR14.1 ; 92.95,39.24 v1(93.3,39.24) ; CPU1.AR4 72.13,154.6 71.83,154.3 71.33,154.3 71.08,154.04 70.68,154.04 70.63,154.1 70.37,154.1 70.28,154 69.39,154 v3(68.93,153.54)
  L3 w0.102: v4(92.95,44.34) 92.95,43.59 92.58,43.22 88.86,43.22 84.99,47.09 71.4,47.09 62.87,38.56 55.3,38.56 52.9,40.96 46.77,40.96 44.7,38.89 43.42,38.89 42.53,39.78 38.9,39.78 38.29,39.17 36.93,39.17 33.18,42.91 v4(33.18,48.67) ; v3(68.93,153.54) 67.59,154.89 66.84,154.89 66.33,155.4 56.76,155.4 55.46,154.1 52.98,154.1 48.67,149.79 36.99,149.79 35.36,148.17 25.31,148.17 22.98,150.5 22.98,151.87 22.36,152.49 21.08,152.49 20.45,151.87 v4(20.45,151.21)
  L4 w0.102: v4(20.45,151.21) 20.48,151.18 20.48,149.46 24.27,145.67 24.27,140.62 25.66,139.23 31.34,139.23 35.92,134.65 35.92,119.82 36,119.74 36,116.29 37.47,114.81 37.47,101.07 38.31,100.23 38.31,91.65 38.68,91.28 38.68,86.58 36.3,84.2 36.3,73.44 28.87,66.02 28.87,56.46 33.16,52.17 33.16,48.69 v4(33.18,48.67)
F_USB1P: length 265.4
  TOP w0.102: v1(92.31,40.16) 92.7,40.16 ; 92.7,40.16 92.7,42.85 92.62,42.92 92.62,43.91 v4(92.19,44.34) ; 92.7,40.16 92.7,37.99 C6727.1 92.7,36.81 92.7,35.28 92.48,35.06 TR14.4 ; CPU1.AR3 71.7,154.66 71.57,154.79 71.33,154.79 71.2,154.66 71.2,154.46 70.99,154.25 70.77,154.25 70.71,154.31 70.29,154.31 70.19,154.21 68.49,154.21 68.3,154.02 v3(68.3,153.54)
  L3 w0.102: v4(21.22,151.21) 21.14,151.21 20.68,151.66 20.68,151.77 21.17,152.26 22.27,152.26 22.75,151.77 22.75,150.4 25.21,147.94 35.46,147.94 37.08,149.56 48.77,149.56 53.07,153.87 55.56,153.87 56.86,155.17 66.23,155.17 66.74,154.66 67.49,154.66 68.3,153.85 v3(68.3,153.54) ; v4(92.19,44.34) 92.72,43.81 92.72,43.68 92.48,43.45 88.96,43.45 85.08,47.32 71.31,47.32 62.77,38.79 55.39,38.79 52.99,41.19 46.67,41.19 44.6,39.12 43.52,39.12 42.63,40.01 38.8,40.01 38.19,39.4 37.02,39.4 33.41,43.01 33.41,48.09 33.7,48.39 33.7,49.21 v4(33.64,49.28)
  L4 w0.102: v4(21.22,151.21) 20.71,150.7 20.71,149.55 24.5,145.76 24.5,140.71 25.75,139.46 31.44,139.46 36.15,134.74 36.15,119.92 36.23,119.84 36.23,116.38 37.7,114.91 37.7,101.16 38.54,100.32 38.54,91.74 38.91,91.37 38.91,86.49 36.53,84.11 36.53,73.35 29.1,65.92 29.1,56.55 33.39,52.27 33.39,49.38 33.49,49.28 v4(33.64,49.28)
F_USB3N: length 231.1
  TOP w0.102: v3(68.97,155.4) 69.38,155.81 69.77,155.81 69.88,155.69 70.31,155.69 70.32,155.7 70.68,155.7 70.69,155.69 71.11,155.69 71.12,155.7 71.79,155.7 72.29,156.2 CPU1.AN4 ; TR9.4 32.12,14.44 31.88,14.68 31.88,15.13 33.26,16.51 33.26,17.27 34.02,18.03 34.02,21.52 35.03,22.53 35.03,23.46 v4(35.29,23.72) ; v4(18.98,152.03) 18.98,151.84 v1(18.32,151.18)
  L3 w0.102: v3(68.97,155.4) 67.62,156.75 62.05,156.75 61.9,156.9 52.99,156.9 49.82,160.07 45.3,160.07 44.87,159.64 44.87,152.78 42.55,150.47 36.71,150.47 35.09,148.84 25.59,148.84 23.66,150.78 23.66,152.15 22.64,153.16 20.57,153.16 19.88,152.47 19.42,152.47 v4(18.98,152.03)
  L4 w0.102: v4(18.98,152.03) 18.63,151.68 18.63,149.34 23.15,144.81 23.15,140.15 25.19,138.11 30.88,138.11 34.25,134.74 34.25,122.76 34.68,122.32 34.68,119.25 34.86,119.07 34.86,115.14 35.25,114.74 36.36,113.64 36.36,98.75 36.4,98.7 36.4,91.62 37.02,91 37.02,87.15 35.19,85.32 35.19,81.43 34.09,80.34 34.09,72.82 27.67,66.39 27.67,55.89 31.68,51.87 31.68,43.8 28.53,40.65 28.53,31.31 29.8,30.04 29.8,30.04 30.07,29.77 30.07,29.77 30.21,29.63 30.54,29.63 31.29,28.88 31.29,28.56 33.76,26.09 34.7,26.09 35.02,25.77 35.02,23.99 v4(35.29,23.72)
  BOTTOM w0.102: v2(36.38,23.33) 36.36,23.35 36.36,23.37 36,23.72 v4(35.29,23.72)
F_USB3P: length 230.6
  TOP w0.102: CPU1.AN3 71.41,155.91 71.03,155.91 71.03,155.9 70.77,155.9 70.77,155.91 70.23,155.91 70.23,155.9 69.97,155.9 69.86,156.01 68.94,156.01 v3(68.33,155.4) ; v4(19.74,152.02) 20.76,152.02 v1(20.76,152.01) ; TR9.1 31.44,14.47 31.63,14.66 31.63,15.24 33,16.61 33,17.38 33.76,18.14 33.76,21.63 34.77,22.64 34.77,23.43 34.5,23.7 v4(34.5,23.72)
  L3 w0.102: v4(19.74,152.02) 20.66,152.93 22.54,152.93 23.43,152.05 23.43,150.68 25.49,148.62 35.18,148.62 36.8,150.24 42.65,150.24 45.1,152.69 45.1,159.55 45.39,159.84 49.72,159.84 52.9,156.67 61.8,156.67 61.95,156.52 67.53,156.52 68.33,155.71 v3(68.33,155.4)
  L4 w0.102: v4(19.74,152.02) 19.27,152.49 18.79,152.49 18.4,152.1 18.4,149.25 22.92,144.72 22.92,140.06 25.1,137.89 30.78,137.89 34.02,134.65 34.02,122.66 34.45,122.23 34.45,119.16 34.63,118.98 34.63,115.04 35.16,114.52 36.13,113.54 36.13,98.65 36.17,98.61 36.17,91.52 36.79,90.91 36.79,87.24 34.96,85.41 34.96,81.53 33.87,80.43 33.87,72.91 27.44,66.48 27.44,55.79 31.45,51.78 31.45,43.89 28.3,40.74 28.3,31.41 28.3,31.41 28.3,31.22 29.57,29.95 29.57,29.94 29.97,29.54 29.98,29.54 30.12,29.4 30.44,29.4 31.06,28.78 31.06,28.46 33.66,25.86 34.61,25.86 34.79,25.67 34.79,24.04 34.5,23.75 v4(34.5,23.72)
  BOTTOM w0.102: v2(33.69,23.75) 33.69,23.75 33.71,23.72 v4(34.5,23.72)
F_USB4N: length 177.6
  TOP w0.102: TR1.1 151.03,197.95 150.5,198.48 150.5,199.22 v4(151.29,200) ; CPU1.AM2 70.8,156.5 69.97,156.5 69.69,156.21 68.51,156.21 v3(67.7,155.4)
  L3 w0.102: v4(45.55,159.36) 45.82,159.09 49.63,159.09 52.5,156.22 61.62,156.22 61.77,156.07 67.02,156.07 v3(67.7,155.4)
  BOTTOM w0.102: 45.76,162.69 45.76,163.5 45,164.27 45,169.35 44.64,169.71 44.64,175.62 48.71,179.69 51.98,179.69 54.35,182.06 54.35,196.79 54.93,197.37 66.46,197.37 69.88,200.79 81.45,200.79 82.24,201.57 88.7,201.57 89.87,202.74 101.96,202.74 104.53,200.18 148.19,200.18 148.9,200.89 150.69,200.89 151.04,200.54 151.04,200.26 v4(151.29,200) ; 45.76,162.69 v2(45.42,162.69) ; 45.76,162.69 45.76,159.56 v4(45.55,159.36)
F_USB4P: length 177.6
  TOP w0.102: v3(67.06,155.4) 67.06,155.68 67.19,155.81 67.75,155.81 68.41,156.47 69.58,156.47 69.87,156.76 70.38,156.76 70.5,156.88 CPU1.AM1 ; TR1.4 152.03,197.27 151.6,197.7 150.92,197.7 150.25,198.37 150.25,199.32 150.6,199.68 150.6,199.9 150.53,199.98 v4(150.53,200)
  L3 w0.102: v3(67.06,155.4) 67.06,155.71 66.93,155.85 61.67,155.85 61.53,155.99 52.41,155.99 49.54,158.86 45.82,158.86 v4(45.55,158.6)
  BOTTOM w0.102: 54.6,183.26 54.6,181.95 52.09,179.44 48.82,179.44 44.89,175.51 44.89,169.82 45.25,169.46 45.25,164.37 46.01,163.61 46.01,159.05 v4(45.55,158.6) ; 54.6,183.26 54.6,196.68 55.04,197.12 66.57,197.12 69.98,200.53 81.56,200.53 82.34,201.32 88.81,201.32 89.98,202.49 101.86,202.49 104.42,199.92 148.3,199.92 149.01,200.63 150.58,200.63 150.78,200.43 150.78,200.26 v4(150.53,200) ; 54.6,183.26 v2(54.9,183.26)
F_USB5N: length 125.9
  TOP w0.102: v3(68.33,157.15) 68.96,157.79 70.09,157.79 CPU1.AL1 ; v4(104.67,206.63) 104.71,206.59 TR12.4
  L3 w0.102: v4(43.57,161.19) 44.24,160.52 50.21,160.52 51.24,159.48 52.52,158.2 57.28,158.2 58.08,157.41 64.14,157.41 64.33,157.22 66.55,157.22 66.89,157.56 68.24,157.56 68.33,157.47 v3(68.33,157.15)
  BOTTOM w0.102: v2(102.61,206.73) 102.61,206.38 ; 102.61,206.38 102.1,206.38 100.66,204.94 89.76,204.94 87.1,202.28 81.95,202.28 81.16,201.49 69.59,201.49 67.48,199.38 55.32,199.38 53.65,197.71 53.65,187.96 49.56,183.87 49.56,181.56 43.92,175.92 43.92,167.48 44.3,167.11 44.3,162.43 43.88,162 43.88,161.49 v4(43.57,161.19) ; 102.61,206.38 104.41,206.38 v4(104.67,206.63)
F_USB5P: length 125.9
  TOP w0.102: v3(68.97,157.15) 68.97,157.43 69.12,157.58 69.75,157.58 69.83,157.5 70.6,157.5 CPU1.AL2 ; v4(104.67,205.87) 104.71,205.91 TR12.1
  L3 w0.102: v3(68.97,157.15) 68.97,157.25 68.43,157.79 66.8,157.79 66.45,157.44 64.43,157.44 64.23,157.63 58.17,157.63 57.38,158.43 52.61,158.43 51.4,159.65 50.3,160.74 44.34,160.74 44.26,160.82 44.26,161.12 v4(44.33,161.19)
  BOTTOM w0.102: 100.46,204.69 100.77,204.69 102.2,206.12 104.41,206.12 v4(104.67,205.87) ; 100.46,204.69 v2(100.46,204.32) ; 100.46,204.69 89.87,204.69 87.21,202.02 82.06,202.02 81.27,201.23 69.69,201.23 67.58,199.12 55.42,199.12 53.91,197.61 53.91,187.86 49.82,183.77 49.82,181.46 44.18,175.82 44.18,167.59 44.55,167.21 44.55,162.32 44.13,161.9 44.13,161.39 v4(44.33,161.19)
F_USB6N: length 158
  TOP w0.102: v4(162.7,108.33) 162.74,108.37 TR3.4 ; v3(67.06,157.15) 67.06,157.28 67.97,158.19 69.78,158.19 69.91,158.32 70.35,158.32 70.37,158.3 70.63,158.3 70.66,158.33 71.14,158.33 71.36,158.12 72.19,158.12 CPU1.AL4
  BOTTOM w0.102: v2(163.47,110.35) 163.25,110.12 ; 163.25,110.12 163.86,109.5 163.86,108.86 163.59,108.58 162.96,108.58 v4(162.7,108.33) ; 163.25,110.12 161.94,111.43 153.04,111.43 149.64,114.83 127.7,114.83 125.73,116.8 123.17,116.8 120.5,119.46 114.53,119.46 110.39,123.6 88.99,123.6 83.85,128.74 79.78,128.74 74.88,133.65 64.75,133.65 57.71,140.68 57.71,143.5 54.59,146.62 54.59,152.62 56,154.04 56,155.68 58.19,157.86 66.94,157.86 67.06,157.74 v3(67.06,157.15)
F_USB6P: length 158
  TOP w0.102: v3(67.7,157.15) 67.58,157.27 67.58,157.44 68.13,157.99 69.86,157.99 69.99,158.12 70.27,158.12 70.29,158.09 70.71,158.09 70.74,158.12 71.06,158.12 71.27,157.91 71.27,157.53 71.4,157.4 71.58,157.4 71.71,157.53 71.71,157.79 CPU1.AL3 ; v4(162.7,109.09) 162.74,109.05 TR3.1
  BOTTOM w0.102: v2(161.19,110.82) 161.19,111.18 ; 161.19,111.18 152.94,111.18 149.54,114.58 127.59,114.58 125.63,116.54 123.06,116.54 120.39,119.21 114.43,119.21 110.29,123.35 88.88,123.35 83.74,128.49 79.68,128.49 74.78,133.39 64.64,133.39 57.46,140.58 57.46,143.4 54.34,146.52 54.34,152.73 55.75,154.14 55.75,155.78 58.08,158.12 67.04,158.12 67.31,157.84 67.31,157.53 v3(67.7,157.15) ; 161.19,111.18 161.83,111.18 163.61,109.4 163.61,108.96 163.48,108.84 162.96,108.84 v4(162.7,109.09)
F_USB7N: length 162.8
  TOP w0.102: v3(68.33,158.6) 68.33,158.95 68.59,159.21 69.85,159.21 69.97,159.1 70.28,159.1 70.29,159.11 70.78,159.11 70.98,158.9 71.18,158.9 71.28,159 71.28,159.16 71.04,159.4 CPU1.AJ2 ; TR4.4 163.62,106.25 163.49,106.38 162.83,106.38 162.7,106.25 v4(162.7,106.17)
  BOTTOM w0.102: v2(158.27,109.37) 158.03,109.12 ; 158.03,109.12 156.53,110.62 152.77,110.62 149.25,114.13 127.41,114.13 125.44,116.1 122.88,116.1 120.21,118.77 114.24,118.77 110.1,122.9 88.7,122.9 83.56,128.04 79.5,128.04 74.59,132.95 63.55,132.95 60.28,136.22 60.28,137.13 57.01,140.4 57.01,142.27 53.75,145.54 53.75,154.82 55.39,156.46 55.77,156.46 57.87,158.56 64.1,158.56 64.93,159.38 68.56,159.38 68.71,159.23 68.71,158.98 v3(68.33,158.6) ; 158.03,109.12 161.61,105.54 163.28,105.54 163.61,105.87 163.61,106.55 163.48,106.68 163.1,106.68 162.7,106.28 v4(162.7,106.17)
F_USB7P: length 162.7
  TOP w0.102: TR4.1 162.74,106.89 v4(162.7,106.93) ; CPU1.AK2 70.93,158.6 70.63,158.9 70.37,158.9 70.37,158.89 69.88,158.89 69.77,159.01 69.37,159.01 v3(68.97,158.6)
  BOTTOM w0.102: 163.86,106.27 163.86,105.76 163.38,105.28 161.51,105.28 156.43,110.36 152.66,110.36 149.14,113.88 127.3,113.88 125.34,115.84 122.77,115.84 120.1,118.51 114.14,118.51 110,122.65 88.6,122.65 83.45,127.79 79.39,127.79 74.49,132.69 63.45,132.69 60.03,136.11 60.03,137.02 56.76,140.29 56.76,142.17 53.49,145.43 53.49,154.92 55.28,156.71 55.67,156.71 57.77,158.81 64,158.81 64.82,159.64 68.66,159.64 68.97,159.34 v3(68.97,158.6) ; 163.86,106.27 v2(164.17,106.27) ; 163.86,106.27 163.86,106.66 163.59,106.93 v4(162.7,106.93)
FALL_INT2: length 8.7
  TOP w0.102: 82.73,63.1 82.73,62.91 82.61,62.79 82.15,62.79 82.08,62.87 ; 82.73,63.1 v4(83.22,62.61) ; 82.73,63.1 Q6701.3 ; 82.08,62.87 Q6701.2 ; 82.08,62.87 82.08,61.94 81.99,61.85 81.31,61.85 81.04,62.12 81.04,63.25 R6703.2
  BOTTOM w0.102: v4(83.22,62.61) 83.22,61.85 v2(83.35,61.72)
FCH_0.775_S5: length 247.1
  TOP w0.356: CPU1.AP13 v3(80,154.82) 79.72,154.82 CPU1.AR12
  L3 w0.508: v4(135.47,120.73) 135.97,120.22 160.43,120.22 160.76,120.55 162.06,120.55 165.44,123.93 165.44,139.27 165.52,139.35 165.52,155.89 165.44,155.96 165.44,183.08 164.3,184.21 162.69,184.21 155.48,191.43 155.48,199.64 156.62,200.79 159.37,200.79 161.27,202.69 v4(161.27,210.12) ; v3(80,154.82) 79.95,154.82 79,153.87 79,150.76 78.39,150.15 78.39,149.86 76.41,147.88 76.41,146.08 73.15,142.82 73.15,142.39 72.98,142.22 72.98,140.01 77.96,135.03 77.96,134.11 82.15,129.92 83.6,129.92 90.06,123.46 119.88,123.46 131.71,111.63 v4(135.67,111.63)
  L4 w0.508: v4(135.47,120.73) 135.67,120.52 v4(135.67,111.63)
  BOTTOM w0.406: Q6704.5 158.66,215.26 C6715.1 159.28,214.62 Q6704.6 ; Q6703.5 158.66,210.95 C6714.1 159.28,210.3 Q6703.6
  BOTTOM w0.508: C6715.1 C1956.1 v2(160.56,212.55) 160.56,211.96 160.43,211.84 C6712.1 ; C1954.1 80,155.43 v3(80,154.82) 79.67,154.82 C1953.1 ; C6712.1 159.48,210.12 C6714.1 ; C6712.1 v4(161.27,210.12)
FCH_S5_POWER_COMP: length 20
  TOP w0.102: Q4701.1 149.12,210.71 148.37,211.46 v4(148.37,211.96) ; R79724.1 147.48,200.6 v1(147.48,199.64) 147.23,199.39 146.53,199.39 R4706.1 R79725.2 146.72,200.98 U178.2 146.72,204.63 148.23,206.14 148.86,206.14 149.26,206.53 U178.5 149.26,207.9 148.37,208.79 v4(148.24,208.79)
  L3 w0.127: v4(148.24,208.79) 148.97,209.51 148.97,211.37 v4(148.37,211.96)
FFS_INT1: length 316.7
  TOP w0.102: v3(67.7,158.6) 68.51,159.41 69.94,159.41 69.95,159.4 CPU1.AJ1 ; v4(149.71,46.15) 149.71,46.02 149.66,45.97 U109.110 ; v4(81.1,67.87) 81.19,67.78 81.19,67.44 80.86,67.11 v1(80.86,67.04) 80.74,66.93 80.39,66.93 R79658.2 79.6,65.77 79.03,65.2 79.03,64.21 78.42,63.6 77.99,63.6 v4(77.76,63.37) 77.38,63.75 76.78,63.75 76.46,64.07 R6702.2
  L3 w0.127: v4(80.93,52.03) 81.44,52.54 86.46,52.54 90.97,48.02 96.23,48.02 97.25,47 100.58,47 100.9,46.68 110.83,46.68 111.39,47.24 111.67,47.24 121.35,47.24 122.6,45.99 129.62,45.99 130.64,44.96 133.6,44.96 133.95,44.62 139.18,44.62 140.79,46.23 144.62,46.23 145.78,45.07 148.6,45.07 149.65,46.13 149.69,46.13 v4(149.71,46.15) ; v3(74.46,79.5) 74.07,79.12 51.64,79.12 49.49,76.97 45.38,76.97 41.38,80.97 41.38,107.18 38.15,110.42 38.15,115.94 36.86,117.23 36.86,133.67 30.7,139.83 18.44,139.83 16.66,141.61 16.66,152.29 14.7,154.24 14.7,158.47 13.77,159.4 13.77,163.51 16.92,166.66 24.49,166.66 27.62,163.54 33.64,163.54 34.12,164.02 38.16,164.02 39.5,162.68 50.45,162.68 52.54,160.59 57.37,160.59 58.76,159.19 64.76,159.19 64.86,159.3 67,159.3 v3(67.7,158.6)
  L4 w0.127: v3(74.46,79.5) 77.66,76.3 77.66,65.7 77.03,65.07 77.03,64.02 77.55,63.5 77.63,63.5 v4(77.76,63.37) ; v4(81.1,67.87) 81.1,67.8 81.06,67.76 81.06,52.16 v4(80.93,52.03)
FFS_INT1_C: length 2.7
  TOP w0.102: R79658.1 78.71,66.69 79.03,67.01 v1(79.03,67.11) U6701.11
FFS_INT2_APU: length 223.1
  TOP w0.102: v3(73.04,158.51) 73.07,158.51 73.3,158.74 CPU1.AK5 ; v4(78.38,64.21) R79657.2
  L3 w0.127: v3(73.04,158.51) 72.81,158.51 72.47,158.17 71.36,158.17 69.97,159.55 64.76,159.55 64.66,159.45 58.87,159.45 57.47,160.85 52.64,160.85 50.55,162.94 39.6,162.94 38.27,164.27 34.02,164.27 33.53,163.79 27.72,163.79 24.6,166.92 16.22,166.92 13.46,164.16 13.46,155.12 16.4,152.18 16.4,141.41 18.24,139.57 30.6,139.57 36.61,133.56 36.61,117.12 37.89,115.84 37.89,110.31 41.13,107.07 41.13,80.77 45.21,76.68 49.56,76.68 51.62,78.74 74.84,78.74 v3(75.47,79.38)
  L4 w0.127: v4(78.38,64.21) 78.38,65.54 78.06,65.87 78.06,76.79 v3(75.47,79.38)
  BOTTOM w0.102: v2(77.85,64.95) 78.11,64.95 78.38,64.68 v4(78.38,64.21)
FFS_INT2_C: length 20
  TOP w0.102: U6701.9 78.03,67.57 R6704.2 ; R6704.2 R79668.1 ; R6704.2 77.62,67.04 78.01,66.65 78.01,65.54 R79657.1 77.49,64.27 77.5,64.26 v4(77.5,64.21) ; Q6701.5 82.08,66.12 82.46,66.5 83.38,66.5 R6706.1 84.77,66.95 v1(85.07,66.65) 85.07,66.22 84.01,65.15 v4(84.01,64.49)
  L3 w0.127: v4(77.5,64.21) 77.68,64.21 78.15,63.74 78.73,63.74 79.48,64.49 v4(84.01,64.49)
FFS_INT2_Q: length 208.5
  TOP w0.102: Q6701.6 81.42,66.02 82.3,66.9 82.9,66.9 R6706.2 R6705.2 83.87,68.91 85.63,68.91 86.44,68.1 v1(86.44,65.56) 86.44,64.24 85.38,63.17 v4(84.01,63.17)
  L3 w0.127: v4(84.01,63.17) 83.01,63.17 81.82,61.97 74.23,61.97 70.33,65.87 68.56,65.87 65.98,63.3 63.76,63.3 63.1,62.64 60.64,62.64 57.82,65.46 40.51,65.46 38.75,67.21 35.27,67.21 30.53,71.95 30.53,72.1 v4(29.29,73.33)
  L4 w0.127: v4(29.29,73.33) 29.29,74.17 29.93,74.8 29.93,76.71 30.89,77.67 30.89,84.9 31.34,85.34 31.34,92.01 32.74,93.42 32.74,104.35 32.29,104.8 32.29,112.47 32.53,112.71 32.53,114.01 31.83,114.71 31.83,133.03 29.03,135.83 23.12,135.83 18.77,140.18 18.77,141.92 18.25,142.44 18.25,146.48 16.34,148.39 16.34,152.63 15.25,153.72 15.25,157.2 15.89,157.84 15.89,162.5 15.17,163.22 15.17,166.38 15.78,167 15.78,181.13 13.75,183.16 13.75,188.25 SATAP1.5
FP_RST_N: length 18.5
  TOP w0.102: CPU1.AF2 71,162.1 70.32,162.1 70.31,162.09 69.78,162.09 69.68,162.2 69.28,162.2 v3(68.88,161.79) ; v4(58.33,160.66) 58.33,160.38 57.59,159.64 C1735.1 R2004.1 R2012.2 R1679.1
  BOTTOM w0.102: v3(68.88,161.79) 68.62,161.54 v2(67.93,161.54) 59.21,161.54 v4(58.33,160.66)
FWH_ID0: length 5.5
  TOP w0.102: LPC1.6 117.7,56.67 R1700.2 v1(117.7,61.34)
GFX_SVC: length 16.7
  TOP w0.102: R1998.1 R1994.1 v4(82.96,193.4) ; CPU1.B16 82.2,181.07 81.9,181.37 81.9,181.68 81.91,181.69 81.91,182.11 81.71,182.31 81.71,184.01 v3(80.93,184.78)
  L4 w0.127: v3(80.93,184.78) 82.24,186.09 82.24,192.67 v4(82.96,193.4)
  BOTTOM w0.102: v4(82.96,193.4) v2(82.96,194.21)
GFX_SVD: length 5.7
  TOP w0.102: R2000.1 R1995.1 83.78,185.92 v1(83.78,185.14) 83.78,184.53 83.8,184.51 83.8,182.51 83.8,182.51 CPU1.A18
GFX_SVT: length 16.5
  TOP w0.102: v3(80.93,184.15) 81.5,183.58 81.5,182.22 81.7,182.03 81.7,181.77 81.4,181.47 CPU1.B15 ; v4(80.93,192.63) 81.39,193.09 81.39,193.79 R2002.1 R1993.1
  L4 w0.127: v4(80.93,192.63) 80.17,191.87 80.17,185.82 80.46,185.53 80.46,184.62 v3(80.93,184.15)
  BOTTOM w0.102: v2(80.2,193.01) 80.58,192.63 v4(80.93,192.63)
GFX_VCORE: length 66.3
  TOP w0.356: CPU1.K7 74.9,174.8 v3(75.3,175.2) 75.7,175.6 CPU1.J8 ; CPU1.K19 v3(85.4,174) CPU1.L19 CPU1.N21 v3(85.4,171.6) CPU1.P19 CPU1.T21 v3(85.4,169.2) CPU1.U19 ; CPU1.K12 CPU1.K13 v3(80.6,174) ; CPU1.P8 75.7,170.6 v3(75.3,170.2) CPU1.T7 ; v3(80.6,174) CPU1.L13 CPU1.N15 v3(80.6,171.6) CPU1.P13 CPU1.T15 v3(80.6,169.2) CPU1.U13 ; v3(80.6,174) CPU1.K15 ; CPU1.J9 77.2,175.5 v3(77.6,175.9) 78,175.5 CPU1.J11 ; CPU1.N12 v3(78.2,171.6) 78.2,170.4 CPU1.T12 v3(78.2,169.2) ; v3(80.13,177.4) 80.43,177.1 CPU1.G14 ; v3(87.8,174) CPU1.L22 87.8,172.8 v3(87.8,171.6) CPU1.P22 87.8,170.4 v3(87.8,169.2) CPU1.U22 ; CPU1.N7 v3(74.5,171.8) ; v3(81.33,178.2) 81.63,177.9 CPU1.F15 ; CPU1.L8 v3(75.3,173.8) ; CPU1.U16 v3(83,169.2) CPU1.T18 CPU1.P16 v3(83,171.6) CPU1.N18 CPU1.L16 v3(83,174) CPU1.K16
  TOP w0.38: v3(78.89,178.2) 79.1,178.2 CPU1.F12 ; CPU1.G11 77.91,177.39 v3(77.5,177.39)
  TOP w0.508: 54.73,187.83 PT5401.1 ; PT5401.1 56.84,187.83 ; PT5401.1 55.79,188.89 ; PT5402.1 63.66,196.76 ; PT5402.1 62.61,195.71 ; PT5402.1 64.71,195.71 ; PT5402.1 63.66,194.65 ; 55.79,194.65 PT5403.1 ; PT5403.1 54.73,195.71 ; PT5403.1 56.84,195.71 ; PT5403.1 55.79,196.76
  BOTTOM w0.508: PT5401.1 56.84,187.83 ; PT5401.1 55.79,186.78 ; PT5401.1 55.79,188.89 ; 63.66,194.65 PT5402.1 ; PT5402.1 62.61,195.71 ; PT5402.1 64.71,195.71 ; 56.84,195.71 PT5403.1 55.79,194.65
  vias: v2(60.33,189.76) v2(76.74,173.1) v2(96.83,176.4) v2(101.86,198.07) v7(55.94,194.06) v7(56.01,192.84) v7(57.54,195.94) v7(57.56,194.64) v7(57.61,193.4) v7(57.61,191.95) v7(57.64,190.53) v7(57.59,189.26) v7(59.6,196.09) v7(59.74,194.37) v7(59.72,192.91) v7(59.72,191.52) v7(61.55,195.86) v7(61.6,194.51) v7(61.65,193.19)
GFX_VRM_PWRGD: length 4.5
  TOP w0.102: v4(84.01,215.19) v1(84.01,214.25)
  BOTTOM w0.102: PR5463.2 84.34,215.52 v4(84.01,215.19) 83.55,215.65 82.74,215.65 82.61,215.77 PU5407.7
GP11: length 5.2
  TOP w0.102: R679.1 161.28,61.09 v1(160.59,61.09) 159.62,60.12 159.62,59.3 159.34,59.03 159.34,58.6 159.12,58.38 U109.31
GP14: length 3.4
  TOP w0.102: U109.28 159.45,57.18 v4(159.7,57.43)
  BOTTOM w0.102: v4(159.7,57.43) 159.93,57.66 v5(160.61,57.66) R90068.1
GP24: length 3.6
  TOP w0.102: U109.20 159.9,53.98 160.03,53.85 v1(160.58,53.85) 160.94,53.85 161.64,54.55 R297.1
GP26: length 3.5
  TOP w0.102: R1188.1 161.58,52.51 160.65,52.51 v1(160.64,52.53) 160.28,52.53 159.63,53.18 U109.18
GP27: length 6.1
  TOP w0.102: v1(163.56,52.48) 163.1,52.02 162.16,52.02 161.71,51.56 R1864.1 161.34,51.87 160.4,51.87 160.15,52.11 160.15,52.17 159.55,52.78 U109.17
GP32: length 4.5
  TOP w0.102: R307.2 160.8,51.38 v4(160.66,51.38) 160.53,51.52 159.51,51.52 159.45,51.58 U109.14
  BOTTOM w0.102: v2(161.32,51.86) 160.85,51.38 v4(160.66,51.38)
GP33: length 6.4
  TOP w0.102: U109.13 160.22,51.18 160.47,50.93 160.56,50.93 161.2,50.29 161.2,50.19 161.3,50.09 161.4,50.09 161.77,49.72 R80222.1 162.33,50.09 163.18,50.09 v1(163.53,50.44)
GP34: length 4.5
  TOP w0.102: U109.12 159.12,50.78 159.34,50.55 159.34,50.49 159.92,49.91 v1(160.69,49.91) 160.69,49.66 161.77,48.58 R80221.1
GP63: length 4.4
  TOP w0.102: R1863.1 161.24,45.47 v1(160.69,46.02) 160.69,46.05 160.7,46.06 160.7,46.74 160.26,47.18 U109.3
GPU_DMINUS: length 91.7
  TOP w0.127: v4(93.43,63.78) 93.15,64.06 92.57,64.06 90.71,65.91 90.71,72.26 90.36,72.62 90.36,81.81 86.77,85.39 86.08,85.39 RT2.2
  L3 w0.127: v4(93.43,63.78) 93.61,63.96 94.14,63.96 96.82,61.28 106.25,61.28 108.22,61.28 109.13,62.18 118.75,62.18 121.08,64.5 136.57,64.5 v4(136.94,64.14)
  BOTTOM w0.127: 138.09,58.04 138.09,64.31 137.96,64.45 137.26,64.45 v4(136.94,64.14) ; 138.09,58.04 138.09,55.59 138.78,54.9 140.46,53.23 142.77,53.23 143.29,52.7 143.29,52.53 143.12,52.36 C524.2 R651.2 ; 138.09,58.04 v2(137.78,58.04)
GPU_DPLUS: length 95.9
  TOP w0.127: v4(93.47,64.57) 93.21,64.31 92.67,64.31 90.97,66.02 90.97,72.37 90.61,72.72 90.61,81.92 86.88,85.65 86.08,85.65 RT2.1 ; U109.85 144.56,50.78 v4(144.69,50.65)
  L3 w0.127: v4(93.47,64.57) 93.82,64.21 94.25,64.21 96.93,61.53 106.14,61.53 108.12,61.53 109.02,62.43 118.65,62.43 120.97,64.76 136.67,64.76 v4(136.94,65.02)
  BOTTOM w0.127: v2(138.62,62.81) 138.35,62.81 ; 138.35,62.81 138.35,55.69 140.56,53.48 142.87,53.48 143.54,52.81 143.54,52.42 143.23,52.11 143.06,52.11 C524.1 142.43,51.33 142.64,51.12 142.95,51.12 143.26,50.8 143.26,50.48 R658.1 144.15,50.42 144.38,50.65 v4(144.69,50.65) ; 138.35,62.81 138.35,64.42 138.06,64.71 137.26,64.71 v4(136.94,65.02)
HDMI1_CLK_APU: length 291
  TOP w0.102: CPU1.F7 74.3,178.2 v3(74,178.2) ; v4(134.9,28.35) 134.71,28.53 134.71,28.97 R79639.2
  L4 w0.127: v4(134.9,28.35) 138.72,32.17 138.72,40.3 138.8,40.38 138.8,42.53 138.72,42.61 138.72,52.28 139.43,52.99 139.43,60.02 142.43,63.02 142.43,71.26 147.43,76.26 147.43,77.82 148.06,78.44 148.06,88.62 148.91,89.48 148.91,97.7 148.06,98.55 148.06,106.87 150.2,109.01 150.2,121.96 154.5,126.27 154.5,130.55 155.16,131.21 155.16,191.6 151.82,194.94 109.05,194.94 104.07,199.91 101.12,199.91 96.41,204.63 76.02,204.63 69.97,198.58 69.97,187.5 70.44,187.03 70.76,187.03 74.2,183.58 74.2,181.05 74.62,180.63 74.62,179.87 74.46,179.7 74.46,178.39 74.27,178.2 v3(74,178.2)
  BOTTOM w0.102: v4(134.9,28.35) 134.9,29.22 v2(134.86,29.26)
HDMI1_CLK_APU_SRC: length 3.6
  TOP w0.102: R79639.1 134.71,30.05 133.92,30.84 v1(133.92,31.32) 133.92,32.23 133.74,32.41 U118.38
HDMI1_CLK_CON: length 24.7
  TOP w0.102: U118.32 131.34,32.37 v4(129.82,30.85) R2083.2 ; v4(124.9,39.89) U117.1 U117.10 121.97,39.89 121.51,39.43 119.82,39.43 119.44,39.82 HDMI1.15
  L4 w0.127: v4(124.9,39.89) 124.9,37.94 127.59,35.24 127.59,30.97 127.72,30.85 v4(129.82,30.85)
  BOTTOM w0.102: v4(124.9,39.89) 124.13,39.89 v2(124.09,39.85)
HDMI1_DATA_APU: length 291.1
  TOP w0.102: R79640.2 v4(135.91,28.34) ; v3(74,179) 74.3,179 CPU1.E7
  L4 w0.127: v3(74,179) 74,179.32 73.72,179.6 73.24,179.6 73.11,179.73 73.11,180.37 73.24,180.49 73.47,180.49 73.67,180.7 73.67,183.79 72.04,185.42 71.69,185.42 69.72,187.39 69.72,198.69 75.91,204.88 96.51,204.88 101.23,200.16 104.18,200.16 109.15,195.19 151.93,195.19 155.41,191.71 155.41,131.1 154.75,130.45 154.75,126.16 150.45,121.86 150.45,108.9 148.31,106.76 148.31,98.66 149.16,97.81 149.16,89.37 148.31,88.52 148.31,78.34 147.69,77.71 147.69,76.09 142.69,71.09 142.69,62.91 139.68,59.91 139.68,52.89 139.05,52.25 139.05,42.64 139.05,42.63 139.05,40.27 138.97,40.19 138.97,32.06 135.91,29 v4(135.91,28.34)
  BOTTOM w0.102: v2(136.76,29.11) 135.99,28.34 v4(135.91,28.34)
HDMI1_DATA_APU_N0: length 294.6
  TOP w0.102: v3(71.45,181.45) 71.45,181.36 71.58,181.23 71.77,181.23 71.9,181.36 CPU1.A3 ; v4(139.62,33.35) C3371.1
  L4 w0.127: v4(139.62,33.35) 139.93,33.04 141.15,33.04 142.27,34.16 142.27,49.51 142.75,49.99 142.75,58.54 145.09,60.88 145.09,68.87 150.72,74.5 150.72,81.96 151.32,82.57 151.32,88.03 151.71,88.41 151.71,95.82 152.41,96.53 152.41,105.51 153.66,106.76 153.66,108.8 155.62,110.75 155.62,117.69 157.01,119.08 157.01,123.81 158.53,125.33 158.53,156.25 159.24,156.95 159.24,192.25 158.14,193.34 157.21,193.34 152.96,197.6 110.15,197.6 105.18,202.57 102.23,202.57 97.37,207.42 74.76,207.42 66.14,198.81 66.14,186.17 70.44,181.87 71.36,181.87 71.45,181.78 v3(71.45,181.45)
  BOTTOM w0.102: v2(140.55,32.75) 139.95,33.35 v4(139.62,33.35)
HDMI1_DATA_APU_N1: length 291.5
  TOP w0.102: C3372.1 138.77,34.94 139,34.72 139.56,34.72 139.62,34.79 v4(139.62,35.13) ; CPU1.A4 72.47,181.63 72.47,182.14 72.14,182.47 71.7,182.47 71.08,183.09 71.08,183.82 70.96,183.95 70.68,183.95 70.55,183.82 v3(70.55,183.62)
  L4 w0.127: v4(139.62,35.13) 139.94,35.13 140.06,35 140.06,34.65 140.19,34.52 141.11,34.52 141.58,34.99 141.58,49.76 142.08,50.26 142.08,58.82 144.42,61.16 144.42,69.15 150.05,74.78 150.05,82.24 150.66,82.85 150.66,88.3 151.04,88.68 151.04,96.1 151.75,96.81 151.75,105.79 152.99,107.03 152.99,109.07 154.95,111.03 154.95,117.97 156.34,119.36 156.34,124.08 157.86,125.61 157.86,156.52 158.57,157.23 158.57,191.97 157.87,192.67 156.9,192.67 152.65,196.93 109.87,196.93 104.9,201.9 101.95,201.9 97.1,206.75 75.03,206.75 67.35,199.07 67.35,185.9 69.99,183.26 70,183.25 70.18,183.25 v3(70.55,183.62)
  BOTTOM w0.102: v4(139.62,35.13) 140.12,35.13 v2(140.59,34.66)
HDMI1_DATA_APU_N2: length 286.8
  TOP w0.102: v3(71.9,183.62) 71.9,184.05 72,184.15 72.31,184.15 72.41,184.05 72.41,182.84 72.97,182.28 72.97,181.9 73.12,181.75 73.12,181.25 73.1,181.23 73.1,180.97 73.12,180.95 73.12,180.85 73.25,180.72 73.72,180.72 73.85,180.6 73.85,180.42 73.72,180.3 CPU1.C5 ; v4(139.62,36.9) C3373.1
  L4 w0.127: v4(139.62,36.9) 139.93,36.59 140.38,36.59 140.91,37.12 140.91,42.29 140.14,43.06 140.14,51.83 140.75,52.44 140.75,59.47 143.76,62.47 143.76,69.43 149.38,75.05 149.38,82.52 149.99,83.12 149.99,88.58 150.37,88.96 150.37,96.38 151.08,97.09 151.08,106.07 152.32,107.31 152.32,109.35 154.28,111.31 154.28,118.25 155.67,119.63 155.67,124.36 156.91,125.6 156.91,129.17 156.48,129.6 156.48,153.71 157.18,154.41 157.18,185.1 156.48,185.8 156.48,192.15 152.37,196.26 109.59,196.26 104.62,201.23 101.67,201.23 96.82,206.09 75.31,206.09 68.02,198.79 68.02,187.25 71.64,183.62 v3(71.9,183.62)
  BOTTOM w0.102: v2(140.56,36.59) 140.24,36.9 v4(139.62,36.9)
HDMI1_DATA_APU_N3: length 284.5
  TOP w0.102: CPU1.B5 73.4,181.44 73.9,181.94 73.9,182.97 73.82,183.05 v3(73.25,183.62) ; v4(139.62,38.68) C3374.1
  L4 w0.127: v3(73.25,183.62) 72.92,183.62 72.12,184.42 69.31,187.23 69.31,199.14 75.59,205.42 96.54,205.42 101.4,200.57 104.34,200.57 109.32,195.59 152.09,195.59 155.81,191.87 155.81,185.53 156.51,184.83 156.51,154.69 155.81,153.99 155.81,130.93 155.16,130.28 155.16,125.99 150.85,121.69 150.85,121.07 151.16,120.76 153.2,120.76 153.32,120.64 153.32,120.38 153.2,120.26 151.16,120.26 150.85,119.95 150.85,108.74 148.71,106.6 148.71,98.82 149.7,97.83 149.7,96.49 149.56,96.35 149.56,95.97 149.7,95.83 149.7,95.45 149.56,95.32 149.56,94.93 149.7,94.8 149.7,94.42 149.56,94.28 149.56,93.9 149.7,93.76 149.7,92.52 149.56,92.38 149.56,92 149.7,91.87 149.7,91.49 149.56,91.35 149.56,90.97 149.7,90.83 149.7,90.45 149.56,90.31 149.56,89.93 149.7,89.79 149.7,89.24 149.32,88.86 149.32,83.4 148.71,82.79 148.71,75.4 145.83,72.51 145.83,72.51 143.09,69.77 143.09,62.75 140.09,59.74 140.09,52.72 139.45,52.08 139.45,42.8 140.24,42.01 140.24,38.55 140.06,38.37 139.93,38.37 v4(139.62,38.68)
  BOTTOM w0.102: v2(140.43,38.84) 140.27,38.68 v4(139.62,38.68)
HDMI1_DATA_APU_P0: length 294.5
  TOP w0.102: v4(139.62,32.46) C3368.1 ; CPU1.A2 v3(70.55,181.45)
  L4 w0.127: v4(139.62,32.46) 139.93,32.77 141.26,32.77 142.54,34.05 142.54,49.4 143.02,49.88 143.02,58.43 145.36,60.77 145.36,68.76 150.98,74.39 150.98,81.85 151.59,82.46 151.59,87.91 151.97,88.3 151.97,95.71 152.68,96.42 152.68,105.4 153.93,106.65 153.93,108.69 155.88,110.64 155.88,117.58 157.27,118.97 157.27,123.7 158.8,125.22 158.8,156.14 159.5,156.84 159.5,192.36 158.25,193.61 157.32,193.61 153.07,197.86 110.26,197.86 105.29,202.84 102.34,202.84 97.49,207.69 74.65,207.69 65.87,198.92 65.87,186.06 70.48,181.45 v3(70.55,181.45)
  BOTTOM w0.102: v4(139.62,32.46) 139.22,32.46 v2(138.74,31.98)
HDMI1_DATA_APU_P1: length 291.4
  TOP w0.102: v4(139.62,34.24) C3370.1 ; CPU1.B4 72.25,181.05 72.25,182.05 72.05,182.25 71.61,182.25 70.93,182.93 70.88,182.98 v3(70.55,182.98)
  L4 w0.127: v3(70.55,182.98) 69.89,182.98 69.8,183.08 69.65,183.22 67.08,185.79 67.08,199.18 74.92,207.02 97.21,207.02 102.06,202.17 105.01,202.17 109.98,197.2 152.76,197.2 156.83,193.12 157.01,192.94 157.98,192.94 158.83,192.08 158.83,157.12 158.13,156.41 158.13,125.5 156.6,123.97 156.6,119.25 155.22,117.86 155.22,110.92 153.26,108.96 153.26,106.92 152.01,105.68 152.01,96.7 151.3,95.99 151.3,88.57 150.92,88.19 150.92,82.74 150.32,82.13 150.32,74.67 144.69,69.04 144.69,61.05 142.35,58.71 142.35,50.15 141.84,49.65 141.84,34.88 141.22,34.25 139.64,34.25 v4(139.62,34.24)
  BOTTOM w0.102: v2(138.69,34.44) 138.9,34.24 v4(139.62,34.24)
HDMI1_DATA_APU_P2: length 286.9
  TOP w0.102: v3(71.9,182.98) 71.96,182.98 72.75,182.19 72.75,181.81 72.9,181.66 72.9,181.34 72.88,181.31 72.88,180.89 72.9,180.86 72.9,180 CPU1.D5 ; v4(139.62,36.01) C3369.1
  L4 w0.127: v3(71.9,182.98) 67.75,187.14 67.75,198.9 75.2,206.35 96.93,206.35 101.78,201.5 104.73,201.5 109.71,196.53 152.48,196.53 156.75,192.26 156.75,185.91 157.29,185.37 157.44,185.22 157.44,154.3 156.75,153.6 156.75,129.71 157.18,129.28 157.18,125.49 155.94,124.25 155.94,119.52 154.55,118.14 154.55,111.2 152.59,109.24 152.59,107.2 151.35,105.95 151.35,96.98 150.64,96.27 150.64,88.85 150.26,88.47 150.26,83.01 149.65,82.41 149.65,74.94 144.02,69.32 144.02,62.36 141.02,59.36 141.02,52.33 140.41,51.72 140.41,43.17 141.18,42.4 141.18,37.01 140.49,36.33 139.93,36.33 v4(139.62,36.01)
  BOTTOM w0.102: v4(139.62,36.01) 139,36.01 v2(138.67,36.35)
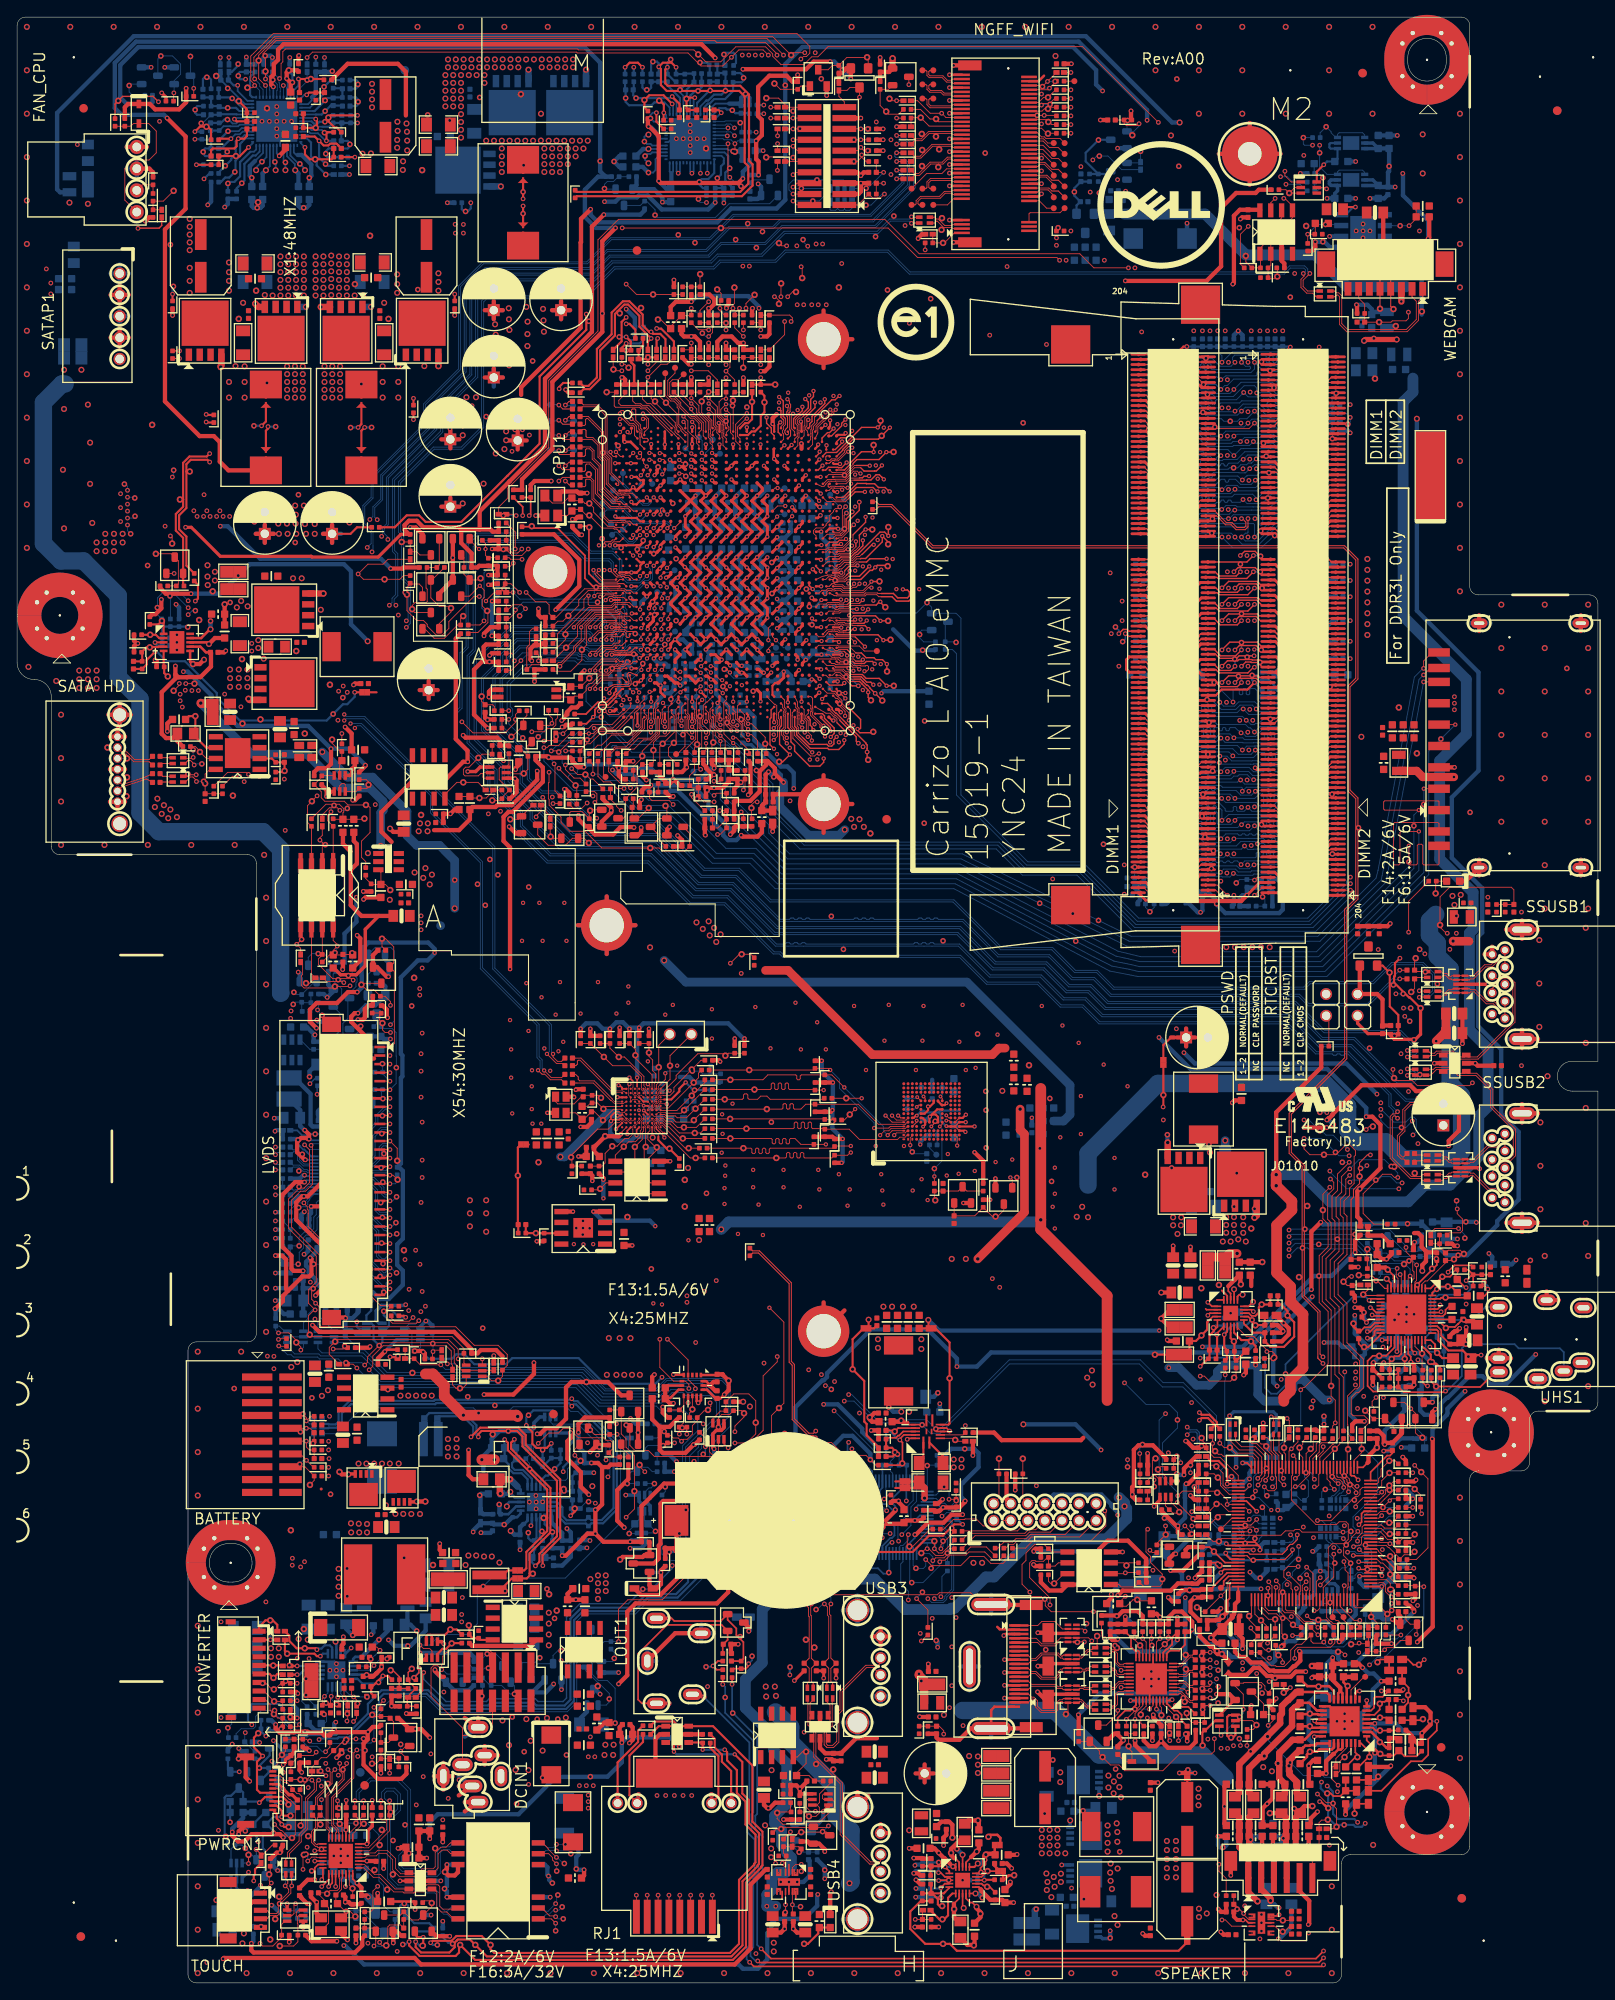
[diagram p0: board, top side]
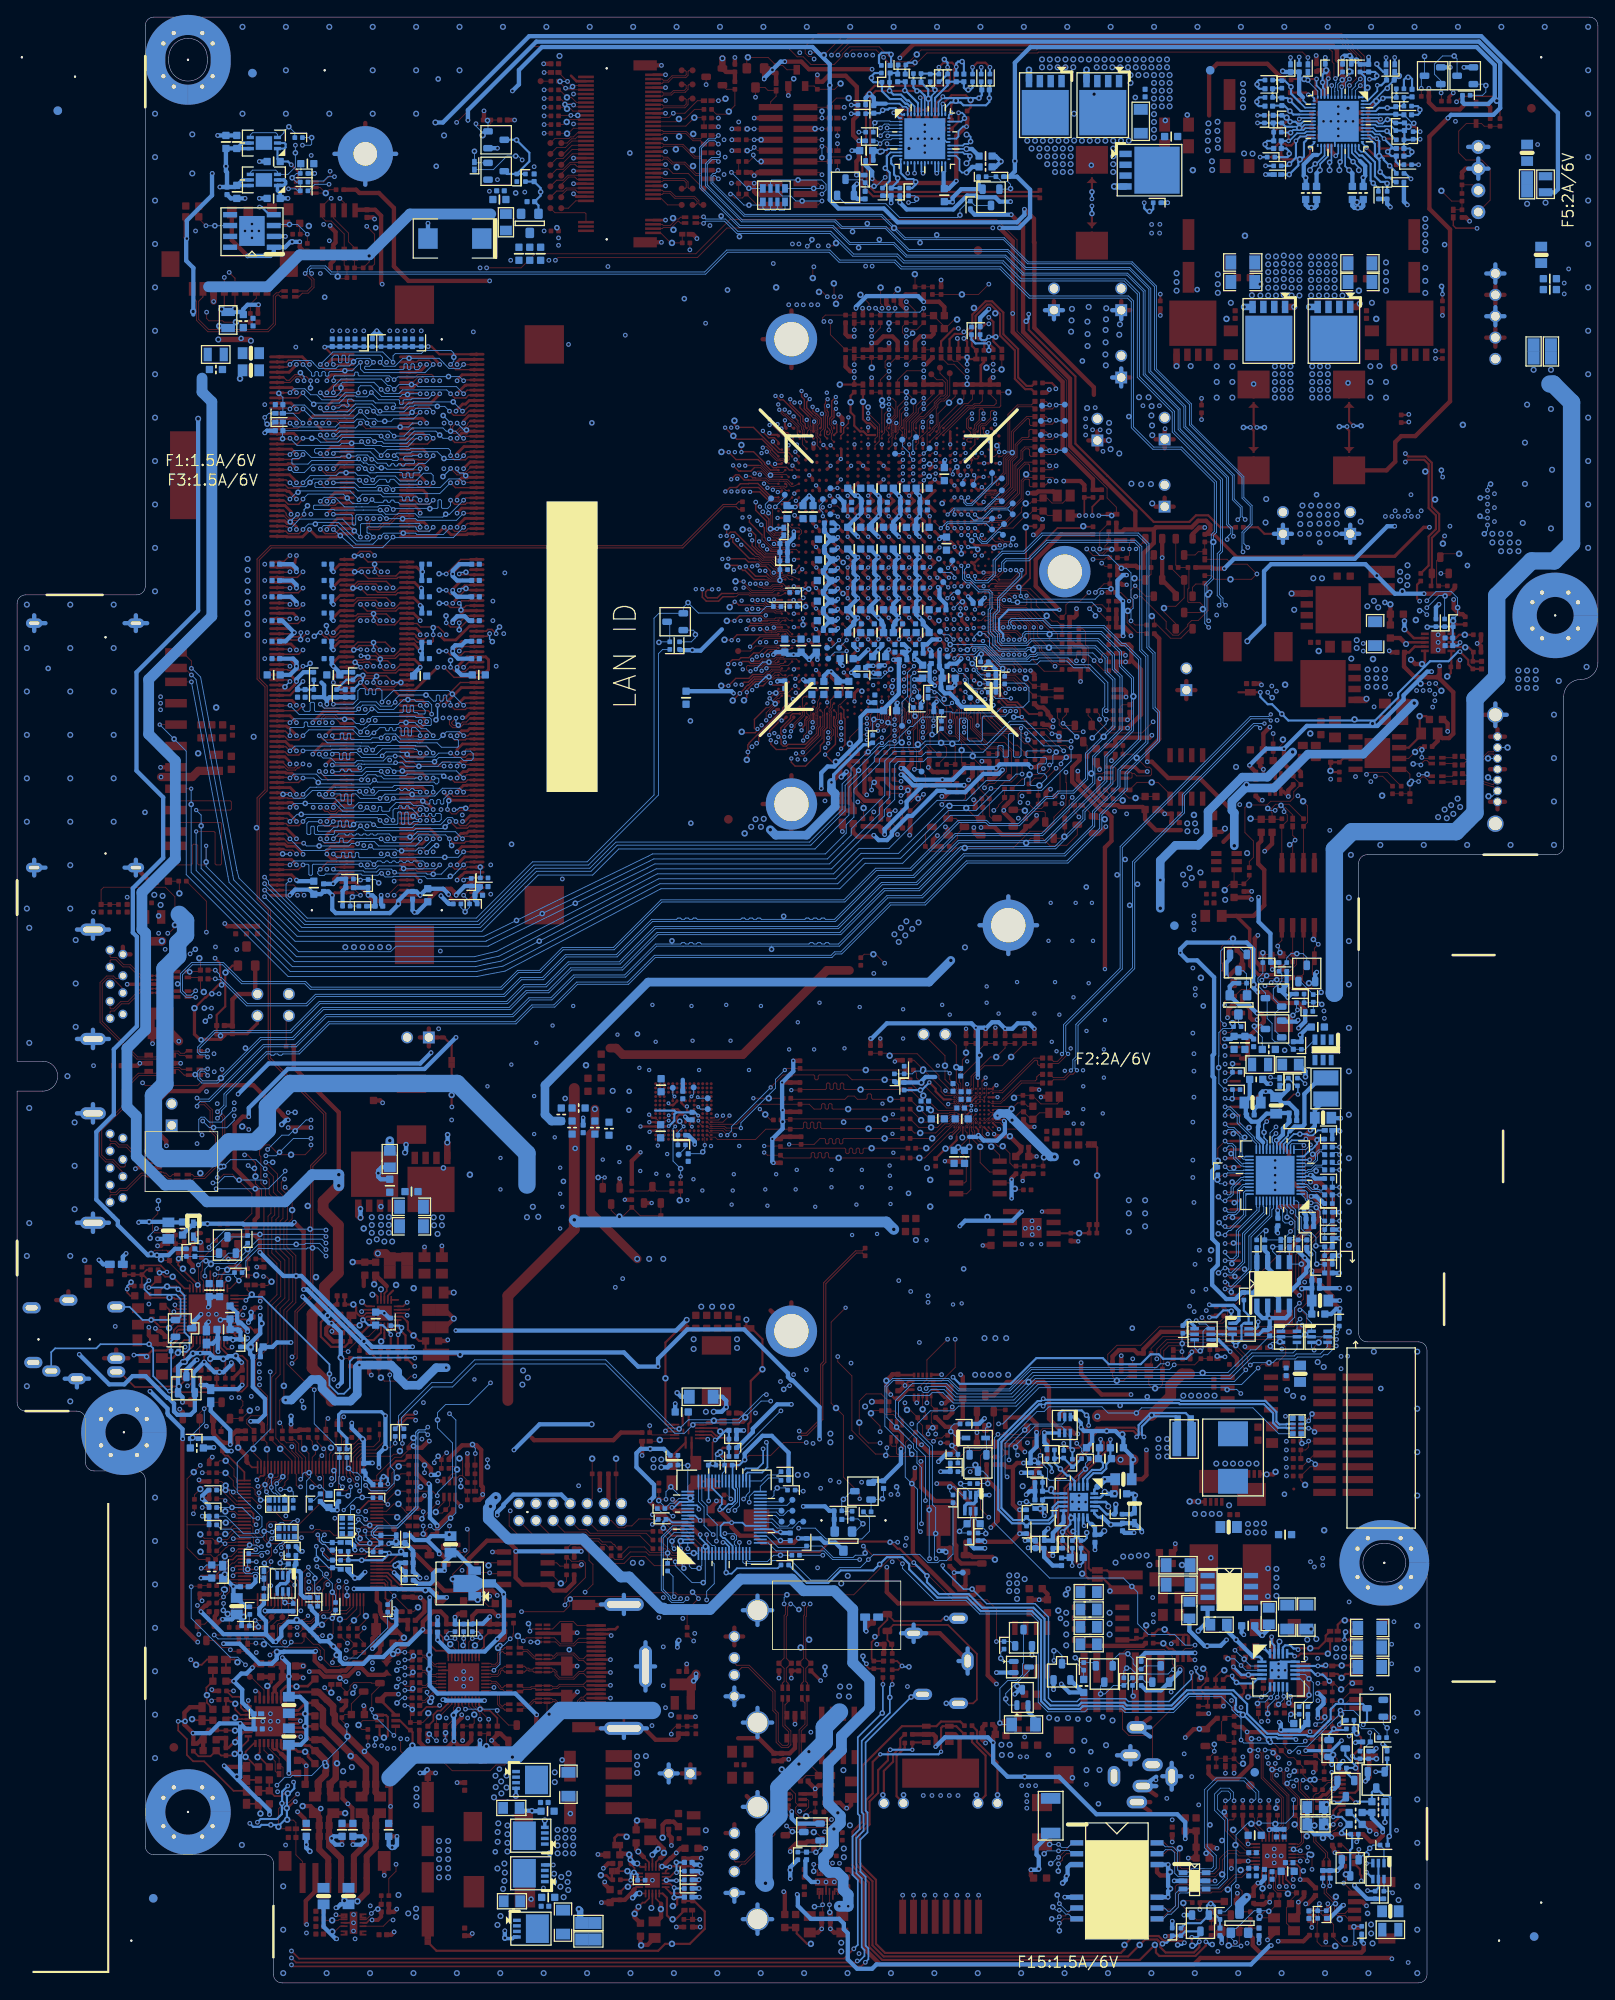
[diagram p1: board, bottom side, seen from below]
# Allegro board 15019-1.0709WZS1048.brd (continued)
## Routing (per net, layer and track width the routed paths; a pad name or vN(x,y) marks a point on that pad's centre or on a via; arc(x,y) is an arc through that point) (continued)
HDMI1_DATA_APU_P3: length 284.8
  TOP w0.102: v3(73.25,182.98) 73.31,183.05 73.52,183.05 73.67,182.9 73.68,182.88 73.68,182.03 73.55,181.9 CPU1.A5 ; v4(139.62,37.79) C3375.1
  L4 w0.127: v4(139.62,37.79) 139.93,38.1 140.17,38.1 140.51,38.44 140.51,42.12 139.72,42.91 139.72,51.97 140.35,52.61 140.35,59.63 143.36,62.64 143.36,69.66 145.94,72.25 148.98,75.29 148.98,82.68 149.59,83.29 149.59,88.75 149.97,89.13 149.97,97.95 148.98,98.93 148.98,106.49 151.12,108.63 151.12,119.84 151.27,119.99 153.31,119.99 153.59,120.27 153.59,120.75 153.31,121.03 151.27,121.03 151.12,121.18 151.12,121.58 155.42,125.88 155.42,130.17 156.08,130.82 156.08,153.88 156.78,154.58 156.78,184.94 156.08,185.64 156.08,191.98 152.2,195.86 109.43,195.86 104.45,200.83 101.51,200.83 96.65,205.68 75.48,205.68 69.05,199.25 69.05,187.12 71.93,184.23 71.97,184.2 73.18,182.98 v3(73.25,182.98)
  BOTTOM w0.102: v2(138.62,38.26) 139.08,37.79 v4(139.62,37.79)
HDMI1_DATA_APU_SRC: length 3.7
  TOP w0.102: R79640.1 135.91,30.84 v1(135.63,31.12) 135.63,31.12 134.14,32.61 U118.39
HDMI1_DATA_CON: length 24.8
  TOP w0.102: U118.33 131.74,32.44 130.83,31.54 v4(130.83,30.85) R2084.2 ; HDMI1.16 119.26,40.32 119.92,39.66 121.41,39.66 122.12,40.37 U117.9 U117.2 125.39,40.37 v4(125.76,40.01)
  L4 w0.127: v4(125.76,40.01) 125.51,39.75 125.51,37.68 127.84,35.35 127.84,33.84 v4(130.83,30.85)
  BOTTOM w0.102: v2(126.37,40.56) 125.81,40.01 v4(125.76,40.01)
HDMI1_DATA_CON_N0: length 11.4
  TOP w0.102: TR16.2 126,32.61 125.76,32.38 125.34,32.38 124.58,33.13 124.37,33.13 124.24,33.26 U116.2 U116.9 122.44,33.26 122.31,33.13 121.99,33.13 121.57,32.71 121.57,32.02 121.41,31.86 119.92,31.86 119.41,32.37 119.41,33.01 118.99,33.43 118.71,33.43 118.32,33.82 HDMI1.3
HDMI1_DATA_CON_N1: length 9.3
  TOP w0.102: HDMI1.6 118.32,35.32 118.71,34.93 121.55,34.93 121.83,34.65 122.31,34.65 122.44,34.78 U116.6 U116.5 124.23,34.78 124.37,34.65 124.84,34.65 124.95,34.53 125.76,34.53 126,34.77 TR17.2
HDMI1_DATA_CON_N2: length 10.1
  TOP w0.102: TR18.2 125.62,37.05 125.39,36.82 125.12,36.82 125,36.71 124.64,36.71 124.51,36.84 U31.7 U31.4 122.44,36.84 122.31,36.71 122.12,36.71 121.83,36.41 121.83,36.07 121.52,35.76 119.92,35.76 119.25,36.43 118.71,36.43 118.32,36.82 HDMI1.9
HDMI1_DATA_CON_N3: length 11.4
  TOP w0.102: v1(126.4,40.59) 126.4,39.46 TR19.2 125.99,39.21 125.75,38.98 125.25,38.98 124.49,38.23 124.37,38.23 124.24,38.36 U31.10 U31.1 122.44,38.36 122.31,38.23 122.21,38.23 121.84,38.59 119.83,38.59 119.16,37.93 118.71,37.93 118.32,38.32 HDMI1.12
HDMI1_DATA_CON_P0: length 12.9
  TOP w0.102: U116.10 U116.1 124.23,32.78 124.37,32.91 124.49,32.91 125.25,32.16 125.76,32.16 126,31.93 TR16.3 ; U116.10 122.44,32.78 122.31,32.91 122.08,32.91 121.79,32.62 121.79,31.93 121.5,31.65 119.83,31.65 119.2,32.28 119.2,32.92 118.91,33.21 118.71,33.21 118.32,32.82 HDMI1.1 ; U116.10 122.98,31.69 v1(122.74,31.45)
HDMI1_DATA_CON_P1: length 9.3
  TOP w0.102: HDMI1.4 118.32,34.32 118.71,34.71 121.46,34.71 121.74,34.43 122.31,34.43 122.44,34.3 U116.7 U116.4 124.23,34.3 124.37,34.43 124.75,34.43 124.86,34.32 125.7,34.32 125.94,34.09 TR17.3
HDMI1_DATA_CON_P2: length 10.1
  TOP w0.102: TR18.3 125.62,36.37 125.39,36.6 125.21,36.6 125.09,36.49 124.64,36.49 124.51,36.36 U31.6 U31.5 122.44,36.36 122.31,36.49 122.21,36.49 122.04,36.32 122.04,35.98 121.61,35.55 119.83,35.55 119.16,36.21 118.71,36.21 118.32,35.82 HDMI1.7
HDMI1_DATA_CON_P3: length 9.9
  TOP w0.102: TR19.3 126,38.53 125.76,38.76 125.34,38.76 124.58,38.01 124.37,38.01 124.23,37.88 U31.9 U31.2 122.44,37.88 122.31,38.01 122.12,38.01 121.75,38.38 119.92,38.38 119.25,37.71 118.71,37.71 118.32,37.32 HDMI1.10
HDMI1_DATA_IC_N0: length 3.2
  TOP w0.102: C3371.2 137.55,33.01 137.33,33.01 136.26,34.08 136,34.08 135.9,34.17 U118.2
HDMI1_DATA_IC_N1: length 3
  TOP w0.102: C3372.2 137.55,34.79 137.19,34.79 136.7,35.28 136,35.28 135.9,35.37 U118.5
HDMI1_DATA_IC_N2: length 3.4
  TOP w0.102: C3373.2 137.55,36.57 137.22,36.57 137.07,36.42 ; U118.7 135.9,36.17 136,36.08 136.73,36.08 137.07,36.42 ; 137.07,36.42 v1(136.79,36.7)
HDMI1_DATA_IC_N3: length 3.6
  TOP w0.102: v1(136.76,38.38) 137.01,38.13 ; 137.01,38.13 136.16,37.28 136,37.28 135.9,37.37 U118.10 ; 137.01,38.13 137.23,38.34 137.55,38.34 C3374.2
HDMI1_DATA_IC_P0: length 3.6
  TOP w0.102: U118.1 135.9,33.77 136,33.86 136.17,33.86 136.89,33.15 ; C3368.2 137.55,32.79 137.24,32.79 136.89,33.15 ; v1(136.64,32.9) 136.89,33.15
HDMI1_DATA_IC_P1: length 3
  TOP w0.102: C3370.2 137.55,34.57 137.1,34.57 136.61,35.06 136,35.06 135.9,34.97 U118.4
HDMI1_DATA_IC_P2: length 3
  TOP w0.102: U118.6 135.9,35.77 136,35.86 136.82,35.86 137.31,36.35 137.55,36.35 C3369.2
HDMI1_DATA_IC_P3: length 3.2
  TOP w0.102: U118.9 135.9,36.97 136,37.06 136.25,37.06 137.32,38.13 137.55,38.13 C3375.2
HDMI1_DET_APU: length 285.4
  TOP w0.102: v3(73.69,177.42) 73.3,177.81 CPU1.F5 ; v4(137.03,34.01) 136.96,34.01 136.55,34.42 136.18,34.42 136.02,34.57 U118.3
  L4 w0.127: v4(137.03,34.01) 138.09,35.07 138.09,40.14 138.47,40.52 138.47,42.39 138.38,42.47 138.38,52.41 139.1,53.13 139.1,68.19 141.85,70.95 141.85,71.15 147.1,76.4 147.1,77.96 147.73,78.58 147.73,88.76 148.58,89.61 148.58,97.56 147.73,98.41 147.73,106.52 147.73,107.01 149.87,109.15 149.87,122.1 154.17,126.4 154.17,130.69 154.82,131.34 154.82,191.46 151.68,194.6 108.91,194.6 103.93,199.58 100.99,199.58 96.27,204.29 76.16,204.29 70.3,198.44 70.3,187.64 70.58,187.36 70.89,187.36 74.44,183.81 74.44,182.51 74.85,182.11 74.85,179.52 74.76,179.43 74.76,178.37 74.17,177.78 74.05,177.78 v3(73.69,177.42)
  BOTTOM w0.102: v4(137.03,34.01) 137.03,33.75 136.63,33.35 v2(136.48,33.35)
HDMI1_DET_CON: length 19.1
  TOP w0.102: HDMI1.19 119.45,41.82 119.92,42.29 121.45,42.29 122.32,41.41 U117.7 U117.4 124.72,41.41 v4(124.99,41.15) ; U118.28 v4(129.2,34.57)
  L4 w0.127: v4(129.2,34.57) 126.65,37.11 126.65,40.39 125.89,41.15 v4(124.99,41.15)
  BOTTOM w0.102: v2(125.15,42.04) 124.99,41.87 v4(124.99,41.15)
HDMI_LANE0_IC_DN: length 4.3
  TOP w0.102: TR16.1 127.93,32.61 128.17,32.38 128.27,32.38 128.56,32.67 128.56,33.78 128.85,34.08 129.48,34.08 129.57,34.17 U118.29
HDMI_LANE0_IC_DP: length 4.3
  TOP w0.102: TR16.4 127.93,31.93 128.17,32.16 128.36,32.16 128.77,32.58 128.77,33.69 128.94,33.86 129.48,33.86 129.57,33.77 U118.30
HDMI_LANE1_IC_DN: length 3.3
  TOP w0.102: U118.26 129.57,35.37 129.48,35.28 128.95,35.28 128.43,34.76 128.43,34.67 128.29,34.53 128.17,34.53 127.93,34.77 TR17.1
HDMI_LANE1_IC_DP: length 3.3
  TOP w0.102: U118.27 129.57,34.97 129.48,35.06 129.04,35.06 128.65,34.67 128.65,34.58 128.38,34.32 128.17,34.32 127.93,34.09 TR17.4
HDMI_LANE2_IC_DN: length 3.4
  TOP w0.102: U118.24 129.57,36.17 129.48,36.08 128.85,36.08 128.65,36.28 128.65,36.53 128.36,36.82 128.17,36.82 127.93,37.05 TR18.1
HDMI_LANE2_IC_DP: length 3.4
  TOP w0.102: TR18.4 127.93,36.37 128.17,36.6 128.27,36.6 128.43,36.44 128.43,36.19 128.76,35.86 129.48,35.86 129.57,35.77 U118.25
HDMI_LANE3_IC_DN: length 4.6
  TOP w0.102: TR19.1 127.93,39.21 128.17,38.98 128.36,38.98 128.43,38.91 ; 128.43,38.91 128.77,38.56 128.77,37.55 129.05,37.28 129.48,37.28 129.57,37.37 U118.21 ; 128.43,38.91 v1(128.71,39.19)
HDMI_LANE3_IC_DP: length 4.2
  TOP w0.102: TR19.4 127.93,38.53 128.17,38.76 128.27,38.76 128.56,38.47 128.56,37.47 128.96,37.06 129.48,37.06 129.57,36.97 U118.22
HDT_C_M1: length 4.2
  TOP w0.102: HDT1.11 98.33,214.38 98.71,214.76 v4(98.74,214.76) 98.74,214.73 99.09,214.38 R1702.1
  BOTTOM w0.102: v4(98.74,214.76) 98.74,214.73 99.09,214.38 v2(99.55,214.38)
HDT_C_M2: length 3.7
  TOP w0.102: R1703.1 v4(98.74,215.65) HDT1.13
  BOTTOM w0.102: v4(98.74,215.65) v2(97.93,215.65)
HDT_C_M3: length 3.7
  TOP w0.102: HDT1.15 v4(98.74,216.92) R1705.1
  BOTTOM w0.102: v4(98.74,216.92) v2(99.55,216.92)
HDT_PW_M3: length 4.6
  TOP w0.102: Q50.1 91.73,221.93 R1701.2 89.33,221.55 88.65,222.22 v1(88.63,222.22)
HDT_PW_M4: length 7.7
  TOP w0.102: Q1210.G 99.6,225.17 v1(99.47,225.3) 99.45,225.27 97.1,225.27 R504.2 95.41,224.35 94.9,223.84 Q50.3
HDT_RST0: length 3.7
  TOP w0.102: HDT1.18 v4(90.81,218.19) R1747.1
  BOTTOM w0.102: v4(90.81,218.19) v2(90.81,219)
HDT_RST1: length 5.7
  TOP w0.102: HDT1.20 R1748.1 89.89,219.75 89.11,220.52 v1(87.68,220.52)
HDT_TRST: length 4.9
  TOP w0.102: R1743.1 99.35,213.11 98.84,213.61 ; 98.84,213.61 98.33,213.11 HDT1.9 ; 98.84,213.61 v4(98.84,213.87)
  BOTTOM w0.102: v2(97.93,213.11) 98.33,213.11 98.84,213.61 v4(98.84,213.87)
HDT_VDDIO_SUS: length 34.8
  TOP w0.102: v4(101.51,209.3) 101.05,208.84 100.12,208.84 R1704.1 98.39,208.03 HDT1.1 ; v4(98.59,220.62) Q1210.D 97.47,221.77 97.12,221.42 R1698.2 96.17,220.73 96.81,220.09 HDT1.19
  L3 w0.127: v4(101.51,209.3) 99.66,211.14 99.66,219.54 v4(98.59,220.62)
  BOTTOM w0.102: RN12.7 96.02,207.62 ; 96.02,207.62 95.79,207.39 95.23,207.39 95.13,207.49 RN12.8 ; 96.02,207.62 96.25,207.39 96.68,207.39 96.83,207.54 ; v4(101.51,209.3) 101.23,209.3 99.93,208 v2(99.35,208) 98.1,208 RN12.5 97.72,207.67 97.44,207.39 96.98,207.39 96.83,207.54 ; 96.83,207.54 RN12.6
HM_VCCP: length 5.9
  TOP w0.508: R1832.1 138.4,40.58 139.63,39.34 139.9,39.34 140.28,38.96 140.28,38.69 140.5,38.48 v1(141,38.48) 141.77,37.72 G5.2
HM_VCCP_R: length 8.2
  TOP w0.203: U109.95 142.06,46.78 141.89,46.61 141.89,44.98 141.54,44.63
  TOP w0.508: R1832.2 C558.2 140.26,42.42 140.32,42.48 140.69,42.48 v1(141.07,42.86) 141.54,43.33 141.54,44.63
HPOL_CON: length 22
  TOP w0.203: R223.2 169.82,83.44 R220.2 ; v4(169.58,82.17) 170.28,82.87 R220.2 ; R220.2 170.4,82.85 R225.2 ; R220.2 R221.1 C134.1
  BOTTOM w0.203: UHS1.1 171.83,79.09 170.31,77.57 v2(169.31,77.57) 169.3,77.57 Q57.1 166.21,77.57 165.87,77.91 165.87,80.01 166.38,80.52 169.46,80.52 170.09,81.15 170.09,81.66 v4(169.58,82.17)
HPOR_CON: length 36.2
  TOP w0.203: R281.1 161.67,69.72 162.28,69.11 167.04,69.11 v4(167.17,69.24) ; R281.1 C159.1 R262.2 ; R281.1 R284.2
  BOTTOM w0.203: Q57.2 167.01,75.05 167.01,74.52 166.97,74.48 R627.2 166.97,69.43 v4(167.17,69.24) 167.32,69.24 169.07,70.99 169.07,74.24 v2(169.55,74.73) 175.25,74.73 175.72,74.25 180.55,74.25 181.01,73.79 181.01,71.6 UHS1.2
HPOUT-JD: length 9.3
  TOP w0.203: UHS1.6 173,71.49 171.23,69.72 168.75,69.72 168.69,69.78 v1(166.06,69.78) 165.51,70.33 R267.1
HPOUT-L: length 42.2
  TOP w0.203: v4(167.47,83.16) 167.47,83.22 168.2,83.95 170.2,83.95 R220.1 ; v4(159.85,74.4) 160.08,74.17 160.43,74.17 160.79,74.53 U6.26
  L3 w0.203: v4(159.85,74.4) 160.08,74.17 161.06,74.17 161.26,74.37 164.42,74.37 165.26,73.53 166.78,73.53 168.44,75.18 174.15,75.18 175.34,73.99 176.89,73.99 178.47,75.56 178.49,75.56 178.49,77.04 172.85,82.68 167.95,82.68 v4(167.47,83.16)
  BOTTOM w0.203: v4(167.47,83.16) 168.26,83.16 v2(168.33,83.08)
HPOUT-R: length 9.8
  TOP w0.203: R284.1 159.2,69.19 158.7,69.19 158.05,69.84 158.05,72.77 158.65,73.37 v1(159.41,73.37) 160.22,73.37 161.19,74.34 U6.27
HSI_C_DN3: length 141.8
  TOP w0.102: CPU1.P6 74.1,170.6 v3(73.7,170.2) ; v4(102.93,214.12) R1712.2
  L3 w0.127: v4(42.15,171.2) 41.89,171.45 41.89,172.24 42.6,172.95 48.04,172.95 49.07,173.98 54.6,173.98 61.63,181 61.63,181.86 63.06,183.3 64.36,183.3 67.32,180.34 67.32,177.58 70.43,174.46 70.43,173.21 72.82,170.81 73.51,170.81 73.7,170.62 v3(73.7,170.2)
  BOTTOM w0.102: v4(42.15,171.2) 41.85,171.49 41.85,172.6 42.78,173.53 42.78,176.34 48.46,182.02 48.46,184.39 52.55,188.48 52.55,198.17 54.86,200.48 67.02,200.48 69.13,202.59 80.7,202.59 83.37,205.26 87.23,205.26 ; v4(102.93,214.12) 102.85,214.12 102.73,214 102.73,213.68 102.84,213.56 103.73,213.56 104.45,212.84 104.45,210.29 100.21,206.04 89.31,206.04 88.52,205.26 87.23,205.26 ; 87.23,205.26 v2(87.23,204.9)
HSI_C_DP3: length 141.9
  TOP w0.102: v4(102.93,213.11) R1711.2 ; v3(74.5,170.2) 74.9,170.6 CPU1.P7
  L3 w0.127: v3(74.5,170.2) 73.62,171.08 72.93,171.08 70.7,173.32 70.7,174.57 67.58,177.69 67.58,180.45 64.47,183.57 62.95,183.57 61.36,181.97 61.36,181.11 54.49,174.24 48.96,174.24 47.93,173.22 42.49,173.22 41.63,172.35 41.63,171.56 v4(41.28,171.22)
  BOTTOM w0.102: v4(102.93,213.11) 103.17,213.35 103.64,213.35 104.24,212.75 104.24,210.38 100.12,206.26 89.22,206.26 88.43,205.47 85.5,205.47 ; v4(41.28,171.22) 41.64,171.58 41.64,172.69 42.56,173.62 42.56,176.43 48.24,182.11 48.24,184.48 52.33,188.57 52.33,198.26 54.77,200.7 66.93,200.7 69.04,202.81 80.61,202.81 83.28,205.47 85.5,205.47 ; v2(85.5,205.84) 85.5,205.47
HSI_LAN_DN1: length 247.7
  TOP w0.102: v3(73.7,169.4) CPU1.T5 ; v4(36.38,24.97) 36.64,24.71 36.64,23.41 34.91,21.69 34.91,20.85 C1808.2
  L3 w0.127: v3(73.7,169.4) 73.7,169.12 73.56,168.98 71.93,168.98 71.38,169.52 71.38,171.32 68.11,174.6 68.11,176.15 66.85,177.41 66.85,179.41 64.47,181.79 63.08,181.79 52.74,171.45 43.9,171.45 42.81,170.36 40.96,170.36 37.28,174.04 30.15,174.04 29.8,173.69 22.52,173.69 21.28,172.45 21.28,171.79 v4(21.06,171.58)
  L4 w0.127: v4(36.38,24.97) 36.62,25.21 36.62,27.93 32,32.55 32,42.15 34.73,44.88 34.73,50.03 34.43,50.33 34.43,52.73 30.51,56.65 30.51,65.82 38.9,74.2 38.9,77.6 41.23,79.92 41.23,121.08 44.29,124.14 44.29,154.65 39.92,159.02 39.92,160.39 34.65,165.67 26.14,165.67 21.31,170.49 21.31,171.33 v4(21.06,171.58)
  BOTTOM w0.102: v2(73.27,168.76) 73.7,169.19 v3(73.7,169.4)
HSI_LAN_DN1_R: length 5.5
  TOP w0.102: 34.47,17.17 34.47,16.43 34.79,16.11 34.94,15.95 35.11,15.95 35.2,15.86 U16.18 ; 34.47,17.17 34.47,17.72 34.91,18.17 34.91,19.28 C1808.1 ; 34.47,17.17 v1(34.07,17.17)
HSI_LAN_DP1: length 248.2
  TOP w0.102: C1805.2 35.13,20.85 35.13,21.6 36.86,23.32 36.86,24.63 v4(37.19,24.97) ; v3(74.5,169.4) CPU1.T6
  L3 w0.127: v3(74.5,169.4) 73.81,168.71 71.82,168.71 71.2,169.33 71.12,169.41 71.12,171.21 67.84,174.49 67.84,176.04 66.58,177.3 66.58,179.3 64.36,181.52 63.19,181.52 52.85,171.18 44.01,171.18 42.92,170.09 40.85,170.09 37.17,173.78 30.26,173.78 29.91,173.43 22.64,173.43 21.55,172.34 21.55,171.86 v4(21.83,171.58)
  L4 w0.127: v4(37.19,24.97) 36.89,25.27 36.89,28.04 32.27,32.66 32.27,42.04 35,44.77 35,50.14 34.7,50.44 34.7,52.84 30.78,56.76 30.78,65.71 39.16,74.09 39.16,77.49 41.49,79.81 41.49,120.97 44.56,124.03 44.56,154.76 40.19,159.13 40.19,160.51 34.76,165.94 26.25,165.94 21.58,170.61 21.58,171.33 v4(21.83,171.58)
  BOTTOM w0.102: v4(37.19,24.97) 38.13,24.97 v2(38.13,24.96)
HSI_LAN_DP1_R: length 5.1
  TOP w0.102: U16.17 35.2,16.26 35.11,16.17 35.03,16.17 34.68,16.52 34.68,17.63 35.13,18.08 35.13,18.54 ; 35.13,18.54 35.13,19.28 C1805.1 ; 35.13,18.54 v1(35.49,18.54)
HSO_C_BLAN_DN1: length 10.6
  TOP w0.102: CPU1.R3 71.48,170.82 71.11,170.82 71.03,170.9 70.74,170.9 70.71,170.88 70.29,170.88 70.26,170.9 69.16,170.9 68.49,171.58 68.49,172.39 67.28,173.6 67.28,175.68 67.03,175.93 66.62,175.93 66.55,175.86 66.55,175.18 66.42,175.06 66.01,175.06 65.88,175.18 C45.1
HSO_C_BLAN_DP1: length 11
  TOP w0.102: CPU1.R4 72.13,170.6 71.69,171.03 71.2,171.03 71.11,171.12 70.65,171.12 70.63,171.1 70.37,171.1 70.35,171.12 69.25,171.12 68.7,171.67 68.7,172.48 67.49,173.69 67.49,175.77 67.11,176.15 66.91,176.15 ; C44.1 66.91,176.15 ; 66.91,176.15 v1(66.91,176.5)
HSO_C_DN3: length 124.2
  TOP w0.102: v4(102.93,212.09) R1714.2 ; C41.2 63.86,177.04 v4(63.4,177.5)
  L3 w0.127: v4(41.54,167.43) 41.98,167.43 41.99,167.41 47.31,167.41 49.01,169.11 54.01,169.11 62.59,177.7 63.2,177.7 v4(63.4,177.5)
  BOTTOM w0.102: v4(102.93,212.09) 103.33,211.69 103.56,211.69 103.79,211.46 103.79,210.57 99.93,206.71 83.88,206.71 81.14,203.96 79.33,203.96 ; v4(41.54,167.43) 41.65,167.54 41.65,169.74 40.69,170.7 40.69,172.76 41.65,173.72 41.65,176.15 47.8,182.29 47.8,184.66 51.89,188.75 51.89,198.44 54.59,201.14 66.75,201.14 69.57,203.96 79.33,203.96 ; v2(79.33,203.61) 79.33,203.96
HSO_C_DP3: length 124.2
  TOP w0.102: v4(64.16,177.5) 64.6,177.93 C42.2 ; v4(102.93,211.07) R1713.2
  L3 w0.127: v4(64.16,177.5) 63.69,177.97 62.48,177.97 53.89,169.38 48.9,169.38 47.2,167.68 42.1,167.68 41.84,167.94 v4(40.98,167.94)
  BOTTOM w0.102: v2(77.38,204.52) 77.38,204.18 ; 77.38,204.18 69.48,204.18 66.66,201.36 54.5,201.36 51.67,198.53 51.67,188.84 47.58,184.75 47.58,182.38 41.44,176.24 41.44,173.81 40.47,172.85 40.47,170.61 41.44,169.65 41.44,168.4 v4(40.98,167.94) ; 77.38,204.18 81.05,204.18 83.79,206.92 99.84,206.92 103.58,210.66 103.58,211.37 103.47,211.47 103.33,211.47 v4(102.93,211.07)
HSO_C_LAN_DN1: length 231.2
  TOP w0.102: v4(38.95,27.25) 39.19,27.01 39.19,24.07 36.82,21.71 36.82,18.43 37.37,17.88 37.37,17.63 37.28,17.53 U16.14 ; C45.2 64.62,175.26 v4(64.16,175.72)
  L3 w0.127: v4(64.16,175.72) 63.35,176.53 62.22,176.53 54.33,168.64 49.2,168.64 47.5,166.94 41.11,166.94 40.2,167.85 28.23,167.85 27.13,168.96 26.18,169.9 26.18,171.6 25.42,172.36 24.61,172.36 24.38,172.12 24.38,171.84 v4(24.11,171.58)
  L4 w0.127: v4(24.11,171.58) 24.26,171.43 24.26,169.44 26.69,167 35.22,167 41.26,160.97 41.26,159.57 45.63,155.2 45.63,123.59 42.56,120.52 42.56,77.93 40.38,75.75 40.38,73.59 37.21,70.42 37.21,69.2 36.13,68.13 34.71,68.13 31.85,65.26 31.85,57.29 35.77,53.37 35.77,50.88 36.07,50.58 36.07,38.12 34.09,36.14 34.09,32.54 38.95,27.69 v4(38.95,27.25)
  BOTTOM w0.102: v4(38.95,27.25) 38.34,27.25 v2(38.01,26.92)
HSO_C_LAN_DP1: length 231
  TOP w0.102: U16.13 37.68,17.53 37.59,17.63 37.59,17.97 37.04,18.52 37.04,21.62 39.4,23.98 39.4,26.9 v4(39.76,27.25) ; C44.2 63.83,176.15 v4(63.4,175.72)
  L3 w0.127: v4(63.4,175.72) 63.4,176.03 63.16,176.26 62.33,176.26 54.44,168.37 49.31,168.37 47.61,166.67 41,166.67 40.09,167.59 28.12,167.59 26.94,168.77 25.92,169.79 25.92,171.49 25.31,172.09 24.72,172.09 24.64,172.01 24.64,171.81 v4(24.87,171.58)
  L4 w0.127: v4(39.76,27.25) 34.36,32.65 34.36,36.03 36.33,38.01 36.33,50.69 36.03,50.99 36.03,53.48 32.12,57.4 32.12,65.15 34.82,67.86 36.24,67.86 37.47,69.09 37.47,70.31 40.64,73.48 40.64,75.64 42.83,77.82 42.83,120.41 45.89,123.48 45.89,155.31 41.52,159.68 41.52,161.08 35.33,167.27 26.8,167.27 24.52,169.55 24.52,171.23 v4(24.87,171.58)
  BOTTOM w0.102: v4(39.76,27.25) 40.67,27.25 v2(40.72,27.2)
ICH_RSMRST_N_R: length 4.2
  TOP w0.102: U109.82 140.96,51.98 v1(140.65,51.66) 139.95,51.66 R374.2
ILIM_R: length 48.1
  TOP w0.254: v4(22.13,183.51) 22.19,183.45 PR4637.2 ; PR4620.1 22.7,216.8 22.33,217.17 v1(22.16,217.17) 22.14,217.18 21.39,217.18 v4(20.81,216.6)
  L3 w0.254: v4(22.13,183.51) 22,183.39 19.59,183.39 17.5,185.48 17.5,206.95 19.79,209.25 21.66,209.25 23.99,211.57 23.99,215.4 22.98,216.41 21,216.41 v4(20.81,216.6)
  BOTTOM w0.254: PR4619.2 v4(20.81,216.6)
ILIMNB_R: length 52.2
  TOP w0.254: PR4639.2 v4(46.39,185.39) ; PR4644.1 37.41,217.07 37.17,217.07 36.43,217.81 v1(36.43,218.24) 36.43,218.25 36.69,218.5 v4(39.83,218.5)
  L3 w0.254: v4(39.83,218.5) 37.75,216.42 37.75,211.24 38.56,210.44 41.36,210.44 44.54,207.26 51.75,200.06 51.75,189.14 48,185.39 v4(46.39,185.39)
  BOTTOM w0.254: PR4640.2 v4(39.83,218.5)
IMS: length 215.6
  TOP w0.102: R79691.1 154.08,40.28 v4(153.68,39.88) ; R79661.2 42.58,113.47 R79659.1 42.4,113.25 42.4,112.65 v1(42.76,112.3) 42.76,111.51 43.06,111.2 v4(43.7,111.2) ; LVDS1.4 v4(43.63,106.5)
  L3 w0.127: v4(114.13,82.4) 114.05,82.47 87.46,82.47 86.39,81.41 81.44,81.41 80.53,82.32 46.66,82.32 44.66,84.32 44.66,84.89 44.1,85.45 44.1,106.03 v4(43.63,106.5) ; v4(110.7,30.1) 111.74,31.14 116.1,31.14 117.81,29.44 128.19,29.44 128.34,29.29 129.7,29.29 130.16,28.83 137.41,28.83 138.85,27.39 140.84,27.39 v4(140.89,27.45)
  L4 w0.127: v4(140.89,27.45) 140.89,28.09 143.7,30.89 147.63,30.89 153.83,37.08 153.83,37.51 153.49,37.85 153.49,38.24 153.83,38.59 153.83,39.62 153.68,39.78 v4(153.68,39.88) ; v4(110.7,30.1) 110.7,33.68 110.51,33.87 110.51,42.14 111.37,43.01 111.37,54.7 118.52,61.85 118.52,70.1 114.13,74.5 v4(114.13,82.4) ; v4(43.7,111.2) 43.16,110.67 43.16,106.73 43.39,106.5 v4(43.63,106.5)
INIT_3V: length 5.5
  TOP w0.102: LPC1.2 114.9,56.72 R1699.2 v1(114.9,61.34)
IO_SMI_N: length 273.4
  TOP w0.102: v4(164.63,46.35) 164.56,46.42 R313.2 163.55,46.48 R80223.1 ; CPU1.BB13 79.8,148.53 80.1,148.23 80.1,147.97 80.02,147.89 80.02,146.91 v3(80.63,146.3)
  L3 w0.127: v3(80.63,146.3) 79.88,145.55 79.88,145.31 79.57,145 79.57,144.17 79.14,143.73 79.14,140.2 79.83,139.51 79.83,137.39 80.51,136.71 80.59,136.62 80.59,136.48 81.55,135.53 81.91,135.53 83,134.44 83,134.17 83.37,133.8 85.49,133.8 87.02,132.28 88.57,132.28 91.8,129.05 118.39,129.05 120.45,126.99 121.41,126.99 133.46,114.95 148.34,114.95 151.78,111.51 151.78,108.93 157.42,103.29 157.42,95.13 v4(155.98,93.69) ; v4(105.7,40.89) 105.96,40.63 112.56,40.63 113.97,39.22 117.2,39.22 118.19,38.23 121.68,38.23 121.89,38.01 137.93,38.01 139.36,39.45 140.01,39.45 143.22,36.23 143.61,36.23 144.65,37.27 146.87,37.27 149.15,39.56 152.57,39.56 152.72,39.41 153.87,39.41 153.9,39.43 155.83,39.43 156.14,39.13 157.2,39.13 157.85,38.48 157.85,37.63 v4(158.28,37.21)
  L4 w0.127: v4(158.28,37.21) 157.89,37.59 156.88,37.59 156.46,38.01 156.46,43.73 156.16,44.03 156.16,47.26 156.12,47.31 156.12,49.44 155.63,49.92 155.51,49.92 155.23,50.2 155.23,50.79 156.18,51.74 156.18,54.35 155.57,54.96 155.57,55.97 155.99,56.39 156.94,56.39 158.17,57.62 158.17,59.37 158.13,59.4 158.13,74.89 158.49,75.24 158.49,76.43 159.28,77.22 159.28,87.08 162.62,90.42 162.62,93.07 v4(162.09,93.6) ; v4(105.7,40.89) 105.7,43.86 104.8,44.76 104.8,47.54 101.54,50.8 100.87,50.8 100.47,51.2 v4(100.47,51.54)
  BOTTOM w0.102: v4(164.63,46.35) 164.63,42.67 160.05,38.1 159.16,38.1 v4(158.28,37.21) ; v4(162.09,93.6) 161.45,93.6 160.71,94.34 159.67,94.34 159.27,93.93 v2(159.01,93.93) 156.23,93.93 v4(155.98,93.69) ; v4(100.47,51.54) U4101.13
ISEN1: length 7.8
  TOP w0.254: v4(35.09,38.99) 34.92,39.15 v1(33.66,39.15) 32.71,39.15 31.86,40.01 31.86,40.63 R51.2
  BOTTOM w0.254: U120.17 36.87,39.24 36.61,39.5 36,39.5 35.62,39.12 35.21,39.12 v4(35.09,38.99)
ISEN2: length 6.7
  TOP w0.254: v4(35.49,38.23) 35.09,38.23 34.79,38.52 v1(31.61,38.52) 31.61,38.58 31.34,38.85 R53.2
  BOTTOM w0.254: U120.16 36.36,38.52 35.78,38.52 v4(35.49,38.23)
ISEN3: length 4.4
  TOP w0.254: R56.2 v4(32.77,37.08)
  BOTTOM w0.254: v2(31.86,37.16) 31.94,37.08 v4(32.77,37.08) 33.86,37.08 33.87,37.08 U120.14
ISEN4: length 5.3
  TOP w0.254: R59.2 v4(32.77,36.07)
  BOTTOM w0.254: U120.13 34.41,36.58 34.41,36.57 33.55,36.57 33.05,36.07 v4(32.77,36.07) 32.19,36.07 v2(31.43,35.31)
ISET: length 4.4
  TOP w0.102: R2086.1 R1596.2 131.5,30.39 v1(131.5,31.39) 131.5,31.75 132.14,32.38 U118.34
ISP_CLK1: length 7.4
  TOP w0.102: v4(33.21,74.04) 33.21,74.4 v1(32.67,74.93) 32.67,75.18 31.81,76.05 v4(30.59,76.05)
  BOTTOM w0.102: Q7.6 31.3,76.24 30.7,76.85 R1860.2 30.26,76.38 v4(30.59,76.05) ; v4(33.21,74.04) 33.51,74.35 Q7.3
ISP_DAT1: length 10.8
  TOP w0.102: v4(36.99,74.17) 38.53,74.17 R57.2
  L3 w0.127: v4(36.99,74.17) 35.21,75.95 35.21,77.32 v4(34.86,77.67)
  BOTTOM w0.102: Q4.6 35.21,77.32 v4(34.86,77.67) ; Q4.3 38.15,74.94 38.34,74.75 v2(38.34,74.5) 38.34,74.4 38.11,74.17 v4(36.99,74.17)
ISW: length 16.6
  TOP w0.508: C10.1 38.01,39.5 38.18,39.67 v4(38.18,40.49)
  L3 w0.508: v4(38.18,40.49) 39.1,41.4 42.2,41.4 v4(43.47,40.13)
  BOTTOM w0.254: v4(38.18,40.49) 38.18,39.78 37.87,39.46 U120.19
  BOTTOM w0.508: R79630.2 47.81,41.21 46.02,39.42 v2(45.73,39.42) 45.7,39.45 44.15,39.45 v4(43.47,40.13)
ISW_1:
  vias: v2(45.3,49.73)
JACK_PSID: length 38.4
  TOP w0.102: DCIN1.3 52.12,28.96 ; 52.12,28.96 54.9,28.96 55.64,29.7 55.64,30.84 55.64,30.84 DCIN2.11 ; 52.12,28.96 52.12,29.82 48.45,33.5 48.45,36.84 48.71,37.11 49.23,37.11 v4(49.69,36.65) 49.69,37.21 49.82,37.34 49.82,38.23 50.25,38.66 50.4,38.66 50.75,39 55.21,39 55.64,38.57 DCIN2.4
  BOTTOM w0.102: L15.1 55.48,36.5 v2(55.15,36.83) 54.7,36.83 54.01,36.14 50.3,36.14 49.79,36.65 v4(49.69,36.65)
JDREF: length 4.8
  TOP w0.203: 164.87,74.08 164.69,74.27 164.65,74.27 164.39,74.53 U6.35
  TOP w0.254: R268.1 166.53,71.98 166.07,72.44 165.6,72.44 v1(165.37,72.67) 165.44,72.74 165.44,73.52 164.87,74.08
JENK#: length 4
  BOTTOM w0.102: TP4125.1 94.9,55.88 U4101.28
KBCLK: length 5.3
  TOP w0.102: U109.78 144.42,53.58 v4(145.07,54.23)
  BOTTOM w0.102: RN10.3 145.33,53.72 145.07,53.98 v4(145.07,54.23) 144.38,53.54 v2(143.72,53.54)
KBRST_N: length 165
  TOP w0.102: U109.42 153.25,59.55 153.3,59.51 153.3,58.95 153.66,58.59 153.66,58.26 154.16,57.76 v4(154.16,57.74) ; CPU1.AY15 80.76,149.86 80.68,149.86 80.3,149.48 80.3,148.32 80.31,148.31 80.31,147.89 80.22,147.8 80.22,147.29 81.03,146.47 81.03,146.08 v3(80.63,145.67)
  L3 w0.127: v4(159.59,102.97) 158.41,102.97 152.16,109.22 152.16,111.67 148.5,115.33 133.61,115.33 121.57,127.37 120.61,127.37 118.55,129.43 91.96,129.43 88.73,132.66 87.18,132.66 85.05,134.79 83.83,134.79 82.71,135.91 82.02,135.91 81.71,135.91 80.98,136.64 80.98,136.78 80.77,136.98 80.21,137.54 80.21,139.67 79.52,140.36 79.52,143.57 79.95,144.01 79.95,145 v3(80.63,145.67)
  L4 w0.127: v4(159.59,102.97) 160.43,102.13 160.43,95.5 159.37,94.44 159.37,90.51 156.18,87.32 156.18,86.79 155.48,86.09 155.48,85.01 155.7,84.8 155.7,82.31 156.47,81.53 156.47,80.89 155.7,80.12 155.7,79.8 155.7,77.75 156.18,77.27 156.18,71.56 155.1,70.48 155.1,64.51 154.73,64.14 154.73,59.58 154.11,58.95 154.11,57.81 154.16,57.76 v4(154.16,57.74)
  BOTTOM w0.102: v4(154.16,57.74) v2(153.09,57.74) 152.98,57.74 152.69,57.45 R1845.1
KDAT: length 4.9
  TOP w0.102: v4(144.2,54.24) 144.19,54.24 143.93,53.98 U109.77
  BOTTOM w0.102: v2(145.73,55.65) 145.73,55.55 145.98,55.3 RN10.4 145.8,54.37 145.45,54.72 144.69,54.72 v4(144.2,54.24)
LAD0_FWH0: length 208
  TOP w0.102: v4(156.69,57.35) 156.69,57.58 155.63,58.64 155.63,58.84 155.37,59.11 155.36,59.11 155.08,59.39 155.08,59.39 154.85,59.61 U109.38 ; v3(79,145.69) 78.39,146.3 78.39,147.85 78.5,147.96 78.5,148.23 78.2,148.53 CPU1.BB11 ; R79703.2 110.64,52.88 117.07,52.88 LPC1.5
  L3 w0.127: LPC1.5 119.13,53.24 121.49,53.24 122.41,52.33 127.31,52.33 127.86,52.87 129.34,52.87 130.05,53.59 132.48,53.59 133.92,52.15 139,52.15 140.59,53.75 145.32,53.75 146.41,54.84 150.71,54.84 151.34,55.47 154.14,55.47 155.66,56.99 156.29,56.99 156.65,57.35 v4(156.69,57.35) ; v3(79,145.69) 79,145.42 78.81,145.23 78.81,144.97 77.49,143.65 77.49,140.28 78.32,139.46 78.32,138.03 79.98,136.37 79.98,136.23 81.47,134.75 81.47,134.14 83.01,132.6 85.13,132.6 91.85,125.88 120.96,125.88 133,113.84 144.33,113.84 155.42,102.75 155.42,98.7 155.16,98.44 155.16,89.79 154.67,89.29 154.67,80.6 154.63,80.56 154.63,75.64 154.67,75.6 154.67,74.83 156.65,72.85 v4(156.65,72.43)
  L4 w0.127: v4(156.69,57.35) 156.34,57.7 156.34,59.73 156.4,59.78 156.4,68.96 157.12,69.68 157.12,71.96 v4(156.65,72.43)
  BOTTOM w0.102: RN7.4 v2(156.5,56.49) 156.69,56.69 v4(156.69,57.35)
LAD0_FWH0_EC: length 5.8
  TOP w0.102: v4(108.11,50.8) 108.11,51.24 R79703.1
  BOTTOM w0.102: v4(108.11,50.8) 108.36,51.05 v2(108.36,51.69) 107.77,52.28 U4101.62
LAD1_FWH1: length 209.6
  TOP w0.102: v3(77.76,147.7) 77.76,147.7 77.76,149.26 CPU1.BA11 ; R79702.2 111.37,52.6 117.93,52.6 118.35,53.02 119.21,53.02 LPC1.7 ; U109.39 154.45,59.28 154.58,59.16 154.92,59.16 155.35,58.72 155.35,58.52 155.74,58.14 155.74,57.54 v4(155.81,57.46)
  L3 w0.127: v3(77.76,147.7) 77.19,147.13 77.19,145.72 75.24,143.77 75.24,138.61 79.05,134.79 79.05,133.72 81.85,130.92 84.44,130.92 91.15,124.21 120.26,124.21 132.3,112.17 143.63,112.17 153.75,102.05 153.75,99.39 152.85,98.5 152.85,92.37 153.72,91.5 153.72,80.95 153.72,80.94 153.72,75.26 153.75,75.22 153.75,73.79 155.99,71.56 155.99,70.6 v4(156.62,69.96) ; LPC1.7 121.07,54.09 122.53,52.63 127.19,52.63 127.73,53.18 129.21,53.18 129.92,53.89 132.6,53.89 134.04,52.45 138.87,52.45 140.47,54.05 143.31,54.05 143.97,54.71 145.26,54.71 146.35,55.79 154.03,55.79 155.7,57.46 v4(155.81,57.46)
  L4 w0.127: v4(155.81,57.46) 155.81,57.61 155.9,57.69 155.9,59.71 156.09,59.91 156.09,69.43 v4(156.62,69.96)
  BOTTOM w0.102: RN7.3 154.84,56.92 154.95,57.02 155.48,57.02 155.81,57.36 v4(155.81,57.46) 155.99,57.63 v2(155.99,58.29)
LAD1_FWH1_EC: length 6.2
  TOP w0.102: R79702.1 109.7,51.74 108.25,50.29 107.86,50.29 v4(107.35,50.8) v1(107.35,51.69)
  BOTTOM w0.102: v4(107.35,50.8) 107.5,50.95 107.5,51.79 107.41,51.88 U4101.63
LAD2_FWH2: length 208.6
  TOP w0.102: R79701.2 112.11,52.32 118.05,52.32 118.47,52.74 120.93,52.74 LPC1.9 ; v4(155.25,57.97) 155.25,58.22 155.07,58.39 155.07,58.6 154.8,58.88 154.46,58.88 154.05,59.28 U109.40 ; v3(79,146.33) 78.59,146.74 78.59,147.77 78.71,147.88 78.71,148.31 78.5,148.51 78.5,150.2 CPU1.AY11
  L3 w0.127: v4(156.62,70.72) 157.12,71.22 157.12,71.68 156.84,71.96 156.45,71.96 154.36,74.05 154.36,75.47 154.33,75.51 154.33,80.69 154.36,80.72 154.36,89.42 154.86,89.92 154.86,98.57 155.12,98.83 155.12,102.62 144.2,113.54 132.87,113.54 120.83,125.58 91.72,125.58 85,132.3 82.88,132.3 81.16,134.01 81.16,134.62 79.68,136.1 79.68,136.24 78.01,137.91 78.01,139.33 77.19,140.16 77.19,143.78 78.58,145.18 78.58,145.91 v3(79,146.33) ; LPC1.9 123.43,52.94 127.06,52.94 127.61,53.48 129.08,53.48 129.8,54.2 132.73,54.2 132.99,53.94 139.27,53.94 140.15,54.81 143,54.81 143.83,55.65 145.77,55.65 146.22,56.1 153.38,56.1 v4(155.25,57.97)
  L4 w0.127: v4(156.62,70.72) 155.79,69.89 155.79,60.04 155.59,59.84 155.59,58.32 v4(155.25,57.97)
  BOTTOM w0.102: RN7.2 154.34,56.87 154.78,57.3 154.97,57.3 155.25,57.58 v4(155.25,57.97) 155.23,57.99 155.23,59.23 v2(155.33,59.33)
LAD2_FWH2_EC: length 5.4
  TOP w0.102: v1(105.82,50.29) 105.82,50.29 106.33,50.8 v4(106.51,50.8) 106.7,50.8 107.49,50.01 108.36,50.01 109.15,50.8 R79701.1
  BOTTOM w0.102: U4101.64 v4(106.51,50.8)
LAD3_FWH3: length 205.7
  TOP w0.102: U109.41 153.65,59.18 154.23,58.6 154.43,58.6 v4(154.61,58.42) ; CPU1.BA13 79.8,149.74 v3(80.17,150.11) ; LPC1.11 122.65,52.46 118.58,52.46 118.09,51.97 116.88,51.97 116.5,51.59 115.5,51.59 115.22,51.31 115.12,51.31 115.02,51.2 115.02,51.1 114.78,50.86 R79700.2
  L3 w0.127: LPC1.11 125.13,53.24 126.93,53.24 127.48,53.79 128.96,53.79 129.67,54.5 132.86,54.5 133.12,54.24 139.15,54.24 140.02,55.12 142.87,55.12 143.71,55.95 145.64,55.95 146.09,56.4 152.75,56.4 153.44,57.09 153.44,58.06 153.86,58.48 154.55,58.48 v4(154.61,58.42) ; v3(80.17,150.11) 80.17,149.36 78.4,147.6 78.4,146.69 78.12,146.41 78.12,145.8 75.86,143.54 75.86,140.4 77.25,139.02 77.25,137.59 78.92,135.92 78.92,135.79 79.66,135.04 79.66,133.97 82.1,131.53 84.69,131.53 91.41,124.82 120.51,124.82 132.55,112.78 143.89,112.78 154.36,102.3 154.36,99.14 154.1,98.88 154.1,94.8 153.82,94.53 153.51,94.53 153.16,94.18 153.16,92.49 154.03,91.62 154.03,80.82 154.02,80.81 154.02,75.38 154.06,75.35 154.06,73.92 156.35,71.63 156.51,71.63 v4(156.65,71.49)
  L4 w0.127: v4(154.61,58.42) 154.62,58.42 154.62,58.75 155.29,59.42 155.29,59.97 155.48,60.16 155.48,70.32 v4(156.65,71.49)
  BOTTOM w0.102: RN7.1 153.69,56.78 153.91,57 154.08,57 154.72,57.64 154.72,58.31 v4(154.61,58.42) 154.61,58.52 v2(153.91,59.23)
LAD3_FWH3_EC: length 11.9
  TOP w0.102: v4(107.17,49.4) 107.5,49.73 108.48,49.73 109.09,50.34 110.93,50.34 111.59,51 113.43,51 R79700.1
  BOTTOM w0.102: U4101.1 106.76,50.24 107.17,49.83 v4(107.17,49.4) 107.17,48.72 v2(106.97,48.51)
LAN_DISABLE_N: length 225.3
  TOP w0.102: R777.2 60.29,158.43 59.98,158.12 59.98,156.6 59.65,156.27 59.65,154.14 59.66,154.13 R1670.1 60.22,154.23 63.08,154.23 63.34,154.5 63.67,154.5 65.13,155.96 65.13,156.31 66.02,157.2 v3(66.02,158.6) 66.02,158.74 67.59,160.31 70.18,160.31 70.37,160.5 70.63,160.5 70.93,160.2 CPU1.AH2
  L3 w0.127: v3(66.02,158.6) 65.57,158.16 64.74,158.16 64.55,158.35 58.53,158.35 57.05,159.83 52.22,159.83 50.14,161.91 43.22,161.91 42.71,161.4 42.71,160.86 44.16,159.41 44.16,153.08 43.09,152.01 40.41,152.01 39.82,152.6 39.04,152.6 38.17,151.73 v4(38.17,151.73)
  L4 w0.127: v4(38.17,151.73) 38.17,150.27 36.27,148.37 36.27,140.85 38.51,138.6 38.51,135.99 38.26,135.73 38.26,134.5 38.26,134.19 38.26,133.87 38.26,123.29 40.64,120.91 40.64,81.78 37.52,78.66 37.52,73.69 29.7,65.87 29.7,56.6 33.85,52.46 33.85,50.08 34.11,49.82 34.11,45.37 31.4,42.66 31.4,29.41 31.75,29.07 31.75,28.74 33.95,26.54 34.89,26.54 35.55,25.88 35.55,24.14 36.08,23.62 36.08,21.89 v4(35.62,21.44)
  BOTTOM w0.102: v4(35.62,21.44) 35.62,19.61 36.53,18.69 v2(39.66,18.69) 40.98,18.69 42.35,17.32 42.35,11.91 42.9,11.37 42.9,9.06 43.63,8.32 R774.1
LAN_DISABLE_N_1: length 9.1
  BOTTOM w0.254: R1180.1 48.23,6.99 46.48,6.99 Q102.B 45.75,8.16 45.75,9.04 45.52,9.27 v2(45.32,9.27) 45.09,9.27 44.84,9.02 44.84,8.05 44.23,7.44 R774.2 C591.1
LAN_DISABLE_N_2: length 9.1
  TOP w0.254: v1(47.49,4.36) 47.53,4.4 v4(47.53,5.33) 46.9,5.33 46.55,5.68 Q101.B
  BOTTOM w0.254: v2(50.96,4.57) 50.83,4.7 50.45,4.7 49.82,5.33 R764.1 R1180.2 48.29,6.03 Q102.C 46.52,5.71 46.9,5.33 v4(47.53,5.33)
LAN_DISABLE_N_3: length 8.5
  TOP w0.102: R775.2 47.67,9.6 48.32,9.6 48.52,9.4 v1(48.52,9.35) 48.52,8.93 Q101.C 46.96,7.37 46.2,7.37 R776.1 44.86,7.94 Q100.C
LAN_DISABLE_N_4: length 13.3
  TOP w0.102: v4(42.43,4.75) 42.43,4.65 42.71,4.37 43.21,4.37 v1(43.21,4.38) 43.38,4.55 43.38,6.56 43.61,6.78 44.88,6.78 C593.1 R776.2
  BOTTOM w0.102: v2(38.51,8.38) 38.58,8.45 PC140.2 40.23,8.45 42.32,6.35 42.48,6.35 42.96,5.87 42.96,5.28 v4(42.43,4.75)
LAN_DISABLE_V3: length 6.7
  TOP w0.102: R1194.2 R1183.1 ; R1183.1 C863.1 ; R1183.1 41.59,6.41 Q100.B 41.97,4.95 41.97,4.94 41.97,4.52 v4(41.77,4.32)
  BOTTOM w0.102: v2(43.16,4.39) 43.06,4.29 42.24,4.29 42.21,4.32 v4(41.77,4.32)
LAN_LEDACT_R#: length 8.7
  TOP w0.254: RJ1.10 82.08,21.84 82.08,26.54 81.64,26.98 81.12,27.5 UR5.2
  BOTTOM w0.254: v2(81.26,22) 81.26,21.05 RJ1.10
LAN_MDI0_C_DN: length 27.9
  TOP w0.089: XF1.2 61.4,8.76 62.33,7.84 62.94,7.84 v4(63.03,7.75) ; RJ1.2 v4(80.1,10.27)
  L4 w0.102: v4(80.1,10.27) 80.32,10.27 80.69,9.89 80.69,7.72 79.09,6.12 66.73,6.12 65.45,7.4 63.37,7.4 v4(63.03,7.75)
  BOTTOM w0.089: v4(63.03,7.75) 63.28,7.49 v2(63.91,7.49)
LAN_MDI0_C_DP: length 27.8
  TOP w0.089: RJ1.1 v4(81.37,10.27) ; v4(63.03,6.99) 62.52,7.49 XF1.1
  L4 w0.102: v4(63.03,6.99) 63.11,7.07 65.31,7.07 66.59,5.79 79.23,5.79 81.02,7.58 81.02,9.92 v4(81.37,10.27)
  BOTTOM w0.089: v4(63.03,6.99) v2(63.03,6.1)
LAN_MDI0_DN: length 16
  TOP w0.089: 41.56,12.95 40.66,13.86 U16.2 ; 41.56,12.95 41.82,12.7 42.52,12.7 44.23,10.99 U10.3 47.46,10.99 47.95,11.47 49.26,11.47 49.47,11.27 49.47,8.96 49.79,8.64 51.47,8.64 XF1.11 ; 41.56,12.95 v1(41.82,13.21)
LAN_MDI0_DP: length 15.9
  TOP w0.089: U16.1 40.57,13.46 41.67,12.36 42.38,12.36 43.56,11.17 ; v1(43.31,10.92) 43.56,11.17 ; 43.56,11.17 44.09,10.64 45.15,10.64 45.28,10.52 46.43,10.52 46.55,10.64 47.6,10.64 47.95,10.99 U10.4 48.81,10.99 49.12,10.67 49.12,8.82 49.65,8.29 50.29,8.29 51.09,7.49 XF1.12
LAN_MDI1_C_DN: length 30.3
  TOP w0.089: RJ1.6 v4(75.02,10.27) ; v4(63.12,14.69) 62.14,15.67 62.14,15.75 61.5,16.38 XF1.6
  L4 w0.102: v4(63.12,14.69) 63.34,14.47 64.77,14.47 65.64,13.6 65.64,8.9 67.23,7.32 76.35,7.32 77.02,7.98 77.02,9.23 76.43,9.81 75.47,9.81 v4(75.02,10.27)
  BOTTOM w0.089: v4(63.12,14.69) 63.2,14.69 63.91,13.97 v2(64.04,13.97)
LAN_MDI1_C_DP: length 29.9
  TOP w0.089: v4(63.12,13.92) 62.67,14.38 62.67,14.65 62.21,15.11 XF1.5 ; RJ1.3 v4(78.83,10.27)
  L4 w0.102: v4(78.83,10.27) 78.25,10.27 77.35,9.37 77.35,7.84 76.49,6.99 67.09,6.99 65.31,8.76 65.31,13.46 64.63,14.14 63.34,14.14 v4(63.12,13.92)
  BOTTOM w0.089: v2(63.15,13.08) 63.15,13.18 63.12,13.21 v4(63.12,13.92)
LAN_MDI1_DN: length 16.6
  TOP w0.089: XF1.7 50.71,16.38 50.2,15.88 49.56,15.88 49.18,15.49 ; 49.18,15.49 48.93,15.24 48.93,13.59 48.69,13.35 47.42,13.35 46.84,12.77 45.98,12.77 U10.1 45.73,12.77 44.9,12.77 44.3,13.37 44.3,14.53 43.32,15.51 42.2,15.51 41.89,15.2 40.76,15.2 40.62,15.06 U16.5 ; 49.18,15.49 v1(48.93,15.75)
LAN_MDI1_DP: length 16.5
  TOP w0.089: U16.4 40.7,14.66 40.9,14.86 42.03,14.86 42.34,15.17 43.18,15.17 43.96,14.39 43.96,13.23 44.23,12.95 ; v1(43.98,12.7) 44.23,12.95 ; 44.23,12.95 44.76,12.43 46.98,12.43 47.57,13.01 48.43,13.01 U10.6 48.67,13.01 48.84,13.01 49.27,13.45 49.27,15.1 49.71,15.53 50.33,15.53 50.74,15.11 XF1.8
LAN_MDI2_C_DN: length 24.5
  TOP w0.089: RJ1.5 v4(76.29,10.27)
  L3 w0.102: v4(76.29,10.27) 76.63,10.27 76.88,10.02 76.88,7.76 75.81,6.69 66.84,6.69 64.64,8.89 63.41,8.89 v4(63.03,9.27)
  BOTTOM w0.089: XF2.5 61.5,8.76 61.88,8.38 62.14,8.38 v4(63.03,9.27) 63.15,9.4 63.15,10.16 v2(63.28,10.29)
LAN_MDI2_C_DP: length 24.3
  TOP w0.089: RJ1.4 v4(77.56,10.27)
  L3 w0.102: v4(77.56,10.27) 77.21,9.92 77.21,7.62 75.95,6.36 66.7,6.36 64.5,8.56 63.08,8.56 v4(63.03,8.51)
  BOTTOM w0.089: v2(63.79,8.89) 63.41,8.51 v4(63.03,8.51) 62.75,8.51 62.28,8.04 61.92,8.04 61.37,7.49 XF2.6
LAN_MDI2_DN: length 25.6
  TOP w0.089: v4(42.58,21.31) PR5250.2
  BOTTOM w0.089: XF2.8 50.71,8.76 50.33,8.38 50.07,8.38 49.42,9.04 49.42,10.5 49.05,10.86 48.67,10.86 U11.3 47.99,10.99 47.53,11.45 44.57,11.45 43.69,12.33 43.69,16.66 ; 43.69,16.66 43.69,19.02 44.86,20.19 44.86,22.1 44.18,22.79 43.14,22.79 42.66,22.31 42.66,21.39 v4(42.58,21.31) ; 43.69,16.66 v2(44,16.66)
LAN_MDI2_DN_R: length 6.8
  TOP w0.089: v1(42.68,17.91) 42.95,17.64 ; 42.95,17.64 43.25,17.94 43.25,18.97 43.15,19.08 42.68,19.08 42.58,19.18 PR5250.1 ; 42.95,17.64 41.11,15.8 40.6,15.8 40.55,15.86 U16.7
LAN_MDI2_DP: length 25.6
  TOP w0.089: v4(43.59,21.31) PR5249.2
  BOTTOM w0.089: 43.95,19.76 43.35,19.16 43.35,12.19 44.43,11.11 45.73,11.11 U11.4 45.98,11.11 47.38,11.11 47.97,10.52 48.9,10.52 49.07,10.35 49.07,8.9 49.93,8.04 50.33,8.04 50.88,7.49 XF2.7 ; 43.95,19.76 44.52,20.34 44.52,21.96 44.03,22.44 43.28,22.44 43,22.17 43,21.58 43.27,21.31 v4(43.59,21.31) ; 43.95,19.76 v2(43.72,19.99)
LAN_MDI2_DP_R: length 6.8
  TOP w0.089: 42.17,16.38 41.25,15.46 U16.6 ; 42.17,16.38 43.59,17.8 PR5249.1 ; 42.17,16.38 v1(42.43,16.13)
LAN_MDI3_C_DN: length 24.3
  TOP w0.089: RJ1.8 v4(72.48,10.27)
  L3 w0.102: v4(72.48,10.27) 72.82,10.27 73.19,9.91 73.19,9.14 72.44,8.39 66.82,8.39 64.75,10.46 64.71,10.46 64.63,10.55 64.63,15.63 64.18,16.08 63.25,16.08 v4(63.12,16.21)
  BOTTOM w0.089: v2(64.17,16.21) v4(63.12,16.21) 62.75,15.84 62.05,15.84 61.5,16.38 XF2.1
LAN_MDI3_C_DP: length 25.1
  TOP w0.089: RJ1.7 v4(73.75,10.27)
  L3 w0.102: v4(73.75,10.27) 73.52,10.04 73.52,9.01 72.57,8.06 66.68,8.06 64.61,10.13 64.57,10.13 64.3,10.41 64.3,15.49 64.04,15.75 63.42,15.75 v4(63.12,15.45)
  BOTTOM w0.089: XF2.2 61.5,15.11 61.88,15.49 63.08,15.49 v4(63.12,15.45) 64.47,15.45 v2(64.8,15.11)
LAN_MDI3_DN: length 28.9
  TOP w0.089: PR5248.2 v4(39.53,21.31)
  BOTTOM w0.089: XF2.12 51.09,16.38 50.63,15.93 49.74,15.93 49.18,15.37 49.18,13.21 48.86,12.89 U11.1 47.99,12.89 47.53,13.35 45.25,13.35 45.01,13.59 45.01,14.77 45.63,15.39 ; v2(45.85,15.16) 45.63,15.39 ; 45.63,15.39 46.06,15.82 46.06,22.59 44.67,23.98 41.28,23.98 39.68,22.38 39.68,21.46 v4(39.53,21.31)
LAN_MDI3_DN_R: length 3.2
  TOP w0.089: U16.10 38.88,17.51 39.86,18.49 39.86,19.29 PR5248.1
LAN_MDI3_DP: length 28.9
  TOP w0.089: v4(40.55,21.31) PR5247.2
  BOTTOM w0.089: 45.71,18.49 45.71,15.96 44.67,14.92 44.67,13.45 45.1,13.01 45.73,13.01 U11.6 47.5,12.89 47.97,12.43 49.13,12.43 49.52,12.83 49.52,15.22 49.88,15.58 50.62,15.58 51.09,15.11 XF2.11 ; 45.71,18.49 45.71,22.45 44.53,23.64 41.43,23.64 40.03,22.24 40.03,21.53 40.24,21.31 v4(40.55,21.31) ; 45.71,18.49 v2(45.4,18.49)
LAN_MDI3_DP_R: length 3.6
  TOP w0.089: 40.2,18.62 40.2,19.28 PR5247.1 ; 40.2,18.62 40.2,18.35 39.28,17.42 U16.9 ; 40.2,18.62 v1(40.57,18.62)
LAN_RSET: length 2.8
  TOP w0.102: R412.2 39.28,11.02 v1(39.25,11.05) 38.88,11.42 38.88,12.77 U16.31
LAN_XTALI: length 9.8
  TOP w0.102: X4.1 36.44,6.98 36.44,8.8 R407.2 35.97,9.68 35.28,10.38 C1800.1 36.18,10.54 v1(36.28,10.44) 36.28,10.46 36.61,10.79 37.45,10.79 37.74,11.08 37.74,12.21 37.68,12.26 U16.28
LAN_XTALO: length 8.3
  TOP w0.102: X4.3 39.42,7.61 v1(39.58,7.77) 38.96,8.39 38.37,8.39 R407.1 37.31,9.46 C1799.1 37.96,10.94 37.96,12.15 38.08,12.26 U16.29
LANCLK_REQ_N: length 320
  TOP w0.102: R1674.1 82.87,144.43 82.87,145.37 v3(82.31,145.92) 82.31,145.98 81.91,146.39 81.91,146.68 81.5,147.08 81.5,148 CPU1.BC15 ; R413.2 v4(37.5,21.31)
  L3 w0.127: v4(141.66,27.43) 141.64,27.43 141.13,27.94 140.72,27.94 140.43,27.65 138.95,27.65 137.52,29.08 130.27,29.08 129.66,29.69 129.34,29.69 129.19,29.54 128.44,29.54 128.29,29.69 117.91,29.69 116.21,31.39 111.33,31.39 109.81,29.88 101.59,29.88 99.13,32.33 93.22,32.33 90.59,29.71 67.46,29.71 65.29,31.88 49.51,31.88 46.4,28.77 46.4,25.9 42.86,22.35 38.54,22.35 v4(37.5,21.31) ; v4(157.96,95.63) 162.26,99.93 162.26,103.66 161.68,104.24 160.16,105.76 160.16,114.09 159.55,114.7 150.8,114.7 148.99,116.51 134.1,116.51 122.06,128.56 121.1,128.56 119.04,130.61 92.45,130.61 89.22,133.85 87.67,133.85 85.54,135.98 84.53,135.98 82.34,138.17 82.34,143.23 81.89,143.67 81.89,145.5 v3(82.31,145.92)
  L4 w0.127: v4(157.96,95.63) 157.96,90.18 155.42,87.63 155.42,87.11 154.55,86.24 154.55,71.81 154.05,71.31 154.05,66.93 153.41,66.3 153.41,59.87 152.92,59.38 152.92,56.28 154.05,55.16 154.05,54.34 153.61,53.91 153.61,49.97 154.17,49.41 154.17,48.84 154.4,48.61 154.4,43.74 154.63,43.51 154.63,42.97 155.19,42.41 155.19,39.24 154.43,38.48 154.43,37.27 146.56,29.4 142.57,29.4 141.66,28.49 141.66,27.43 v4(141.66,27.43)
  BOTTOM w0.102: v4(157.96,95.63) 157.89,95.63 157.56,95.3 v2(157.22,95.3) ; v2(37.68,20.45) 37.68,21.13 v4(37.5,21.31)
LANCLK_REQ_U_N: length 2.9
  TOP w0.102: R413.1 37.5,18.9 37.75,18.64 v1(37.75,18.6) 37.8,18.6 38.02,18.37 38.02,17.72 38.08,17.66 U16.12
LDO_VDD33_18: length 15.3
  TOP w0.076: v3(76.03,102.82) 75.99,102.86 75.2,102.86 75.06,102.72 75.06,102.51 74.91,102.36 74.7,102.36 74.45,102.11 U902.F8
  TOP w0.102: v3(70.67,99.31) 70.67,99.47 U902.K2
  TOP w0.508: C9015.1 67.51,97.32 C9016.1 67.69,97.94 67.7,97.94 v1(68.82,99.06) 70.41,99.06 v3(70.67,99.31)
  L3 w0.508: v3(70.67,99.31) 70.67,99.51 72.34,101.18 74.38,101.18 76.02,102.82 v3(76.03,102.82)
LDR: length 6.5
  BOTTOM w0.305: U120.1 39.33,37.9 39.58,38.15 40.34,38.15
  BOTTOM w0.508: R65.2 43.42,41.22 v2(42.35,40.16) 40.34,38.15
LDR_1: length 3.8
  BOTTOM w0.508: Q1250.4 45.68,42.24 R65.1 46.03,41.91 v2(46.77,41.17)
LDRQ#: length 245.5
  TOP w0.102: U109.2 159.37,46.78 159.43,46.84 159.89,46.84 160.15,46.57 160.15,46.19 160.13,46.16 160.13,45.79 160.75,45.16 v4(160.84,45.16) 161.09,44.91 161.25,44.91 161.64,44.51 R316.1 ; CPU1.BA1 69.45,149.25 68.59,149.25 68.13,148.79 v3(68.12,148.79)
  L3 w0.127: v4(160.84,45.16) 157.81,45.16 157.45,44.79 149.81,44.79 148.98,43.97 142.63,43.97 142.27,44.32 140.72,44.32 139.96,43.56 130.89,43.56 130.69,43.76 127.87,43.76 127.15,44.49 122.61,44.49 120.91,46.19 111.83,46.19 111.19,45.55 108.48,45.55 v4(108.11,45.19) ; v4(67.83,136.27) 69.89,136.27 80.1,126.06 81.72,126.06 87.9,119.89 118.12,119.89 131.96,106.05 144.93,106.05 146.75,104.23 146.75,77.01 145.42,75.68 145.42,73.69 146.57,72.54 150.51,72.54 151.04,72.01 153.12,72.01 155.81,69.32 159.06,69.32 v4(159.9,68.48)
  L4 w0.127: v4(160.84,45.16) 160.84,45.21 162.07,46.44 162.07,54.27 161.53,54.81 161.53,58.05 160.8,58.79 160.8,63.26 159.9,64.16 v4(159.9,68.48) ; v4(67.83,136.27) 67.57,136.27 66.07,137.77 66.07,138.3 68.12,140.35 v3(68.12,148.79)
  BOTTOM w0.102: v4(160.84,45.16) 160.84,45.16 v2(160.84,46.05) ; R79704.2 108.24,47.56 108.24,45.31 v4(108.11,45.19)
LDRQ#_EC: length 5.5
  BOTTOM w0.102: R79704.1 v2(108.87,50.29) 108.87,51.94 108.13,52.68 U4101.61
LDT_RST: length 53.7
  TOP w0.102: R1617.2 C1721.2 v3(78.9,185.42) 79.79,184.53 79.79,183.77 80.89,182.66 80.89,181.69 80.9,181.68 80.9,181.37 80.89,181.37 80.89,180.83 81.1,180.63 81.1,180.17 81.4,179.87 CPU1.D15 ; R1745.2 v4(89,215.19) ; v4(88.63,197.28) 88.72,197.28 89.21,196.8 89.21,196.5 v1(89.16,196.45)
  L3 w0.127: v4(89,215.19) 89.45,214.73 89.45,207.77 89.48,207.74 89.48,198.12 v4(88.63,197.28)
  L4 w0.127: v4(88.63,197.28) 87.35,198.56 79.56,198.56 77.03,196.03 77.03,188.04 78.9,186.17 v3(78.9,185.42)
LDT_RST#_BUF: length 4.6
  TOP w0.102: R1745.1 90.39,214.88 v4(90.81,214.88) 91.32,214.38 HDT1.12
  BOTTOM w0.102: v4(90.81,214.88) v2(90.81,213.56)
LED_5VSB: length 4.2
  TOP w0.254: v1(92.11,4.57) 92.54,4.57 93.76,5.79 93.76,6.35 R1767.2 LED2.A
LEDC_ISET: length 5.6
  BOTTOM w0.102: R82.1 33.31,32.96 33.31,35.13 33.76,35.59 v2(33.82,35.59) 33.82,35.64 34.25,36.08 U120.12
LFRAMEJ_FW4: length 220.1
  TOP w0.102: LPC1.13 124.37,52.18 118.7,52.18 118.21,51.69 117,51.69 116.62,51.31 116.14,51.31 115.69,50.86 R79698.2 ; v4(76.78,137.87) 76.32,138.33 74.3,138.33 74.01,138.62 R1875.2 R1871.1 R1872.2 ; CPU1.AV14 81,151.7 v3(81.2,151.7) ; U109.37 155.25,59.61 155.48,59.39 155.48,59.39 155.91,58.96 155.91,58.75 156.56,58.1 v4(156.81,58.1)
  L3 w0.127: v3(81.2,151.7) 81.2,151.67 80.17,150.65 80.11,150.65 79.75,150.29 79.75,149.27 78.18,147.69 78.18,146.87 77.47,146.17 77.47,145.57 75.54,143.65 75.54,139.11 v4(76.78,137.87) 76.78,137.49 79.36,134.92 79.36,133.85 81.98,131.23 84.56,131.23 91.28,124.51 120.39,124.51 132.43,112.47 143.76,112.47 154.05,102.18 154.05,99.27 153.63,98.84 v4(153.63,95) ; LPC1.13 128.83,54.09 129.54,54.81 132.98,54.81 133.24,54.55 139.02,54.55 139.9,55.42 142.75,55.42 143.58,56.26 145.52,56.26 145.97,56.71 152.63,56.71 153.13,57.21 153.13,58.18 153.9,58.95 155.71,58.95 156.56,58.1 v4(156.81,58.1)
  L4 w0.127: v4(156.81,58.1) 157.1,58.38 157.13,58.38 157.41,58.66 157.41,59.05 156.7,59.75 156.7,66.38 157.34,67.01 157.34,67.4 157.01,67.73 157.01,68.71 157.73,69.43 157.73,75.07 157.16,75.64 157.16,83.29 157.42,83.56 157.42,83.95 157.16,84.22 157.16,85.39 162.06,90.3 162.06,92.56 v4(161.7,92.91)
  BOTTOM w0.102: v4(161.7,92.91) v2(157.13,92.91) 155.61,92.91 153.63,94.89 v4(153.63,95)
LFRAMEJ_FW4_EC: length 16.6
  TOP w0.102: R79698.1 115.03,49.53 114.14,49.53 113.25,50.42 111.4,50.42 111.04,50.06 109.21,50.06 108.6,49.45 108.16,49.45 v4(107.98,49.28)
  BOTTOM w0.102: U4101.3 104.47,47.06 v2(104.7,46.83) 106.01,46.83 107.98,48.81 v4(107.98,49.28)
LINE2-VREFO: length 5.3
  TOP w0.203: U6.29 161.99,73.62 161.69,73.32 161.18,73.32 v1(160.87,73) 160.62,72.76 R261.1 R272.1
LINEOUT-JD: length 182.5
  TOP w0.203: v4(85.73,2.41) 86.22,1.93 152.71,1.93 v4(152.89,2.11) ; v4(165.06,69.85) 164.9,69.85 164.5,70.26 R266.1
  L3 w0.203: v4(165.06,69.85) 165.06,69.29 166.91,67.44 166.91,35.06 158.59,26.74 158.59,18.29 158.15,17.84 153.13,17.84 152.16,16.87 152.16,4.86 151.93,4.63 151.93,3.07 v4(152.89,2.11)
  BOTTOM w0.203: LOUT1.Q 80.06,33.76 v2(80.37,33.45) 85.7,28.13 85.7,20.16 85.48,19.94 85.48,17.6 86.32,16.77 86.32,13.03 85.7,12.41 85.7,4.36 85.38,4.04 85.38,2.77 v4(85.73,2.41)
LINEOUT-L: length 190.4
  TOP w0.203: R429.1 v4(83.68,34.92) ; U6.19 158.69,78.03 v4(158.58,78.15) ; v4(152.89,3.73) 152,2.84 88.22,2.84 v4(87.08,3.99)
  L3 w0.203: v4(158.58,78.15) 158.58,77.97 159.24,77.31 159.24,74.29 159.87,73.66 160.87,73.66 163.51,71.02 165.26,71.02 166.1,70.17 166.1,69.54 167.83,67.82 167.83,34.68 159.51,26.36 159.51,17.91 158.53,16.93 153.66,16.93 153.07,16.34 153.07,3.91 v4(152.89,3.73)
  BOTTOM w0.203: v4(83.68,34.92) 83.68,31.65 v2(83.75,31.57) 83.78,31.57 86.61,28.74 86.61,19.78 86.39,19.56 86.39,17.98 87.23,17.14 87.23,12.65 86.61,12.03 86.61,4.46 v4(87.08,3.99)
LINEOUT-R: length 195
  TOP w0.203: v4(86.67,2.57) 86.85,2.39 152.36,2.39 v4(152.89,2.92) ; R428.1 v4(82.58,34.92) ; U6.18 159.04,78.43 158.48,78.99 v4(158.38,78.99)
  L3 w0.203: v4(158.38,78.99) 157.89,78.51 157.89,78 158.19,77.7 158.21,77.7 158.78,77.12 158.78,74.1 159.68,73.2 160.68,73.2 163.32,70.56 165.07,70.56 165.65,69.98 165.65,69.35 167.37,67.63 167.37,34.87 159.05,26.55 159.05,18.1 158.34,17.39 153.47,17.39 152.61,16.53 152.61,4.67 152.38,4.45 152.38,3.43 v4(152.89,2.92)
  BOTTOM w0.203: v4(86.67,2.57) 86.42,2.57 85.83,3.15 85.83,3.85 86.15,4.17 86.15,12.22 86.77,12.84 86.77,16.96 85.94,17.79 85.94,19.75 86.15,19.97 86.15,28.32 82.86,31.61 v2(82.86,33.4) 82.86,34.65 v4(82.58,34.92)
LINEOUT_C-L: length 3.4
  TOP w0.203: R429.2 83.83,36.77 L62.1 85.29,36.77 85.56,37.04 85.56,37.29 v4(85.61,37.34)
  BOTTOM w0.203: v4(85.61,37.34) 86.01,37.74 v2(86.01,38.23)
LINEOUT_C-R: length 3.6
  TOP w0.203: R428.2 81.88,36.64 v4(81.44,37.08) 82.01,37.66 L20.1
  BOTTOM w0.203: v2(80.63,36.98) 81.34,36.98 v4(81.44,37.08)
LINEOUT_CON-L: length 17.7
  TOP w0.203: C268.1 L62.2 85,37.91 85,39.88 84.17,40.7 84.17,41.47 83.15,42.48 Q46.1 82.35,42.34 76.91,42.34 76.59,42.66 LOUT1.4
  BOTTOM w0.203: v2(76.26,42.66) LOUT1.4
LINEOUT_CON-R: length 24.2
  TOP w0.203: LOUT1.1 73.11,32.71 72.68,33.15 72.68,38.51 76.06,41.88 82.45,41.88 Q46.2 83.15,40.13 C267.1 82.58,39.56 L20.2
  BOTTOM w0.203: LOUT1.1 v2(76.26,32.71)
LINK_ACTIVITY_N: length 87.3
  TOP w0.203: U16.27 v4(37.28,11.28)
  TOP w0.254: v4(82.81,27.28) 83.09,27 83.09,26.04 84.23,24.89 84.23,22.23 85.24,21.22 85.24,18.54 86.42,17.35 86.42,14.1 86.25,13.93 86.25,13.83 84.49,12.06 84.49,4.57 83.42,3.51 55.84,3.51 55.41,3.94 v1(55.41,4.45) 54.36,5.49 51.41,5.49 50.85,4.93 48.65,4.93 48.42,4.7 v4(48.4,4.7) ; v3(80.23,27.28) UR5.1 80.17,28.13 U12.4
  L4 w0.254: v4(48.4,4.7) 48.39,4.7 48.11,4.7 47.7,4.29 45.46,4.29 40.17,9.59 40.17,10.61 40.67,11.12 40.67,11.59 39.95,12.32 38.32,12.32 v4(37.28,11.28)
  BOTTOM w0.254: v2(49.18,4.45) 48.65,4.45 v4(48.4,4.7) ; v4(82.81,27.28) v3(80.23,27.28)
LINK_PWR: length 10.1
  TOP w0.254: R79618.2 81.64,28.56 81.64,27.55 82.48,26.71 82.48,25.88 83.56,24.8 RJ1.9
  BOTTOM w0.254: v2(83.68,22) 83.68,21.15 RJ1.9
LPC_CLK0_R: length 17.9
  TOP w0.102: v3(81.2,151.06) 80.97,151.3 CPU1.AW14 ; v4(78.93,139.06) 78.93,138.69 80.45,137.16 R1646.2
  L3 w0.127: v3(81.2,151.06) 81.2,149.37 79.42,147.59 79.42,145.52 79.04,145.14 79.04,144.63 77.89,143.49 77.89,140.45 78.93,139.42 v4(78.93,139.06)
  BOTTOM w0.102: v4(78.93,139.06) 79,139.06 79.51,138.56 v2(79.56,138.56)
LPC_CLK1: length 203.3
  TOP w0.102: C66.1 R1869.1 80.36,138.18 v4(81.57,138.18) ; C66.1 R1876.2 ; C66.1 78.96,139.83 R1870.2 78.71,141.26 79.28,141.83 R123.1 ; v4(157.89,99.85) 158.24,100.2 v1(158.66,100.2)
  L3 w0.127: v4(157.89,99.85) 158.66,99.85 161.04,102.23 161.04,104.32 159.76,105.6 159.76,113.93 159.38,114.3 150.64,114.3 148.82,116.11 133.94,116.11 121.9,128.15 120.93,128.15 118.87,130.21 92.28,130.21 89.05,133.44 87.5,133.44 85.37,135.57 84.15,135.57 83.04,136.69 82.03,136.69 81.76,136.97 81.76,137.1 81.68,137.18 81.57,137.29 v4(81.57,138.18) ; v4(150.53,53.34) 148.67,53.34 147.96,52.62 147.12,52.62 146.51,52.01 143.9,52.01 143.66,52.25 140.63,52.25 139.45,51.06 133.4,51.06 132.37,52.09 128.18,52.09 127.64,51.54 122.08,51.54 121.17,52.46 115.91,52.46 LPC1.1
  L4 w0.127: v4(157.89,99.85) 157.75,99.71 157.75,98.56 157.09,97.91 157.09,90.23 154.76,87.9 154.76,87.38 153.9,86.51 153.9,72.09 152.69,70.88 152.69,67.43 151.35,66.09 151.35,59.69 150.95,59.29 150.95,56.51 150.6,56.16 150.6,53.41 v4(150.53,53.34)
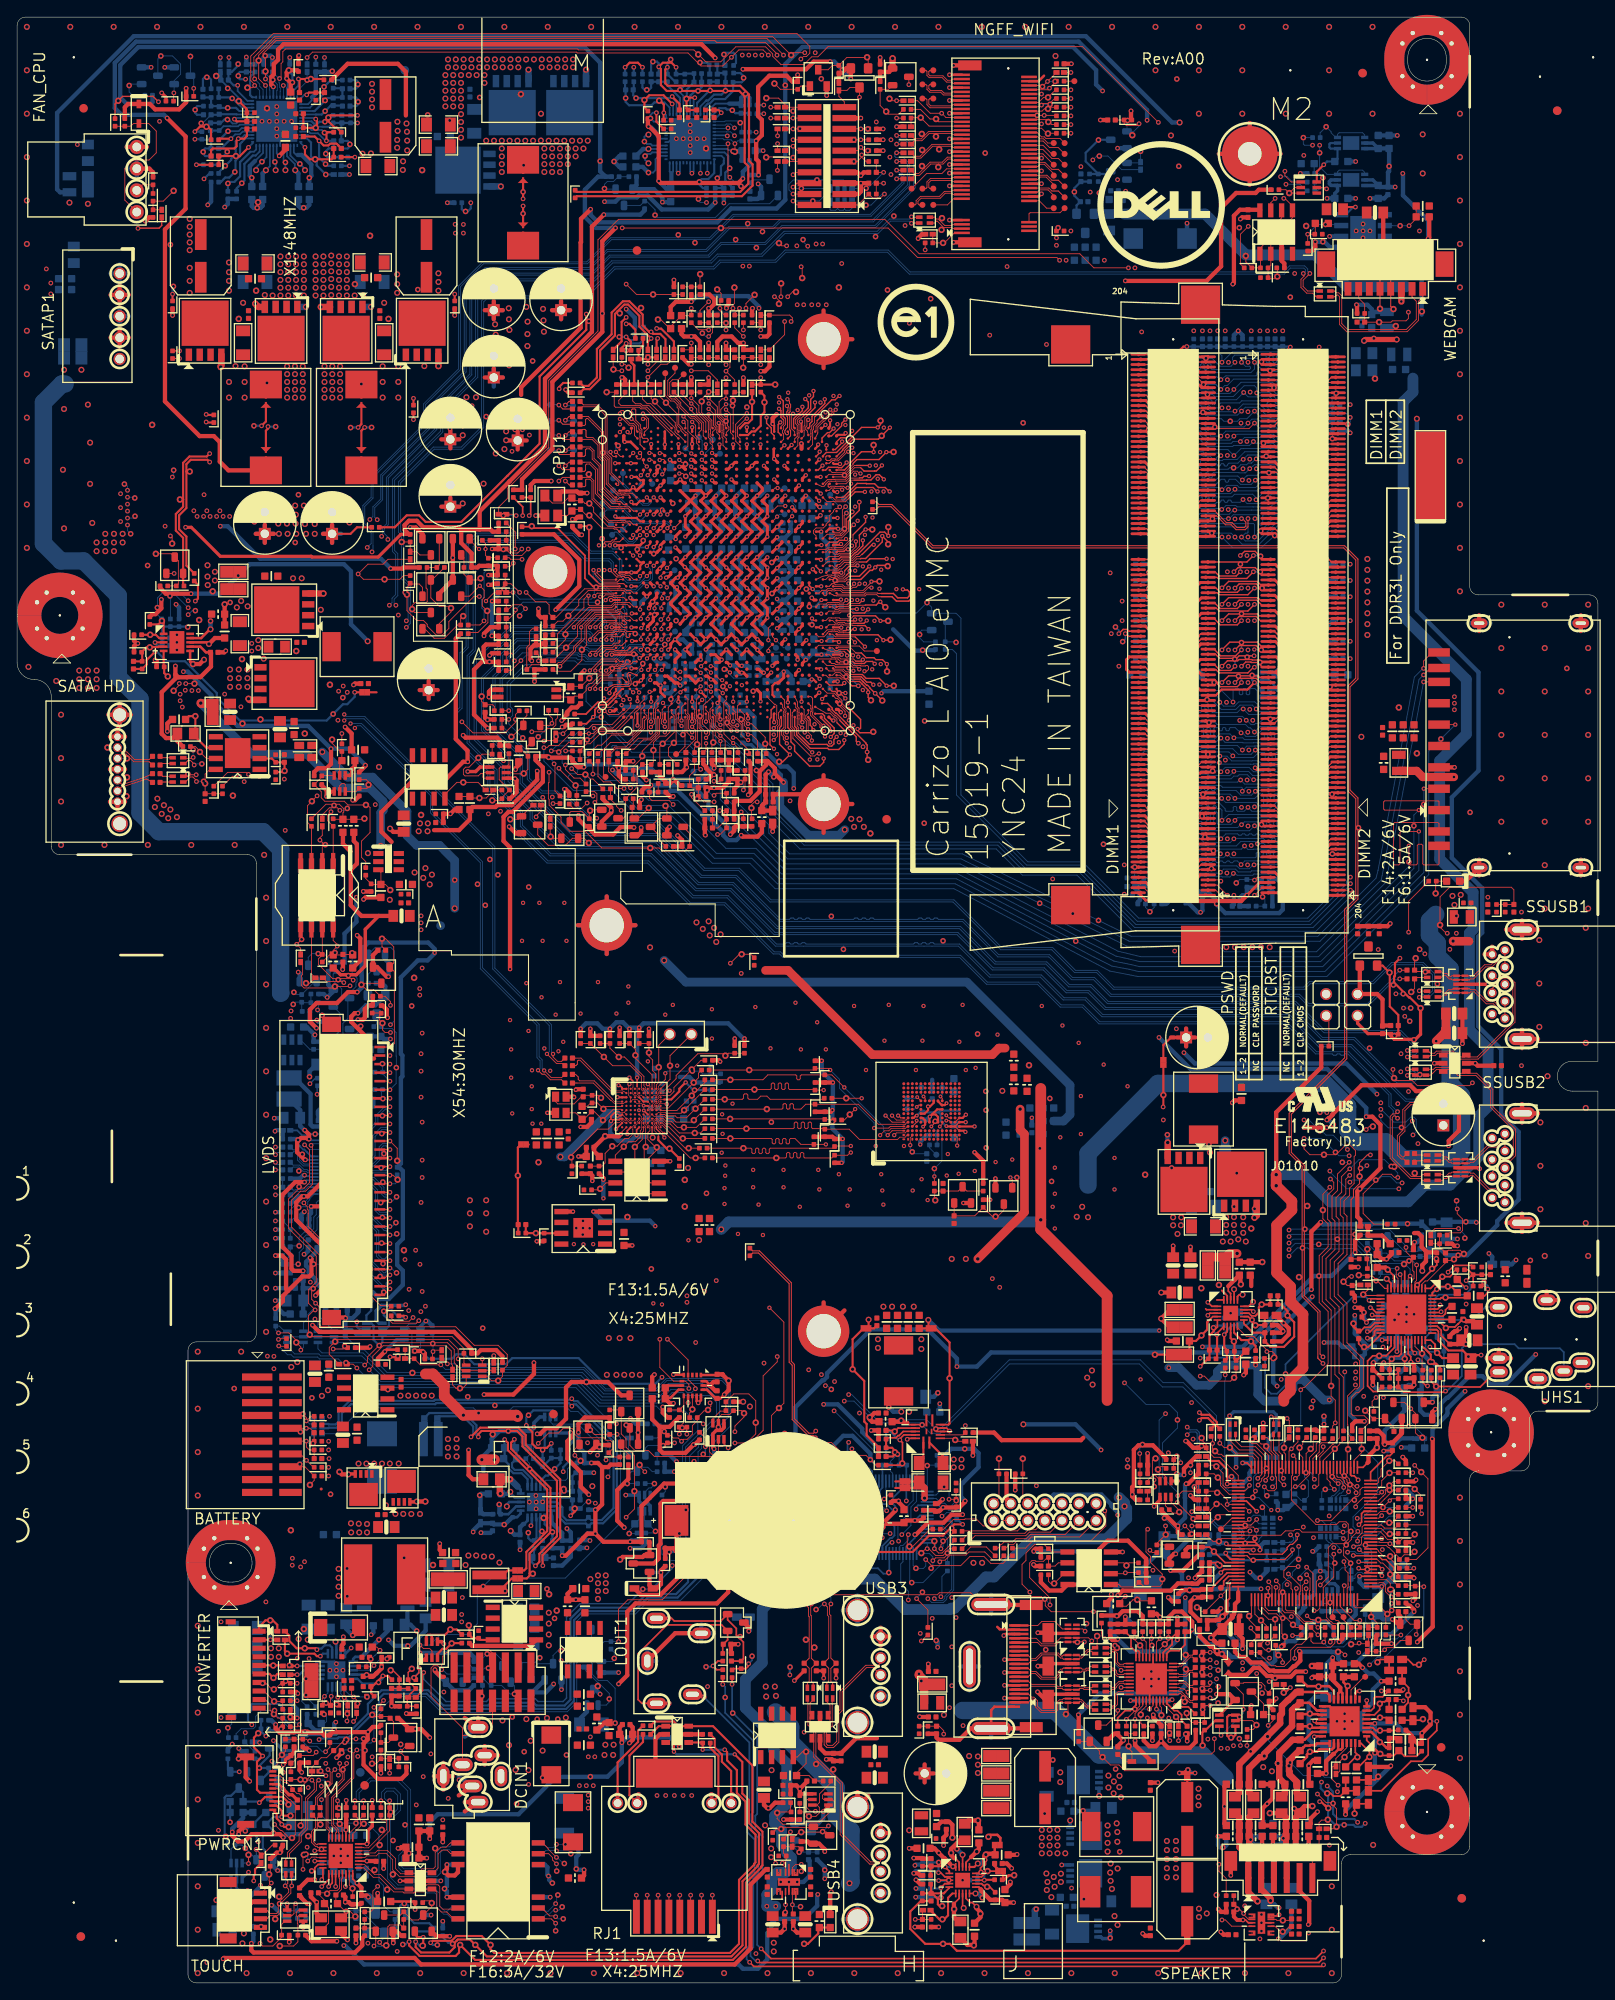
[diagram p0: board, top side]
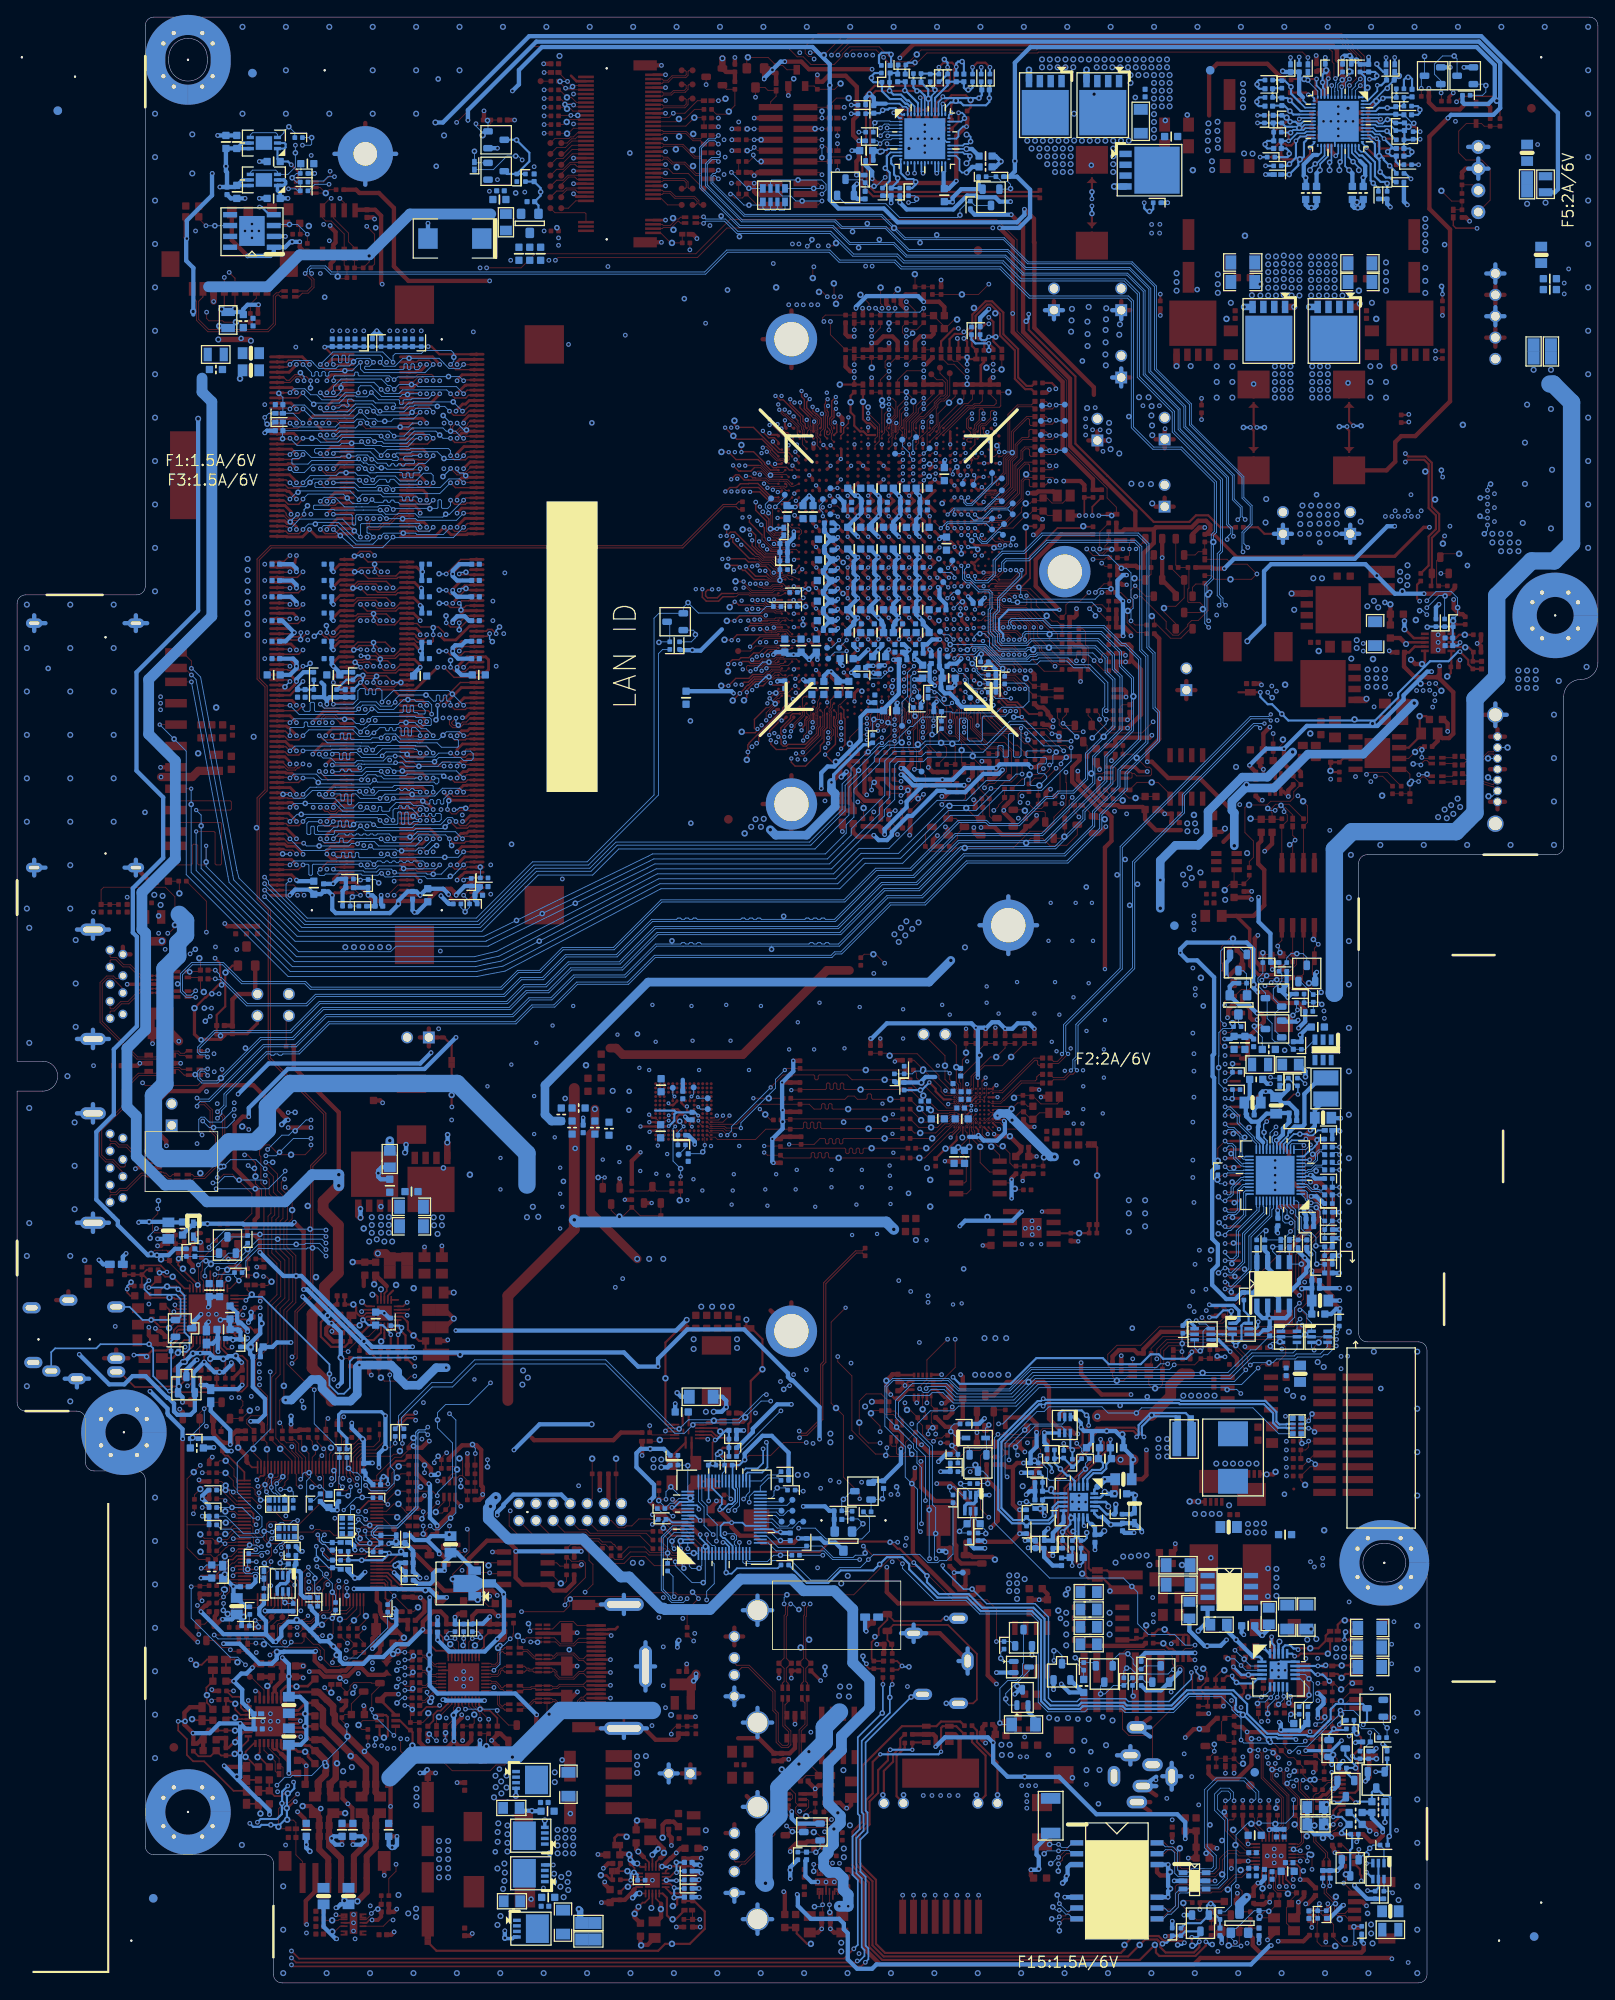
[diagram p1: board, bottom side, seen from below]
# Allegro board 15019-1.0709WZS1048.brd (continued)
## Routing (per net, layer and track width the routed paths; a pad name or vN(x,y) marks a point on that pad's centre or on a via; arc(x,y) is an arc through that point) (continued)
LPC_CLK1_R: length 6.9
  TOP w0.102: R123.2 79.28,144.53 79.59,144.83 v1(79.59,144.91) 79.59,144.96 79.61,144.98 79.61,146.74 79.61,147.85 79.5,147.96 79.5,148.23 79.51,148.23 79.51,148.77 79.5,148.77 79.5,150.2 CPU1.AY13
LPC_PD_N: length 2.3
  TOP w0.102: v3(76.13,162) 76.5,162.37 CPU1.AE9
  BOTTOM w0.102: v3(76.13,162) 75.42,162.71 TP9.1
LPC_PME_N: length 356.3
  TOP w0.102: v4(153.63,93.09) 152.81,92.28 v1(152.81,90.42) 152.81,89.4 153.42,88.79 153.42,86.13 152.38,85.09 152.38,79.6 153.42,78.56 153.42,72.43 150.67,69.68 150.51,69.68 v4(150.22,69.39) ; v4(130.06,200.66) 126.02,200.66 124.37,202.31 105.57,202.31 101.55,206.33 70.37,206.33 67.98,203.94 67.98,193.27 62.21,187.5 62.21,179.65 57.44,174.88 57.44,173.75 56.36,172.66 R568.1
  L3 w0.127: v4(149.51,200) 149.73,199.79 149.73,196.55 162.51,183.77 164.12,183.77 164.99,182.89 164.99,155.78 165.07,155.7 165.07,139.54 164.84,139.31 164.84,124.26 v4(161.79,121.21) ; v4(146.92,58.04) 147.5,58.62 147.5,59.58 147.14,59.94 144.48,59.94 144.04,59.5 143.83,59.5 143.25,58.93 138.01,58.93 136.96,57.87 132.31,57.87 131.05,59.13 113.51,59.13 111.75,57.37 107.9,57.37 107.03,58.23 91.79,58.23 91.22,58.8 v4(89.82,58.8)
  L4 w0.127: v4(161.79,121.21) 162.36,120.63 162.36,117.01 162.21,116.86 162.21,114.68 161.68,114.14 161.68,112.63 156.61,107.57 156.61,105.53 155.65,104.57 155.65,100.6 154.26,99.21 154.26,93.72 v4(153.63,93.09) ; v4(149.51,200) 132.14,200 131.01,201.13 130.53,201.13 v4(130.06,200.66) ; v4(90.71,50.04) 88.81,51.94 88.81,57.53 89.82,58.55 v4(89.82,58.8)
  BOTTOM w0.102: v4(146.92,58.04) 147.33,58.45 147.33,59.22 147.29,59.26 R80224.2 R1843.2 150.22,65.42 v4(150.22,69.39) ; R79709.2 v4(90.71,50.04)
LPC_TPM: length 2.2
  TOP w0.102: v3(80,151.7) 79.6,151.3 CPU1.AW12
  BOTTOM w0.102: v3(80,151.7) 79.51,151.21 TP187.1
LPF: length 3.4
  TOP w0.102: v4(36.76,33.53) 36.69,33.45 C3455.1
  BOTTOM w0.102: U120.9 36.87,33.64 v4(36.76,33.53) 36.76,33.21 v2(37.38,32.59)
LVDS_BL_ADJ: length 6.4
  TOP w0.165: R134.2 45.68,32.37 R132.1 45.66,33.3 R1984.1 45.77,33.56 46.1,33.89 46.1,33.89 R133.1 45.77,35.33 R131.1 45.77,36.33 v1(46.19,36.75)
LVDS_BL_EN_1: length 3.8
  TOP w0.102: R79686.2 148.27,63.21 v1(148.27,62.61) 148.27,62.05 148.46,61.86 U109.54
LVDS_DET_A*: length 163.6
  TOP w0.102: v4(152.51,47.42) 152.05,46.97 U109.116 ; v4(43.63,93.5) LVDS1.17
  L3 w0.127: v4(152.51,47.42) 151.75,46.66 151.75,45.76 151.58,45.59 149.48,45.59 148.7,44.82 145.67,44.82 144.52,45.97 140.9,45.97 139.28,44.36 131.57,44.36 131.36,44.56 128.2,44.56 127.45,45.31 122.92,45.31 121.24,46.99 112.07,46.99 111.5,46.99 110.93,46.43 100.8,46.43 100.48,46.75 97.14,46.75 96.12,47.77 90.87,47.77 86.35,52.29 82.67,52.29 v4(81.95,51.56) ; v4(80.42,80.9) 79.26,82.07 46.56,82.07 44.33,84.29 44.33,84.47 43.77,85.03 43.44,85.03 43.16,85.31 43.16,93.03 v4(43.63,93.5)
  L4 w0.127: v4(80.42,80.9) 80.42,77.85 84.42,73.85 84.42,67.3 84.48,67.25 84.48,62.74 83.37,61.63 83.37,55.79 81.95,54.37 v4(81.95,51.56)
  BOTTOM w0.102: v4(43.63,93.5) 44.26,93.5 44.48,93.73 R482.2 ; v2(82.84,51.56) v4(81.95,51.56)
LVDS_DET_B*: length 196.6
  TOP w0.102: v4(151.79,43.54) 152.15,43.54 152.45,43.84 U109.117 ; v4(43.7,114.38) 43.7,114.81 43.06,115.44 R483.2 41.72,116.24 40.84,116.24 v1(40.29,116.79) 40.46,116.95 Q103.D
  L3 w0.127: v4(82.58,49.28) 84.5,49.28 85.01,48.76 85.37,48.76 88.22,45.91 95.41,45.91 96.53,44.79 96.53,42.7 97.49,41.73 99.42,41.73 99.98,42.29 106.15,42.29 106.67,41.77 116.26,41.77 118.66,39.37 122.15,39.37 122.37,39.15 137.45,39.15 138.89,40.59 140.84,40.59 143.49,37.93 143.61,37.93 144.02,37.53 146.76,37.53 149.24,40.01 152.18,40.01 153.36,41.19 153.36,41.87 151.79,43.44 v4(151.79,43.54) ; v4(43.7,114.38) 43.96,114.38 44.43,113.91 44.43,85.6 44.91,85.12 44.91,84.43 46.77,82.58 81.41,82.58 v4(81.82,82.17)
  L4 w0.127: v4(81.82,82.17) 81.82,77.6 86.3,73.11 86.3,63.79 84.42,61.91 84.42,51.12 v4(82.58,49.28)
LVDS_DET_B_C*: length 16.9
  TOP w0.102: LVDS1.1 43.75,109.5 44.15,109.91 44.15,118.32 Q103.G 44.08,119.32 44.08,121.22 43.12,122.17 v1(42.71,122.17) 42.71,121.25 C869.1
LVDS_PU_5: length 3.6
  TOP w0.102: LVDS1.5 v4(43.63,105.5)
  BOTTOM w0.102: v4(43.63,105.5) 42.77,106.36 R1163.2 42.77,107.53 v2(42.76,107.54)
LVDS_PU_5_1: length 1.6
  BOTTOM w0.102: R484.1 42.07,112.2 Q9647.D
LVDS_PU_5_2: length 3.6
  BOTTOM w0.102: Q9647.G 41.12,115.61 R80233.1 41.12,118.05 41.5,118.43 Q9650.D
LVDS_PU_6: length 10.2
  TOP w0.102: LVDS1.6 v4(43.63,104.5)
  BOTTOM w0.102: R484.2 42.87,111.66 43.89,111.66 44.36,111.19 44.36,108.45 44.38,108.43 v2(44.38,107.09) 44.38,107.04 44.36,107.01 44.36,105.23 v4(43.63,104.5)
LVDS_PU_24: length 20.8
  TOP w0.102: v4(43.63,86.5) LVDS1.24
  L4 w0.127: v4(43.63,86.5) 43.41,86.5 43.16,86.74 43.16,87.69 43.16,87.7 43.16,87.97 43.16,87.97 43.16,103.03 v4(43.63,103.5)
  BOTTOM w0.102: v4(43.63,103.5) 43.48,103.35 42.91,103.35 v2(42.81,103.45) 42.63,103.63 42.63,104.38 R481.2
LX:
  vias: v2(38.62,48.49) v2(38.64,45.24) v7(37.63,48.44) v7(37.63,47.4) v7(37.63,46.35) v7(37.63,45.29)
M1_SMB_CLK: length 4.7
  TOP w0.102: R14.2 121.42,220.47 120.84,219.89 120.06,219.89 v4(119.88,219.71) 119.87,219.71 119.67,219.5 NGFF1.60
  BOTTOM w0.102: v2(120.89,219.79) 119.96,219.79 v4(119.88,219.71)
M1_SMB_DATA: length 3.4
  TOP w0.102: NGFF1.58 119.95,219 120.21,219.27 v1(120.64,219.27) 120.75,219.27 120.94,219.46 R1622.2
M_CAS_A_N: length 72.5
  TOP w0.102: 98.33,158.81 98.33,158.81 97.78,158.81 97.72,158.87 96.74,158.87 96.63,158.98 96.22,158.98 96.14,158.89 95.64,158.89 95.64,158.9 95,158.9 CPU1.AK32
  TOP w0.165: DIMM2.115 145.73,153.95 145.19,154.49 144.44,154.49 144.39,154.54 143.78,154.54 v4(143.29,154.05) ; 98.33,158.81 99.23,158.81 v3(99.64,158.4) ; v4(134.27,153.92) 133.78,153.44 132.55,153.44 132.03,153.95 DIMM1.115
  L3 w0.216: v4(143.29,154.05) 142.35,153.12 140.03,153.12 140.02,153.12 139.68,153.12 138.71,152.14 117.5,152.14 116.93,152.71 116.93,153.2 116.7,153.44 116.27,153.44 116.06,153.23 116.06,152.35 115.84,152.14 115.41,152.14 115.19,152.35 115.19,153.23 114.98,153.44 107.87,153.44 107.74,153.57 102.87,158.43 99.68,158.43 v3(99.64,158.4)
  L4 w0.216: v4(143.29,154.05) 142.77,153.54 140.79,153.54 139.89,154.44 134.82,154.44 134.31,153.92 v4(134.27,153.92)
  BOTTOM w0.165: v4(134.27,153.92) v2(134.27,154.74)
M_DATA_A0: length 91
  TOP w0.102: 89.69,182.88 89.72,182.85 89.72,182.42 89.4,182.1 CPU1.A25
  TOP w0.165: v4(132.75,189.36) 132.74,189.35 DIMM1.5 ; v3(89.17,184.17) 89.39,183.95 89.39,183.18 89.69,182.88 ; v4(147.99,189.36) 147.98,189.35 DIMM2.5
  L4 w0.216: v3(89.17,184.17) 88.7,184.64 88.7,185.9 91.39,188.59 96.5,188.59 97.77,189.87 98.26,189.87 98.48,189.66 98.48,189.28 98.7,189.06 99.13,189.06 99.34,189.28 99.34,189.66 99.56,189.87 99.99,189.87 100.21,189.66 100.21,189.28 100.42,189.06 100.86,189.06 101.07,189.28 101.07,189.66 101.29,189.87 101.72,189.87 101.93,189.66 101.93,189.28 102.15,189.06 102.58,189.06 102.8,189.28 102.8,189.66 103.01,189.87 139.02,189.87 139.24,189.66 139.24,188.66 139.46,188.44 139.89,188.44 140.1,188.66 140.1,189.66 140.32,189.87 140.54,189.87 140.79,190.13 142.01,190.13 v4(142.53,189.61)
  BOTTOM w0.102: v4(132.75,189.36) 133.21,188.9 134.46,188.9 135.05,189.49 135.05,189.51 135.62,190.08 v2(139.13,190.08) 139.84,190.08 140.77,189.15 142.07,189.15 v4(142.53,189.61) 142.25,189.89 142.25,190.2 142.5,190.44 146.07,190.44 146.17,190.34 146.17,189.66 146.27,189.56 146.47,189.56 146.58,189.66 146.58,190.34 146.68,190.44 146.88,190.44 146.98,190.34 146.98,189.66 147.08,189.56 147.29,189.56 147.39,189.66 147.39,190.34 147.49,190.44 147.87,190.44 148.14,190.17 148.14,189.51 v4(147.99,189.36)
M_DATA_A1: length 92.1
  TOP w0.102: 89.86,183.09 89.92,183.03 89.92,182.33 89.7,182.11 89.7,181.77 89.57,181.64 89.57,181.36 89.7,181.23 89.7,180.6 CPU1.C25
  TOP w0.165: v4(134.27,189.36) 133.67,188.75 DIMM1.7 ; v4(149.51,189.36) 148.91,188.75 DIMM2.7 ; v3(89.19,185.55) 89.66,185.07 89.66,183.29 89.86,183.09
  L4 w0.216: v4(141,189.61) 141.77,188.85 143.4,188.85 143.62,188.63 143.62,188.31 143.4,188.09 140.66,188.09 140.5,187.93 138.46,187.93 137.55,188.84 132.53,188.84 132,189.38 103.69,189.38 102.88,188.57 97.17,188.57 96.7,188.1 91.59,188.1 89.19,185.7 v3(89.19,185.55)
  BOTTOM w0.102: v4(149.51,189.36) 148.05,190.82 142.21,190.82 v4(141,189.61) 141,190.37 140.75,190.63 137.7,190.63 137.35,190.98 134.2,190.98 133.89,190.68 v2(133.89,190.21) 133.89,189.74 v4(134.27,189.36)
M_DATA_A2: length 90.1
  TOP w0.102: CPU1.C27 91,180.65 91.3,180.95 91.3,181.24 91.29,181.25 91.29,181.74 91.3,181.75 91.3,182.24 91.11,182.42 91.11,182.93 91.53,183.35 91.67,183.35 91.91,183.59
  TOP w0.165: DIMM2.15 147.69,186.35 v4(147.99,186.06) ; DIMM1.15 132.33,186.35 v4(132.75,185.93) ; v3(92.24,185.31) 92.59,184.95 92.59,184.27 91.91,183.59
  L4 w0.216: v3(92.24,185.31) 93.11,184.44 94.43,184.44 95.13,185.14 97,185.14 97.26,185.41 106.13,185.41 106.35,185.63 106.35,186.01 106.56,186.23 106.99,186.23 107.21,186.01 107.21,185.63 107.43,185.41 107.86,185.41 108.07,185.63 108.07,186.01 108.29,186.23 108.72,186.23 108.94,186.01 108.94,185.63 109.15,185.41 109.58,185.41 109.8,185.63 109.8,186.01 110.02,186.23 110.45,186.23 110.66,186.01 110.66,185.63 110.88,185.41 111.31,185.41 111.53,185.63 111.53,186.01 111.74,186.23 112.18,186.23 112.39,186.01 112.39,185.63 112.61,185.41 113.04,185.41 113.25,185.63 113.25,186.01 113.47,186.23 113.9,186.23 114.12,186.01 114.12,185.63 114.33,185.41 114.77,185.41 114.98,185.63 114.98,186.01 115.2,186.23 115.63,186.23 115.85,186.01 115.85,185.63 116.06,185.41 116.49,185.41 116.71,185.63 116.71,186.01 116.93,186.23 117.36,186.23 117.57,186.01 117.57,185.63 117.79,185.41 118.22,185.41 118.44,185.63 118.44,186.01 118.65,186.23 119.08,186.23 119.3,186.01 119.3,185.63 119.52,185.41 119.95,185.41 120.16,185.63 120.16,186.01 120.38,186.23 120.81,186.23 121.03,186.01 121.03,185.63 121.24,185.41 121.67,185.41 121.89,185.63 121.89,186.01 122.11,186.23 122.54,186.23 122.75,186.01 122.75,185.63 122.97,185.41 123.4,185.41 123.62,185.63 123.62,186.01 123.83,186.23 124.27,186.23 124.48,186.01 124.48,185.63 124.7,185.41 125.13,185.41 125.35,185.63 125.35,186.01 125.56,186.23 130.49,186.23 131.3,185.41 139.85,185.41 v4(140.88,186.44)
  BOTTOM w0.102: v4(147.99,186.06) 147.99,186.74 147.08,187.65 142.37,187.65 141.61,186.89 141.33,186.89 v4(140.88,186.44) 140.3,187.01 v2(138.84,187.01) 138.33,187.01 138.08,186.76 133.58,186.76 v4(132.75,185.93)
M_DATA_A3: length 91.7
  TOP w0.102: CPU1.D27 91.37,179.87 91.37,180.72 91.51,180.86 91.51,181.35 91.5,181.35 91.5,181.64 91.51,181.65 91.51,182.32 91.32,182.51 91.32,182.85 91.56,183.08 91.78,183.08 92.03,183.34
  TOP w0.165: v4(134.27,185.93) 133.78,185.44 132.48,185.44 132.17,185.75 DIMM1.17 ; DIMM2.17 147.6,185.75 147.79,185.57 149.02,185.57 v4(149.51,186.06) ; 92.03,183.34 92.87,184.17 92.87,185.27 93.2,185.6 v3(93.2,186.26)
  L4 w0.216: v4(142.4,186.44) 141.89,186.95 140.66,186.95 140.16,186.45 132.31,186.45 132.3,186.45 131.9,186.45 131.63,186.72 130.25,186.72 130.03,186.94 130.03,187.32 129.81,187.53 129.38,187.53 129.17,187.32 129.17,186.94 128.95,186.72 128.52,186.72 128.3,186.94 128.3,187.32 128.09,187.53 127.66,187.53 127.44,187.32 127.44,186.94 127.22,186.72 126.79,186.72 126.58,186.94 126.58,187.32 126.36,187.53 125.93,187.53 125.71,187.32 125.71,186.94 125.5,186.72 125.06,186.72 124.85,186.94 124.85,187.32 124.63,187.53 124.2,187.53 123.98,187.32 123.98,186.94 123.77,186.72 123.34,186.72 123.12,186.94 123.12,187.32 122.91,187.53 122.47,187.53 122.26,187.32 122.26,186.94 122.04,186.72 105.57,186.72 105.35,186.5 105.35,186.19 105.14,185.98 104.7,185.98 104.49,186.19 104.49,186.5 104.27,186.72 103.84,186.72 103.62,186.5 103.62,186.19 103.41,185.98 102.98,185.98 102.76,186.19 102.76,186.5 102.55,186.72 102.11,186.72 101.9,186.5 101.9,186.19 101.68,185.98 101.25,185.98 101.03,186.19 101.03,186.5 100.82,186.72 100.39,186.72 100.17,186.5 100.17,186.19 99.95,185.98 99.52,185.98 99.31,186.19 99.31,186.5 99.09,186.72 97.93,186.72 97.47,186.25 96.62,186.25 96.62,186.26 v3(93.2,186.26)
  BOTTOM w0.102: v4(149.51,186.06) 149.05,185.6 147.68,185.6 147.1,186.18 v2(147.1,186.64) 147.1,187.1 146.92,187.27 143.24,187.27 v4(142.4,186.44) 141.94,185.98 140.31,185.98 139.9,186.39 134.73,186.39 v4(134.27,185.93)
M_DATA_A4: length 92.3
  TOP w0.165: v4(151.54,189.36) 152.03,189.85 153.27,189.85 153.47,189.65 DIMM2.4 ; v4(136.3,189.36) 136.79,189.85 138.03,189.85 138.23,189.65 DIMM1.4 ; v3(87.71,183.16) 87.71,182.47 88.27,181.92 88.27,181.36 88.6,181.03 CPU1.B24
  L4 w0.216: v3(87.71,183.16) 87.72,183.16 87.72,186.31 90.98,189.58 96.09,189.58 97.37,190.85 140.13,190.85 140.38,191.11 143.28,191.11 144.78,189.61 v4(144.81,189.61)
  BOTTOM w0.102: v4(151.54,189.36) 151.49,189.36 150.55,188.42 150.55,188.09 150.45,187.99 150.25,187.99 150.15,188.09 150.15,188.42 150.05,188.52 149.84,188.52 149.74,188.42 149.74,188.09 149.64,187.99 149.44,187.99 149.34,188.09 149.34,188.42 149.23,188.52 149.03,188.52 148.93,188.42 148.93,188.09 148.83,187.99 148.62,187.99 148.52,188.09 148.52,188.42 148.42,188.52 146.74,188.52 v2(146.64,188.62) 145.8,188.62 v4(144.81,189.61) 144.81,188.83 144.38,188.4 137.26,188.4 v4(136.3,189.36)
M_DATA_A5: length 91
  TOP w0.165: DIMM2.6 153.37,189.05 v4(153.07,189.36) ; v3(89.31,182.58) 89.07,182.34 89.07,181.43 CPU1.B25 ; DIMM1.6 138.14,189.05 v4(137.83,189.36)
  L4 w0.216: v4(143.29,189.61) 142.28,190.62 140.59,190.62 140.33,190.36 97.57,190.36 96.29,189.08 91.19,189.08 88.21,186.1 88.21,182.84 87.96,182.59 87.96,181.58 88.14,181.41 88.68,181.41 88.86,181.58 88.86,182.13 v3(89.31,182.58)
  BOTTOM w0.102: v4(137.83,189.36) 137.83,188.98 138.03,188.78 138.4,188.78 138.5,188.88 138.5,189.34 138.61,189.44 138.81,189.44 138.91,189.34 138.91,188.88 139.01,188.78 139.21,188.78 139.32,188.88 139.32,189.34 139.42,189.44 139.62,189.44 139.72,189.34 139.72,188.88 139.82,188.78 144.23,188.78 144.33,188.88 144.33,189.05 144.23,189.15 143.75,189.15 v4(143.29,189.61) 143.75,190.07 145.23,190.07 v2(145.63,189.67) 146.12,189.18 147.4,189.18 147.68,188.9 149.7,188.9 150.32,189.52 150.32,189.55 150.59,189.81 152.61,189.81 v4(153.07,189.36)
M_DATA_A6: length 89.6
  TOP w0.102: CPU1.B27 91,181.47 90.64,181.83 90.64,183.43 v3(90.81,183.59)
  TOP w0.165: DIMM1.16 137.95,186.05 v4(137.83,185.93) ; v4(153.07,186.06) 153.07,186.05 DIMM2.16
  L4 w0.216: v4(145.07,186.03) 146.76,186.03 146.97,186.25 146.97,187.29 146.76,187.5 146.27,187.5 146.05,187.72 146.05,188.35 145.83,188.57 145.4,188.57 145.19,188.35 145.19,187.72 144.97,187.5 142.9,187.5 142.68,187.29 142.68,186.88 142.91,186.65 142.91,186.22 142.68,185.99 142.68,185.58 142.37,185.28 140.59,185.28 140.23,184.92 132.39,184.92 99.4,184.92 99.23,185.1 97.69,185.1 95.96,183.36 94.87,183.36 94.32,182.81 93.93,182.81 92.74,184 92.74,184.22 92.09,184.87 91.53,184.87 90.88,184.22 90.88,183.66 v3(90.81,183.59)
  BOTTOM w0.102: v4(137.83,185.93) 139.21,185.93 139.3,185.83 v2(139.31,185.83) 139.92,185.83 140.15,185.6 142.33,185.6 143.59,186.87 144.81,186.87 145.07,186.61 v4(145.07,186.03) 145.09,186.06 146.62,186.06 147.45,185.22 149.33,185.22 149.91,185.81 150.63,185.81 151.33,186.51 152.61,186.51 v4(153.07,186.06)
M_DATA_A7: length 92.1
  TOP w0.165: v3(91.9,184.4) 91.9,183.96 91.53,183.58 91.44,183.58 90.88,183.03 90.88,182.02 CPU1.A27 ; DIMM2.18 152.15,185.45 v4(151.54,186.06) ; v4(136.3,185.93) 136.79,185.44 138.03,185.44 138.04,185.45 DIMM1.18
  L4 w0.216: v4(143.54,186.08) 143.54,185.65 143.82,185.37 146.07,185.37 146.29,185.15 146.29,184.72 146.07,184.51 142.26,184.51 141.98,184.79 140.79,184.79 140.43,184.43 132.6,184.43 132.6,184.43 132.19,184.43 131.79,184.43 131.79,184.43 99.4,184.43 99.05,184.78 98.07,184.78 96.17,182.88 95.86,182.88 95.09,182.11 95.09,181.72 94.87,181.51 91.18,181.51 90.97,181.72 90.97,182.99 91.81,183.83 91.81,184.31 v3(91.9,184.4)
  BOTTOM w0.102: v4(136.3,185.93) 136.88,185.35 138.78,185.35 138.91,185.23 139.73,185.23 139.83,185.13 139.83,184.76 139.93,184.66 140.13,184.66 140.23,184.76 140.23,185.13 140.34,185.23 142.69,185.23 v4(143.54,186.08) 144.05,185.57 145.26,185.57 145.37,185.68 146.46,185.68 147.3,184.85 150.15,184.85 v2(150.29,184.7) 151.54,185.95 v4(151.54,186.06)
M_DATA_A8: length 81.1
  TOP w0.165: DIMM2.21 147.59,184.55 v4(147.99,184.28) ; DIMM1.21 132.07,184.55 132.72,183.9 v4(132.88,183.9) ; v3(94.52,185.29) 94.52,184.78 93.03,183.29 93.03,182.7 92.76,182.43 92.76,182.06 CPU1.A29
  L3 w0.216: v4(141,184.28) 140.41,184.28 139.3,185.39 132.56,185.39 131.78,186.17 110.73,186.17 110.52,185.95 110.52,185.2 110.3,184.99 109.87,184.99 109.65,185.2 109.65,185.95 109.44,186.17 109.01,186.17 108.79,185.95 108.79,185.2 108.57,184.99 108.14,184.99 107.93,185.2 107.93,185.95 107.71,186.17 107.28,186.17 107.06,185.95 107.06,185.2 106.85,184.99 106.42,184.99 106.2,185.2 106.2,185.95 105.98,186.17 105.55,186.17 105.34,185.95 105.34,185.2 105.12,184.99 104.69,184.99 104.47,185.2 104.47,185.95 104.26,186.17 95.34,186.17 94.52,185.35 v3(94.52,185.29)
  BOTTOM w0.102: v4(147.99,184.28) 147.33,184.28 147,184.61 146.69,184.61 146.44,184.37 146.3,184.37 146.16,184.52 146.16,184.66 146.31,184.81 146.31,185.19 146.2,185.31 145.84,185.31 145.64,185.11 143.32,185.11 143.07,184.85 140.85,184.85 140.71,184.71 140.71,184.57 v4(141,184.28) 139.78,184.28 139.2,184.85 138.75,184.85 138.63,184.98 v2(133.96,184.98) v4(132.88,183.9)
M_DATA_A9: length 81.5
  TOP w0.102: CPU1.C29 92.87,180.57 92.87,180.92 92.9,180.95 92.9,181.24 92.89,181.25 92.89,181.75 92.99,181.85 92.99,182.22 93.33,182.56 93.33,183.21 93.38,183.26
  TOP w0.165: DIMM1.23 132.07,183.95 132.62,183.41 133.91,183.41 v4(134.4,183.9) ; v4(149.51,184.28) 149.11,183.77 147.68,183.77 147.5,183.95 DIMM2.23 ; v3(96.25,185.68) 96.2,185.68 95.74,185.22 95.34,185.22 93.38,183.26
  L3 w0.216: v4(142.53,183.9) 142.26,183.76 140.23,183.76 139.1,184.9 131.74,184.9 130.97,185.68 116.33,185.68 115.21,184.56 114.77,184.56 114.56,184.77 114.56,185.46 114.34,185.68 113.91,185.68 113.69,185.46 113.69,184.77 113.48,184.56 113.05,184.56 112.83,184.77 112.83,184.91 112.48,185.27 111.72,185.27 110.8,184.35 104.2,184.35 103.33,185.22 97.21,185.22 96.91,185.52 96.4,185.52 v3(96.25,185.68)
  BOTTOM w0.102: v4(134.4,183.9) 134.96,184.45 v2(135.82,184.45) 135.97,184.6 138.47,184.6 138.6,184.48 139.05,184.48 139.7,183.82 142.45,183.82 v4(142.53,183.9) 142.64,183.9 143.48,184.73 145.41,184.73 146.32,183.82 149.16,183.82 v4(149.51,184.28)
M_DATA_A10: length 79.1
  TOP w0.165: v4(147.99,181.1) 147.76,180.95 DIMM2.33 ; v4(132.75,180.72) 132.52,180.95 DIMM1.33 ; v3(96.93,182.91) 96.5,182.47 96.5,182.18 95.31,181 CPU1.B32
  L3 w0.216: v4(140.88,180.97) 140.41,180.97 139.52,181.86 131.87,181.86 131.15,182.58 120.04,182.58 119.83,182.37 119.83,182.09 119.61,181.87 119.18,181.87 118.72,182.33 114.48,182.33 114.26,182.12 114.26,181.39 114.05,181.18 113.61,181.18 113.4,181.39 113.4,182.12 113.18,182.33 112.75,182.33 112.53,182.12 112.53,181.39 112.32,181.18 111.89,181.18 111.67,181.39 111.67,182.12 111.45,182.33 111.02,182.33 110.81,182.12 110.81,181.39 110.59,181.18 110.16,181.18 109.94,181.39 109.94,182.12 109.73,182.33 109.3,182.33 109.08,182.12 109.08,181.39 108.86,181.18 108.43,181.18 108.22,181.39 108.22,182.12 108,182.33 107.57,182.33 107.35,182.12 107.35,181.39 107.14,181.18 106.71,181.18 106.49,181.39 106.49,182.12 106.27,182.33 105.84,182.33 105.63,182.12 105.63,181.39 105.41,181.18 104.98,181.18 104.76,181.39 104.76,182.12 104.55,182.33 102.93,182.33 102.51,182.75 97.09,182.75 v3(96.93,182.91)
  BOTTOM w0.102: v4(132.75,180.72) 132.86,180.72 133.69,181.55 v2(134.27,181.55) 134.78,181.55 135.16,181.93 138.75,181.93 139.71,180.97 v4(140.88,180.97) 141.46,181.56 147.22,181.56 147.67,181.1 v4(147.99,181.1)
M_DATA_A11: length 80.8
  TOP w0.165: v4(149.51,181.1) 148.76,180.35 DIMM2.35 ; CPU1.D32 94.7,179.88 v3(94.72,179.91) ; DIMM1.35 132.43,180.35 132.55,180.23 133.78,180.23 v4(134.27,180.72)
  L3 w0.216: v3(94.72,179.91) 94.14,180.49 94.14,182.48 94.95,183.29 95.74,183.29 96.47,182.56 96.47,182.08 96.74,181.81 97.29,181.81 97.53,182.05 98.41,182.05 99.04,181.41 102.47,181.41 103.27,180.62 114.75,180.62 114.97,180.84 114.97,181.24 115.18,181.46 115.62,181.46 115.83,181.24 115.83,180.84 116.05,180.62 116.7,180.62 117.46,181.38 120.83,181.38 121.05,181.6 121.05,181.88 121.27,182.09 121.7,182.09 121.91,181.88 121.91,181.6 122.13,181.38 122.56,181.38 122.78,181.6 122.78,181.88 122.99,182.09 123.42,182.09 123.64,181.88 123.64,181.6 123.86,181.38 131.65,181.38 131.66,181.37 139.31,181.37 140.23,180.46 141.85,180.46 142.37,180.97 v4(142.4,180.97)
  BOTTOM w0.102: v4(149.51,181.1) 149.05,180.64 147.6,180.64 147.06,181.18 142.78,181.18 v4(142.4,180.97) 141.94,180.52 139.56,180.52 138.52,181.55 135.99,181.55 v2(135.54,181.1) 135.16,180.72 v4(134.27,180.72)
M_DATA_A12: length 80.5
  TOP w0.102: 92.41,183.34 92.18,183.11 92.18,182.22 92.09,182.13 92.09,181.65 92.1,181.64 92.1,181 CPU1.B28
  TOP w0.165: DIMM2.22 153.17,184.25 v4(153.07,184.15) ; 92.41,183.34 93.38,184.3 v3(93.38,184.91) ; DIMM1.22 138.17,184.25 138.03,184.38 136.79,184.38 v4(136.3,183.77)
  L3 w0.216: v4(143.29,183.9) 142.56,184.92 140.46,184.92 138.94,186.44 132.34,186.44 132.12,186.66 95.12,186.66 93.38,184.91 v3(93.38,184.91)
  BOTTOM w0.102: v4(153.07,184.15) 152.61,184.61 151.35,184.61 150.19,183.44 146.17,183.44 145.26,184.35 143.75,184.35 v4(143.29,183.9) 142.83,183.44 139.1,183.44 v2(138.78,183.76) 138.31,184.23 136.66,184.23 v4(136.3,183.77)
M_DATA_A13: length 78.8
  TOP w0.102: v3(92.59,182.88) 92.44,182.73 92.44,182.17 92.3,182.03 92.3,181.75 92.48,181.57 92.6,181.1 CPU1.B29
  TOP w0.165: DIMM2.24 152.04,183.65 v4(151.54,184.15) ; DIMM1.24 138.07,183.65 v4(137.83,183.77)
  L3 w0.216: v3(92.59,182.88) 92.59,184.82 94.92,187.15 132.33,187.15 132.54,186.93 139.14,186.93 140.66,185.41 143.55,185.41 v4(144.81,183.9)
  BOTTOM w0.102: v4(137.83,183.77) 138.6,183 140.94,183 141.23,182.71 v2(141.97,182.71) 142.8,182.71 143.04,182.96 143.05,182.96 143.1,183 143.92,183 v4(144.81,183.9) 145.64,183.07 150.46,183.07 v4(151.54,184.15)
M_DATA_A14: length 78
  TOP w0.165: v4(153.07,180.72) 153.14,180.65 DIMM2.34 ; v4(137.83,180.72) 137.9,180.65 DIMM1.34 ; CPU1.A31 94.21,181.9 v3(94.6,182.29)
  L3 w0.216: v3(94.6,182.29) 94.6,181.63 96.09,180.15 96.41,179.82 96.69,179.82 97.03,180.16 97.85,180.16 99.4,178.61 123.95,178.61 124.16,178.83 124.16,179 124.38,179.21 124.81,179.21 125.03,179 125.03,178.83 125.24,178.61 125.83,178.61 126.05,178.83 126.05,179.34 126.26,179.55 126.7,179.55 126.91,179.34 126.91,178.83 127.13,178.61 127.56,178.61 127.77,178.83 127.77,179.34 127.99,179.55 128.42,179.55 128.64,179.34 128.64,178.83 128.85,178.61 129.29,178.61 129.5,178.83 129.5,179.34 129.72,179.55 130.15,179.55 130.37,179.34 130.37,178.83 130.58,178.61 131.07,178.61 131.94,179.48 143.83,179.48 v4(144.69,180.34)
  BOTTOM w0.102: v4(153.07,180.72) 152.24,179.89 147.24,179.89 147,180.14 v2(145.85,180.14) 144.89,180.14 v4(144.69,180.34) 144.24,179.89 143.36,179.89 143.35,179.88 142.37,179.88 142.25,179.77 139.24,179.77 138.29,180.72 v4(137.83,180.72)
M_DATA_A15: length 80.8
  TOP w0.165: DIMM2.36 152.21,180.05 v4(151.54,180.72) ; v4(136.3,180.72) 136.97,180.05 DIMM1.36 ; CPU1.C31 94.2,180.74 94.84,181.38 95.08,181.38 v3(95.55,181.86)
  L3 w0.216: v3(95.55,181.86) 95.77,181.86 96.97,180.66 97.82,180.66 98.09,180.92 102.27,180.92 103.49,179.71 114.4,179.71 114.82,180.13 115.26,180.13 115.69,179.71 116.13,179.71 116.55,180.13 116.99,180.13 117.42,179.71 118.08,179.71 118.3,179.92 118.3,180.38 118.52,180.59 118.95,180.59 119.16,180.38 119.16,179.92 119.38,179.71 119.81,179.71 120.03,179.92 120.03,180.38 120.24,180.59 120.68,180.59 120.89,180.38 120.89,179.92 121.11,179.71 121.54,179.71 121.75,179.92 121.75,180.38 121.97,180.59 122.4,180.59 122.62,180.38 122.62,179.92 122.83,179.71 123.27,179.71 123.48,179.92 123.48,180.38 123.7,180.59 124.13,180.59 124.35,180.38 124.35,179.92 124.56,179.71 125.05,179.71 125.92,180.57 131.66,180.57 132.25,179.97 142.79,179.97 v4(143.16,180.34)
  BOTTOM w0.102: v4(151.54,180.72) v2(150.5,180.72) 149.95,180.72 149.49,180.27 147.44,180.27 146.91,180.81 143.63,180.81 v4(143.16,180.34) 142.3,180.34 142.1,180.14 139.4,180.14 138.36,181.18 136.76,181.18 v4(136.3,180.72)
M_DATA_A16: length 77.3
  TOP w0.165: DIMM1.39 132.41,179.15 v4(132.75,178.69) ; CPU1.E30 93.93,179.02 v3(93.93,179.15) ; DIMM2.39 147.78,179.15 v4(147.99,178.94)
  L4 w0.216: v4(140.88,178.69) 140.88,178.79 140.44,179.23 140.26,179.23 139.3,180.18 132.52,180.18 130.8,181.91 125.11,181.91 124.06,182.96 123.52,182.96 123.3,182.75 123.3,182.12 123.08,181.91 122.65,181.91 122.44,182.12 122.44,182.75 122.22,182.96 121.79,182.96 121.57,182.75 121.57,182.12 121.36,181.91 120.92,181.91 120.71,182.12 120.71,182.75 120.49,182.96 120.06,182.96 119.85,182.75 119.85,182.12 119.63,181.91 119.2,181.91 118.98,182.12 118.98,182.75 118.77,182.96 99.67,182.96 98.2,181.5 98.2,181.34 96.07,179.2 93.97,179.2 v3(93.93,179.15)
  BOTTOM w0.102: v4(147.99,178.94) 147.79,179.14 143.66,179.14 142.76,178.23 141.16,178.23 141.05,178.13 140.5,178.13 140.39,178.23 140.39,178.46 140.5,178.56 140.75,178.56 v4(140.88,178.69) 140.57,178.99 138.95,178.99 138.8,179.15 135.82,179.15 135.04,178.36 v2(135.04,178.36) 135.03,178.36 134.91,178.23 133.21,178.23 v4(132.75,178.69)
M_DATA_A17: length 81.4
  TOP w0.165: DIMM1.41 132.2,178.55 132.55,178.2 133.78,178.2 v4(134.27,178.69) ; CPU1.E31 94.3,178.66 94.71,179.07 95.9,179.07 98.83,182 v3(100.72,182) 101.05,182.33 v1(101.05,182.78) ; v4(149.51,178.94) 149.02,178.45 147.79,178.45 147.69,178.55 DIMM2.41
  L4 w0.216: v3(100.72,182) 101.2,182.47 114.39,182.47 114.61,182.26 114.61,181.63 114.82,181.42 115.25,181.42 115.47,181.63 115.47,182.26 115.69,182.47 116.12,182.47 116.33,182.26 116.33,181.63 116.55,181.42 116.98,181.42 117.2,181.63 117.2,182.26 117.41,182.47 117.84,182.47 118.06,182.26 118.06,181.63 118.28,181.42 130.59,181.42 132.32,179.69 139.1,179.69 140.61,178.17 141.89,178.17 v4(142.4,178.69)
  BOTTOM w0.102: v4(134.27,178.69) 134.27,179.27 134.53,179.52 138.96,179.52 139.09,179.39 141.7,179.39 v4(142.4,178.69) 143.22,179.51 143.51,179.51 143.52,179.52 150.06,179.52 150.2,179.37 150.2,179.12 150.05,178.97 149.54,178.97 v4(149.51,178.94)
M_DATA_A18: length 78.3
  TOP w0.165: v1(100.24,179.94) v3(100.24,179.1) 100.23,179.1 100.19,179.15 98.81,179.15 97.52,177.85 97.52,177.7 96.83,177.01 95.91,177.01 CPU1.G33 ; v4(132.75,175.51) 132.71,175.55 DIMM1.51 ; DIMM2.51 147.95,175.55 v4(147.99,175.51)
  L4 w0.216: v3(100.24,179.1) 100.25,179.1 100.73,179.59 101.52,179.59 101.52,179.59 101.93,179.59 101.93,179.59 106.28,179.59 107.37,178.5 118.62,178.5 118.83,178.28 118.83,177.67 119.05,177.45 119.48,177.45 119.7,177.67 119.7,178.28 119.91,178.5 120.34,178.5 120.56,178.28 120.56,177.67 120.78,177.45 121.21,177.45 121.42,177.67 121.42,178.28 121.64,178.5 122.07,178.5 122.29,178.28 122.29,177.67 122.5,177.45 122.93,177.45 123.15,177.67 123.15,178.28 123.37,178.5 123.8,178.5 124.01,178.28 124.01,177.67 124.23,177.45 124.66,177.45 124.88,177.67 124.88,178.28 125.09,178.5 125.53,178.5 125.74,178.28 125.74,177.67 125.96,177.45 126.39,177.45 126.61,177.67 126.61,178.28 126.82,178.5 127.25,178.5 127.47,178.28 127.47,177.67 127.68,177.45 128.12,177.45 128.33,177.67 128.33,178.28 128.55,178.5 129.04,178.5 132.53,175 140.7,175 v4(141,174.7)
  BOTTOM w0.102: v4(132.75,175.51) 133.21,175.97 134.46,175.97 135.46,174.97 140.73,174.97 v4(141,174.7) 141.07,174.7 141.58,175.21 142.77,175.21 143.03,174.95 144.94,174.95 145.5,175.51 v4(147.99,175.51)
M_DATA_A19: length 81.5
  TOP w0.102: 97.83,177.79 97.83,177.68 96.85,176.7 95.75,176.7 95.74,176.71 95.39,176.71 CPU1.G32
  TOP w0.165: 97.83,177.79 98.28,178.23 100.86,178.23 v3(101.73,179.1) 102.55,179.1 v1(102.57,179.12) ; DIMM2.53 148.95,174.95 v4(149.51,175.51) ; DIMM1.53 133.71,174.95 v4(134.27,175.51)
  L4 w0.216: v3(101.73,179.1) 101.73,179.1 106.08,179.1 107.17,178.01 112.44,178.01 112.66,177.79 112.66,177.18 112.87,176.96 113.3,176.96 113.52,177.18 113.52,177.79 113.74,178.01 114.3,178.01 114.52,177.79 114.52,177.18 114.73,176.96 115.17,176.96 115.38,177.18 115.38,177.79 115.6,178.01 116.03,178.01 116.24,177.79 116.24,177.18 116.46,176.96 116.89,176.96 117.11,177.18 117.11,177.79 117.32,178.01 117.76,178.01 117.97,177.79 117.97,177.18 118.19,176.96 129.88,176.96 132.33,174.51 138.32,174.51 138.65,174.19 141.96,174.19 v4(142.53,174.76)
  BOTTOM w0.102: v4(134.27,175.51) 135.54,174.24 142.01,174.24 v4(142.53,174.76) 142.72,174.57 145.1,174.57 145.49,174.95 150.05,174.95 150.15,175.05 150.15,175.46 150.05,175.56 149.56,175.56 v4(149.51,175.51)
M_DATA_A20: length 79.8
  TOP w0.165: v4(153.07,178.82) 153.1,178.85 DIMM2.40 ; v3(97.72,181.58) 97.72,181.47 97.03,180.78 96.37,180.78 95.9,180.31 CPU1.C33 ; v4(137.83,178.69) 137.99,178.85 DIMM1.40
  L4 w0.216: v4(143.49,178.25) 143.49,178.32 142.1,179.72 140.46,179.72 138.69,181.48 132.75,181.48 132.75,181.48 132.34,181.48 130.37,183.45 129.63,183.45 129.42,183.24 129.42,182.61 129.2,182.4 128.77,182.4 128.55,182.61 128.55,183.24 128.34,183.45 127.91,183.45 127.69,183.24 127.69,182.61 127.47,182.4 127.04,182.4 126.83,182.61 126.83,183.24 126.61,183.45 126.18,183.45 125.96,183.24 125.96,182.61 125.75,182.4 125.32,182.4 125.1,182.61 125.1,183.24 124.88,183.45 99.46,183.45 97.72,181.71 v3(97.72,181.58)
  BOTTOM w0.102: v4(153.07,178.82) 152.61,179.27 151.35,179.27 150.57,178.49 147.23,178.49 147.08,178.63 v2(146.18,178.63) 145.34,178.63 145.21,178.77 144,178.77 v4(143.49,178.25) 143.31,178.25 142.86,177.81 141.82,177.81 141.66,177.65 141.66,177.58 141.56,177.47 141.35,177.47 141.25,177.58 141.25,177.65 141.15,177.75 140.95,177.75 140.85,177.65 140.85,177.58 140.74,177.47 140.54,177.47 140.44,177.58 140.44,177.65 140.34,177.75 140.14,177.75 140.03,177.65 140.03,177.58 139.93,177.47 139.73,177.47 139.63,177.58 139.63,177.65 139.53,177.75 138.59,177.75 138.49,177.85 138.49,178.07 138.59,178.18 139.66,178.18 139.76,178.28 139.76,178.48 139.62,178.62 138.8,178.62 138.72,178.69 v4(137.83,178.69)
M_DATA_A21: length 81.2
  TOP w0.165: v4(136.3,178.69) 136.79,178.2 138.03,178.2 138.08,178.25 DIMM1.42 ; v3(96.55,180.34) 96.55,180.21 95.74,179.4 CPU1.D33 ; v4(151.54,178.82) 152.11,178.25 DIMM2.42
  L4 w0.216: v4(145.02,178.31) 143.5,179.83 142.95,179.83 142.57,180.21 140.66,180.21 138.9,181.97 132.55,181.97 130.58,183.94 99.26,183.94 97.11,181.79 96.77,181.79 96.5,181.52 96.5,181.14 96.55,181.08 v3(96.55,180.34)
  BOTTOM w0.102: v4(136.3,178.69) 137.22,177.77 137.99,177.77 138.66,177.1 141.72,177.1 141.88,177.26 142.36,177.26 v2(142.37,177.26) 142.37,177.26 142.85,177.26 143.21,177.62 143.88,177.62 144.09,177.82 144.44,177.82 144.44,177.83 144.47,177.83 144.95,178.31 v4(145.02,178.31) 145.21,178.11 150.55,178.11 150.96,177.7 152.74,177.7 152.84,177.8 152.84,178.26 152.74,178.36 152.03,178.36 151.57,178.82 v4(151.54,178.82)
M_DATA_A22: length 78.1
  TOP w0.165: v4(137.83,175.51) 138.16,175.85 DIMM1.50 ; v4(153.07,175.51) 153.53,175.85 DIMM2.50 ; CPU1.G30 93.74,177 v3(94.26,177.52)
  L4 w0.216: v4(144.91,175.82) 144.18,176.56 141.76,176.56 141.66,176.65 133.79,176.65 133.78,176.64 132.28,176.64 129.45,179.48 107.78,179.48 106.69,180.57 102.34,180.57 102.34,180.57 101.12,180.57 101.12,180.57 99.86,180.57 98.59,179.29 98.59,179.05 98.34,178.81 98.34,178.79 98.07,178.52 98.06,178.52 97.92,178.38 95.91,178.38 95.69,178.17 95.69,176.42 95.47,176.2 94.97,176.2 94.75,176.42 94.75,177.31 94.53,177.52 v3(94.26,177.52)
  BOTTOM w0.102: v4(153.07,175.51) 152.61,175.06 151.21,175.06 v2(150.72,175.55) 150.3,175.97 145.14,175.97 144.99,175.82 v4(144.91,175.82) 144.43,175.33 143.19,175.33 142.59,175.93 141.89,175.93 141.79,175.82 141.79,175.69 141.69,175.59 141.48,175.59 141.38,175.69 141.38,175.82 141.28,175.93 140.9,175.93 140.33,175.35 138,175.35 v4(137.83,175.51)
M_DATA_A23: length 80.2
  TOP w0.165: DIMM2.52 153.62,175.25 153.27,174.9 152.03,174.9 v4(151.54,175.51) ; DIMM1.52 138.25,175.25 138.03,175.03 136.79,175.03 v4(136.3,175.51) ; v3(97.08,177.88) 97.08,177.88 96.48,177.28 96.11,177.28 96.05,177.33 94.96,177.33 94.63,177 CPU1.G31
  L4 w0.216: v4(143.39,175.84) 143.39,175.83 138.74,175.83 138.42,176.16 133.99,176.16 133.98,176.15 132.08,176.15 129.24,178.99 107.58,178.99 106.48,180.08 102.13,180.08 102.13,180.08 101.32,180.08 101.32,180.08 100.07,180.08 98.66,178.67 98.66,178.13 97.61,177.09 97.61,176.47 97.4,176.25 97.02,176.25 96.81,176.47 96.81,177.61 v3(97.08,177.88)
  BOTTOM w0.102: v4(151.54,175.51) 150.71,176.35 147.65,176.35 147.31,176.69 v2(146.5,176.69) 145.43,176.69 145.13,176.39 144.01,176.39 143.93,176.31 143.87,176.31 143.4,175.84 v4(143.39,175.84) 143.32,175.84 142.86,176.3 140.75,176.3 140.17,175.72 138.36,175.72 137.45,176.63 136.56,176.63 136.3,176.38 v4(136.3,175.51)
M_DATA_A24: length 82.9
  TOP w0.102: CPU1.J30 94.14,175.1 94.43,175.1 94.63,175.31 94.63,175.36 94.97,175.7 95.26,175.7 95.27,175.69 95.75,175.69 95.77,175.71 97.02,175.71 97.37,176.06 98.55,176.06 98.59,176.09
  TOP w0.165: v4(147.99,173.35) 147.72,173.75 DIMM2.57 ; 98.59,176.09 98.92,176.09 99.1,176.28 99.68,176.28 v3(99.7,176.3) ; DIMM1.57 132.48,173.75 v4(132.75,173.48)
  L4 w0.216: v4(142.5,172.32) 142.04,171.86 141.35,171.86 140.94,171.44 132.37,171.44 130.75,173.06 130.22,173.06 130.01,172.84 130.01,171.65 129.79,171.43 129.36,171.43 129.14,171.65 129.14,172.84 128.93,173.06 128.5,173.06 128.28,172.84 128.28,171.65 128.06,171.43 127.63,171.43 127.42,171.65 127.42,172.84 127.2,173.06 106.32,173.06 102.86,176.52 99.92,176.52 v3(99.7,176.3)
  BOTTOM w0.102: v4(132.75,173.48) 134.41,171.82 134.82,171.82 v2(134.84,171.84) 135.18,171.5 138.02,171.5 138.42,171.9 140.39,171.9 140.46,171.83 141.86,171.83 142.18,172.16 142.19,172.16 142.36,172.32 v4(142.5,172.32) 144.49,172.32 147.87,172.32 147.94,172.39 150.22,172.39 150.32,172.49 150.32,172.8 150.22,172.9 148.56,172.9 148.1,173.35 v4(147.99,173.35)
M_DATA_A25: length 83.8
  TOP w0.102: v3(98.7,176.6) 98.59,176.6 98.32,176.87 97.89,176.87 96.94,175.92 95.7,175.92 95.67,175.9 95.35,175.9 95.34,175.91 94.86,175.91 94.35,175.4 CPU1.J31
  TOP w0.165: DIMM2.59 147.5,173.15 147.79,172.87 149.02,172.87 v4(149.51,173.35) ; v4(134.27,173.48) 133.78,172.99 132.55,172.99 132.39,173.15 DIMM1.59
  L4 w0.216: v4(140.98,172.39) 140.94,172.36 138.16,172.36 138.04,172.47 132.03,172.47 130.78,173.72 117.7,173.72 117.48,173.94 117.48,174.85 117.27,175.06 116.84,175.06 116.62,174.85 116.62,173.94 116.41,173.72 115.97,173.72 115.76,173.94 115.76,174.85 115.54,175.06 115.11,175.06 114.89,174.85 114.89,173.94 114.68,173.72 114.25,173.72 114.03,173.94 114.03,174.85 113.81,175.06 113.38,175.06 113.17,174.85 113.17,173.94 112.95,173.72 112.52,173.72 112.3,173.94 112.3,174.85 112.09,175.06 111.66,175.06 111.44,174.85 111.44,173.94 111.22,173.72 110.71,173.72 109.37,175.06 105.02,175.06 103.07,177.01 99.11,177.01 v3(98.7,176.6)
  BOTTOM w0.102: v4(134.27,173.48) 134.27,172.85 134.6,172.52 135.24,172.52 135.34,172.62 135.34,173.43 135.44,173.53 135.64,173.53 135.75,173.43 135.75,172.62 135.85,172.52 136.63,172.52 136.66,172.48 v2(136.69,172.48) 136.73,172.52 140.82,172.52 140.95,172.39 v4(140.98,172.39) 141.01,172.39 141.48,172.85 142.62,172.85 142.77,172.7 144.64,172.7 146.68,172.7 147.8,173.81 149.05,173.81 v4(149.51,173.35)
M_DATA_A26: length 81.8
  TOP w0.165: DIMM1.67 132.31,170.75 v4(132.75,170.31) ; DIMM2.67 147.54,170.75 v4(147.99,170.05) ; CPU1.L33 96.68,173.8 98.32,175.44 99.37,175.44 99.4,175.4 100.36,175.4 100.8,174.96 100.85,174.96 100.85,174.96 101.6,174.96 101.93,174.62 101.99,174.62 v3(102.12,174.5)
  L4 w0.216: v3(102.12,174.5) 102.27,174.5 105.56,171.21 113.18,171.21 113.4,170.99 113.4,169.18 113.61,168.97 114.05,168.97 114.26,169.18 114.26,170.99 114.48,171.21 114.91,171.21 115.13,170.99 115.13,169.18 115.34,168.97 116.1,168.97 116.31,169.18 116.31,170.17 116.53,170.39 116.96,170.39 117.18,170.17 117.18,169.18 117.39,168.97 119.75,168.97 119.97,169.18 119.97,169.37 120.19,169.58 120.62,169.58 120.83,169.37 120.83,169.18 121.05,168.97 121.48,168.97 121.7,169.18 121.7,169.37 121.91,169.58 122.35,169.58 122.56,169.37 122.56,169.18 122.78,168.97 123.21,168.97 123.43,169.18 123.43,169.37 123.64,169.58 124.07,169.58 124.29,169.37 124.29,169.18 124.5,168.97 124.94,168.97 125.15,169.18 125.15,169.37 125.37,169.58 125.8,169.58 126.02,169.37 126.02,169.18 126.23,168.97 126.66,168.97 126.88,169.18 126.88,169.37 127.1,169.58 127.53,169.58 127.74,169.37 127.74,169.18 127.96,168.97 128.39,168.97 128.61,169.18 128.61,169.37 128.82,169.58 129.25,169.58 129.47,169.37 129.47,169.18 129.69,168.97 130.12,168.97 130.33,169.18 130.33,169.37 130.55,169.58 130.98,169.58 131.2,169.37 131.2,169.18 131.41,168.97 140.81,168.97 v4(141,169.16)
  BOTTOM w0.102: v4(132.75,170.31) 133.96,169.1 140.94,169.1 v4(141,169.16) 142.21,167.95 145.64,167.95 145.76,168.08 v2(147.17,169.33) v4(147.99,170.05)
M_DATA_A27: length 83.4
  TOP w0.102: 97.06,173.8 96.75,173.5 95.75,173.5 95.44,173.8 CPU1.L32
  TOP w0.165: v3(100.69,174.5) 100.67,174.52 100.61,174.52 100.17,174.96 98.22,174.96 97.06,173.8 ; DIMM1.69 132.21,170.15 132.55,169.82 133.78,169.82 v4(134.27,170.31) ; DIMM2.69 147.2,170.15 147.79,169.56 148.95,169.56 149.24,169.85 v4(149.51,170.05)
  L4 w0.216: v3(100.69,174.5) 101.18,174.01 101.91,174.01 102.07,174.01 105.36,170.72 106.86,170.72 109.1,168.48 109.73,168.48 109.94,168.69 109.94,170.5 110.16,170.72 110.59,170.72 110.8,170.5 110.8,168.69 111.02,168.48 111.45,168.48 111.67,168.69 111.67,170.5 111.88,170.72 112.32,170.72 112.53,170.5 112.53,168.69 112.75,168.48 132.43,168.48 141.84,168.48 v4(142.53,169.16)
  BOTTOM w0.102: v4(134.27,170.31) 135.11,169.47 138.22,169.47 138.37,169.62 v2(139.81,169.62) 142.07,169.62 v4(142.53,169.16) 143.36,168.33 145.37,168.33 147.54,170.51 149.15,170.51 v4(149.51,170.05)
M_DATA_A28: length 81.5
  TOP w0.102: CPU1.H32 95,176.5 95.64,176.5 95.65,176.49 96.93,176.49 97.98,177.55 98.2,177.55
  TOP w0.165: v4(137.83,173.48) 138.4,174.05 DIMM1.56 ; v3(99.79,177.51) 99.75,177.55 98.2,177.55 ; DIMM2.56 153.64,174.05 v4(153.07,173.61)
  L4 w0.216: v4(144.99,173.53) 144.97,173.55 144.97,173.58 144.44,174.1 142.94,174.1 142.54,173.7 138.38,173.7 138.05,174.02 131.87,174.02 129.85,176.04 129.19,176.04 128.97,175.83 128.97,174.92 128.75,174.7 128.32,174.7 128.11,174.92 128.11,175.83 127.89,176.04 127.46,176.04 127.24,175.83 127.24,174.92 127.03,174.7 126.6,174.7 126.38,174.92 126.38,175.83 126.16,176.04 125.73,176.04 125.52,175.83 125.52,174.92 125.3,174.7 124.87,174.7 124.65,174.92 124.65,175.83 124.44,176.04 105.42,176.04 103.43,178.04 100.29,178.04 99.93,177.67 99.93,177.66 v3(99.79,177.51)
  BOTTOM w0.102: v4(153.07,173.61) 152.28,174.4 v2(152.12,174.4) 151.96,174.56 146.02,174.56 v4(144.99,173.53) 144.99,173.79 144.6,174.18 142.48,174.18 142.17,173.87 140.01,173.87 139.91,173.77 139.91,173.51 139.81,173.41 139.61,173.41 139.5,173.51 139.5,173.77 139.4,173.87 139.2,173.87 139.1,173.77 139.1,173.51 139,173.41 138.79,173.41 138.69,173.51 138.69,173.77 138.59,173.87 138.21,173.87 v4(137.83,173.48)
M_DATA_A29: length 82.2
  TOP w0.102: 98.72,177.28 98,177.28 96.93,176.2 CPU1.H33
  TOP w0.165: v4(136.3,173.48) 136.79,172.99 138.03,172.99 138.49,173.45 DIMM1.58 ; 98.72,177.28 99.12,176.89 100.34,176.89 100.35,176.89 100.55,176.89 v3(101.21,177.55) ; DIMM2.58 153.73,173.45 153.27,172.99 152.03,172.99 v4(151.54,173.61)
  L4 w0.216: v4(143.47,173.56) 142.88,172.97 132.23,172.97 130.98,174.21 124.02,174.21 123.8,174.43 123.8,175.34 123.59,175.55 123.16,175.55 122.94,175.34 122.94,174.43 122.72,174.21 122.29,174.21 122.08,174.43 122.08,175.34 121.86,175.55 121.43,175.55 121.21,175.34 121.21,174.43 121,174.21 120.56,174.21 120.35,174.43 120.35,175.34 120.13,175.55 119.7,175.55 119.48,175.34 119.48,174.43 119.27,174.21 118.71,174.21 118.5,174.43 118.5,175.34 118.28,175.55 105.22,175.55 103.23,177.55 v3(101.21,177.55)
  BOTTOM w0.102: v4(136.3,173.48) 136.76,173.02 140.19,173.02 140.39,173.23 140.77,173.23 140.87,173.33 140.87,173.39 140.97,173.49 141.18,173.49 141.28,173.39 141.28,173.33 141.38,173.23 141.58,173.23 141.68,173.33 141.68,173.39 141.79,173.49 141.99,173.49 142.09,173.39 142.09,173.33 142.19,173.23 143.14,173.23 v4(143.47,173.56) 143.95,173.07 144.8,173.07 145.7,173.07 v2(146.36,173.73) 146.82,174.19 150.96,174.19 v4(151.54,173.61)
M_DATA_A30: length 81
  TOP w0.165: v4(137.83,170.31) 137.97,170.45 DIMM1.68 ; DIMM2.68 153.62,170.45 153.54,170.38 153.39,170.38 v4(153.07,170.05) ; CPU1.L30 93.5,173.76 v3(93.86,173.41)
  L4 w0.216: v3(93.86,173.41) 94.41,173.96 99.1,173.96 99.11,173.95 99.11,173.94 100.02,173.03 101.66,173.03 102.01,172.68 102.01,172.37 101.3,171.66 101.3,171.36 101.6,171.05 101.91,171.05 102.62,171.76 102.93,171.76 103.61,171.07 103.61,168.27 104.39,167.5 132.03,167.5 132.43,167.5 132.84,167.5 142.31,167.5 143.47,168.65 144.3,168.65 v4(144.81,169.16)
  BOTTOM w0.102: v4(153.07,170.05) 152.31,170.89 151.97,171.26 146.91,171.26 v2(145.54,169.89) v4(144.81,169.16) 144.81,170.64 144.71,170.74 137.93,170.74 137.83,170.64 v4(137.83,170.31)
M_DATA_A31: length 83.6
  TOP w0.102: CPU1.L31 94.77,173.33 95.61,173.33 95.65,173.29 96.93,173.29 97.28,173.65
  TOP w0.165: DIMM1.70 138.06,169.85 138.03,169.82 136.79,169.82 v4(136.3,170.31) ; DIMM2.70 153.56,169.85 153.27,169.56 152.03,169.56 v4(151.54,170.05) ; v3(99.22,174.45) 98.08,174.45 97.28,173.65
  L4 w0.216: v3(99.22,174.45) 99.29,174.45 100.23,173.52 101.71,173.52 101.86,173.52 104.1,171.28 104.1,168.47 104.59,167.99 105.89,167.99 106.11,168.2 106.11,169.48 106.32,169.7 106.76,169.7 106.97,169.48 106.97,168.2 107.19,167.99 132.23,167.99 132.63,167.99 142.11,167.99 v4(143.29,169.16)
  BOTTOM w0.102: v4(136.3,170.31) 136.76,169.85 138.02,169.85 138.29,170.12 138.29,170.26 138.39,170.36 143.95,170.36 144.05,170.26 144.05,169.72 143.95,169.62 143.75,169.62 v4(143.29,169.16) 143.75,168.71 145.21,168.71 147.39,170.89 149.9,170.89 v2(150.1,170.69) 150.91,170.69 v4(151.54,170.05)
M_DATA_A32: length 82.7
  TOP w0.102: CPU1.AN31 94.54,156.06 95.23,155.8 95.54,155.8 95.64,155.69 96.19,155.69 96.3,155.81 96.78,155.81 96.81,155.77
  TOP w0.165: v3(97.13,155.31) 97.13,155.45 96.81,155.77 ; v4(132.75,149.48) 132.48,149.75 DIMM1.129 ; DIMM2.129 147.84,149.75 v4(147.99,149.61)
  L4 w0.216: v3(97.13,155.31) 97.63,155.81 102.37,155.81 103.18,155.81 104.5,154.49 116.96,154.49 117.17,154.71 117.17,155.08 117.39,155.3 117.82,155.3 118.04,155.08 118.04,154.71 118.25,154.49 118.68,154.49 118.9,154.71 118.9,155.08 119.12,155.3 119.55,155.3 119.76,155.08 119.76,154.71 119.98,154.49 120.41,154.49 120.63,154.71 120.63,155.08 120.84,155.3 121.27,155.3 121.49,155.08 121.49,154.71 121.71,154.49 122.14,154.49 122.35,154.71 122.35,155.08 122.57,155.3 123,155.3 123.22,155.08 123.22,154.71 123.43,154.49 123.87,154.49 124.08,154.71 124.08,155.08 124.3,155.3 124.73,155.3 124.95,155.08 124.95,154.71 125.16,154.49 125.59,154.49 125.81,154.71 125.81,155.08 126.02,155.3 126.46,155.3 126.67,155.08 126.67,154.71 126.89,154.49 127.38,154.49 129.13,152.74 137.37,152.74 137.45,152.66 138.62,152.66 140.53,150.75 141.41,150.75 v4(142.3,149.86)
  BOTTOM w0.102: v4(132.75,149.48) v2(134.06,150.79) 134.49,151.22 140.94,151.22 v4(142.3,149.86) 142.3,151.18 142.55,151.43 142.93,151.43 143.03,151.33 143.03,150.83 143.13,150.72 143.33,150.72 143.44,150.83 143.44,151.33 143.54,151.43 143.74,151.43 143.84,151.33 143.84,150.83 143.94,150.72 144.15,150.72 144.25,150.83 144.25,151.33 144.35,151.43 144.86,151.43 145.12,151.18 145.12,150.2 145.71,149.61 v4(147.99,149.61)
M_DATA_A33: length 83
  TOP w0.102: 98.14,154.64 97.88,154.9 96.4,154.9 96.19,155.11 95.65,155.11 95.64,155.1 95.35,155.1 95.05,155.4 CPU1.AP32
  TOP w0.165: DIMM1.131 132.39,149.15 132.55,148.99 133.78,148.99 v4(134.27,149.48) ; 98.14,154.64 98.8,154.64 v3(98.97,154.81) ; v4(149.51,149.61) 149.02,149.12 147.79,149.12 147.75,149.15 DIMM2.131
  L4 w0.216: v3(98.97,154.81) 99.47,155.32 102.57,155.32 102.98,155.32 104.29,154 110.36,154 110.57,153.78 110.57,153.33 110.79,153.12 111.22,153.12 111.44,153.33 111.44,153.78 111.65,154 112.09,154 112.3,153.78 112.3,153.33 112.52,153.12 112.95,153.12 113.17,153.33 113.17,153.78 113.38,154 113.81,154 114.03,153.78 114.03,153.33 114.24,153.12 114.68,153.12 114.89,153.33 114.89,153.78 115.11,154 115.54,154 115.76,153.78 115.76,153.33 115.97,153.12 116.4,153.12 116.62,153.33 116.62,153.78 116.84,154 117.27,154 117.48,153.78 117.48,153.33 117.7,153.12 118.13,153.12 118.35,153.33 118.35,153.78 118.56,154 118.99,154 119.21,153.78 119.21,153.33 119.43,153.12 119.86,153.12 120.07,153.33 120.07,153.78 120.29,154 127.18,154 128.92,152.25 137.17,152.25 137.25,152.17 138.41,152.17 v4(140.75,149.83)
  BOTTOM w0.102: v4(134.27,149.48) 134.25,149.5 134.25,149.89 134.32,149.96 134.62,149.96 134.72,150.06 134.72,150.58 134.82,150.68 135.03,150.68 135.13,150.58 135.13,150.06 135.23,149.96 135.43,149.96 135.53,150.06 135.53,150.58 135.64,150.68 135.84,150.68 135.94,150.58 135.94,150.06 136.04,149.96 136.25,149.96 136.97,150.68 v2(137.15,150.68) 140.26,150.68 140.75,150.19 v4(140.75,149.83) 141.21,149.38 142.46,149.38 142.97,149.88 144.85,149.88 145.58,149.15 149.05,149.15 v4(149.51,149.61)
M_DATA_A34: length 82
  TOP w0.102: 97.82,152.81 97.58,152.81 97.21,153.19 96.93,153.19 96.61,153.51 95.65,153.51 95.64,153.5 95,153.5 CPU1.AT32
  TOP w0.165: DIMM1.141 132,146.15 132.23,145.92 v4(132.75,145.92) ; v3(100.21,151.89) 99.9,152.19 99.43,152.19 99.12,152.49 99.12,152.49 98.8,152.81 97.82,152.81 ; v4(148.12,145.92) 147.89,146.15 DIMM2.141
  L4 w0.216: v4(142.4,145.67) 141.89,146.18 138.3,146.18 138.04,146.44 136.09,146.44 136.07,146.42 134.51,146.42 134.49,146.44 131.66,146.44 130.83,147.27 119.99,147.27 119.78,147.05 119.78,146.63 119.56,146.42 119.13,146.42 118.91,146.63 118.91,147.05 118.7,147.27 118.27,147.27 118.05,147.05 118.05,146.63 117.83,146.42 117.4,146.42 117.19,146.63 117.19,147.05 116.97,147.27 116.54,147.27 116.32,147.05 116.32,146.63 116.11,146.42 115.68,146.42 115.46,146.63 115.46,147.05 115.24,147.27 114.81,147.27 114.6,147.05 114.6,146.63 114.38,146.42 113.95,146.42 113.73,146.63 113.73,147.05 113.52,147.27 113.08,147.27 112.87,147.05 112.87,146.63 112.65,146.42 112.22,146.42 112.01,146.63 112.01,147.05 111.79,147.27 111.36,147.27 111.14,147.05 111.14,146.63 110.93,146.42 110.49,146.42 110.28,146.63 110.28,147.05 110.06,147.27 109.42,147.27 109.2,147.05 109.2,146.63 108.99,146.42 106.35,146.42 101.38,151.38 100.71,151.38 v3(100.21,151.89)
  BOTTOM w0.102: v4(148.12,145.92) 148.12,145.69 147.89,145.47 147.28,145.47 147.18,145.57 147.18,146.13 147.08,146.23 146.88,146.23 146.77,146.13 146.77,145.57 146.68,145.47 146.46,145.47 146.37,145.57 146.37,146.1 146.27,146.2 146.06,146.2 145.96,146.1 145.96,145.57 145.86,145.47 144.57,145.47 144.56,145.47 143.64,145.47 143.44,145.67 v4(142.4,145.67) 141.94,146.13 140.72,146.13 140.7,146.1 140.69,146.1 140.42,145.83 140.42,145.82 140.12,145.52 138.07,145.52 138.02,145.47 135.67,145.47 v2(135.15,145.98) 134.75,146.38 133.21,146.38 v4(132.75,145.92)
M_DATA_A35: length 83.7
  TOP w0.102: CPU1.AU32 95.45,153 95.75,153.3 96.31,153.3 96.65,152.96 97.15,152.96 97.56,152.55 97.95,152.55
  TOP w0.165: v4(134.27,145.92) 133.78,145.43 132.55,145.43 132.43,145.55 DIMM1.143 ; v4(149.64,145.92) 149.15,145.43 147.91,145.43 147.8,145.55 DIMM2.143 ; v1(101.25,150.04) 101.2,150.09 101.2,150.09 v4(100.42,150.87) 99.79,151.51 99.79,151.57 99.53,151.82 99.42,151.82 99.01,152.22 99.01,152.22 98.69,152.55 97.95,152.55
  L4 w0.216: v4(100.42,150.87) 100.89,150.4 100.95,150.4 101.67,150.4 106.14,145.93 120.5,145.93 120.72,146.14 120.72,146.56 120.93,146.78 121.36,146.78 121.58,146.56 121.58,146.14 121.79,145.93 122.23,145.93 122.44,146.14 122.44,146.56 122.66,146.78 123.09,146.78 123.31,146.56 123.31,146.14 123.52,145.93 123.95,145.93 124.17,146.14 124.17,146.56 124.39,146.78 124.82,146.78 125.03,146.56 125.03,146.14 125.25,145.93 125.68,145.93 125.9,146.14 125.9,146.56 126.11,146.78 126.54,146.78 126.76,146.56 126.76,146.14 126.98,145.93 127.41,145.93 127.62,146.14 127.62,146.56 127.84,146.78 128.27,146.78 128.49,146.56 128.49,146.14 128.7,145.93 129.14,145.93 129.35,146.14 129.35,146.56 129.57,146.78 130,146.78 130.21,146.56 130.21,146.14 130.43,145.93 132.02,145.93 132.53,145.41 138.04,145.41 138.32,145.69 140.83,145.69 v4(140.88,145.64)
  BOTTOM w0.102: v4(149.64,145.92) 149.52,145.92 148.7,145.09 144.71,145.09 144.71,145.09 143.47,145.09 143.41,145.15 141.37,145.15 v4(140.88,145.64) 140.77,145.64 140.28,145.15 138.23,145.15 138.17,145.09 137.86,145.09 135.85,145.09 135.34,144.58 133.46,144.58 133.36,144.68 133.36,145.36 133.46,145.47 133.81,145.47 v4(134.27,145.92)
M_DATA_A36: length 83.1
  TOP w0.102: CPU1.AN33 96.05,156.2 96.06,156.21 97.55,156.21 98.16,155.6
  TOP w0.165: DIMM2.130 153.22,149.45 v4(153.07,149.48) ; v1(101.81,153.44) 101.78,153.47 v3(101.78,154.31) 101.28,154.81 100.51,154.81 100.28,155.05 99.36,155.05 98.8,155.6 98.16,155.6 ; DIMM1.130 137.86,149.45 v4(137.83,149.48)
  L4 w0.216: v3(101.78,154.31) 102.6,154.31 104.77,152.14 108.82,152.14 109.03,151.93 109.03,151.49 109.25,151.27 109.68,151.27 109.9,151.49 109.9,151.93 110.1,152.14 110.55,152.14 110.76,151.93 110.76,151.49 110.98,151.27 111.41,151.27 111.62,151.49 111.62,151.93 111.83,152.14 112.28,152.14 112.49,151.93 112.49,151.49 112.7,151.27 113.13,151.27 113.35,151.49 113.35,151.93 113.56,152.14 114.01,152.14 114.21,151.93 114.21,151.49 114.43,151.27 114.86,151.27 115.08,151.49 115.08,151.93 115.29,152.14 115.73,152.14 115.94,151.93 115.94,151.49 116.16,151.27 116.59,151.27 116.8,151.49 116.8,151.93 117.01,152.14 117.46,152.14 117.67,151.93 117.67,151.49 117.88,151.27 118.32,151.27 118.53,151.49 118.53,151.93 118.74,152.14 127.65,152.14 128.52,151.27 128.92,151.27 136.76,151.27 139.21,148.83 143.27,148.83 v4(143.49,149.05)
  BOTTOM w0.102: v4(153.07,149.48) 151.99,148.4 144.15,148.4 v4(143.49,149.05) 143.49,149.05 143.2,149.05 142.77,148.63 139.91,148.63 139.81,148.73 139.81,149.38 139.71,149.48 139.51,149.48 139.41,149.38 139.41,148.73 139.3,148.63 139.1,148.63 139,148.73 139,149.38 138.9,149.48 138.69,149.48 138.59,149.38 138.59,148.73 138.49,148.63 138.17,148.63 138.01,148.46 137.35,148.46 137.24,148.56 137.24,148.89 v4(137.83,149.48)
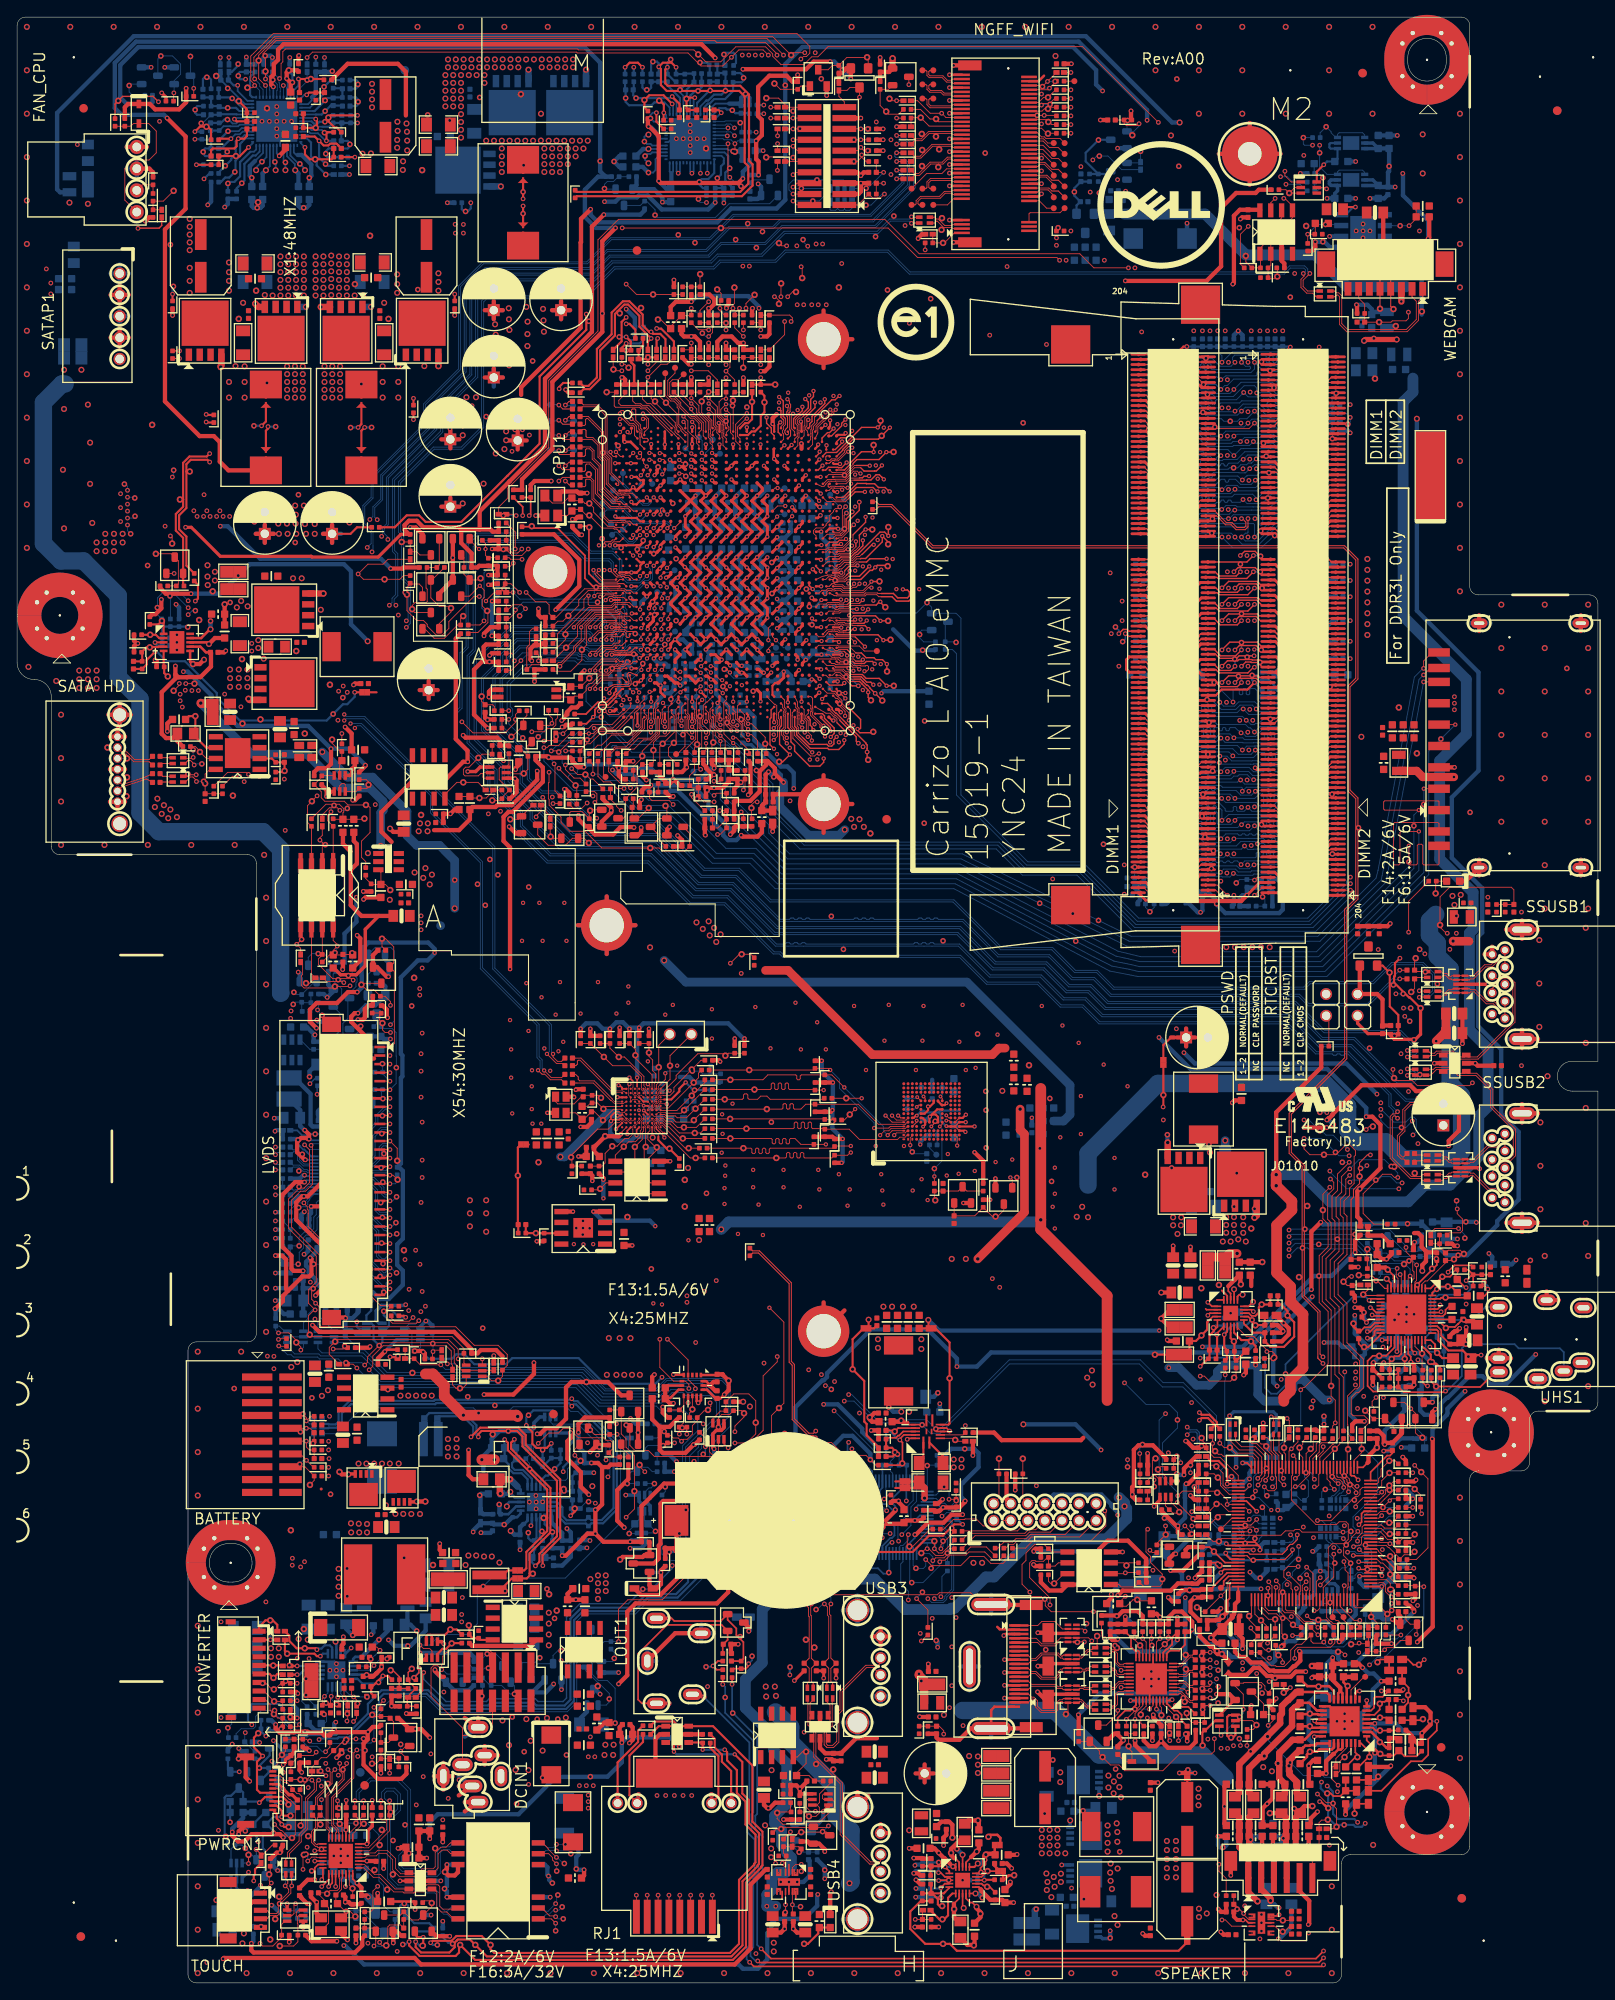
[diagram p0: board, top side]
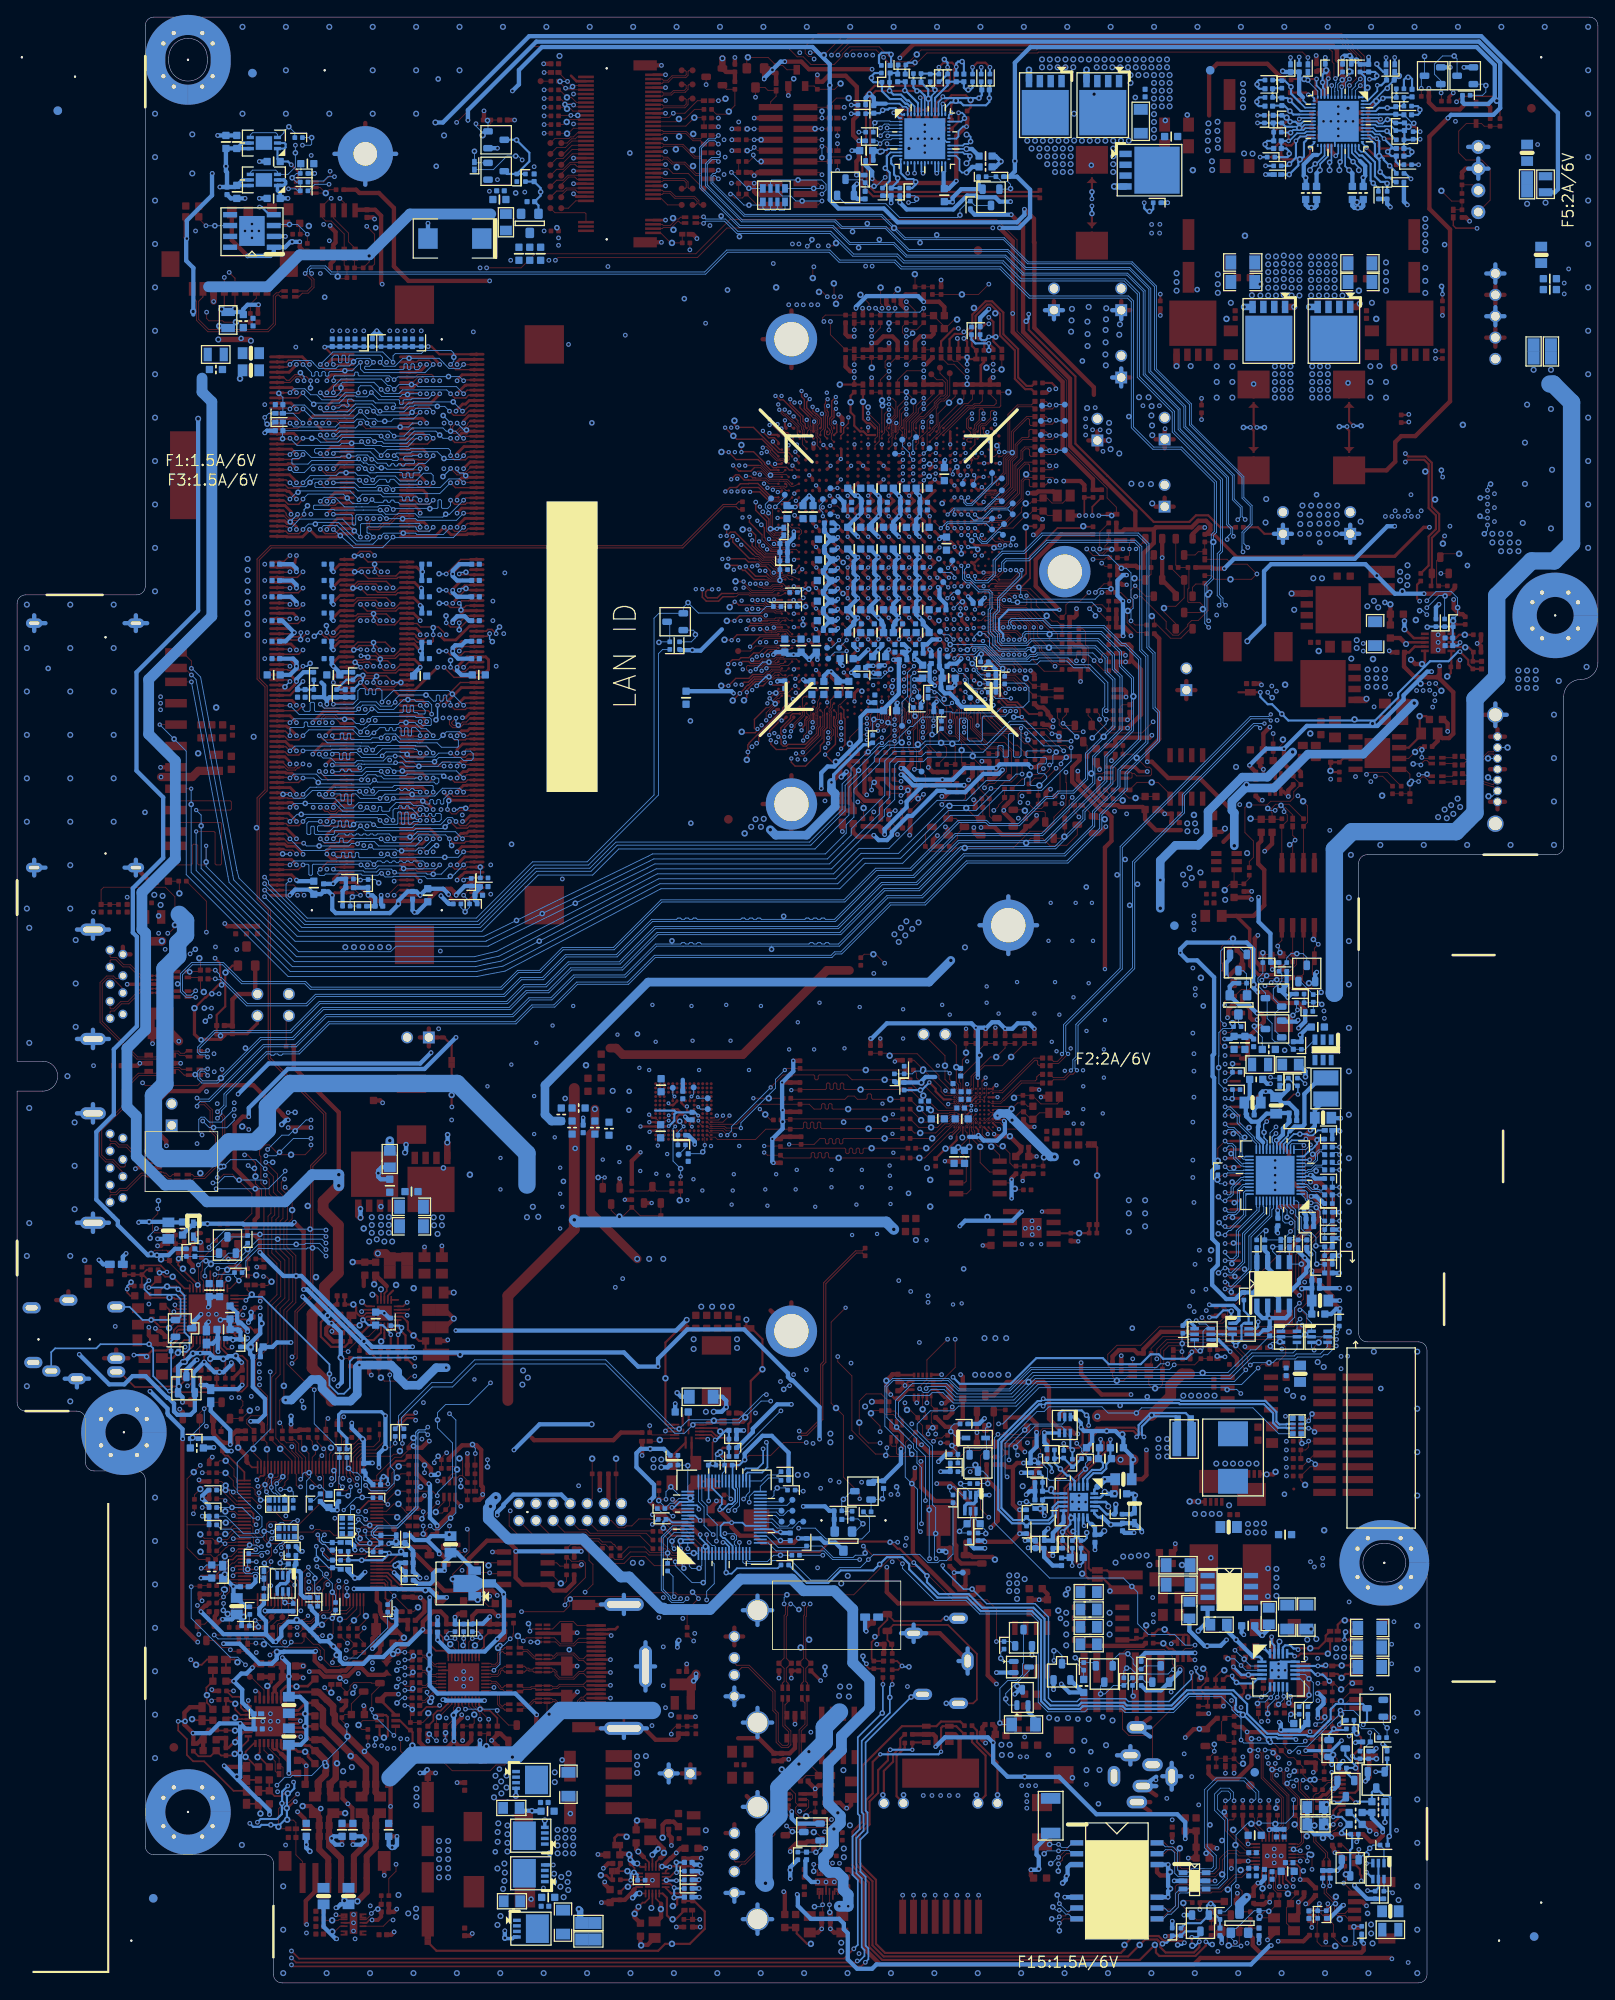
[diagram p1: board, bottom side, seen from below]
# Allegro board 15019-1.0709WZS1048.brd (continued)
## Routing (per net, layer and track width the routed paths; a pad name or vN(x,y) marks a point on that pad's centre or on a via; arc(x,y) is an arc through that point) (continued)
M_DATA_A37: length 83.6
  TOP w0.102: 97.19,155.96 97.13,156.01 96.15,156.01 96.03,155.9 95.75,155.9 95.44,156.2 CPU1.AN32
  TOP w0.165: v4(136.48,148.45) 136.88,148.85 DIMM1.132 ; v4(151.54,149.48) 152.17,148.85 DIMM2.132 ; v3(97.82,155.32) 97.19,155.96
  L4 w0.216: v4(145.02,149.05) 144.5,149.56 142.97,149.56 142.72,149.32 139.41,149.32 136.97,151.76 128.72,151.76 127.85,152.63 125.71,152.63 125.49,152.84 125.49,153.28 125.28,153.49 124.84,153.49 124.63,153.28 124.63,152.84 124.41,152.63 123.98,152.63 123.76,152.84 123.76,153.28 123.55,153.49 123.12,153.49 122.9,153.28 122.9,152.84 122.69,152.63 122.25,152.63 122.04,152.84 122.04,153.28 121.82,153.49 121.39,153.49 121.17,153.28 121.17,152.84 120.96,152.63 104.97,152.63 102.77,154.83 99.64,154.83 99.16,154.35 98.6,154.35 97.82,155.13 v3(97.82,155.32)
  BOTTOM w0.102: v4(151.54,149.48) 151.54,149 151.32,148.77 150.81,148.77 150.71,148.87 150.71,149.73 150.6,149.83 150.3,149.83 150.2,149.73 150.2,148.87 150.1,148.77 145.31,148.77 145.03,149.05 v4(145.02,149.05) 144.56,149.51 143.12,149.51 142.62,149 140.92,149 139.78,150.14 v2(139.26,150.14) 138.52,150.14 138.32,149.94 136.88,149.94 136.48,149.54 v4(136.48,148.45)
M_DATA_A38: length 82.6
  TOP w0.102: 95.81,153.96 95.77,153.96 95.59,154.14 94.76,154.14 CPU1.AR31
  TOP w0.165: DIMM1.140 136.83,146.45 v4(136.3,145.92) ; v3(97.31,153.82) 97.16,153.96 95.81,153.96 ; v4(153.07,145.92) 153.6,146.45 DIMM2.140
  L4 w0.216: v3(97.31,153.82) 97.31,153.43 98.34,152.39 101.83,152.39 105.98,148.25 121.51,148.25 121.72,148.46 121.72,149.11 121.94,149.33 122.5,149.33 122.71,149.11 122.71,148.46 122.93,148.25 123.36,148.25 123.58,148.46 123.58,149.11 123.79,149.33 130.77,149.33 132.63,147.47 135.41,147.47 135.88,147.94 136.69,147.94 136.85,148.09 138.52,148.09 139.44,147.17 143.99,147.17 v4(144.81,146.35)
  BOTTOM w0.102: v4(144.81,146.35) 144.81,146.36 ; 144.81,146.36 144.33,146.84 144.15,146.84 143.75,147.24 140.42,147.24 140.21,147.46 v2(139.49,147.46) 138.43,147.46 138.22,147.24 138.21,147.24 137.71,146.74 137.12,146.74 v4(136.3,145.92) ; 144.81,146.36 145.42,146.96 145.53,146.96 145.55,146.98 150.91,146.98 150.99,147.07 150.99,147.43 151.09,147.53 151.3,147.53 151.4,147.43 151.4,146.99 151.5,146.89 152.97,146.89 153.07,146.79 v4(153.07,145.92)
M_DATA_A39: length 83.7
  TOP w0.102: 97.82,153.08 97.65,153.08 97.34,153.39 97.02,153.39 96.7,153.71 95.59,153.71 CPU1.AT33
  TOP w0.165: DIMM2.142 153.69,145.85 153.27,145.43 152.03,145.43 v4(151.54,145.92) ; v1(102.6,151.76) v3(101.76,151.76) 100.9,152.63 99.36,152.63 98.91,153.08 97.82,153.08 ; v4(137.83,145.92) 137.9,145.85 DIMM1.142
  L4 w0.216: v3(101.76,151.76) 101.77,151.76 105.78,147.76 107.32,147.76 107.53,147.54 107.53,147.12 107.75,146.91 108.18,146.91 108.4,147.12 108.4,147.54 108.61,147.76 124.16,147.76 124.37,147.97 124.37,148.55 124.59,148.77 125.02,148.77 125.23,148.55 125.23,147.97 125.45,147.76 125.88,147.76 126.1,147.97 126.1,148.55 126.31,148.77 126.75,148.77 126.96,148.55 126.96,147.97 127.18,147.76 127.61,147.76 127.83,147.97 127.83,148.55 128.04,148.77 128.47,148.77 128.69,148.55 128.69,147.97 128.91,147.76 129.34,147.76 129.55,147.97 129.55,148.55 129.77,148.77 130.2,148.77 130.42,148.55 130.42,147.97 130.63,147.76 131.6,147.76 132.43,146.93 138.99,146.93 139.24,146.68 142.81,146.68 v4(143.24,146.25)
  BOTTOM w0.102: v4(151.54,145.92) 150.86,146.61 145.71,146.61 144.95,145.85 143.81,145.85 143.4,146.25 v4(143.24,146.25) 142.99,146.5 142.91,146.5 142.55,146.87 141.96,146.87 141.86,146.77 141.86,146.6 141.76,146.5 141.56,146.5 141.46,146.6 141.46,146.77 141.35,146.87 141.15,146.87 141.05,146.77 141.05,146.6 140.95,146.5 140.74,146.5 140.64,146.6 140.64,146.77 140.54,146.87 140.16,146.87 140.06,146.77 140.06,146.02 139.96,145.92 139.76,145.92 139.66,146.02 139.66,146.77 139.56,146.87 139.35,146.87 139.25,146.77 139.25,146 139.15,145.9 138.95,145.9 138.84,146 138.84,146.77 138.74,146.87 138.37,146.87 137.83,146.33 v4(137.83,145.92)
M_DATA_A40: length 85.6
  TOP w0.165: v4(149.64,143.76) 149.05,144.35 DIMM2.147 ; v3(93.93,152.58) 93.92,152.58 CPU1.AU30 ; DIMM1.147 132.42,144.35 132.73,144.04 v4(132.75,143.89)
  L4 w0.216: v3(93.93,152.58) 94.95,151.56 96.6,151.56 96.78,151.56 96.95,151.56 99.46,149.06 99.46,148.98 100,148.44 100.85,148.44 106.94,142.36 124.73,142.36 124.94,142.58 124.94,143.23 125.16,143.45 125.59,143.45 125.8,143.23 125.8,142.58 126.02,142.36 126.45,142.36 126.67,142.58 126.67,143.23 126.88,143.45 127.32,143.45 127.53,143.23 127.53,142.58 127.75,142.36 128.18,142.36 128.4,142.58 128.4,143.23 128.61,143.45 129.04,143.45 129.26,143.23 129.26,142.58 129.48,142.36 129.91,142.36 130.12,142.58 130.12,143.23 130.34,143.45 130.77,143.45 130.99,143.23 130.99,142.58 131.2,142.36 131.73,142.36 132.25,142.89 138.99,142.89 139.51,143.41 140.62,143.41 v4(140.75,143.54)
  BOTTOM w0.102: v4(149.64,143.76) 149.18,143.31 148.28,143.31 147.72,142.75 145.48,142.75 145.23,143 144.54,143 144.51,142.97 142.15,142.97 141.59,143.53 140.76,143.53 v4(140.75,143.54) 140.12,143.54 139.47,142.88 v2(136.15,142.88) 136.13,142.88 135.63,143.38 133.1,143.38 132.75,143.03 131.83,143.03 131.63,143.23 131.63,143.81 131.94,144.12 132.52,144.12 v4(132.75,143.89)
M_DATA_A41: length 83
  TOP w0.165: DIMM2.149 148.1,143.75 v4(148.12,143.76) ; CPU1.AV32 95.06,151.84 96.56,151.84 v3(96.8,152.08) ; v4(134.27,143.89) 134.2,143.89 133.71,143.4 132.55,143.4 132.2,143.75 DIMM1.149
  L4 w0.216: v4(142.27,143.56) 142.27,143.75 141.94,144.08 139.48,144.08 138.78,143.38 131.97,143.38 131.41,143.94 124.42,143.94 124.2,143.72 124.2,143.07 123.99,142.85 123.56,142.85 123.34,143.07 123.34,143.72 123.12,143.94 122.69,143.94 122.48,143.72 122.48,143.07 122.26,142.85 121.83,142.85 121.61,143.07 121.61,143.72 121.4,143.94 120.97,143.94 120.75,143.72 120.75,143.07 120.53,142.85 120.1,142.85 119.89,143.07 119.89,143.72 119.67,143.94 119.24,143.94 119.02,143.72 119.02,143.07 118.81,142.85 118.37,142.85 118.16,143.07 118.16,143.72 117.94,143.94 117.37,143.94 117.15,143.72 117.15,143.07 116.94,142.85 107.14,142.85 101.06,148.93 100.2,148.93 97.26,151.88 97.04,151.88 97.01,151.88 v3(96.8,152.08)
  BOTTOM w0.102: v4(148.12,143.76) 148.12,143.87 148.01,143.97 147.38,143.97 147.28,143.87 147.28,143.23 147.18,143.12 146.98,143.12 146.88,143.23 146.88,143.87 146.77,143.97 146.57,143.97 146.47,143.87 146.47,143.23 146.37,143.12 146.16,143.12 146.06,143.23 146.06,143.87 145.96,143.97 145.28,143.97 144.69,143.37 142.46,143.37 v4(142.27,143.56) 141.82,144.02 140.14,144.02 140.08,143.96 139.58,143.96 v2(139.36,143.74) 139.05,143.43 136.11,143.43 135.66,143.89 v4(134.27,143.89)
M_DATA_A42: length 82.2
  TOP w0.102: v3(96.9,148.24) 96.9,148.75 95.9,149.75 CPU1.BA33
  TOP w0.165: DIMM1.157 132.37,141.35 v4(132.75,140.97) ; v4(148.12,141.73) 148.12,141.73 147.73,141.35 DIMM2.157
  L4 w0.216: v4(140.88,141.71) 140.98,141.6 140.98,140.79 138.99,138.8 131.8,138.8 131.58,139.02 131.58,139.26 131.37,139.48 130.94,139.48 130.72,139.26 130.72,139.02 130.5,138.8 130.07,138.8 129.86,139.02 129.86,139.26 129.64,139.48 129.21,139.48 128.99,139.26 128.99,139.02 128.78,138.8 128.35,138.8 128.13,139.02 128.13,139.26 127.91,139.48 127.48,139.48 127.27,139.26 127.27,139.02 127.05,138.8 126.62,138.8 126.4,139.02 126.4,139.26 126.19,139.48 125.75,139.48 125.54,139.26 125.54,139.02 125.32,138.8 124.89,138.8 124.67,139.02 124.67,139.26 124.46,139.48 124.03,139.48 123.81,139.26 123.81,139.02 123.6,138.8 116.59,138.8 116.37,138.59 116.37,138.2 116.16,137.99 115.72,137.99 115.51,138.2 115.51,138.59 115.29,138.8 114.86,138.8 114.65,138.59 114.65,138.2 114.43,137.99 114,137.99 113.78,138.2 113.78,138.59 113.57,138.8 113.13,138.8 112.92,138.59 112.92,138.2 112.7,137.99 112.27,137.99 112.05,138.2 112.05,138.59 111.84,138.8 111.41,138.8 111.19,138.59 111.19,138.2 110.98,137.99 110.54,137.99 110.33,138.2 110.33,138.59 110.11,138.8 109.68,138.8 109.46,138.59 109.46,138.2 109.25,137.99 108.82,137.99 108.6,138.2 108.6,138.59 108.38,138.8 106.8,138.8 100.01,145.6 99.98,145.6 98.82,146.75 98.82,146.9 97.48,148.24 v3(96.9,148.24)
  BOTTOM w0.102: v4(148.12,141.73) 148.06,141.73 148.04,141.71 147.25,141.71 147.15,141.81 147.15,141.89 147.05,142 146.85,142 146.74,141.89 146.74,141.81 146.64,141.71 146.44,141.71 146.34,141.81 146.34,141.89 146.24,142 146.03,142 145.93,141.89 145.93,141.81 145.83,141.71 144.69,141.71 144.18,142.22 141.39,142.22 v4(140.88,141.71) 140.78,141.8 v2(139.91,141.8) 133.58,141.8 v4(132.75,140.97)
M_DATA_A43: length 83.2
  TOP w0.165: v3(94.21,150.22) 94.6,150.6 CPU1.AY32 ; DIMM1.159 132.28,140.75 132.55,140.48 133.78,140.48 v4(134.27,140.97) ; DIMM2.159 148.63,140.75 v4(149.64,141.76)
  L4 w0.216: v3(94.21,150.22) 95.02,150.22 96.11,149.13 96.59,149.13 96.98,148.74 97.46,148.74 99.76,146.44 99.86,146.44 107,139.29 112.11,139.29 112.33,139.51 112.33,139.75 112.54,139.97 112.98,139.97 113.19,139.75 113.19,139.51 113.41,139.29 113.84,139.29 114.06,139.51 114.06,139.75 114.27,139.97 114.7,139.97 114.92,139.75 114.92,139.51 115.13,139.29 115.57,139.29 115.78,139.51 115.78,139.75 116,139.97 116.43,139.97 116.65,139.75 116.65,139.51 116.86,139.29 117.29,139.29 117.51,139.51 117.51,139.75 117.73,139.97 118.16,139.97 118.37,139.75 118.37,139.51 118.59,139.29 119.02,139.29 119.24,139.51 119.24,139.75 119.45,139.97 119.88,139.97 120.1,139.75 120.1,139.51 120.32,139.29 120.75,139.29 120.96,139.51 120.96,139.75 121.18,139.97 121.61,139.97 121.83,139.75 121.83,139.51 122.04,139.29 122.48,139.29 122.69,139.51 122.69,139.75 122.91,139.97 138.24,139.97 140.53,142.25 141.42,142.25 141.42,142.25 141.85,142.25 142.34,141.76 v4(142.4,141.76)
  BOTTOM w0.102: v4(149.64,141.76) 149.61,141.76 149.13,141.27 144.59,141.27 144.13,141.73 142.43,141.73 v4(142.4,141.76) 142.37,141.73 142.37,141.7 141.92,141.25 139.51,141.25 139.34,141.43 135.31,141.43 v2(135.07,141.18) 134.86,140.97 v4(134.27,140.97)
M_DATA_A44: length 85.7
  TOP w0.102: 97.7,152.27 97.52,152.27 97.04,152.76 96.55,152.76 96.31,153 CPU1.AU33
  TOP w0.165: DIMM1.146 137.06,144.65 v4(136.3,143.89) ; DIMM2.146 153.57,144.65 v4(153.07,144.15) ; 97.7,152.27 98.59,152.27 98.9,151.96 98.9,151.96 99.6,151.26 v3(99.6,151) 99.6,150.39 v1(99.93,150.06)
  L4 w0.216: v3(99.6,151) 99.6,150.96 100.65,149.91 101.46,149.91 106.46,144.92 107.66,144.92 107.88,144.7 107.88,144.16 108.1,143.94 108.53,143.94 108.74,144.16 108.74,144.7 108.96,144.92 109.39,144.92 109.61,144.7 109.61,144.16 109.82,143.94 110.26,143.94 110.47,144.16 110.47,144.7 110.69,144.92 111.12,144.92 111.34,144.7 111.34,144.16 111.55,143.94 111.98,143.94 112.2,144.16 112.2,144.7 112.41,144.92 112.85,144.92 113.06,144.7 113.06,144.16 113.28,143.94 113.71,143.94 113.93,144.16 113.93,144.7 114.14,144.92 114.57,144.92 114.79,144.7 114.79,144.16 115.01,143.94 115.44,143.94 115.65,144.16 115.65,144.7 115.87,144.92 138.24,144.92 138.38,145.06 142.73,145.06 143.21,145.54 144.38,145.54 144.58,145.34 144.58,144.95 144.4,144.76 143.9,144.76 v4(143.39,144.25)
  BOTTOM w0.102: v4(153.07,144.15) 152.51,144.7 148.34,144.7 148.33,144.72 144.86,144.72 144.85,144.7 143.91,144.7 143.45,144.25 v4(143.39,144.25) 143.33,144.25 142.81,144.77 138.39,144.77 138.33,144.71 137.13,144.71 v4(136.3,143.89)
M_DATA_A45: length 84
  TOP w0.102: CPU1.AU31 94.65,153 94.95,152.7 96.3,152.7 96.45,152.55 96.91,152.55 97.44,152.02
  TOP w0.165: v4(151.54,144.15) 152.03,143.66 153.27,143.66 153.66,144.05 DIMM2.148 ; DIMM1.148 137.99,144.05 v4(137.83,143.89) ; 97.44,152.02 97.71,151.75 v4(98.45,151.75)
  L4 w0.216: v4(144.91,144.25) 144.99,144.17 147.26,144.17 147.48,143.95 147.48,142.99 147.26,142.77 144.14,142.77 142.34,144.57 138.58,144.57 138.45,144.43 117.05,144.43 115.96,143.34 107.34,143.34 101.26,149.42 100.45,149.42 99.25,150.62 98.96,150.62 98.46,151.13 98.46,151.74 v4(98.45,151.75)
  BOTTOM w0.102: v4(151.54,144.15) 151.47,144.22 148.29,144.22 148.17,144.34 145.02,144.34 144.92,144.25 v4(144.91,144.25) 144.42,143.75 142.92,143.75 142.27,144.39 138.54,144.39 138.48,144.34 138.27,144.34 v4(137.83,143.89)
  BOTTOM w0.165: v4(98.45,151.75) 97.4,152.81 v2(97.01,152.81)
M_DATA_A46: length 84.7
  TOP w0.102: CPU1.AW31 94.8,150.9 95.63,150.9 96.06,150.47 96.12,150.47 96.52,150.07 96.52,149.71 97.03,149.2 97.34,149.2
  TOP w0.165: DIMM2.158 153.15,141.05 v4(153.07,140.97) ; v1(100.2,146.38) 100.15,146.38 100.05,146.27 98.62,146.27 98.36,146.54 v3(98.36,146.71) 98.61,146.71 98.71,146.81 98.71,147.83 97.34,149.2 ; DIMM1.158 137.91,141.05 v4(137.83,140.97)
  L4 w0.216: v3(98.36,146.71) 98.36,146.52 99.77,145.11 99.8,145.11 107.42,137.5 117.21,137.5 117.43,137.71 117.43,138.1 117.65,138.31 118.08,138.31 118.29,138.1 118.29,137.71 118.51,137.5 118.94,137.5 119.16,137.71 119.16,138.1 119.37,138.31 119.8,138.31 120.02,138.1 120.02,137.71 120.24,137.5 120.67,137.5 120.88,137.71 120.88,138.1 121.1,138.31 121.53,138.31 121.75,138.1 121.75,137.71 121.96,137.5 122.39,137.5 122.61,137.71 122.61,138.1 122.83,138.31 139.2,138.31 141.9,141.01 142.72,141.01 142.97,141.26 144.15,141.26 144.64,140.77 v4(144.71,140.77)
  BOTTOM w0.102: v4(153.07,140.97) 152.61,141.43 149.98,141.43 149.32,140.77 v4(144.71,140.77) 144.56,140.77 144.13,141.2 143.98,141.36 143.01,141.36 142.86,141.2 142.4,141.2 142.07,140.87 138.48,140.87 138.39,140.97 v4(137.83,140.97)
M_DATA_A47: length 84.9
  TOP w0.102: v3(97.34,147.73) 97.34,148.6 96.31,149.63 96.31,149.98 96.03,150.27 95.83,150.27 CPU1.AY33
  TOP w0.165: v4(151.54,140.97) 152.06,140.45 DIMM2.160 ; DIMM1.160 136.82,140.45 v4(136.3,140.97)
  L4 w0.216: v4(143.18,140.74) 142.93,140.49 142.14,140.49 139.47,137.82 132.8,137.82 131.99,137.01 131.34,137.01 131.12,137.22 131.12,137.61 130.9,137.82 130.47,137.82 130.26,137.61 130.26,137.22 130.04,137.01 129.61,137.01 129.39,137.22 129.39,137.61 129.18,137.82 128.75,137.82 128.53,137.61 128.53,137.22 128.31,137.01 127.88,137.01 127.67,137.22 127.67,137.61 127.45,137.82 127.02,137.82 126.8,137.61 126.8,137.22 126.59,137.01 126.15,137.01 125.94,137.22 125.94,137.61 125.72,137.82 125.29,137.82 125.07,137.61 125.07,137.22 124.86,137.01 107.21,137.01 99.49,144.73 99.49,144.88 97.41,146.95 97.41,147.65 v3(97.34,147.73)
  BOTTOM w0.102: v4(136.3,140.97) 135.75,140.97 135.64,140.87 135.64,140.49 135.85,140.28 136,140.28 136.21,140.5 142.82,140.5 143.07,140.74 v4(143.18,140.74) 143.66,140.27 145.82,140.27 145.84,140.29 149.6,140.29 v2(149.76,140.45) 150.28,140.97 v4(151.54,140.97)
M_DATA_A48: length 92.2
  TOP w0.165: v4(148.12,139.06) 147.63,139.55 DIMM2.163 ; v4(132.75,139.32) 132.52,139.55 DIMM1.163 ; CPU1.BC31 94.1,147.97 95.19,146.88 v3(95.19,146.47)
  L3 w0.216: v4(142.53,138.59) 142.52,138.59 141.89,139.22 139.7,139.22 138.96,139.97 132.07,139.97 129.36,142.67 124.03,142.67 123.82,142.46 123.82,141.55 123.6,141.33 123.17,141.33 122.95,141.55 122.95,142.46 122.74,142.67 122.31,142.67 122.09,142.46 122.09,141.55 121.87,141.33 121.44,141.33 121.23,141.55 121.23,142.46 121.01,142.67 120.58,142.67 120.36,142.46 120.36,141.55 120.15,141.33 119.71,141.33 119.5,141.55 119.5,142.46 119.28,142.67 118.85,142.67 118.64,142.46 118.64,141.55 118.42,141.33 117.99,141.33 117.77,141.55 117.77,142.46 117.56,142.67 117.12,142.67 116.91,142.46 116.91,141.55 116.69,141.33 116.26,141.33 116.04,141.55 116.04,142.46 115.83,142.67 115.4,142.67 115.18,142.46 115.18,141.55 114.96,141.33 114.53,141.33 114.32,141.55 114.32,142.46 114.1,142.67 113.56,142.67 113.34,142.46 113.34,141.55 113.13,141.33 100.74,141.33 97.84,144.23 97.84,145.8 96.96,146.69 95.41,146.69 95.2,146.47 v3(95.19,146.47)
  BOTTOM w0.102: v4(148.12,139.06) 148.06,139.12 147.2,139.12 147.1,139.01 147.1,138.4 147,138.3 146.8,138.3 146.69,138.4 146.69,139.01 146.59,139.12 146.39,139.12 146.29,139.01 146.29,137.95 146.19,137.85 145.98,137.85 145.88,137.95 145.88,139.01 145.78,139.12 145.37,139.12 144.84,138.59 v4(142.53,138.59) 142.45,138.59 141.95,139.09 138.82,139.09 v2(138.78,139.04) 138.59,138.86 136.11,138.86 135.85,139.13 135.85,139.15 135.22,139.78 133.21,139.78 v4(132.75,139.32)
M_DATA_A49: length 95.3
  TOP w0.102: CPU1.BB30 94.02,148.94 94.67,148.55 95.14,148.55 95.59,148.11 95.7,148.11 95.94,147.87 95.94,147.45
  TOP w0.165: DIMM2.165 147.47,138.95 147.84,138.58 149.15,138.58 v4(149.64,139.06) ; DIMM1.165 132.17,138.95 132.29,138.83 133.95,138.83 v4(134.27,139.32) ; 95.94,147.45 96.93,146.45 96.93,146.05 v3(96.98,146.01)
  L3 w0.216: v4(140.96,138.59) 138.91,138.59 138.69,138.8 132.53,138.8 130.5,140.84 129.23,140.84 129.01,141.06 129.01,141.9 128.79,142.11 128.36,142.11 128.15,141.9 128.15,141.06 127.93,140.84 127.5,140.84 127.28,141.06 127.28,141.9 127.07,142.11 126.64,142.11 126.42,141.9 126.42,141.06 126.2,140.84 125.77,140.84 125.56,141.06 125.56,141.9 125.34,142.11 124.91,142.11 124.69,141.9 124.69,141.06 124.48,140.84 107.13,140.84 106.92,140.63 106.92,139.2 106.7,138.99 106.27,138.99 106.05,139.2 106.05,140.63 105.84,140.84 105.41,140.84 105.19,140.63 105.19,139.2 104.97,138.99 104.54,138.99 104.33,139.2 104.33,140.63 104.11,140.84 103.68,140.84 103.46,140.63 103.46,139.2 103.25,138.99 102.81,138.99 102.6,139.2 102.6,140.63 102.38,140.84 100.53,140.84 97.35,144.03 97.35,145.64 v3(96.98,146.01)
  BOTTOM w0.102: v4(134.27,139.32) 135.06,138.53 135.06,138.02 135.17,137.92 135.37,137.92 135.47,138.02 135.47,138.35 135.57,138.46 135.78,138.46 135.88,138.35 135.88,138.02 135.98,137.92 136.18,137.92 136.28,138.02 136.28,138.35 136.39,138.46 136.59,138.46 136.69,138.35 136.69,138.02 136.79,137.92 137.17,137.92 v2(137.52,138.28) 137.73,138.49 140.86,138.49 v4(140.96,138.59) 141.45,138.11 145.02,138.11 145.67,137.46 146.71,137.46 147.34,138.08 147.34,138.11 147.84,138.61 149.07,138.61 149.52,139.06 v4(149.64,139.06)
M_DATA_A50: length 95
  TOP w0.102: CPU1.BB28 92.1,149 92.1,148.36 92.09,148.35 92.09,147.88 92.36,147.62 92.36,146.49 v3(92.17,146.3)
  TOP w0.165: v4(147.99,135.89) 147.93,135.95 DIMM2.175 ; DIMM1.175 131.89,135.95 132.44,135.4 133.15,135.4 v4(133.64,135.89)
  L3 w0.216: v4(143.29,135.51) 142.64,134.86 140.31,134.86 139.84,134.4 132.19,134.4 130.88,135.71 127.96,135.71 127.74,135.49 127.74,135.09 127.53,134.87 127.09,134.87 126.88,135.09 126.88,135.49 126.66,135.71 126.17,135.71 125.96,135.49 125.96,134.61 125.74,134.4 125.31,134.4 125.09,134.61 125.09,135.49 124.88,135.71 124.44,135.71 124.23,135.49 124.23,134.61 124.01,134.4 123.58,134.4 123.37,134.61 123.37,135.49 123.15,135.71 101.42,135.71 94.99,142.13 92.39,142.13 91.79,142.73 91.79,145.92 v3(92.17,146.3)
  BOTTOM w0.102: v4(133.64,135.89) 134.09,136.35 134.63,136.35 134.99,135.99 134.99,135.96 135.44,135.51 138.41,135.51 138.74,135.18 142.84,135.18 143.09,135.43 143.15,135.5 v4(143.29,135.51) 143.62,135.84 145.32,135.84 v2(145.62,135.53) 145.93,135.22 146.11,135.22 146.21,135.33 146.21,135.85 146.31,135.96 146.51,135.96 146.62,135.85 146.62,135.33 146.72,135.22 146.92,135.22 147.02,135.33 147.02,135.85 147.12,135.96 147.33,135.96 147.43,135.85 147.43,135.33 147.53,135.22 147.93,135.22 148.41,134.75 149.74,134.75 149.84,134.85 149.84,135.28 149.74,135.38 148.5,135.38 v4(147.99,135.89)
M_DATA_A51: length 96.3
  TOP w0.102: CPU1.AY27 91.33,149.87 91.33,149.33 91.51,149.14 91.51,148.65 91.5,148.64 91.5,148.32 91.51,148.31 91.51,147.89 91.5,147.88 91.5,147.25 v3(91.88,146.87)
  TOP w0.165: v4(149.51,135.89) 148.97,135.35 DIMM2.177 ; DIMM1.177 132.07,135.35 132.31,135.11 133.55,135.11 134.33,135.89 v4(134.4,135.89)
  L3 w0.216: v4(144.81,135.38) 143.8,134.37 140.66,134.37 139.63,133.34 132.49,133.34 131.93,133.9 122.85,133.9 121.54,135.22 101.21,135.22 94.79,141.64 92.18,141.64 91.3,142.52 91.3,146.29 v3(91.88,146.87)
  BOTTOM w0.102: v4(149.51,135.89) 149.54,135.86 150.88,135.86 151.09,135.66 151.09,134.47 150.99,134.37 150.73,134.37 150.63,134.47 150.63,135.23 150.53,135.33 150.3,135.33 150.22,135.25 150.22,134.49 150.1,134.37 147.98,134.37 147.87,134.47 147.87,134.75 147.77,134.85 145.35,134.85 v4(144.81,135.38) 144.24,134.81 138.59,134.81 138.33,135.07 135.09,135.07 v2(134.91,135.25) 134.89,135.25 134.4,135.75 v4(134.4,135.89)
M_DATA_A52: length 92.9
  TOP w0.102: 96.3,147.7 96.3,147.8 95.79,148.31 95.69,148.31 CPU1.BB32
  TOP w0.165: v4(137.83,139.32) 137.9,139.25 DIMM1.164 ; v4(98.45,145.04) 98.45,145.04 98.2,145.29 98.2,145.8 96.3,147.7 ; v4(153.07,139.06) 153.25,139.25 DIMM2.164
  L3 w0.216: v4(144.91,139.42) 144.4,138.91 143.18,138.91 142.37,139.71 139.91,139.71 139.16,140.46 132.53,140.46 129.51,143.48 112.09,143.48 111.88,143.26 111.88,142.04 111.66,141.82 111.23,141.82 111.01,142.04 111.01,143.26 110.8,143.48 110.37,143.48 110.15,143.26 110.15,142.04 109.94,141.82 109.5,141.82 109.29,142.04 109.29,143.26 109.07,143.48 108.64,143.48 108.42,143.26 108.42,142.04 108.21,141.82 107.78,141.82 107.56,142.04 107.56,143.26 107.34,143.48 106.91,143.48 106.7,143.26 106.7,142.04 106.48,141.82 106.05,141.82 105.83,142.04 105.83,143.26 105.62,143.48 105.19,143.48 104.97,143.26 104.97,142.04 104.75,141.82 104.32,141.82 104.11,142.04 104.11,143.26 103.89,143.48 103.46,143.48 103.24,143.26 103.24,142.04 103.03,141.82 102.59,141.82 102.38,142.04 102.38,143.26 102.16,143.48 99.29,143.48 98.45,144.31 v4(98.45,145.04)
  BOTTOM w0.102: v2(153.88,139.06) v4(153.07,139.06) 152.61,138.61 151.35,138.61 150.45,139.52 149.83,139.52 149.83,139.52 149.45,139.52 149.44,139.52 149.07,139.52 149.07,139.52 148.69,139.52 148.68,139.52 148.31,139.52 148.3,139.52 147.93,139.52 147.92,139.52 145.01,139.52 v4(144.91,139.42) 144.46,138.96 143.2,138.96 142.65,139.52 140.69,139.52 140.59,139.62 140.59,139.63 140.49,139.73 140.29,139.73 140.19,139.63 140.19,139.62 140.09,139.52 139.88,139.52 139.78,139.62 139.78,139.63 139.68,139.73 139.48,139.73 139.37,139.63 139.37,139.62 139.27,139.52 139.07,139.52 138.97,139.62 138.97,139.63 138.87,139.73 138.66,139.73 138.56,139.63 138.56,139.62 138.46,139.52 138.03,139.52 v4(137.83,139.32)
M_DATA_A53: length 93.8
  TOP w0.165: v4(136.3,139.32) 136.97,138.65 DIMM1.166 ; DIMM2.166 153.34,138.65 153.27,138.58 152.03,138.58 v4(151.54,139.06) ; CPU1.BA31 94.84,149.7 95.38,149.16 95.38,148.97 95.81,148.55 95.88,148.55 96.99,147.44 96.99,147.41 99.35,145.05 99.35,144.97 99.49,144.83 99.49,144.43 99.47,144.41 v4(99.47,144.02) 99.47,143.23 v1(99.6,143.1)
  L3 w0.216: v4(143.39,139.42) 143.39,139.6 142.79,140.2 140.11,140.2 138.68,141.63 136,141.63 135.65,141.28 134.69,141.28 134.34,141.63 132.6,141.63 130.21,144.02 129.72,144.02 129.5,144.23 129.5,145.28 129.29,145.49 128.85,145.49 128.64,145.28 128.64,144.23 128.42,144.02 127.99,144.02 127.77,144.23 127.77,145.28 127.56,145.49 127.13,145.49 126.91,145.28 126.91,144.23 126.7,144.02 126.26,144.02 126.05,144.23 126.05,145.28 125.83,145.49 125.4,145.49 125.18,145.28 125.18,144.23 124.97,144.02 124.54,144.02 124.32,144.23 124.32,145.28 124.1,145.49 123.67,145.49 123.46,145.28 123.46,144.23 123.24,144.02 122.81,144.02 122.59,144.23 122.59,145.28 122.38,145.49 121.95,145.49 121.73,145.28 121.73,144.23 121.51,144.02 121.08,144.02 120.87,144.23 120.87,145.28 120.65,145.49 120.22,145.49 120,145.28 120,144.23 119.79,144.02 v4(99.47,144.02)
  BOTTOM w0.102: v4(136.3,139.32) 136.3,140 136.41,140.11 140.85,140.11 141.06,139.89 143.29,139.89 143.39,139.79 v4(143.39,139.42) 143.86,139.89 147.76,139.89 147.77,139.9 149.98,139.9 149.99,139.89 150.72,139.89 v4(151.54,139.06)
M_DATA_A54: length 95.6
  TOP w0.165: CPU1.BC29 92.62,148.08 92.62,148.01 92.81,147.81 92.81,147.79 92.81,147.79 92.81,147.15 93.05,146.92 93.05,146.71 v3(93.2,146.56) ; v4(136.3,136.02) 136.79,136.51 138.03,136.51 138.29,136.25 DIMM1.174 ; DIMM2.174 153.43,136.25 v4(153.07,135.89)
  L3 w0.216: v3(93.2,146.56) 93.2,145.82 93.53,145.49 93.53,144.98 101.82,136.69 118.08,136.69 118.3,136.9 118.3,138.26 118.51,138.48 118.94,138.48 119.16,138.26 119.16,136.9 119.37,136.69 119.81,136.69 120.02,136.9 120.02,138.26 120.24,138.48 120.67,138.48 120.89,138.26 120.89,136.9 121.1,136.69 121.53,136.69 121.75,136.9 121.75,138.26 121.97,138.48 122.4,138.48 122.61,138.26 122.61,136.9 122.83,136.69 123.26,136.69 123.48,136.9 123.48,138.26 123.69,138.48 129.49,138.48 132.59,135.38 139.43,135.38 140.07,136.02 v4(141,136.02)
  BOTTOM w0.102: v4(136.3,136.02) 136.18,135.89 135.59,135.89 135.36,136.12 135.36,136.7 135.49,136.83 135.95,136.83 136.06,136.73 136.06,136.58 136.16,136.47 136.36,136.47 136.46,136.58 136.46,136.73 136.56,136.83 136.77,136.83 136.87,136.73 136.87,136.58 136.97,136.47 137.17,136.47 137.27,136.58 137.27,136.73 137.38,136.83 137.58,136.83 137.68,136.73 137.68,136.58 137.78,136.47 137.99,136.47 138.09,136.58 138.09,136.68 138.79,137.39 139.03,137.39 139.13,137.49 139.13,137.62 139.23,137.72 139.43,137.72 139.53,137.62 139.53,137.49 139.64,137.39 139.84,137.39 139.94,137.49 139.94,137.62 140.04,137.72 140.25,137.72 140.35,137.62 140.35,137.49 140.45,137.39 140.83,137.39 141,137.21 v4(141,136.02) 141.82,136.71 147.04,136.71 147.06,136.72 v2(151.75,136.72) 152.23,136.72 v4(153.07,135.89)
M_DATA_A55: length 95.6
  TOP w0.102: v3(93.01,145.36) 92.95,145.42 92.95,145.95 92.58,146.32 92.58,147.69 92.3,147.97 92.3,148.25 92.6,148.55 CPU1.BB29
  TOP w0.165: DIMM2.176 153.52,135.65 153.27,135.4 152.03,135.4 v4(151.54,135.89) ; v4(137.83,136.02) 138.2,135.65 DIMM1.176
  L3 w0.216: v4(142.53,136.02) 141.86,135.35 140.1,135.35 139.64,134.89 132.39,134.89 131.08,136.2 129.31,136.2 129.09,136.41 129.09,137.75 128.88,137.96 128.45,137.96 128.23,137.75 128.23,136.41 128.02,136.2 127.58,136.2 127.37,136.41 127.37,137.75 127.15,137.96 126.72,137.96 126.5,137.75 126.5,136.41 126.29,136.2 125.86,136.2 125.64,136.41 125.64,137.75 125.42,137.96 124.99,137.96 124.78,137.75 124.78,136.41 124.56,136.2 121.94,136.2 101.62,136.2 95.19,142.62 92.59,142.62 92.28,142.93 92.28,144.63 v3(93.01,145.36)
  BOTTOM w0.102: v2(138.67,136.51) 138.26,136.1 137.91,136.1 v4(137.83,136.02) 137.96,135.89 138.59,135.89 138.92,135.56 139.12,135.56 139.23,135.66 139.23,136.88 139.33,136.98 139.53,136.98 139.63,136.88 139.63,135.66 139.73,135.56 139.94,135.56 140.04,135.66 140.04,136.91 140.14,137.01 140.34,137.01 140.44,136.91 140.44,135.66 140.55,135.56 142.07,135.56 v4(142.53,136.02) 142.84,136.33 147.2,136.33 147.21,136.35 151.09,136.35 v4(151.54,135.89)
M_DATA_A56: length 91.3
  TOP w0.102: v3(93.05,143.98) 93.04,143.99 92.94,143.99 91,145.94 91,146.69 90.7,146.99 90.7,148.25 90.71,148.26 90.71,148.61 CPU1.BB27
  TOP w0.165: v4(132.88,133.86) 132.58,134.15 DIMM1.181 ; v4(147.99,133.86) 147.7,134.15 DIMM2.181
  L4 w0.216: v3(93.05,143.98) 93.39,144.32 96.83,144.32 106.06,135.09 107.81,135.09 108.02,134.88 108.02,133.57 108.24,133.35 108.67,133.35 108.89,133.57 108.89,134.88 109.1,135.09 109.53,135.09 109.75,134.88 109.75,133.57 109.97,133.35 110.4,133.35 110.61,133.57 110.61,134.88 110.83,135.09 111.26,135.09 111.48,134.88 111.48,133.57 111.69,133.35 112.12,133.35 112.34,133.57 112.34,134.88 112.56,135.09 112.99,135.09 113.2,134.88 113.2,133.57 113.42,133.35 113.85,133.35 114.07,133.57 114.07,134.88 114.28,135.09 115.23,135.09 115.93,134.4 138.55,134.4 138.77,134.18 138.77,134.05 138.98,133.83 139.42,133.83 139.63,134.05 139.63,134.18 139.85,134.4 140.34,134.4 v4(140.88,133.86)
  BOTTOM w0.102: v4(147.99,133.86) 147.86,133.99 147.82,133.99 147.38,134.43 146.65,134.43 146.5,134.29 146.24,134.29 146.1,134.43 145.84,134.43 145.69,134.29 145.43,134.29 145.28,134.43 145.02,134.43 144.88,134.29 144.62,134.29 144.47,134.43 144.21,134.43 144.06,134.29 143.8,134.29 143.66,134.43 143.4,134.43 143.25,134.29 142.99,134.29 142.85,134.43 141.45,134.43 v4(140.88,133.86) 140.65,134.08 139.02,134.08 v2(139.01,134.08) 139.01,134.08 138.78,134.08 138.17,134.69 133.71,134.69 v4(132.88,133.86)
M_DATA_A57: length 93.8
  TOP w0.102: v3(93.84,143.83) 93.77,143.76 93.55,143.76 93.33,143.55 92.87,143.55 92.86,143.56 92.84,143.56 90.79,145.61 90.79,146.6 90.49,146.9 90.49,148.35 90.5,148.36 90.5,149 CPU1.BB26
  TOP w0.165: DIMM2.183 147.6,133.55 147.79,133.37 149.02,133.37 v4(149.51,133.86) ; v4(134.4,133.86) 133.91,133.37 132.67,133.37 132.49,133.55 DIMM1.183
  L4 w0.216: v4(142.4,133.86) 141.89,133.34 132.04,133.34 131.48,133.9 122.56,133.9 122.37,133.72 122.37,133.06 122.16,132.84 121.73,132.84 121.51,133.06 121.51,133.72 121.32,133.9 120.83,133.9 120.65,133.72 120.65,133.06 120.43,132.84 120,132.84 119.78,133.06 119.78,133.72 119.6,133.9 119.11,133.9 118.92,133.72 118.92,133.06 118.7,132.84 118.27,132.84 118.06,133.06 118.06,133.72 117.87,133.9 117.38,133.9 117.19,133.72 117.19,133.06 116.98,132.84 116.54,132.84 116.33,133.06 116.33,133.72 116.14,133.9 115.65,133.9 115.47,133.72 115.47,133.06 115.25,132.84 107.62,132.84 96.63,143.83 v3(93.84,143.83)
  BOTTOM w0.102: v4(149.51,133.86) 149.05,133.4 147.34,133.4 147.24,133.5 147.24,133.83 147.14,133.93 146.94,133.93 146.84,133.83 146.84,133.5 146.73,133.4 146.32,133.4 145.81,133.91 144.77,133.91 144.77,133.91 144.08,133.91 144.08,133.91 142.45,133.91 v4(142.4,133.86) 141.94,133.4 138.93,133.4 138.02,134.32 134.86,134.32 v4(134.4,133.86) 134.4,133.32 v2(134.15,133.07)
M_DATA_A58: length 93.4
  TOP w0.165: DIMM1.191 132.41,131.15 v4(132.75,130.81) ; v4(149.51,130.3) 148.68,131.13 147.6,131.13 147.58,131.15 DIMM2.191 ; CPU1.BB24 88.24,148.94 88.24,148.03 88.11,147.9 88.11,144.85 v3(88.57,144.4)
  L4 w0.216: v4(142.34,129.81) 143.09,129.07 143.09,128.42 142.56,127.9 107.87,127.9 95.39,140.37 94.02,140.37 94.02,140.37 91.71,140.37 91.54,140.46 88.44,143.55 88.44,144.27 v3(88.57,144.4)
  BOTTOM w0.102: v4(132.75,130.81) 133.71,129.85 133.71,129.84 134.08,129.47 v2(134.3,129.47) 134.58,129.19 137.02,129.19 137.3,129.47 140.96,129.47 141.03,129.4 141.93,129.4 v4(142.34,129.81) 142.56,129.81 142.77,129.6 144.62,129.6 144.75,129.74 148.91,129.74 149.08,129.57 149.59,129.57 149.82,129.79 149.82,130 v4(149.51,130.3)
M_DATA_A59: length 90.9
  TOP w0.102: v3(88.55,146.81) 89.01,147.27 89.01,147.67 88.89,147.78 88.89,148.37 88.9,148.37 88.9,149.43 88.73,149.6 88.63,149.6 87.8,150.43 CPU1.AY23
  TOP w0.165: DIMM1.193 132.32,130.55 132.55,130.32 133.78,130.32 v4(134.27,130.81) ; v4(147.99,130.3) 147.74,130.55 DIMM2.193
  L4 w0.216: v4(140.83,129.95) 139.27,128.39 131.84,128.39 131.62,128.61 131.62,129.1 131.4,129.32 130.97,129.32 130.76,129.1 130.76,128.61 130.54,128.39 130.11,128.39 129.89,128.61 129.89,129.1 129.68,129.32 129.25,129.32 129.03,129.1 129.03,128.61 128.81,128.39 128.38,128.39 128.17,128.61 128.17,129.1 127.95,129.32 127.52,129.32 127.3,129.1 127.3,128.61 127.09,128.39 108.07,128.39 95.6,140.86 93.82,140.86 93.81,140.86 91.83,140.86 89.46,143.23 89.46,144.17 88.67,144.95 88.36,144.95 88.09,145.22 88.09,146.35 v3(88.55,146.81)
  BOTTOM w0.102: v4(147.99,130.3) 147.8,130.11 144.48,130.11 144.35,129.98 142.92,129.98 142.59,130.31 141.19,130.31 v4(140.83,129.95) 140.73,129.85 137.14,129.85 137.02,129.72 v2(136.3,129.72) 135.36,129.72 v4(134.27,130.81)
M_DATA_A60: length 92.9
  TOP w0.102: 91.92,145.73 91.47,146.18 91.47,146.88 91.29,147.06 91.29,147.97 91.3,147.97 91.3,148.23 91.29,148.23 91.29,148.74 91.3,148.75 91.3,149.04 91.12,149.22 91.12,149.58 CPU1.BA27
  TOP w0.165: v4(153.07,133.86) 153.53,134.45 DIMM2.180 ; v3(95.91,145.79) 95.59,145.47 95.59,144.96 95.34,144.71 94.97,144.71 94.77,144.91 92.74,144.91 91.92,145.73 ; v4(136.3,133.86) 136.9,134.45 DIMM1.180
  L4 w0.216: v4(143.64,133.02) 143.91,133.29 143.91,133.29 144.5,133.88 145.83,133.88 146.12,134.18 146.12,134.48 145.88,134.72 142.96,134.72 142.3,135.38 131.85,135.38 131.15,136.08 106.69,136.08 97.65,145.11 97.65,145.99 96.96,146.69 96.19,146.69 95.92,146.41 95.92,145.79 v3(95.91,145.79)
  BOTTOM w0.102: v4(153.07,133.86) 151.71,132.5 151.34,132.5 151.34,132.49 148.98,132.49 148.83,132.65 144.71,132.65 144.68,132.62 144.04,132.62 v4(143.64,133.02) 143.27,132.65 140.69,132.65 140.48,132.45 140.01,132.45 v2(140,132.45) 140,132.45 138.36,132.45 138.02,132.79 137.37,132.79 v4(136.3,133.86)
M_DATA_A61: length 90.8
  TOP w0.165: DIMM2.182 153.75,133.85 153.27,133.37 151.49,133.37 v4(151.47,133.35) ; v4(137.83,133.86) 137.84,133.85 DIMM1.182 ; CPU1.BC27 91,147.02 91.23,146.79 91.23,146.04 92.82,144.45 94.85,144.45 94.99,144.31 96.16,144.31 96.79,144.94 96.79,145.38 v3(96.8,145.4)
  L4 w0.216: v4(145.16,133.27) 145.07,133.18 145.07,132.99 144.58,132.51 143.43,132.51 143.13,132.81 143.13,133.86 142.1,134.89 131.64,134.89 130.94,135.59 130.45,135.59 130.24,135.37 130.24,135.1 130.02,134.89 129.59,134.89 129.37,135.1 129.37,135.37 129.16,135.59 128.73,135.59 128.51,135.37 128.51,135.1 128.3,134.89 127.86,134.89 127.65,135.1 127.65,135.37 127.43,135.59 127,135.59 126.78,135.37 126.78,135.1 126.57,134.89 126.14,134.89 125.92,135.1 125.92,135.37 125.7,135.59 125.27,135.59 125.06,135.37 125.06,135.1 124.84,134.89 124.41,134.89 124.19,135.1 124.19,135.37 123.98,135.59 123.55,135.59 123.33,135.37 123.33,135.1 123.11,134.89 122.68,134.89 122.47,135.1 122.47,135.37 122.25,135.59 121.82,135.59 121.6,135.37 121.6,135.1 121.39,134.89 120.95,134.89 120.74,135.1 120.74,135.37 120.52,135.59 120.09,135.59 119.88,135.37 119.88,135.1 119.66,134.89 119.23,134.89 119.01,135.1 119.01,135.37 118.8,135.59 118.36,135.59 118.15,135.37 118.15,135.1 117.93,134.89 117.5,134.89 117.28,135.1 117.28,135.37 117.07,135.59 106.49,135.59 96.81,145.26 96.81,145.39 v3(96.8,145.4)
  BOTTOM w0.102: v4(137.83,133.86) 137.83,133.55 138.36,133.02 142.68,133.02 143.19,133.53 144.24,133.53 144.24,133.53 144.62,133.53 144.62,133.53 144.88,133.53 145.14,133.27 v4(145.16,133.27) 145.2,133.27 145.24,133.32 145.87,133.32 146.17,133.02 149.65,133.02 v2(149.65,133.03) 149.65,133.02 151.14,133.02 v4(151.47,133.35)
M_DATA_A62: length 94.3
  TOP w0.165: v1(89.19,142.88) 89.6,142.88 v3(90.44,143.71) 89.23,144.92 89.23,146.87 89.44,147.08 89.44,147.94 89.4,147.98 CPU1.BC25 ; v4(137.07,130.81) 137.55,130.32 138.03,130.32 138.56,130.85 DIMM1.192 ; v4(153.07,130.81) 153.11,130.85 DIMM2.192
  L4 w0.216: v3(90.44,143.71) 90.44,143.64 92.24,141.84 93.41,141.84 93.41,141.85 96,141.85 107.55,130.3 115.32,130.3 115.53,130.51 115.53,130.78 115.75,130.99 116.18,130.99 116.4,130.78 116.4,130.51 116.61,130.3 117.04,130.3 117.26,130.51 117.26,130.78 117.47,130.99 117.91,130.99 118.12,130.78 118.12,130.51 118.34,130.3 118.77,130.3 118.99,130.51 118.99,130.78 119.2,130.99 119.63,130.99 119.85,130.78 119.85,130.51 120.07,130.3 120.5,130.3 120.71,130.51 120.71,130.78 120.93,130.99 121.36,130.99 121.58,130.78 121.58,130.51 121.79,130.3 122.22,130.3 122.44,130.51 122.44,130.78 122.66,130.99 123.09,130.99 123.3,130.78 123.3,130.51 123.52,130.3 123.95,130.3 124.17,130.51 124.17,130.78 124.38,130.99 124.82,130.99 125.03,130.78 125.03,130.51 125.25,130.3 125.68,130.3 125.89,130.51 125.89,130.78 126.11,130.99 126.54,130.99 126.76,130.78 126.76,130.51 126.97,130.3 127.41,130.3 127.62,130.51 127.62,130.78 127.84,130.99 128.27,130.99 128.49,130.78 128.49,130.51 128.7,130.3 139.29,130.3 139.94,130.95 143.1,130.95 143.21,130.84 v4(143.24,130.84)
  BOTTOM w0.102: v4(153.07,130.81) 152.61,131.27 143.67,131.27 v4(143.24,130.84) 142.81,131.27 142.44,131.27 142.23,131.06 142.03,131.06 141.83,131.27 141.62,131.27 141.42,131.06 141.22,131.06 141.01,131.27 140.81,131.27 140.61,131.06 140.4,131.06 140.2,131.27 140,131.27 139.79,131.06 139.59,131.06 139.39,131.27 139.18,131.27 138.98,131.06 138.78,131.06 138.57,131.27 137.52,131.27 v4(137.07,130.81)
M_DATA_A63: length 94.3
  TOP w0.102: CPU1.BB25 89.11,148.61 89.11,148.29 89.1,148.28 89.1,147.96 89.21,147.84 89.21,147.18 89,146.97 89,145.86 v3(88.55,145.41)
  TOP w0.165: v4(151.54,130.81) 152.1,130.25 DIMM2.194 ; DIMM1.194 138.37,130.25 138.15,130.03 136.32,130.03 v4(135.54,130.81)
  L4 w0.216: v4(144.76,130.81) 144.25,130.3 143.06,130.3 142.89,130.46 140.15,130.46 139.49,129.81 107.35,129.81 95.8,141.36 93.61,141.36 93.61,141.35 92.03,141.35 89.95,143.44 89.95,144.34 88.87,145.41 v3(88.55,145.41)
  BOTTOM w0.102: v4(135.54,130.81) 136,130.35 139.73,130.35 139.76,130.38 v2(139.77,130.38) 139.77,130.39 140.07,130.69 142.74,130.69 143.08,130.35 144.19,130.35 144.6,130.76 144.71,130.76 v4(144.76,130.81) 144.83,130.88 150.34,130.88 150.45,130.78 150.45,129.69 150.55,129.59 150.75,129.59 150.85,129.69 150.85,130.78 150.95,130.88 151.47,130.88 v4(151.54,130.81)
M_DQS_A_DN0: length 77.9
  TOP w0.102: 89.92,181.76 89.92,181.68 89.85,181.61 89.85,181.37 89.93,181.29 89.93,181.23 90.03,181.13 90.17,181.13 90.27,181.23 90.27,181.43 CPU1.A26
  TOP w0.127: DIMM2.10 153.8,187.85 153.45,187.5 153.15,187.5 152.48,188.18 151.78,188.18 151.54,187.93 151.14,187.93 v4(150.66,187.45) ; DIMM1.10 138.45,187.85 138.12,188.19 136.48,188.19 136.3,188.01 v4(136.3,187.48) ; 89.92,181.76 90.16,182 90.16,183.24 90.08,183.32 90.08,183.81 90.21,183.94 90.21,184.4 v3(90.1,184.51)
  L3 w0.152: v4(136.3,187.48) 136.81,187.99 137.17,187.99 137.68,188.49 146.16,188.49 147.68,186.97 150.17,186.97 v4(150.66,187.45)
  L4 w0.152: v4(136.3,187.48) 136.3,187.81 136.1,188.01 132.19,188.01 131.65,188.55 104.03,188.55 103.22,187.74 97.51,187.74 97.05,187.27 92.75,187.27 90.52,185.05 90.52,184.93 v3(90.1,184.51)
  BOTTOM w0.127: v4(150.66,187.45) 150.66,186.62 v2(150.67,186.61)
M_DQS_A_DN1: length 73.7
  TOP w0.102: CPU1.A30 93.5,181.6 93.5,182.12 94.25,182.87 94.33,182.87 95.01,183.55 95.22,183.55 95.38,183.72 95.38,183.85 v3(95.17,184.07)
  TOP w0.127: v4(133.51,182.5) 133.61,182.5 134.03,182.08 134.03,181.73 133.86,181.56 133.59,181.56 133.21,181.94 132.64,181.94 132.28,182.3 132.28,182.46 131.99,182.75 DIMM1.27 ; v4(149.26,182.5) 149.16,182.5 148.69,182.97 147.53,182.97 147.31,182.75 DIMM2.27
  L3 w0.152: v4(133.51,182.5) 133.61,182.5 133.76,182.65 133.76,182.96 133.61,183.11 117.84,183.11 117.61,182.88 103.8,182.88 102.87,183.81 96.16,183.81 95.98,183.63 95.61,183.63 v3(95.17,184.07)
  L4 w0.152: v4(133.51,182.5) 133.69,182.68 133.69,183.08 134.02,183.41 135.03,183.41 135.16,183.29 145.8,183.29 147.58,185.06 149.87,185.06 150.32,184.61 150.32,183.57 v4(149.26,182.5)
  BOTTOM w0.127: v2(132.41,181.7) 132.71,181.7 v4(133.51,182.5)
M_DQS_A_DN2: length 67.9
  TOP w0.102: v3(97.73,179.63) 97.62,179.74 97.28,179.74 97.1,179.55 97.1,179.55 96.86,179.31 96.86,179.12 96.02,178.28 95.73,178.28 95.71,178.31 95.29,178.31 95.12,178.13 94.75,178.13 94.65,178.23 94.65,178.56 94.75,178.66 95.04,178.66 CPU1.E32
  TOP w0.127: v4(148.75,177.16) 148.82,177.09 148.82,176.84 148.68,176.7 147.79,176.7 147.14,177.35 DIMM2.45 ; v4(133.51,177.16) 133.61,177.07 133.61,176.89 133.42,176.7 132.55,176.7 131.9,177.35 DIMM1.45
  L3 w0.152: v4(148.75,177.16) 148.24,176.65 141.72,176.65 140.42,177.95 134.63,177.95 134.37,177.7 134.04,177.7 v4(133.51,177.16)
  L4 w0.152: v4(133.51,177.16) 133.56,177.16 133.9,177.5 133.9,177.72 133.71,177.9 132.09,177.9 129.89,180.09 107.97,180.09 106.93,181.13 99.02,181.13 97.73,179.85 v3(97.73,179.63)
  BOTTOM w0.127: v2(132.5,176.35) 132.8,176.64 133.19,176.64 133.51,176.96 v4(133.51,177.16)
M_DQS_A_DN3: length 75.9
  TOP w0.102: v3(97.19,174.93) 96.9,174.93 96.72,175.11 96.38,175.11 96.36,175.08 95.77,175.08 95.74,175.11 95.22,175.11 95.11,175 95.01,175 94.91,175.1 94.91,175.3 95.01,175.4 CPU1.J32
  TOP w0.127: DIMM2.62 153.8,172.25 153.51,171.96 153.51,171.73 153.14,171.36 152.25,171.36 152.09,171.52 152.09,171.74 v4(152.18,171.83) ; DIMM1.62 140.13,172.25 141.53,170.85 142.19,170.85 142.76,170.28 143.62,170.28 143.8,170.46 143.8,170.91 143.39,171.32 v4(143.29,171.32)
  L3 w0.152: v4(152.18,171.83) 152.18,170.99 151.72,170.54 146.9,170.54 146.21,169.85 143.8,169.85 143.29,170.36 v4(143.29,171.32)
  L4 w0.152: v4(143.29,171.32) 143.75,170.87 143.75,170.41 143.64,170.3 140.96,170.3 140.46,169.8 132.57,169.8 131.96,170.41 118.54,170.41 116.92,172.04 106,172.04 105.9,172.04 102.58,175.36 98.49,175.36 97.93,174.8 97.32,174.8 v3(97.19,174.93)
  BOTTOM w0.127: v2(153.03,170.93) 152.91,171.06 152.91,171.1 v4(152.18,171.83)
M_DQS_A_DN4: length 72.9
  TOP w0.102: CPU1.AR33 96.06,154.44 96.24,154.44 96.25,154.43 97.57,154.43 97.86,154.14 98.69,154.14 98.75,154.08 99.3,154.08 99.35,154.13 99.52,154.13 99.64,154.01 99.64,153.69 99.42,153.47 v3(99.17,153.47)
  TOP w0.127: v4(149.64,147.45) 149.38,147.7 149.38,147.98 148.99,148.37 147.79,148.37 147.37,147.95 DIMM2.135 ; v4(133.64,147.98) 133.64,147.98 134.15,147.48 134.15,147.35 133.91,147.12 133.26,147.12 132.85,147.53 132.42,147.53 132,147.95 DIMM1.135
  L3 w0.152: v4(149.64,147.45) 149.54,147.35 149.54,146.79 149.16,146.41 147.71,146.41 147.62,146.49 145.91,148.21 144.05,148.21 144.05,148.21 139.78,148.21 138.03,146.46 134.02,146.46 133.66,146.81 133.66,147.95 v4(133.64,147.98)
  L4 w0.152: v3(99.17,153.47) 99.21,153.47 99.75,152.92 102.05,152.92 105.11,149.86 116.17,149.86 116.32,149.71 116.32,149.1 116.65,148.77 117.21,148.77 117.54,149.1 117.54,149.71 117.69,149.86 131.25,149.86 132.42,148.69 133.99,148.69 134.09,148.59 134.09,148.44 133.65,147.99 133.64,147.99 v4(133.64,147.98)
  BOTTOM w0.127: v4(133.64,147.98) 133.64,147.42 v2(133.37,147.15)
M_DQS_A_DN5: length 73
  TOP w0.127: DIMM2.152 153.96,142.85 153.54,142.43 153.54,142.43 153.26,142.15 152.53,142.15 152.35,142.33 152.31,142.38 v4(152.31,142.62) ; v4(134.27,142.37) 134.27,142.8 134.37,142.9 135.17,142.9 135.48,142.58 138.37,142.58 138.64,142.85 DIMM1.152 ; CPU1.AW33 95.9,151.32 95.96,151.26 96.25,150.96 96.89,150.96 v3(96.93,150.92)
  L3 w0.152: v4(152.31,142.62) 151.65,143.28 144.61,143.28 142.5,141.17 140.32,141.17 139.03,142.46 138.08,143.41 135.64,143.41 135.09,142.85 134.75,142.85 v4(134.27,142.37)
  L4 w0.152: v4(134.27,142.37) 134.27,141.99 134.12,141.83 106.44,141.83 100.35,147.92 99.78,147.92 99.17,148.53 99.17,148.78 97.03,150.92 v3(96.93,150.92)
  BOTTOM w0.127: v3(96.93,150.92) v2(96.2,150.92)
M_DQS_A_DN6: length 79
  TOP w0.102: CPU1.AY29 92.89,150.5 93.1,150.29 93.1,149.17 93.13,149.15 93.13,148.67 93.07,148.62 93.07,148.37 v3(94.37,147.08)
  TOP w0.127: v4(148.75,137.54) 148.28,137.07 147.79,137.07 147.11,137.75 DIMM2.169 ; v4(133.87,137.26) 133.49,137.26 133.35,137.4 132.28,137.4 131.93,137.75 DIMM1.169
  L3 w0.152: v4(133.87,137.26) 133.69,137.44 131.48,137.44 129.75,139.17 117.26,139.17 116.47,138.39 116.47,137.54 116.14,137.21 115.58,137.21 115.25,137.54 115.25,139.02 115.1,139.17 114.8,139.17 114.64,139.02 114.64,137.54 114.31,137.21 102.04,137.21 93.81,145.44 93.81,146.52 v3(94.37,147.08)
  L4 w0.152: v4(148.75,137.54) 148.85,137.64 148.85,138.05 148.62,138.28 143.33,138.28 141.55,136.5 134.98,136.5 134.68,136.8 134.32,136.8 v4(133.87,137.26)
  BOTTOM w0.127: v4(133.87,137.26) 133.48,137.26 133.21,137.53 132.6,137.53 v2(132.5,137.43)
M_DQS_A_DN7: length 81.7
  TOP w0.102: CPU1.AY25 89.79,150.11 89.79,149.28 89.97,149.1 89.97,148.73 89.87,148.63 89.87,148.37 89.95,148.3 89.95,146.8 89.67,146.52 89.67,146.1 90.08,145.69 v3(90.08,145.67)
  TOP w0.127: v4(152.3,132.08) 152.76,132.54 153.63,132.54 153.73,132.65 DIMM2.186 ; v4(137.07,132.26) 137.61,132.8 138.02,132.8 138.18,132.65 DIMM1.186
  L3 w0.152: v4(137.07,132.26) 137.19,132.26 137.63,131.82 138.03,131.82 138.03,131.83 139.29,131.83 140.06,132.59 142.6,132.59 143.01,132.18 146.41,132.18 146.79,132.56 151.81,132.56 v4(152.3,132.08)
  L4 w0.152: v4(137.07,132.26) 137.07,132.23 136.66,131.83 107.2,131.83 96.35,142.68 93.06,142.68 93.06,142.68 92.58,142.68 91.27,143.98 91.27,144.7 90.31,145.67 v3(90.08,145.67)
  BOTTOM w0.127: v4(137.07,132.26) 136.25,133.07 v2(135.91,133.07)
M_DQS_A_DP0: length 77.2
  TOP w0.127: v4(151.42,187.45) 151.89,187.92 152.37,187.92 153.05,187.25 DIMM2.12 ; DIMM1.12 138.69,187.25 138.01,187.93 137.55,187.93 137.09,187.48 v4(137.07,187.48) ; v3(90.15,185.29) 90.39,185.06 90.39,184.81 90.52,184.68 90.52,184.33 90.46,184.28 90.46,183.84 90.33,183.7 90.33,183.43 90.42,183.34 90.42,181.73 90.52,181.63 90.52,181.02 CPU1.B26
  L3 w0.152: v4(151.42,187.45) 150.93,186.97 150.6,186.97 150.3,186.66 147.56,186.66 146.03,188.19 137.8,188.19 137.09,187.48 v4(137.07,187.48)
  L4 w0.152: v4(137.07,187.48) 136.23,188.32 132.32,188.32 131.78,188.85 103.91,188.85 103.1,188.04 97.38,188.04 96.92,187.58 92.62,187.58 90.33,185.29 v3(90.15,185.29)
  BOTTOM w0.127: v4(151.42,187.45) 151.42,187.96 v2(151.85,188.39)
M_DQS_A_DP1: length 73.5
  TOP w0.102: v3(95.8,184.06) 95.59,183.84 95.59,183.63 95.3,183.35 95.09,183.35 94.41,182.67 94.34,182.67 93.71,182.03 93.71,181.34 CPU1.B30
  TOP w0.127: DIMM2.29 147.08,182.15 147.43,182.5 147.43,182.51 147.64,182.71 148.28,182.71 v4(148.5,182.5) ; v4(134.27,182.5) 134.27,182.19 134.28,182.18 134.28,181.62 133.97,181.31 133.48,181.31 133.1,181.69 132.54,181.69 132.07,182.15 DIMM1.29
  L3 w0.152: v4(134.27,182.5) 134.07,182.7 134.07,183.08 133.74,183.41 117.71,183.41 117.48,183.18 103.93,183.18 103,184.11 96.04,184.11 95.98,184.06 v3(95.8,184.06)
  L4 w0.152: v4(134.27,182.5) 133.99,182.78 133.99,182.96 134.15,183.11 134.91,183.11 135.03,182.98 145.93,182.98 147.71,184.76 149.74,184.76 150.02,184.48 150.02,183.69 149.46,183.13 148.22,183.13 148.06,182.98 148.06,182.77 148.33,182.5 v4(148.5,182.5)
  BOTTOM w0.127: v2(135.14,183.38) 134.27,182.51 v4(134.27,182.5)
M_DQS_A_DP2: length 68.3
  TOP w0.102: v3(97.26,179.15) 97.17,179.15 96.1,178.08 95.65,178.08 95.63,178.1 95.37,178.1 95.2,177.93 95.18,177.93 95.05,177.8 CPU1.F32
  TOP w0.127: v4(149.51,177.16) 148.79,176.44 147.69,176.44 147.38,176.75 DIMM2.47 ; v4(134.27,177.19) 133.52,176.44 132.45,176.44 132.14,176.75 DIMM1.47
  L3 w0.152: v4(134.27,177.19) 134.3,177.19 134.75,177.65 140.29,177.65 141.59,176.35 148.37,176.35 148.7,176.68 149.03,176.68 v4(149.51,177.16)
  L4 w0.152: v3(97.26,179.15) 97.26,179.81 98.89,181.44 107.05,181.44 108.09,180.4 130.02,180.4 132.21,178.21 133.84,178.21 134.2,177.84 134.2,177.26 v4(134.27,177.19)
  BOTTOM w0.127: v4(134.27,177.19) 134.27,177.13 v2(135.16,176.24)
M_DQS_A_DP3: length 75.6
  TOP w0.102: v3(96.55,174.7) 96.38,174.88 95.66,174.88 95.64,174.9 95.31,174.9 95,174.6 CPU1.K32
  TOP w0.127: DIMM2.64 153.78,171.65 153.24,171.11 152.14,171.11 v4(151.42,171.83) ; DIMM1.64 140.37,171.65 141.42,170.6 142.08,170.6 142.65,170.03 143.72,170.03 144.05,170.36 v4(144.05,171.32)
  L3 w0.152: v4(151.42,171.83) 151.87,171.37 151.87,171.12 151.59,170.84 146.77,170.84 146.08,170.15 143.92,170.15 143.59,170.48 143.59,170.87 v4(144.05,171.32)
  L4 w0.152: v4(144.05,171.32) 144.05,170.28 143.77,170 141.09,170 140.59,169.49 132.45,169.49 131.83,170.11 118.42,170.11 116.79,171.74 105.78,171.74 102.46,175.06 98.61,175.06 98.05,174.5 96.76,174.5 v3(96.55,174.7)
  BOTTOM w0.127: v4(151.42,171.83) 151.42,172.37 151.02,172.77 v2(151.02,172.83)
M_DQS_A_DP4: length 73.7
  TOP w0.102: v3(98.56,153.7) 98.46,153.8 98.35,153.91 98.32,153.94 97.77,153.94 97.48,154.23 95.82,154.23 95.68,154.37 95.33,154.37 CPU1.AR32
  TOP w0.127: DIMM2.137 147.13,147.35 147.9,148.12 148.89,148.12 149.13,147.88 149.13,147.7 v4(148.88,147.45) ; v4(134.4,148.01) 134.4,147.24 134.02,146.86 133.15,146.86 132.74,147.27 132.17,147.27 132.15,147.3 132.06,147.35 DIMM1.137
  L3 w0.152: v4(148.88,147.45) 149.23,147.09 149.23,146.91 149.03,146.71 147.84,146.71 146.51,148.03 146.03,148.51 139.66,148.51 137.9,146.76 134.14,146.76 133.97,146.94 133.97,147.19 134.12,147.35 134.65,147.35 134.81,147.5 134.81,147.68 134.48,148.01 v4(134.4,148.01)
  L4 w0.152: v4(134.4,148.01) 134.4,148.72 134.12,149 132.55,149 131.38,150.16 117.57,150.16 117.24,149.83 117.24,149.23 117.08,149.08 116.78,149.08 116.63,149.23 116.63,149.83 116.3,150.16 105.24,150.16 102.17,153.23 99.87,153.23 99.62,153.49 99.62,153.64 99.35,153.9 98.76,153.9 v3(98.56,153.7)
  BOTTOM w0.127: v2(97.01,154.53) 97.72,154.53 v3(98.56,153.7)
M_DQS_A_DP5: length 72.2
  TOP w0.127: DIMM2.154 153.72,142.25 153.37,141.9 152.43,141.9 152.18,142.15 152.01,142.15 v4(151.54,142.62) ; DIMM1.154 138.54,142.25 138.46,142.33 135.07,142.33 v4(135.03,142.37) ; v3(96.93,150.29) 96.51,150.71 96.15,150.71 95.94,150.92 95.74,151.12 95.38,151.12 CPU1.AW32
  L3 w0.152: v4(151.54,142.62) 151.19,142.98 144.73,142.98 142.63,140.87 140.19,140.87 138.9,142.16 137.95,143.1 135.77,143.1 v4(135.03,142.37)
  L4 w0.152: v3(96.93,150.29) 97.23,150.29 98.86,148.66 98.86,148.4 99.65,147.61 100.23,147.61 106.31,141.53 134.25,141.53 135.03,142.32 v4(135.03,142.37)
  BOTTOM w0.127: v2(96.27,149.66) 96.9,150.29 v3(96.93,150.29)
M_DQS_A_DP6: length 79.3
  TOP w0.102: v3(94.43,146.45) 94.21,146.67 94.2,146.67 93.96,146.91 93.96,147.2 92.87,148.29 92.87,148.7 92.92,148.75 92.92,148.78 92.92,148.78 92.92,149.06 92.89,149.09 92.89,149.41 CPU1.BA29
  TOP w0.127: v4(134.63,137.29) 134.12,136.78 133.61,136.78 133.24,137.15 DIMM1.171 ; DIMM2.171 147.35,137.15 147.69,136.82 148.39,136.82 148.64,137.07 148.97,137.07 149.44,137.54 v4(149.51,137.54)
  L3 w0.152: v4(134.63,137.29) 134.17,137.74 131.61,137.74 129.88,139.47 117.13,139.47 116.17,138.51 116.17,137.67 116.02,137.52 115.71,137.52 115.56,137.67 115.56,139.14 115.23,139.47 114.67,139.47 114.34,139.14 114.34,137.67 114.19,137.52 102.17,137.52 94.12,145.57 94.12,146.05 94.43,146.36 v3(94.43,146.45)
  L4 w0.152: v4(149.51,137.54) 149.16,137.9 149.16,138.18 148.75,138.58 143.2,138.58 141.43,136.8 135.11,136.8 v4(134.63,137.29)
  BOTTOM w0.127: v2(134.48,138.31) 134.61,138.18 134.61,137.83 134.63,137.81 v4(134.63,137.29)
M_DQS_A_DP7: length 79.7
  TOP w0.102: CPU1.BA25 89.59,149.51 89.59,149.19 89.77,149.01 89.77,148.82 89.67,148.72 89.67,148.29 89.74,148.21 89.74,146.89 89.47,146.61 89.47,146.02 89.67,145.81 89.67,145.5 90.08,145.09 v3(90.08,145.03)
  TOP w0.127: DIMM1.188 138.11,132.05 137.86,132.3 v4(137.83,132.3) ; v4(153.06,132.07) 153.08,132.05 DIMM2.188
  L3 w0.152: v4(153.06,132.07) 152.55,132.58 152.23,132.58 151.94,132.87 146.67,132.87 146.29,132.49 143.13,132.49 142.73,132.89 139.93,132.89 139.17,132.13 138,132.13 v4(137.83,132.3)
  L4 w0.152: v4(137.83,132.3) 137.3,131.78 137.04,131.78 136.79,131.52 107.07,131.52 96.22,142.37 93.19,142.37 93.19,142.37 92.45,142.37 90.97,143.86 90.97,144.58 90.51,145.03 v3(90.08,145.03)
  BOTTOM w0.127: v4(153.06,132.07) 153.82,132.07 153.85,132.1 v2(153.93,132.1)
M_MA_DM0: length 88
  TOP w0.165: v3(89.8,179.9) 89.4,179.5 CPU1.D25 ; v4(132.75,187.45) 132.65,187.55 DIMM1.11 ; v4(147.96,187.45) 147.86,187.55 DIMM2.11
  L4 w0.216: v4(140.88,187.58) 140.74,187.44 140.46,187.44 139.96,186.94 132.1,186.94 131.02,188.02 121.46,188.02 120.64,187.21 120.15,187.21 119.94,187.43 119.94,187.81 119.72,188.02 119.29,188.02 119.08,187.81 119.08,187.43 118.86,187.21 118.43,187.21 118.21,187.43 118.21,187.81 118,188.02 117.56,188.02 117.35,187.81 117.35,187.43 117.13,187.21 116.7,187.21 116.48,187.43 116.48,187.81 116.27,188.02 115.84,188.02 115.62,187.81 115.62,187.43 115.4,187.21 114.97,187.21 114.76,187.43 114.76,187.81 114.54,188.02 114.11,188.02 113.89,187.81 113.89,187.43 113.68,187.21 113.25,187.21 113.03,187.43 113.03,187.81 112.81,188.02 112.38,188.02 112.17,187.81 112.17,187.43 111.95,187.21 111.52,187.21 111.3,187.43 111.3,187.81 111.09,188.02 110.66,188.02 110.44,187.81 110.44,187.43 110.22,187.21 109.79,187.21 109.58,187.43 109.58,187.81 109.36,188.02 108.93,188.02 108.71,187.81 108.71,187.43 108.5,187.21 108.06,187.21 107.85,187.43 107.85,187.81 107.63,188.02 107.2,188.02 106.98,187.81 106.98,187.43 106.77,187.21 106.34,187.21 106.12,187.43 106.12,187.81 105.91,188.02 105.47,188.02 105.26,187.81 105.26,187.43 105.04,187.21 97.73,187.21 97.26,186.75 96.83,186.75 96.83,186.75 92.96,186.75 90.56,184.34 90.56,184.05 90.33,183.82 90.33,181.97 89.8,181.43 v3(89.8,179.9)
  BOTTOM w0.102: v4(147.96,187.45) 147.96,187.92 147.86,188.03 145.59,188.03 145.49,188.13 145.49,188.37 145.39,188.47 145.19,188.47 145.08,188.37 145.08,188.13 144.98,188.03 141.45,188.03 v4(140.88,187.58) 140.42,187.91 137.6,187.91 137.57,187.93 134.52,187.93 v2(134.51,187.94) 134.5,187.93 133.23,187.93 v4(132.75,187.45)
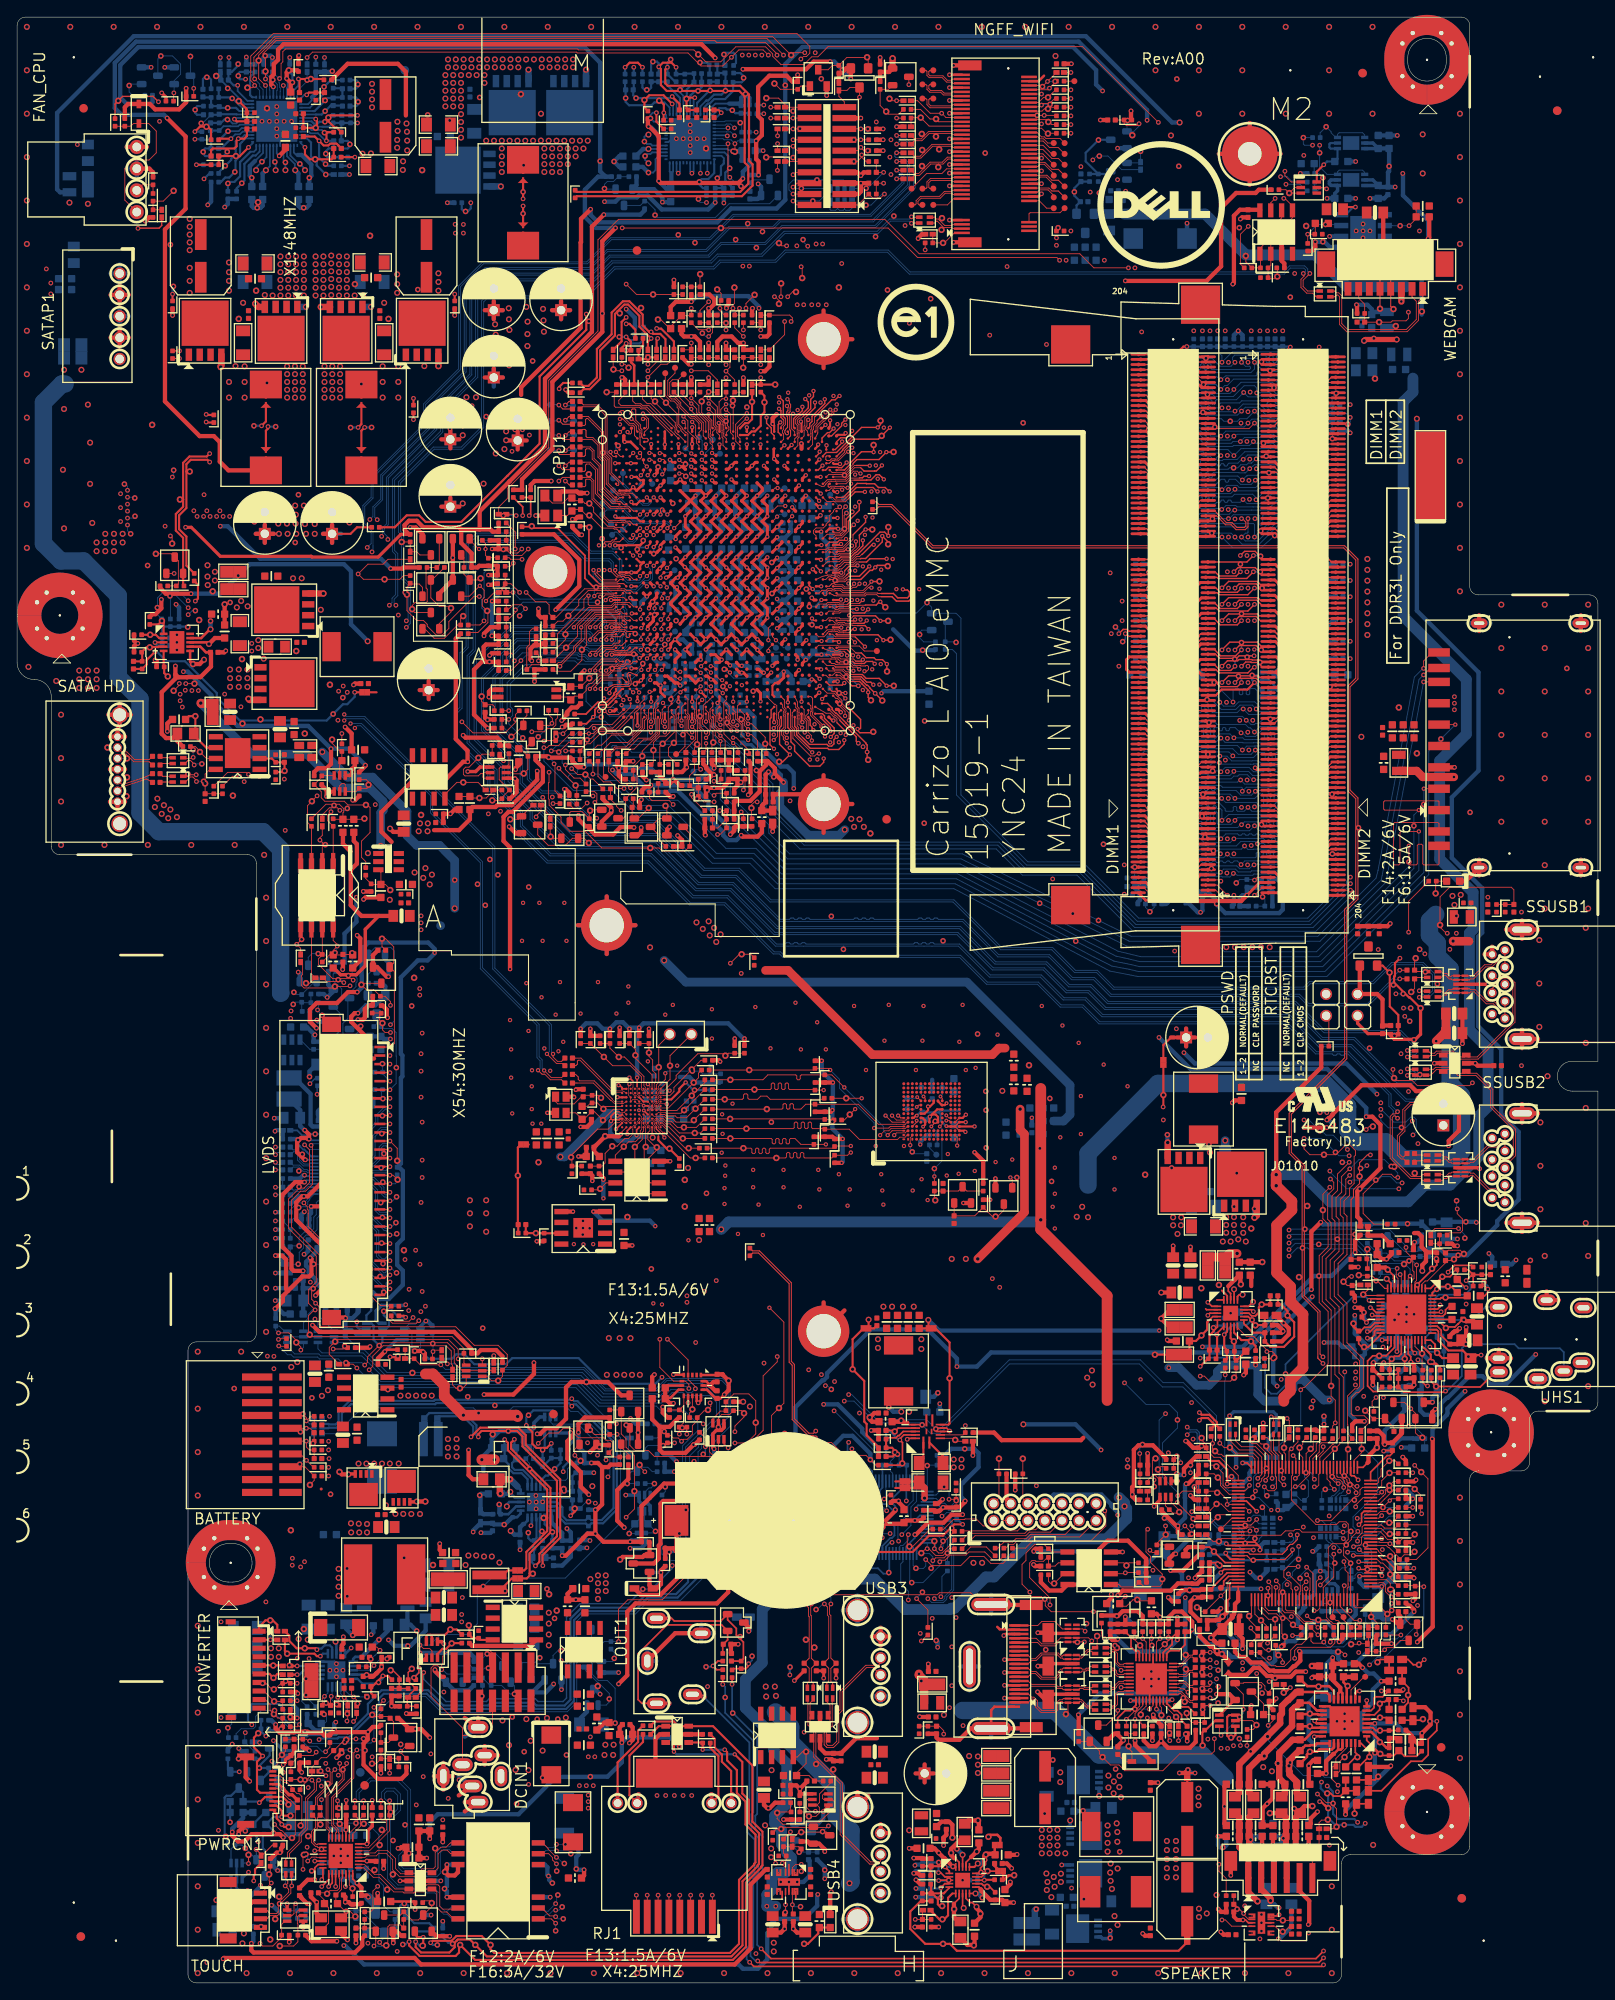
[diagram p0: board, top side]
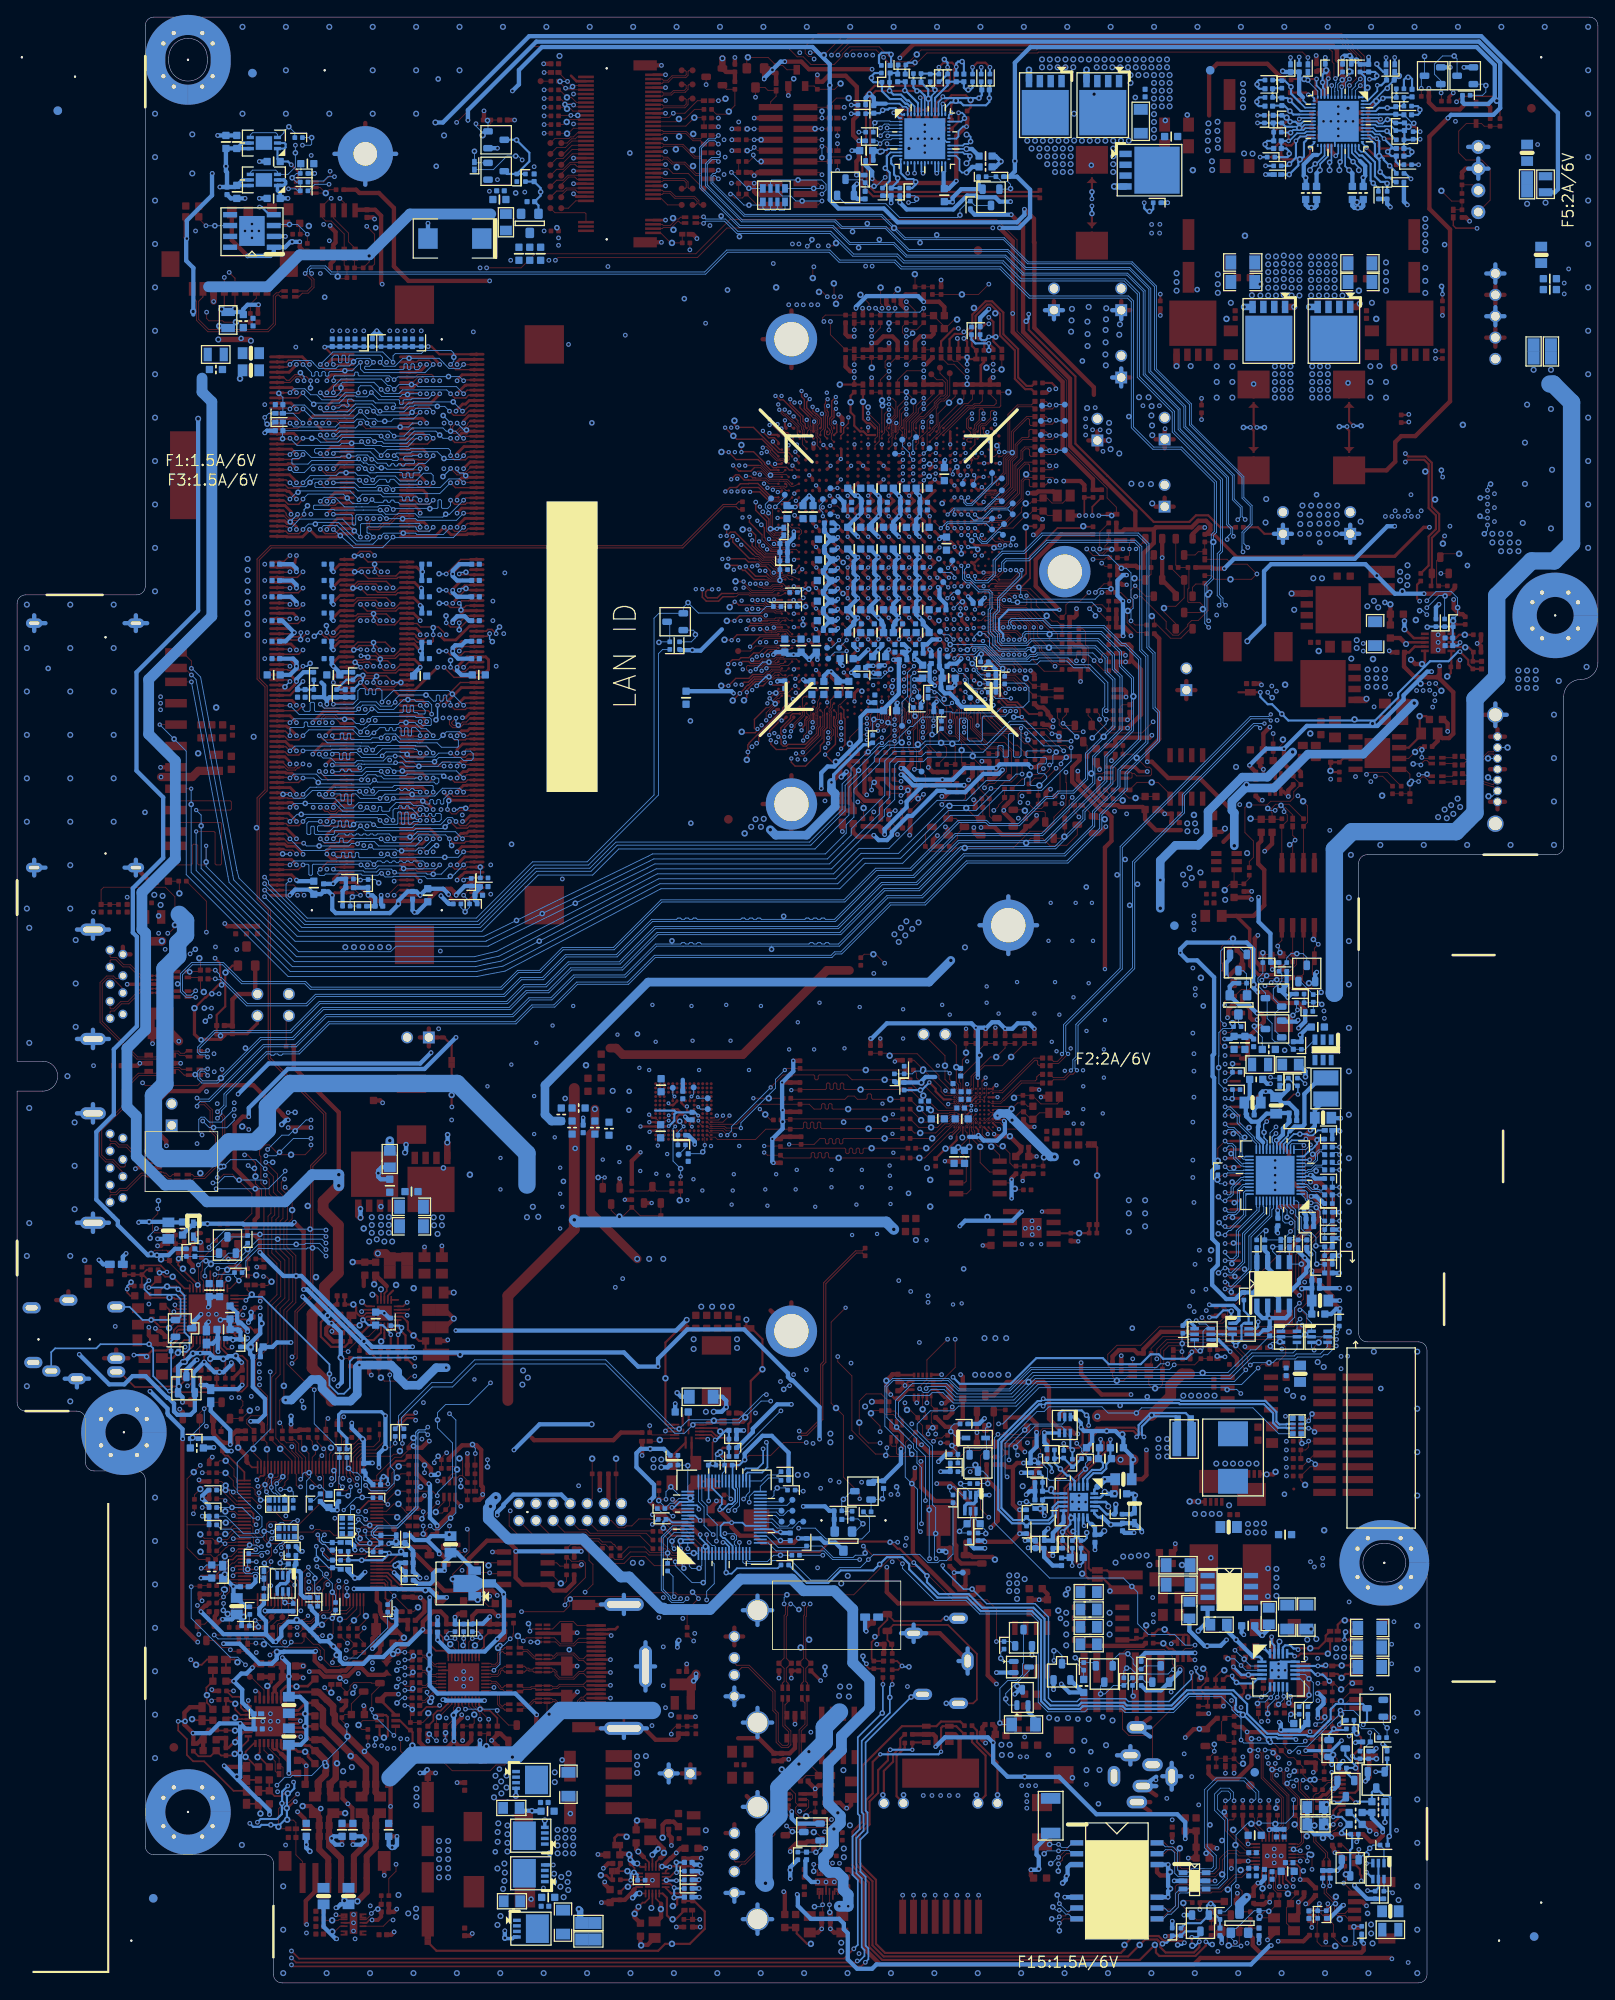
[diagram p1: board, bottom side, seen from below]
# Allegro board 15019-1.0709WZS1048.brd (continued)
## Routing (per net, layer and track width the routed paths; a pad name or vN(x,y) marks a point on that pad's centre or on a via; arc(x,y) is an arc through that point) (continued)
M_MA_DM1: length 79.5
  TOP w0.102: 93.62,182.77 93.62,182.54 93.2,182.12 93.2,181.76 93.1,181.66 93.1,181.35 93.11,181.35 93.11,180.83 93.1,180.83 93.1,180 CPU1.D29
  TOP w0.165: DIMM1.28 137.88,182.45 v4(137.83,182.5) ; v3(94.13,183.28) 93.62,182.77 ; v4(153.07,182.5) 153.12,182.45 DIMM2.28
  L3 w0.216: v3(94.13,183.28) 94.14,183.29 94.14,183.93 95.35,185.14 96.25,185.14 96.75,184.64 103.22,184.64 104.01,183.85 116.42,183.85 116.54,183.97 118.42,183.97 118.64,184.19 118.64,184.97 118.86,185.19 119.78,185.19 119.99,184.97 119.99,184.24 120.21,184.02 120.64,184.02 120.86,184.24 120.86,184.97 121.07,185.19 130.76,185.19 131.54,184.41 138.89,184.41 140.16,183.15 143.4,183.15 v4(144.05,182.5)
  BOTTOM w0.102: v4(137.83,182.5) 138.72,182.5 139.17,182.04 v2(140.17,182.04) 143.59,182.04 v4(144.05,182.5) 144.51,182.96 145.22,182.96 145.61,182.57 147.25,182.57 147.77,182.04 152.61,182.04 v4(153.07,182.5)
M_MA_DM2: length 78.3
  TOP w0.165: v4(153.07,177.16) 153.18,177.05 DIMM2.46 ; v3(102.14,181.97) v1(101.18,181.01) 100.79,180.62 97.83,180.62 96.62,179.41 96.62,179.32 CPU1.E33 ; DIMM1.46 137.94,177.05 v4(137.83,177.16)
  L4 w0.216: v4(144.25,177.17) 143.74,177.68 140.41,177.68 138.89,179.2 132.11,179.2 130.39,180.93 113.84,180.93 113.62,181.14 113.62,181.77 113.41,181.98 112.97,181.98 112.76,181.77 112.76,181.14 112.54,180.93 112.11,180.93 111.9,181.14 111.9,181.77 111.68,181.98 111.25,181.98 111.03,181.77 111.03,181.14 110.82,180.93 110.38,180.93 110.17,181.14 110.17,181.77 109.95,181.98 109.52,181.98 109.3,181.77 109.3,181.14 109.09,180.93 108.31,180.93 107.27,181.97 v3(102.14,181.97)
  BOTTOM w0.102: v4(137.83,177.16) 137.83,176.78 137.93,176.68 138.55,176.68 138.65,176.58 138.65,176.2 138.75,176.1 138.96,176.1 139.06,176.2 139.06,176.58 139.16,176.68 139.36,176.68 139.47,176.58 139.47,176.2 139.57,176.1 139.77,176.1 139.87,176.2 139.87,176.58 140,176.71 142.98,176.71 142.99,176.68 143.68,176.68 143.68,176.68 143.77,176.68 144,176.91 144,176.98 144.19,177.16 144.25,177.16 v4(144.25,177.17) 144.31,177.17 144.59,177.45 144.63,177.45 144.8,177.62 150.48,177.62 151.39,176.71 152.61,176.71 v4(153.07,177.16)
M_MA_DM3: length 81.7
  TOP w0.102: 97.97,175.82 97.42,175.82 97,175.4 CPU1.J33
  TOP w0.165: DIMM2.63 147.87,171.95 v4(147.99,171.83) ; DIMM1.63 132.74,171.95 v4(132.75,171.96) ; v3(101.43,175.92) 101.36,175.99 101.36,176.01 101.19,176.18 100.91,176.45 100.53,176.45 99.92,175.84 99.42,175.84 99.4,175.82 97.97,175.82
  L4 w0.216: v4(141.77,171.32) 141.38,170.94 126.55,170.94 126.34,171.16 126.34,172.35 126.12,172.57 125.69,172.57 125.47,172.35 125.47,171.16 125.26,170.94 124.83,170.94 124.61,171.16 124.61,172.35 124.4,172.57 123.96,172.57 123.75,172.35 123.75,171.16 123.53,170.94 123.1,170.94 122.88,171.16 122.88,172.35 122.67,172.57 122.24,172.57 122.02,172.35 122.02,171.16 121.8,170.94 121.37,170.94 121.16,171.16 121.16,172.35 120.94,172.57 120.51,172.57 120.29,172.35 120.29,171.16 120.08,170.94 119.25,170.94 119.03,171.16 119.03,172.35 118.82,172.57 106.12,172.57 102.75,175.94 102.17,175.94 102.15,175.92 v3(101.43,175.92)
  BOTTOM w0.102: v4(147.99,171.83) 147.94,171.78 145.88,171.78 145.78,171.68 145.78,170.66 145.68,170.56 145.47,170.56 145.37,170.66 145.37,171.68 145.27,171.78 142.34,171.78 142.01,171.46 141.9,171.46 v4(141.77,171.32) 139.91,171.32 v2(139.89,171.3) 139.87,171.32 138.37,171.32 138.17,171.12 133.58,171.12 v4(132.75,171.96)
M_MA_DM4: length 82.1
  TOP w0.102: CPU1.AR30 93.8,154.9 95.24,154.9 95.25,154.89 95.74,154.89 95.75,154.9 96.08,154.9 96.35,154.64 97.77,154.64
  TOP w0.165: v3(100.36,154.34) 100.36,154.34 100.1,154.61 99.39,154.61 99.15,154.37 98.79,154.37 98.79,154.38 98.03,154.38 97.77,154.64 ; v4(153.07,147.45) 153.27,147.65 DIMM2.136 ; DIMM1.136 137.9,147.65 v4(137.83,147.57)
  L4 w0.216: v3(100.36,154.34) 100.49,154.21 100.49,154.19 100.87,153.81 102.4,153.81 105.43,150.78 119.25,150.78 119.47,151 119.47,151.35 119.68,151.56 120.11,151.56 120.33,151.35 120.33,151 120.55,150.78 120.98,150.78 121.19,151 121.19,151.35 121.41,151.56 121.84,151.56 122.06,151.35 122.06,151 122.27,150.78 122.71,150.78 122.92,151 122.92,151.35 123.14,151.56 123.57,151.56 123.79,151.35 123.79,151 124,150.78 124.43,150.78 124.65,151 124.65,151.35 124.86,151.56 125.3,151.56 125.51,151.35 125.51,151 125.73,150.78 126.16,150.78 126.38,151 126.38,151.35 126.59,151.56 127.02,151.56 127.24,151.35 127.24,151 127.46,150.78 128.31,150.78 129.13,150.78 129.13,150.78 135.22,150.78 136.55,149.45 136.55,149.27 136.85,148.96 138.38,148.96 139.02,148.32 143.3,148.32 143.8,147.83 143.8,147.78 v4(143.85,147.73)
  BOTTOM w0.102: v4(137.83,147.57) 137.83,147.39 137.55,147.12 136.63,147.12 136.53,147.22 136.53,147.85 136.73,148.06 138.31,148.06 138.44,148.18 143.39,148.18 v4(143.85,147.73) 143.91,147.73 144.42,147.21 144.8,147.21 144.92,147.34 145.32,147.34 145.85,147.87 146.65,147.87 v2(146.67,147.85) 146.73,147.9 152.61,147.9 v4(153.07,147.45)
M_MA_DM5: length 81.7
  TOP w0.165: DIMM1.153 132.55,142.55 v4(132.75,142.37) ; DIMM2.153 148.06,142.55 v4(148.12,142.49) ; v3(93.93,151.76) 93.57,151.4 CPU1.AW30
  L4 w0.216: v3(93.93,151.76) 96.24,149.45 96.72,149.45 97.12,149.05 97.59,149.05 99.56,147.08 99.91,147.08 105.99,141 107.17,141 107.38,140.79 107.38,140.23 107.6,140.02 108.03,140.02 108.25,140.23 108.25,140.79 108.46,141 108.89,141 109.11,140.79 109.11,140.23 109.33,140.02 109.76,140.02 109.97,140.23 109.97,140.79 110.19,141 110.62,141 110.84,140.79 110.84,140.23 111.05,140.02 111.49,140.02 111.7,140.23 111.7,140.79 111.92,141 117.67,141 117.89,140.79 117.89,140.67 118.1,140.46 118.54,140.46 118.75,140.67 118.75,140.79 118.97,141 119.4,141 119.62,140.79 119.62,140.67 119.83,140.46 120.26,140.46 120.48,140.67 120.48,140.79 120.69,141 121.13,141 121.34,140.79 121.34,140.67 121.56,140.46 121.99,140.46 122.21,140.67 122.21,140.79 122.42,141 122.85,141 123.07,140.79 123.07,140.67 123.29,140.46 123.72,140.46 123.93,140.67 123.93,140.79 124.15,141 124.58,141 124.8,140.79 124.8,140.67 125.01,140.46 125.44,140.46 125.66,140.67 125.66,140.79 125.88,141 126.31,141 126.52,140.79 126.52,140.67 126.74,140.46 127.17,140.46 127.39,140.67 127.39,140.79 127.6,141 128.04,141 128.25,140.79 128.25,140.67 128.47,140.46 128.9,140.46 129.12,140.67 129.12,140.79 129.33,141 129.76,141 129.98,140.79 129.98,140.67 130.19,140.46 130.63,140.46 130.84,140.67 130.84,140.79 131.06,141 131.49,141 131.71,140.79 131.71,140.67 131.92,140.46 138.04,140.46 138.34,140.76 138.34,140.78 140.3,142.74 140.67,142.74 v4(140.7,142.77)
  BOTTOM w0.102: v4(148.12,142.49) 148,142.49 147.88,142.37 145.33,142.37 145.08,142.62 144.7,142.62 144.66,142.59 144.34,142.59 144.33,142.59 140.88,142.59 v4(140.7,142.77) 139.91,142.77 139.49,142.34 v2(137.98,142.34) 135.75,142.34 135.27,142.82 133.21,142.82 v4(132.75,142.37)
M_MA_DM6: length 93
  TOP w0.165: DIMM1.170 138.36,137.45 138.03,137.78 137.55,137.78 v4(137.07,137.29) ; DIMM2.170 153.16,137.45 v4(153.07,137.54) ; CPU1.BC30 94.24,148.5 94.48,148.26 94.48,147.96 95.62,146.82 95.62,146.18 v3(95.22,145.78)
  L3 w0.216: v3(95.22,145.78) 95.62,145.38 95.62,145.06 102.63,138.05 107.04,138.05 108.24,139.24 108.24,139.98 108.45,140.19 108.88,140.19 109.1,139.98 109.1,138.26 109.32,138.05 109.75,138.05 109.96,138.26 109.96,139.98 110.18,140.19 110.61,140.19 110.83,139.98 110.83,138.26 111.04,138.05 111.48,138.05 111.69,138.26 111.69,139.98 111.91,140.19 112.34,140.19 112.56,139.98 112.56,138.26 112.77,138.05 113.2,138.05 113.42,138.26 113.42,139.29 114.32,140.19 130.41,140.19 131.62,138.98 131.63,138.98 132.3,138.31 138.25,138.31 138.65,137.92 142.49,137.92 142.5,137.93 142.77,137.93 142.98,138.14 143.45,138.14 v4(144.05,137.54)
  BOTTOM w0.102: v4(153.07,137.54) 152.61,138 v2(151.27,138) 147.8,138 146.88,137.08 144.51,137.08 v4(144.05,137.54) 143.59,137.08 142.83,137.08 142.73,137.19 142.73,137.54 142.63,137.64 142.43,137.64 142.32,137.54 142.32,137.19 142.22,137.08 141.48,137.08 141.38,137.19 141.38,137.37 140.65,138.1 138.97,138.1 138.62,137.74 137.52,137.74 v4(137.07,137.29)
M_MA_DM7: length 92.4
  TOP w0.165: DIMM1.187 132.73,132.35 v4(132.75,132.33) ; CPU1.BC26 90.2,146.87 90.56,146.51 90.56,145.21 90.99,144.78 90.99,144.12 92.74,142.37 93.95,142.37 94.39,142.81 v3(94.39,143.26) ; v4(147.99,132.08) 147.72,132.35 DIMM2.187
  L4 w0.216: v4(141.64,132.08) 140.86,132.85 132.4,132.85 131.9,132.35 131.25,132.35 131.03,132.57 131.03,133.23 130.85,133.41 130.36,133.41 130.17,133.23 130.17,132.57 129.95,132.35 129.52,132.35 129.31,132.57 129.31,133.23 129.12,133.41 128.63,133.41 128.44,133.23 128.44,132.57 128.23,132.35 127.8,132.35 127.58,132.57 127.58,133.23 127.39,133.41 126.9,133.41 126.72,133.23 126.72,132.57 126.5,132.35 126.07,132.35 125.85,132.57 125.85,133.23 125.67,133.41 125.18,133.41 124.99,133.23 124.99,132.57 124.77,132.35 124.34,132.35 124.12,132.57 124.12,133.23 123.94,133.41 123.45,133.41 123.26,133.23 123.26,132.57 123.05,132.35 107.42,132.35 96.55,143.22 94.43,143.22 v3(94.39,143.26)
  BOTTOM w0.102: v4(147.99,132.08) 147.56,131.65 147.15,131.65 147.05,131.75 147.05,132.17 146.94,132.27 146.74,132.27 146.64,132.17 146.64,131.75 146.54,131.65 146.33,131.65 146.23,131.75 146.23,132.17 146.13,132.27 145.93,132.27 145.83,132.17 145.83,131.75 145.73,131.65 145.52,131.65 145.42,131.75 145.42,132.17 145.32,132.27 145.12,132.27 145.01,132.17 145.01,131.75 144.91,131.65 142.07,131.65 v4(141.64,132.08) 141.2,131.64 140.65,131.64 140.6,131.7 v2(134.95,131.7) 133.38,131.7 v4(132.75,132.33)
M_MAA_A0: length 82.2
  TOP w0.102: CPU1.AG31 94.66,161 94.96,161.3 95.24,161.3 95.25,161.29 95.77,161.29 95.78,161.3 96.06,161.3 96.12,161.24 97.14,161.24 97.17,161.27
  TOP w0.165: v4(134.78,157.73) 135.69,158.64 137.78,158.64 138.18,159.05 DIMM1.98 ; DIMM2.98 152.13,159.05 151.62,159.56 v4(151.54,159.56) ; v3(97.7,161.8) 97.17,161.27
  L3 w0.216: v3(97.7,161.8) 97.87,161.97 97.87,161.99 98.51,162.63 99.83,162.63 99.83,162.63 100.59,162.63 100.59,162.63 101.44,162.63 101.69,162.38 101.73,162.34 103.73,162.34 108.23,157.85 108.26,157.85 108.47,157.64 127.17,157.64 127.92,156.89 143.95,156.89 144.76,156.08 144.76,156.03 v3(144.79,156.01)
  L4 w0.216: v4(134.78,157.73) 135.57,156.95 143.85,156.95 v3(144.79,156.01) 147.28,158.5 150.48,158.5 v4(151.54,159.56)
  BOTTOM w0.165: v3(144.79,156.01) 145.55,156.01 v2(145.6,155.96)
M_MAA_A1: length 71.5
  TOP w0.102: 96.86,165.2 96.86,164.83 96.62,164.59 96.25,164.59 96.12,164.72 95.66,164.72 95.64,164.7 95.35,164.7 95.33,164.72 94.87,164.72 94.87,164.71 94.77,164.69 94.23,164.56 CPU1.AC30
  TOP w0.165: v4(142.53,159.38) 143.02,159.87 145.02,159.87 145.54,159.35 DIMM2.97 ; v3(98.35,165.84) 98.26,165.75 97.36,165.75 96.86,165.24 96.86,165.2 ; v4(134.78,159.13) 134.29,158.64 133.05,158.64 132.34,159.35 DIMM1.97
  L3 w0.216: v4(142.53,159.38) 141.59,160.32 140.12,160.32 138.18,162.26 137.23,162.26 137.13,162.35 131.76,162.35 130.5,163.62 127.93,163.62 127.3,164.25 126.87,164.68 121.28,164.68 118.45,167.5 101.95,167.5 101.28,166.84 99.35,166.84 v3(98.35,165.84)
  L4 w0.216: v4(142.53,159.38) 141.76,158.62 135.29,158.62 v4(134.78,159.13)
  BOTTOM w0.165: v4(134.78,159.13) 134.78,159.92 v2(134.81,159.94)
M_MAA_A2: length 72.1
  TOP w0.102: 97.07,164.71 96.72,164.36 96.17,164.36 96.02,164.52 95.76,164.52 95.7,164.45 95.3,164.45 95.23,164.52 94.95,164.52 94.63,164.2 CPU1.AC31
  TOP w0.165: v3(97.44,165.21) 97.44,165.08 97.07,164.71 ; v4(143.29,159.38) 142.8,158.9 140.8,158.9 140.51,159.18 140.51,159.2 140.07,159.65 DIMM1.96 ; v4(153.09,159.59) 153.27,159.59 153.33,159.65 DIMM2.96
  L3 w0.216: v3(97.44,165.21) 97.44,165.58 99.12,167.26 101.11,167.26 101.77,167.93 118.85,167.93 121.64,165.14 127,165.14 128.1,164.04 130.67,164.04 131.25,163.46 136.63,163.46 137.4,162.68 138.36,162.68 140.3,160.74 142.06,160.74 143.29,159.51 v4(143.29,159.38)
  L4 w0.216: v4(143.29,159.38) 144.2,160.3 152.84,160.3 153.07,160.07 153.07,159.61 v4(153.09,159.59)
  BOTTOM w0.165: v4(143.29,159.38) v2(143.29,160.2)
M_MAA_A3: length 72.8
  TOP w0.102: CPU1.AB32 95,165.3 95.64,165.3 95.64,165.29 96.13,165.29 96.27,165.43 96.5,165.43 97.05,165.98 97.92,165.98 98.18,166.25 98.59,166.25
  TOP w0.165: v4(141,159.38) 141.78,160.17 145.14,160.17 145.35,159.95 DIMM2.95 ; v3(101.76,166.62) 99.79,166.62 99.42,166.25 98.59,166.25 ; v4(133.26,159.13) 132.44,159.95 DIMM1.95
  L3 w0.216: v3(101.76,166.62) 102.22,167.08 102.83,167.08 102.94,166.96 118.25,166.96 120.96,164.25 121.51,164.25 121.73,164.04 121.73,163.49 121.95,163.27 122.38,163.27 122.59,163.49 122.59,164.04 122.81,164.25 123.24,164.25 123.46,164.04 123.46,163.39 123.67,163.17 124.1,163.17 124.32,163.39 124.32,164.04 124.54,164.25 124.97,164.25 125.18,164.04 125.18,163.39 125.4,163.17 125.83,163.17 126.05,163.39 126.05,164.04 126.26,164.25 126.69,164.25 126.91,164.04 126.91,163.41 127.13,163.19 130.32,163.19 131.59,161.93 136.96,161.93 137.05,161.84 138.01,161.84 139.95,159.9 140.49,159.9 v4(141,159.38)
  L4 w0.216: v4(141,159.38) 140.49,159.9 134.02,159.9 v4(133.26,159.13)
  BOTTOM w0.165: v2(133.26,158.32) v4(133.26,159.13)
M_MAA_A4: length 73.4
  TOP w0.102: 98.71,166.62 98.27,166.62 97.84,166.19 96.81,166.19 96.33,165.71 96.25,165.71 96.03,165.5 95.74,165.5 95.44,165.8 CPU1.AA32
  TOP w0.165: DIMM2.92 153.32,160.85 153.27,160.8 152.03,160.8 v4(151.54,161.29) ; DIMM1.92 140.34,160.85 140.68,160.51 144.03,160.51 v4(144.81,161.29) ; v1(101.94,168.33) 101.94,168.59 v3(101.25,169.28) 101.25,168.6 99.3,166.65 98.75,166.65 98.71,166.62
  L3 w0.216: v3(101.25,169.28) 101.38,169.41 101.38,169.42 102.16,170.2 107.18,170.2 109.88,170.2 110.47,169.61 119.71,169.61 122.49,166.83 128.58,166.83 129.63,165.78 137.72,165.78 140.86,162.65 143.46,162.65 v4(144.81,161.29)
  L4 w0.216: v4(151.54,161.29) 151.16,161.67 151.03,161.8 145.33,161.8 v4(144.81,161.29)
M_MAA_A5: length 71.2
  TOP w0.102: CPU1.AA33 96.04,165.94 96.25,165.94 96.7,166.39 97.75,166.39 98.25,166.88 98.59,166.88 98.84,167.13
  TOP w0.165: DIMM2.91 145.71,161.15 145.09,161.78 143.02,161.78 v4(142.53,161.29) ; v4(134.78,161.42) 134.29,160.93 132.67,160.93 132.45,161.15 DIMM1.91 ; v3(100.25,168.26) 100.02,168.26 98.89,167.13 98.84,167.13
  L3 w0.216: v3(100.25,168.26) 100.91,168.26 101.42,168.77 103.31,168.77 103.52,168.99 103.52,169.14 103.74,169.35 104.17,169.35 104.39,169.14 104.39,168.99 104.6,168.77 105.03,168.77 105.25,168.99 105.25,169.14 105.47,169.35 105.9,169.35 106.11,169.14 106.11,168.99 106.33,168.77 106.76,168.77 106.98,168.99 106.98,169.14 107.19,169.35 107.62,169.35 107.84,169.14 107.84,168.99 108.06,168.77 108.49,168.77 108.7,168.99 108.7,169.14 108.92,169.35 109.35,169.35 109.57,169.14 109.57,168.99 109.78,168.77 119.16,168.77 119.36,168.77 122.14,165.98 128.23,165.98 129.34,164.88 131.02,164.88 131.6,164.3 136.98,164.3 137.11,164.16 138.11,164.16 140.47,161.8 142.01,161.8 v4(142.53,161.29)
  L4 w0.216: v4(142.53,161.29) 142.49,161.29 141.98,161.8 137.74,161.8 136.84,160.9 135.29,160.9 v4(134.78,161.42)
  BOTTOM w0.165: v4(134.78,161.42) v2(135.59,161.42)
M_MAA_A6: length 72
  TOP w0.102: 98.36,167.12 98.19,167.12 97.67,166.59 96.54,166.59 96.24,166.28 94.82,166.28 94.34,165.8 CPU1.AA31
  TOP w0.165: v4(143.29,161.29) 142.8,160.8 140.8,160.8 140.15,161.45 DIMM1.90 ; v1(101.96,170.33) 101.96,170.33 v3(101.96,169.31) 101.53,169.74 100.98,169.74 98.36,167.12 ; v4(153.07,161.29) 153.23,161.45 DIMM2.90
  L3 w0.216: v3(101.96,169.31) 102.43,169.77 109.71,169.77 110.29,169.19 119.53,169.19 122.32,166.41 128.41,166.41 129.45,165.36 136.51,165.36 137.29,164.59 138.29,164.59 140.65,162.23 142.35,162.23 v4(143.29,161.29)
  L4 w0.216: v4(153.07,161.29) 152.13,162.23 144.23,162.23 v4(143.29,161.29)
M_MAA_A7: length 73.8
  TOP w0.165: CPU1.Y33 96.19,166.6 96.42,166.83 97.57,166.83 98.1,167.35 98.19,167.35 98.98,168.14 v3(98.98,168.78) ; v4(151.54,163.19) 152.09,162.65 DIMM2.86 ; DIMM1.86 140.44,162.65 140.68,162.41 144.03,162.41 v4(144.81,163.19)
  L3 w0.216: v4(144.81,163.19) 143.42,164.59 141.34,164.59 138.46,167.47 130.33,167.47 129.28,168.51 125.82,168.51 122.45,171.88 101.23,171.88 99.91,170.56 99.16,170.56 98.76,170.16 98.76,169 v3(98.98,168.78)
  L4 w0.216: v4(151.54,163.19) 151.03,163.71 145.33,163.71 v4(144.81,163.19)
  BOTTOM w0.165: v4(144.81,163.19) v2(145.7,163.19)
M_MAA_A8: length 73.4
  TOP w0.165: DIMM1.89 132.14,161.75 132.18,161.7 132.97,161.7 v4(133.26,161.42) ; DIMM2.89 145.53,161.75 145.21,162.07 141.78,162.07 v4(141,161.29) ; v3(94.07,165.16) 93.5,165.72 CPU1.AA30
  L3 w0.216: v4(141,161.29) 140.39,161.29 137.94,163.74 136.94,163.74 136.8,163.88 131.43,163.88 130.85,164.46 129.16,164.46 128.06,165.56 121.97,165.56 119.18,168.35 107.58,168.35 101.6,168.35 101.35,168.1 100.93,167.68 98.85,167.68 98.35,167.18 96.36,167.18 96.14,166.97 96.14,166.13 95.93,165.91 95.49,165.91 95.28,166.13 95.28,166.97 95.06,167.18 93.76,167.18 93.35,166.78 93.35,165.87 v3(94.07,165.16)
  L4 w0.216: v4(133.26,161.42) 134.02,160.65 134.19,160.48 140.19,160.48 v4(141,161.29)
  BOTTOM w0.165: v4(133.26,161.42) 133.05,161.21 v2(133.05,160.63)
M_MAA_A9: length 70.8
  TOP w0.102: 98.16,168.04 97.39,167.27 96.21,167.27 96.03,167.1 95.75,167.1 95.45,167.4 CPU1.W32
  TOP w0.165: v3(98.16,168.65) 98.16,168.04 ; v4(134.78,162.94) 134.29,162.45 133.05,162.45 132.56,162.95 DIMM1.85 ; DIMM2.85 145.57,162.95 145.3,163.21 145.3,163.4 145.02,163.68 143.02,163.68 v4(142.53,163.19)
  L3 w0.216: v3(98.16,168.65) 98.49,168.32 99.17,168.32 99.6,168.75 99.6,169 101.64,171.04 121.96,171.04 125.33,167.67 128.93,167.67 129.98,166.63 138.11,166.63 140.99,163.74 141.98,163.74 v4(142.53,163.19)
  L4 w0.216: v4(142.53,163.19) 141.76,162.43 135.29,162.43 v4(134.78,162.94)
  BOTTOM w0.165: v2(135.59,162.97) 135.57,162.94 v4(134.78,162.94)
M_MAA_A10: length 71.4
  TOP w0.102: 99.27,161.21 99.24,161.19 98.64,161.19 98.6,161.15 97.66,161.15 97.35,160.83 96.19,160.83 96.06,160.7 95.75,160.7 95.45,161 CPU1.AG32
  TOP w0.165: DIMM2.107 145.64,156.35 145.13,156.86 141.91,156.86 v4(141,155.96) ; 99.27,161.21 100.54,161.21 100.79,161.47 100.9,161.47 v3(101.02,161.59) 101.02,161.53 101.59,160.96 v1(101.61,160.96) ; DIMM1.107 132.74,156.35 v4(133.26,155.83)
  L3 w0.216: v4(141,155.96) 138.68,155.96 138.04,155.31 133.04,155.31 132.38,155.98 119.1,155.98 118.89,156.2 118.89,156.49 118.67,156.71 118.24,156.71 118.02,156.49 118.02,156.2 117.81,155.98 117.38,155.98 117.16,156.2 117.16,156.49 116.95,156.71 116.51,156.71 116.3,156.49 116.3,156.2 116.08,155.98 115.65,155.98 115.43,156.2 115.43,156.49 115.22,156.71 114.79,156.71 114.57,156.49 114.57,156.2 114.35,155.98 113.92,155.98 113.71,156.2 113.71,156.49 113.49,156.71 113.06,156.71 112.84,156.49 112.84,156.2 112.63,155.98 112.2,155.98 111.98,156.2 111.98,156.49 111.76,156.71 111.33,156.71 111.12,156.49 111.12,156.2 110.9,155.98 108.9,155.98 103.38,161.5 101.12,161.5 v3(101.02,161.59)
  L4 w0.216: v4(141,155.96) 140.36,155.31 133.77,155.31 v4(133.26,155.83)
M_MAA_A11: length 72
  TOP w0.102: 98.57,169.04 98.57,168.07 98.09,167.59 98,167.59 97.48,167.07 96.31,167.07 96.13,166.89 95.64,166.89 95.64,166.9 95,166.9 CPU1.Y32
  TOP w0.165: v1(100.08,170.05) v3(99.3,170.05) 99.23,170.05 98.57,169.39 98.57,169.04 ; DIMM2.84 153.12,163.25 v4(153.07,163.19) ; DIMM1.84 140.26,163.25 140.8,162.71 142.8,162.71 v4(143.29,163.19)
  L3 w0.216: v3(99.3,170.05) 99.99,170.05 101.41,171.46 122.27,171.46 125.64,168.09 129.11,168.09 130.15,167.05 138.28,167.05 141.16,164.16 142.32,164.16 v4(143.29,163.19)
  L4 w0.216: v4(143.29,163.19) 144.23,164.13 152.13,164.13 v4(153.07,163.19)
M_MAA_A12: length 72.8
  TOP w0.165: v4(133.26,162.94) 132.65,163.55 DIMM1.83 ; CPU1.W33 96.01,167.51 96.78,167.51 96.99,167.72 v3(97.23,167.72) ; DIMM2.83 145.56,163.55 145.14,163.98 141.78,163.98 141.03,163.23 v4(141,163.23)
  L3 w0.216: v4(141,163.23) 140.91,163.23 137.93,166.2 129.8,166.2 128.76,167.25 122.95,167.25 121.59,168.61 121.59,168.91 122.38,169.7 122.38,170.01 122.08,170.31 121.77,170.31 120.98,169.52 120.68,169.52 119.59,170.62 119.12,170.62 118.91,170.4 118.91,170.25 118.69,170.03 118.26,170.03 118.04,170.25 118.04,170.4 117.83,170.62 117.39,170.62 117.18,170.4 117.18,170.25 116.96,170.03 116.53,170.03 116.32,170.25 116.32,170.4 116.1,170.62 115.67,170.62 115.45,170.4 115.45,170.25 115.24,170.03 114.8,170.03 114.59,170.25 114.59,170.4 114.37,170.62 113.94,170.62 113.72,170.4 113.72,170.25 113.51,170.03 113.08,170.03 112.86,170.25 112.86,170.4 112.64,170.62 112.21,170.62 112,170.4 112,170.25 111.78,170.03 111.35,170.03 111.13,170.25 111.13,170.4 110.92,170.62 107.7,170.62 107.7,170.62 107.35,170.62 107,170.62 107,170.62 101.82,170.62 99.92,168.72 99.92,168.62 99.3,168 98.21,168 97.89,167.69 97.27,167.69 v3(97.23,167.72)
  L4 w0.216: v4(141,163.23) 140.97,163.23 140.49,163.71 134.02,163.71 v4(133.26,162.94)
  BOTTOM w0.165: v4(133.26,162.94) 133.05,163.14 v2(132.47,163.14)
M_MAA_A13: length 70.4
  TOP w0.102: CPU1.AL31 94.81,158.31 95.37,158.31 95.38,158.3 95.67,158.3 95.67,158.31 96.13,158.31 96.27,158.17 96.66,158.17 96.71,158.21
  TOP w0.165: v3(97.25,158.47) 96.99,158.21 96.71,158.21 ; DIMM1.119 133.86,152.75 v4(135.03,153.92) ; v4(141,152.15) 141.78,152.93 145.14,152.93 145.31,152.75 DIMM2.119
  L3 w0.216: v4(141,152.15) 140,152.15 139.15,151.3 131.27,151.3 131.26,151.29 115.06,151.29 113.75,152.6 113.33,152.6 113.12,152.38 113.12,151.51 112.9,151.29 112.47,151.29 112.25,151.51 112.25,152.38 112.04,152.6 107.52,152.6 106.56,153.55 106.56,153.55 102.97,157.14 102.12,157.14 101.67,157.59 100.13,157.59 100.02,157.48 98.23,157.48 v3(97.25,158.47)
  L4 w0.216: v4(141,152.15) 139.74,153.41 135.58,153.41 135.07,153.92 v4(135.03,153.92)
  BOTTOM w0.165: v4(141,152.15) v2(140.09,152.15)
M_MAA_A14: length 75.2
  TOP w0.102: 97.45,169.04 97.45,168.8 96.59,167.94 95.72,167.94 95.67,167.9 95.35,167.9 95.34,167.91 94.86,167.91 94.68,167.73 93.83,167.73 CPU1.W30
  TOP w0.165: v4(144.69,165.1) 143.9,164.32 140.55,164.32 140.42,164.45 DIMM1.80 ; DIMM2.80 152.19,164.45 v4(151.54,165.1) ; 97.45,169.04 97.55,169.14 97.55,170.25 v4(97.91,170.6)
  L3 w0.216: v4(144.69,165.1) 143.33,166.46 141.26,166.46 138.98,168.73 130.85,168.73 129.81,169.78 126.44,169.78 123.07,173.15 99.68,173.15 97.91,171.38 v4(97.91,170.6)
  L4 w0.216: v4(144.69,165.1) 145.2,165.61 151.03,165.61 v4(151.54,165.1)
  BOTTOM w0.165: v4(144.69,165.1) v2(145.5,165.1)
M_MAA_A15: length 71.3
  TOP w0.165: DIMM2.78 153.12,165.05 v4(153.07,165.1) ; v3(97.01,168.93) 96.86,168.79 96.23,168.79 96.01,168.57 95.07,168.57 CPU1.V32 ; DIMM1.78 140.23,165.05 140.67,164.61 142.67,164.61 v4(143.16,165.1)
  L3 w0.216: v3(97.01,168.93) 98.83,170.76 98.83,171.72 99.84,172.73 122.89,172.73 126.26,169.36 129.63,169.36 130.68,168.31 138.81,168.31 141.08,166.04 142.23,166.04 v4(143.16,165.1)
  L4 w0.216: v4(143.16,165.1) 144.1,166.04 152.13,166.04 v4(153.07,165.1)
  BOTTOM w0.165: v4(143.16,165.1) v2(143.16,165.99)
M_ODT_A0: length 62.5
  TOP w0.102: 97.39,157.99 97.37,157.97 96.71,157.97 96.7,157.96 96.17,157.96 96.03,158.1 95.78,158.1 95.77,158.09 95.27,158.09 95.26,158.1 94.97,158.1 94.8,157.93 94.8,157.87 94.43,157.5 93.8,157.5 CPU1.AL30
  TOP w0.165: v3(98.04,158.4) 97.8,158.4 97.39,157.99 ; v4(144.8,153.93) 144.69,153.93 144.03,153.27 140.68,153.27 140.3,153.65 DIMM1.116
  L3 w0.216: v4(144.8,153.93) 144.69,153.93 143.46,152.69 139.95,152.69 138.98,151.72 131.09,151.72 131.08,151.71 115.24,151.71 113.93,153.02 107.69,153.02 106.98,153.73 102.7,158.01 99.95,158.01 99.85,157.91 99.37,157.91 98.54,157.91 v3(98.04,158.4)
  BOTTOM w0.165: v2(145.45,154.51) 145.42,154.48 145.36,154.48 v4(144.8,153.93)
M_ODT_A1: length 58.7
  TOP w0.102: CPU1.AM32 95,157.3 95.64,157.3 95.65,157.29 97.61,157.29 v3(98.05,156.84)
  TOP w0.165: v4(143.29,152.15) 142.8,151.66 140.8,151.66 140.51,151.95 140.51,152.13 140.19,152.45 DIMM1.120
  L3 w0.216: v4(143.29,152.15) 143.26,152.15 142.33,151.21 140.26,151.21 139.5,150.46 131.62,150.46 131.61,150.45 120.89,150.45 120.39,149.95 119.94,149.95 119.43,150.45 118.75,150.45 118.25,149.95 118.05,149.95 118.05,149.94 117.81,149.94 117.81,149.95 110.37,149.95 110.37,149.94 108.98,149.94 108.98,149.95 107.94,150.98 102.62,156.3 100.58,156.3 99.81,157.06 99.6,157.06 99.54,157.12 98.32,157.12 v3(98.05,156.84)
  BOTTOM w0.165: v4(143.29,152.15) 143.29,152.53 v2(142.93,152.88)
M_ODT_B0: length 64.6
  TOP w0.102: CPU1.AJ32 95.44,159.4 95.75,159.1 96.03,159.1 96.12,159.18 96.81,159.18 96.91,159.07 97.89,159.07
  TOP w0.165: DIMM2.116 153.36,153.65 153.27,153.56 152.03,153.56 v4(151.54,154.05) ; v3(99.43,159.4) 99.1,159.07 97.9,159.07 97.89,159.07
  L3 w0.216: v4(151.54,154.05) 151.03,154.57 139.34,154.57 138.18,153.41 127.62,153.41 126.32,154.71 108.39,154.71 103.26,159.83 103.04,159.83 103.02,159.85 99.88,159.85 v3(99.43,159.4)
  BOTTOM w0.165: v2(150.71,154.38) 150.73,154.38 151.06,154.05 v4(151.54,154.05)
M_ODT_B1: length 65.8
  TOP w0.165: v4(153.07,152.27) 153.37,152.45 DIMM2.120 ; CPU1.AM33 96.06,157 v3(96.19,156.88)
  L3 w0.216: v4(153.07,152.27) 152.18,151.38 145.42,151.38 145.02,150.98 143.24,150.98 142.89,150.63 142.65,150.39 140.58,150.39 139.77,149.58 138.66,149.58 138.04,148.96 135.84,148.96 135.42,148.54 131.96,148.54 131.4,147.98 109.06,147.98 102.03,155.02 99.68,155.02 98.79,155.91 96.77,155.91 96.19,156.49 v3(96.19,156.88)
  BOTTOM w0.165: v4(153.07,152.27) 153.6,151.74 153.6,151.69 v2(153.65,151.64)
M_RAS_A_N: length 69.4
  TOP w0.102: 97.83,160.27 97.7,160.41 96.42,160.41 96.28,160.27 95.57,160.27 CPU1.AH33
  TOP w0.165: v4(144.76,155.27) 143.02,155.27 142.72,154.98 140.73,154.98 140.26,155.45 DIMM1.110 ; 97.83,160.27 99.17,160.27 v3(99.6,160.71) ; v4(151.54,155.96) 152.05,155.45 DIMM2.110
  L3 w0.216: v3(99.6,160.71) 99.64,160.66 99.65,160.66 103.03,160.66 108.56,155.13 126.67,155.13 127.23,154.57 132.27,154.57 132.37,154.47 138.39,154.47 138.93,155.01 143.87,155.01 144.13,155.27 v4(144.76,155.27)
  L4 w0.216: v4(151.54,155.96) 150.86,155.27 v4(144.76,155.27)
  BOTTOM w0.165: v4(144.76,155.27) 144.13,155.27 143.97,155.12 v2(143.95,155.12)
M_SBS_A0: length 70.6
  TOP w0.102: CPU1.AH32 95,160.5 95.64,160.5 95.64,160.49 96.16,160.49 96.29,160.62 97.49,160.62 97.61,160.74
  TOP w0.165: v4(142.53,155.96) 143.04,156.47 144.99,156.47 145.71,155.75 DIMM2.109 ; v3(98.27,160.74) 97.61,160.74 ; v4(134.78,155.83) 134.29,155.34 133.05,155.34 132.64,155.75 DIMM1.109
  L3 w0.216: v3(98.27,160.74) 98.77,161.25 100,161.25 100.17,161.08 103.21,161.08 108.74,155.55 126.97,155.55 127.19,155.33 127.19,155.2 127.4,154.99 127.83,154.99 128.05,155.2 128.05,155.33 128.27,155.55 128.7,155.55 128.91,155.33 128.91,155.2 129.13,154.99 129.56,154.99 129.78,155.2 129.78,155.33 129.99,155.55 130.43,155.55 130.64,155.33 130.64,155.2 130.86,154.99 131.29,154.99 131.5,155.2 131.5,155.33 131.72,155.55 132.21,155.55 132.87,154.89 138.22,154.89 138.76,155.44 142.01,155.44 v4(142.53,155.96)
  L4 w0.216: v4(142.53,155.96) 142.01,156.47 135.42,156.47 v4(134.78,155.83)
  BOTTOM w0.165: v4(134.78,155.83) 135.59,155.83 v2(135.62,155.8)
M_SBS_A1: length 72.2
  TOP w0.102: 98.59,161.42 98.54,161.38 97.6,161.38 97.26,161.04 96.09,161.04 96.06,161 CPU1.AG33
  TOP w0.165: v4(153.07,155.96) 153.16,156.05 DIMM2.108 ; v4(143.29,155.96) 142.6,155.27 140.85,155.27 140.07,156.05 DIMM1.108 ; v3(98.97,161.8) 98.59,161.42
  L3 w0.216: v3(98.97,161.8) 99.38,162.21 100.01,162.21 100.01,162.21 100.41,162.21 100.42,162.21 101.27,162.21 101.55,161.92 103.56,161.92 108.08,157.4 108.11,157.4 108.29,157.22 119.19,157.22 119.94,156.47 120.36,156.47 120.58,156.69 120.58,157 120.79,157.22 121.23,157.22 121.44,157 121.44,156.69 121.66,156.47 122.09,156.47 122.3,156.69 122.3,157 122.52,157.22 122.95,157.22 123.17,157 123.17,156.69 123.38,156.47 123.82,156.47 124.03,156.69 124.03,157 124.25,157.22 124.68,157.22 124.9,157 124.9,156.69 125.11,156.47 125.54,156.47 125.76,156.69 125.76,157 125.98,157.22 126.41,157.22 126.62,157 126.62,156.69 126.84,156.47 142.74,156.47 142.75,156.46 142.78,156.46 v4(143.29,155.96)
  L4 w0.216: v4(143.29,155.96) 144.49,154.76 151.87,154.76 v4(153.07,155.96)
  BOTTOM w0.165: v2(143.29,156.82) v4(143.29,155.96)
M_SBS_A2: length 71
  TOP w0.102: CPU1.W31 94.66,167.4 94.96,167.7 95.24,167.7 95.25,167.69 95.77,167.69 95.81,167.74 96.68,167.74 97.82,168.88 97.82,169.42
  TOP w0.165: v4(142.4,165.1) 142.89,165.59 144.89,165.59 145.73,164.75 DIMM2.79 ; v4(133.26,164.85) 133.16,164.75 DIMM1.79 ; v3(99.3,171.52) 99.3,170.9 97.82,169.42
  L3 w0.216: v3(99.3,171.52) 100.08,172.3 122.62,172.3 125.99,168.94 129.46,168.94 130.5,167.89 138.63,167.89 140.91,165.61 141.89,165.61 v4(142.4,165.1)
  L4 w0.216: v4(142.4,165.1) 141.63,164.33 133.77,164.33 v4(133.26,164.85)
  BOTTOM w0.165: v4(133.26,164.85) 133.08,165.02 132.49,165.02 v2(132.47,165.05)
M_SCKE_A0: length 71.8
  TOP w0.102: 97.02,170.18 97.02,169.87 96.47,169.32 96.42,169.32 96.42,169.32 95.76,169.32 95.45,169 CPU1.U32
  TOP w0.165: DIMM1.73 133.08,166.55 v4(134.78,164.85) ; DIMM2.73 145.83,166.55 144.89,167.49 143.65,167.49 v4(143.16,167) ; 97.02,170.18 97.02,171.28 97.73,171.99 v4(97.73,172.12)
  L3 w0.216: v4(97.73,172.12) 98.13,172.12 99.58,173.57 123.24,173.57 126.61,170.2 129.98,170.2 131.03,169.16 139.16,169.16 141.31,167 v4(143.16,167)
  L4 w0.216: v4(134.78,164.85) 135.55,165.61 141.77,165.61 v4(143.16,167)
  BOTTOM w0.165: v2(135.62,164.87) 135.59,164.85 v4(134.78,164.85)
M_SCKE_A1: length 72.1
  TOP w0.102: 97.29,170.18 97.29,169.85 96.5,169.06 96.15,169.06 96.08,169 CPU1.U33
  TOP w0.165: DIMM1.74 143.93,166.25 v4(144.69,167) ; 97.29,170.18 97.29,171.02 98.56,172.29 v4(98.56,173.26) ; DIMM2.74 153.82,166.25 v4(153.07,167)
  L3 w0.216: v4(98.56,173.26) 99.29,173.99 123.53,173.99 126.84,170.68 130.1,170.68 131.2,169.58 139.33,169.58 141.39,167.52 144.17,167.52 v4(144.69,167)
  L4 w0.216: v4(153.07,167) 152.55,166.49 145.2,166.49 v4(144.69,167)
  BOTTOM w0.165: v2(145.52,166.93) 145.45,167 v4(144.69,167)
M_SCS_A_N0: length 58.5
  TOP w0.102: CPU1.AJ33 96.23,159.4 96.25,159.38 97.16,159.38 97.19,159.35
  TOP w0.165: DIMM1.114 140.11,154.25 140.8,153.56 142.04,153.56 v4(142.53,154.05) ; 97.19,159.35 97.92,159.35 v3(98.08,159.51)
  L3 w0.216: v3(98.08,159.51) 98.08,159.49 98.68,158.88 99.85,158.88 99.86,158.87 102.8,158.87 102.82,158.86 103.05,158.86 108.04,153.86 117.04,153.86 117.36,153.54 117.36,152.88 117.67,152.57 118.21,152.57 118.42,152.78 118.42,153.45 118.64,153.67 119.07,153.67 119.29,153.45 119.29,152.78 119.5,152.57 119.93,152.57 120.15,152.78 120.15,153.45 120.37,153.67 120.8,153.67 121.01,153.45 121.01,152.78 121.23,152.57 138.53,152.57 139.5,153.54 140.2,153.54 142.01,153.54 v4(142.53,154.05)
  BOTTOM w0.165: v4(142.53,154.05) 142.53,154.86 v2(142.5,154.89)
M_SCS_A_N1: length 64.8
  TOP w0.102: 98.1,157.46 98.06,157.49 95.76,157.49 95.45,157.8 CPU1.AL32
  TOP w0.165: DIMM1.121 133.13,152.15 v4(135.8,149.48) ; v3(99.22,156.34) 98.1,157.46
  L3 w0.216: v3(99.22,156.34) 100.1,155.46 102.18,155.46 108.68,148.96 109.18,148.96 109.4,148.75 109.4,148.67 109.61,148.46 110.05,148.46 110.26,148.67 110.26,148.75 110.48,148.96 110.91,148.96 111.13,148.75 111.13,148.67 111.34,148.46 111.77,148.46 111.99,148.67 111.99,148.75 112.21,148.96 112.64,148.96 112.85,148.75 112.85,148.67 113.07,148.46 113.5,148.46 113.72,148.67 113.72,148.75 113.93,148.96 114.36,148.96 114.58,148.75 114.58,148.67 114.8,148.46 115.23,148.46 115.44,148.67 115.44,148.75 115.66,148.96 116.09,148.96 116.31,148.75 116.31,148.67 116.52,148.46 116.96,148.46 117.17,148.67 117.17,148.75 117.39,148.96 117.82,148.96 118.03,148.75 118.03,148.67 118.25,148.46 118.68,148.46 118.9,148.67 118.9,148.75 119.11,148.96 119.55,148.96 119.76,148.75 119.76,148.67 119.98,148.46 120.41,148.46 121.47,149.52 122.08,149.52 122.3,149.3 122.3,148.58 122.48,148.4 122.98,148.4 123.16,148.58 123.16,149.3 123.38,149.52 123.81,149.52 124.03,149.3 124.03,148.54 124.16,148.4 124.75,148.4 124.89,148.54 124.89,149.3 125.11,149.52 125.54,149.52 125.75,149.3 125.75,148.54 125.89,148.4 126.48,148.4 126.62,148.54 126.62,149.3 126.83,149.52 127.26,149.52 127.48,149.3 127.48,148.64 127.66,148.46 128.17,148.46 128.34,148.64 128.34,149.3 128.56,149.52 128.99,149.52 129.21,149.3 129.21,148.64 129.39,148.46 129.89,148.46 130.07,148.64 130.07,149.3 130.29,149.52 130.72,149.52 130.93,149.3 130.93,149.18 131.15,148.96 135.25,148.96 135.76,149.48 v4(135.8,149.48)
  BOTTOM w0.165: v4(135.8,149.48) 135.8,147.96 v2(135.97,147.78)
M_SCS_B_N0: length 69.5
  TOP w0.165: v3(93.02,159.64) 93.26,159.4 CPU1.AJ30 ; DIMM2.114 153.27,154.25 v4(153.07,154.05)
  L3 w0.216: v4(153.07,154.05) 152.26,153.24 146.67,153.24 144.79,151.36 143.08,151.36 142.5,150.79 140.43,150.79 139.68,150.04 131.79,150.04 131.78,150.03 121.13,150.03 120.63,149.52 119.38,149.52 119.38,149.52 117.63,149.52 108.8,149.52 105.3,153.03 102.44,155.88 100.33,155.88 99.41,156.8 99.03,156.8 98.61,156.38 97.17,156.38 96.68,156.88 96.68,157.04 94.08,159.64 v3(93.02,159.64)
  BOTTOM w0.165: v3(93.02,159.64) v2(93.02,158.9)
M_SCS_B_N1: length 63.3
  TOP w0.165: DIMM2.121 145.5,152.15 145.02,152.63 143.02,152.63 v4(142.53,152.15) ; CPU1.AL33 95.97,157.73 100.75,157.73 v3(101.38,157.1) 102.17,157.1 v1(102.22,157.15)
  L3 w0.216: v3(101.38,157.1) 101.57,157.1 101.94,156.72 102.79,156.72 106.14,153.38 107.37,152.14 108.17,152.14 108.38,151.93 108.38,151.23 108.56,151.05 109.07,151.05 109.25,151.23 109.25,151.93 109.46,152.14 109.9,152.14 110.11,151.93 110.11,150.57 110.29,150.39 110.8,150.39 110.97,150.57 110.97,151.93 111.19,152.14 111.58,152.14 111.83,151.89 111.83,150.71 112.18,150.37 113.28,150.37 113.5,150.58 113.5,151.28 113.67,151.46 114.18,151.46 114.36,151.28 114.36,150.58 114.58,150.37 116.35,150.37 116.56,150.58 116.56,150.66 116.78,150.87 117.21,150.87 117.43,150.66 117.43,150.58 117.64,150.37 118.07,150.37 118.29,150.58 118.29,150.66 118.5,150.87 131.43,150.87 131.44,150.88 139.33,150.88 140.08,151.63 140.68,151.63 142.01,151.63 v4(142.53,152.15)
M_WE_A_N: length 71.5
  TOP w0.102: CPU1.AJ31 94.65,159.4 94.95,159.7 95.26,159.7 95.27,159.69 95.75,159.69 95.76,159.7 96.24,159.7 96.35,159.59 97.54,159.59 97.87,159.92
  TOP w0.165: DIMM2.113 145.57,154.55 145.34,154.78 144.56,154.78 144.51,154.83 142.99,154.83 142.85,154.69 141.64,154.69 v4(141,154.05) ; DIMM1.113 132.12,154.55 v4(132.75,153.92) ; v1(101.94,159.36) v3(101.05,159.36) 100.46,159.95 97.9,159.95 97.87,159.92
  L3 w0.216: v4(141,154.05) 139.42,154.05 138.36,152.99 125.95,152.99 125.74,153.2 125.74,153.94 125.52,154.15 125.09,154.15 124.87,153.94 124.87,153.2 124.66,152.99 124.23,152.99 124.01,153.2 124.01,153.94 123.79,154.15 123.36,154.15 123.15,153.94 123.15,153.2 122.93,152.99 122.51,152.99 121.21,154.28 108.21,154.28 103.14,159.36 v3(101.05,159.36)
  L4 w0.216: v4(141,154.05) 140.19,154.86 133.68,154.86 v4(132.75,153.92)
MCLK: length 6.1
  TOP w0.102: U109.80 144.17,52.78 v4(144.28,52.88)
  BOTTOM w0.102: v4(144.28,52.88) 144.17,52.77 144.17,52.16 143.72,51.72 v2(143.72,51.44) 143.75,51.44 143.91,51.27 144.95,51.27 145.36,51.68 145.36,51.95 RN10.1
MCT_R: length 4.7
  BOTTOM w0.508: XF1.4 61.76,13.84 62.06,13.54 62.06,12.63 v4(62.19,12.5) 62.26,12.43 62.26,12.06 v2(62.64,11.68) ; v4(62.39,10.03) 60.99,10.03
MCT_R_1: length 7
  TOP w0.508: v4(66.35,13.23) 66.35,12.57 R79612.1
  BOTTOM w0.508: v4(66.35,13.23) 65.54,13.23 v2(65.44,13.34) 65.44,14.74 65.69,15 65.69,15.88 C3131.1
MDAT: length 4.4
  TOP w0.102: v4(145.04,52.96) 144.66,53.34 144.05,53.34 143.89,53.18 U109.79
  BOTTOM w0.102: v2(144.86,51.99) 144.86,52.24 145.04,52.43 v4(145.04,52.96) 145.3,53.22 RN10.2
MEM_MA_EVENT_L: length 109.8
  TOP w0.102: CPU1.AG30 93.83,161.33 94.68,161.33 94.86,161.51 95.34,161.51 95.35,161.5 95.67,161.5 95.67,161.51 96.16,161.51 96.22,161.44 96.71,161.44 v3(97.06,161.8) ; DIMM1.198 140.73,129.05 v4(140.88,128.91) ; DIMM2.198 153.09,129.05 v4(153.07,129.03)
  L3 w0.127: v4(153.07,129.03) 152.16,128.13 146.44,128.13 146.04,128.52 143.92,128.52 143.54,128.91 v4(140.88,128.91)
  BOTTOM w0.102: v4(153.07,129.03) 153.53,128.57 153.53,127.06 151.05,124.59 131.25,124.59 124.67,131.17 118.29,131.17 110.46,138.99 110.46,159.67 109.89,160.24 Q1207.E 107.03,160.95 v2(106.48,161.49) 105.27,160.27 98.08,160.27 97.32,161.04 R1584.2 96.49,161.23 v3(97.06,161.8)
MEM_MA_ZVDDIO: length 2.4
  TOP w0.203: v3(93.11,163.08) 92.7,163.49 CPU1.AD29
  BOTTOM w0.203: v2(92.36,163.08) v3(93.11,163.08) 93.5,162.69 R1696.1
MEM_MB_ZVDDIO: length 2.5
  TOP w0.203: CPU1.AF32 94.7,161.8 94.13,161.8 v3(94.13,161.8)
  BOTTOM w0.203: v2(92.72,161.04) R121.1 93.7,161.37 v3(94.13,161.8)
MEM_VREFCA_SUS: length 28.1
  TOP w0.254: v4(151.54,152.27) 153.04,150.65 DIMM2.126 ; v4(144.81,152.15) 143.99,151.32 140.96,151.32 140.29,150.65 DIMM1.126
  L4 w0.254: v4(151.54,152.27) 151.14,152.68 145.35,152.68 v4(144.81,152.15)
  BOTTOM w0.254: R2059.2 R2060.1 C1980.2 C1979.2 152.18,151.64 v4(151.54,152.27) ; C1746.2 R122.1 146.46,152.46 R120.2 145.18,152.98 v2(144.53,152.98) 144.53,152.43 v4(144.81,152.15) 145.64,151.32 C65.2
MIC2-L: length 4.3
  TOP w0.203: C139.1 169.48,80.16 167.19,80.16 v1(167.17,80.19) 167.14,80.16 166.66,80.16 166.53,80.03 U6.47
MIC2-L-1: length 3.4
  TOP w0.203: R225.1 171.76,81.53 v4(172.12,81.18) 172.12,80.77 171.74,80.39 C139.2
  BOTTOM w0.203: v2(171.66,81.99) 172.12,81.53 v4(172.12,81.18)
MIC2-R: length 3.8
  TOP w0.203: U6.48 165.62,80.75 166.35,81.48 v1(167.45,81.48) 167.47,81.46 167.85,81.46 C138.1
MIC2-R-1: length 13.9
  TOP w0.203: v4(169.58,81.36) 169.48,81.36 C138.2
  BOTTOM w0.203: R627.1 166.01,73.84 165.18,73.84 164.83,74.19 164.83,75.54 165.41,76.12 165.41,80.42 166.14,81.14 v2(166.14,81.15) 166.35,81.36 v4(169.58,81.36)
MIC2-VREFO-L: length 4.6
  TOP w0.203: R223.1 167.69,82.63 166.91,82.63 166.91,82.62 v1(166.79,82.62) 166.72,82.55 166.71,82.55 165.42,81.26 U6.1
MIC2-VREFO-R: length 3.5
  TOP w0.203: U6.30 v1(162.39,73.03) 162.39,71.89 R262.1
MIC-CAP: length 4.6
  TOP w0.203: U6.36 165.44,75.21 165.95,74.7 165.95,74.67
  TOP w0.254: 165.95,74.67 165.95,73.95 v1(166.19,73.71) 166.8,73.1 C154.1
MINI_POWER_CTRL: length 198.7
  TOP w0.102: RN8.4 147.68,62.13 148.06,61.76 U109.55 148.06,59.17 v4(148.19,59.03)
  L4 w0.127: v4(125.89,213.28) 131.13,213.28 142.92,201.49 154.3,201.49 162.76,193.04 162.76,188.4 161.81,187.45 161.81,155.88 161.1,155.18 161.1,125.1 161.8,124.4 161.8,122.33 162.87,121.26 162.87,116.8 162.72,116.65 162.72,114.43 162.72,114.43 162.72,113.79 162.49,113.56 162.21,113.56 161.93,113.29 161.93,112.53 156.87,107.47 156.87,105.43 155.91,104.47 155.91,100.5 154.51,99.1 154.51,89.73 152.44,87.66 152.44,76.73 151.77,76.06 151.77,74.07 148.83,71.12 148.83,68.47 148.15,67.79 148.15,60.03 148.19,59.99 v4(148.19,59.03)
  BOTTOM w0.102: R15.1 129.26,212.15 127.67,213.74 v2(126.65,213.74) 126.35,213.74 v4(125.89,213.28)
MODEL_ID_DET: length 5.9
  TOP w0.102: v4(109.06,56.58) R79723.2 R79722.1
  BOTTOM w0.102: v4(109.06,56.58) 109.06,57.47 v2(108.49,58.04) 107.53,57.08 U4101.50
MPCIE_DISABLE_N: length 202.4
  TOP w0.102: v4(148.27,58.27) 148.19,58.27 147.66,58.8 U109.56 147.66,61.7 147.03,62.33 RN8.3 ; R1620.1 v4(123.32,218.44)
  L4 w0.127: v4(148.27,58.27) 148.27,58.34 148.66,58.74 148.66,65.41 149.09,65.85 149.09,71.03 152.02,73.96 152.02,75.95 152.69,76.63 152.69,87.55 154.76,89.62 154.76,92.89 154.95,93.08 154.95,99.18 156.23,100.47 156.23,102.03 156.54,102.34 156.54,104.74 157.64,105.84 157.64,107.52 163.23,113.11 163.23,116.44 163.38,116.59 163.38,121.47 162.31,122.55 162.31,124.62 161.61,125.31 161.61,154.97 162.32,155.67 162.32,187.24 163.38,188.3 163.38,193.13 154.51,202 143.22,202 128,217.22 124.54,217.22 v4(123.32,218.44)
  BOTTOM w0.102: v4(148.27,58.27) 148.19,58.27 147.73,58.72 147.73,59.74 v2(147.93,59.94)
NB_VRM_PWRGD: length 139.5
  TOP w0.102: v4(30.72,222.81) 30.89,222.99 30.89,224.56 31.1,224.77 31.1,225.96 31.4,226.26 65.61,226.26 65.71,226.16 79.2,226.16 79.71,225.65 v1(79.71,225.63) 79.74,225.63 80.6,224.76 82.35,224.76 84.11,226.52 87.6,226.52 88.43,225.69 88.43,225.41 89.38,224.46 92.1,224.46 92.99,225.35 93.71,225.35 94.9,226.54 124.7,226.54 v4(133.56,217.68)
  L4 w0.127: v4(147.86,211.33) 145.61,209.08 140.27,209.08 133.56,215.79 v4(133.56,217.68)
  BOTTOM w0.102: R79674.1 150.85,210.82 149.13,210.82 148.62,211.33 v4(147.86,211.33) ; PU4601.8 30.79,221.28 30.8,221.3 30.8,221.7 30.7,221.81 30.7,222.28 30.65,222.33 30.65,222.74 v4(30.72,222.81) 30.65,222.81 PR4632.2
NC#7: length 3.1
  TOP w0.102: R90032.2 68.11,92.79 v1(68.23,92.91) 68.92,93.6 70.01,93.6
NGFF_ALERT#: length 230.3
  TOP w0.102: R1717.1 v4(123.32,221.49) ; R1749.1 87.66,144.87 v1(87.55,144.98) 87.55,145.73 85.96,147.32 v3(85.55,147.32) 85.55,147.38 85.15,147.79 85.15,148.33 85.1,148.37 85.1,148.4 CPU1.BB19
  L3 w0.127: v4(164.75,120.4) 163.72,119.36 135.29,119.36 121.19,133.46 93.63,133.46 87.76,139.33 87.76,140.5 86.46,141.81 86.46,146.88 86.01,147.32 v3(85.55,147.32)
  L4 w0.127: v4(164.75,120.4) 164.65,120.5 164.65,123.35 162.37,125.63 162.37,154.53 163.08,155.23 163.08,186.92 164.14,187.98 164.14,193.45 159.22,198.37 159,198.59 154.83,202.76 143.54,202.76 124.81,221.49 v4(123.32,221.49)
  BOTTOM w0.102: v4(164.75,120.4) 164.22,120.93 v2(164.14,120.93)
NGFF_ALERT_N: length 3.8
  TOP w0.102: R1717.2 121.52,221.49 120.65,220.62 v1(120.65,220.61) 120.12,220.61 119.52,220 NGFF1.62
NGFF_BT_DISABLE: length 317.8
  TOP w0.102: U109.125 155.66,46.18 155.77,46.29 155.77,46.67 155.76,46.68 155.76,47.98 155.42,48.32 155.42,48.82 155.35,48.88 155.35,49.22 v4(155.28,49.3) ; R1933.1 85.63,144.22 84.16,145.69 v3(83.8,145.69) ; R1621.1 v4(123.32,217.42)
  L3 w0.127: v3(83.8,145.69) 83.38,145.28 83.38,139.15 86.85,135.69 88.35,135.69 92.74,131.3 120.29,131.3 134.39,117.2 159.19,117.2 160.33,116.06 160.33,115.16 v4(162.4,113.09) 164.74,110.75 164.74,109.72 164.9,109.55 164.9,97.84 164.22,97.16 161.92,97.16 157.11,92.34 157.11,84.27 157.42,83.95 157.42,83.12 157.56,82.98 157.56,82.65 156.19,81.28 156.19,80.07 156.08,79.96 156.08,76.24 158.15,74.17 158.15,73.79 158.87,73.06 158.93,73.06 159.2,72.79 159.2,72.38 161.45,70.13 161.45,69.72 163.74,67.44 163.74,64.39 165.13,62.99 165.13,59.28 164.23,58.38 163.72,58.38 161.39,56.05 161.39,52.97 159.58,51.17 159.58,51.17 159.31,50.89 159.31,50.89 157.97,49.56 157.39,49.56 157.2,49.75 156.81,49.75 156.47,49.4 155.48,49.4 155.37,49.3 v4(155.28,49.3)
  L4 w0.127: v4(162.4,113.09) 162.98,113.67 162.98,116.54 163.12,116.69 163.12,121.37 162.05,122.44 162.05,124.51 161.36,125.2 161.36,155.07 162.06,155.78 162.06,187.34 163.12,188.4 163.12,193.03 154.41,201.74 143.03,201.74 128.13,216.64 124.11,216.64 v4(123.32,217.42)
  BOTTOM w0.102: v4(162.4,113.09) 162.84,112.65 162.85,112.65 v2(162.97,112.52)
NGFF_CLKREQ0_N: length 6.6
  TOP w0.102: R1931.1 105.72,219.2 106.84,218.08 v1(107.55,218.08) 107.87,217.75 NGFF1.53
NGFF_CLKREQ0_NGFF#: length 6.9
  TOP w0.102: Q1229.S 101.98,221.55 R1932.2 101,219.66 v1(101.71,218.95) 101.71,218.92 101.99,218.64 103.17,218.64 R1931.2
NGFF_CLKREQ1_APU#: length 252.7
  TOP w0.102: v3(84.26,146.5) 84.25,146.51 84.25,146.58 83.9,146.94 83.54,146.94 83.19,147.29 83.19,147.86 83.3,147.97 83.3,148.23 83,148.53 CPU1.BB17 ; Q1229.D v4(104.36,222.1)
  L3 w0.127: v3(84.26,146.5) 84.26,145.91 84.22,145.87 84.22,144.79 83.64,144.21 83.64,139.26 86.96,135.94 88.45,135.94 92.84,131.55 120.39,131.55 134.49,117.45 159.29,117.45 160.58,116.16 160.58,115.4 161.93,114.05 v4(162.25,114.05)
  L4 w0.127: v4(162.25,114.05) 162.47,114.27 162.47,116.75 162.62,116.9 162.62,121.16 161.54,122.23 161.54,124.3 160.85,124.99 160.85,155.28 161.55,155.99 161.55,187.55 162.5,188.5 162.5,192.93 154.2,201.24 136.96,201.24 122.1,216.1 118.64,216.1 116.55,218.19 108.1,218.19 104.36,221.92 v4(104.36,222.1)
  BOTTOM w0.102: v4(162.25,114.05) v2(163.09,114.05)
NGFF_CLKREQ1_N: length 4.5
  TOP w0.102: R1925.2 v4(120.82,221.68) 120.63,221.5 NGFF1.68
  BOTTOM w0.102: v4(120.82,221.68) 120.18,221.68 v2(120,221.87)
NGFF_CLKREQ1_N_TP: length 1.2
  TOP w0.102: R1925.1 TP208.1
NGFF_DETECT_PCIE: length 248.7
  TOP w0.102: R1155.2 v4(102.93,218.19) ; CPU1.BA19 84.3,149.4 84.3,148.74 84.31,148.73 84.31,148.27 84.3,148.26 84.3,147.97 84.94,147.33 84.94,146.66 v3(85.55,146.05) 85.96,146.05 86.65,145.36 R1926.1
  L3 w0.127: v3(85.55,146.05) 85.81,146.05 86,145.86 86,144.97 85.44,144.41 85.44,144.03 85.04,143.63 85.04,141.16 86.75,139.45 86.75,138.91 93.21,132.45 120.77,132.45 134.86,118.35 159.31,118.35 159.37,118.29 161.36,116.29 v4(161.36,115.73)
  L4 w0.127: v4(102.93,218.19) 105.38,218.19 106.14,217.42 116.24,217.42 119.69,213.97 121.8,213.97 124.28,211.5 125.62,211.5 136.64,200.47 153.88,200.47 160.79,193.56 160.79,156.3 160.09,155.6 160.09,121.99 160.78,121.29 160.78,117.29 161.36,116.72 v4(161.36,115.73)
  BOTTOM w0.102: v2(162.21,115.73) 161.45,115.73 v4(161.36,115.73)
NGFF_DETECT_PCIE_C: length 7.4
  TOP w0.102: NGFF1.51 106.73,217.25 v1(105.75,218.24) 104.67,218.24 R1155.1 R1709.1
NGFF_DETECT_USB: length 221.5
  TOP w0.102: U109.126 156.06,49.18 155.24,50 155.24,50.97 156.14,51.87 156.14,52.1 156.88,52.83 v4(156.9,52.83) ; R1154.2 v4(106.27,202.77)
  L3 w0.127: v4(153.28,101.83) 152.09,100.64 152.09,86.57 153.42,85.24 153.42,81.07 153.41,81.06 153.41,75.13 153.42,75.12 153.42,73.45 v4(155.38,71.49)
  L4 w0.127: v4(153.28,101.83) 153.37,101.92 153.37,105.52 154.33,106.48 154.33,108.52 158.72,112.91 158.72,124.58 159.2,125.06 159.2,155.97 159.9,156.67 159.9,192.52 158.42,194.01 157.49,194.01 153.23,198.26 110.77,198.26 v4(106.27,202.77)
  BOTTOM w0.102: v2(152.47,101.86) 152.56,101.86 152.59,101.83 v4(153.28,101.83) ; v4(155.38,71.49) 155.38,64.77 159.24,60.91 159.24,57.41 156.34,54.51 156.34,53.39 v4(156.9,52.83) 157.13,52.6 158.55,52.6 160.56,54.61 R1935.2
NGFF_DETECT_USB_C: length 4.9
  TOP w0.102: NGFF1.1 109.69,204.75 108.52,203.58 v1(108.36,203.58) R1154.1 R1209.1
NGFF_PCIE0_RXN: length 7.1
  TOP w0.102: NGFF1.43 109.5,215.25 109.36,215.11 107.06,215.11 106.17,214.21 ; v1(105.92,214.45) 106.17,214.21 ; 106.17,214.21 105.68,213.72 105.02,213.72 R1712.1
NGFF_PCIE0_RXP: length 7.1
  TOP w0.102: R1711.1 105.02,213.51 105.77,213.51 107.15,214.89 107.91,214.89 ; v1(107.91,214.53) 107.91,214.89 ; 107.91,214.89 109.36,214.89 109.5,214.75 NGFF1.41
NGFF_PCIE0_TXN: length 7.3
  TOP w0.102: R1714.1 105.02,211.69 105.51,211.69 106.14,212.33 ; 106.14,212.33 106.84,213.03 108.28,213.03 108.86,213.61 109.36,213.61 109.5,213.75 NGFF1.37 ; 106.14,212.33 v1(105.9,212.57)
NGFF_PCIE0_TXP: length 7.3
  TOP w0.102: R1713.1 105.02,211.47 105.6,211.47 106.93,212.81 107.81,212.81 ; 107.81,212.81 v1(107.81,212.45) ; 107.81,212.81 108.37,212.81 108.95,213.39 109.36,213.39 109.5,213.25 NGFF1.35
NGFF_PCIE1_RXN: length 5.1
  TOP w0.102: TP82.1 106.84,222.12 106.69,221.98 106.69,221.63 106.91,221.42 108.18,221.42 108.49,221.11 109.36,221.11 109.5,221.25 NGFF1.67
NGFF_PCIE1_RXP: length 5.5
  TOP w0.102: NGFF1.65 109.5,220.75 109.36,220.89 108.4,220.89 108.09,221.21 106.82,221.21 106.75,221.27 106.48,221.54 106.48,222 106.35,222.12 TP81.1
NGFF_PCIE1_TXN: length 5.1
  TOP w0.102: TP80.1 106.82,220.47 106.69,220.34 106.69,219.84 106.93,219.61 109.36,219.61 109.5,219.75 NGFF1.61
NGFF_PCIE1_TXP: length 5.5
  TOP w0.102: NGFF1.59 109.5,219.25 109.36,219.39 106.84,219.39 106.48,219.75 106.48,220.34 106.35,220.47 TP79.1
NGFF_PEWAKE0_N: length 31.3
  TOP w0.102: R1719.1 105.39,220.22 106.85,218.75 v4(108.2,218.75) 108.7,218.25 NGFF1.55 ; R1718.2 v4(120.59,222.47) 120.12,222 NGFF1.70
  L4 w0.127: v4(108.2,218.75) 108.2,223.74 109.63,225.17 119.03,225.17 120.59,223.62 v4(120.59,222.47)
  BOTTOM w0.102: v2(121.47,222.47) v4(120.59,222.47)
NGFF_POWER_CTRL_1: length 2.9
  BOTTOM w0.102: v2(131.48,214.3) R15.2 131.38,212.95 Q3.G
NGFF_POWER_CTRL_V2: length 6.6
  TOP w0.102: C864.1 R1716.1 129.56,217.56 129.8,217.32 131.1,217.32 v4(131.3,217.53)
  BOTTOM w0.102: v2(129.95,217.91) 129.89,217.84 Q128.B 130.68,216.63 131.3,217.25 v4(131.3,217.53)
NGFF_REFCLKN0: length 6.9
  TOP w0.102: R23.1 105.02,215.75 105.8,215.75 106.13,216.08 ; 106.13,216.08 106.66,216.61 109.36,216.61 109.5,216.75 NGFF1.49 ; 106.13,216.08 v1(105.87,216.33)
NGFF_REFCLKN1: length 5.2
  TOP w0.102: NGFF1.73 109.5,222.75 109.36,222.61 108.87,222.61 108.35,223.13 106.83,223.13 106.69,223.27 106.69,223.63 106.84,223.77 TP84.1
NGFF_REFCLKP0: length 6.9
  TOP w0.102: v1(107.54,216.03) 107.54,216.39 ; 107.54,216.39 109.36,216.39 109.5,216.25 NGFF1.47 ; 107.54,216.39 106.75,216.39 105.89,215.54 105.02,215.54 R22.1
NGFF_REFCLKP1: length 5.5
  TOP w0.102: TP83.1 106.35,223.77 106.48,223.65 106.48,223.18 106.74,222.91 108.26,222.91 108.78,222.39 109.36,222.39 109.5,222.25 NGFF1.71
NGFF_W_DISABLE1_N: length 4.1
  TOP w0.102: R1620.2 121.58,218.5 v4(120.2,218.5) NGFF1.56
  BOTTOM w0.102: v4(120.2,218.5) v2(119.39,218.5)
NGFF_W_DISABLE2_N: length 3.5
  TOP w0.102: R1621.2 121.1,217.42 120.79,217.73 v1(120.68,217.73) 120.68,217.77 120.45,218 NGFF1.54
OGPIO0: length 9.5
  TOP w0.076: U902.B9 74.81,104.26 75.06,104.51 75.06,104.9 75.19,105.03
  TOP w0.102: 75.19,105.03 75.86,105.7 v3(75.86,106.43)
  BOTTOM w0.102: R90047.2 R90048.1 80.23,106.36 79.92,106.68 v2(79.03,106.68) 76.11,106.68 v3(75.86,106.43)
OGPIO1: length 13.5
  TOP w0.076: 75.98,104.65 75.69,104.36 75.41,104.36 75.2,104.36 75.06,104.22 75.06,104.01 74.91,103.86 74.56,103.86 U902.C8
  TOP w0.102: 75.98,104.65 77.12,105.79 77.12,106.17 79.66,108.71 82.66,108.71 v1(82.89,108.48) 82.96,108.48 83.26,108.78 R90073.1 R90074.2
OGPIO2: length 7.5
  TOP w0.076: 74.6,105.27 74.56,105.23 74.56,104.59 74.56,104.36 U902.B8
  TOP w0.102: R90075.2 R90050.1 v1(73.95,108.84) 73.95,108.41 74.38,107.98 74.38,106.73 74.73,106.38 74.73,105.41 74.6,105.27
OGPIO3: length 7.5
  TOP w0.102: R90054.1 R90051.2 72.36,109.22 v1(72.36,108.53) 72.36,108.19 74.31,106.24 U902.A8
OGPIO4: length 11.6
  TOP w0.076: U902.C7 73.56,103.86 73.56,104.22 73.41,104.36 73.2,104.36 73.06,104.51 73.06,104.77 73.06,104.78
  TOP w0.102: 73.06,104.78 73.06,106.03 71.77,107.31 69.69,107.31 v1(68.67,108.34) R90052.1 R90055.2
OGPIO5: length 9.2
  TOP w0.076: U902.B7 73.81,104.26 73.56,104.51 73.56,104.77 73.36,104.98 73.36,105.09
  TOP w0.102: 73.36,105.09 73.36,106.05 71.08,108.33 v1(70.42,108.33) 69.38,109.37 R90056.2 R90053.1
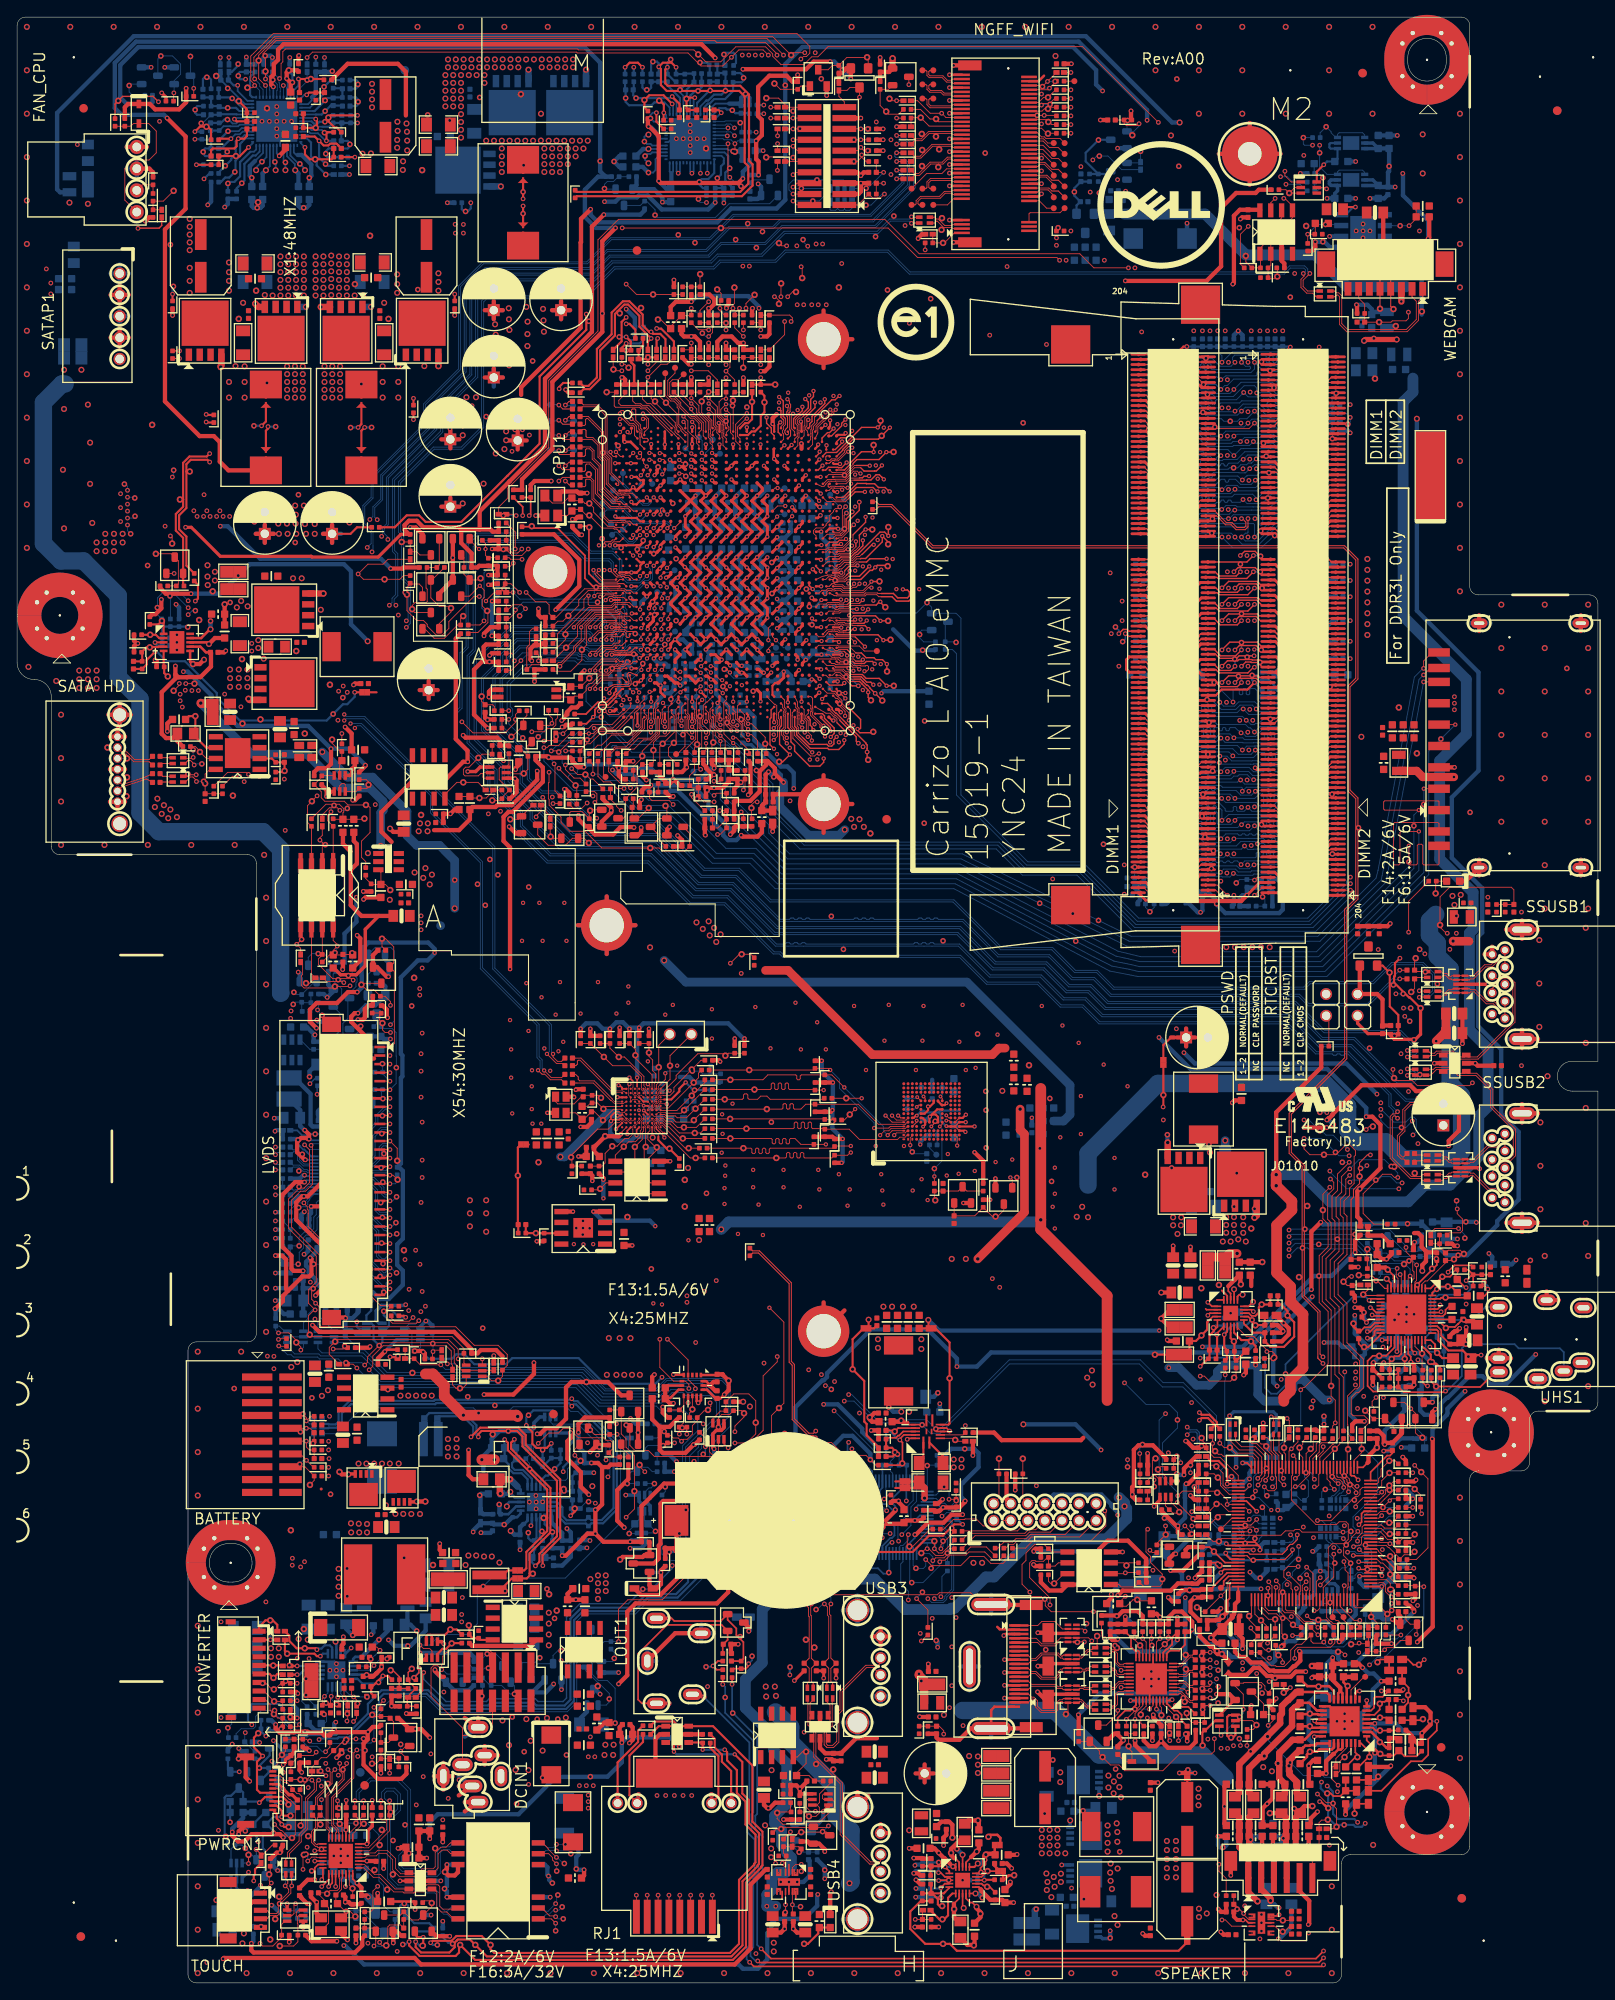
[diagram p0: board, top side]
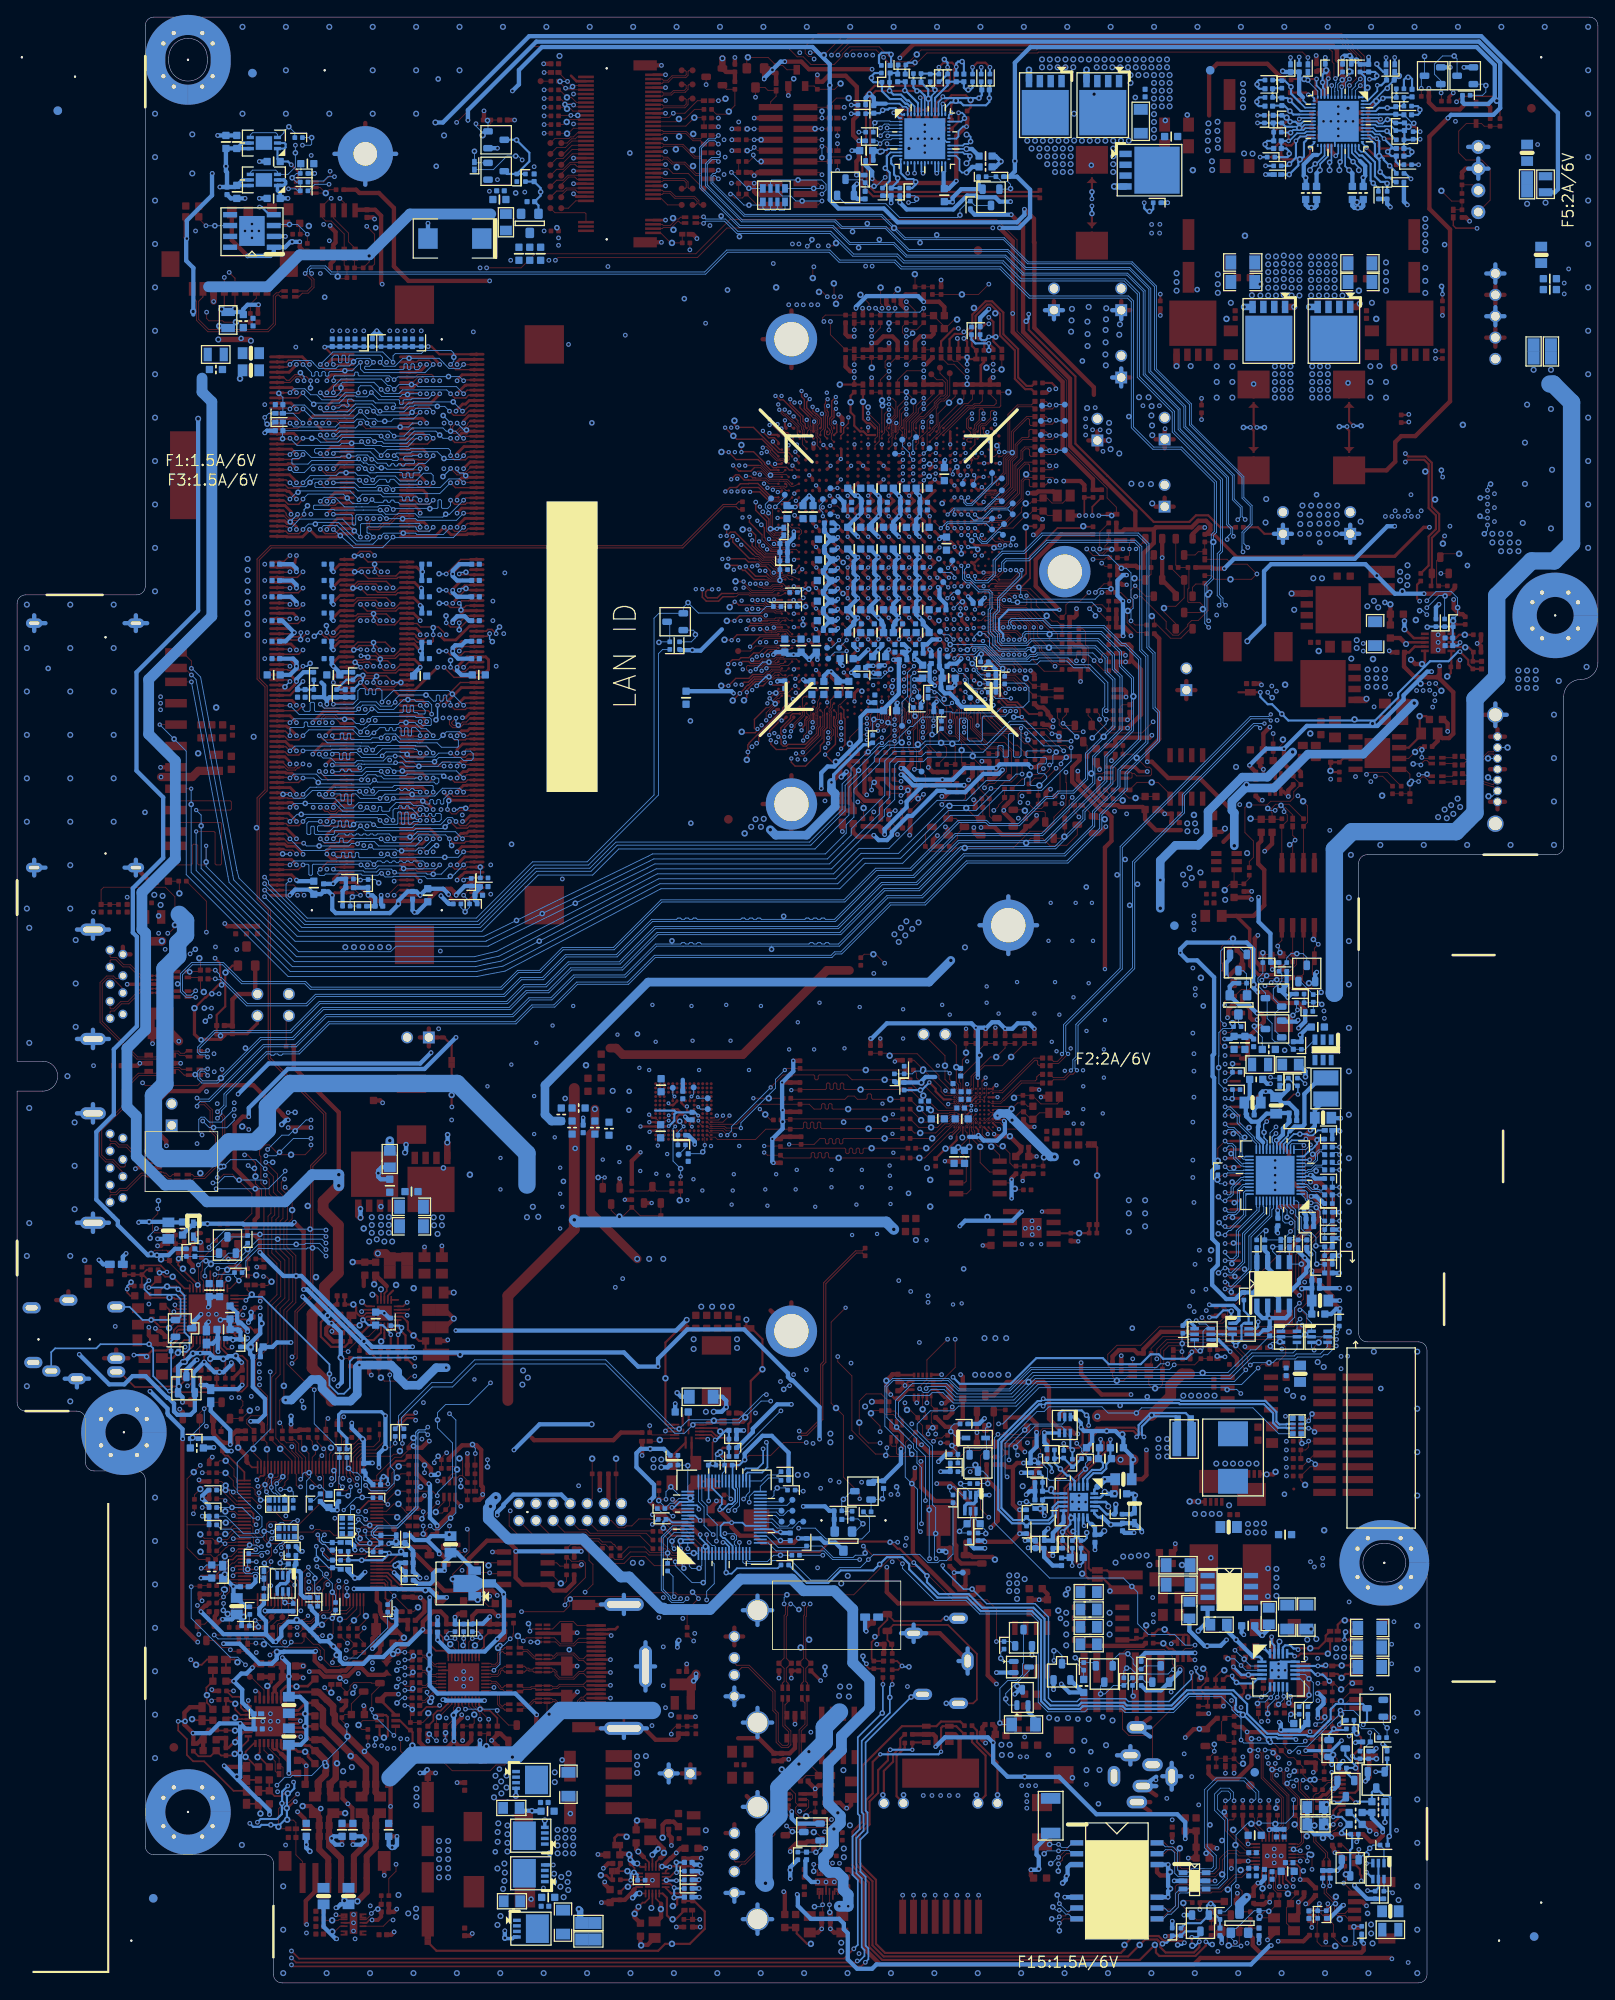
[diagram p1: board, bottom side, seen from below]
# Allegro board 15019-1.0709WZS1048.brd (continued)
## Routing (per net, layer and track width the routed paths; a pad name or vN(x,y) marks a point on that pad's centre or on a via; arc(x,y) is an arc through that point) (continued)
OSD_BIST_N: length 70
  TOP w0.102: R744.2 35.62,24.77 v4(36.14,24.25) ; v4(46.34,77.85) 46.32,77.85 45.89,77.42 44.18,77.42 43.78,77.81 R535.1
  L4 w0.127: v4(46.34,77.85) 46.32,77.85 45.83,77.36 45.83,74.74 41.57,70.48 41.21,70.48 39.28,68.55 39.28,68.19 36.72,65.63 36.25,65.63 34.58,63.96 34.58,56.85 37.38,54.04 37.38,51.55 37.7,51.23 37.7,50.02 38.51,49.2 38.51,41.19 39.03,40.67 39.03,40.03 38.56,39.56 38.56,37.57 39.01,37.12 39.01,34.63 39.89,33.75 39.89,31.16 40.34,30.71 40.34,29.67 40.33,29.66 40.33,29.06 40.34,29.05 40.34,26.31 37.87,23.84 36.55,23.84 v4(36.14,24.25)
  BOTTOM w0.102: v2(35.53,24.78) 36.06,24.25 v4(36.14,24.25)
OSD_BIST_N_1: length 6.7
  TOP w0.254: v4(45.47,77.88) 45.44,77.88 45.26,78.05 R535.2
  BOTTOM w0.254: v4(45.47,77.88) 44.66,77.88 43.85,78.68 43,78.68 v2(42.91,78.59) 42.91,78.13 43.52,77.52 43.52,76.86 43.19,76.53 Q12.2
OSD_DN: length 191.7
  TOP w0.102: v3(73.8,157.18) 73.8,157.5 CPU1.AL6 ; v4(35,27) 35,26.99 35,26.96 34.64,26.61 R1758.1 32.16,25.72 C238.1 R1755.1
  L3 w0.127: v3(73.8,157.18) 73.08,157.9 70.1,157.9 69.82,158.18 66.23,158.18 66.2,158.16 65.93,158.16 65.68,157.9 64.63,157.9 64.44,158.09 58.43,158.09 57.63,158.89 52.8,158.89 50.03,161.66 43.33,161.66 42.96,161.29 42.96,160.96 44.41,159.51 44.41,152.97 43.15,151.7 40.36,151.7 39.71,152.35 39.15,152.35 38.64,151.84 v4(38.64,151)
  L4 w0.127: v4(35,27) 35,27.01 35,28.15 34.87,28.28 34.87,28.34 34.35,28.87 33.48,28.87 31.67,30.68 31.67,42.53 34.36,45.22 34.36,49.93 34.1,50.19 34.1,52.59 30.18,56.51 30.18,65.99 37.83,73.64 37.83,78.18 40.89,81.25 40.89,122.39 38.53,124.75 38.53,134.41 38.77,134.65 38.77,138.71 37.21,140.27 37.21,145.16 36.61,145.76 36.61,147.7 38.64,149.73 v4(38.64,151)
  BOTTOM w0.102: v4(38.64,151) 38.64,150.88 38.14,150.38 v2(38.12,150.38)
OSD_DN_R: length 3.5
  TOP w0.102: v1(33.17,23.79) 33.14,23.81 R1755.2 31.91,23.69 31.34,23.69 30.77,24.25 PWRCN1.2
OSD_MENU: length 301.9
  TOP w0.102: CPU1.AH1 70.41,160.11 67.71,160.11 66.45,158.85 66.45,157.31 65.36,156.22 65.36,155.86 v4(63.53,154.04) ; v4(34.25,28.3) 34.09,28.3 33.88,28.51 R755.1 C585.1 R758.1 ; v4(81.39,49.05) 82.08,49.73 82.77,49.73 84.49,48.02 84.49,48.01 87.08,45.42 107.69,45.42 107.92,45.64 111.6,45.64 112.03,45.22 119.88,45.22 120.33,44.78 120.33,44.13 121.03,43.43 v4(125.97,43.43)
  L3 w0.127: v4(149.13,42.85) 148.83,43.15 144.29,43.15 143.88,42.75 136.87,42.75 136.18,42.06 127.34,42.06 v4(125.97,43.43)
  L4 w0.127: v4(63.53,154.04) 62.57,153.07 54.74,153.07 54.01,152.34 54.01,148.3 52.19,146.48 52.04,146.48 51.73,146.17 51.73,128.92 48.18,125.37 48.18,122.53 45.88,120.23 45.88,83.63 46.9,82.62 46.9,80.64 47.35,80.19 48.21,80.19 48.88,79.52 48.88,76.08 42.27,69.47 41.63,69.47 41.32,69.16 41.32,69.14 40.29,68.11 40.29,67.73 36.54,63.98 36.04,63.98 35.59,63.54 35.59,57.71 38.46,54.84 38.46,52.53 40.14,50.86 40.14,41.01 40.38,40.76 40.38,38.05 40.14,37.81 40.14,34.94 40.9,34.17 40.9,31.76 41.54,31.13 41.54,30.61 41.97,30.18 41.97,28.63 v4(41.77,28.42)
  BOTTOM w0.102: v4(81.39,49.05) 81.39,48.5 79.49,46.61 79.49,46.61 77.64,44.75 73.95,44.75 72.36,43.17 66.36,43.17 65.5,42.3 65.5,32.83 64.39,31.72 60.04,31.72 59.72,32.04 55.75,32.04 55.35,31.64 49.66,31.64 47.81,33.5 44.08,33.5 42.83,32.26 42.83,31.95 42.25,31.37 42.2,31.37 41.77,30.94 v4(41.77,28.42) 41.77,28.4 41.44,28.07 38.46,28.07 38.37,28.16 v2(38.34,28.16) 38.2,28.02 34.53,28.02 v4(34.25,28.3) ; R80206.1 147.73,43.05 v2(148.12,42.67) 148.95,42.67 v4(149.13,42.85)
OSD_MENU_R: length 3.5
  TOP w0.102: PWRCN1.1 29.93,25.07 30.51,25.65 30.51,26.2 v1(30.99,26.68) 31.4,27.09 R758.2
OSD_MENU_SIO: length 11
  TOP w0.102: U109.109 149.26,45.96 149.09,46.13 149.09,46.79 148.82,47.06 148.68,47.06 148.24,47.5 148.24,48.22 148.74,48.72 v4(149.92,48.72)
  BOTTOM w0.102: R80206.2 147.73,45.34 v2(148.12,45.72) 148.12,46.74 148.77,47.39 148.97,47.39 149.24,47.65 149.24,48.04 v4(149.92,48.72)
OSD_UP: length 241.8
  TOP w0.102: v4(39.66,28.55) 38.62,28.55 v1(38.51,28.45) 38.32,28.45 C582.1 36.23,26.35 35.59,26.35 R742.2 34.51,25.27 R744.1 34.51,24.39 34.04,23.91 34.04,23.72 33.12,22.8 R743.1 ; CPU1.AJ3 71.33,159.4 71.03,159.7 70.77,159.7 70.77,159.69 70.23,159.69 70.23,159.7 68.16,159.7 v3(67.06,158.6)
  L3 w0.127: v4(45.83,78.66) 44.05,78.66 41.64,81.08 41.64,107.29 38.4,110.52 38.4,116.05 37.3,117.14 37.3,120.48 37.94,121.12 37.94,121.51 37.35,122.1 37.35,135.73 32.99,140.08 28.7,140.08 28.7,140.08 18.55,140.08 16.91,141.72 16.91,152.39 14.96,154.35 14.96,158.57 14.02,159.51 14.02,163.41 17.02,166.41 24.39,166.41 27.51,163.28 33.74,163.28 34.23,163.77 38.06,163.77 39.39,162.43 50.34,162.43 52.43,160.34 57.26,160.34 58.66,158.94 64.87,158.94 64.97,159.04 66.62,159.04 v3(67.06,158.6)
  L4 w0.127: v4(45.83,78.66) 45.22,78.66 43.64,77.09 43.64,75.31 42.1,73.76 42.1,71.78 37.08,66.76 36.37,66.76 35.42,65.81 35.42,65.16 34.12,63.86 33.66,63.86 33.38,63.59 33.38,63.2 34,62.58 34,61.93 33.67,61.61 33.67,61.61 33.4,61.33 33.4,60.94 34.21,60.13 34.21,56.86 37.13,53.94 37.13,51.44 37.45,51.13 37.45,49.91 38.26,49.1 38.26,41.09 38.78,40.57 38.78,40.17 38.26,39.65 38.26,37.45 38.76,36.96 38.76,31.86 39.86,30.75 39.86,28.75 v4(39.66,28.55)
  BOTTOM w0.102: v2(40.55,28.57) 40.52,28.55 v4(39.66,28.55)
OSD_UP_R: length 7.8
  TOP w0.102: v1(33.18,18.41) 33.32,18.55 33.32,21.83 33,22.15 32.75,22.15 32.29,22.61 R743.2 32.23,22.8 31.57,23.46 31.24,23.46 30.95,23.75 PWRCN1.3
OZ554_ENA: length 12.4
  TOP w0.102: R79625.1 42.58,32.74 v4(42.88,33.05) ; R79627.1 41.61,36.98 v4(41.77,37.13) 41.24,37.66 C3458.1
  L4 w0.127: v4(41.77,37.13) 41.77,36.14 42.73,35.18 42.73,33.2 v4(42.88,33.05)
  BOTTOM w0.102: U120.3 41.21,36.58 v4(41.77,37.13) 41.77,37.16 42.53,37.92 v2(43.3,37.92)
OZ554_PWM: length 8.7
  TOP w0.254: R79621.1 43.43,35.92 v4(42.81,35.92) 41.56,34.67 C8.1 41.44,34.63 41.44,33.9 R79623.1
  BOTTOM w0.254: U120.5 39.84,35.58 40.39,35.03 42.17,35.03 v2(42.3,35.16) 42.78,35.64 42.78,35.89 v4(42.81,35.92)
OZ554_VIN: length 6.7
  TOP w0.508: R5.2 42.67,37 v4(42.65,36.98) 42.65,36.8 42.06,36.21 42.03,36.21 41.69,35.86 C3457.1
  BOTTOM w0.305: U120.4 40.72,36.08 40.75,36.04 v2(40.9,36.04) 41.71,36.04 v4(42.65,36.98)
P_GFX_TXN0: length 10.3
  TOP w0.102: C1811.1 65.88,178.74 66.01,178.61 66.38,178.61 66.5,178.74 66.5,179.36 66.63,179.49 67,179.49 67.3,179.18 67.3,178.28 68.11,177.47 68.11,174.66 69.69,173.08 70.42,173.08 CPU1.M1
P_GFX_TXN1: length 10.7
  TOP w0.102: CPU1.L2 70.53,173.8 70.23,173.5 69.97,173.5 68.53,174.94 68.53,177.96 67.98,178.52 67.98,179.91 67.29,180.59 C1813.1
P_GFX_TXN2: length 13.7
  TOP w0.102: CPU1.L3 71.7,173.98 71.59,174.08 71.05,174.08 71.03,174.1 70.74,174.1 70.71,174.08 70.25,174.08 70.1,174.23 70.1,174.23 68.95,175.38 68.95,178.14 68.4,178.69 68.4,181.42 67.38,182.44 67.04,182.78 66.77,183.05 66.66,183.05 66.53,182.92 66.53,182.35 66.4,182.22 66.01,182.22 65.88,182.35 C1814.1
P_GFX_TXN3: length 12.7
  TOP w0.102: C122.1 66.3,184.63 67.93,184.63 69.04,183.51 69.04,178.95 69.59,178.4 69.59,176.68 70.87,175.4 CPU1.J2
P_GFX_TXP0: length 10.4
  TOP w0.102: C1809.1 67.09,179.71 67.52,179.27 67.52,178.37 68.33,177.56 68.33,174.75 69.78,173.29 70.31,173.29 70.32,173.3 70.63,173.3 70.93,173 CPU1.M2
P_GFX_TXP1: length 10.6
  TOP w0.102: CPU1.L1 69.98,173.8 68.75,175.03 68.75,178.05 68.19,178.61 68.19,180 67.38,180.81 66.71,180.81 66.58,180.94 66.58,181.64 66.45,181.76 66.16,181.76 C1810.1
P_GFX_TXP2: length 13.8
  TOP w0.102: CPU1.L4 72,174.3 71.14,174.3 71.11,174.32 70.65,174.32 70.63,174.3 70.34,174.3 70.32,174.32 70.32,174.32 69.17,175.47 69.17,178.23 68.61,178.78 68.61,181.51 66.86,183.26 C1812.1
P_GFX_TXP3: length 12.7
  TOP w0.102: CPU1.J1 70.1,175.31 70.2,175.21 70.34,175.21 70.42,175.29 70.42,175.55 69.37,176.59 69.37,178.31 68.82,178.86 68.82,183.42 67.84,184.41 66.14,184.41 C1815.1
P_RX_ZVDD: length 23.1
  TOP w0.203: v3(73.7,168) 74.1,168.4 CPU1.U6 ; R557.1 R2003.1 60.1,171.85 v4(59.93,171.68)
  L3 w0.203: v3(73.7,168) 73.7,167.15 73.09,166.54 69.05,166.54 67.55,168.05 67.55,169.54 66.49,170.6 61.01,170.6 v4(59.93,171.68)
  BOTTOM w0.203: v2(72.58,167.72) 72.8,167.94 73.64,167.94 v3(73.7,168)
P_TX_ZVDD: length 23.5
  TOP w0.203: R558.2 59.17,172.7 v4(59.17,171.68) ; v3(74.5,168) 74.9,168.4 CPU1.U7
  L3 w0.203: v4(59.17,171.68) 59.17,171.61 60.77,170.01 66.35,170.01 67.24,169.12 67.24,167.92 68.92,166.24 73.22,166.24 74.5,167.52 v3(74.5,168)
  BOTTOM w0.203: v3(74.5,168) v2(74.5,167.21)
PANEL_ON_1: length 4.3
  BOTTOM w0.102: R33.1 R39.1 33.37,114.68 R42.1 ; R42.1 32.57,114.74 v2(32.32,114.49) ; R42.1 33.31,113.73 R41.2
PANEL_ON_2: length 3.4
  BOTTOM w0.102: Q10.B 34.83,117.16 R42.2 32.68,115.63 32.42,115.9 v2(32.39,115.9)
PANEL_ON_3: length 17
  BOTTOM w0.102: v2(39.21,120.52) R20.2 39.21,118.13 39.78,117.56 39.78,117.13 39.66,117.01 39.66,116.56 38.91,115.81 Q5.D 38.7,115.01 38.7,112.84 38.13,112.27 38.13,110.44 37.78,110.08 37.71,110.08 37.55,110.08 37.53,110.06 36.48,110.06 C14.2 R19.1 34.26,109.23 33.13,110.36 U1.3
PANEL_ON_4: length 15
  BOTTOM w0.102: Q10.C 34.07,119.99 34.5,120.42 v2(35.24,120.42) 35.92,120.42 36.42,119.93 R26.2 37.31,118.49 R30.1 36.99,118.05 36.99,117.24 37.47,116.76 37.53,116.76 37.99,116.3 37.99,115.21 Q5.G 37.78,113.46 37.78,111.4 Q1.G
PANEL_ON_5: length 4.7
  BOTTOM w0.102: R8.1 39.28,110.64 40.22,111.58 v2(40.22,111.94) 40.06,112.09 39.39,112.09 Q1.D
PANEL_SEL1_CABLE: length 4.4
  TOP w0.102: CONVT1.7 29.02,35.15 29.83,34.34 v1(30.06,34.34) 30.18,34.34 30.89,35.05 R1730.2 R1734.2
PANEL_SEL1_CABLE_EC: length 143.7
  TOP w0.102: v4(146.39,46.18) 146.46,46.11 U109.102 ; R1730.1 v4(32.77,35.05)
  L3 w0.127: v4(32.77,35.05) 32.95,35.23 43.47,35.23 45.56,37.33 47.35,37.33 47.95,37.92 54.34,37.92 54.83,37.43 63.29,37.43 63.47,37.25 63.85,37.25 64.13,37.52 64.13,37.68 72.03,45.58 84.36,45.58 89.49,40.46 89.81,40.46 91.33,38.94 102.58,38.94 102.76,38.75 109.78,38.75 110.75,39.73 112.2,39.73 113.6,38.33 115.98,38.33 118.6,35.71 130.03,35.71 131.42,37.1 137.59,37.1 138.77,35.93 138.77,32.11 139.27,31.61 140.02,31.61 143.37,34.96 143.83,34.96 v4(145.06,36.2)
  L4 w0.127: v4(145.06,36.2) 145.06,41.01 147.48,43.42 147.48,44.85 146.48,45.85 146.48,46.09 v4(146.39,46.18)
  BOTTOM w0.102: v2(146.39,45.31) v4(146.39,46.18)
PANEL_SEL2_CABLE: length 4.3
  TOP w0.102: R1731.2 R287.2 31.01,32.94 v1(30.08,32.94) 28.88,34.15 CONVT1.8
PANEL_SEL2_CABLE_EC: length 148.2
  TOP w0.102: U109.103 146.86,46.44 146.48,46.82 v4(146.48,46.93) ; R287.1 v4(32.77,33.02)
  L3 w0.127: v4(32.77,33.02) 34.35,33.02 35.49,34.16 46.09,34.16 48.05,36.13 48.05,36.73 48.44,37.12 54,37.12 54.5,36.63 62.96,36.63 63.27,36.31 66.05,36.31 67.51,37.77 67.51,39.93 72.36,44.78 84.03,44.78 89.16,39.66 89.48,39.66 90.45,38.68 93.98,35.16 109.1,35.16 109.19,35.24 109.57,35.24 110.9,33.92 112.49,33.92 113.97,35.39 117.13,35.39 119.52,32.99 127.76,32.99 128.65,33.88 130.66,33.88 130.9,33.64 135.38,33.64 138.21,30.81 140.35,30.81 143.71,34.16 144.28,34.16 145.36,35.25 v4(146.52,35.25)
  L4 w0.127: v4(146.52,35.25) 146.52,35.4 145.44,36.48 145.44,40.85 147.86,43.27 147.86,45 146.86,46.01 146.86,46.56 v4(146.48,46.93)
  BOTTOM w0.102: v2(147.22,35.66) 147.2,35.66 146.79,35.25 v4(146.52,35.25)
PANEL_SEL3_CABLE: length 5.1
  TOP w0.102: R1732.2 R1733.2 30.51,30.99 v1(30.06,31.45) 29.6,31.9 29.6,32.59 29.04,33.15 CONVT1.9
PANEL_SEL3_CABLE_EC: length 149
  TOP w0.102: U109.104 147.26,46.21 v4(147.33,46.28) ; v4(33.05,30.23) 32.8,29.97 R1732.1
  L3 w0.127: v4(145.45,34.67) 144.56,33.78 143.86,33.78 140.51,30.43 134.68,30.43 134.31,30.79 134.31,32.26 133.69,32.88 131.81,32.88 131.43,32.5 128.56,32.5 128.28,32.22 119.07,32.22 117.32,33.97 113.62,33.97 112.81,33.15 109.81,33.15 108.57,34.39 93.67,34.39 89.16,38.89 88.84,38.89 83.71,44.02 72.67,44.02 68.27,39.61 68.27,37.45 66.37,35.55 48.77,35.55 46.44,33.22 45.78,33.22 42.53,29.97 34.13,29.97 33.97,30.14 33.14,30.14 v4(33.05,30.23)
  L4 w0.127: v4(147.33,46.28) 148.24,45.37 148.24,43.11 145.83,40.69 145.83,36.64 146.99,35.47 146.99,35.05 146.61,34.67 v4(145.45,34.67)
  BOTTOM w0.102: v2(31.96,31.11) 31.96,30.78 32.32,30.43 32.8,30.43 33,30.23 v4(33.05,30.23) ; v4(145.45,34.67) 145.45,34.19 145.7,33.93 v2(145.7,33.9)
PB_IN_N_1: length 7.9
  TOP w0.102: R385.2 C197.2 R379.2 140.27,57.53 v1(140.44,57.35) 140.8,57.35 141.61,56.54 v4(141.61,55.98) U109.72
  BOTTOM w0.102: R79669.1 141.67,55.98 v4(141.61,55.98)
PB_IN_N_2: length 16
  TOP w0.102: U109.111 150.06,45.72 150.17,45.83 150.17,46.46 v4(148.78,47.84)
  L4 w0.127: v4(148.78,47.84) 146.77,49.85 v3(146.77,55.32)
  BOTTOM w0.102: R79669.2 143.36,56.78 144.58,56.78 v2(144.61,56.8) 144.63,56.78 145.32,56.78 146.77,55.33 v3(146.77,55.32)
PB_IN_SW1: length 12.5
  TOP w0.254: v1(28.23,29.21) 27.72,28.7 27.72,27.56 v4(28.74,26.54) 28.07,25.88 28.07,22.61 28.43,22.25 PWRCN1.6
  BOTTOM w0.254: v2(25.92,26.23) R1760.2 R1756.1 28.42,26.23 v4(28.74,26.54)
PCB_VER_ID: length 5.4
  BOTTOM w0.102: R79721.2 R79720.1 106.56,60.58 v2(106.51,60.53) U4101.49
PCH_AUD_RST_N: length 42.7
  TOP w0.102: v4(143.92,27.77) 143.95,27.8 R637.1 ; R289.1 161.26,53.21 160.03,53.21 159.67,53.58 U109.19 157.64,53.58 157.4,53.35 157.4,52.65 156.87,52.11 v4(156.87,51.69)
  L4 w0.102: v4(143.92,27.77) 146.7,27.77 150.91,31.98 153.87,31.98 158.77,36.88 158.77,37.8 158.31,38.26 158.31,39.69 158.4,39.79 158.4,43.32 157.94,43.78 157.94,43.81 157.61,44.14 157.61,50.94 v4(156.87,51.69)
  BOTTOM w0.102: v4(143.92,27.77) 143.92,27.52 v2(144.36,27.08)
PCH_AUD_RST_N_1: length 4.1
  TOP w0.102: Q63.5 144.56,30.68 145.04,30.2 v1(145.04,30.18) 145.04,30.05 144.65,29.65 R637.2
PCH_CLK48_F: length 4.1
  TOP w0.102: CPU1.BC10 77.4,147.92 77.35,147.87 77.35,147.47 v3(77.76,147.07)
  BOTTOM w0.102: R1645.2 77.52,146.05 v2(77.92,146.05) 77.92,146.9 v3(77.76,147.07)
PCH_SATA_LED_1: length 5.7
  BOTTOM w0.254: Q38.B 29.43,24.61 R1759.2 v2(28.35,25.15) 28.35,25.41 29.56,26.61 Q1213.C
PCH_SATA_LED_R: length 3.1
  BOTTOM w0.254: Q1213.B 31.47,29.15 v2(30.89,29.72) 30.77,29.59 29.56,29.59 R1754.2
PCIE_RST#: length 216.4
  TOP w0.102: NGFF1.66 v4(119.88,221) ; NGFF1.52 v4(119.88,217.5)
  L3 w0.127: v4(119.88,221) 119.36,220.48 119.36,218.02 v4(119.88,217.5)
  L4 w0.127: v4(155.22,51.98) 155.2,52 154.87,52 154.43,52.44 154.43,55.31 153.31,56.44 153.31,59.23 153.79,59.71 153.79,65.73 154.72,66.66 154.72,71.44 154.93,71.66 154.93,86.08 155.8,86.95 155.8,87.47 158.43,90.11 158.43,95.88 157.88,96.44 157.88,97.31 159.27,98.7 159.27,100.08 158.53,100.81 158.53,104.52 159.6,105.58 159.6,107.26 165.6,113.27 165.6,131.48 163.6,133.48 163.6,154.85 164.77,156.03 164.77,194.61 162.19,197.19 161.07,197.19 155.12,203.14 143.69,203.14 124.88,221.96 121.84,221.96 120.88,221 v4(119.88,221)
  BOTTOM w0.102: RN13.1 154.98,52.22 v4(155.22,51.98) 155.55,51.65 v2(155.55,51.24)
PCIE_RST_N: length 24.5
  TOP w0.102: v3(74.6,155.98) 74.9,156.28 CPU1.AN7 ; R1678.2 v4(57.54,148.84)
  BOTTOM w0.102: v3(74.6,155.98) v2(73.79,155.98) 73.64,155.98 73.24,156.39 71.78,156.39 69.98,154.59 66.51,154.59 66.28,154.82 65.63,154.82 65.43,155.02 62,155.02 61.21,154.23 59.44,154.23 57.35,152.15 57.35,149.03 v4(57.54,148.84)
PCIE_RST_N_A: length 2.8
  TOP w0.102: R1678.1 55.85,149.35 55.66,149.54 C1738.1 54.36,149.95 v1(54.36,150.52)
PCIRST1#: length 20.2
  TOP w0.102: U109.30 157.45,57.98 157.15,57.68 157.15,57.16 156.88,56.89 156.6,56.89 153.78,54.08 152.2,54.08 v4(152.18,54.1)
  L3 w0.127: v4(152.18,54.1) 152.6,53.68 154.85,53.68 155.53,54.36 v4(156.83,54.36)
  BOTTOM w0.102: v4(156.83,54.36) 157.4,54.36 158.67,55.63 v2(159.85,55.63) R79690.1 ; v4(152.18,54.1) 152.69,54.1 153.2,53.59 RN13.6
PCIRST3#: length 23.2
  TOP w0.102: U109.81 147.92,52.38 148.42,52.88 149.39,52.88 149.56,53.05 150.07,53.05 150.38,52.74 v4(155.18,52.74)
  BOTTOM w0.102: RN13.7 153.7,53.72 153.83,53.85 154.21,53.85 154.35,53.71 RN13.8 154.72,53.19 155.16,52.74 v4(155.18,52.74) 155.57,52.74 155.66,52.83 v2(156.09,52.83) 156.09,52.35 156.29,52.15 158.96,52.15 159.9,53.09 161.13,53.09 R79689.1
PD4405_A: length 3.7
  BOTTOM w0.102: v2(71.28,65.28) 71.66,64.9 PD4405.A 71.57,63.66 PQ4409.B
PD4405_K: length 3.8
  BOTTOM w0.102: PD4405.K 74.96,63.75 v2(75.73,64.52) 75.73,65.02 75.34,65.41 PR4458.2
PD_N: length 8.2
  TOP w0.102: v4(132.53,32.03) 132.94,32.44 U118.36 ; v4(128.81,31.88) 128.81,31.5 127.48,30.16 Q1249.D
  BOTTOM w0.102: v4(128.81,31.88) 128.96,32.03 v2(130.82,32.03) v4(132.53,32.03)
PEG_RXN0: length 7.1
  TOP w0.102: CPU1.P9 76.5,170.6 v3(76.1,170.2)
  BOTTOM w0.102: v3(76.1,170.2) 76.23,170.33 76.23,170.56 76.06,170.73 71.58,170.73 TP5006.1
PEG_RXN1: length 5.9
  TOP w0.102: CPU1.N5 v3(72.9,171.8)
  BOTTOM w0.102: v3(72.9,171.8) 72.47,171.37 72.09,171.37 70.9,172.55 69.03,172.55 TP5008.1
PEG_RXN2: length 8.2
  TOP w0.102: v3(75.3,171.8) 75.3,172.45 75.42,172.57 75.58,172.57 75.7,172.45 CPU1.N8
  BOTTOM w0.102: TP5010.1 70.01,173.61 70.39,173.61 71.67,172.33 75.26,172.33 75.4,172.19 75.4,171.9 v3(75.3,171.8)
PEG_RXN3: length 6.5
  TOP w0.102: CPU1.L6 v3(73.7,173.8)
  BOTTOM w0.102: v3(73.7,173.8) 73.99,173.51 73.99,173.27 73.82,173.1 73.31,173.1 70.9,175.51 TP5012.1
PEG_RXP0: length 7.6
  TOP w0.102: CPU1.P10 77.6,170.9 v3(76.9,170.2)
  BOTTOM w0.102: TP5005.1 71.27,170.95 76.15,170.95 v3(76.9,170.2)
PEG_RXP1: length 6.8
  TOP w0.102: CPU1.N6 v3(73.7,171.8)
  BOTTOM w0.102: v3(73.7,171.8) 73.05,171.15 72,171.15 70.81,172.34 68.99,172.34 TP5007.1
PEG_RXP2: length 8.1
  TOP w0.102: CPU1.N9 v3(76.1,171.8)
  BOTTOM w0.102: v3(76.1,171.8) 75.35,172.55 71.76,172.55 69.76,174.55 TP5009.1
PEG_RXP3: length 7.2
  TOP w0.102: CPU1.L7 v3(74.5,173.8)
  BOTTOM w0.102: TP5011.1 70.09,176.02 70.68,175.42 73.22,172.89 73.91,172.89 74.21,173.18 74.21,173.51 v3(74.5,173.8)
PEG_TXN0: length 3
  TOP w0.102: C1811.2 63.51,178.82 63.4,178.92 v4(63.4,179.27)
  BOTTOM w0.102: v4(63.4,179.27) 63.35,179.32 TP4143.1
PEG_TXN1: length 2.8
  TOP w0.102: C1813.2 63.86,180.59 v4(63.4,181.05)
  BOTTOM w0.102: v4(63.4,181.05) 63.35,181.1 TP4145.1
PEG_TXN2: length 2.8
  TOP w0.102: v4(63.4,182.83) 63.86,182.37 C1814.2
  BOTTOM w0.102: v4(63.4,182.83) 63.33,182.75 TP4147.1
PEG_TXN3: length 1.9
  TOP w0.102: v4(64.16,184.61) 64.6,185.04 C122.2
  BOTTOM w0.102: v4(64.16,184.61) 64.24,184.53 TP4149.1
PEG_TXP0: length 2
  TOP w0.102: v4(64.16,179.27) 64.6,179.71 C1809.2
  BOTTOM w0.102: TP4142.1 64.22,179.32 v4(64.16,179.27)
PEG_TXP1: length 2
  TOP w0.102: C1810.2 64.6,181.48 v4(64.16,181.05)
  BOTTOM w0.102: v4(64.16,181.05) 64.22,181.1 TP4144.1
PEG_TXP2: length 2.1
  TOP w0.102: C1812.2 64.6,183.26 v4(64.16,182.83)
  BOTTOM w0.102: TP4146.1 64.24,182.75 v4(64.16,182.83)
PEG_TXP3: length 2.8
  TOP w0.102: v4(63.4,184.61) 63.86,184.15 C1815.2
  BOTTOM w0.102: TP4148.1 63.35,184.66 v4(63.4,184.61)
PLTRST*_EC: length 7.9
  TOP w0.102: R79697.1 106.84,53.09 104.81,51.05 v1(104.43,51.05) 104.17,51.31 104.17,52.32 v4(104.3,52.45)
  BOTTOM w0.102: v4(104.3,52.45) 104.3,51.82 103.67,51.18 103.41,51.18 103.27,51.04 U4101.6
PLTRST*_SIO: length 12.9
  TOP w0.102: v4(151.82,58.93) 151.65,59.09 U109.46 151.65,61.37 152.39,62.11 152.39,62.93 152.66,63.2 153.46,63.2 R352.1
  BOTTOM w0.102: v4(151.82,58.93) 151.57,59.18 151.57,59.54 151.41,59.69 v2(150.83,59.69) 150.66,59.52 150.66,59.21 151.11,58.75 151.11,56.91 R351.1 150.27,56.45 C76.2
PLTRST_LAN_N: length 151.9
  TOP w0.102: v4(34.83,15.46) U16.19
  L3 w0.127: v4(143.16,27.77) 143.16,27.53 142.21,26.58 138.69,26.58 137.82,27.44 129.28,27.44 127.93,28.79 117.45,28.79 117.22,28.56 94.18,28.56 92.78,29.96 91.74,29.96 90.79,29.01 68.23,29.01 66.53,27.3 66.49,27.3 66.22,27.03 66,27.03 60.66,21.69 58.09,21.69 55.56,19.16 51.32,19.16 50.62,18.47 37.84,18.47 v4(34.83,15.46)
  L4 w0.127: v4(154.76,50.52) 154.81,50.47 154.81,49.1 155.74,48.17 155.74,47.15 155.78,47.1 155.78,43.99 155.52,43.73 155.52,43.34 156.08,42.78 156.08,38.38 155.74,38.04 155.74,37.68 146.82,28.76 144.15,28.76 v4(143.16,27.77)
  BOTTOM w0.102: v2(143.03,28.58) 143.03,28.47 143.16,28.35 v4(143.16,27.77) ; v2(35.63,15.62) 35.46,15.46 v4(34.83,15.46) ; RN13.2 153.7,51.82 154.11,51.41 154.25,51.41 154.76,50.9 v4(154.76,50.52)
PLTRST_N: length 214.8
  TOP w0.102: LPC1.3 115.46,54.09 114.62,53.25 113.93,53.25 113.72,53.47 113.06,53.47 112.25,54.28 110.94,54.28 110.88,54.22 109.57,54.22 108.44,53.09 R79697.2 ; CPU1.BB12 79.29,149.01 79.29,148.69 79.3,148.68 79.3,148.32 79.29,148.31 79.29,147.88 79.41,147.77 79.41,147.37 v3(79,146.96) 79.41,146.56 79.41,146.56 79.41,145.52 78.27,144.38 C77.1 ; R352.2 153.96,65.15 154.26,65.45 154.26,65.53 v4(154.26,65.53) 154.26,68.18 153.78,68.67 v1(153.78,69.85) 153.78,78.71 152.74,79.75 152.74,84.94 153.78,85.99 153.78,88.94 153.57,89.15 153.37,89.34 153.37,92.19 154.08,92.9 154.08,93.67 v4(153.7,94.06)
  L3 w0.127: v3(79,146.96) 78.35,146.32 78.35,145.49 76.25,143.38 76.25,140.56 77.63,139.17 77.63,137.75 79.3,136.08 79.3,135.95 80.04,135.2 80.04,134.13 82.26,131.92 84.85,131.92 91.56,125.2 120.67,125.2 132.71,113.16 144.04,113.16 154.74,102.46 154.74,98.98 154.48,98.72 154.48,94.64 153.94,94.11 153.75,94.11 v4(153.7,94.06) ; LPC1.3 117.51,52.86 121.33,52.86 122.25,51.95 127.47,51.95 128.02,52.49 132.54,52.49 133.57,51.46 139.28,51.46 140.88,53.06 143.42,53.06 144.06,52.41 146.34,52.41 146.95,53.03 147.79,53.03 148.58,53.81 151.81,53.81 152.31,53.3 155.01,53.3 155.2,53.49 v4(155.33,53.49)
  L4 w0.127: v4(154.26,65.53) 154.26,59.64 153.69,59.07 153.69,56.59 154.81,55.47 154.81,54.01 v4(155.33,53.49)
PME#_M: length 24.4
  TOP w0.102: v4(58.41,171.68) 58.25,171.83 R568.2 ; CPU1.AD7 v3(75.3,163.4)
  L3 w0.127: v3(75.3,163.4) 74.88,163.82 74.88,165 74.66,165.23 73.44,165.23 72.69,165.97 68.81,165.97 65.32,169.47 60.54,169.47 58.41,171.6 v4(58.41,171.68)
  BOTTOM w0.102: v2(56.9,171.68) v4(58.41,171.68)
PORTC_SPK_L: length 47.2
  TOP w0.203: v4(164.68,37.82) 164.65,37.82 v1(164.05,37.22) 163.39,37.22 162.77,37.85 R345.1 ; U6.43 166.56,78.43 v4(166.65,78.52)
  L4 w0.203: v4(164.68,37.82) 165.54,37.82 166.53,38.81 166.53,64.64 167.85,65.96 167.85,70.34 166.73,71.46 166.73,78.44 v4(166.65,78.52)
PORTC_SPK_L_1: length 2.8
  TOP w0.203: v1(159.21,37.52) 159.53,37.85 R345.2 R356.1
PORTC_SPK_R: length 65.7
  TOP w0.203: U6.44 166.24,78.83 166.53,79.12 v4(166.53,79.32) ; v4(166.15,30.61) 166.15,29.54 165.13,28.52 165.13,26.67 164.4,25.93 163.13,25.93 159.67,22.48 R359.1
  L4 w0.203: v4(166.53,79.32) 166.68,79.32 167.32,78.68 167.32,71.7 168.44,70.59 168.44,65.66 167.11,64.34 167.11,31.57 v4(166.15,30.61)
  BOTTOM w0.203: v2(165.34,30.61) v4(166.15,30.61)
PORTC_SPK_R_1: length 2.6
  TOP w0.203: v1(156.52,19.81) 156.52,20.73 R367.1 R359.2
PQ4206_D: length 14.1
  BOTTOM w0.102: PQ4206.D 67.22,37.44 67.33,37.33 67.33,36.08 68.03,35.38 69.07,35.38 69.98,34.47 v2(69.98,30.4) 69.81,30.23 PR4214.2
PQ4406_2: length 3
  BOTTOM w0.102: PQ4406.2 73.44,57.4 73.95,57.91 74.2,57.91 74.58,58.29 v2(74.58,58.42) PR4462.2
PQ4406_3: length 3.3
  BOTTOM w0.102: PR4455.2 75.85,57.47 v2(75.85,58.04) 75.34,58.04 74.38,57.07 PQ4406.3
PQ4406_5: length 4.1
  BOTTOM w0.102: PQ4406.5 73.44,54.1 PC4426.1 v2(74.71,52.83) 74.52,52.64 PR4413.2
PQ4406_6: length 4
  BOTTOM w0.102: PR4450.1 72.49,52.58 v2(71.64,52.58) 71.64,52.93 72.3,53.59 PC4426.2 72.79,54.21 PQ4406.6
PQ4409_C: length 6.2
  BOTTOM w0.102: PR4462.1 v2(71.41,58.42) 71.41,59.31 71.98,59.88 PQ4409.C 72.99,60.33 73.82,60.33 74.33,59.82 PR4451.1
PQ4409_E: length 5.3
  BOTTOM w0.102: PR4433.1 PR4431.2 74.9,62.04 75.6,62.74 v2(75.6,62.87) 73.82,62.87 73.53,62.58 PQ4409.E
PRE: length 4.7
  TOP w0.102: U118.16 132.54,40.09 v4(132.74,40.29) R2088.2
  BOTTOM w0.102: R2088.2 v4(132.74,40.29) 132.74,39.56 v2(132.81,39.48)
PSID_D: length 6.1
  BOTTOM w0.102: Q47.D 58.2,34.76 v2(58.2,33.81) 57.69,33.81 56.69,34.81 L15.2 55.35,34.81 R1852.1
PSID_D_1: length 4.2
  BOTTOM w0.102: v2(54.39,33.55) 54.47,33.63 R1852.2 53.58,35.7 R1853.1 52.94,35.19 Q45.B
PSID_G: length 7.8
  BOTTOM w0.102: Q47.G 56.78,37.74 56.02,38.5 v2(55.01,38.5) 54.39,37.88 54.39,37.34 53.76,36.71 R1849.2 53.07,37.09 Q45.C
PW_CLEAR: length 355.8
  TOP w0.102: v3(68.24,162.18) 68.63,162.18 68.85,162.4 69.76,162.4 69.87,162.3 70.23,162.3 70.23,162.31 70.61,162.31 CPU1.AE2 ; R184.1 153.51,112.84 153.2,113.16
  L3 w0.127: 153.2,113.16 153.83,112.52 153.83,110.96 160.64,104.15 160.64,102.49 v4(159.6,101.45) ; v3(68.24,162.18) 67.9,161.84 66.67,161.84 66.17,162.34 61.74,162.34 61.69,162.39 61.18,162.39 59.14,164.44 56.49,164.44 55.77,165.16 54.83,165.16 54.3,164.63 40.86,164.63 39.38,166.11 27.38,166.11 25.18,168.31 15.64,168.31 12.06,164.74 12.06,154.54 15,151.6 15,140.79 17.61,138.18 28.71,138.18 35.21,131.68 35.21,115.7 36.49,114.41 36.49,109.73 39.73,106.5 39.73,80.19 44.63,75.29 51.88,75.29 53.13,76.53 88.55,76.53 93.09,81.06 107.18,81.06 119.27,68.97 144.11,68.97 144.29,68.8 154.07,68.8 155.65,67.21 v4(156.87,67.21)
  L4 w0.127: v4(163.28,100.84) 162.69,100.25 162.69,99.99 162.34,99.63 162.34,99.1 161.53,98.29 161.53,97.78 161.53,95.67 160.01,94.15 160.01,90.25 156.81,87.05 156.81,86.36 156.12,85.67 156.12,85.28 156.76,84.63 156.76,84.23 156.48,83.95 156.48,83.56 156.85,83.19 156.85,80.73 156.08,79.96 156.08,77.91 156.61,77.38 156.61,74.44 157.42,73.63 157.42,69.56 156.7,68.84 156.7,67.37 v4(156.87,67.21)
  BOTTOM w0.102: v4(163.28,100.84) 162.52,100.08 v2(162.01,100.08) 161.98,100.05 160.46,100.05 159.6,100.91 v4(159.6,101.45)
PWR_1D8V_BOOT: length 3
  TOP w0.203: PU5201.10 104.39,65.32 104.17,65.53
  TOP w0.508: 104.17,65.53 103.77,65.53 103.51,65.79 v1(103.46,65.79) 103.41,65.79 103.28,65.66 PR5205.1
PWR_1D8V_BOOT_A: length 2.7
  TOP w0.508: PR5205.2 100.06,65.66 99.78,65.94 v1(99.78,66.17) 99.8,66.17 100.31,66.67 PC5217.1
PWR_1D8V_EN: length 12.1
  TOP w0.203: PU5201.13 103.77,64.12 103.31,63.65 v4(103.31,63.53) 103.61,63.22 103.61,60.81 v1(103.59,60.78) 103.39,60.58 PR62.2
  BOTTOM w0.254: R77.1 PR57.2 PR5223.1 PC34.1 102.04,64.64 103.16,63.53 v4(103.31,63.53)
PWR_1D8V_FB: length 7.6
  TOP w0.203: PR5209.1 101.85,63.78 102.84,63.78 103.1,64.03 103.22,64.03 103.71,64.52 PU5201.12
  TOP w0.254: PR5209.1 PR5201.2 102.4,62.61 102.73,62.28 v1(102.73,62.08) 102.73,61.82 102.5,61.59 PC5203.2
PWR_1D8V_FB_1: length 16.8
  TOP w0.254: PG5211.2 97.78,75.32 v1(97.78,71.79) 99.14,70.43 99.14,65.68 99.42,65.4 99.42,64.06 100.81,62.67 PR5201.1
  TOP w0.508: PR5201.1 PC5203.1
PWR_1D8V_LX: length 4.2
  BOTTOM w0.508: PR5204.1 102.47,68.58 102.01,68.12 v2(102.01,67.36) 102.55,66.83 v7(103.48,66.83)
  vias: v7(104.39,66.83)
PWR_1D8V_SNB: length 1.6
  BOTTOM w0.508: PR5204.2 107.3,68.58 v2(107.75,69.04)
PWR_1D8V_VCC: length 3.6
  TOP w0.203: PU5201.11 103.11,64.92 v1(102.71,64.52) 102.58,64.64 PC5204.1
PWR_1D8V_VOUT: length 13.2
  TOP w0.203: PU5201.7 109,65.32
  TOP w0.254: 109,65.32 109.13,65.44 v1(109.13,70.74) 109.13,74.93 107.48,76.58 PG5212.2
PWR_3D3V_BOOT2: length 4.1
  TOP w0.203: PU4901.7 110.25,9.89 109.63,9.27 ; 109.63,8.61 v1(109.66,8.64)
  TOP w0.508: PR4902.2 110.14,7.19 109.63,7.7 109.63,8.46 109.66,8.48 v1(109.66,8.64) ; 109.63,9.27 109.63,8.61
PWR_3D3V_BOOT2_R: length 3
  TOP w0.508: PR4902.1 111.21,4.45 111.92,4.45 v1(111.97,4.39) 112.05,4.47 PC4907.2
PWR_3D3V_ENTRIP2: length 4.8
  TOP w0.203: v4(108.11,11.15) 108.57,11.61 PU4901.4
  BOTTOM w0.254: PR4924.1 108.01,11.05 v4(108.11,11.15) 108.11,11.15 v2(108.11,9.98) 108.06,10.03 PC4918.1
PWR_3D3V_FB: length 38.9
  TOP w0.254: PC4911.2 PR4914.1 105.76,9.59 104.53,8.36 104.53,6.32 106.28,4.57 v1(108.36,4.57) 109.16,4.57 109.98,3.76 135.92,3.76 PG4902.1
PWR_3D3V_FB2: length 6.8
  TOP w0.203: PU4901.5 109.1,11.12 108.62,10.64
  TOP w0.254: PC4911.1 106.97,11.49 PR4917.1 ; PC4911.1 PR4914.2 ; PC4911.1 107.08,10.48 ; v1(108.26,8.99) 107.96,8.99 107.75,9.2 107.75,9.8 107.08,10.48 ; 107.08,10.48 108.45,10.48 108.62,10.64
PWR_3D3V_LDO3: length 5.2
  TOP w0.203: 113.19,13.89 112.75,13.45 112.75,12.99 112.57,12.81 PU4901.15
  TOP w0.305: PG4904.1 114.41,15.04
  TOP w0.508: PC4914.2 114.33,15.11 113.47,15.11 v1(113.37,15.01) 113.19,14.83 113.19,13.89
PWR_3D3V_LGATE2: length 14.2
  TOP w0.203: PU4901.10 v7(112.16,10.46)
  L3 w0.762: v7(112.16,10.46) 116.39,10.46 119.73,13.8 v4(122.25,13.8)
  BOTTOM w0.406: PU4903.4 v4(122.25,13.8)
  BOTTOM w0.508: v7(112.16,10.46) 112.45,10.46 v2(112.96,9.96)
PWR_3D3V_PHASE2: length 21.6
  TOP w0.203: PU4901.9 111.05,9.89 111.54,9.4 111.79,9.4 v7(112.28,8.91)
  TOP w0.508: v7(112.28,8.91) 112.28,8.73 112.73,8.28 v1(112.73,8.09) 112.73,7.67 PC4907.1
  L3 w0.762: v7(112.28,8.91) 112.3,8.91 112.3,8.89 113.83,7.37 124.87,7.37 125.33,7.82 v7(128.43,7.82)
  vias: v7(127.92,12.9) v7(127.97,13.97) v7(127.97,11.94) v7(128.13,11) v7(128.79,13.39) v7(128.79,6.78)
PWR_3D3V_SNB:
  vias: v2(124.85,9.8)
PWR_3D3V_UGATE2: length 23.8
  TOP w0.203: v7(110.78,8.76) 110.65,8.89 PU4901.8
  L3 w0.762: v7(110.78,8.76) 110.78,7.37 112.56,5.59 127.67,5.59 127.92,5.84 v4(127.92,6.1)
  BOTTOM w0.406: PU4902.4 126.83,5.37 127.02,5.18 127.92,5.18
  BOTTOM w0.508: v4(127.92,6.1) v2(127.92,5.26) 127.92,5.18 127.92,5.18
PWR_5V3V_EMN: length 4.6
  TOP w0.203: v4(113.19,12.01) PU4901.13
  TOP w0.254: PR4918.2 113.24,12.06 v4(113.19,12.01)
  BOTTOM w0.254: v4(113.19,12.01) 113.19,12.75 113.01,12.93 v2(112.81,12.93) 112.64,12.93 112.39,12.68 PR4920.1
PWR_5V3V_ENLDO: length 2.7
  TOP w0.203: PU4901.12 112.87,11.61 113.08,11.4 113.37,11.4 v1(113.52,11.25) 113.81,11.25 PR4901.2
PWR_5V3V_LDO5: length 3.9
  TOP w0.203: PU4901.14 112.87,12.41 113.54,13.08 v1(113.57,13.08) PG4901.1
  TOP w0.305: PG4901.1 114.79,13.3 114.4,13.69 PC4906.1
PWR_5V3V_PGOOD: length 5.9
  TOP w0.203: PU4901.6 109.45,10.46
  TOP w0.254: 109.45,10.46 108.95,9.96 108.95,7.9 108.49,7.44 v1(108.29,7.44) 107.93,7.44 106.93,8.45 106.93,8.48 R1762.2
PWR_5V3V_TON: length 3.4
  TOP w0.203: v4(107.84,11.97) 107.89,11.97 107.93,12.01 PU4901.3
  BOTTOM w0.254: v2(109.02,12.01) 108.98,11.97 v4(107.84,11.97) 107,11.97 PR4919.1
PWR_5V_BOOT1: length 4.6
  TOP w0.203: PU4901.19 110.25,14.12 109.76,14.61
  TOP w0.508: PR4903.1 110.32,16.69 109.3,15.67 v1(109.3,15.21) 109.3,14.96 109.66,14.61 109.76,14.61
PWR_5V_BOOT1_R: length 2.8
  TOP w0.508: PR4903.2 111.29,19 v1(112.45,19) 112.56,18.9 PC4908.1
PWR_5V_BYP1: length 87.4
  TOP w0.203: 109.16,13.97 109.16,13.84 109.44,13.57 PU4901.20
  TOP w0.254: v4(137.85,24.56) PG4903.2
  TOP w0.508: PG4903.2 v4(136.02,24.56) ; PC4913.1 PR4921.2 105.89,14.61 v4(104.94,14.61) ; PC4912.1 107.35,15.75 107.86,15.24 v4(107.86,15.21) 108.46,14.61 108.52,14.61 109.16,13.97
  L3 w0.254: v4(104.94,14.61) 104.94,14.73 107.48,17.27 107.48,20.07 109.19,21.78 111.61,21.78 117.79,27.97 127.59,27.97 128.94,26.62 135.8,26.62 v4(137.85,24.56)
  L3 w0.508: v4(136.02,24.56) 134.68,25.91 128.68,25.91 127.26,27.33 118.17,27.33 111.92,21.08 109.63,21.08 108.24,19.68 108.24,17.02 107.6,16.38 107.6,15.46 v4(107.86,15.21)
  BOTTOM w0.508: v2(137.02,24.93) 137.38,24.56 v4(137.85,24.56)
PWR_5V_ENTRIP1: length 4.6
  TOP w0.203: PU4901.2 108.57,12.41 108.08,12.9 v4(107.83,12.9)
  BOTTOM w0.254: PR4925.1 107.65,13.08 v4(107.83,12.9) 107.83,14.07 v2(107.86,14.1) PC4917.1
PWR_5V_FB1: length 5.7
  TOP w0.203: PU4901.1 109.1,13.08 108.79,13.39
  TOP w0.254: 108.79,13.39 v4(108.6,13.57) 108.59,13.57 108.5,13.65 PC4913.2 ; PC4913.2 PR4921.1 ; PC4913.2 106.9,13.59 PR4922.1
  BOTTOM w0.254: v4(108.6,13.57) 109.44,13.57 109.48,13.62 v2(109.52,13.62)
PWR_5V_LGATE1: length 16.3
  TOP w0.254: v7(112.43,13.97) 112.02,13.57 PU4901.16
  L4 w0.762: v7(112.43,13.97) 112.56,14.1 114.84,14.1 117.66,16.92 117.66,17.55 119.12,19.01 v7(123.24,19.01)
  BOTTOM w0.406: PU4905.4 v7(123.24,19.01)
  BOTTOM w0.508: v7(112.43,13.97) 112.76,13.97 113.24,14.45 v2(113.24,14.4)
PWR_5V_PHASE1: length 23.4
  TOP w0.203: PU4901.17 111.05,14.1 111.67,14.73
  TOP w0.508: 111.67,14.73 111.67,14.74 v7(112.3,15.37) 112.56,15.62 PC4908.2
  L3 w0.762: v7(112.3,15.37) 115.54,18.61 115.55,18.61 117.65,20.7 124.67,20.7 125.2,20.17 127.62,20.17 129.17,21.72 v7(129.19,21.72)
  vias: v2(128.56,25.02) v2(129.04,15.34) v7(127.62,18.41) v7(127.62,17.4) v7(127.62,16.38) v7(127.62,15.37) v7(127.72,24.26) v7(127.72,22.86) v7(128.33,22.17) v7(128.35,23.57) v7(128.68,18.67) v7(128.76,17.65) v7(128.76,16.51) v7(129.01,24.23) v7(128.99,22.91)
PWR_5V_SNB: length 2.7
  BOTTOM w0.508: PC4915.1 124.7,20.09 v2(124.75,20.14) 125.86,20.14 PR4912.2
PWR_5V_UGATE1: length 23.1
  TOP w0.203: PU4901.18 v7(110.65,14.99)
  L3 w0.762: v7(110.65,14.99) 110.65,16.13 116.75,22.23 126.3,22.23 v7(126.64,21.88)
  BOTTOM w0.406: v7(126.64,21.88) 126.61,21.91 PU4904.4
  BOTTOM w0.508: v7(110.65,14.99) 110.65,15.01 v2(109.99,15.67)
PWR_CHG_ACDET: length 4.9
  BOTTOM w0.254: PR5270.2 64.99,59.31 PR4412.1 PC5232.1 64.04,57.53 v2(64.02,57.56) 63.72,57.26 U55.6
PWR_CHG_ACN: length 26.7
  TOP w0.254: 62.03,54.41 62.03,57.73 57.44,62.33 57.44,63.2 v4(57.06,63.58) ; 62.03,54.41 62.03,52.86 59.6,50.42 59.6,48.51 59.34,48.26 PG4905.2 ; 62.03,54.41 v1(61.63,54.41)
  BOTTOM w0.254: v4(57.06,63.58) PC4404.1 57.06,61.47 PC4402.1 56.93,61.26 57.54,60.66 57.54,60.17 58.08,59.63 59.04,59.63 59.74,58.94 U55.1
PWR_CHG_ACP: length 28.1
  TOP w0.254: v1(60.36,47.88) 59.98,47.88 ; 59.98,47.88 59.98,47.65 59.65,47.32 58.89,47.32 PG4907.2 ; 59.98,47.88 59.98,50.27 62.42,52.7 62.42,57.89 57.82,62.49 57.82,63.22 v4(58.2,63.6)
  BOTTOM w0.254: U55.2 60.25,58.18 60.25,58.97 59.2,60.02 58.23,60.02 57.92,60.33 57.92,60.81 PC4402.2 58.45,62.48 PC4403.1 58.2,62.74 v4(58.2,63.6)
PWR_CHG_AD_OFF: length 39.4
  TOP w0.102: v4(70.39,39.94) 70.39,43.74 71.48,44.83 75.5,44.83 79.39,48.72 80.37,48.72 81.67,50.01 84.87,50.01 v4(85.96,51.1)
  BOTTOM w0.102: PQ4206.G 68.71,39.94 PR4210.1 v4(70.39,39.94) ; U4101.19 97.27,52.28 95.92,50.93 92.81,50.93 R80230.1 90.82,51.12 89.49,49.78 87.16,49.78 86.9,50.04 86.01,50.04 v2(85.76,50.29) 85.76,50.9 v4(85.96,51.1)
PWR_CHG_AD_OFF_R: length 3
  BOTTOM w0.102: PR4210.2 69.88,38.67 v2(69.88,37.97) 69.88,37.8 69.7,37.61 PQ4204.B
PWR_CHG_BTST: length 4
  BOTTOM w0.305: PR5279.1 57.49,54.84 58.41,55.76 U55.17
  BOTTOM w0.508: v2(56.42,55.98) 56.45,55.96 56.45,54.98 PR5279.1
PWR_CHG_BTST_1: length 4.6
  BOTTOM w0.508: PC5234.1 54.31,57.23 v2(54.14,57.05) 54.24,56.95 PD4401.K 54.57,54.84 PR5279.2
PWR_CHG_CMPIN: length 9.5
  BOTTOM w0.254: PR5467.2 63.6,60.82 v2(62.9,60.13) 62.14,59.36 61.86,59.36 61.24,58.74 U55.4 ; PR5467.2 PR5468.1 ; PR5467.2 63.53,61.4 PR5469.2 PR5470.1 61.37,60.39 PR5287.2
PWR_CHG_CMPIN_R: length 3.2
  BOTTOM w0.254: PQ5006.6 61.74,62.6 v2(61.5,62.36) PR5470.2
PWR_CHG_CMPIN_RR: length 11.2
  TOP w0.254: v4(62.52,63.12) 61.99,62.6 60.77,62.6 60.3,63.06 60.3,64.45 59.6,65.16 v4(59.6,65.23)
  BOTTOM w0.254: PQ5006.3 63.04,66.64 62.7,66.98 60.41,66.98 v2(59.85,66.42) 59.6,66.17 v4(59.6,65.23) ; PR5469.1 v4(62.52,63.12)
PWR_CHG_HIDRV: length 24.1
  TOP w0.406: PU4403.4 38.8,59.55 v7(38.76,59.5)
  TOP w0.508: v7(38.76,59.5) 37.99,59.5 37.73,59.77 v1(37.73,59.79)
  L3 w1.016: v7(38.76,59.5) 39.97,58.29 53.22,58.29 55.76,55.75 v7(57.31,55.75)
  BOTTOM w0.305: v7(57.31,55.75) 57.31,55.98 57.59,56.26 U55.18
PWR_CHG_ILIM: length 35.7
  TOP w0.508: v4(60.87,64.23) 61.22,64.23 61.88,64.9 63.13,64.9 64.24,66 64.24,69.66 64.88,70.31 v1(66.63,70.31) 69.15,70.31 70.71,68.75 PQ5003.D
  L4 w0.508: v4(60.87,64.23) 60.87,63.94 60.33,63.4 60.33,60.86 63.15,58.04 63.15,54.36 v4(64.35,53.16)
  BOTTOM w0.305: U55.10 62.54,54.64
  BOTTOM w0.508: 62.54,54.64 62.54,53.88 63.79,52.63 PR5278.2 PR5268.1 64.8,52.7 v4(64.35,53.16)
PWR_CHG_IOUT: length 12.9
  TOP w0.254: v4(64.78,54.66) 65.26,55.14 v1(65.26,55.5)
  L4 w0.254: v4(63.91,59.82) 64.8,58.93 64.8,54.69 v4(64.78,54.66)
  BOTTOM w0.254: v4(63.91,59.82) 63.91,60.35 64.49,60.92 PR5467.1 ; v4(64.78,54.66) 64.94,54.83 PR5288.1 64.99,55.55 PC5239.1 64.75,56.76 U55.7
PWR_CHG_LODRV: length 18
  TOP w0.406: PU4405.4 46.73,56.28 v7(46.78,56.32)
  TOP w0.508: v1(47.77,56.32) v7(46.78,56.32)
  L3 w1.016: v7(57.77,52.88) 55.43,52.88 51.99,56.32 v7(46.78,56.32)
  BOTTOM w0.305: U55.15 59.74,54.09 59.34,53.7
  BOTTOM w0.508: v7(57.77,52.88) 58.21,52.44 PC5237.1 58.86,53.31 59.24,53.7 59.34,53.7
PWR_CHG_NC: length 3.1
  BOTTOM w0.254: PR5286.1 62.64,52.36 62.65,52.37 v2(62.65,52.76) 61.74,53.67 U55.11
PWR_CHG_PHASE: length 17.2
  L3 w1.016: v7(57.72,57.45) 57.56,57.45 57.54,57.48 56.78,57.48 55.62,58.64 55.21,58.64 53.9,59.94 45.48,59.94 v7(44.66,60.76)
  BOTTOM w0.305: U55.19 58.26,56.76 57.72,57.3 v7(57.72,57.45)
  BOTTOM w0.508: PC5234.2 57.49,57.23 v7(57.72,57.45)
  vias: v7(39.96,60.76) v7(40.88,60.76) v7(41.79,60.76) v7(42.71,60.76) v7(43.62,60.76)
PWR_CHG_SRN: length 3.2
  BOTTOM w0.254: v2(61.42,52.83) 61.17,52.83 ; 61.17,52.83 61.17,54.42 U55.12 ; 61.17,52.83 61.17,52.08 PR5277.1
PWR_CHG_SRP: length 4.3
  BOTTOM w0.254: U55.13 60.74,54.32 60.79,54.26 60.79,52.06 PR5283.1 60.12,51.75 59.82,52.04 v2(59.82,52.68)
PWR_CHG_VCC: length 6.3
  TOP w0.762: v4(57.71,58.93) PR5284.2 56.5,57.3 v1(56.55,57.25)
  BOTTOM w0.305: U55.20 58.94,57.7 58.57,58.06
  BOTTOM w0.762: 58.57,58.06 v4(57.71,58.93) PR5284.2
PWR_COMP_R: length 2.7
  BOTTOM w0.254: PC4626.1 21.06,218.57 20.84,218.8 v2(20.84,219.15) 20.84,219.33 21.09,219.58 PR4645.2
PWR_CPU_BST1: length 6.1
  BOTTOM w0.203: PU4601.28 32.39,214.15 32.61,213.93 32.79,213.93 32.85,213.87
  BOTTOM w0.508: 32.85,213.87 33.31,213.87 34.42,212.75 34.42,211.43 v2(34.2,211.2) PR4701.1
PWR_CPU_BST2: length 5.5
  BOTTOM w0.203: PU4601.37 28.79,214.11 27.85,213.17
  BOTTOM w0.508: 27.85,213.17 27.24,212.56 27.24,211.44 v2(27.46,211.21) 27.47,211.21 PR4703.1
PWR_CPU_COMP: length 6.5
  BOTTOM w0.127: v2(21.55,217.58) 21.71,217.58 PC4626.2
  BOTTOM w0.203: 25.65,218.63 25.68,218.61 PU4601.48
  BOTTOM w0.254: PC4626.2 23.59,218.57 PC4627.2 25.65,218.63
PWR_CPU_COMPNB: length 5.3
  BOTTOM w0.203: PU4601.18 34.95,218.61
  BOTTOM w0.254: 34.95,218.61 35.65,218.61 v2(36.05,219) 36.05,219 36.7,219.65 PC4612.2 38.01,219.65 PC4611.2
PWR_CPU_CSCOMP: length 55.6
  TOP w0.254: PR4637.1 22.19,182.56 v4(22.13,182.63)
  L3 w0.254: v4(20.81,215.71) 21,215.9 22.77,215.9 23.4,215.26 23.4,211.71 21.88,210.19 20.02,210.19 16.99,207.16 16.99,185.69 16.99,185.27 19.38,182.88 21.88,182.88 v4(22.13,182.63)
  BOTTOM w0.203: PU4601.45 26.05,217.4 25.86,217.22 24.93,217.22 24.92,217.23 24.16,217.23 PR4601.2
  BOTTOM w0.254: PC4618.1 22.03,213.74 21.78,214 v2(21.78,214.22) 21.78,214.4 22,214.63 PC4615.2 PR4626.2 ; PR4626.2 21.69,215.65 PR4619.1 v4(20.81,215.71) ; PR4626.2 22.64,215.71 PC4603.2 PR4601.2
PWR_CPU_CSCOMPNB: length 57.8
  TOP w0.254: PR4639.1 v4(46.39,182.91)
  L3 w0.254: v4(39.83,217.61) 39.66,217.61 38.26,216.21 38.26,211.46 38.77,210.95 41.57,210.95 44.9,207.62 52.26,200.27 52.26,188.76 47.17,183.67 47.17,183.66 46.41,182.91 v4(46.39,182.91)
  BOTTOM w0.203: 35.74,217.17 34.58,217.17 34.34,217.4 PU4601.21
  BOTTOM w0.254: PC4624.2 PR4638.2 36.55,217.17 35.74,217.17 ; PC4624.2 PR4640.1 v4(39.83,217.61) ; PC4624.2 37.94,217.55 PR4609.2 PC4613.1 38.69,215.52 38.95,215.26 v2(38.95,215.11) 38.95,214.88 38.69,214.63 PC4617.2
PWR_CPU_CSN1: length 62.9
  TOP w0.254: PG4702.2 40.29,181.61 v4(40.67,181.99)
  L3 w0.254: v4(21.88,211.07) 21.75,211.2 20.04,211.2 16.23,207.39 16.23,184.47 18.83,181.86 23.53,181.86 25.69,184.02 39.82,184.02 40.48,183.36 40.48,182.18 v4(40.67,181.99)
  BOTTOM w0.254: v4(21.88,211.07) 22.51,211.71 PR4618.2 ; v4(40.67,181.99) v2(41.49,181.99)
PWR_CPU_CSN1NB: length 64.5
  TOP w0.254: v4(29.36,182.09) 29.36,181.86 29.12,181.61 PG4704.2
  L3 w0.254: v4(29.36,182.09) 29.39,182.06 29.39,181.59 30.26,180.72 47.58,180.72 48.91,182.06 48.91,184.6 52.76,188.45 52.76,200.48 41.72,211.52 40.64,212.6 v4(38.9,212.6)
  BOTTOM w0.254: v2(30.26,182.08) 29.52,182.08 29.51,182.09 v4(29.36,182.09) ; v4(38.9,212.6) PR4612.2
PWR_CPU_CSP1: length 5.8
  TOP w0.254: v4(27.08,214.76) 26.04,213.72 25.64,213.72 v1(25.61,213.74) PC4628.2 PR4615.1
  BOTTOM w0.203: PU4601.40 27.57,215.25 v4(27.08,214.76)
PWR_CPU_CSP1NB: length 6.4
  TOP w0.254: PC4623.1 PR4608.1 36.8,213.36 v1(34.88,213.36) 34.27,213.36 33.69,213.94 v4(33.69,214.76)
  BOTTOM w0.203: v4(33.69,214.76) 33.2,215.25 PU4601.26
PWR_CPU_CSP2: length 7.7
  BOTTOM w0.203: PU4601.41 26.74,215.81 26.32,215.39
  BOTTOM w0.254: 26.32,215.39 26.09,215.16 26.09,213.75 25.56,213.22 25.56,211.96 v2(25.48,211.89) 24.82,211.23 24.37,211.23 23.83,210.69 PR4631.1
PWR_CPU_CSP2NB: length 6.8
  BOTTOM w0.203: PU4601.25 33.92,215.81 34.18,215.54
  BOTTOM w0.254: 34.18,215.54 34.4,215.32 34.4,213.68 35.06,213.02 35.06,212.65 v2(36.13,211.58) PR4633.1
PWR_CPU_CSREF: length 13.7
  TOP w0.254: PC4606.1 26.89,216.09 26.58,215.77 v4(25.89,215.77) 25.69,215.57 25.69,214.88 25.43,214.63 22.89,214.63 22.7,214.44 PC4628.1
  BOTTOM w0.203: v4(25.89,215.77) 26.02,215.9 26.32,215.9 26.63,216.21 PU4601.42
  BOTTOM w0.254: PR4618.1 23.59,211.82 v2(24.37,212.6) 25.05,213.28 25.05,213.43 25.59,213.96 25.59,215.47 v4(25.89,215.77)
PWR_CPU_CSREFNB: length 11.7
  TOP w0.254: PC4622.1 34.83,216.03 v4(35.34,215.52) 35.87,214.99 36.42,214.99 36.63,215.19 37.39,215.19 37.6,214.98 37.6,214.97 PC4623.2
  BOTTOM w0.203: v4(35.34,215.52) 34.83,216.03 34.2,216.03 34.02,216.21 PU4601.24
  BOTTOM w0.254: v4(35.34,215.52) 35.34,213.56 v2(36.1,212.8) 36.3,212.6 PR4612.1
PWR_CPU_CSSUM: length 10.2
  TOP w0.254: PR4620.2 23.72,215.77 v4(25.03,215.77)
  BOTTOM w0.203: PU4601.43 26.39,216.61 26.07,216.28 25.53,216.28 v4(25.03,215.77)
  BOTTOM w0.254: 23.88,214.63 24.21,214.63 v2(24.59,214.25) 24.59,214.17 24.16,213.74 PC4618.2 23.66,213.68 23.66,213.11 23.27,212.72 PR4641.1 ; 23.88,214.63 v4(25.03,215.77) ; 23.88,214.63 PC4615.1
PWR_CPU_CSSUMNB: length 10.3
  TOP w0.254: v4(36.2,215.52) 36.2,216.38 36.36,216.53 PR4644.2
  BOTTOM w0.203: v4(36.2,215.52) 36.1,215.52 35.21,216.41 34.32,216.41 34.13,216.61 PU4601.23
  BOTTOM w0.254: v4(36.2,215.52) PC4613.2 PC4617.1 36.46,214.63 36.13,214.3 v2(36.13,214.02) 36.13,213.82 36.33,213.61 PR4625.1
PWR_CPU_DIFF: length 5.5
  BOTTOM w0.203: 26.04,219.68 26.32,219.4 PU4601.50
  BOTTOM w0.254: 26.04,219.68 25.24,220.48 v2(25.17,220.48) 25.05,220.6 PR4636.1 PR4634.1
PWR_CPU_DIFFNB: length 6.7
  BOTTOM w0.203: 34.89,220.03 34.27,219.4 PU4601.16
  BOTTOM w0.254: 34.89,220.03 35.92,221.06 v2(35.92,221.84) 36.65,222.57 PR4621.1 37.05,222.63 PR4622.1
PWR_CPU_DROOP: length 5.4
  BOTTOM w0.203: PU4601.46 25.9,217.81 25.64,217.55 25.22,217.55 24.76,218.01 v2(24.62,218.01)
  BOTTOM w0.254: v2(24.62,218.01) 24.26,218.01 23.86,217.61 PR4601.1 PC4603.1
PWR_CPU_DROOPNB: length 5.3
  BOTTOM w0.203: PU4601.20 34.46,217.81
  BOTTOM w0.254: 34.46,217.81 34.73,217.54 35.17,217.54 35.39,217.75 v2(36.02,217.75) 36.05,217.75 36.8,218.5 PR4638.1 PC4624.1
PWR_CPU_FB: length 7.1
  BOTTOM w0.203: 25.81,219.2 26,219 PU4601.49
  BOTTOM w0.254: 25.81,219.2 25.62,219.38 v2(24.65,219.38) 23.79,219.38 PC4627.1 23.59,219.58 PR4645.1 PR4636.2 21.81,220.6 PC4621.2
PWR_CPU_FBNB: length 7.7
  BOTTOM w0.203: PU4601.17 34.63,219
  BOTTOM w0.254: 34.63,219 34.81,219 v2(36.05,220.24) 36.34,220.54 PC4612.1 37.05,220.6 PR4623.1 PC4610.2 38.01,221.68 PR4621.2
PWR_CPU_HG1: length 36.2
  TOP w0.762: 49.31,190.5 v7(49.31,189.17)
  L3 w1.016: v7(33.69,212.09) 33.69,211.46 38.69,206.45 41.74,206.45 47.79,200.41 47.79,191.37 49.31,189.85 49.31,189.17 v7(49.31,189.17)
  BOTTOM w0.203: PU4601.29 31.99,213.79 32.95,212.82 v2(33.09,212.82) 33.69,212.23 v7(33.69,212.09)
PWR_CPU_HG2: length 31.4
  TOP w0.762: v7(23.83,189.05) 23.83,189.18 23.91,189.26 PU4702.4
  L3 w1.016: v7(27.97,212.09) 25.81,209.93 25.81,207.01 21.75,202.95 21.75,191.13 v7(23.83,189.05)
  BOTTOM w0.203: PU4601.36 29.19,213.61 v2(28.66,213.08) 27.97,212.39 v7(27.97,212.09)
PWR_CPU_ILIM: length 4.5
  BOTTOM w0.203: v2(24.68,216.65) 25.93,216.65 26.28,217 PU4601.44
  BOTTOM w0.254: v2(24.68,216.65) 23.68,215.65 PR4626.1
PWR_CPU_ILIMNB: length 4.1
  BOTTOM w0.203: PU4601.22 34.23,217 34.45,216.79 35.66,216.79 v2(35.97,216.48) 37,216.48 PR4609.1
PWR_CPU_IOUT: length 6.5
  TOP w0.254: v1(25.94,220.17) 26.83,219.28 26.83,219.2 26.89,219.14 PR4614.1 PC4609.2 25.69,217.81 v4(25.43,218.06)
  BOTTOM w0.203: v4(25.43,218.06) 25.58,218.21 PU4601.47
PWR_CPU_IOUTNB: length 6
  TOP w0.254: v4(34.95,218.07) 35.09,217.93 35.09,217.18 v1(34.95,217.04) PR4627.1 PC4616.1
  BOTTOM w0.203: v4(34.95,218.07) 34.81,218.21 PU4601.19
PWR_CPU_LG1: length 32.1
  TOP w0.762: PU4705.4 36.61,196.09 v7(35.54,196.09)
  L4 w1.016: v7(35.54,196.09) 41.41,196.09 v7(41.41,196.09) 41.49,196.16 41.49,200.99 39.15,203.33 37.5,203.33 31.4,209.42 v7(31.4,212.09)
  BOTTOM w0.203: v7(31.4,212.09) v2(31.4,213) 31.19,213.22 PU4601.31
  BOTTOM w0.762: PU4706.4 v7(41.41,196.09)
PWR_CPU_LG2: length 28
  TOP w0.762: PU4704.4 28.25,196.09 v7(27.87,196.47)
  L4 w1.016: v7(33.79,196.09) 28.25,196.09 v7(27.87,196.47) 27.87,204.62 29.31,206.06 29.31,208.98 30.26,209.93 v7(30.26,212.09)
  BOTTOM w0.203: v7(30.26,212.09) 30.26,212.97 v2(30.17,213.06) 29.99,213.24 PU4601.34
  BOTTOM w0.762: PU4703.4 v7(33.79,196.09)
PWR_CPU_PHCONFIG: length 6.7
  BOTTOM w0.203: 27.91,213.8 27.92,213.8 28.39,214.27 PU4601.38
  BOTTOM w0.254: PR4635.1 25.69,209.96 v2(26.3,210.57) 26.6,210.87 26.6,212.82 27.58,213.8 27.91,213.8
PWR_CPU_ROSC: length 3.2
  BOTTOM w0.203: 32.16,221.74 31.99,221.56 PU4601.11
  BOTTOM w0.254: 32.16,221.74 32.16,222.3 v2(32.22,222.36) 32.22,223.27 PR4610.2
PWR_CPU_SNBNB:
  vias: v1(25.94,194.69)
PWR_CPU_SNBVDD1:
  vias: v1(43.47,194.69)
PWR_CPU_SR: length 7.3
  BOTTOM w0.203: 27.28,214.22 27.31,214.25 27.72,214.25 27.99,214.52 PU4601.39
  BOTTOM w0.254: PR4603.1 v2(24.67,210.54) 24.85,210.72 25.43,210.72 26.09,211.38 26.09,213.03 27.28,214.22
PWR_CPU_SW1: length 36.5
  L3 w1.016: v7(32.55,212.09) 32.55,210.06 37.8,204.8 41.06,204.8 46.13,199.72 46.13,190.69 v7(47.66,189.17)
  BOTTOM w0.203: PU4601.30 31.59,213.72 32.51,212.81 32.51,212.13 v7(32.55,212.09)
  BOTTOM w0.508: PC4704.2 32.93,211.71 v7(32.55,212.09)
  vias: v2(40.29,187.07) v7(35.97,189.14) v7(35.97,188.23) v7(35.97,187.31) v7(35.97,186.4) v7(35.97,185.48) v7(36.89,189.14) v7(36.89,188.23) v7(36.89,187.31) v7(36.89,186.4) v7(36.89,185.48) v7(37.8,189.14) v7(37.8,188.23) v7(37.8,187.31) v7(37.8,186.4) v7(37.8,185.48) v7(42.78,189.14) v7(42.78,187.31) v7(42.78,185.48) v7(44.61,189.14) v7(44.61,187.31) v7(44.61,185.48)
PWR_CPU_SW2: length 31.3
  L3 w1.016: v7(25.56,189.17) 25.56,189.99 23.4,192.15 23.4,202.06 27.47,206.12 27.47,209.04 29.12,210.69 v7(29.12,212.09)
  BOTTOM w0.203: v7(29.12,212.09) 29.59,212.56 PU4601.35
  BOTTOM w0.508: v7(29.12,212.09) 28.74,211.71 PC4710.2
  vias: v2(29.24,187.2) v7(24.8,187.31) v7(24.8,185.48) v7(26.63,189.14) v7(26.63,187.31) v7(26.63,185.48) v7(31.61,189.14) v7(31.61,188.23) v7(31.61,187.31) v7(31.61,186.4) v7(31.61,185.48) v7(32.52,189.14) v7(32.52,188.23) v7(32.52,187.31) v7(32.52,186.4) v7(32.52,185.48) v7(33.43,189.14) v7(33.43,188.23) v7(33.43,187.31) v7(33.43,186.4) v7(33.43,185.48)
PWR_CPU_SWN1: length 64.6
  TOP w0.254: PR4615.2 v4(20.99,212.72) ; v4(39.91,181.99) 40.29,182.37 PG4701.2
  L3 w0.254: v4(39.91,181.99) 40.1,182.18 40.1,183.2 39.66,183.64 25.85,183.64 23.69,181.48 18.67,181.48 15.84,184.31 15.84,207.55 20.99,212.69 v4(20.99,212.72)
  BOTTOM w0.254: v4(20.99,212.72) PR4641.2 ; v4(39.91,181.99) 39.05,181.99 v2(39.03,181.97)
PWR_CPU_SWN1NB: length 67.6
  TOP w0.254: PG4703.2 29.12,182.69 v4(28.61,182.18) ; PR4608.2 v4(39.53,213.61)
  L3 w0.254: v4(28.61,182.18) 28.61,181.83 30.1,180.34 47.73,180.34 49.3,181.9 49.3,184.44 53.14,188.29 53.14,200.63 40.8,212.98 40.17,212.98 v4(39.53,213.61)
  BOTTOM w0.254: v4(39.53,213.61) PR4625.2 ; v4(28.61,182.18) v2(27.72,182.18)
PWR_CPU_TEENSE: length 51.5
  TOP w0.254: PR4613.2 v4(51.21,197.59)
  L3 w0.254: v4(51.21,197.59) 51.21,199.87 49.09,202 44.18,206.9 41.15,209.93 38.35,209.93 37.24,211.03 37.24,222.5 36.41,223.34 27.34,223.34 v4(26.73,222.73)
  BOTTOM w0.203: PU4601.1 27.53,220.62 27.52,220.62
  BOTTOM w0.254: 27.52,220.62 27.27,220.88 27.27,223.01 PR4605.2 PC4607.2 26.08,223.58 25.88,223.38 v2(25.88,223.13) 25.88,222.92 26.07,222.73 v4(26.73,222.73)
PWR_CPU_TSENSENB: length 40.5
  TOP w0.254: PC4619.2 PR4629.2 34.16,221.17 v4(33.89,220.9) ; PR4630.2 v4(18.19,197.59)
  L3 w0.254: v4(33.89,220.9) 25.86,220.9 24.49,219.53 24.49,211.36 21.76,208.64 20.2,208.64 18.19,206.63 v4(18.19,197.59)
  BOTTOM w0.203: PU4601.14 33.2,220.49 33.61,220.9 v4(33.89,220.9)
  BOTTOM w0.254: v2(18.3,198.5) 18.19,198.39 v4(18.19,197.59)
PWR_CPU_VCC: length 6.3
  TOP w0.508: PR4602.2 32.79,223.77 v1(31.8,223.77) 31.55,223.53 v4(31.55,222.81) 32.01,222.35 PC4602.1
  BOTTOM w0.203: PU4601.10 31.59,221.71 31.66,221.79 31.66,222.7 v4(31.55,222.81)
PWR_CPU_VDD: length 6
  BOTTOM w0.203: PC4601.1 24.49,221.98 24.49,221.82 v2(24.65,221.67) 24.72,221.59 24.89,221.59 26.67,219.8 PU4601.51
  BOTTOM w0.508: PR4604.1 23.78,222.69 PC4601.1
PWR_CPU_VDDNB: length 7
  BOTTOM w0.203: PU4601.15 34.04,219.8 34.48,220.24 34.48,220.58 34.51,220.61
  BOTTOM w0.508: v2(36.89,223.67) 36.8,223.58 PR4642.1 PC4605.1 34.96,221.06 34.51,220.61
PWR_CPU_VRMP: length 7
  TOP w0.254: PC4614.1 33.05,222.63 v4(32.93,222.76) v1(34.37,222.76) 35.81,222.76 PR4616.2
  BOTTOM w0.203: v4(32.93,222.76) 32.93,222 32.39,221.46 PU4601.12
PWR_DCBATOUT_1D8V: length 8.4
  TOP w0.254: PC5214.1 106.06,61.32 PU5201.1 ; PG5205.2 105.44,58.67 PC5209.1 104.94,57.91 PG5210.2 PG5205.2
  TOP w0.762: PC5209.1 106.2,57.92 v1(106.2,56.72)
PWR_DCBATOUT_3V: length 1.7
  BOTTOM w0.762: v2(119.26,8.64) 119.11,8.48 PR4929.2
PWR_DCBATOUT_5V:
  vias: v2(121.22,26.09) v7(122.08,24.64) v7(122.08,23.5)
PWR_DCBATOUT_VDDP:
  vias: v2(24.93,161.51) v7(25.71,160.93) v7(26.22,161.7) v7(26.98,161.06)
PWR_DIFF_R: length 3.4
  BOTTOM w0.254: PR4634.2 22.7,222.68 22.42,222.96 v2(22.21,222.96) 21.95,222.96 21.75,222.76 PC4621.1
PWR_FCH_REF: length 7.6
  TOP w0.102: PR5473.2 v4(151.04,204.6) PR5472.1 151.93,204.66 PC51.1
  BOTTOM w0.102: v4(151.04,204.6) 152.18,205.74 v2(153.12,205.74) 154.83,205.74 PU5.3
PWR_FCH_S5: length 18.4
  TOP w0.254: Q4701.6 152.1,211.91 v4(152.92,212.72) ; v4(156.62,207.77) 155.43,207.77 PC50.1
  L3 w0.254: v4(152.92,212.72) 153.68,212.72 154.96,211.44 154.96,209.44 v4(156.62,207.77)
  BOTTOM w0.254: v4(156.62,207.77) 156.37,207.77 155.48,206.88 PU5.4 ; v4(152.92,212.72) 153.3,213.11 PC5428.1 154.53,213.42 Q6704.1 153.72,214.62 153.58,214.76 153.58,215.14 153.7,215.26 Q6704.2
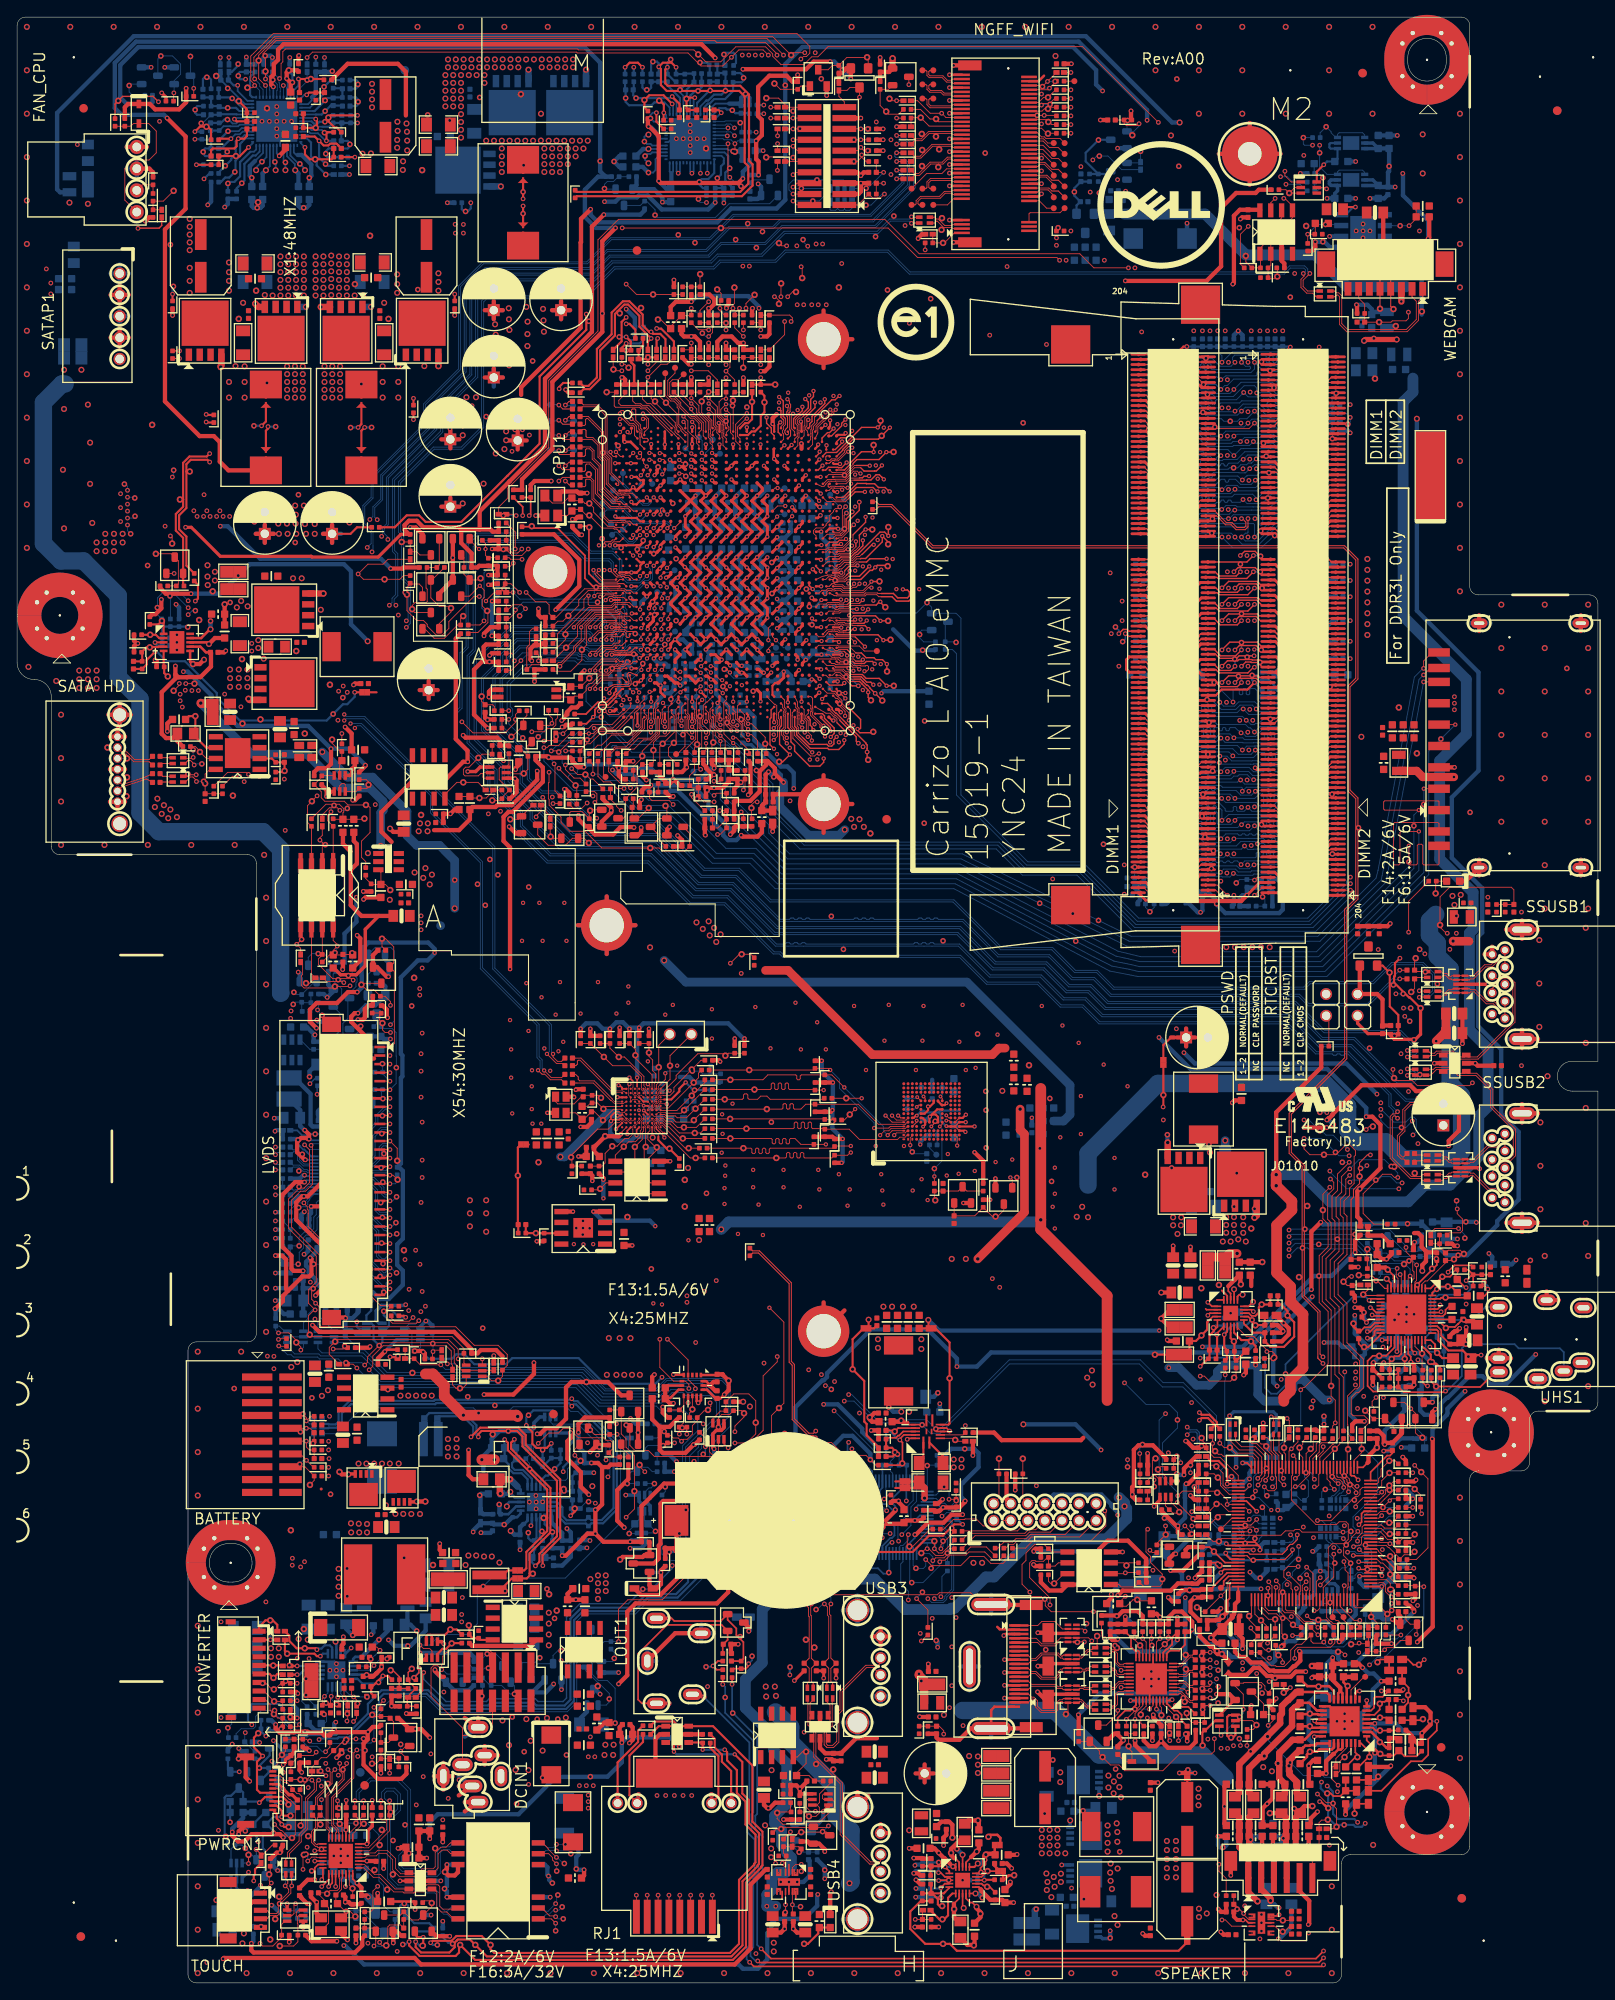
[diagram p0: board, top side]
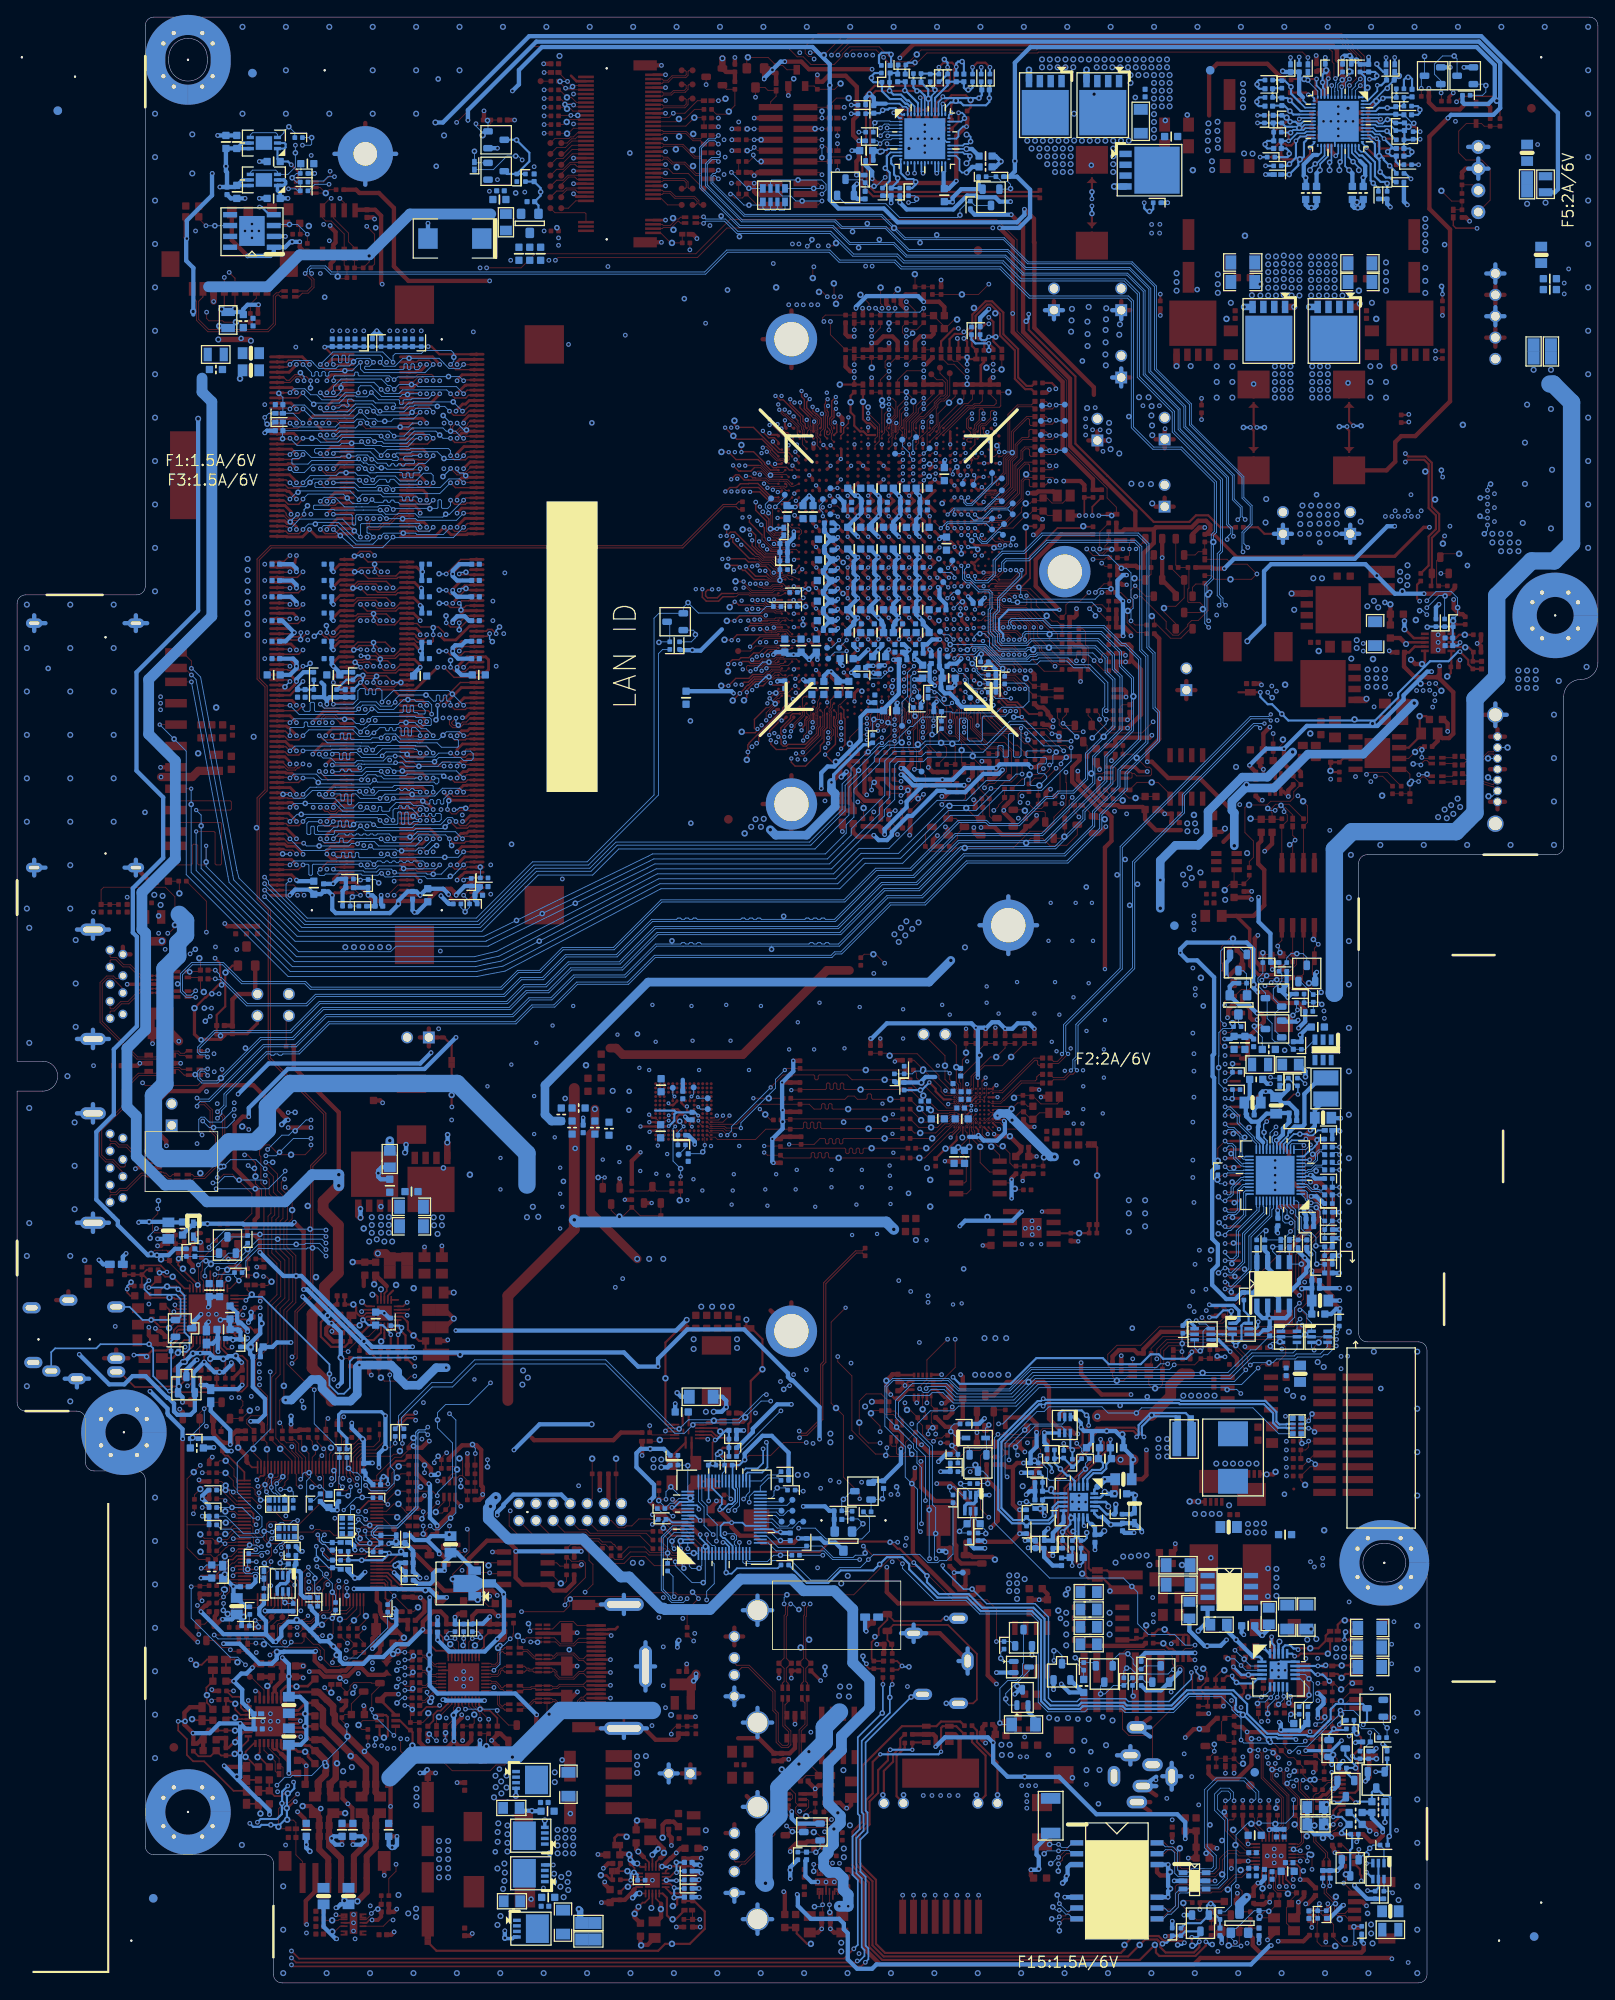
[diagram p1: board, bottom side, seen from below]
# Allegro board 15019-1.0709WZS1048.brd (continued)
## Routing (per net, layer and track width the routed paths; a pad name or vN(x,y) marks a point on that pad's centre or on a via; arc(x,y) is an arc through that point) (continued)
PWR_FCH_VCNTL: length 5.5
  TOP w0.102: PC49.1 PR5475.2 163.74,206.43 v4(162.9,205.59)
  BOTTOM w0.102: v4(162.9,205.59) v2(161.86,205.59) 160.94,205.59 160.92,205.61 PU5.6
PWR_GFX_BST1: length 5.4
  BOTTOM w0.203: PU5407.28 75.12,213.77 74.71,213.36 74.71,212.09 74.42,211.8 v2(73.89,211.8)
  BOTTOM w0.508: PR5404.1 73.22,212.47 v2(73.89,211.8)
PWR_GFX_BST1_SW1: length 2.6
  BOTTOM w0.508: PR5404.2 70.49,212.47 v2(69.86,213.11) 70.49,213.74 PC5411.1
PWR_GFX_COMP: length 5.4
  BOTTOM w0.203: PU5407.48 79.57,219.86
  BOTTOM w0.254: 79.57,219.86 79.57,219.95 81.03,221.41 v2(81.11,221.41) 81.06,221.46 PC5417.2 PC5416.2
PWR_GFX_COMP_FB: length 2.3
  BOTTOM w0.254: v2(79.92,224.69) 79.94,224.66 80.74,224.66 PR5415.2 81.06,224.35 PC5417.1
PWR_GFX_CSCOMP: length 57.8
  TOP w0.254: PR5414.1 65.5,209.55 84.62,209.55 85.57,210.5 85.57,212.56 85.15,212.98 85.15,220.73 84.51,221.36 76.02,221.36 75.34,222.04 75.34,223.93 v4(75.09,224.18) 75.57,224.66 76.59,224.66 v4(77.12,224.13)
  BOTTOM w0.203: 78.37,221.04 PU5407.45
  BOTTOM w0.254: PC5414.1 v4(75.09,224.18) 75.09,224.59 74.89,224.79 74.41,224.79 v2(74.41,224.79) 74.4,224.79 74.2,224.59 PC5425.2 ; v4(77.12,224.13) PR5425.1 PR5428.2 78.2,223.39 PR5417.2 PC5419.2 78.37,221.53 78.37,221.04
PWR_GFX_CSN1: length 59.6
  TOP w0.254: PG5402.2 v4(59.22,207.9)
  L3 w0.254: v4(59.22,207.9) 58.99,208.13 56.17,208.13 54.67,206.63 49.02,206.63 47.79,207.87 47.79,224.44 49.51,226.16 70.89,226.16 71.85,225.2 71.85,224.45 v4(72.17,224.13)
  BOTTOM w0.254: v4(72.17,224.13) PR4685.2 ; v2(59.22,207.01) v4(59.22,207.9)
PWR_GFX_CSP1: length 8.9
  BOTTOM w0.203: 75.77,220.01 76.37,219.41 PU5407.40
  BOTTOM w0.254: PR5408.1 71.15,221.55 PC5426.1 v2(71.22,220.52) 71.22,220.08 71.61,219.68 74.25,219.68 74.58,220.01 75.77,220.01
PWR_GFX_CSP2: length 6.7
  TOP w0.254: v4(76.67,219.84) 75.65,220.85 73.97,220.85 v1(73.41,220.29) 73.41,219.42 PR5429.1
  BOTTOM w0.203: v4(76.67,219.84) 76.77,219.73 PU5407.41
PWR_GFX_CSREF: length 10.6
  TOP w0.254: v4(76.67,220.7) 77.5,219.86 PC5413.1
  BOTTOM w0.203: v4(76.67,220.7) 76.67,220.56 77.17,220.05 PU5407.42
  BOTTOM w0.254: PR4685.1 72.17,221.55 PC5426.2 72.11,220.85 v2(72.44,220.52) 76.49,220.52 v4(76.67,220.7)
PWR_GFX_CSSUM: length 9
  BOTTOM w0.203: PU5407.43 77.57,220.17
  BOTTOM w0.254: PR5409.1 73.19,221.74 73.44,221.49 v2(73.69,221.49) 73.95,221.49 74.2,221.74 PC5425.1 PC5414.2 PR5426.2 76.11,222.01 77.57,220.55 77.57,220.17
PWR_GFX_DIFF: length 9.2
  BOTTOM w0.203: 80.59,219.62 80.37,219.41 PU5407.50
  BOTTOM w0.254: 80.59,219.62 80.83,219.87 81.03,219.87 81.58,220.41 82.85,220.41 83.79,221.35 PR5413.1 84.79,222.38 85.02,222.61 v2(85.02,222.88) 85.02,223.09 84.65,223.46 PR5407.1
PWR_GFX_DIFF_R: length 4.2
  BOTTOM w0.254: PC5415.1 82.72,224.46 v2(82.72,225.63) 82.92,225.83 83.82,225.83 84.13,225.52 84.13,224.62 PR5407.2
PWR_GFX_DROOP: length 5.6
  BOTTOM w0.203: PU5407.46 78.77,220.76 78.81,220.8 78.81,220.83
  BOTTOM w0.254: PR5417.1 PC5419.1 80.11,221.78 v2(79.69,221.36) 79.34,221.36 78.81,220.83 78.81,220.83
PWR_GFX_FB: length 8.8
  BOTTOM w0.203: PU5407.49 79.97,219.55 80.61,220.18
  BOTTOM w0.254: 80.61,220.18 80.67,220.25 80.88,220.25 81.56,220.93 82.44,220.93 v2(82.9,221.39) PR5413.2 82.9,223.39 PC5415.2 82.08,223.46 PC5416.1 81.95,224.35 PR5415.1
PWR_GFX_HG1: length 35
  L3 w1.016: v7(56.61,210.19) 55.02,210.19 53.91,211.3 53.91,215.95 55,217.04 67.34,217.04 71.46,212.92 71.64,212.92 71.66,212.9 v7(73.89,212.9)
  BOTTOM w0.203: PU5407.29 74.32,214.17 74.13,213.99 73.74,213.99 v2(73.49,213.74) 73.49,213.3 v7(73.89,212.9)
  BOTTOM w0.762: PU5401.4 v7(56.61,210.19)
PWR_GFX_ILIM: length 4.2
  BOTTOM w0.203: v2(77.58,221.49) 77.58,221.18 77.97,220.79 PU5407.44
  BOTTOM w0.254: PR5428.1 78.14,222.05 v2(77.58,221.49)
PWR_GFX_ILIM_R: length 47.8
  TOP w0.254: v4(76.11,224.13) 75.85,223.88 75.85,222.25 76.13,221.97 84.62,221.97 85.66,220.94 85.66,213.19 86.08,212.77 86.08,210.29 84.83,209.04 65.5,209.04 PR5414.2
  BOTTOM w0.254: PR5425.2 77,222.44 PR5426.1 v4(76.11,224.13) 76.11,224.66 v2(76.49,225.04)
PWR_GFX_IOUT: length 5.5
  TOP w0.254: v4(79.31,220.57) 78.47,220.57 v1(78.34,220.45) 78.34,219.32 PR5402.1 PC5423.2
  BOTTOM w0.203: v4(79.31,220.57) 79.17,220.44 PU5407.47
PWR_GFX_LG1: length 28.7
  L3 w1.016: 63.22,223.14 65.88,223.14 v7(66.58,223.84) ; 63.22,223.14 60.55,223.14 v7(59.85,223.84) ; 63.22,223.14 63.22,220.92 63.79,220.34 68.71,220.34 72.8,216.25 v7(73.89,216.25)
  BOTTOM w0.203: v7(73.89,216.25) 73.67,216.25 73.41,216 v2(73.41,215.44) 73.7,215.16 74.13,215.16 74.32,214.97 PU5407.31
  BOTTOM w0.762: PU5403.4 v7(59.85,223.84) ; v7(66.58,223.84) PU5402.4
PWR_GFX_PHCONFIG: length 5.4
  TOP w0.254: PR5412.1 74.82,217.76 v4(74.82,218.81)
  BOTTOM w0.203: PU5407.38 74.51,217.77 v2(74.12,218.16) 74.12,218.54 74.39,218.81 v4(74.82,218.81)
PWR_GFX_ROSC: length 6.2
  BOTTOM w0.203: 83.09,213.87 82.79,214.17 PU5407.11
  BOTTOM w0.254: PR5411.2 82.88,210.84 82.88,211.8 v2(83.4,212.32) 83.22,212.5 83.22,213.74 83.09,213.87
PWR_GFX_SNB1:
  vias: v2(54.14,220.6)
PWR_GFX_SR: length 3.3
  TOP w0.254: PR5419.1 75.66,218.79 v4(75.68,218.81) 75.68,219.77 75.23,220.22 v1(75.14,220.22)
  BOTTOM w0.203: v4(75.68,218.81) 75.96,218.53 PU5407.39
PWR_GFX_SW1: length 18.2
  L3 w1.016: v7(73.89,214.57) 72.15,214.57 68.02,218.69 v7(61.31,218.69)
  BOTTOM w0.203: v7(73.89,214.57) PU5407.30
  BOTTOM w0.508: PC5411.2 73.26,214.57 v7(73.89,214.57)
  vias: v2(59.28,212.67) v7(54.9,215.54) v7(55.81,215.54) v7(56.73,215.54) v7(56.73,214.62) v7(56.73,213.71) v7(56.73,212.79) v7(56.73,211.88) v7(57.64,215.54) v7(58.55,215.54) v7(59.47,215.54) v7(60.38,215.54) v7(61.3,215.56) v7(61.7,214.62) v7(61.7,213.71) v7(61.7,212.79) v7(61.7,211.88) v7(62.21,215.54) v7(62.62,214.62) v7(62.62,213.71) v7(62.62,212.79) v7(62.62,211.88) v7(63.13,215.54) v7(63.53,214.62) v7(63.53,213.71) v7(63.53,212.79) v7(63.53,211.88) v7(64.04,215.54) v7(64.45,214.62) v7(64.45,213.71) v7(64.45,212.79) v7(64.96,215.54) v7(65.36,214.62) v7(65.36,213.71) v7(65.87,215.54) v7(66.28,214.62) v7(66.78,215.54)
PWR_GFX_SWN1: length 60.8
  TOP w0.254: PG5401.2 v4(59.22,208.74) ; v4(73.19,224.13) 72.65,224.66 71.69,224.66 v4(71.15,224.13)
  L3 w0.254: v4(71.15,224.13) 71.47,224.45 71.47,225.04 70.73,225.78 49.67,225.78 48.17,224.28 48.17,208.03 49.18,207.01 54.52,207.01 56.01,208.51 58.99,208.51 v4(59.22,208.74)
  BOTTOM w0.254: v2(59.22,209.55) v4(59.22,208.74) ; v4(73.19,224.13) PR5409.2 ; PR5408.2 v4(71.15,224.13)
PWR_GFX_TSENSE: length 68.9
  TOP w0.254: PR5421.2 PC5422.2 82.07,219.14 v4(82.41,218.81)
  L4 w0.254: v4(53.09,208.28) 52.56,207.75 49.33,207.75 47.15,209.93 47.15,224.79 48.6,226.24 78.72,226.24 82.46,222.5 82.46,218.86 v4(82.41,218.81)
  BOTTOM w0.203: PU5407.1 81.77,218.17 v4(82.41,218.81)
  BOTTOM w0.254: v4(53.09,208.28) 53.09,207.62 52.74,207.26 v2(52.48,207.26) 52.31,207.26 52.04,207.53 PR5423.2
PWR_GFX_VCC: length 4.6
  BOTTOM w0.203: PU5407.10 83.1,214.57 83.24,214.43 83.66,214.43 v2(83.78,214.31)
  BOTTOM w0.508: v2(83.78,214.31) 84.45,214.31 84.51,214.38 PC5420.1 84.81,214.31 PR5418.2
PWR_GFX_VDD: length 8.1
  BOTTOM w0.203: PU5407.51 80.77,219.31 80.98,219.51 81.36,219.51 81.73,219.87 83.35,219.87
  BOTTOM w0.508: 83.35,219.87 84.51,219.87 PC5418.1 84.74,220.55 85.2,221.01 v2(85.25,221.01) 85.25,220.99 85.69,220.55 PR5420.1
PWR_GFX_VR_HOT: length 5.1
  BOTTOM w0.203: PU5407.13 81.59,212.79
  BOTTOM w0.254: 81.59,212.79 81.59,211.75 80.88,211.05 80.12,211.05 79.84,210.77 v2(79.84,210.72) 79.84,210.41 80.26,209.99 PR5464.1
PWR_GFX_VRMP: length 6.4
  BOTTOM w0.203: 82.71,213.23 82.71,213.49 82.42,213.77 PU5407.12
  BOTTOM w0.254: PR5424.2 PC5424.1 81.95,210.76 v2(81.95,211.15) 82.37,211.57 82.37,212.54 82.71,212.88 82.71,213.23
PWR_GFX_VSS: length 5.1
  BOTTOM w0.203: 81.95,219.11 81.95,219.07 81.46,218.59 PU5407.52
  BOTTOM w0.254: 81.95,219.11 82.18,219.34 82.91,219.34 83.06,219.19 83.61,219.19 v2(83.7,219.1) 84.04,218.76 PC5418.2 85.63,218.76 PR5422.1
PWR_LED_YELLOW_C: length 13
  TOP w0.254: v1(32,19.56) 31.99,19.56 31.11,19.56 v4(30.97,19.42) 30.97,20.14 30.36,20.75 PWRCN1.9
  BOTTOM w0.254: Q1212.D 28.99,15.54 28.76,15.77 28.76,17.23 R1761.1 29.88,17.4 v2(30.01,17.53) 30.01,17.78 29.24,18.54 R1751.2 29.99,19.42 v4(30.97,19.42)
PWR_LED_YELLOW_C2: length 3.3
  BOTTOM w0.254: R724.2 28.99,19.94 R1751.1 27.47,18.54 v2(26.7,17.78)
PWR_VDDP_BOOT:
  vias: v1(21.31,159.46)
PWR_VDDP_BOOT_R: length 2.4
  TOP w0.508: v1(24.29,161.29) PR4812.2 PC4806.2
PWR_VDDP_CS: length 2.7
  TOP w0.254: PU4803.2 16.63,157.35 16.24,157.73 v1(15.58,157.73) PR4802.2
PWR_VDDP_EN: length 7.4
  TOP w0.254: PU4803.3 16.18,156.84 16.16,156.83 v4(16.14,156.83)
  BOTTOM w0.254: v4(16.14,156.83) 16.16,156.81 16.16,156.7 16.4,156.46 PC4804.1 PC48.1 16.99,158.62 R1763.2 R1764.1 R125.1 19.91,158.69 v2(19.97,158.62)
PWR_VDDP_FB: length 5
  TOP w0.254: PC4805.2 PR4803.2 14.64,155.64 PR4816.1 15.13,156.26 v1(15.53,156.26) 15.56,156.3 16.53,156.3 16.58,156.34 PU4803.4
PWR_VDDP_FB_R: length 33.2
  TOP w0.254: v4(16.14,155.75) 15.17,154.78 15.17,154.27 PR4803.1 PC4805.1 ; PG4801.1 v4(39.5,151)
  BOTTOM w0.254: v4(39.5,151) 39.5,150.47 38.64,149.61 38.13,149.61 v2(36.99,148.46) 36.23,147.7 26.07,147.7 23.38,150.39 23.38,150.91 20.24,154.05 20.23,154.05 19.64,154.64 17.48,154.64 16.37,155.75 v4(16.14,155.75)
PWR_VDDP_LGATE: length 15.6
  TOP w0.305: v1(20.58,154.31) 20.53,154.31 20.25,154.58 PU4803.6
  TOP w0.508: v7(21.88,154.81) 21.37,154.31 v1(20.58,154.31)
  TOP w0.762: v7(27.08,150.24) 27.21,150.11 PU4801.4
  L3 w1.016: v7(21.88,154.81) 27.47,154.81 28.18,154.09 28.18,151.34 v7(27.08,150.24)
PWR_VDDP_PG: length 3.2
  TOP w0.254: PU4803.1 17.15,159.16 v1(16.95,159.36) 16.53,158.94 PR4805.2
PWR_VDDP_PHASE: length 19.2
  TOP w0.305: v7(22.45,156.65) 22.26,156.84 PU4803.8
  TOP w0.508: PC4806.1 23.16,157.35 v7(22.45,156.65)
  L3 w1.016: v7(35.54,160.66) 33,158.12 25,158.12 23.54,156.65 v7(22.45,156.65)
  vias: v1(36.61,151.89)
PWR_VDDP_RF: length 3.2
  TOP w0.254: v1(17.64,152.86) 17.61,152.86 17.22,153.25 PR4807.1 17.15,154.04 PU4803.5
PWR_VDDP_SNB:
  vias: v1(32.67,155.83)
PWR_VDDP_UGATE: length 20.5
  TOP w0.305: v7(22.64,158.37) 22.56,158.37 21.54,157.35 PU4803.9
  TOP w0.762: PU4802.4 v7(35.85,162.56)
  L3 w1.016: v7(22.64,158.37) 24.04,159.77 31.93,159.77 34.73,162.56 v7(35.85,162.56)
  BOTTOM w0.508: v7(22.64,158.37) v2(22.64,159.34)
PWR_VDDQ_BOOT: length 4.7
  TOP w0.203: PU5001.18 142.02,80.67 141.74,80.95 141.74,81.52
  TOP w0.508: 141.74,81.52 142.46,82.25 142.48,82.25 PR5006.1 143.16,82.68 143.16,81.79 v1(143.21,81.74)
PWR_VDDQ_BOOT_L: length 2.7
  TOP w0.508: PR5006.2 PC5010.1 145.71,84.33 v1(145.72,84.34)
PWR_VDDQ_CS: length 5.1
  TOP w0.203: PU5001.13 144.15,78.36 144.47,78.04 144.92,78.04 145.03,78.14
  TOP w0.254: PC5003.2 PR5003.2 v1(145.65,79.38) 145.32,79.04 145.32,78.44 145.03,78.14
PWR_VDDQ_EN: length 5.8
  TOP w0.203: PU5001.8 142.02,76.06
  TOP w0.254: 142.02,76.06 142.02,75.44 v1(142.4,75.06) 142.4,74.83 142.46,74.77 R1810.2 142.46,73.03 R1808.2 142.72,72.83 C1796.1
PWR_VDDQ_FB: length 6.5
  TOP w0.203: PU5001.6 141.22,76.8 140.5,76.07 140.5,75.92 v4(140.41,75.83)
  TOP w0.254: PR5023.2 140.43,73.15 PC5013.2 140.43,75.81 v4(140.41,75.83)
  BOTTOM w0.254: v4(140.41,75.83) 140.04,76.2 140.04,76.63 v2(140.01,76.66) 140.25,76.9 PR5009.1
PWR_VDDQ_LGATE: length 13.8
  TOP w0.203: PU5001.15 144.11,79.16 v7(144.64,79.68)
  TOP w0.762: PU5007.4 145.07,89.79 v7(144.81,89.53)
  L4 w0.762: v7(144.81,89.53) 144.74,89.46 144.74,79.78 v7(144.64,79.68)
  BOTTOM w0.508: v2(144.82,90.57) 144.82,90.34 144.81,90.34 v7(144.81,89.53)
PWR_VDDQ_PHASE: length 22.8
  TOP w0.203: v7(143.42,80.52) 143.02,80.52 142.82,80.31 PU5001.16
  TOP w0.508: 144.43,81.53 144.43,82.68 PC5010.2
  L4 w0.762: v7(143.42,80.52) 143.42,82.17 140.11,85.47 140.11,96.61 139.61,97.12 v7(139.61,97.16)
  BOTTOM w0.508: v7(139.61,97.16) 139.48,97.28 v2(139.48,98.08)
  BOTTOM w1.016: PR5034.1 v7(141.38,98.55)
PWR_VDDQ_SENSE: length 46.8
  TOP w0.203: PU5001.5 140.47,76.73 140.01,76.27 140.01,76.23
  TOP w0.254: PG5001.2 v1(134.15,103.89) 134.15,102.51 v4(134.12,102.49) ; v4(138.46,72.14) 139.35,73.03 PR5023.1 139.54,73.15 PC5013.1 139.54,75.76 140.01,76.23
  L3 w0.254: v4(134.12,102.49) 134.12,102.46 130,98.35 130,85.67 134.65,81.03 134.65,77.98 137.68,74.96 137.68,72.92 v4(138.46,72.14)
PWR_VDDQ_SNB: length 3.7
  BOTTOM w0.508: PR5034.2 142.35,95.43 142.73,95.05 v2(142.73,94.74) 142.73,94.31 142.45,94.03 PC5017.1
PWR_VDDQ_TON: length 4.4
  TOP w0.203: PU5001.9 142.42,76.07
  TOP w0.254: PR5007.2 144.94,74.52 v1(144.41,75.06) 144.25,75.21 143.28,75.21 142.42,76.07
PWR_VDDQ_UGATE: length 24.4
  TOP w0.203: PU5001.17 v7(142.42,81.15)
  TOP w0.762: PU5006.4 v7(134.65,98.32)
  L4 w0.762: v7(142.42,81.15) 142.29,81.15 138.46,84.98 138.46,94.51 v7(134.65,98.32)
  BOTTOM w0.508: v2(134.62,99.24) 134.62,99.24 134.62,98.36 v7(134.65,98.32)
PWR_VDDQ_VDD: length 14.3
  TOP w0.203: PU5001.11 143.57,77.14 143.82,76.89
  TOP w0.254: PC5003.1 PR5003.1 147.9,79.38 148.67,78.6 v1(148.67,78.08) 149.45,77.3 149.45,75.61 148.27,74.42 146.65,74.42 PR5002.1 PC5018.1 144.64,76.07 143.82,76.89
PWR_VDDQ_VDDP: length 4.2
  TOP w0.203: PU5001.12 144.08,77.96 144.35,77.68
  TOP w0.254: PR5004.1 146.02,77.95 PC5009.1 144.94,76.96 v1(144.91,76.94) 144.35,77.5 144.35,77.68
PWR_VDDQ_VTTIN: length 1.4
  TOP w0.203: 141.38,80.63 141.62,80.39 PU5001.19
  TOP w0.254: 141,81.01 141.38,80.63
  vias: v1(140.65,81.66)
PWR_VDDQ_VTTREF: length 6.7
  TOP w0.203: PU5001.4 139.92,77.96 139.4,77.44
  TOP w0.254: PR5032.2 137.19,73.76 PC5014.1 137.96,75.11 v1(138.61,75.75) 138.61,75.77 139.27,76.43 139.27,77.26 139.33,77.35 139.34,77.38 139.4,77.44
PWR_VTT_EN: length 8.4
  TOP w0.203: PU5001.7 141.62,76.19 v4(141.27,75.84)
  TOP w0.254: v4(141.27,75.84) 141.27,74.36 141.49,74.14 141.49,74 R1810.1 141.57,73.03 R1809.2
  BOTTOM w0.254: v4(141.27,75.84) 141.27,76 142.23,76.96 C1797.1 143.88,76.96 144.48,77.57 v2(144.54,77.57)
PWRBTN_N: length 183.1
  TOP w0.102: v4(137.47,55.13) 137.47,55.14 137.83,55.5 R385.1
  L3 w0.127: v4(134.78,30.99) 134.78,32.33 133.85,33.26 130.74,33.26 130.5,33.5 128.81,33.5 127.92,32.61 119.32,32.61 117.58,34.35 113.47,34.35 112.65,33.53 110.62,33.53 v4(109.38,34.77) 93.82,34.77 90.19,38.41 89.32,39.27 89,39.27 83.87,44.4 72.52,44.4 67.89,39.77 67.89,37.61 66.21,35.93 48.61,35.93 46.37,33.69 41.78,33.69 40.03,31.94 30.38,31.94 27.72,29.29 v4(26.7,29.29)
  L4 w0.127: v4(137.47,55.13) 137.94,54.66 137.94,53.02 137.28,52.36 137.28,49.12 136.47,48.31 136.47,46.41 137.28,45.59 137.28,43.03 138.08,42.23 138.08,40.67 137.71,40.3 137.71,35.36 136.56,34.21 136.56,33.82 136.78,33.59 136.78,31.86 136.06,31.14 134.93,31.14 v4(134.78,30.99) ; v4(109.38,34.77) 109.38,35.48 106.55,38.32 106.55,43.79 105.74,44.61 105.74,47.74 103.16,50.32 v4(103.16,51.69)
  BOTTOM w0.102: v4(26.7,29.29) 26.64,29.22 C1760.1 27.72,27.11 R1756.2 ; v4(103.16,51.69) 103.08,51.77 103.08,53.64 104.25,54.81 104.25,55.84 104.87,56.45 U4101.47 ; v2(137.62,54.31) 137.47,54.46 v4(137.47,55.13)
PWRCN_DET_N: length 341.4
  TOP w0.102: v3(80.63,145.03) 80.63,144.28 R1669.1 ; v4(30.13,18.54) 30.84,17.83 30.98,17.83 31.84,16.98 32.16,16.98 v1(32.18,16.96) 32.56,17.34 32.56,20.24 C6722.2 32.8,20.61 31.93,21.47 31.84,21.47 31.05,22.27 30.92,22.27 30.44,22.75 PWRCN1.5 ; v4(155.4,38.37) 155.04,38.73 v1(154.59,38.73) ; U109.124 155.25,46.42 v4(155.31,46.48)
  L3 w0.127: v4(30.13,18.54) 30.13,22.95 32.42,25.23 32.42,27.14 34.3,29.02 40.41,29.02 40.53,28.89 44.04,28.89 48.65,33.5 65.96,33.5 68.13,31.33 82.47,31.33 88.29,37.15 90.37,37.15 93.51,34.01 99.3,34.01 100.64,32.67 101.42,32.67 101.44,32.69 117.97,32.69 118.82,31.84 124.91,31.84 125.34,31.41 129.01,31.41 129.17,31.57 131.04,31.57 131.97,32.5 133.53,32.5 133.93,32.1 133.93,30.64 134.52,30.05 140.67,30.05 144.02,33.4 145.74,33.4 146.12,33.78 147.2,33.78 151.94,38.52 155.25,38.52 v4(155.4,38.37) ; v3(80.63,145.03) 80.59,145 80.59,137.7 81.04,137.25 81.36,136.93 81.36,136.8 81.87,136.29 82.87,136.29 83.98,135.17 85.2,135.17 87.33,133.04 88.89,133.04 92.12,129.81 118.7,129.81 120.76,127.75 121.73,127.75 133.77,115.71 148.66,115.71 152.54,111.83 152.54,109.38 156.44,105.48 157.02,104.9 159.52,104.9 160.38,104.04 160.38,103 v4(159.6,102.21) ; v4(159.78,50.7) 158.78,49.71 158.78,47.88 157.74,46.84 155.61,46.84 155.31,46.54 v4(155.31,46.48)
  L4 w0.127: v4(163.36,99.21) 163.36,98.68 163.2,98.53 163.2,96.85 163.77,96.28 163.77,91.22 159.55,86.99 159.55,77.12 158.83,76.41 158.83,73.16 159.29,72.7 159.29,69.72 158.39,68.82 158.39,59.51 158.42,59.47 158.42,59.29 158.66,59.05 158.66,55.19 158.59,55.13 158.59,54.21 159.24,53.56 159.69,53.56 160.17,53.09 160.17,51.09 v4(159.78,50.7) ; v4(155.4,38.37) 155.7,38.66 155.7,42.62 155.14,43.18 155.14,43.89 155.3,44.11 155.3,46.47 v4(155.31,46.48)
  BOTTOM w0.102: v4(163.36,99.21) 163.74,99.59 163.74,101.03 163.47,101.3 163.09,101.3 162.51,100.71 161.12,100.71 159.62,102.21 v4(159.6,102.21)
PWRGD_3V: length 158.2
  TOP w0.102: R1857.2 R369.1 R368.1 C194.1 131.41,61.86 131.38,61.9 v4(131.38,61.94) ; R1668.1 61.31,137.1 60.74,136.53 v4(60.74,136.42)
  L3 w0.127: v3(131.48,70.61) 136.69,70.61 137.57,71.5 139.77,71.5 145.92,77.65 145.92,103.98 144.61,105.29 131.64,105.29 118.36,118.56 88.14,118.56 81.41,125.3 79.78,125.3 69.69,135.39 61.77,135.39 v4(60.74,136.42)
  L4 w0.127: v4(131.38,61.94) 131.38,70.51 v3(131.48,70.61)
  BOTTOM w0.102: v4(131.38,61.94) 131.38,62.56 131.71,62.89 v2(131.71,62.99)
PWRGD_3V_B_1: length 5.2
  TOP w0.102: Q37.6 135.05,56.25 136,55.3 v1(136,55.09) 135.95,55.09 135.82,54.97 135.25,54.97 R380.2 134.4,55.82 Q37.5
PWRGD_3V_D: length 8.2
  TOP w0.102: Q1246.D 60.93,134.33 62.16,133.1 64.17,133.1 64.99,133.92 Q78.S 66.37,133.92 v1(66.91,133.38)
PWRGD_3V_G: length 3.4
  TOP w0.102: R1668.2 60.33,137.79 Q1246.G 58.68,136.14 v1(57.72,136.14)
PWRGD_3V_LL: length 4.5
  TOP w0.102: v1(133.23,61.37) 133.12,61.37 132.86,61.11 132.86,59.33 ; 132.86,59.33 132.3,58.77 R369.2 ; 132.86,59.33 132.89,59.36 133.21,59.36 133.75,58.82 Q37.3
PWRGD_PS_L: length 5.1
  BOTTOM w0.102: Q1226.2 153.91,48.37 C525.2 154.11,49.02 v2(154.21,49.12) 154.21,49.39 153.57,50.03 R656.1 153.26,51.05 R657.2
PWRGD_PS_L1: length 4.1
  BOTTOM w0.102: Q1226.5 153.91,44.75 v2(153.65,44.5) 153.54,44.39 R1831.2 152.69,44.7 153.26,45.27 Q1226.6
PWRGD_PS_L2: length 3.2
  BOTTOM w0.102: Q1226.3 154.56,48.05 155.07,48.56 155.53,48.56 v2(156.07,49.1) 156.07,49.07 156.12,49.02 R1842.1
PWROK3_1: length 4.5
  TOP w0.102: R309.2 160.63,59.69 v1(160.61,59.66) 159.7,58.76 159.7,58.16 159.12,57.58 U109.29
PWROK3_1_R: length 36.9
  TOP w0.102: R366.2 R1857.1 133.08,58.31 v3(133.08,58.85) ; R309.1 v4(163.33,59.69)
  L3 w0.127: v4(163.33,59.69) 163.2,59.56 151.75,59.56 150.73,58.55 149.12,58.55 148.66,59.01 148.66,59.22 148.39,59.5 148.13,59.5 147.3,60.33 144.11,60.33 143.77,59.98 143.71,59.98 143.04,59.31 137.71,59.31 137.26,58.86 136.6,58.86 135.99,58.25 133.68,58.25 v3(133.08,58.85)
  BOTTOM w0.102: v2(133.08,58.06) v3(133.08,58.85)
PWROK3_2: length 4.3
  TOP w0.102: R373.1 139.4,53.47 140.42,54.48 v1(140.52,54.48) 140.52,54.58 140.71,54.78 U109.75
PWROK3_2_R: length 14.4
  TOP w0.102: v4(134.73,62.03) 135.35,61.4 R381.1 R384.1 ; R373.2 v4(137.47,53.47)
  L4 w0.127: v4(134.73,62.03) 134.73,62 134.65,61.93 134.65,54.86 135.58,53.94 137,53.94 v4(137.47,53.47)
  BOTTOM w0.102: v4(137.47,53.47) v2(137.47,52.53)
RDY#: length 5.6
  BOTTOM w0.102: TP4126.1 93.51,53.98 94.27,53.21 96.05,53.21 96.72,53.88 U4101.23
REMOTE1+: length 278.2
  TOP w0.127: U109.87 143.93,49.98 144.38,49.53 148.34,49.53 149.26,50.44 v4(149.26,50.67) ; RT3.1 v4(19.01,190.06)
  L3 w0.127: v4(78.39,80.39) 78.14,80.14 76.47,80.14 75.78,80.82 51.19,80.82 49.16,78.79 48.17,78.79 v4(47.79,79.17) ; v4(149.26,50.67) 149.21,50.72 147.58,50.72 146.77,49.91 142.27,49.91 141.82,49.47 140.38,49.47 139.65,48.73 133.37,48.73 133.19,48.91 130.44,48.91 129.67,49.68 122.63,49.68 122.49,49.82 120.44,49.82 119.29,50.98 111.34,50.98 110.36,50 106.08,50 105.66,49.58 98.64,49.58 98.15,50.07 97.28,50.95 92.54,50.95 91.92,51.56 90.18,51.56 85.31,56.43 82.64,56.43 v4(81.92,57.15)
  L4 w0.127: v4(81.92,57.15) 82.16,57.39 82.16,62.55 82.01,62.7 82.01,74.1 77.88,78.23 77.88,79.88 v4(78.39,80.39) ; v4(47.79,79.17) 46.87,79.17 44.58,81.46 44.58,120.91 46.78,123.11 46.78,125.73 49.57,128.52 49.57,145.9 47.28,148.2 47.28,155.18 42.41,160.05 42.41,161.45 35.7,168.16 27.82,168.16 25.92,170.07 25.92,172.36 25.25,173.02 20.98,173.02 20.61,173.4 20.61,183.24 18.19,185.65 18.19,190.27 18.37,190.45 18.62,190.45 v4(19.01,190.06)
  BOTTOM w0.127: v4(149.26,50.67) 149.26,50.09 148.64,49.47 C211.2 148.08,49.45 R404.1 ; v4(81.92,57.15) 81.92,57.15 81.92,57.89 v2(82.08,58.04)
REMOTE1-: length 271.9
  TOP w0.127: RT3.2 v4(19.01,190.94)
  L3 w0.127: v4(82.74,57.15) 83.2,56.69 85.42,56.69 90.29,51.82 92.03,51.82 92.64,51.2 97.38,51.2 98.75,49.83 105.55,49.83 105.97,50.25 110.25,50.25 111.23,51.23 119.39,51.23 120.55,50.08 122.59,50.08 122.74,49.93 129.78,49.93 130.55,49.16 133.29,49.16 133.47,48.98 139.54,48.98 140.28,49.72 141.72,49.72 142.16,50.16 146.67,50.16 147.48,50.98 148.77,50.98 148.94,51.14 149.6,51.14 149.66,51.08 v4(149.98,51.08) ; v4(47.25,78.54) 49.27,78.54 51.3,80.57 75.67,80.57 76.36,79.88 78.14,79.88 v4(78.39,79.63)
  L4 w0.127: v4(47.25,78.54) 47.15,78.54 44.68,81 44.33,81.36 44.33,121.02 46.53,123.21 46.53,125.84 49.32,128.62 49.32,145.8 47.02,148.09 47.02,155.08 42.16,159.94 42.16,161.34 35.59,167.91 27.71,167.91 25.66,169.96 25.66,172.25 25.14,172.77 20.87,172.77 20.35,173.29 20.35,183.13 17.94,185.55 17.94,190.37 18.27,190.7 18.76,190.7 v4(19.01,190.94) ; v4(82.74,57.15) 82.42,57.47 82.42,62.66 82.27,62.81 82.27,74.21 78.14,78.34 78.14,79.38 v4(78.39,79.63)
  BOTTOM w0.127: R400.2 147.33,48.58 C211.1 148.53,48.58 149.74,49.78 ; 149.74,49.78 149.98,50.03 v4(149.98,51.08) ; 149.74,49.78 v2(149.97,49.56)
REXT: length 3.4
  TOP w0.102: R2082.1 130.71,40.23 131.42,39.51 v1(131.42,39.49) 131.74,39.17 U118.18
RING2: length 41.4
  TOP w0.203: U6.31 162.79,73.59 163.1,73.28 v4(163.1,72.64)
  TOP w0.508: v4(163.1,72.64) 163.48,72.26 C157.1 ; R261.2 159.74,72.33 159.93,72.52 v4(159.93,72.57)
  L3 w0.508: UHS1.3 183.3,78.41 183.25,78.35 183.18,78.25 183.16,78.18 178.51,73.53 v4(177.72,73.53)
  BOTTOM w0.508: v4(159.93,72.57) 159.93,72.38 160.85,71.45 v2(161.32,71.45) 161.91,71.45 v4(163.1,72.64) 164.37,71.37 164.37,69.22 Q24.2 164.2,66.97 164.7,66.47 166.25,66.47 166.63,66.86 166.63,67.79 167.29,68.45 167.42,68.45 169.96,70.99 171.48,70.99 172.44,70.03 174.22,70.03 v4(177.72,73.53)
ROM_RST#: length 3
  TOP w0.102: v3(77.63,151) 77.93,151.3 CPU1.AW11
  BOTTOM w0.102: R1647.1 77.95,151.32 v3(77.63,151) 77.32,151 v2(76.51,150.2)
RSMRST*_R: length 3.1
  TOP w0.102: Q37.2 134.4,59.26 134.09,59.56 133.76,59.56 133.51,59.82 v1(133.51,60.07) 133.84,60.4 134.26,60.4 R384.2
RSMRST_N: length 293.9
  TOP w0.102: v3(54.06,167.77) 54.01,167.77 52.96,168.81 Q1247.G ; v4(136.66,53.47) 137.26,52.87 R382.2 R374.1
  L3 w0.127: v4(134.4,66.6) 118.94,66.6 108.71,76.83 100.36,76.83 97.06,73.53 97.06,70.61 95.66,69.22 88.29,69.22 86.44,71.06 85.73,71.77 63.96,71.77 61.62,69.42 42.27,69.42 40.22,71.47 39.57,71.47 39.25,71.79 39.25,73.11 35.97,76.39 35.97,77.63 35.92,77.69 35.92,85.08 36.44,85.61 36.44,90.24 35.74,90.94 35.74,106.48 33.41,108.81 33.41,130.81 29.85,134.37 15.69,134.37 13.61,136.44 13.61,151.38 10.92,154.07 10.92,165.21 16.87,171.16 18.74,171.16 21.7,174.12 v4(21.88,174.12)
  L4 w0.127: v3(54.06,167.77) 54,167.77 53.98,167.75 50.79,167.75 48.5,170.04 48.5,173.1 45.52,176.07 27.89,176.07 25.94,174.12 v4(21.88,174.12)
  BOTTOM w0.102: v4(136.66,53.47) 136.2,53.01 135.63,53.01 v2(134.27,54.38) 133.65,54.99 133.65,65.85 v4(134.4,66.6)
RSMRST_N_1: length 4.7
  TOP w0.102: Q1247.D 52.29,166.75 R2066.1 52.29,164.81 Q1248.G 54.05,164.15 v1(54.24,164.34)
RSMRST_N_FCH: length 32.5
  TOP w0.102: Q1248.D 52.93,162.24 v3(54.15,163.46) 54.66,162.96 54.66,162.07 54.44,161.85 54.44,161.1 v1(55.02,160.53) 55.1,160.44 55.1,159.17 53.92,157.99 52.93,157.99 R1677.2 ; CPU1.AE4 72.13,162.6 71.83,162.9 71.31,162.9 71.11,163.11 70.69,163.11 70.68,163.1 70.32,163.1 70.31,163.11 66.42,163.11 63.08,159.77 C78.1 62.26,160.21 62.26,161.23 61.89,161.59 60.66,161.59 v4(59.57,162.69)
  L3 w0.127: v3(54.15,163.46) 54.15,163.43 54.45,163.13 55.77,163.13 55.79,163.16 59.1,163.16 v4(59.57,162.69)
RST#: length 9.4
  TOP w0.076: 72.06,99.82 72.06,100.22 72.2,100.36 72.41,100.36 72.56,100.51 72.56,100.74 72.81,100.99 U902.H5
  TOP w0.102: C9019.1 R90046.2 68.45,95.57 68.82,95.94 68.82,97.05 v1(69.65,97.89) 70.21,97.89 71.13,98.81 71.56,98.81 72.06,99.3 72.06,99.82
RSVD_AN30: length 7.5
  TOP w0.102: TP212.1 99.15,155.83 98.57,156.42 96.11,156.42 96.03,156.5 93.8,156.5 CPU1.AN30
RSVD_U30: length 7.7
  TOP w0.102: v4(96.27,172.69) 96.08,172.5 95.77,172.5 95.55,172.27 95.55,172.15 95.05,171.65 95.05,171.04 94.68,170.67 94.68,170.55 94.36,170.23 93.5,170.23 93.2,169.93 93.2,169.61 93.5,169.3 CPU1.U30
  BOTTOM w0.102: TP210.1 95.16,173.81 v4(96.27,172.69)
RSVD_U31: length 7.2
  TOP w0.102: CPU1.U31 94.3,169 94.8,169.49 95.65,169.49 95.68,169.52 96.33,169.52 96.34,169.52 96.38,169.52 96.78,169.92 96.78,171.7 v4(97.06,171.97)
  BOTTOM w0.102: v4(97.06,171.97) 97.06,172.21 97.44,172.59 97.44,173 TP211.1
RT: length 3.3
  TOP w0.102: R79628.1 35.72,33.27 v4(35.97,33.53)
  BOTTOM w0.102: U120.10 36.37,33.93 v4(35.97,33.53) 35.97,32.94 v2(36.17,32.74)
RT9025_ADJ: length 10.5
  TOP w0.254: PG9001.1 58.61,97.74 v1(58.61,94.46) 58.61,88.76 C9008.1 R90030.1
RT9025_ADJ_FB: length 5.2
  TOP w0.254: U9001.7 61.69,87.71 R90031.1 v1(60.71,87.72) 59.55,87.72 R90030.2 C9008.2
RTL_ISOLATE_N: length 24.6
  TOP w0.102: v4(28.43,4.62) 28.74,4.32 29.93,4.32 30.96,5.35 R1817.1 30.96,6.85 31.34,7.22 Q36.6 ; U16.20 35.18,15.06 35.17,15.07 35.09,15.07 35.02,15 34.64,15 34.57,15.07 33.64,15.07 v1(33.56,14.99) 33.46,14.89 v4(33.46,13.28)
  L4 w0.127: v4(33.46,13.28) 33.46,7.13 33.25,6.92 30.72,6.92 v4(28.43,4.62)
  BOTTOM w0.102: v4(28.43,4.62) 28.56,4.75 v2(28.56,6.58) 28.52,6.62 R377.2
RTL_ISOLATE_N_1: length 6.5
  TOP w0.102: Q36.5 32.16,7.87 32.41,8.12 32.41,9.08 v4(32.6,9.27)
  BOTTOM w0.102: R406.1 33.79,8.45 C1798.1 ; R406.1 32.8,9.07 v4(32.6,9.27) ; R406.1 R1816.2 31.42,8.8 31.42,8.8 30.95,9.27 v2(30.72,9.27)
RTL_ISOLATE_N_2: length 7.5
  TOP w0.102: Q36.2 32.93,7.87 32.8,7.75 ; 32.8,7.75 32.67,7.87 32.67,8.26 32.94,8.52 Q36.3 ; 32.8,7.75 32.8,6.95 32.86,6.88 R378.2 32.86,4.81 32.37,4.32 v1(30.74,4.32)
RTN1: length 3.9
  TOP w0.254: CONVT1.1 28.33,41.68 29.07,42.42 v1(29.62,42.42) 29.93,42.42 30.45,41.9 R51.1
RTN2: length 3.1
  TOP w0.254: CONVT1.2 v4(29.65,40.15) 29.67,40.13 R53.1
  BOTTOM w0.254: v4(29.65,40.15) 29.65,40.95 v2(29.54,41.06)
RTN3: length 2.8
  TOP w0.254: R56.1 31.02,37.15 30,37.15 v1(29.98,37.13) 29.96,37.15 28.33,37.15 CONVT1.5
RTN4: length 3.2
  TOP w0.254: R59.1 31,36.15 30.47,36.15 v1(30.01,35.69) 29.54,36.15 CONVT1.6
RUN_0P95_EN1: length 10.4
  TOP w0.102: R179.2 R181.1 54.41,143.76 v1(53.98,143.33) 53.77,143.12 53.77,143.12 52.89,142.24 52.48,142.24 52.23,141.99 52.23,141.4 52.41,141.22 53.98,141.22 54.26,141.5 54.52,141.5 ; Q18.3 54.63,140.95 54.52,141.07 54.52,141.5 ; 54.52,141.5 54.62,141.6 Q18.2
RUN_0P95_EN2: length 8.2
  TOP w0.102: v1(55.61,138.35) 56.54,138.35 R172.1 56.74,138.68 R175.1 56.42,140.78 56.42,142.11 56.56,142.26 Q18.6 57.56,142.59 R171.2
RUN_0P95_EN3: length 7.7
  TOP w0.102: D20.3 59.79,144.78 R1776.2 ; C1768.2 58.9,144.4 R1776.2 ; R1776.2 59.79,141.99 v1(59.3,141.5) 59.26,141.46 58.01,141.46 57.87,141.6 Q18.5
RUN_0P95_EN4: length 5.5
  TOP w0.102: C857.1 C94.1 53.17,138.63 v1(54.11,138.63) 54.89,138.63 55.72,139.46 R174.1 R175.2
RUN_EN1: length 7
  TOP w0.102: R733.2 40.86,140.78 41.13,140.51 v1(41.13,140.18) 41.13,139.97 40.93,139.76 R732.1 39.67,139.4 Q65.3 38.4,140.19 38.26,140.34 38.01,140.34 37.75,140.08 Q65.2
RUN_EN2: length 18.6
  TOP w0.102: Q65.6 35.71,141.27 R1778.2 35.66,141.1 R722.1 35.1,139.88 35.1,139.87 35.59,139.38 35.59,138.66 36,138.26 38.28,138.26 38.72,137.82 v1(40.83,137.82) 41,137.82 41.31,137.52 41.31,134.59 40.32,133.6 40.32,131.68 40.8,131.2 R1178.1
RUN_EN_1P8V: length 5.7
  TOP w0.102: C862.1 43.09,128.52 43.67,127.94 v1(43.67,127.86) ; C862.1 42.58,129.94 U105.3 ; C862.1 41.5,128.52 R1179.2 40.8,129.22 R1178.2
RUNPWR_R6: length 4.9
  TOP w0.102: v1(36.86,145.47) 36.86,145.03 37.82,144.08 R718.2 C865.2 37.75,142.75 Q65.5
S0A3_GPIO: length 38.7
  TOP w0.102: CPU1.AE8 75.42,162.32 75.42,162.04 v3(75.47,161.99) ; v4(54.64,159.36) 54.16,158.88 R2021.2 ; R1813.1 R1724.1 57.25,168.56 57.69,168.12 57.69,167.58 57.98,167.29 58.59,167.29 v4(59.06,167.77)
  L3 w0.127: v4(59.06,167.77) 60.25,168.96 63.98,168.96 66.71,166.23 66.71,165.13 67.5,164.34 71.59,164.34 73.24,162.69 74.77,162.69 v3(75.47,161.99)
  BOTTOM w0.102: v4(54.64,159.36) 54.64,160.59 54.39,160.84 54.39,161.85 54.64,162.1 54.64,164.97 55.19,165.52 v2(55.77,165.52) 57.28,167.03 58.33,167.03 v4(59.06,167.77)
S0A3_GPIO_G: length 6.7
  TOP w0.102: Q1243.G 47.7,158.43 48.8,157.33 50.01,157.33 51.56,158.88 R2021.1 51.91,159.63 v1(52.2,159.92)
S_LVDS_BL_EN: length 5.4
  TOP w0.102: R144.1 42.01,25.65 v1(41.54,25.65) ; R144.1 R139.1 ; R144.1 R1985.1 43.66,26.29 R135.1 R143.2
S_TXE0+: length 5.8
  TOP w0.102: LVDS1.18 v4(43.63,92.5)
  BOTTOM w0.102: 42.56,93.46 41.79,94.23 41.53,94.23 41.46,94.3 U26.31 ; 42.56,93.46 v2(42.81,93.7) ; 42.56,93.46 42.93,93.09 42.93,92.35 43.09,92.2 43.33,92.2 v4(43.63,92.5)
S_TXE0-: length 6.5
  TOP w0.102: LVDS1.19 v4(43.63,91.5)
  BOTTOM w0.102: U26.32 41.46,93.9 41.53,93.97 41.69,93.97 42.68,92.98 42.68,92.25 42.98,91.95 43.18,91.95 v4(43.63,91.5) 43.93,91.5 v2(44.41,91.97)
S_TXE1+: length 4.6
  TOP w0.102: LVDS1.15 v4(43.63,95.5)
  BOTTOM w0.102: 42.6,95.03 41.53,95.03 41.46,95.1 U26.29 ; 42.6,95.03 43.16,95.03 v4(43.63,95.5) ; 42.6,95.03 v2(42.6,95.38)
S_TXE1-: length 5.3
  TOP w0.102: v1(44.53,93.98) 44.51,93.98 43.99,94.5 v4(43.63,94.5) LVDS1.16
  BOTTOM w0.102: U26.30 41.46,94.7 41.53,94.77 43.36,94.77 v4(43.63,94.5)
S_TXE2+: length 8.6
  TOP w0.102: LVDS1.12 v4(43.63,98.5) 44.48,97.65 v1(44.48,96.19)
  BOTTOM w0.102: v4(43.63,98.5) 43.33,98.19 42.75,98.19 42.38,97.82 42.38,96.57 41.64,95.83 41.53,95.83 41.46,95.9 U26.27
S_TXE2-: length 6.3
  TOP w0.102: LVDS1.13 v4(43.63,97.5)
  BOTTOM w0.102: 42.63,97.03 42.63,97.71 42.86,97.94 43.19,97.94 v4(43.63,97.5) ; 42.63,97.03 42.63,96.46 41.74,95.57 41.53,95.57 41.46,95.5 U26.28 ; 42.63,97.03 v2(42.93,97.03)
S_TXE3+: length 8.6
  TOP w0.102: LVDS1.8 v4(43.63,102.5)
  BOTTOM w0.102: 41.08,99.82 41.97,100.71 41.97,101.47 42.98,102.49 43.62,102.49 v4(43.63,102.5) ; 41.08,99.82 v2(40.83,100.08) ; 41.08,99.82 40.22,98.96 40.22,98.77 39.58,98.13 U26.23
S_TXE3-: length 8.6
  TOP w0.102: LVDS1.9 v4(43.63,101.5)
  BOTTOM w0.102: v4(43.63,101.5) 43.63,101.85 43.25,102.23 43.09,102.23 42.53,101.67 ; 42.53,101.67 42.22,101.37 42.22,100.61 40.47,98.86 40.47,98.66 39.98,98.17 U26.24 ; 42.53,101.67 v2(42.76,101.45)
S_TXEC+: length 7.3
  TOP w0.102: LVDS1.10 v4(43.63,100.5)
  BOTTOM w0.102: v2(41.33,98.93) 41.64,98.93 ; 41.64,98.93 41.64,99.15 42.59,100.1 43.23,100.1 v4(43.63,100.5) ; 41.64,98.93 41.64,96.87 41.4,96.63 41.31,96.63 41.24,96.7 U26.25
S_TXEC-: length 7.3
  TOP w0.102: LVDS1.11 v4(43.63,99.5)
  BOTTOM w0.102: 42.45,99.6 41.9,99.05 41.9,96.77 41.51,96.38 41.31,96.38 41.24,96.3 U26.26 ; 42.45,99.6 v2(42.68,99.36) ; 42.45,99.6 42.7,99.85 43.28,99.85 v4(43.63,99.5)
S_TXO0+: length 14.9
  TOP w0.102: v4(43.63,82.01) 43.63,81.84 43.29,81.5 LVDS1.29
  BOTTOM w0.102: U26.41 38.38,90.67 38.41,90.64 38.41,89.82 40.85,87.38 40.85,83.53 41.11,83.27 ; v4(43.63,82.01) 43.31,82.01 43.19,81.88 43.19,81.58 43.06,81.45 42.93,81.45 41.11,83.27 ; 41.11,83.27 v2(41.36,83.52)
S_TXO0-: length 15
  TOP w0.102: LVDS1.30 42.93,80.5 v4(43.63,81.2)
  BOTTOM w0.102: 42.91,81.2 42.83,81.2 40.6,83.43 40.6,87.27 38.16,89.71 38.16,90.45 37.98,90.64 U26.42 ; 42.91,81.2 v4(43.63,81.2) ; 42.91,81.2 v2(42.91,80.82)
S_TXO1+: length 13.4
  TOP w0.102: v4(43.63,83.64) 43.49,83.5 LVDS1.27
  BOTTOM w0.102: U26.39 39.18,90.88 39.1,90.81 39.1,90.17 41.59,87.69 41.59,84.4 42.91,83.08 43.06,83.08 43.19,83.2 43.19,83.51 43.31,83.64 v4(43.63,83.64) 43.78,83.64 44.34,83.07 v2(44.4,83.07)
S_TXO1-: length 12.8
  TOP w0.102: LVDS1.28 43.06,82.5 43.38,82.82 v4(43.63,82.82)
  BOTTOM w0.102: 42.73,82.9 42.8,82.82 v4(43.63,82.82) ; 42.73,82.9 41.33,84.29 41.33,87.58 38.85,90.06 38.85,90.74 38.78,90.82 U26.40 ; 42.73,82.9 v2(42.48,82.65)
S_TXO2+: length 10.8
  TOP w0.102: LVDS1.25 v4(43.63,85.5)
  BOTTOM w0.102: v2(42.65,86.56) 42.32,86.56 ; 42.32,86.56 42.32,85.12 42.69,84.75 43.05,84.75 43.63,85.33 v4(43.63,85.5) ; 42.32,86.56 42.32,87.99 39.9,90.41 39.9,90.74 39.98,90.82 U26.37
S_TXO2-: length 10.8
  TOP w0.102: LVDS1.26 v4(43.63,84.5)
  BOTTOM w0.102: v2(42.83,84.15) 42.83,84.5 ; 42.83,84.5 42.58,84.5 42.07,85.01 42.07,87.89 39.65,90.31 39.65,90.74 39.58,90.82 U26.38 ; 42.83,84.5 v4(43.63,84.5)
S_TXO3+: length 7.3
  TOP w0.102: LVDS1.20 v4(43.63,90.5)
  BOTTOM w0.102: v2(42.55,91.29) 42.2,91.29 ; 42.2,91.29 42.2,92.77 41.54,93.43 41.31,93.43 41.23,93.5 U26.33 ; 42.2,91.29 42.2,90.42 42.45,90.17 43.3,90.17 v4(43.63,90.5)
S_TXO3-: length 7.3
  TOP w0.102: LVDS1.21 v4(43.63,89.5)
  BOTTOM w0.102: 42.76,89.92 43.22,89.92 v4(43.63,89.5) ; 42.76,89.92 42.35,89.92 41.94,90.32 41.94,92.66 41.44,93.17 41.31,93.17 41.24,93.1 U26.34 ; 42.76,89.92 v2(42.76,89.56)
S_TXOC+: length 8.3
  TOP w0.102: LVDS1.22 v4(43.63,88.5)
  BOTTOM w0.102: v2(44.33,88.95) 43.88,88.5 v4(43.63,88.5) 43.43,88.3 43.06,88.3 41.46,89.9 41.46,92.48 41.24,92.7 U26.35
S_TXOC-: length 8.3
  TOP w0.102: LVDS1.23 v4(43.63,87.5)
  BOTTOM w0.102: v2(44.43,87.64) 44.36,87.64 44.21,87.5 v4(43.63,87.5) 43.63,87.59 43.18,88.04 42.96,88.04 41.21,89.79 41.21,92.12 41.03,92.3 U26.36
SA0_DIM1: length 5
  TOP w0.102: v4(132.75,129.03) 132.43,129.35 DIMM1.197
  BOTTOM w0.102: v4(132.75,129.03) 132.56,129.22 R165.2 131.8,129.29 R163.1 130.78,130.22 130.8,130.24 v2(130.8,130.55)
SA0_DIM2: length 4.9
  TOP w0.102: DIMM2.197 145.13,129.35 v4(144.81,129.03)
  BOTTOM w0.102: v2(142.68,128.7) 143.08,129.1 R2055.2 144.75,129.1 v4(144.81,129.03) 144.94,129.16 R2056.1
SA1_DIM1: length 5.5
  TOP w0.102: DIMM1.201 131.85,128.15 v4(132.75,127.25)
  BOTTOM w0.102: v4(132.75,127.25) 132.05,126.56 R1634.2 132.05,125.84 v2(132.57,125.32) 133.07,125.82 R1635.1
SA1_DIM2: length 5.2
  TOP w0.102: DIMM2.201 145.71,128.15 v4(144.81,127.25)
  BOTTOM w0.102: R2061.2 R2062.1 146.02,126.81 v2(145.76,127.07) 145.58,127.25 v4(144.81,127.25)
SATA__RXN0_C: length 5.9
  TOP w0.102: C149.2 15.46,142.88 13.64,142.88 12.74,143.78 12.26,143.78 HDD1.5
  BOTTOM w0.102: HDD1.5 v1(12.86,143.27)
SATA__RXP0_C: length 6
  TOP w0.102: C151.2 15.46,143.13 13.75,143.13 12.85,144.03 12.26,144.03 HDD1.6
  BOTTOM w0.102: HDD1.6 v1(10.57,144.54)
SATA__TXN0_C: length 5.8
  TOP w0.102: HDD1.3 12.26,140.22 12.36,140.22 14.4,140.89 15.01,141.09 C142.2
  BOTTOM w0.102: HDD1.3 12.48,140.73 12.8,141.05 v1(12.86,141.05)
SATA__TXP0_C: length 5.9
  TOP w0.102: HDD1.2 12.26,139.97 12.4,139.97 12.42,139.98 15.07,140.84 15.18,140.84 C141.2
  BOTTOM w0.102: v1(12.8,138.84) 12.37,138.84 HDD1.2
SATA_CALRN: length 8.2
  TOP w0.203: CPU1.AW2 70.8,151.4 70.15,150.75 70.15,150.52 69.16,149.53 68.18,149.53 67.62,148.97 67.62,148.31 v3(67.42,148.11) 66.63,147.32 R586.2
  BOTTOM w0.203: v3(67.42,148.11) v2(68.36,148.11)
SATA_CALRP: length 6.3
  TOP w0.203: CPU1.AW1 70.1,151.13 69.84,150.87 69.84,150.68 68.99,149.83 67.95,149.83 66.58,148.46 R1644.2
SATA_LED_N_C_1: length 9
  TOP w0.127: v4(27.08,13.97) v1(27.08,14.99)
  L3 w0.127: v4(27.08,13.97) 24.04,10.92 v4(24.04,10.54)
  BOTTOM w0.127: Q9646.3 27.03,14.02 v4(27.08,13.97) ; Q9646.6 25.04,10.75 R80201.2 24.23,10.73 v4(24.04,10.54)
SATA_X1: length 8.2
  TOP w0.102: X54.3 65.37,101.8 R90057.2 66.34,101.04 C9025.1 67.58,101.92 v1(68.56,100.94) 68.56,100.99 69.78,102.21 70.71,102.21 U902.F1
SATA_X2: length 5.3
  TOP w0.102: U902.E1 70.74,102.54 68.89,102.54 v1(68.61,102.26) 67.91,102.96 R90076.1 67.13,102.96 66.73,102.57 R90057.1
SATA_X2_R: length 6.5
  TOP w0.102: v1(68.33,103.56) 68.04,103.85 R90076.2 66.43,103.85 C9024.1 66.01,103.67 65.18,102.84 63.28,102.84 63.02,103.11 X54.1
SATAHDR_RX_DN0: length 55.4
  TOP w0.102: v4(20.72,142.49) 20.72,142.6 20.3,143.02 19.99,143.02 19.63,142.66 L4103.4 ; CPU1.AV1 70.5,152.36 70.43,152.43 68.41,152.43 67.66,151.68 v3(67.66,151.4)
  L3 w0.102: v3(67.66,151.4) 67.4,151.13 arc(67.35,151.09) 67.29,151.05 arc(67.14,150.98) 66.98,150.96 arc(66.88,150.91) 66.79,150.84 66.71,150.76 arc(66.48,150.58) 66.21,150.46 arc(66.18,150.45) 66.15,150.44 arc(66.01,150.42) 65.86,150.41 arc(65.41,150.25) 65.03,149.96 64.75,149.69 arc(64.6,149.56) 64.44,149.46 arc(64.14,149.34) 63.81,149.3 56.7,149.3 arc(55.64,149.16) 54.67,148.74 arc(54.27,148.47) 53.92,148.15 52.87,147.1 arc(52.4,146.72) 51.88,146.44 arc(51.32,146.27) 50.73,146.22 47.41,146.22 47.19,146.19 46.17,146.09 46.17,146.09 27.17,144.17 27.17,144.17 26.97,144.15 26.32,143.99 26.15,143.95 26.08,143.93 26.03,143.92 22.9,143.15 21.36,143.15 arc(21.16,143.11) 20.99,143 20.89,142.91 arc(20.77,142.72) v4(20.72,142.49)
  BOTTOM w0.102: v4(20.72,142.49) 20.85,142.62 v2(21.62,142.62)
SATAHDR_RX_DN0_EMI: length 1.5
  TOP w0.102: L4103.3 16.9,142.66 C149.1
SATAHDR_RX_DN1: length 92.1
  TOP w0.102: v3(72.79,150.99) 72.79,151.11 CPU1.AW4 ; C9029.1 63.72,107.82 63.24,107.82 62.72,108.34 v3(62.72,108.69)
  L3 w0.102: v3(38.29,148.41) 38.29,148.41 49.19,148.41 53.53,152.75 56.02,152.75 56.83,153.56 65.74,153.56 66.18,153.11 71.15,153.11 72.58,151.67 72.58,151.17 72.77,150.99 v3(72.79,150.99)
  BOTTOM w0.102: 55.91,129.64 55.91,132.95 40.7,148.16 38.54,148.16 v3(38.29,148.41) ; 55.91,129.64 v2(56.27,129.64) ; 55.91,129.64 55.91,118.73 62.53,112.11 62.53,108.88 v3(62.72,108.69)
SATAHDR_RX_DN1_R: length 8
  TOP w0.076: U902.B2 70.88,104.36 70,104.36 69.97,104.4
  TOP w0.102: 69.97,104.4 69.79,104.4 65.98,108.2 C9029.2
SATAHDR_RX_DP0: length 55.4
  TOP w0.102: v3(67.03,151.4) 68.31,152.68 70.82,152.68 CPU1.AV2 ; L4103.1 19.52,143.27 20.5,143.27 v4(20.61,143.38)
  L3 w0.102: v4(20.61,143.38) 22.88,143.38 25.89,144.12 26.19,144.2 26.93,144.38 46.4,146.34 47.17,146.42 47.39,146.44 50.73,146.44 arc(51.27,146.5) 51.79,146.65 arc(52.28,146.91) 52.7,147.26 52.81,147.37 53.76,148.31 arc(54.13,148.65) 54.55,148.93 arc(55.58,149.38) 56.7,149.53 63.81,149.53 arc(64.23,149.61) 64.59,149.85 64.76,150.03 64.87,150.13 arc(65.27,150.43) 65.73,150.61 arc(65.79,150.63) 65.84,150.64 arc(65.97,150.64) 66.1,150.66 arc(66.12,150.67) 66.14,150.68 arc(66.36,150.77) 66.55,150.92 66.67,151.04 v3(67.03,151.4)
  BOTTOM w0.102: v4(20.61,143.38) v2(20.61,144.27)
SATAHDR_RX_DP0_EMI: length 1.5
  TOP w0.102: C151.1 16.9,143.34 L4103.2
SATAHDR_RX_DP1: length 92.1
  TOP w0.102: C9028.1 63.85,107.57 63.13,107.57 v3(62.01,108.69) ; CPU1.AW3 v3(72.1,151)
  L3 w0.102: v3(38.29,147.7) 38.31,147.7 38.79,148.18 49.29,148.18 53.63,152.52 56.11,152.52 56.92,153.33 65.64,153.33 66.09,152.88 71.05,152.88 72.35,151.58 72.35,151.25 v3(72.1,151)
  BOTTOM w0.102: 55.66,131.44 v2(55.33,131.44) ; 55.66,131.44 55.66,132.84 40.6,147.9 38.51,147.9 38.41,147.8 38.39,147.8 v3(38.29,147.7) ; 55.66,131.44 55.66,118.63 62.28,112.01 62.28,108.96 v3(62.01,108.69)
SATAHDR_RX_DP1_R: length 7.9
  TOP w0.076: U902.B1 70.74,104.18 70.02,104.18 69.98,104.15 69.97,104.15
  TOP w0.102: 69.97,104.15 69.68,104.15 65.88,107.95 65.67,107.95 65.57,107.85 65.57,107.49 65.39,107.31 C9028.2
SATAHDR_TX_DN0: length 57.5
  TOP w0.102: CPU1.AU4 71.79,153.3 71.57,153.3 71.4,153.13 71.4,152.87 71.6,152.27 71.6,152.02 71.48,151.89 71.12,151.89 71.11,151.91 70.69,151.91 70.68,151.89 70.32,151.89 70.31,151.91 69.96,151.91 69.7,151.85 69.5,151.73 69.17,151.54 v3(68.93,151.4) ; v4(20.96,141.35) 20.17,141.35 20,141.18 L4102.1
  L3 w0.102: v3(68.93,151.4) 68.44,150.91 65.16,149.03 64.18,148.48 63.16,148.48 61.66,147.95 52.97,144.9 52.45,144.86 24.81,142.27 24.35,142.23 23.8,142.01 22.11,141.35 v4(20.96,141.35)
  BOTTOM w0.102: v4(20.96,141.35) 20.07,141.35 v2(20,141.43)
SATAHDR_TX_DN0_EMI: length 1.6
  TOP w0.102: L4102.2 17.03,141.18 C142.1
SATAHDR_TX_DN1: length 91.1
  TOP w0.102: v3(60.97,106.78) 61.43,106.32 61.75,106.32 62.41,105.66 63.72,105.66 C9027.1 ; CPU1.AY1 70.95,150.15 70.95,150.11 v3(70.96,150.1)
  L3 w0.102: v3(39.53,146.82) 39.51,146.84 39.51,147.51 39.57,147.57 49.54,147.57 53.88,151.92 56.36,151.92 57.17,152.72 65.39,152.72 65.84,152.28 69.92,152.28 71.36,150.85 71.36,150.47 70.99,150.1 v3(70.96,150.1)
  BOTTOM w0.102: v3(60.97,106.78) 61.2,107.01 61.2,107.9 60.84,108.25 60.84,112.04 54.21,118.67 54.21,128.55 ; 54.21,128.55 54.21,131.06 48.38,136.89 48.38,138.92 40.21,147.09 39.8,147.09 v3(39.53,146.82) ; 54.21,128.55 v2(53.88,128.55)
SATAHDR_TX_DN1_R: length 7.4
  TOP w0.076: U902.D2 70.91,102.88 70.85,102.86 70.71,102.86 70.67,102.9 69.88,102.9 69.52,103.26 69.46,103.26 69.45,103.27
  TOP w0.102: C9027.2 67.44,105.28 69.45,103.27
SATAHDR_TX_DP0: length 57.4
  TOP w0.102: v3(69.33,150.9) 69.4,151.16 69.69,151.55 69.93,151.69 69.98,151.69 70.06,151.7 70.23,151.7 70.24,151.69 70.76,151.69 70.77,151.7 71.03,151.7 71.04,151.69 71.56,151.69 71.57,151.7 71.63,151.7 71.86,151.93 71.86,152.32 71.78,152.53 CPU1.AU3 ; v4(20.99,140.56) 20.99,140.68 20.57,141.1 20.28,141.1 19.68,140.5 L4102.4
  L3 w0.102: v3(69.33,150.9) 69.29,150.94 68.8,150.94 68.58,150.72 64.24,148.25 63.2,148.25 53.02,144.68 24.83,142.04 24.4,142 22.15,141.12 21.61,141.12 arc(21.41,141.08) 21.24,140.97 20.99,140.72 v4(20.99,140.56)
  BOTTOM w0.102: v2(21.83,140.59) 21.01,140.59 v4(20.99,140.56)
SATAHDR_TX_DP0_EMI: length 1.5
  TOP w0.102: C141.1 16.77,140.5 L4102.3
SATAHDR_TX_DP1: length 91.1
  TOP w0.102: CPU1.AY2 v3(71.7,150.2) ; C9026.1 63.72,105.92 62.52,105.92 v3(61.68,106.76)
  L3 w0.102: v3(71.7,150.2) 71.58,150.32 71.58,150.94 70.02,152.51 65.93,152.51 65.49,152.95 57.08,152.95 56.27,152.15 53.79,152.15 49.44,147.8 39.48,147.8 v3(39.02,147.35)
  BOTTOM w0.102: v3(61.68,106.76) 61.45,106.98 61.45,108 61.09,108.36 61.09,112.14 54.46,118.78 54.46,126.09 ; 54.46,126.09 54.46,131.17 48.63,137 48.63,139.03 40.32,147.35 v3(39.02,147.35) ; 54.46,126.09 v2(54.8,126.09)
SATAHDR_TX_DP1_R: length 7.4
  TOP w0.076: 69.63,103.45 69.64,103.44 69.64,103.39 69.95,103.08 70.78,103.08 U902.D1
  TOP w0.102: 69.63,103.45 67.55,105.54 65.84,105.54 65.67,105.71 65.67,105.99 65.36,106.3 C9026.2
SB3V: length 1291.6
  TOP w0.203: U54.9 89.53,9.8
  TOP w0.254: R6702.1 v4(76.93,63.18)
  TOP w0.305: C579.1 46.45,9.53 R775.1 v4(46.58,8.59)
  TOP w0.356: CPU1.AR15 82.18,154.5 82.43,154.75 82.43,154.79 v3(82.46,154.81) 82.33,154.81 82.22,154.92 82.2,154.92 81.72,155.4 CPU1.AP15
  TOP w0.381: v4(16.92,221.13) 17.42,220.64 R526.2 ; v4(19.72,170.31) 20.38,170.31 23.78,166.92 34.41,166.92 34.5,166.83 42.26,166.83 44.91,169.48 45.87,169.48
  TOP w0.508: R90066.2 v3(113.88,91.63) ; R184.2 152.62,107.12 147.35,101.85 v7(147.35,94.56) ; v4(124.2,31.37) 124.24,31.33 R2091.1 ; 54.6,154.78 53.47,153.65 53.47,148.39 v4(55.05,146.81) R2064.1 ; 54.6,154.78 54.82,154.56 v4(55.28,154.56) R2010.1 R79671.2 ; 54.6,154.78 54.6,156.32 54.87,156.59 R1679.2 R2012.1 v4(55.56,157.61) ; v4(136.81,58.39) 136.84,58.42 137.07,58.42 138.21,59.56 R364.1 R371.2 ; R137.2 60.52,156.53 60.08,156.09 60.08,154.84 v4(60.23,154.69) ; R137.2 61.25,156.53 61.44,156.72 R1676.2 ; R137.2 R777.1 ; R2029.2 40.17,119.63 40.17,122.2 v4(39.8,122.57) ; v4(83.47,134.37) 83.92,134.81 R1877.1 84.11,135.32 R79635.2 R79670.2 ; v4(74.18,140.13) 74.02,139.98 73.56,139.98 73.12,139.54 R1875.1 ; v4(165.13,204.09) 165.26,204.22 PR5475.1 ; 54.14,170.05 54.14,172.19 57.64,175.69 57.64,175.69 61.78,179.83 61.78,187.68 67.27,193.17 67.27,205.49 v4(68.66,206.88) ; 54.14,170.05 51.98,170.05 ; 54.14,170.05 55.41,170.05 55.66,169.8 R1813.2 R79673.2 ; R1669.2 80.3,142.62 80.65,142.26 80.65,142.09 81.29,141.45 81.47,141.45 v4(81.57,141.35) 81.38,141.35 80.87,140.84 R1876.1 ; v4(32.77,30.99) R1733.1 R1731.1 ; R1863.2 163.55,45.47 R313.1 163.61,44.96 v4(163.36,44.7) ; PR5206.1 114.33,64.39 115.22,63.5 124.49,63.5 124.77,63.78 ; v3(55.15,164.72) R1664.1 R1675.2 56.17,165.8 R1874.1 54.07,165.8 53.88,165.61 R2066.2 53.18,167.26 51.98,168.47 51.98,170.05 ; R742.1 33.12,25.78 R1758.2 33.05,24.89 v4(33.31,24.64) ; R531.1 47.43,73.93 v4(47.53,73.83) 47.72,73.63 R514.1 ; v4(39.89,112.7) 40.47,112.7 40.7,112.93 40.7,113.94 41.12,114.36 R79661.1 41.63,114.43 R483.1 ; R307.1 R1864.2 163.33,51.56 v4(163.36,51.54) ; R382.1 136.1,52.45 135.85,52.7 v4(135.85,53.47) 135.67,53.47 133.95,55.18 R380.1 ; R378.1 34.46,4.88 v4(37.42,4.88) ; R755.2 33.63,27.42 33.95,27.42 v4(34.2,27.18) ; R297.2 v4(163.33,54.61) ; v4(163.33,56.64) R682.1 R1826.2 ; 51.98,170.05 51.72,170.31 47.54,170.31 46.78,171.07 45.86,171.07 45.35,170.56 45.35,170.01 45.87,169.48 R2065.2 ; v4(85.57,139) 85.83,139.27 85.83,142.74 R1933.2 ; R1676.2 R582.2 ; R1676.2 R1666.1 ; R679.2 162.53,61.13 162.16,61.49 v4(162.16,61.52) ; v4(65.69,136.6) 65.69,136.14 66.52,135.32 R717.1 66.96,135.04 67.63,134.37 69.76,134.37 70.62,135.23 72.15,135.23 v4(72.19,135.19) ; v4(32.85,33.86) 32.67,34.04 R1734.1 ; R1785.1 29.69,14.54 30.39,15.24 v4(30.77,15.24) 30.89,15.37 30.89,15.75 31.08,15.94 R1752.1 ; R1665.1 v3(55.58,161.67) ; R312.2 163.36,47.5 v4(163.48,47.37) ; R2030.2 38.13,133.27 v4(39,132.41)
  TOP w1.27: 127.57,68.15 127.57,80.39 119.79,88.16 v7(119.79,89.28) 119.79,104.65 ; 148.24,68.05 148.24,68.5 149,69.27 149,70.48 150.48,71.96 150.48,78.23 149.03,79.68 149.03,81.46 147.4,83.08 147.4,88.65 149.18,90.42 149.18,91.44 v7(147.35,93.27) v7(147.35,94.56)
  L3 w0.508: v4(41.77,32.23) 41.44,32.23 40.57,31.37 37.12,31.37 36.74,30.99 v4(32.77,30.99) 30.13,28.35 v4(30.01,28.35) 28.96,27.3 27.72,27.3 27.08,27.94 27.08,28.19 25.43,28.19 v4(25.18,27.94) ; v4(41.05,4.65) 40.01,5.69 38.29,5.69 38.16,5.56 38.11,5.56 v4(37.42,4.88) 36.3,4.88 35.62,5.56 30.69,5.56 28.48,7.77 v4(28.48,11.43) ; v4(41.05,4.65) 41.54,5.13 41.54,7.72 42.4,8.59 v4(46.58,8.59) 46.59,8.6 48.84,8.6 49.82,7.62 v4(49.82,7.21) ; v4(41.05,4.65) 40.85,4.45 40.85,3.28 41.83,2.3 41.84,2.29 41.87,2.29 ; v4(47.4,80.9) 46.56,80.9 45.67,80.01 43.33,80.01 42.08,81.26 42.08,109.66 39.89,111.86 v4(39.89,112.7) 40.27,112.7 40.62,113.06 40.62,121.74 v4(39.8,122.57) 39,123.37 v4(39,132.41) 40.06,133.48 40.06,136.94 41.64,138.52 55.14,138.52 v4(56.57,137.08) 61.37,137.08 62.07,136.39 65.48,136.39 v4(65.69,136.6) ; v4(155.99,43.54) 162.19,43.54 v4(163.36,44.7) ; v4(33.31,24.64) 33.05,24.89 33.05,26.23 34,27.18 v4(34.2,27.18) ; v4(162.16,61.52) 160.89,60.25 148.8,60.25 148.73,60.33 148.47,60.33 147.3,61.49 143.14,61.49 142.65,61 v4(142.65,60.33) ; v4(137.62,63.63) 140.34,66.34 v4(141.89,66.34)
  L3 w1.27: 41.87,2.29 83.85,2.29 87.43,5.87 87.43,8.66 v4(87.74,8.97) v4(88.78,8.97)
  L4 w0.254: v4(76.93,63.18) 76.72,63.4 76.72,66.97 77.34,67.6 77.34,69 v4(75.47,70.87)
  L4 w0.381: v4(19.72,170.31) 19.72,171.15 19.2,171.67 19.2,171.86 18.44,172.62 18.44,175.61 18.77,175.94 18.77,176.44 18.05,177.15 18.05,181.3 15.48,183.88 15.48,203.66 17.51,205.69 17.51,216.99 18.32,217.81 18.32,219.74 v4(16.92,221.13)
  L4 w0.508: v4(150.17,211.71) v4(162.16,211.71) ; v3(113.88,91.63) 117.44,91.63 v7(119.79,89.28) ; 86.32,139.75 v4(85.57,139) ; 86.32,139.75 v4(90.89,139.75) ; 86.32,139.75 84.72,141.35 v4(81.57,141.35) ; v4(28.48,11.43) 28.48,13.59 30.13,15.24 v4(30.77,15.24) 32.27,16.74 32.27,21.6 31.78,22.08 31.78,22.99 30.49,24.28 30.49,26.31 30.01,26.8 v4(30.01,28.35) ; v4(41.77,32.23) 41.85,32.32 41.85,34.84 41.09,35.6 41.09,37.41 41.34,37.66 41.34,39.32 42.4,40.39 42.4,41.1 41.09,42.41 41.09,50.85 42.13,51.89 42.13,52.37 42.13,54.31 41.07,55.37 39.28,55.37 37.57,57.08 37.5,57.16 37.5,63.42 47.53,73.46 v4(47.53,73.83) 49.77,76.06 49.77,79.26 48.12,80.9 v4(47.4,80.9) ; v4(56.57,137.08) 56.6,137.11 56.6,137.4 55.05,138.94 v4(55.05,146.81) ; v4(55.28,154.56) 55.81,154.03 59.27,154.03 59.93,154.69 v4(60.23,154.69) ; v4(163.36,44.7) 163.36,45.14 163.48,45.27 163.48,47.37 v4(163.48,47.37) 164.14,48.03 164.14,50.61 163.36,51.4 v4(163.36,51.54) 163.33,51.56 v4(163.33,54.61) 163.33,54.69 162.67,55.35 162.67,55.98 v4(163.33,56.64) 163.33,57.86 162.03,59.16 162.03,61.39 v4(162.16,61.52) ; v4(136.81,58.39) 136.84,58.42 137.83,58.42 138.27,58.86 138.27,62.98 v4(137.62,63.63) ; v4(136.71,45.09) 135.9,45.9 135.9,48.31 134.93,49.28 134.93,51.79 135.85,52.7 v4(135.85,53.47) ; v4(74.18,140.13) 74.18,137.9 72.19,135.92 v4(72.19,135.19)
  L4 w1.524: v4(125.59,209.52) 124.09,208.03 101.76,208.03 101.66,208.13 101.02,208.13 100.34,208.81 100.34,209.45 100.11,209.68 100.11,212.09 99.5,212.7 98.35,212.7 97.44,213.61 89.72,213.61 89.34,213.23 87.82,213.23 87.79,213.21 83.71,213.21 82.24,211.74 82.24,211.55 80.22,209.52 72.57,209.52 69.92,206.88 v4(68.66,206.88)
  BOTTOM w0.254: v4(47.53,73.83) 47.53,73.66 48.17,73.03 50.88,73.03 51.4,73.55 52.34,73.55 53.5,72.39 57.23,72.39 57.95,73.1 65.72,73.1 68.73,70.09 74.7,70.09 v4(75.47,70.87)
  BOTTOM w0.381: v4(30.01,28.35) 31.17,27.18 v4(34.2,27.18) ; v4(141.89,66.34) 142.37,66.82 147.02,66.82 147.37,66.48 147.37,64.66 146.4,63.69 R1843.1
  BOTTOM w0.508: v4(68.66,206.88) 72.93,206.88 73.44,207.39 R1987.2 ; v3(82.46,154.81) C1716.1 81.76,154.34 81.81,154.29 81.81,150.81 83.6,149.02 C1715.1 85.55,148.84 86.29,148.11 86.29,145.39 89.36,142.32 90.14,142.32 90.89,141.58 v4(90.89,139.75) ; v3(55.15,164.72) 55.58,164.72 56.22,164.08 56.22,162.31 v3(55.58,161.67) 55.58,157.63 v4(55.56,157.61) ; v4(142.65,60.33) 142.65,61.93 141.89,62.69 v4(141.89,66.34) ; v4(25.18,27.94) 24.67,27.43 R731.1 ; v4(32.85,33.86) 32.68,33.86 32.11,33.29 32.11,32.66 32.77,32 v4(32.77,30.99) ; v4(162.16,211.71) 162.19,211.68 162.19,209.14 165.13,206.2 v4(165.13,204.09) 165.21,204.01 165.21,201.5 164.37,200.66 164.37,195.2 ; 79.2,140.12 79.2,139.92 80.91,138.22 80.91,137.55 83.45,135 83.46,135 83.47,134.99 v4(83.47,134.37) ; 79.2,140.12 80.14,140.12 81.38,141.35 v4(81.57,141.35) ; 79.2,140.12 74.19,140.12 v4(74.18,140.13) ; R1831.1 155.95,43.5 v4(155.99,43.54) ; v4(135.85,53.47) 135.85,53.59 136.69,54.43 136.69,56.72 136.66,56.75 136.66,57.3 136.69,57.32 136.69,58.27 v4(136.81,58.39) ; R79675.1 v4(150.17,211.71) ; v4(28.48,11.43) 28.48,11.3 27.02,9.84 R80202.1 R80201.1 ; v4(124.2,31.37) 126.69,33.86 135.8,33.86 136.71,34.77 v4(136.71,45.09) ; v4(163.33,54.61) R297.2 R79689.2 ; R79690.2 162.53,55.84 v4(163.33,56.64) 163.33,57 162.67,57.66 R1826.2 ; R764.2 v4(49.82,7.21) ; R305.2 v4(163.48,47.37)
  BOTTOM w1.27: 163.36,187.76 163.36,186.13 162.21,184.99 162.21,159.89 169.6,152.5 169.6,146.1 166.48,142.98 166.48,131.5 170.39,127.58 170.39,123.26 169.96,122.82 169.96,111.52 172.14,109.33 172.14,102.51 171.05,101.42 171.05,96.7 167.7,93.34 164.75,93.34 162.8,91.39 153.65,91.39 150.48,94.56 v7(147.35,94.56) v7(147.35,93.27) ; v4(88.78,8.97) v4(87.74,8.97) 87.74,10.31 88.32,10.9 88.32,12.24 89.01,12.93 89.95,12.93 90.61,13.59 90.61,14.66 90.09,15.18 90.09,15.58 89.47,16.2 89.47,17.87 88.65,18.68 88.65,19.55 90.08,20.97 90.08,25.68 88.53,27.23 88.53,28.88 85.23,32.18 85.23,35.49 87.21,37.47 87.21,43.71 89.38,45.89 92.96,45.89 94.32,47.24 100.36,47.24 103.92,43.69 109.18,43.69 109.33,43.84 109.71,43.84 113.37,47.5 114.33,47.5 118.78,51.94 127.49,51.94 129.85,54.31 129.85,55.5 v7(129.6,55.75) 129.6,56.16 v7(128.96,56.79) ; v7(119.79,89.28) 119.54,89.03 83.27,89.03 v7(82.41,88.16) ; 162.59,198.45 155.66,198.45 151.93,202.18 143.8,202.18 139.02,206.96 129.57,206.96
  vias: v2(126.65,209.42)
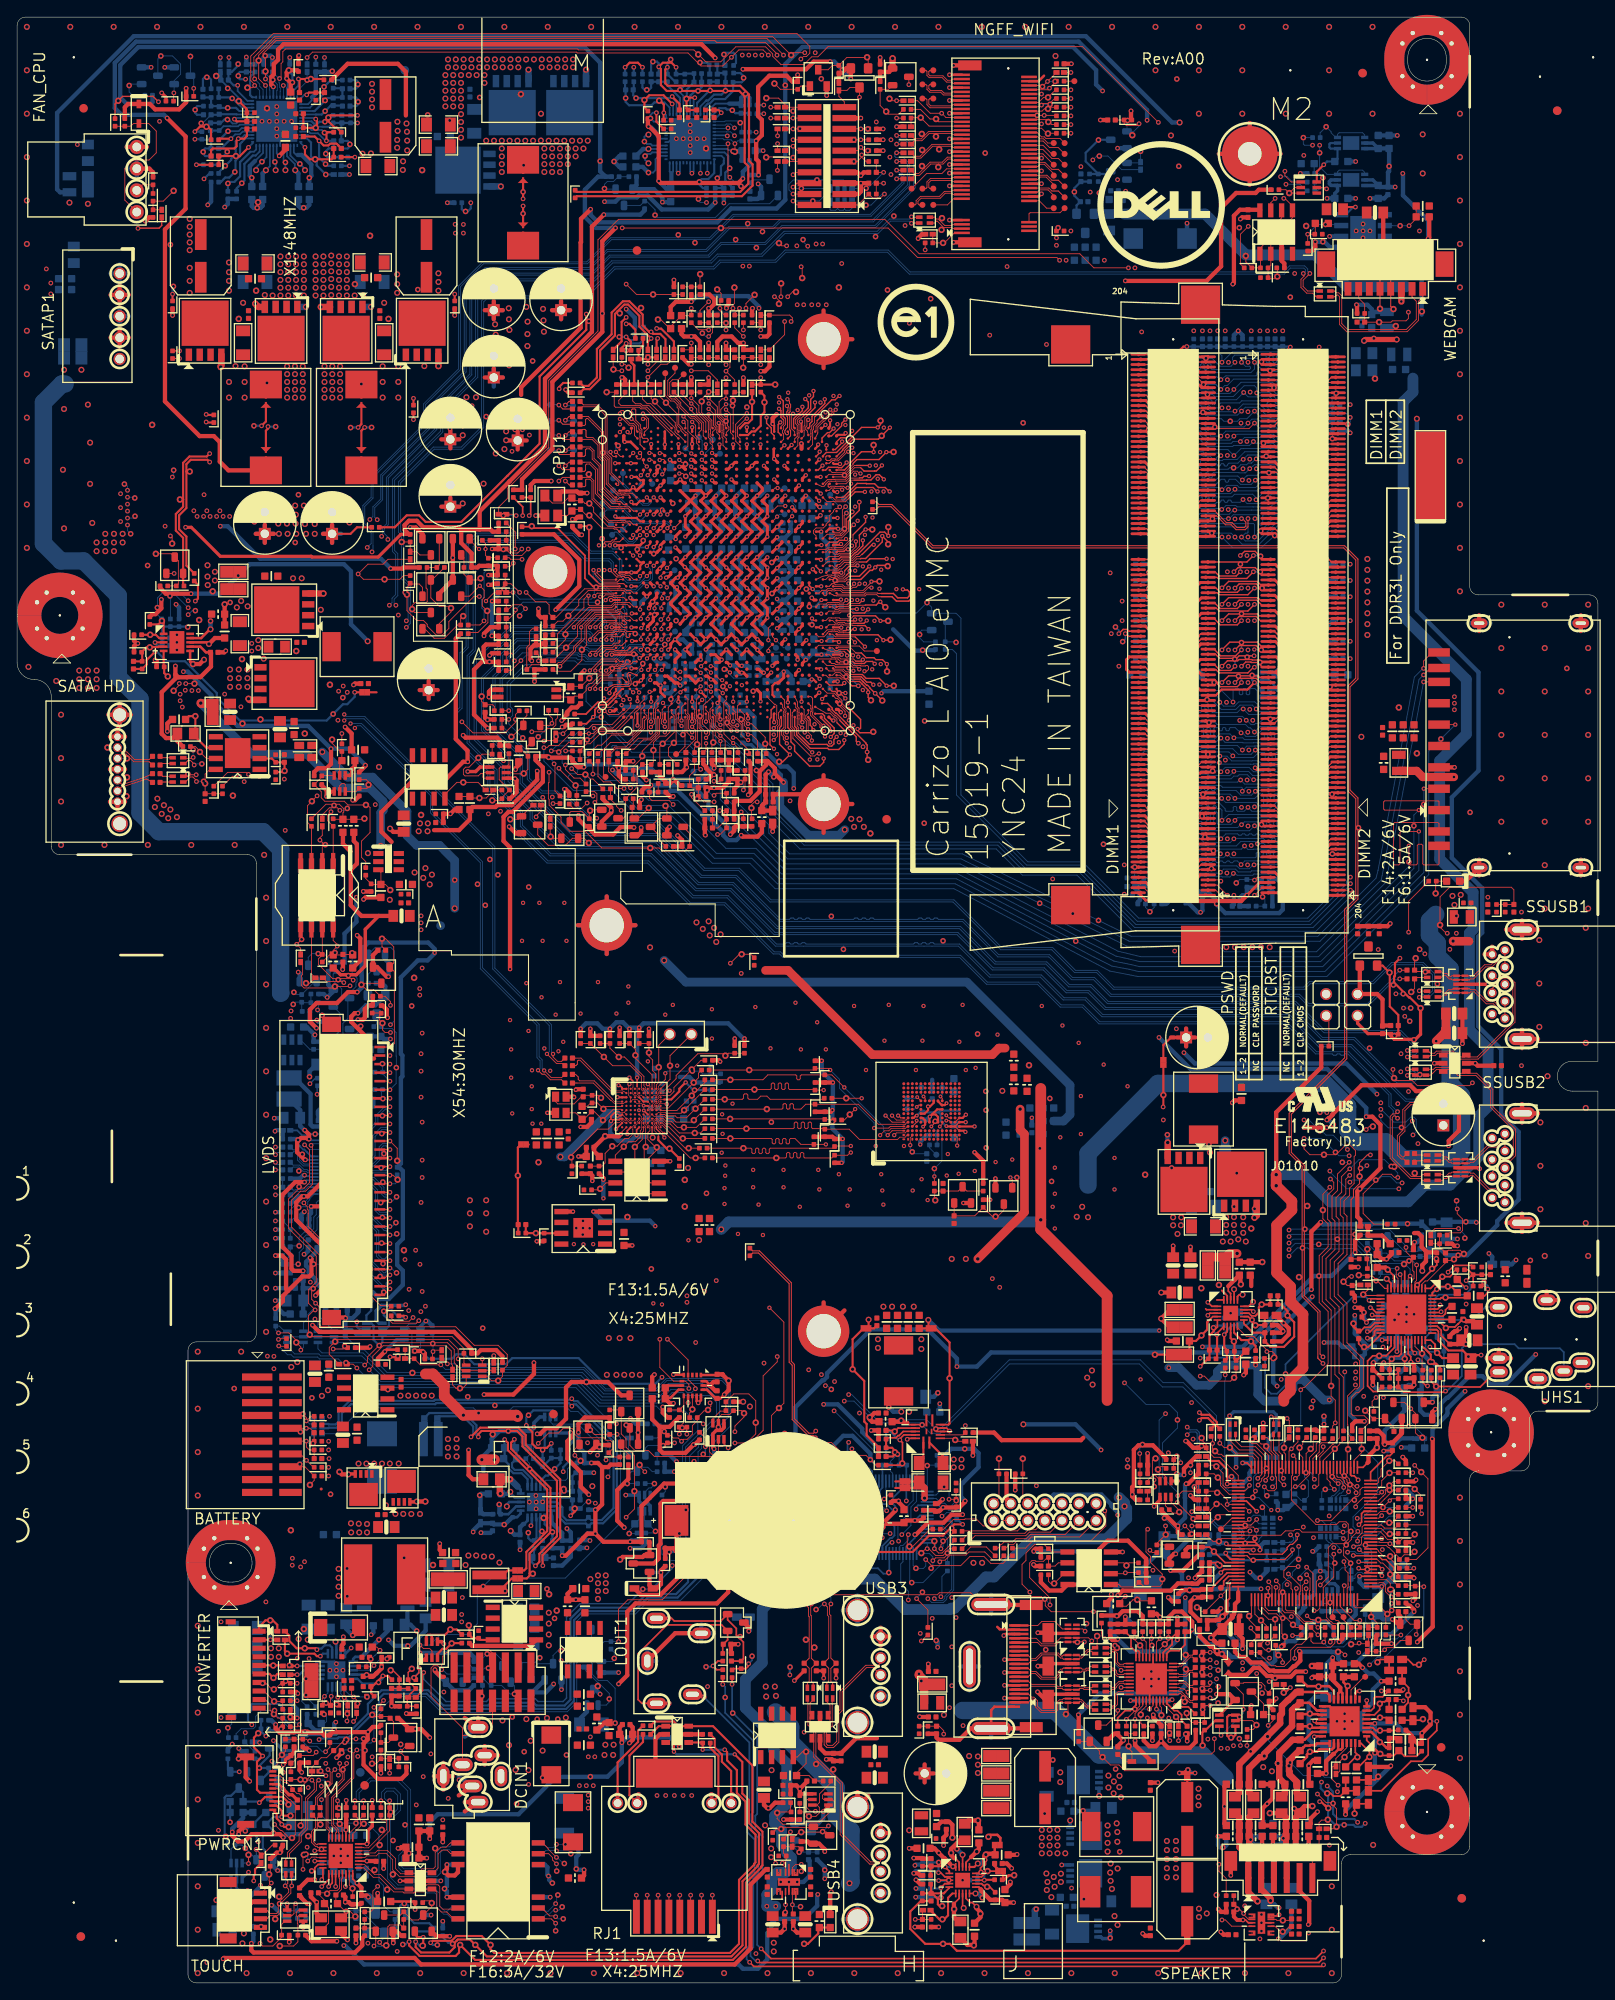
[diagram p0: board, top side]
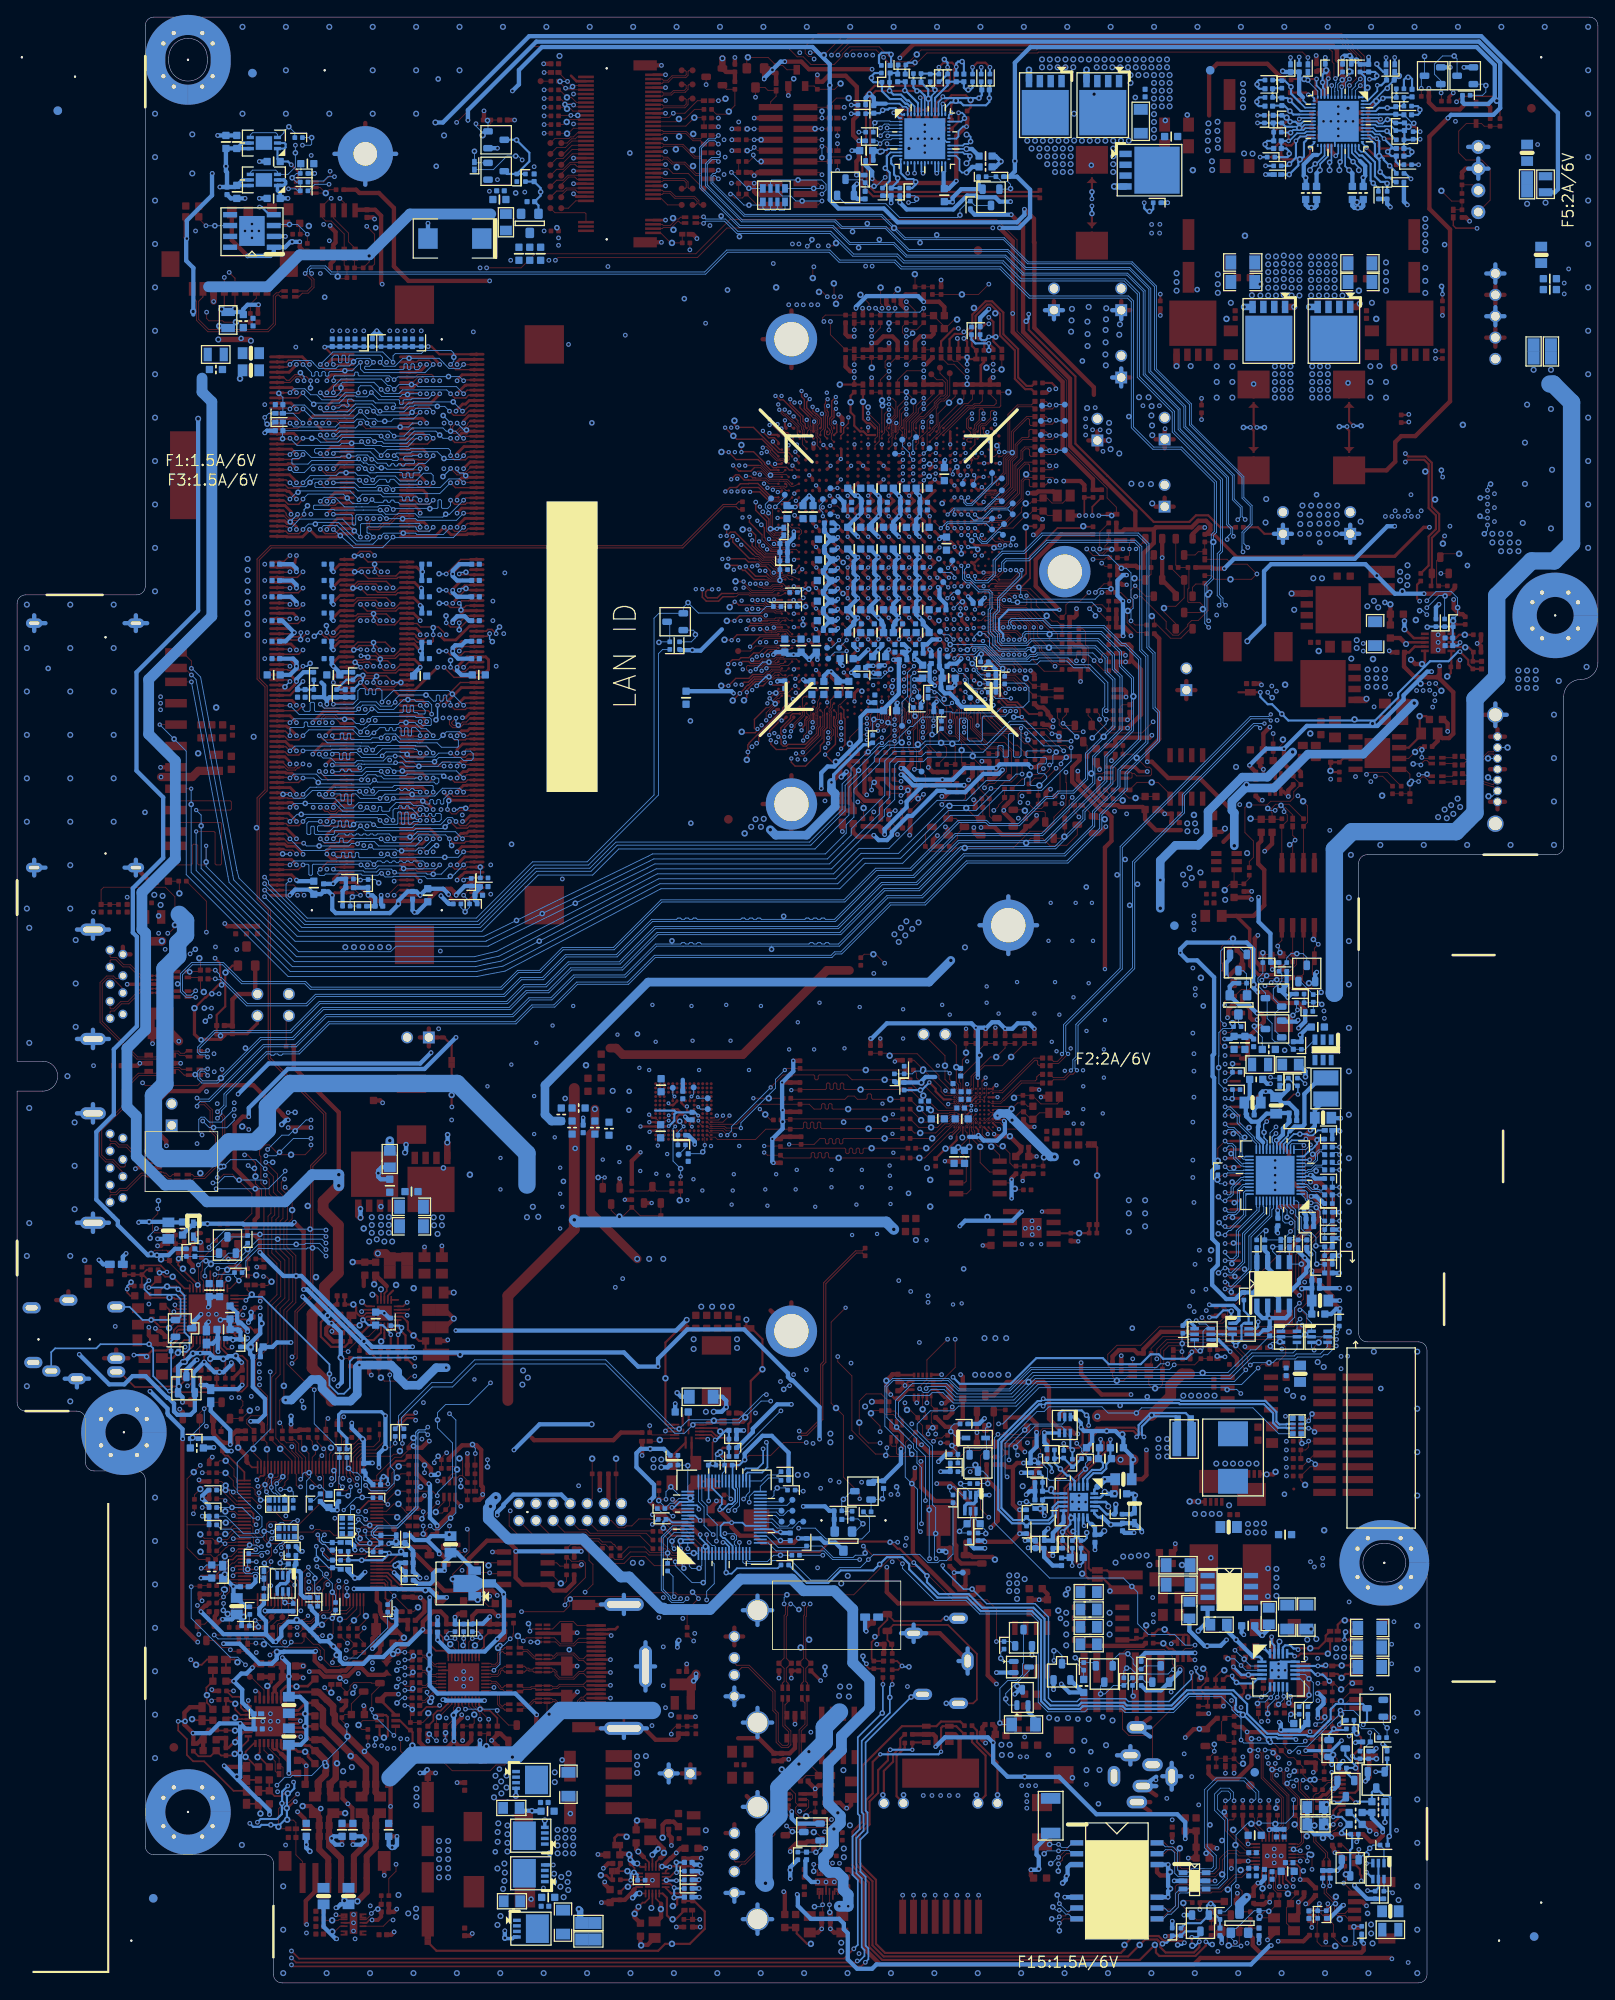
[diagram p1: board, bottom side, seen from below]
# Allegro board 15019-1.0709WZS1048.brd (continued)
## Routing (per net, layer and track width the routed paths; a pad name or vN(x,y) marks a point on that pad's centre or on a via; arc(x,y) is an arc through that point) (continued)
SPI_33_18_PU1: length 9.7
  TOP w0.102: R2030.1 38.13,136.9 38.23,137 38.23,137.38 37.71,137.9 36.14,137.9 R1736.1 ; R2030.1 37.05,136.14 R1738.1 ; R2030.1 R2031.1 40.57,136.14 v1(40.65,136.22)
SPI_33_18_PU2: length 8.1
  TOP w0.102: R1737.1 36.55,120.27 R2032.1 ; R2029.1 39.21,120.33 C1758.2 38.07,120.27 R2032.1 ; R2032.1 36.99,120.8 37.35,121.16 37.35,121.18 v4(37.47,121.31) 37.35,121.44 37.35,121.62 36.99,121.97 SRCON1.8
  BOTTOM w0.102: v4(37.47,121.31) 37.35,121.18 37.35,120.68 v2(37.21,120.54)
SPI_CLK: length 66.7
  TOP w0.102: CPU1.BC6 74.2,147.6 v3(74.17,147.57) ; R1741.2 36.22,117.17 38.11,117.17 v4(38.23,117.04)
  L3 w0.127: v4(38.23,117.04) 37.64,117.64 37.64,120.34 38.28,120.98 38.28,122.41 37.81,122.88 37.81,136.36 38.78,137.34 38.78,138.55 39.94,139.71 56.59,139.71 56.87,139.43 60.05,139.43 60.77,140.15 65.69,140.15 66.17,140.63 67.72,140.63 68.19,141.1 68.19,141.56 72.87,146.24 72.96,146.24 73.48,146.75 73.48,146.88 v3(74.17,147.57)
  BOTTOM w0.102: v2(37.58,117.37) 37.9,117.37 v4(38.23,117.04)
SPI_CLK_1: length 7.1
  TOP w0.102: v1(33.82,116.97) 34.26,116.97 R1741.1 34.45,118.05 SRCON1.6
SPI_CS0_N: length 55.2
  TOP w0.102: CPU1.BB8 75.5,149 75.5,148.37 75.51,148.37 75.51,147.89 75.39,147.78 75.39,147.37 v3(75.8,146.97) ; v4(36.74,137.03) 36.36,136.65 36.36,135.97 36.99,135.33 R1738.2 SRCON1.1
  L3 w0.127: v3(75.8,146.97) 75.7,146.97 74.44,148.22 73.91,148.22 73.02,147.33 73.02,146.94 72.77,146.7 71.92,146.7 66.61,141.39 66,141.39 65.42,140.81 60.4,140.81 59.68,140.09 57.15,140.09 56.82,140.42 38.74,140.42 36.74,138.42 v4(36.74,137.03)
  BOTTOM w0.102: v2(37.09,137.76) 36.74,137.41 v4(36.74,137.03)
SPI_CS#: length 9.9
  TOP w0.076: 73.56,99.95 73.56,100.22 73.31,100.47 U902.J6
  TOP w0.102: 73.56,99.95 73.56,97.82 v1(73.57,97.82) 73.39,97.64 73.39,92.81 73.87,92.33 U9003.1
SPI_DATAIN: length 52.4
  TOP w0.102: CPU1.BA9 76.6,149.64 76.21,149.24 76.21,146.74 v3(75.8,146.33) ; R1740.1 35.72,136.66 36.55,137.49 37.47,137.49 v4(37.77,137.19)
  L3 w0.127: v4(37.77,137.19) 37.75,137.21 37.75,138.28 39.56,140.09 56.68,140.09 57.01,139.76 59.92,139.76 60.64,140.48 65.55,140.48 66.04,140.96 67.58,140.96 67.86,141.24 67.86,141.69 72.63,146.47 72.87,146.47 73.25,146.85 73.25,147.24 74,147.99 74.35,147.99 74.59,147.75 74.59,147.54 v3(75.8,146.33)
  BOTTOM w0.102: v2(38.64,137.41) 38.42,137.19 v4(37.77,137.19)
SPI_DATAOUT: length 74
  TOP w0.102: CPU1.AY7 75,150.13 74.58,149.71 74.58,149.22 74.48,149.12 74.48,148.68 74.5,148.66 74.5,148.34 74.49,148.33 74.49,147.89 74.58,147.8 74.58,147.35 v3(74.17,146.94) ; v4(38.96,116.65) 38.94,116.65 38.87,116.58 v1(37.19,116.58) 37.02,116.41 33.58,116.41 33.26,116.74 33.26,117.83 33.41,117.98 33.41,119.21 R1739.2
  L3 w0.127: v3(74.17,146.94) 74.04,146.94 68.52,141.42 68.52,140.96 67.86,140.3 66.31,140.3 65.21,139.2 63.86,139.2 63.51,139.55 60.84,139.55 60.39,139.09 56.58,139.09 56.3,139.37 41.29,139.37 38.31,136.4 38.31,132.94 38.14,132.77 38.14,123.01 38.82,122.33 38.82,116.8 v4(38.96,116.65)
SPI_MISO: length 10.5
  TOP w0.076: 74.06,99.7 74.06,100.01 74.06,100.22 73.91,100.36 73.7,100.36 73.56,100.51 73.56,100.72 73.56,101.36 U902.G6
  TOP w0.102: 75.09,93.6 74.12,93.6 73.92,93.8 73.92,96.52 74.86,97.46 v1(74.86,97.76) 74.73,97.76 73.82,98.68 73.82,99.47 74.06,99.7
SPI_MISO_ROM_1: length 5.1
  TOP w0.102: SRCON1.2 35.72,133.43 v4(35.44,133.71) 35.44,133.99 35.72,134.26 R1740.2
  BOTTOM w0.102: v2(36.08,133.17) 36.02,133.17 35.49,133.71 v4(35.44,133.71)
SPI_MOSI: length 6.8
  TOP w0.076: U902.H6 73.31,100.99 73.06,100.74 73.06,99.82 72.93,99.69
  TOP w0.102: U9003.5 70.01,96.85 v1(71,97.84) 71.58,98.42 72.37,98.42 72.93,98.98 72.93,99.69
SPI_MOSI_1: length 4
  TOP w0.102: R1739.1 33.18,121.06 v4(32.72,121.51) 33.18,121.97 SRCON1.5
  BOTTOM w0.102: v2(33.3,122.09) v4(32.72,121.51)
SPI_SCK: length 7.3
  TOP w0.102: U902.K6 73.31,99.67 73.16,99.52 73.16,98.68 v1(72.3,97.82) 72.3,95.99 71.18,94.87 U9003.6
SPI_WP#: length 57.3
  TOP w0.102: SRCON1.3 R1736.2 33.99,135.78 33.99,137.74 v1(34.5,138.25) 34.5,138.28 v4(35.11,138.89)
  L3 w0.127: v3(75.59,149.76) 75.59,149.61 74.46,148.49 73.85,148.49 73.11,147.74 72.5,147.74 67.46,142.71 66.13,142.71 65.86,142.43 65.86,141.73 65.28,141.15 59.87,141.15 59.15,140.42 57.44,140.42 57.11,140.75 36.98,140.75 v4(35.11,138.89)
  BOTTOM w0.102: R1647.2 77.36,150.43 76.99,150.07 76.99,149.99 76.49,149.48 75.87,149.48 v3(75.59,149.76)
SPKR_DET: length 66.4
  TOP w0.102: R1203.1 154.21,18.03 154.41,18.24 v1(154.41,18.26) 154.41,20.37 153.7,21.08 153.21,21.08 152.19,22.1 v4(152.18,22.1) ; v4(146.11,58.8) 146.11,58.94 146.46,59.28 U109.59 146.46,61.73 145.09,63.09 144.52,63.09 R1825.1
  L3 w0.127: v4(139.35,28.52) 140.29,29.46 149.51,29.46 152.18,26.8 v4(152.18,22.1)
  L4 w0.127: v4(139.35,28.52) 139.48,28.65 139.48,29.76 144.59,34.88 144.59,36.39 144.65,36.44 144.65,41.13 144.85,41.33 144.85,41.72 144.09,42.49 144.09,45.43 145.3,46.65 145.33,46.65 145.38,46.7 145.54,46.7 146.3,47.46 146.3,55.8 146.85,56.34 146.85,56.64 146.43,57.05 146.43,58.48 v4(146.11,58.8)
SPKR_DET_C: length 8
  TOP w0.102: v1(153.39,19.1) 153.34,19.05 152.66,19.05 152.37,18.76 R1203.2 PC2127.2 152.37,14.99 151.59,14.2 SPK1.6
SPKR_IN_L: length 4.9
  TOP w0.203: U21.6 158.85,31.36 159.47,31.98 v1(159.47,32.66) 159.7,32.89 160.05,32.89 160.31,33.15 C203.2 160.56,33.08 C199.2
SPKR_IN_R: length 3.6
  TOP w0.203: U21.31 156.6,26.97 156.85,26.72 v1(156.85,26.41) 156.62,26.41 C210.2
SPKR_L+_C: length 11.4
  TOP w0.711: 143.04,16.64 143.04,15.86 144.09,14.81 SPK1.1 144.09,10.63 v1(145.17,9.55)
  TOP w0.762: L31.2 143.04,19.35 C226.1 R396.1 143.04,16.64
SPKR_L+_SNB: length 4.2
  TOP w0.508: R396.2 v4(140.55,17.14)
  BOTTOM w0.508: R396.2 141.51,16.1 141.26,15.85 v2(141.1,15.85) 140.83,15.85 140.55,16.13 v4(140.55,17.14)
SPKR_L-_C: length 11.5
  TOP w0.711: R403.1 144.18,16.26 145.59,14.86 SPK1.2 145.59,10.98 146.69,9.87 v1(146.69,9.63)
  TOP w0.762: L32.2 144.18,19.35 C236.1 R403.1
SPKR_L-_SNB: length 4.2
  TOP w0.508: R403.2 v4(145.7,16.18)
  BOTTOM w0.508: R403.2 144.61,17.14 144.36,16.89 v2(144.36,16.76) 144.36,16.59 144.76,16.18 v4(145.7,16.18)
SPKR_OUT_L+: length 19.8
  TOP w0.305: U21.16 153.6,33.63 153.25,33.99 152.02,33.99 151.97,34.04 C224.2
  TOP w0.762: C224.2 149.72,34.04 148.78,33.1 148.72,33.1 148.01,32.39 148.01,31.52 147.81,31.32 147.81,30.37 146.34,28.9 ; 146.34,28.9 v1(146.34,28.83) ; 146.34,28.9 143.04,25.6 C225.1 143.04,22.3 L31.1
SPKR_OUT_L-: length 17
  TOP w0.305: C228.2 151.21,32.77 152.1,31.88 152.39,31.88 152.41,31.86 U21.18
  TOP w0.762: C228.2 150.14,32.77 149.6,32.23 149.53,32.23 149.21,31.91 149.21,30.05 145.96,26.8 v1(145.96,26.54) 145.83,26.42 145.47,26.42 144.18,25.12 C235.1 144.18,22.3 L32.1
SPKR_OUT_R+: length 10.3
  TOP w0.305: C223.2 150.5,27.53 150.53,27.53 150.75,27.76 151.27,27.76 151.32,27.81 151.93,27.81 152.13,28.02 U21.25
  TOP w0.762: C223.2 150.04,27.18 148.85,25.99 v1(148.85,25.4) 148.85,24.77 148.9,24.71 148.9,24.38 149.77,23.52 C247.1 149.77,22.17 L33.1
SPKR_OUT_R-: length 11.8
  TOP w0.305: C229.2 150.67,28.45 151.58,29.36 U21.23
  TOP w0.762: C229.2 149.26,28.45 147.71,26.9 147.71,25.83 v1(147.56,25.69) 147.71,25.54 147.71,23.94 148.37,23.28 C255.1 148.37,22.17 L34.1
SPKR_R+_C: length 10.2
  TOP w0.508: L33.2 150.15,20.17 150.67,20.69 v1(151.58,20.69)
  TOP w0.711: L33.2 149.64,19.35 C248.1 R415.1 149.64,15.6 148.59,14.55 SPK1.4
SPKR_R+_SNB: length 2.9
  TOP w0.508: R415.2 151.16,16.19 v4(151.15,16.18)
  BOTTOM w0.508: v2(150.73,15.39) 150.76,15.39 151.15,15.79 v4(151.15,16.18) 151.16,16.19 R415.2
SPKR_R-_C: length 9.8
  TOP w0.508: v1(146.6,19.86) L34.2
  TOP w0.711: SPK1.3 147.09,14.59 148.5,16 R419.1 C256.1 148.5,19.35 L34.2
SPKR_R-_SNB: length 4
  TOP w0.508: R419.2 v4(146.97,16.18)
  BOTTOM w0.508: v4(146.97,16.18) 147.73,16.18 148.19,16.64 v2(148.19,16.92) 147.96,17.14 R419.2
SST_HOLDJ_1: length 69.2
  TOP w0.102: v4(71.79,139.83) 71.41,140.21 71.39,140.21 71.27,140.33 70.62,140.33 69.23,141.72 69.23,142.1 69.25,142.13 R576.2 ; v4(39.33,117.32) 39.15,117.5 37.59,117.5 37.58,117.5 36.92,117.5 35.26,119.16 35.26,119.81 35.72,120.27 R1737.2 SRCON1.7
  L3 w0.127: v4(71.79,139.83) 71.39,140.22 68.25,140.22 68,139.96 66.74,139.96 65.63,138.86 63.72,138.86 63.37,139.21 61.14,139.21 60.69,138.76 56.45,138.76 56.16,139.04 41.43,139.04 38.67,136.28 38.67,132.82 38.47,132.63 38.47,123.15 39.33,122.3 v4(39.33,117.32)
  BOTTOM w0.102: v2(38.77,117.86) 39.3,117.32 v4(39.33,117.32)
SST_HOLDJ_1_R: length 10.1
  TOP w0.102: CPU1.BA7 75,149.33 74.7,149.03 74.7,148.75 74.71,148.75 74.71,148.25 74.7,148.25 74.7,147.97 74.79,147.89 74.79,146.32 74.11,145.64 72.72,145.64 71.48,144.4 70.04,144.4 69.47,143.83 R576.1
SSTCMP: length 4.7
  BOTTOM w0.102: U120.11 34.82,35.58 33.82,34.57 v2(33.82,33.68) 33.82,33.46 R45.1
SSTCMP_1: length 2.6
  BOTTOM w0.102: C5.1 35.97,30.35 36.2,30.58 36.2,31.15 v2(35.93,31.42) 35.92,31.43 R45.2
STATUS: length 4.7
  TOP w0.102: R61.1 37.65,33.3 v4(37.52,33.43)
  BOTTOM w0.102: U120.8 37.37,33.58 v4(37.52,33.43) 38.64,32.31 v2(38.64,31.5)
SUS_LED_GREEN_C: length 15.7
  TOP w0.254: v4(28.35,21.08) 29.02,21.75 PWRCN1.7 31.1,21.75 31.76,21.09 v1(31.76,20.86)
  BOTTOM w0.254: R729.2 24.61,16.95 v2(24.42,17.14) 24.29,17.27 24.29,21.69 24.5,21.89 25.04,21.89 Q68.D 26.45,22.29 R730.2 28.23,21.21 v4(28.35,21.08)
SUS_LED_GREEN_C2: length 2.4
  BOTTOM w0.254: v2(24.93,18.8) R735.2 R730.1
SUSCLK_32_APU: length 23.5
  TOP w0.102: CPU1.AG7 74.6,161.1 v3(74.6,160.82) ; R1934.2 57.57,166.75 57.75,166.57 59.08,166.57 v4(59.09,166.56)
  L3 w0.127: v4(59.09,166.56) 59.71,167.17 59.9,167.17 61.03,168.3 63.71,168.3 65.82,166.19 65.82,165.12 67.19,163.75 69.8,163.75 70.83,162.72 72.24,162.72 73.73,161.24 74.18,161.24 v3(74.6,160.82)
  BOTTOM w0.102: v2(74.6,160.07) v3(74.6,160.82)
SUSCLK_32_APU_C: length 129.3
  TOP w0.102: v4(122,201.55) 121.69,201.87 105.39,201.87 101.93,205.32 v1(82.37,205.32) 70.83,205.32 v4(70.82,205.33) ; R1873.1 54.82,168.41 v3(54.82,167.77) 54.82,167.02 R1874.2 55.21,166.75 R1934.1 ; R1710.1 v4(123.32,216.41)
  L3 w0.127: v4(123.32,216.41) 123.32,205.74 122.84,205.26 122.84,202.44 122,201.6 v4(122,201.55)
  L4 w0.127: v4(70.82,205.33) 70.82,204.43 65.28,198.89 65.28,192.12 59.63,186.47 50.03,186.47 48.9,185.34 48.9,170.21 50.96,168.15 53.81,168.15 53.87,168.21 54.24,168.21 54.69,167.77 v3(54.82,167.77)
SUSCLK_NGFF: length 3.5
  TOP w0.102: NGFF1.50 119.89,217 120.52,216.37 v1(120.64,216.37) 120.68,216.41 R1710.2
SVC_VDD: length 121.7
  TOP w0.102: v4(78.9,191.87) R1902.2 R1629.1 ; v4(88.93,225.55) 88.93,225.69 87.59,227.03 81.87,227.03 81.64,227.25 30.31,227.25 28.79,225.73 28.79,225.37 29.07,225.09 v1(29.07,223.65) v4(29.07,222.76)
  L3 w0.127: v4(88.93,225.55) 88.93,222.61 94.99,216.55 94.99,197.57 v4(93.76,196.34)
  L4 w0.127: v4(78.9,191.87) 78.43,192.34 78.43,193.59 80.46,195.62 80.46,196.89 80.74,197.17 86.27,197.17 88.07,195.36 92.78,195.36 v4(93.76,196.34)
  BOTTOM w0.102: PU4601.5 29.59,221.44 29.53,221.49 29.53,222.3 v4(29.07,222.76)
SVC_VDD_GFX: length 27.7
  TOP w0.102: R1994.2 82.77,195.14 82.25,195.66 v4(82.25,195.94) 82.25,196.71 R1999.1 82.39,197.67 v1(81.93,198.13)
  L3 w0.127: v4(82.25,195.94) 83.96,197.64 83.96,211.74 84.63,212.42 84.63,215.45 v4(83.96,216.12)
  BOTTOM w0.102: PU5407.5 83.01,216.57 83.5,216.57 v4(83.96,216.12)
SVD_VDD: length 113.2
  TOP w0.102: v4(90.58,194.39) 90.73,194.53 90.73,194.82 90.41,195.14 R1631.1 R1903.2 ; v4(92.18,225.84) 90.87,225.84 v1(90.58,225.55) 88.43,227.71 30.12,227.71 27.71,225.3 27.71,224.37 27.71,224.37 27.71,223.92 27.71,223.92 27.71,222.85 v4(27.8,222.76)
  L3 w0.127: v4(90.58,194.39) 91.69,195.49 95.05,195.49 96.01,196.45 96.01,221.68 92.18,225.51 v4(92.18,225.84)
  BOTTOM w0.102: PU4601.3 28.79,221.51 28.39,221.91 28.39,222.17 v4(27.8,222.76)
SVD_VDD_GFX: length 38.7
  TOP w0.102: v4(83.78,195.94) 83.78,196.32 83.94,196.49 v1(83.94,198.36) ; R1995.2 83.98,187.55 v4(82.96,188.57) 83.42,189.03 83.42,189.73 R2001.1
  L3 w0.127: v4(83.96,217.03) 84.88,216.11 84.88,212.31 84.21,211.64 84.21,196.37 v4(83.78,195.94)
  L4 w0.127: v4(83.78,195.94) 83.43,195.59 83.43,189.04 v4(82.96,188.57)
  BOTTOM w0.102: v4(83.96,217.03) 83.5,217.49 83.01,217.49 82.89,217.37 PU5407.3
SVT_VDD: length 130.7
  TOP w0.102: v4(89.7,225.55) 87.76,227.48 30.22,227.48 28.27,225.54 v1(28.27,224.92) 28.27,222.79 v4(29.07,222) ; v4(78.9,188.62) 80.88,188.62 81.95,187.55 R1901.2
  L3 w0.127: v4(94.7,196.34) 95.24,196.89 95.24,216.66 89.7,222.21 v4(89.7,225.55)
  L4 w0.127: v4(78.9,188.62) 77.92,189.6 77.92,193.8 79.95,195.83 79.95,197.1 80.53,197.68 86.48,197.68 88.28,195.87 92.25,195.87 92.53,196.15 92.53,196.54 93.06,197.07 94.12,197.07 94.7,196.49 v4(94.7,196.34)
  BOTTOM w0.102: PU4601.4 29.19,221.88 v4(29.07,222)
SVT_VDD_GFX: length 34
  TOP w0.102: v1(86.31,197.51) 85.3,196.5 v4(85.3,195.94) ; R1993.2 79.92,195.68 v4(80.93,196.7)
  L3 w0.127: v4(83.2,217.03) 83.67,217.5 84.15,217.5 85.14,216.52 85.14,212.2 84.47,211.53 84.47,196.77 v4(85.3,195.94)
  L4 w0.127: v4(85.3,195.94) 84.54,196.7 v4(80.93,196.7)
  BOTTOM w0.102: PU5407.4 83.14,216.97 v4(83.2,217.03)
SW_ON_N_SIO: length 6.1
  TOP w0.102: R375.1 R364.2 140.08,59.56 v1(140.52,59.12) 140.83,58.82 140.83,58.2 141.84,57.18 U109.69
SWR_LX: length 11.5
  BOTTOM w0.203: U26.17 37.18,98.22 36.26,99.14 36.26,99.44 36.05,99.64
  BOTTOM w0.508: L2.2 32.48,105.88 34.35,104.01 34.35,100.43 34.57,100.2 35.49,100.2 36.05,99.64
SWR_V12: length 27.6
  TOP w0.508: v4(33.66,99.77) 34.17,99.26 v4(34.17,98.73) 34.04,98.73 33.92,98.86 33.23,98.86 32.77,98.4 32.77,97.19 33.66,96.3 v4(33.73,96.3) ; v4(37.47,90.37) 37.47,90.56 37.18,90.86 34.43,90.86 v4(34.41,90.85)
  L4 w0.508: v4(33.73,96.3) 34.4,95.64 34.4,90.86 v4(34.41,90.85)
  BOTTOM w0.203: U26.11 v4(33.73,96.3) ; v4(37.47,90.37) 37.58,90.48 U26.43 ; v4(34.17,98.73) 34.31,98.59 35.83,98.59 36.38,98.05 U26.15
  BOTTOM w0.508: C295.1 C299.2 34.16,89.83 34.4,90.07 34.4,90.83 v4(34.41,90.85) ; v4(37.47,90.37) 37.47,89.5 C297.1 ; v4(33.66,99.77) 33.61,99.77 33.13,100.25 C296.1 33.13,102.12 L2.1
SYNC: length 3.4
  TOP w0.102: TP24.1 157.64,35.81 156.1,34.28 U21.11
SYS_3VSB: length 5.7
  TOP w0.102: R371.1 140.19,60.58 v1(140.34,60.43) 141.13,59.64 141.13,58.21 141.42,57.92 141.8,57.92 141.86,57.98 U109.67
SYS_FAN_TACH1_1: length 3.2
  TOP w0.102: FANC3.3 14.65,210.38 R80.2 R76.2
SYS_FAN_TACH1_2: length 4.9
  TOP w0.102: v1(18.32,209.68) 17.11,208.47 R76.1 R73.2 R74.2
SYS_PRES: length 4.4
  TOP w0.102: BAT2.7B 33.14,61.89 33.87,61.16 v4(33.87,61.14) 34.68,60.33 R79647.2
  BOTTOM w0.102: v4(33.87,61.14) 33.48,61.14 33.08,60.73 v2(33.08,60.68)
SYS_PWRGD: length 15.8
  TOP w0.102: Q79.D 70.96,136.27 71.22,136.53 R124.2 72.55,139.89 72.55,141.92 R2028.2 R1657.1 74.46,142.81 74.46,144.22 v1(74.46,144.23) 74.46,145.13 75.2,145.87 75.92,145.87 76.41,146.37 76.41,147.91 CPU1.BC9
SYS_PWRGD_G: length 6.2
  TOP w0.102: Q79.G 67.16,137.26 v1(67.06,137.16) 66.96,137.06 R717.2 66.11,137.06 64.83,137.06 64.68,136.91 Q78.D
SYS_PWRGD_HV: length 92.2
  TOP w0.102: Q14.G v4(18.38,164.91) ; Q1209.D 78.71,134.49 R119.2 78.15,132.41 75.52,132.41 75.14,132.79 v1(74.1,132.79) 68.42,132.79 66.46,134.75 64.67,134.75 63.66,135.76 63.66,136.4 62.26,137.8 62.26,138.47 62.18,138.55 62.18,140.4 62.25,140.47 v4(62.25,141.65)
  L3 w0.127: v4(62.25,141.65) 61.67,141.65 61.06,142.25 59.28,142.25 58.46,141.43 58.14,141.43 57.85,141.14 39.97,141.14 39.72,141.39 36.1,141.39 35.63,141.86 30.74,141.86 29.43,140.55 v4(26.58,140.55)
  L4 w0.127: v4(26.58,140.55) 26.54,140.51 25.88,140.51 25.34,141.06 25.34,146.91 22.51,149.74 22.51,151.16 19.93,153.74 19.93,158.4 19.17,159.16 19.17,164.12 v4(18.38,164.91)
SYS_PWRGD_HV_1: length 6.9
  TOP w0.102: R118.1 74.96,133.92 74.96,134.43 Q1208.C 75.12,136.24 Q1209.G 76.04,137.41 75.93,137.53 75.93,137.67 v1(75.89,137.71)
SYS_PWRGD_HV_2: length 4.7
  TOP w0.102: v1(73.92,137.46) 72.7,136.24 Q1208.B 71.98,136.49 C67.1 72.11,137.67 R124.1
SYSTEM_FAN_PWM1_1: length 18
  TOP w0.102: R68.2 R71.2 13.3,217.23 13.62,217.55 D1.A 15.4,217.55 16.29,216.66 16.29,214.12 15.44,213.27 13.58,213.27 12.61,212.3 12.61,208.58 FANC3.4
T_DP_BLON: length 2
  TOP w0.102: v3(73,176.4) 73.3,176.7 CPU1.G5
  BOTTOM w0.102: v3(73,176.4) 72.8,176.2 TP174.1
T_DP_DIGON: length 2
  TOP w0.102: v3(73.8,176.4) 74.1,176.7 CPU1.G6
  BOTTOM w0.102: v3(73.8,176.4) 74.33,175.87 TP6.1
TCK: length 2.6
  BOTTOM w0.102: U4101.27 95.77,55.48 TP4130.1
TDI: length 2.8
  BOTTOM w0.102: U4101.25 96.24,54.68 TP4128.1
TDO: length 4.3
  BOTTOM w0.102: TP4127.1 94.8,53.44 95.76,53.44 96.6,54.28 U4101.24
TEMPIN0: length 1.5
  TOP w0.102: CPU1.E15 81.63,178.7 v3(81.33,179)
  BOTTOM w0.102: TP192.1 82.23,178.94 81.39,178.94 v3(81.33,179)
TEMPIN1: length 2.6
  TOP w0.102: v3(80.13,179) 80.43,178.7 CPU1.E14
  BOTTOM w0.102: v3(80.13,179) 80.13,179.33 80.17,179.37 80.17,180.47 TP193.1
TEMPIN2: length 1.5
  TOP w0.102: CPU1.E12 79.14,178.7 v3(78.9,178.94)
  BOTTOM w0.102: TP194.1 v3(78.9,178.94)
TEMPINR: length 3.5
  TOP w0.102: CPU1.F14 80.43,177.9 v3(80.13,178.2)
  BOTTOM w0.102: TP195.1 81.39,179.83 80.55,179 80.55,178.62 v3(80.13,178.2)
TEST18_M: length 60.1
  TOP w0.102: R1748.2 v4(88.2,219.46) ; R1608.1 77.88,185.8 v3(78.9,184.78) 79.54,184.15 79.54,183.69 80.6,182.63 CPU1.A14 ; v1(89.42,198.84) 89.4,198.82 v4(89.4,197.28)
  L3 w0.127: v4(88.2,219.46) 90.34,217.31 90.34,208.14 90.78,207.7 90.78,197.21 90.38,196.81 89.87,196.81 v4(89.4,197.28)
  L4 w0.127: v3(78.9,184.78) 78.27,185.42 78.27,186.27 76.65,187.88 76.65,196.19 79.41,198.95 87.73,198.95 v4(89.4,197.28)
TEST19_M: length 60
  TOP w0.102: R1609.1 78.84,184.15 v3(78.9,184.15) 78.9,183.95 80.31,182.54 80.31,181.63 80.3,181.63 80.3,181 CPU1.B14 ; R1747.2 v4(88.2,218.19) ; v1(91.16,197.84) 91.11,197.88 90.78,197.88 v4(90.18,197.28)
  L3 w0.127: v4(88.2,218.19) 90.09,216.3 90.09,208.03 90.53,207.59 90.53,197.63 v4(90.18,197.28)
  L4 w0.127: v3(78.9,184.15) 78.01,185.04 78.01,186.16 76.4,187.78 76.4,196.3 79.3,199.2 88.26,199.2 v4(90.18,197.28)
TMS: length 4.1
  BOTTOM w0.102: U4101.26 96.13,55.08 95.76,54.71 95.32,54.71 94.78,55.24 TP4129.1
TP_DET: length 166.7
  TOP w0.102: U109.118 152.85,46.25 154.08,47.48 v4(154.08,50.16) ; TOUCH1.1 28.57,10.5 v4(29.75,11.68) 29.5,11.94 v1(29.5,12.7) 29.62,12.83 R1785.2
  L3 w0.127: v4(29.75,11.68) 30.01,11.94 30.01,13.61 35.94,19.55 55.41,19.55 57.93,22.07 60.38,22.07 61.6,23.29 61.6,23.96 67.03,29.39 90.63,29.39 93.33,32.08 99.02,32.08 101.48,29.62 110.91,29.62 112.17,30.89 116,30.89 117.7,29.18 128.08,29.18 128.23,29.03 129.49,29.03 130.7,27.83 137.98,27.83 138.84,26.96 142.06,26.96 142.35,27.25 v4(142.35,27.75)
  L4 w0.127: v4(142.35,27.75) 142.35,28.82 142.67,29.14 146.66,29.14 154.68,37.16 154.68,38.38 155.44,39.14 155.44,42.52 154.88,43.08 154.88,43.62 154.65,43.85 154.65,48.71 154.43,48.94 154.43,49.82 v4(154.08,50.16)
TP_NGFF_COEX1: length 4.7
  TOP w0.102: NGFF1.48 119.37,216.5 119.89,215.99 120.23,215.99 120.41,215.8 122.05,215.8 TP39.1
TP_NGFF_COEX2: length 3.2
  TOP w0.102: NGFF1.46 119.44,216 119.68,215.76 120.13,215.76 120.62,215.26 TP38.1
TP_NGFF_COEX3: length 4.8
  TOP w0.102: TP196.1 121.85,214.73 120.83,214.73 120.06,215.5 NGFF1.44
TP_NGFF_LED1: length 5.4
  TOP w0.102: TP63.1 122.05,207.11 118.55,207.11 118.42,206.98 NGFF1.6
TP_NGFF_LED2: length 3.2
  TOP w0.102: TP64.1 120.48,207.65 119.63,208.5 NGFF1.16
TP_NGFF_MLDIR: length 3.7
  TOP w0.102: NGFF1.17 109.6,208.75 108.87,208.03 TP62.1
TPA3131_BSNL: length 2.8
  TOP w0.305: U21.19 152.3,31.36 152.21,31.45 151.34,31.45 v1(151.29,31.5) 151.24,31.5 151.19,31.45 150.35,31.45 C228.1
TPA3131_BSNR: length 2.8
  TOP w0.305: C229.1 150.38,29.97 150.43,30.02 v1(151.29,30.02) 151.46,29.86 U21.22
TPA3131_BSPL: length 5.6
  TOP w0.305: C224.1 150.99,34.72 152.26,34.72 v1(152.31,34.67) 152.36,34.72 153.53,34.72 154.1,34.14 U21.15
TPA3131_BSPR: length 5.4
  TOP w0.305: C223.1 150.95,26.45 150.95,26.71 v1(151.29,27.05) 152.13,27.05 152.4,27.32 153.87,27.32 154.1,27.55 U21.26
TPA3131_FAULT#: length 4.5
  TOP w0.102: U21.30 156.1,27.23 155.35,26.48 v1(155.35,26.42) 155.29,26.42 154.8,25.92 154.8,24.79 154.45,24.45 R383.2
TPA3131_GAIN: length 3.9
  TOP w0.203: R358.1 161.58,29.53 R361.2 v1(159.49,29.53) 159.01,29.53 158.68,29.86 U21.3
TPA3131_GVDD: length 5.9
  TOP w0.305: U21.2 158.48,29.36 159.48,28.36 v1(159.48,28.17) 159.6,28.17 160.24,27.53 160.52,27.53 R357.2
  TOP w0.508: R357.2 R361.1 161.51,28.64 C192.1
TPA3131_LINN: length 2.9
  TOP w0.203: U21.5 158.68,30.86 158.69,30.86 159.32,30.86 v1(159.49,31.04) 160.26,31.04 C200.2
TPA3131_LINN_1: length 2.5
  TOP w0.203: v1(164.52,30.86) 164.4,30.73 R346.2 C200.1
TPA3131_MUTE: length 18.1
  TOP w0.203: v4(149,34.54) 148.42,33.96 v1(148.23,33.96) R638.2 ; v4(159.67,34.16) R360.1 159.81,33.48 158.96,33.48 158.81,33.32 158.81,32.32 158.81,32.22 158.45,31.86 U21.7
  L3 w0.203: v4(149,34.54) 149.26,34.8 158.4,34.8 159.04,34.16 v4(159.67,34.16)
TPA3131_PLIMIT: length 8.4
  TOP w0.203: R347.2 163.77,26.52 162.36,26.52 C193.1 161.13,26.61 R357.1 159.72,26.61 v1(159.53,26.8) 157.94,28.38 U21.1
TPA3131_RINN: length 4.2
  TOP w0.203: U21.32 157.3,28.02 158.26,27.05 v1(158.26,26.44) 158.17,26.44 157,25.27 C198.2
TPA3131_RINN_1: length 2.7
  TOP w0.203: C198.1 R344.2 158.91,23.75 v1(159.29,24.13)
TPA3131_SD: length 14.9
  TOP w0.102: v4(143.49,32) 143.49,33.78 142.54,34.73 Q64.G 143.51,35.07 143.57,35.13 145.64,35.13 146.03,34.73 146.03,34.35 R639.2 146.51,34.1 R638.1 ; Q63.3 140.7,29.16 v4(140.9,28.96)
  BOTTOM w0.102: v4(140.9,28.96) v2(143.06,31.11) 143.49,31.55 v4(143.49,32)
TPA3131_SD1#: length 24
  TOP w0.102: v4(154.59,23.13) 153.88,23.84 153.88,25.2 154.02,25.34 R383.1 154.34,26.25 155.6,27.52 U21.29 ; v4(146.41,30.12) 147,30.71 R643.2 146.65,31.39 C521.1 145.88,32.65 Q64.D
  BOTTOM w0.102: v4(146.41,30.12) 146.41,28.37 148.98,25.81 v2(148.98,25.78) 149,25.78 150.53,24.26 152.81,24.26 153.01,24.06 153.66,24.06 v4(154.59,23.13)
UART0_RXD: length 7
  TOP w0.102: CN1.2 75.09,109.7 v1(75.09,107.14) 75.09,105.35 74.81,105.07 U902.A9
UART0_TXD: length 7.9
  TOP w0.102: CN1.1 76.41,108.48 v1(76.41,107.31) 76.41,105.71 U902.A10
USB3_TX2_EMI_DN: length 3.2
  TOP w0.102: L4.1 163.71,117.64 C91.2 163.55,116.33 v1(163.15,115.94)
USB3_TX2_EMI_DP: length 3
  TOP w0.102: v1(163.67,119.89) 163.55,119.77 C1757.2 163.71,118.32 L4.4
USB3_TX3_EMI_DN: length 1.5
  TOP w0.102: C113.2 163.71,96.18 L56.1
USB3_TX3_EMI_DP: length 1.5
  TOP w0.102: L56.4 163.71,96.86 C111.2
USB30_RXN2: length 165.8
  TOP w0.102: L5.1 164.14,115.36 v4(164.1,115.32) ; CPU1.Y7 v3(74.5,165.8)
  BOTTOM w0.102: 165.9,116.89 165.9,115.97 165.24,115.32 v4(164.1,115.32) ; 165.9,116.89 v2(166.22,116.89) ; 165.9,116.89 165.9,118.06 164.58,119.38 160.85,119.38 158.63,117.16 151.23,117.16 150.57,116.5 128.39,116.5 126.43,118.47 123.86,118.47 121.19,121.14 115.22,121.14 109.64,126.72 88.24,126.72 84.54,130.41 80.48,130.41 74.88,136.02 71.53,136.02 71.17,135.65 67.8,135.65 64.64,138.81 63.85,138.81 63.2,139.45 61.44,139.45 59.96,140.93 59.96,143.87 56.77,147.07 56.77,152.44 57.67,153.34 57.67,154.98 58.88,156.19 65.91,156.19 66.11,155.99 66.67,155.99 66.86,155.81 70.09,155.81 70.81,156.52 70.81,157.44 71.36,157.99 71.36,160.68 71.15,160.89 71.15,162.58 71.32,162.74 72.47,162.74 73.54,163.81 73.95,163.81 74.36,164.23 74.36,165.66 v3(74.5,165.8)
USB30_RXN3: length 191.6
  TOP w0.102: v4(161.55,101.93) 161.3,101.68 160.99,101.68 160.69,101.38 160.69,96.47 161.41,95.74 ; CPU1.AB6 v3(73.7,164.6) ; 161.41,95.74 163.05,94.11 164.27,94.11 164.49,93.89 L57.1 ; 161.41,95.74 v1(161.17,95.49)
  BOTTOM w0.102: v3(73.7,164.6) 73.68,164.6 72.89,163.81 71.37,163.81 70.53,164.66 70.53,166.36 69.63,167.26 67.09,167.26 64.97,169.38 53.88,169.38 52.79,168.29 52.79,156.23 52.08,155.51 52.08,149.14 51.55,148.61 51.55,145.37 55.34,141.58 55.34,139.7 58.31,136.73 58.31,135.09 62.13,131.28 73.9,131.28 78.8,126.37 82.87,126.37 88.6,120.64 89.33,120.64 89.74,120.23 110.41,120.23 111.53,119.12 113.55,117.09 119.52,117.09 122.18,114.43 124.75,114.43 126.72,112.46 148.56,112.46 152.07,108.95 155.84,108.95 160.79,103.99 160.79,102.69 v4(161.55,101.93)
USB30_RXP2: length 165.7
  TOP w0.102: CPU1.Y6 v3(73.7,165.8) ; L5.4 164.14,116.04 v4(164.1,116.08)
  BOTTOM w0.102: v4(164.1,116.08) 164.61,115.57 165.13,115.57 165.64,116.08 165.64,117.96 165.06,118.54 ; 165.06,118.54 164.47,119.13 160.95,119.13 158.73,116.91 151.33,116.91 150.68,116.25 128.29,116.25 126.32,118.21 123.75,118.21 121.09,120.88 115.12,120.88 109.53,126.47 88.13,126.47 84.44,130.16 80.37,130.16 74.77,135.76 71.64,135.76 71.27,135.4 67.69,135.4 64.53,138.56 63.74,138.56 63.1,139.2 61.33,139.2 59.71,140.82 59.71,143.77 56.52,146.96 56.52,152.55 57.42,153.45 57.42,155.09 58.77,156.44 66.01,156.44 66.21,156.24 66.78,156.24 66.96,156.06 69.99,156.06 70.55,156.63 70.55,157.55 71.11,158.1 71.11,160.57 70.9,160.78 70.9,162.69 71.21,163 72.36,163 73.43,164.07 73.84,164.07 74.11,164.33 74.11,165.39 v3(73.7,165.8) ; 165.06,118.54 v2(164.8,118.29)
USB30_RXP3: length 191.6
  TOP w0.102: 163.56,94.36 164.27,94.36 164.49,94.57 L57.4 ; 163.56,94.36 v1(163.56,94.74) ; 163.56,94.36 163.15,94.36 160.94,96.57 160.94,101.27 161.09,101.42 161.3,101.42 v4(161.55,101.17) ; CPU1.AB5 v3(72.9,164.6)
  BOTTOM w0.102: v3(72.9,164.6) 72.9,164.18 72.78,164.07 71.48,164.07 70.78,164.76 70.78,166.47 69.73,167.51 67.19,167.51 65.08,169.63 53.77,169.63 52.54,168.4 52.54,156.33 51.82,155.62 51.82,149.24 51.29,148.71 51.29,145.27 55.09,141.47 55.09,139.6 58.06,136.63 58.06,134.99 62.02,131.02 73.79,131.02 78.7,126.12 82.76,126.12 88.5,120.38 89.23,120.38 89.64,119.98 110.31,119.98 111.35,118.94 113.44,116.84 119.41,116.84 122.08,114.17 124.65,114.17 126.61,112.21 148.45,112.21 151.97,108.69 153.89,108.69 154.04,108.54 154.35,108.54 154.5,108.69 154.8,108.69 154.95,108.54 155.26,108.54 155.41,108.69 155.74,108.69 160.54,103.89 160.54,102.58 161.04,102.08 161.04,101.68 v4(161.55,101.17)
USB30_TXN2: length 161.7
  TOP w0.102: v4(161.81,117.47) C91.1 ; CPU1.AC2 70.53,164.2 70.23,163.9 68.57,163.9 67.82,164.65 67.68,164.79 67.61,164.86 67.61,165.14 v3(67.45,165.3)
  BOTTOM w0.102: 160.83,117.01 158.14,114.32 151.08,114.32 149.98,115.41 127.94,115.41 125.97,117.38 123.41,117.38 120.74,120.05 114.77,120.05 110.64,124.18 89.23,124.18 84.09,129.32 80.03,129.32 75.12,134.23 64.99,134.23 58.87,140.34 58.87,143.42 55.68,146.61 55.68,152.89 56.59,153.79 56.59,155.44 58.43,157.28 66.36,157.28 66.89,156.75 69.77,156.75 70.01,156.99 70.01,157.84 70.52,158.35 70.52,160.02 70.01,160.53 70.01,161.92 67.42,164.52 67.42,165.26 v3(67.45,165.3) ; 160.83,117.01 v2(161.07,116.76) ; 160.83,117.01 161.2,117.37 161.7,117.37 v4(161.81,117.47)
USB30_TXN3: length 184.9
  TOP w0.102: v3(69.36,165.3) 70.16,164.5 70.23,164.5 70.23,164.49 70.71,164.49 70.77,164.55 71.01,164.55 71.01,164.55 71.12,164.44 71.54,164.44 71.7,164.28 CPU1.AC3 ; C113.1 162.28,96.39 161.98,96.39 161.53,96.84 161.53,99.12 162.16,99.76 162.16,102.16 163,103 163.42,103 v4(163.95,103.53)
  BOTTOM w0.102: v2(108.36,121.92) 108.36,121.55 ; 108.36,121.55 110.27,121.55 113.9,117.93 119.86,117.93 122.53,115.26 125.1,115.26 127.06,113.3 148.9,113.3 152.42,109.78 156.19,109.78 162.56,103.4 163.82,103.4 v4(163.95,103.53) ; 108.36,121.55 107.34,121.55 107.19,121.7 106.88,121.7 106.73,121.55 106.43,121.55 106.28,121.7 105.97,121.7 105.82,121.55 105.52,121.55 105.37,121.7 105.06,121.7 104.91,121.55 92.33,121.55 92.18,121.7 91.88,121.7 91.73,121.55 91.42,121.55 91.27,121.7 90.97,121.7 90.82,121.55 90.51,121.55 90.36,121.7 90.06,121.7 89.91,121.55 88.87,121.55 83.21,127.21 79.15,127.21 74.24,132.11 62.47,132.11 59.15,135.44 59.15,137.08 56.18,140.05 56.18,141.93 52.91,145.19 52.91,155.16 53.63,155.88 53.63,167.95 54.22,168.54 64.41,168.54 66.57,166.38 69.24,166.38 69.52,166.1 69.52,165.46 v3(69.36,165.3)
USB30_TXP2: length 161.7
  TOP w0.102: v3(68.09,165.3) 67.86,165.08 67.86,164.96 68.67,164.15 70.05,164.15 CPU1.AC1 ; v4(161.81,118.49) C1757.1
  BOTTOM w0.102: v2(95.29,124.79) 95.29,124.44 ; 95.29,124.44 97.89,124.44 98.04,124.59 98.35,124.59 98.5,124.44 98.8,124.44 98.95,124.59 99.26,124.59 99.41,124.44 99.71,124.44 99.86,124.59 100.17,124.59 100.32,124.44 105.4,124.44 105.55,124.59 105.85,124.59 106,124.44 106.31,124.44 106.46,124.59 106.76,124.59 106.91,124.44 107.22,124.44 107.37,124.59 107.67,124.59 107.82,124.44 110.74,124.44 114.88,120.3 120.84,120.3 123.51,117.63 126.08,117.63 128.04,115.67 150.09,115.67 151.18,114.57 158.04,114.57 161.09,117.63 161.21,117.63 161.31,117.73 161.31,118 v4(161.81,118.49) ; 95.29,124.44 92.81,124.44 92.66,124.59 92.36,124.59 92.21,124.44 91.9,124.44 91.75,124.59 91.45,124.59 91.3,124.44 90.99,124.44 90.85,124.59 90.54,124.59 90.39,124.44 89.34,124.44 84.2,129.58 80.13,129.58 75.23,134.48 65.09,134.48 59.13,140.45 59.13,143.53 55.94,146.72 55.94,152.79 56.84,153.69 56.84,155.33 58.53,157.03 66.25,157.03 66.79,156.49 69.87,156.49 70.26,156.88 70.26,157.74 70.77,158.25 70.77,160.13 70.26,160.63 70.26,162.03 67.67,164.62 67.67,164.88 v3(68.09,165.3)
USB30_TXP3: length 185.1
  TOP w0.102: CPU1.AC4 72.14,164.2 71.64,164.7 71.17,164.7 71.12,164.76 70.68,164.76 70.63,164.7 70.32,164.7 69.99,165.02 v3(69.99,165.3) ; v4(163.94,102.57) 163.76,102.74 163.1,102.74 162.42,102.05 162.42,99.65 161.78,99.02 161.78,96.95 162.09,96.65 162.28,96.65 C111.1
  BOTTOM w0.102: v4(163.94,102.57) 163.94,102.77 163.55,103.15 162.46,103.15 156.08,109.53 152.31,109.53 148.8,113.04 126.96,113.04 124.99,115.01 122.42,115.01 119.76,117.68 113.79,117.68 110.17,121.3 96.71,121.3 ; v2(96.71,120.93) 96.71,121.3 ; 96.71,121.3 88.76,121.3 83.11,126.95 79.04,126.95 74.14,131.86 62.37,131.86 58.97,135.26 58.89,135.33 58.89,136.97 55.92,139.94 55.92,141.82 52.66,145.09 52.66,155.27 53.37,155.98 53.37,168.05 54.12,168.8 64.51,168.8 66.68,166.63 69.34,166.63 69.77,166.2 69.77,165.52 v3(69.99,165.3)
USB_COMP_M: length 2.5
  TOP w0.203: CPU1.AP5 73.3,155.34 72.95,154.99 v3(72.85,154.99)
  BOTTOM w0.203: v3(72.85,154.99) 72.37,155.47 v2(72.17,155.47) 72.17,154.62 R1648.1
USB_EN: length 8.4
  TOP w0.102: Q43.4 91.27,26.42 91.9,27.05 v1(92.34,27.05) 92.34,25.67 91.22,24.56 C249.1 92.68,24.26 C1764.2 R1783.2
USB_EN1: length 14.6
  TOP w0.102: Q1217.3 94.41,22.11 94.27,21.97 94.27,21.59 94.39,21.46 Q1217.2 95.41,21.46 95.64,21.23 95.64,20.54 93.92,18.82 92.09,18.82 91.83,18.55 89.61,18.55 88.95,19.21 v1(88.95,19.9) 89.05,20 R1780.2 90.52,20.07 R1781.1
USB_EN2: length 8.7
  TOP w0.102: 93.61,20.81 93.89,20.54 93.89,19.89 93.48,19.48 92.72,19.48 92.71,19.49 v1(92.66,19.49) 92.64,19.51 92.64,19.51 92.15,20 R1777.2 R1779.1 ; 93.61,20.81 Q1217.6 ; 93.61,20.81 93.91,21.12 93.91,22.12 95.22,23.43 R1783.1
USB_PCH_DN3_NN: length 9
  TOP w0.102: TOUCH1.4 29.23,7.5 29.6,7.87 30.21,7.87 ; 30.21,7.87 v1(30.21,7.47) ; 30.21,7.87 30.49,7.87 30.82,8.2 30.82,9.27 32.04,10.49 32.04,11.25 v4(32.14,11.35) 32.12,11.37 TR9.3
  BOTTOM w0.102: C1774.1 32.21,11.43 v4(32.14,11.35)
USB_PCH_DN4_NN: length 18.5
  TOP w0.102: TR1.2 154.17,197.95 154.39,197.74 154.67,197.74 155.02,197.38 155.02,194.13 155.71,193.44 161.35,193.44 ; 161.35,193.44 v1(161.35,193.85) ; 161.35,193.44 162.57,193.44 163.75,194.62 163.75,196.75 163.25,197.25 WEBCM1.2
USB_PCH_DN5_NN: length 4.6
  TOP w0.102: v1(108.24,206.48) 107.97,206.21 ; 107.97,206.21 107.81,206.38 107.57,206.38 107.36,206.59 TR12.3 ; 107.97,206.21 108.55,205.63 109.38,205.63 109.5,205.75 NGFF1.5
USB_PCH_DP3_PP: length 9
  TOP w0.102: v1(30.67,10.08) 30.97,9.78 ; 30.97,9.78 30.56,9.38 30.56,8.31 30.38,8.13 29.6,8.13 29.23,8.5 TOUCH1.3 ; 30.97,9.78 31.78,10.6 31.78,10.95 v4(31.38,11.35) 31.68,11.66 31.68,11.94 31.44,12.18 TR9.2
  BOTTOM w0.102: v4(31.38,11.35) 31.38,11.51 31.4,11.53 31.4,12.18 C1773.1
USB_PCH_DP4_PP: length 18.9
  TOP w0.102: 164,195.55 164,194.52 162.67,193.19 155.61,193.19 154.77,194.03 154.77,197.28 154.56,197.49 154.39,197.49 154.17,197.27 TR1.3 ; 164,195.55 164,196.75 164.5,197.25 WEBCM1.1 ; 164,195.55 v1(164.4,195.55)
USB_PCH_DP5_PP: length 4.6
  TOP w0.102: 108.45,205.37 109.38,205.37 109.5,205.25 NGFF1.3 ; 108.45,205.37 v1(108.19,205.11) ; 108.45,205.37 107.7,206.12 107.57,206.12 107.36,205.91 TR12.2
USBCLK_TP: length 8.6
  TOP w0.102: CPU1.AP8 75.7,155.34 v3(75.32,154.96)
  BOTTOM w0.102: v3(75.32,154.96) 74.88,155.4 73.01,155.4 72.45,155.96 71.92,155.96 69.81,153.85 69.71,153.85 v2(69.65,153.8) 69.43,153.57 R2067.1
USBOC01*: length 303.8
  TOP w0.102: R1725.2 R762.1 C589.1 107.92,30.04 108.44,29.51 v4(108.44,29.11) ; CPU1.AH9 76.2,159.9 v3(76.2,159.56)
  L3 w0.127: v4(94.6,69.88) 94.55,69.93 88.11,69.93 86.71,71.33 85.89,72.15 63.81,72.15 61.46,69.8 42.45,69.8 40.24,72.01 40.24,72.13 39.63,72.74 39.63,73.27 36.36,76.55 36.36,77.79 36.3,77.85 36.3,84.93 36.82,85.45 36.82,90.4 36.18,91.04 36.18,106.6 33.79,108.99 33.79,130.97 30.01,134.75 15.84,134.75 13.99,136.6 13.99,151.54 11.3,154.23 11.3,165.05 16.01,169.76 25.35,169.76 27.85,167.25 39.95,167.25 40.86,166.34 47.75,166.34 48.63,167.22 57.75,167.22 58.89,166.09 59.38,166.09 61.19,167.9 63.54,167.9 65.31,166.13 65.31,165.06 66.89,163.48 68.83,163.48 70.69,161.62 72.56,161.62 73.53,160.65 73.53,160.65 73.77,160.4 75.36,160.4 v3(76.2,159.56)
  L4 w0.127: v4(94.6,69.88) 96.08,68.39 96.08,63.56 95.15,62.62 95.02,62.62 94.88,62.48 94.39,62.48 91.87,59.96 91.87,56.04 92.72,55.19 92.72,45.77 93.95,44.54 93.95,42.99 97.32,39.62 97.32,34.35 102.55,29.11 v4(108.44,29.11)
  BOTTOM w0.102: v4(94.6,69.88) 94.83,69.88 95.26,69.44 v2(95.29,69.44)
USBOC02*: length 341.4
  TOP w0.102: v3(65.16,158.6) 65.16,158.67 67.2,160.72 69.82,160.72 CPU1.AG1 ; R1728.2 R1727.1 C1756.1 175.17,127.89 174.86,128.19 167.65,128.19 166.53,127.08 v1(166.53,123.77) 166.64,123.67 166.64,123.41 167.24,122.81 v4(167.37,122.81)
  L3 w0.127: v4(37.63,151.13) 37.63,151.86 38.63,152.86 39.92,152.86 40.51,152.27 42.99,152.27 43.9,153.18 43.9,159.3 42.45,160.75 42.45,161.5 43.12,162.17 50.24,162.17 52.33,160.08 57.15,160.08 58.64,158.6 v3(65.16,158.6) ; v4(38.26,81.79) 38.26,81.26 38.54,80.98 38.54,79.71 46.4,71.84 60.63,71.84 63.08,74.3 87.26,74.3 88.78,72.77 95.66,72.77 101.13,78.23 107.85,78.23 118.75,67.34 137.8,67.34 138.62,68.15 143.26,68.15 143.93,67.49 154.75,67.49 155.49,66.74 159.36,66.74 160.75,68.13 160.75,69.13 157.51,72.37 157.51,73.08 155.99,74.61 155.99,75.36 155.39,75.95 155.39,80.24 155.43,80.28 155.43,86.4 156.42,87.39 156.42,92.63 161.99,98.2 v4(163.94,98.2)
  L4 w0.127: v4(38.26,81.79) 40.38,83.91 40.38,120.79 38.01,123.16 38.01,133.98 38.01,134.29 38.01,134.61 38.01,134.61 38.01,135.84 38.26,136.09 38.26,138.5 35.09,141.67 35.09,148.21 37.63,150.75 v4(37.63,151.13) ; v4(167.37,122.81) 169.36,120.82 169.36,111.58 167.91,110.13 167.91,106.1 165.39,103.58 165.39,98.93 164.65,98.2 v4(163.94,98.2)
USBP0N_EXT: length 20
  TOP w0.102: TR10.2 95.39,33.22 95.39,30.06 94.7,29.38 94.7,28.84 D24.6 94.7,28.41 94.7,27.97 94.88,27.79 95.44,27.79 95.92,28.27 95.92,31.58 96.3,31.96 96.3,34.14 99.31,37.16 100.77,37.16 101.06,37.45 USB3.2
USBP0P_EXT: length 20.2
  TOP w0.102: TR10.3 94.77,32.89 95.13,32.53 95.13,31.53 D24.1 95.13,31.1 95.13,30.17 94.45,29.48 94.45,27.86 94.77,27.54 95.54,27.54 96.17,28.16 96.17,31.47 96.55,31.85 96.55,34.04 99.42,36.9 100.19,36.9 USB3.3
USBP1N_EXT: length 24.7
  TOP w0.102: TR14.2 93.16,33.12 92.8,32.75 92.8,31.53 D24.3 92.8,31.1 92.8,30.27 93.48,29.59 93.48,26.52 95.27,24.73 ; 95.27,24.73 v1(95.51,24.97) ; 95.27,24.73 96.58,23.42 96.58,17.46 99.88,14.16 100.93,14.16 101.06,14.28 USB4.2
USBP1P_EXT: length 24.6
  TOP w0.102: TR14.3 92.54,33.22 92.54,30.17 93.23,29.48 93.23,28.84 D24.4 93.23,28.41 93.23,26.41 93.77,25.87 ; 93.77,25.87 96.32,23.31 96.32,17.35 99.78,13.9 100.19,13.9 USB4.3 ; 93.77,25.87 v1(93.51,25.6)
USBP6N_EXT: length 20.7
  TOP w0.102: TR3.3 165.22,108.37 165.36,108.51 165.96,108.51 166.21,108.77 166.69,108.77 D4.1 167.12,108.77 167.95,108.77 168.63,108.08 170.98,108.08 175.29,112.39 175.29,117.03 174.52,117.81 173.72,117.81 173.44,117.52 172.94,117.52 SSUSB1.2
USBP6P_EXT: length 20.7
  TOP w0.102: SSUSB1.3 172.62,116.35 173.83,117.55 174.41,117.55 175.04,116.93 175.04,112.5 170.87,108.34 169.81,108.34 D4.6 169.38,108.34 168.74,108.34 168.05,109.02 166.11,109.02 165.85,108.76 165.42,108.76 165.13,109.05 TR3.2
USBP7N_EXT: length 22
  TOP w0.102: SSUSB2.2 172.47,96.34 172.35,96.21 172.35,95.59 172.47,95.47 172.88,95.47 173.72,96.31 174.53,96.31 175.1,96.87 175.1,99.77 172.45,102.42 172.45,104.44 170.71,106.18 168.61,106.18 167.93,106.86 167.12,106.86 D4.3 166.69,106.86 166.09,106.86 165.45,106.21 TR4.3
USBP7P_EXT: length 22.1
  TOP w0.102: SSUSB2.3 172.62,94.85 173.83,96.05 174.64,96.05 175.35,96.76 175.35,99.88 172.7,102.52 172.7,104.55 170.82,106.43 169.81,106.43 D4.4 169.38,106.43 168.72,106.43 168.03,107.12 165.99,107.12 165.77,106.89 TR4.2
USBSS_CALRN: length 11.6
  TOP w0.127: CPU1.AD2 70.98,163.72 70.35,163.72 70.32,163.68 68.13,163.68 67.85,163.96
  TOP w0.203: 67.85,163.96 66.92,164.89 66.92,170.27 v1(66.96,170.31) 66.84,170.43 R1649.1
USBSS_CALRP: length 15.9
  TOP w0.203: R559.1 60.17,170.37 v1(60.23,170.43) 60.45,170.22 63.24,170.22 66.45,167 66.45,164.34 67.39,163.4 CPU1.AD1
USBVCC01: length 19.2
  TOP w0.508: USB3.1 102.09,40.53 ; USB3.1 101.06,39.5 ; USB3.1 100.03,40.53 ; USB3.1 101.06,41.56 ; TC7.1 106.21,25.57 ; TC7.1 106.21,23.46 ; TC7.1 107.26,24.51 ; TC7.1 105.15,24.51 ; 101.06,18.56 USB4.1 102.09,17.53 ; 100.62,28.63 98.19,28.63 C1747.1 C1754.2 94.58,26.86 93.97,27.48 D24.5
USBVCC01_E: length 3.7
  TOP w0.508: L55.1 108.17,18.86 C872.1 109.09,18.86 109.46,18.49 v1(109.46,16.99)
USBVCC23: length 18.4
  TOP w0.508: D4.5 v4(170.64,107.6) 170.92,107.31 C1753.2 ; 171.73,120.34 SSUSB1.1 172.62,121.23
  TOP w1.016: 169.91,121.87 168.08,121.87 v1(168.05,121.89) ; v4(166.07,110.19) 167.01,111.12 C104.1 C105.2
  L3 w0.508: TC8.1 166.91,101.38 ; TC8.1 167.97,100.33 ; TC8.1 166.91,99.28 ; 171.73,120.34 SSUSB1.1 ; SSUSB1.1 172.62,119.45 ; SSUSB1.1 172.62,121.23 ; 171.73,98.84 SSUSB2.1 172.62,99.73
USBVCCTP:
  vias: v1(29.62,5.08) v2(26.96,8.13) v7(26.54,5.79) v7(26.55,6.83)
V_0P675_S3: length 96.5
  TOP w0.33: DIMM1.204 v4(137.83,127.25) ; v4(153.07,127.25) 153.07,127.25 DIMM2.204 ; DIMM1.203 132.07,126.68 133.95,126.68 134.5,127.23 v4(134.5,127.35) ; v4(148.12,127.25) 147.82,127.55 DIMM2.203
  TOP w0.508: PR5018.2 134.91,76.71 v7(133.89,77.72) 134.91,78.74 PR5019.2
  L4 w0.508: v7(133.89,77.72) 133.87,77.72 132.19,79.4 132.19,107.33 134.81,109.95 134.81,121 137.64,123.84 144.7,123.84 v4(148.12,127.25)
  BOTTOM w0.508: v4(134.5,127.35) 134.63,127.48 134.63,127.52 135.08,127.96 135.09,127.96 135.14,128.02 C1971.1 137.06,128.02 v4(137.83,127.25) 138.28,127.7 C1977.1 139.29,127.7 140.38,126.61 v2(140.38,126.26) 140.38,126.18 141.4,125.17 147.7,125.17 148.12,125.58 v4(148.12,127.25) 148.56,127.7 C1732.1 149.45,127.38 C1724.1 150.81,127.91 152.45,127.91 152.84,127.53 152.84,127.48 v4(153.07,127.25)
V_1P5_HDMI: length 118.5
  TOP w0.203: C3376.2 136.28,30.69 136.28,31.37 135.8,31.85 135.42,31.85 134.54,32.73 U118.40 134.84,33.03 134.95,33.13 v4(135.17,33.13) ; v4(130.3,33.03) U118.31 130.94,32.52 130.27,31.85 129.66,31.85 128.8,30.99 C3377.1 ; U118.12 134.14,38.67 134.51,39.04 134.6,39.04 135.16,39.6 135.16,40.42 C3381.2 ; 130.94,38.73 131.07,38.86 131.21,38.86 131.34,38.73 U118.19 ; 130.94,38.73 130.36,39.31 130.36,40.42 C3378.1 ; 130.94,38.73 U118.20
  TOP w0.508: v4(128.81,40.23) 128.71,40.13 128.18,40.13 127.95,40.36 127.95,40.53 127.92,40.56 C3366.1 C3383.1 128.82,41.09 C3378.1 ; v4(156.59,85.47) 156.59,86.89 R79649.1 ; R2081.1 127.52,44.5 128.05,45.03 v4(128.05,45.47) ; C3381.2 v4(135.79,40.13)
  L4 w0.508: v4(138.72,74.42) 133.18,68.88 133.18,61.54 131.65,60.02 131.65,42.24 129.67,40.26 ; v4(128.81,40.23) 128.84,40.26 129.67,40.26 ; v4(130.3,33.03) 130.49,33.22 130.49,39.44 129.67,40.26
  BOTTOM w0.508: C3381.2 v4(135.79,40.13) 134.43,38.77 130.27,38.77 v4(128.81,40.23) 128.02,41.02 128.02,45.44 v4(128.05,45.47) 128.05,45.62 129.17,46.74 U119.2 ; v4(156.59,85.47) 153.83,82.71 v2(152.35,82.71) 151.74,82.71 143.45,74.42 v4(138.72,74.42) ; v4(130.3,33.03) 134.84,33.03 134.95,33.13 v4(135.17,33.13)
V_1P05_LAN: length 10.6
  TOP w0.203: v4(38.42,11.28) 38.48,11.33 U16.30 ; U16.24 35.79,12.23 v4(35.65,12.09) ; U16.22 v4(34.83,14.26) ; v4(40.93,14.26) U16.3 ; v4(40.93,16.26) U16.8
  TOP w0.406: C213.1 41.56,18.34 41.05,17.83 41.05,16.38 v4(40.93,16.26)
  TOP w0.508: C574.1 41.97,14.26 v4(40.93,14.26)
  vias: v2(34.48,13.11)
V_1P5_PWR:
  vias: v1(33.66,146.18)
V_1P8_VDDIO:
  vias: v1(26.37,147.35)
V_3_CARD_BD:
  vias: v1(163.81,143.86)
V_3P0_BAT_VREG: length 191.5
  TOP w0.508: v4(167.52,97.94) 167.55,97.97 167.55,98.53 168.74,99.72 168.74,102.92 167.32,104.34 163.72,104.34 163.03,105.03 157.34,105.03 153.94,101.63 153.94,101.55 153.55,101.17 153.48,101.17 v4(153.28,100.97) ; D23.3 74.52,49.07 75.09,49.65 75.09,51.17 75.29,51.37 75.29,56.06 75.62,56.39 77.58,56.39 79.18,57.99 79.18,60.97 v4(79.23,61.02)
  L3 w0.508: v4(161.98,62.66) 160.35,61.04 149.06,61.04 147.84,62.26 142.83,62.26 140.92,60.35 137.05,60.35 136.89,60.2 135.29,60.2 135.02,60.46 112.96,60.46 111.2,58.7 108.45,58.7 107.59,59.56 107.59,59.56 96.11,59.56 94.65,61.02 v4(79.23,61.02)
  L4 w0.508: v4(159.29,120.9) 159.29,112.67 154.9,108.28 154.9,106.24 153.94,105.28 153.94,101.31 153.59,100.97 v4(153.28,100.97) ; v4(161.98,62.66) 161.98,72.89 162.49,73.4 162.49,74.07 164.73,76.3 164.73,81.46 169.35,86.09 169.35,91.31 167.55,93.12 167.55,97.92 v4(167.52,97.94)
  BOTTOM w0.508: R322.2 163.15,62.64 162.01,62.64 v4(161.98,62.66) ; v2(154.03,100.43) 153.5,100.97 v4(153.28,100.97)
V_3P3_A: length 635.5
  TOP w0.203: v4(143.42,60.83) 143.95,60.83 U109.64 ; U109.1 v4(159.7,46.38) ; C550.2 160.94,61.98 160.66,61.7 160.33,61.7 158.4,59.76 U109.32
  TOP w0.254: v4(159.93,62.23) 159.99,62.29 C550.2 ; PG4902.2 PT4902.1
  TOP w0.508: C1699.1 87.6,13.27 85.83,11.51 85.83,4.01 83.98,2.16 47.28,2.16 46.52,2.92 24.21,2.92 v4(24.11,2.82) ; R644.2 119.81,46.88 120.77,45.91 122.22,45.91 U7.8 125.84,46.61 126.65,47.42 126.65,50.48 v4(126.64,50.49) 126.64,50.74 127.64,51.74 130,51.74 132.13,49.62 R1824.2 R645.2 132.13,46.91 R1823.2 ; R675.2 159.04,40.58 R668.2 v4(160.84,39.69) ; v4(67.67,52.57) 66.75,52.57 66.23,52.04 66.23,51.99 64.22,49.99 v4(63.79,49.99) ; v4(67.67,52.57) 68.63,51.61 v4(71.74,51.61) 73.05,51.61 R1672.2 73.07,55.77 75.73,58.42 v4(77.38,58.42) ; v4(67.67,52.57) v4(67.67,55.36) 67.83,55.36 68.46,55.99 68.46,60.35 ; v4(16.88,161.86) 16.88,160.82 16.21,160.15 15.84,160.15 PR4805.1 ; v4(152.94,65.38) R353.1 152.1,64.58 151.98,64.71 R79688.2 R79687.2 ; v4(147.34,33.27) 147.05,32.98 R639.1 146.51,32.42 R643.1 ; R702.1 v4(145.83,65.51) ; PR5289.1 69.46,60.64 69.16,60.35 68.46,60.35 ; v4(65.69,64.41) 65.69,65.41 66.44,66.15 PR5273.1 PR5281.1 ; 68.46,60.35 67.98,60.83 v4(67.22,60.83) ; PR190.2 v4(107.86,6.54) ; L60.2 142.53,38.74 143.14,38.13 143.77,38.13 144.41,37.49 145.6,37.49 146.55,36.54 147.06,36.54 147.14,36.46 148.8,36.46 149.4,37.06 149.53,37.06 150.17,37.7 150.17,38.71 v4(150.07,38.81) ; R650.2 R655.2 119.18,50.8 118.98,50.6 v4(118.98,50.49) ; R79707.1 103.79,55.63 103.16,56.26 v4(103.16,56.39) 102.46,56.39 R80212.2 ; v4(43.72,165.48) 45.12,165.48 45.25,165.61 R2018.2
  L3 w0.508: v4(103.16,56.39) 103.44,56.11 103.44,55.1 102.92,54.58 99.35,54.58 98.18,55.75 v4(93,55.75) 92.49,55.75 91.53,56.71 89.29,56.71 86.75,59.24 83.1,59.24 82.28,58.42 v4(77.38,58.42) ; v4(107.86,6.54) 107.86,5.84 106.97,4.95 106.97,3.73 ; v4(159.93,62.23) 159.49,61.8 155.4,61.8 152.94,64.26 v4(152.94,65.38) 151.65,65.38 150.91,64.64 146.69,64.64 v4(145.83,65.51) 144.64,65.51 142.66,63.53 142.3,63.53 140.62,61.85 135.9,61.85 134.96,62.79 127.29,62.79 v4(126.86,62.36) ; v4(23.78,170.43) 20.61,170.43 19.97,171.07 19.46,171.07 18.98,170.59 17.47,170.59 v4(17.32,170.43)
  L4 w0.508: v4(159.93,62.23) 159.93,58.94 160.36,58.51 160.36,57.16 159.97,56.77 159.48,56.77 159.1,56.39 159.1,55 159.04,54.94 159.04,54.39 159.42,54.01 159.87,54.01 161.32,52.56 161.32,48 v4(159.7,46.38) 159.67,46.35 159.67,44.5 160.29,43.88 160.29,40.24 v4(160.84,39.69) 160.84,27.74 149.85,16.75 149.85,7.94 149.44,7.52 149.29,7.37 148.9,6.99 147.96,6.99 147.96,6.99 147.47,6.99 145.65,5.16 v4(145.45,5.16) ; v4(126.86,62.36) 127.95,61.26 127.95,51.8 v4(126.64,50.49) ; v4(103.16,56.39) 103.16,56.64 103.79,57.28 110.91,57.28 117.76,64.14 v7(117.76,65.35) ; v4(150.07,38.81) 150.27,38.61 150.27,36.83 147.34,33.9 v4(147.34,33.27) ; v4(24.11,2.82) 24.11,8.71 26.3,10.9 26.3,11.07 26.55,11.32 26.55,12.55 26.42,12.68 26.42,14.45 26.96,14.99 26.96,22.63 25.34,24.24 25.34,26.84 v4(25.94,27.43) 26.09,27.58 26.09,28.04 25.18,28.96 25.18,39.14 30,43.97 30,51.49 26.37,55.12 26.37,69.11 29.91,72.64 30.33,72.64 30.72,73.03 30.72,73.06 31.29,73.63 31.32,73.63 31.71,74.02 31.71,76.99 32.33,77.61 32.33,86.85 35.08,89.6 35.08,98.19 35.06,98.21 35.06,102.11 34.25,102.92 34.25,104.25 33.56,104.93 33.56,118.54 33.38,118.71 33.38,121.79 32.82,122.35 32.82,134.33 30.34,136.82 24.66,136.82 21.75,139.72 21.75,144.38 17.33,148.8 17.33,153.04 16.96,153.41 16.96,161.78 v4(16.88,161.86) 16.88,162.91 16.16,163.63 16.16,165.97 16.77,166.59 16.77,169.89 v4(17.32,170.43)
  BOTTOM w0.508: Q9649.S 89.38,52.87 C6725.2 R80228.2 89.95,55.24 90.46,55.75 v4(93,55.75) ; v4(143.42,60.83) 143.67,60.83 143.67,60.84 144.37,60.84 C1820.2 144.43,63.5 v2(144.56,63.63) 145.83,64.9 v4(145.83,65.51) ; PR4450.2 71.88,51.75 v4(71.74,51.61) ; PR4425.1 v4(67.67,52.57) ; R319.1 163.39,63.68 163.35,63.72 161.92,63.72 160.43,62.23 v4(159.93,62.23) ; v4(67.22,60.83) PR4427.1 66.39,62.04 65.69,62.74 v4(65.69,64.41) ; 159.67,46.35 v4(159.7,46.38) 160.6,47.28 R276.1 ; 159.67,46.35 C1826.2 ; 159.67,46.35 159.67,45.42 C1824.1 158.26,44.01 R80217.1 ; v4(126.86,62.36) 123.86,65.35 v7(117.76,65.35) ; v4(160.84,39.69) 158.97,39.69 156.62,37.34 155.2,37.34 154.62,37.92 154.62,38.32 154.23,38.71 153.83,38.71 153.78,38.76 150.12,38.76 v4(150.07,38.81) ; v4(23.78,170.43) 24.64,170.43 28.45,166.62 42.58,166.62 v4(43.72,165.48) ; v4(63.79,49.99) PR5278.1 PR5286.2 ; PR4426.1 v4(67.67,55.36) ; v4(126.64,50.49) v4(118.98,50.49) ; R1760.1 26.26,27.11 v4(25.94,27.43) ; v4(152.94,65.38) v2(152.94,66.29)
  vias: v4(88.76,14) v7(88.25,15.72) v7(88.25,14.71) v7(88.55,4.7) v7(88.55,3.68) v7(138.31,8.68) v7(138.31,7.71) v7(139.23,8.13)
V_3P3_LAN: length 96.9
  TOP w0.203: v4(39.78,11.68) 39.76,11.68 39.28,12.16 U16.32 ; v4(34.84,12.09) 34.84,13.47 35.23,13.86 U16.23 ; v4(38.48,17.91) U16.11
  TOP w0.508: v4(41.1,10.03) 40.91,10.22 R1819.1 40.29,11.15 39.78,11.66 v4(39.78,11.68) ; C1806.1 70.52,29.91 C1802.1 70.77,28.83 v4(70.77,28.11) ; v4(47.94,14.61) C1807.1 C1803.1 C209.1 C1804.1 v4(48.29,16.87) ; R79618.1 U12.5 77.78,29.08 77.5,28.8 v3(77.5,27.64) ; C3454.1 38.51,19.02 38.51,17.94 v4(38.48,17.91) ; U10.5 v4(47.2,11.94) ; C572.1 34.01,12.06 34.82,12.06 v4(34.84,12.09)
  L3 w0.508: v4(47.2,11.94) 47.2,10.46 46.57,9.83 41.31,9.83 v4(41.1,10.03)
  L4 w0.508: v4(47.94,14.61) 47.2,13.87 v4(47.2,11.94) ; v4(38.48,17.91) 38.48,17.91 37.37,17.91 36.23,16.76 36.23,14.1 34.84,12.71 v4(34.84,12.09) 34.84,11.16 35.38,10.62 38.7,10.62 39.53,11.46 39.56,11.46 v4(39.78,11.68)
  BOTTOM w0.508: U11.5 v4(47.2,11.94) ; v3(77.5,27.64) 76.41,28.73 71.39,28.73 v4(70.77,28.11) 70.77,25.81 69.1,24.13 v2(67.09,24.13) 67.06,24.1 63.05,24.1 58.68,19.74 49.23,19.74 48.29,18.8 v4(48.29,16.87) ; R1816.1 31.4,7.56 29.87,9.09 v4(29.78,9.09) ; C587.1 C84.1 38.42,17.97 v4(38.48,17.91) ; v4(39.78,11.68) 39.47,11.68 39.02,12.13 C3453.1
  BOTTOM w1.016: v4(41.1,10.03) 41.94,9.19 Q44.D
V_3P3_PCIVAUX: length 46.3
  TOP w0.305: 120.18,223.14 119.54,222.5 NGFF1.72
  TOP w0.508: Q1229.G 102.05,223.58 R1.1 R1932.1
  TOP w0.762: v7(102.46,225.17) Q1229.G
  L3 w1.27: 121.64,205.36 121.89,205.61 121.89,225.08 v7(121.52,225.45)
  L4 w1.016: v7(121.52,225.45) 120.6,226.37 103.66,226.37 v7(102.46,225.17)
  vias: v2(121.83,205.36) v4(121.64,204.17) v4(121.64,203.3)
V_5_CODEC: length 24.5
  TOP w0.203: C147.2 166.66,75.75 166.66,76.37 166.19,76.83 U6.39
  TOP w0.508: v4(169.58,76.71) 169.58,75.77 C146.1 168.55,74.74 C147.2
  L4 w0.508: v4(170.77,88.98) 170.77,78.89 169.58,77.7 v4(169.58,76.71)
  BOTTOM w0.508: L19.1 165.69,88.98 C450.1 167.36,89.04 v2(169.55,89.04) 170.7,89.04 v4(170.77,88.98)
V_5_LCD1: length 1.7
  BOTTOM w0.508: v2(34.22,106.02) 34.22,106.65 L1.1
V_5_LCD2:
  vias: v2(36.66,109.12)
V_5HDD: length 8.5
  BOTTOM w0.508: SATAP1.3 12,196.07 ; SATAP1.3 10.93,195 ; SATAP1.3 13.07,195 ; SATAP1.3 12,193.93 ; 12,198.93 SATAP1.1 ; SATAP1.1 10.93,200 ; SATAP1.1 12,201.07 ; SATAP1.1 13.07,200
V_5P0_A: length 274.6
  TOP w0.203: v4(143.46,7.37) 143.76,7.37 144.09,7.04 U52.4 ; U54.4 90.33,13.86
  TOP w0.254: PG4903.1 PT4903.1
  TOP w0.457: C1829.1 142.39,7.76 142.78,7.37 v4(143.46,7.37)
  TOP w0.508: v4(152.56,89) 151.47,87.91 151.47,81.13 v4(151.47,81.13) ; U9001.4 v3(67.44,90.25) ; R79708.1 v4(111.86,61.71)
  L4 w0.508: v4(111.86,61.71) 111.86,66.46 109.99,68.33 v4(109.99,72.11) ; v3(74.68,88.54) 75.32,87.91 80.37,87.91 81.19,87.1 81.19,85.17 84.08,82.27 84.08,79.58 91.09,72.57 v4(91.09,63.63) 91.09,62.99 87.39,59.29 87.39,50.34 89.49,48.24 89.49,35.48 v7(88.68,34.67) ; v4(143.46,7.37) 143.13,7.37 142.88,7.61 142.88,8.61 143.29,9.02 v4(143.67,9.02)
  L4 w2.032: v7(97.42,11.66) 97.42,10.77 95.16,8.51 95.16,5.08 95.94,4.29 134.37,4.29 135.54,5.46 135.54,8.38 137.45,10.29 v7(140.37,10.29)
  BOTTOM w0.508: v3(67.44,90.25) 68.51,89.18 74.05,89.18 v3(74.68,88.54) ; v4(152.56,89) 152.82,88.75 158.5,88.75 158.58,88.82 v2(162.72,88.82) D21.K 165.64,87.55 L19.2 ; v4(151.47,81.13) 151.07,81.13 143.7,73.76 113.98,73.76 112.33,72.11 v4(109.99,72.11) 109.99,73.04 106.57,76.45 99.91,76.45 94.79,71.34 94.79,70.9 94.4,70.51 94.24,70.51 91.09,67.36 v4(91.09,63.63)
  BOTTOM w2.032: 88.76,31.7 90.53,29.92 90.53,28.17 95.85,22.85 95.85,19.56 97.59,17.82 97.59,11.84 v7(97.42,11.66)
  vias: v7(87.61,34.67) v7(87.66,33.5) v7(88.81,33.58) v7(138.26,22.72) v7(138.26,21.75) v7(138.26,20.79)
V_5P0_HDMI_CONN: length 3
  TOP w0.305: 114.71,41.66 114.99,41.38 115.79,41.38 115.85,41.32 HDMI2.2
  BOTTOM w0.508: v2(107.56,40.06) 107.73,39.9 v4(107.73,39.27)
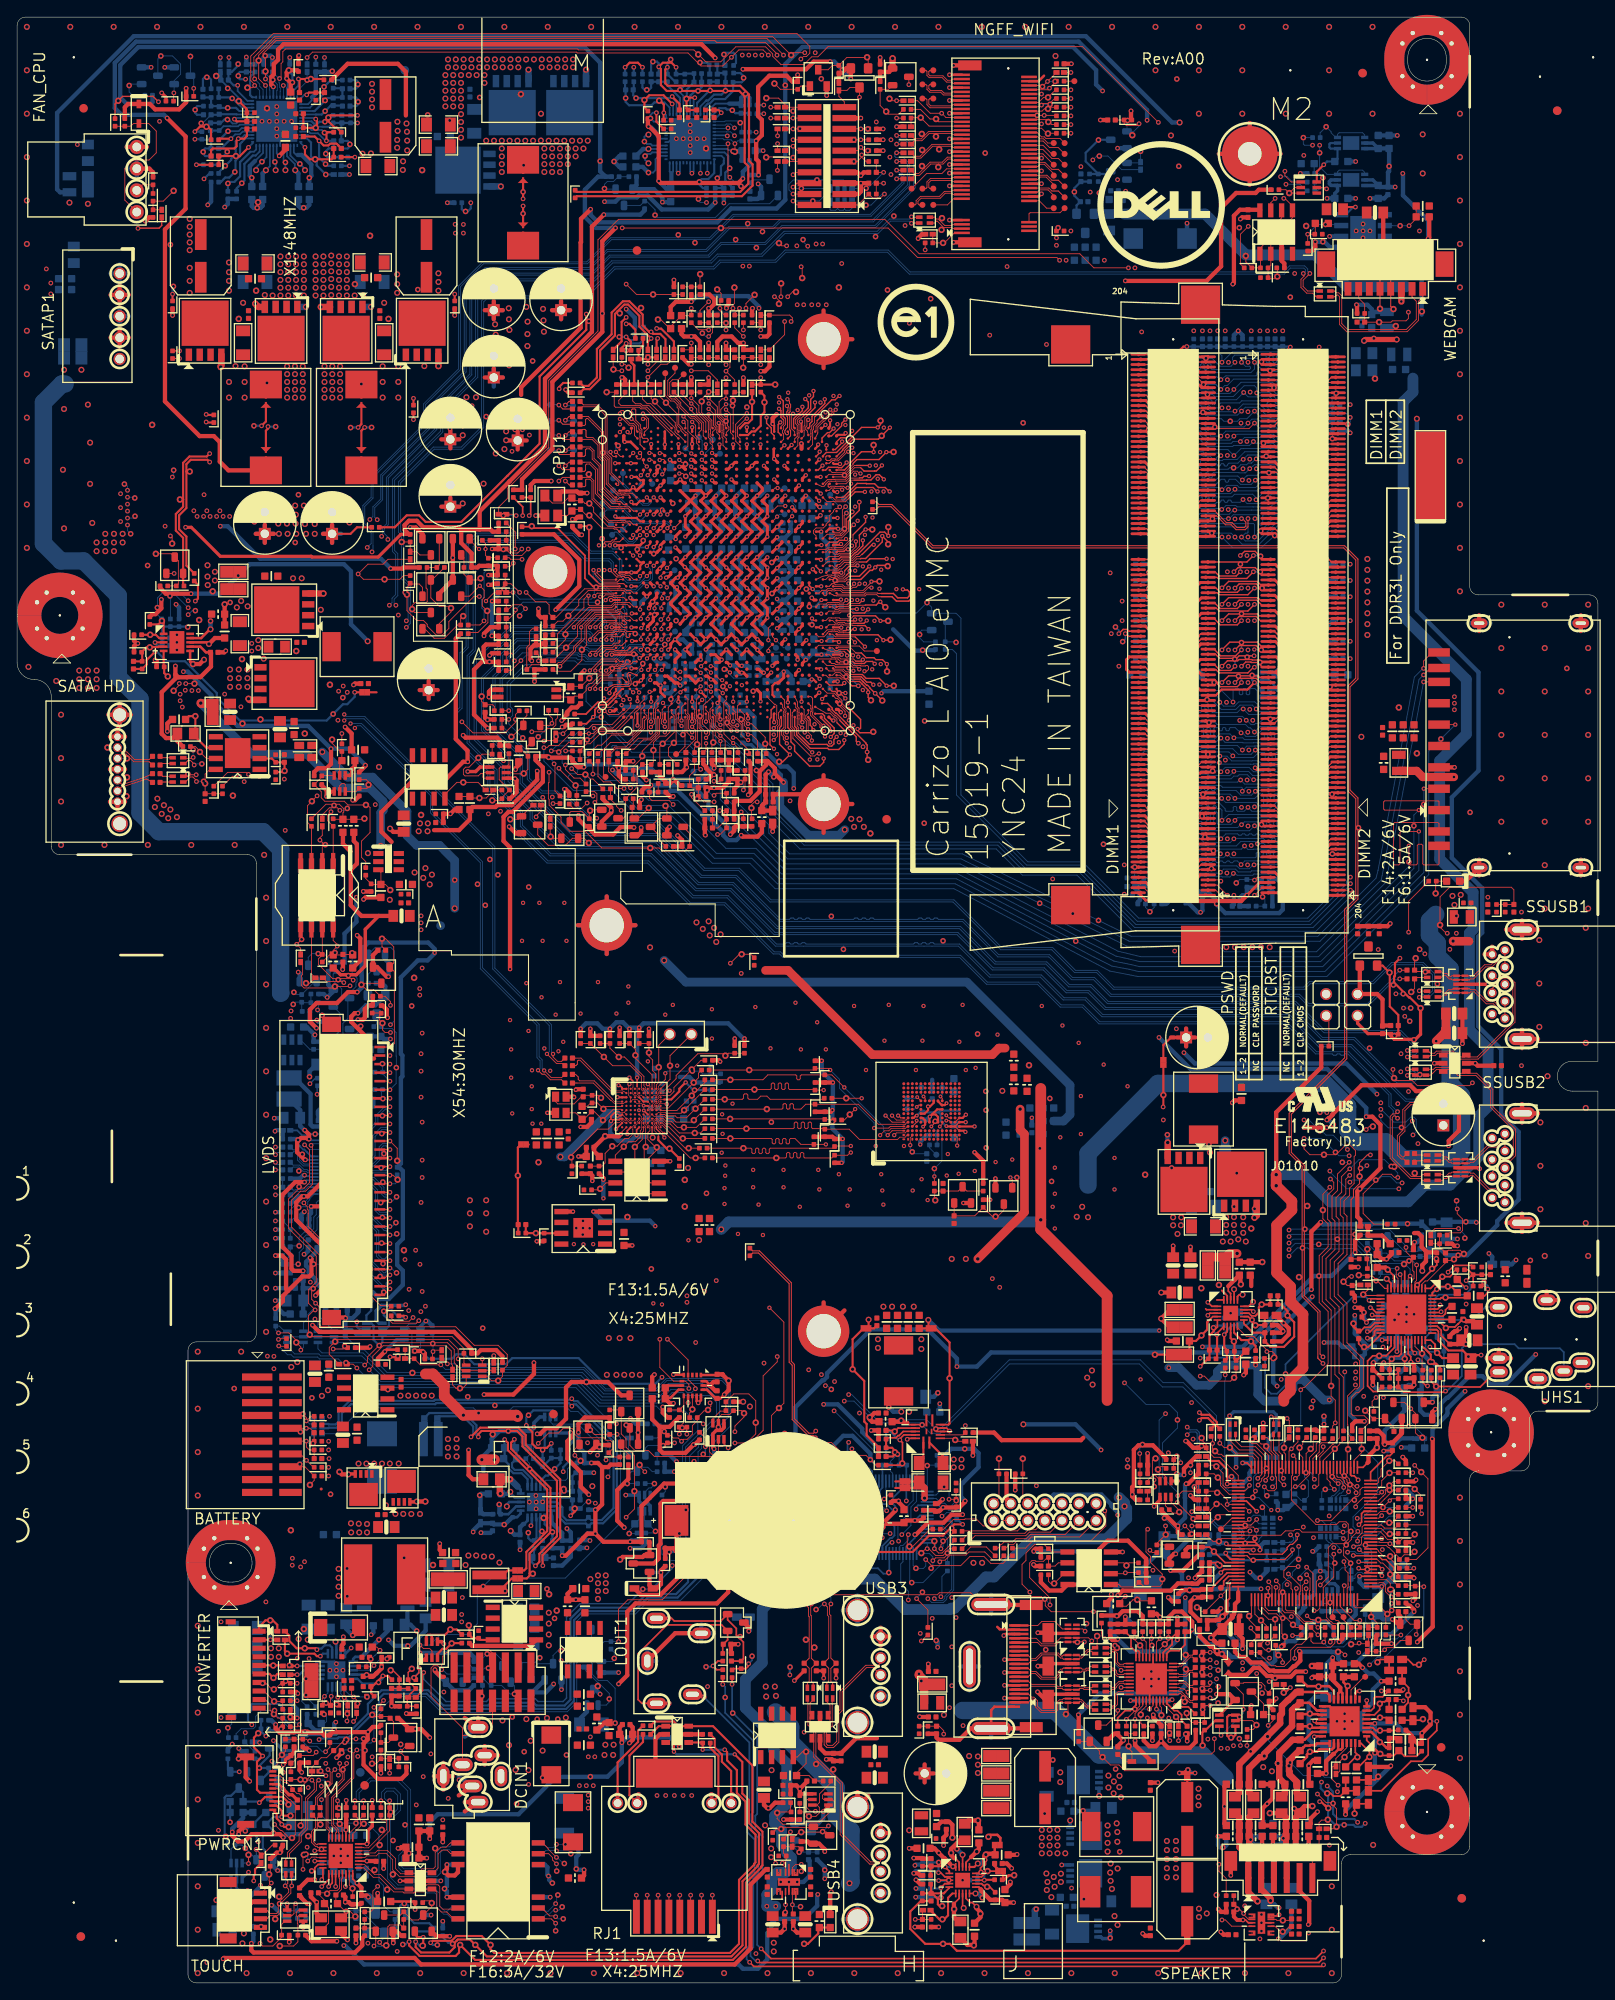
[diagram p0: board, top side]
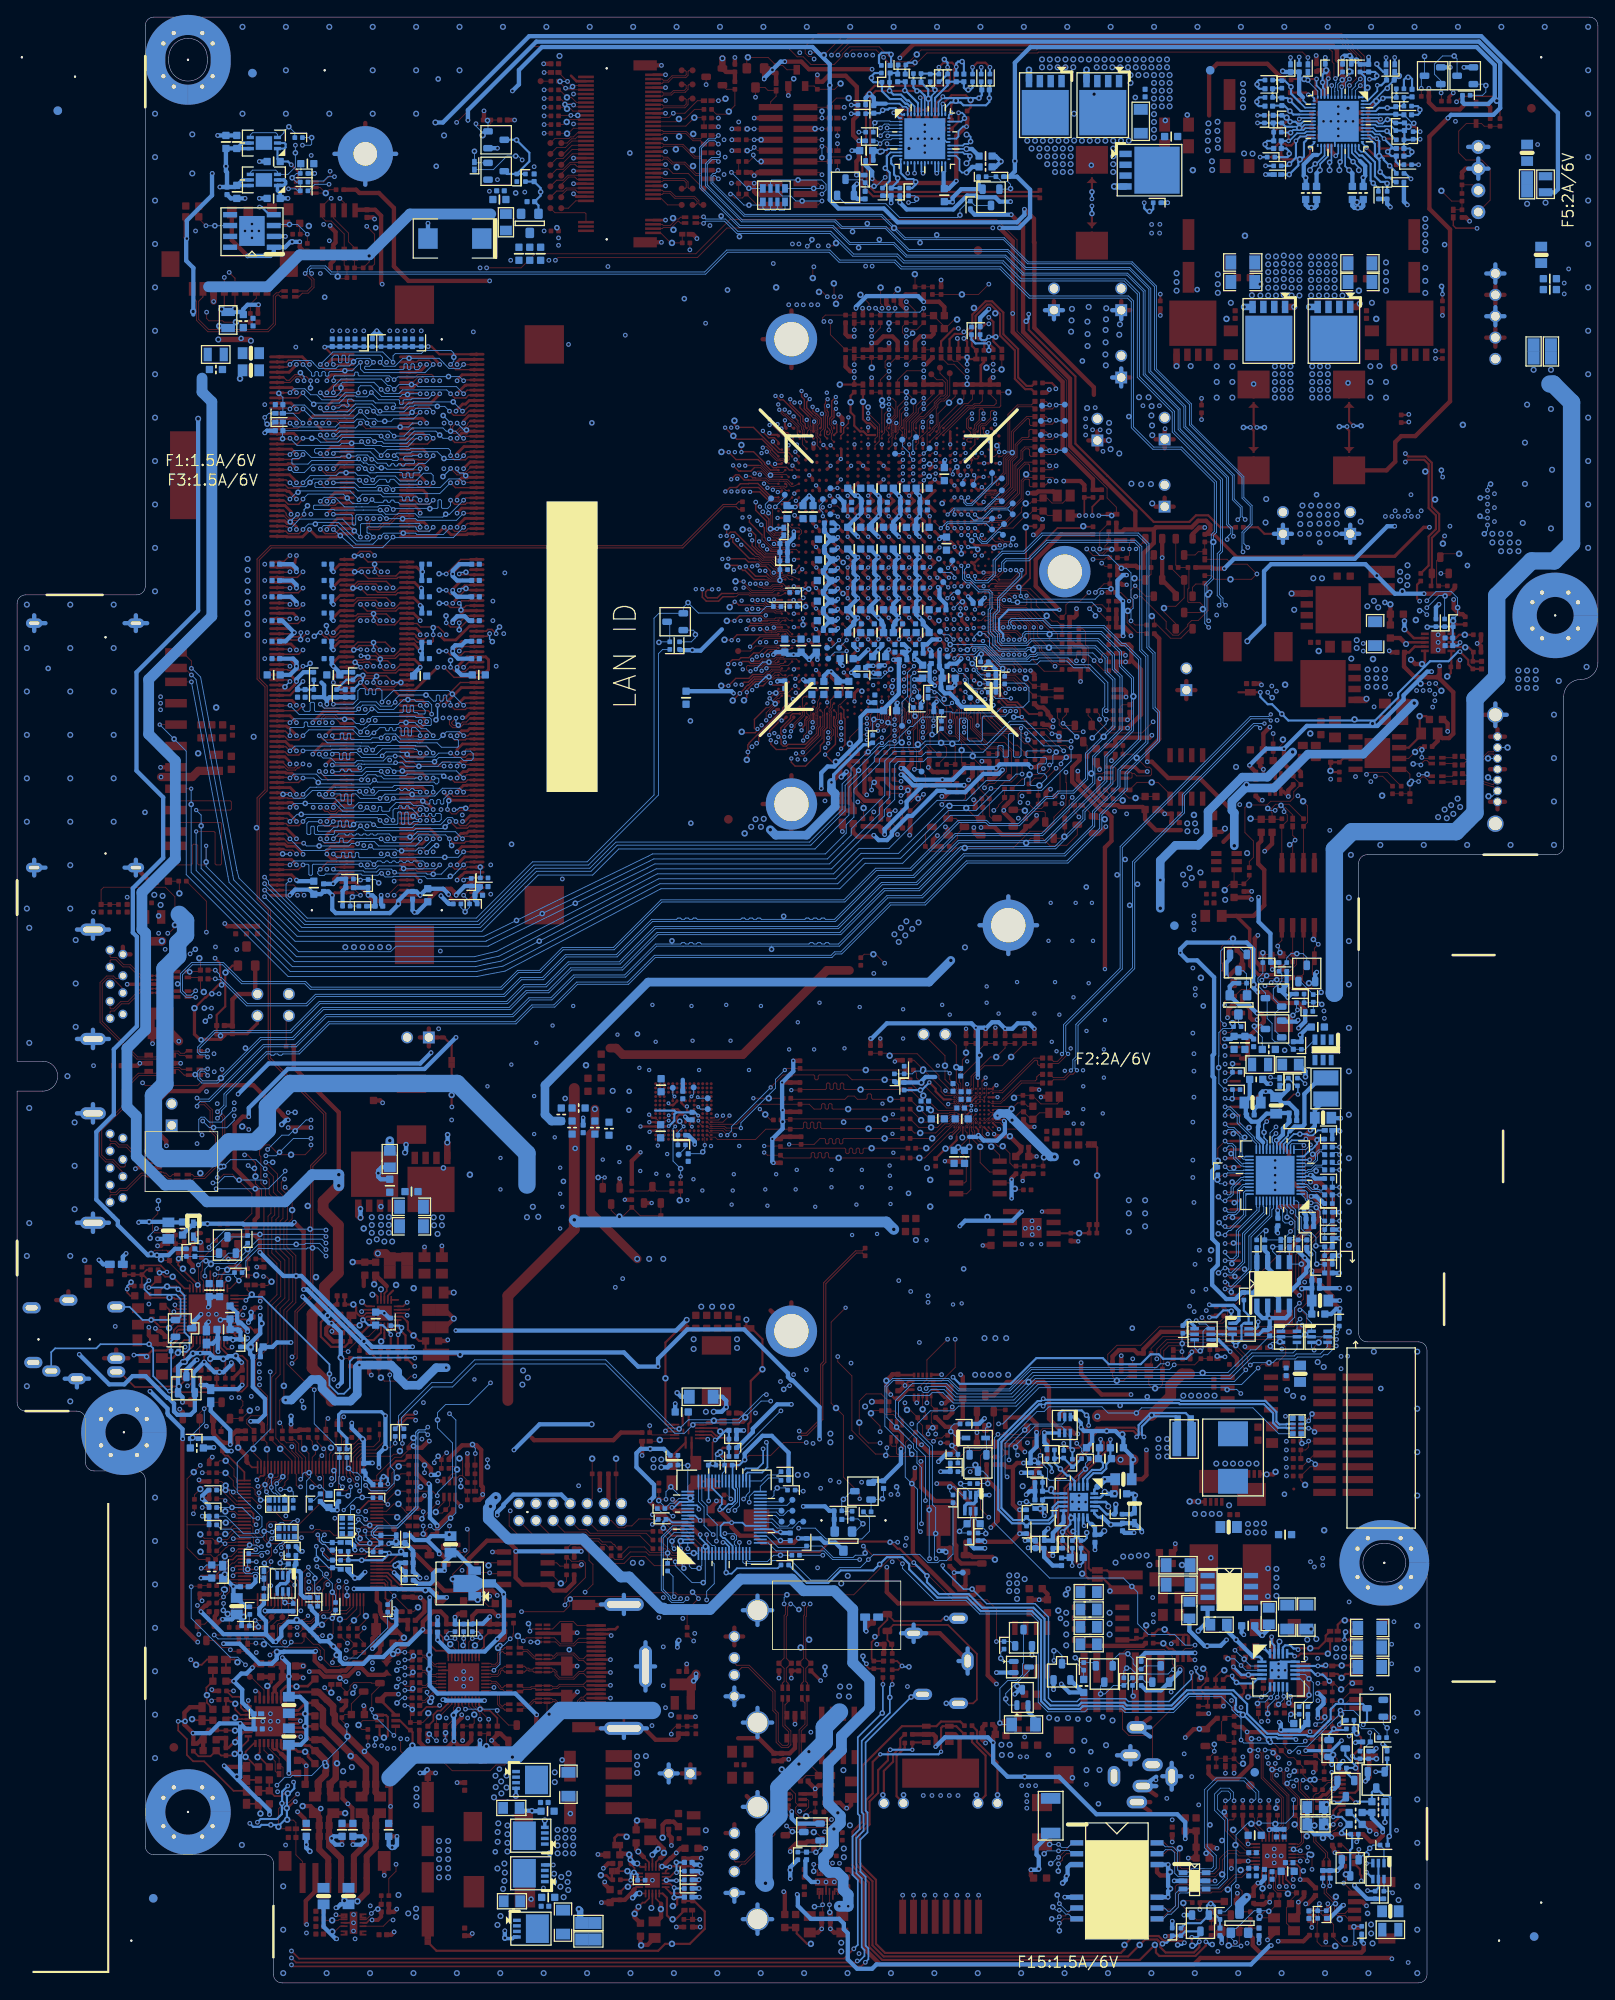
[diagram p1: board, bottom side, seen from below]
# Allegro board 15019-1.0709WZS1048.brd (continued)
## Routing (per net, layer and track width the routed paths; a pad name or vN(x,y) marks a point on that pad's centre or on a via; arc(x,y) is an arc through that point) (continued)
V_5P0_HDMI_CONN_L: length 4.6
  TOP w0.965: L46.2 106.15,34.9 F13.2
  TOP w1.016: v4(105.54,36.16) 105.54,36.02 106.13,35.43 L46.2
  BOTTOM w0.508: v4(105.54,36.16) 105.54,35.61 v2(105.82,35.33)
V_19_INV:
  vias: v1(48.67,48.9)
V_VCORE_EN: length 17.3
  TOP w0.102: R508.2 v4(20.67,221.67)
  L3 w0.127: v4(31.15,222) 31.15,221.62 30.88,221.35 20.99,221.35 v4(20.67,221.67)
  BOTTOM w0.102: v2(20.29,225.4) Q51.D 20.67,222.76 v4(20.67,221.67) ; PU4601.9 31.19,221.96 v4(31.15,222)
VBYP_2: length 3.1
  TOP w0.102: PU5201.3 109.6,63.72 v1(109.79,63.53) 109.94,63.37 R79708.2
VCORE_PWROK: length 129.6
  TOP w0.102: v1(26.96,221.74) 27.55,221.74 v4(27.8,222) 27.8,222.11 27.34,222.57 27.34,223.79 27.34,225.43 27.45,225.53 27.45,225.54 27.65,225.74 29.98,228.07 91.27,228.07 92.77,226.57 92.77,225.78 92.37,225.38 92.01,225.38 v4(91.73,225.09) ; R1904.2 R1623.2 89.82,192.85 v4(89.82,194.39)
  L3 w0.127: v4(89.82,194.39) 91.31,195.87 94.89,195.87 95.63,196.6 95.63,216.81 90.88,221.56 90.88,224.24 v4(91.73,225.09)
  L4 w0.127: v4(86.49,216.53) 86.49,219.86 v4(91.73,225.09)
  BOTTOM w0.102: v4(27.8,222) 28.39,221.41 PU4601.2 ; PR5466.2 v4(86.49,216.53)
VOUT_INV: length 1.5
  BOTTOM w0.305: U120.18 37.37,39.83 v7(37.27,39.93)
  vias: v1(33.56,41.4) v2(28.74,35.05) v7(29.71,39.15) v7(29.71,38.15) v7(30.62,39.15) v7(30.62,38.15) v7(32.95,40.23) v7(34.02,40.16)
VR_HOT: length 3.4
  BOTTOM w0.102: PU4601.13 32.79,221.35 33.94,222.5 v2(33.94,222.63) PR24.1
VREF: length 5
  TOP w0.102: C4.2 42.1,39.29 v4(42.48,38.91)
  BOTTOM w0.102: U120.2 40.64,37.08 41.4,37.83 v2(41.4,37.88) 41.42,37.88 41.87,38.33 41.89,38.33 v4(42.48,38.91)
VREF_1: length 2.3
  TOP w0.203: C140.1 167.92,77.63 U6.41
VREG_PCIAUX_PCH: length 9.3
  BOTTOM w0.254: Q3.D 127.67,211.65 R10.2 ; R10.2 R13.1 ; R10.2 125.05,213.12 125.05,214.12 v2(126.55,215.62) 126.58,215.65 Q128.C
VREG_PCIAUX_PCH_1: length 5.6
  BOTTOM w0.254: Q1211.G 123.99,207.96 PC1.2 123.73,209.11 v2(123.73,209.55) 123.73,209.99 C1616.1 R13.2
VRP: length 9.4
  TOP w0.203: U6.38 166.13,76.43 166.33,76.23 166.33,75.33
  TOP w0.254: v4(171.33,73.46) 170.85,73.46 170.49,73.1 C155.1 169.19,73.99 167.5,73.99 166.33,75.16 166.33,75.33
  BOTTOM w0.254: v2(169.84,73.28) 170.02,73.46 v4(171.33,73.46)
WAKE_N: length 508.5
  TOP w0.102: U16.21 35.08,14.66 35.02,14.72 34.47,14.72 v4(34.02,14.26) ; v1(102.1,220.45) 102.32,220.22 v4(102.93,220.22) R1719.2 ; R1654.1 v4(61.02,154.69) 61.02,155.36 R137.1 ; R1718.1 v4(123.32,223.52)
  L3 w0.127: v4(45.4,84.63) 47.07,82.96 117.66,82.96 130.84,69.77 143.87,69.77 144.42,70.32 147.65,70.32 v4(147.94,70.61)
  L4 w0.127: v4(123.32,223.52) 121.22,223.52 119.19,225.55 104.37,225.55 102.93,224.11 v4(102.93,220.22) 103.89,220.22 106.3,217.81 116.4,217.81 119.85,214.35 123.3,214.35 136.8,200.86 154.04,200.86 162.12,192.77 162.12,191.4 161.17,190.45 161.17,156.15 160.47,155.44 160.47,124.84 161.16,124.14 161.16,117.45 161.83,116.78 161.83,114.84 161.3,114.3 161.3,112.79 156.23,107.73 156.23,105.69 155.27,104.73 155.27,100.76 153.88,99.36 153.88,95.97 153.14,95.23 153.14,88.89 152.06,87.82 152.06,76.89 151.39,76.22 151.39,74.22 147.94,70.77 v4(147.94,70.61) ; v4(34.02,14.26) 34.62,14.86 35.34,14.86 35.66,15.18 35.66,17.59 36.99,18.92 36.99,21.58 37.4,22 40.22,22 42.02,23.8 42.02,27.43 41.16,28.3 41.16,28.7 41.16,28.8 41.59,29.23 41.59,30.02 41.16,30.45 41.16,30.97 40.52,31.6 40.52,34.02 39.76,34.78 39.76,37.97 40,38.21 40,40.6 39.76,40.85 39.76,50.7 38.08,52.37 38.08,54.69 35.21,57.56 35.21,63.7 35.88,64.36 36.39,64.36 39.91,67.89 39.91,68.27 40.94,69.3 40.94,69.31 41.48,69.85 42.11,69.85 48.5,76.23 48.5,79.36 48.05,79.81 47.2,79.81 46.52,80.49 46.52,82.22 45.4,83.34 v4(45.4,84.63) 45.4,120.29 47.8,122.69 47.8,125.53 51.35,129.08 51.35,146.33 51.88,146.86 52.03,146.86 53.63,148.46 53.63,152.5 54.58,153.45 59.79,153.45 v4(61.02,154.69)
  BOTTOM w0.102: v4(34.02,14.26) 34.02,14.81 33.8,15.02 v2(33.8,15.06)
WAKE_N_APU: length 11.5
  TOP w0.102: R1654.2 v1(64.25,156.23) 65.59,157.57 65.59,158.78 67.32,160.52 70.1,160.52 70.29,160.71 70.61,160.71 CPU1.AG2
WEBCAM_DET: length 170.2
  TOP w0.102: U109.114 151.25,45.88 151.31,45.94 151.31,47.35 v4(150.91,47.75) ; v4(162.82,195.48) 162.82,194.74 162.54,194.46 160.94,194.46 160.79,194.31 v1(159.39,194.31) PC126.2 R12.2 157.7,196.41 157.01,197.1 157.01,198.19 WEBCM1.7
  L4 w0.127: v4(150.91,47.75) 150.44,48.22 150.44,49.74 150.61,49.91 150.61,50.77 150.57,50.82 150.57,50.84 150.45,50.96 150.45,52.6 151,53.15 151,56 151.35,56.35 151.35,59.12 151.75,59.52 151.75,65.92 153.09,67.26 153.09,70.71 154.3,71.92 154.3,86.35 155.16,87.21 155.16,87.74 157.49,90.07 157.49,97.74 158.15,98.4 158.15,99.44 158.36,99.65 158.36,100.12 157.42,101.06 157.42,101.54 158.15,102.27 158.15,104.67 158.82,105.35 158.82,107.03 165.22,113.43 165.22,131.32 163.22,133.32 163.22,155.01 164.39,156.19 164.39,193.91 v4(162.82,195.48)
WR2_EN: length 10.7
  TOP w0.076: 70.32,100.64 70.48,100.64 70.7,100.86 70.91,100.86 71.16,100.61 U902.J2
  TOP w0.102: R90064.1 R90065.2 64.93,96.49 v1(64.83,96.6) 64.83,96.79 67.94,99.9 69.2,99.9 69.94,100.64 70.32,100.64
X32K_X1: length 8.4
  TOP w0.102: X2.1 64.47,151.3 R1671.1 64.87,151.7 C57.1 66.01,151.7 v1(66.96,152.65) 67.44,153.14 69.1,153.14 69.77,153.8 CPU1.AT1
X32K_X2: length 10.2
  TOP w0.102: X2.4 64.47,150.45 R1671.2 65.25,150.56 C58.1 66.61,151.22 66.61,151.74 66.89,152.02 67.22,152.02 68.13,152.93 69.19,152.93 69.75,153.5 70.63,153.5 70.93,153.8 CPU1.AT2
X48M_X1: length 12.1
  TOP w0.102: CPU1.T2 70.8,170.3 69.97,170.3 69.86,170.41 69.14,170.41 67.47,172.09 67.47,172.59 v1(66.96,173.1) 66.45,173.1 66.14,173.42 C52.1 65.25,173.42 R113.1 64.47,173.74 63.88,173.14 62.64,173.14 X1.3
X48M_X2: length 8.6
  TOP w0.102: X1.1 64.39,171.68 R113.2 65.12,172.4 C50.1 66.64,171.7 v1(66.96,171.7) 68.46,170.21 69.78,170.21 69.89,170.09 70.21,170.09 CPU1.T1
XRF_TDC2: length 15.3
  TOP w0.508: v4(50.3,13.84) 50.3,13.34 50.07,13.11 v1(50.07,12.98) 50.48,12.57 51.21,12.57 51.6,12.95 XF1.9 ; 51.6,10.03 v4(50.3,10.03) ; v4(49.82,16.48) C3452.1
  L3 w0.508: v4(49.82,16.48) 49.82,14.33 v4(50.3,13.84)
  BOTTOM w0.508: 51.6,10.03 v4(50.3,10.03) 50.3,10.74 v2(50.02,11.02) 50.3,11.3 v4(50.3,13.84) XF1.9

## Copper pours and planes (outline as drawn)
AGND on TOP: 166.66,69.98 166.28,70.36 166.28,71.12 166.4,71.25 170.85,71.25 171.23,71.63 171.23,73.53 171.1,73.66 170.34,73.66 170.21,73.79 170.21,75.56 170.47,75.82 171.86,75.82 171.99,75.95 171.99,77.85 171.86,77.98 168.69,77.98 168.44,78.23 167.55,78.23 167.42,78.36 167.42,79.12 167.94,79.64 171.5,79.64 171.87,80.01 171.86,80.01 171.86,83.21 171.64,83.44 171.1,83.44 170.98,83.57 170.98,84.47 171.1,84.59 173.12,84.59 173.39,84.33 173.39,82.68 173.77,82.3 177.07,82.3 177.2,82.17 177.2,77.47 175.55,75.82 175.55,72.64 175.29,72.39 172.63,72.39 172.25,72.01 172.25,70.1 172.12,69.98 ; 8 cut-outs
AGND on BOTTOM: 80.42,34.42 79.54,35.31 73.57,35.31 72.93,35.94 72.93,39.56 73.31,39.94 77.44,39.94 81.06,43.56 84.36,43.56 84.74,43.18 84.74,41.27 85.12,40.89 85.12,39.5 84.87,39.24 81.82,39.24 80.04,37.47 80.04,36.32 81.19,35.18 81.19,34.67 80.93,34.42
AGND on L2GND: 73.26,31.81 72.36,32.72 72.36,42.47 73.39,43.5 83.52,43.5 83.92,43.1 83.92,41.96 84.55,41.32 84.55,40.82 86.08,39.29 86.08,36.78 81.11,31.81
AGND on L2GND: outline of 100 points within 85.06,0.76 184.24,85.53
AGND on L5GND: 164.58,28.64 164.18,29.03 164.18,38.15 166.34,40.31 166.34,64.47 163.93,66.88 163.93,68.02 163.05,68.9 158.74,68.9 158.47,69.17 158.47,72.95 159.61,74.09 159.61,74.75 159.24,75.12 157.97,75.12 157.32,75.77 157.32,78.31 156.96,78.68 156.45,78.68 156.18,78.95 156.18,79.04 156.45,79.31 158.45,79.31 159.09,78.68 159.85,78.68 159.99,78.53 159.99,75.99 160.36,75.63 164.83,75.63 165.2,75.99 165.2,80.22 164.69,80.72 164.69,81.58 165.2,82.09 165.2,89.08 165.72,89.6 171.66,89.6 173.2,88.06 173.2,83.11 173.94,82.36 177.25,82.36 177.26,82.34 177.26,78.79 177.75,78.3 179.69,78.3 182.61,81.22 184.24,81.22 184.24,70.68 180.2,70.68 179.06,71.82 176.23,71.82 172.17,67.75 171.15,67.75 169.26,65.86 169.26,61.93 167.36,60.02 167.36,29.54 166.45,28.64
AGND on L5GND: 85.2,1.97 85.06,2.11 85.06,12.24 86.08,13.26 86.08,16.59 85.19,17.48 85.19,19.99 85.44,20.24 85.44,28.15 80.76,32.83 78.34,32.83 77.82,33.35 77.82,33.96 79.11,35.24 84.03,35.24 84.17,35.1 84.17,31.8 86.84,29.13 86.84,19.64 86.58,19.38 86.58,18.08 87.47,17.19 87.47,12.52 86.84,11.89 86.84,5.13 87.47,4.49 87.47,3 86.44,1.97
DVCC1_O2 on TOP: 61.12,88.47 59.42,90.17 59.42,98.48 59.49,98.55 63.66,98.55 64.14,99.03 65.26,99.03 65.36,98.93 65.36,97.94 64.07,96.65 64.07,92.46 62.54,90.93 62.54,89.61 62.59,89.56 64.55,89.56 64.68,89.43 64.68,88.62 64.52,88.47 ; 8 cut-outs
DVCC1_O2 on BOTTOM: 70.52,100.2 69.76,100.97 69.76,102.36 70.9,103.5 70.9,104.9 71.38,105.38 73.97,105.38 74.07,105.28 74.07,104.9 73.95,104.78 73.95,103 74.46,102.49 74.46,100.46 74.2,100.2 ; 5 cut-outs
DVCC1D8V on BOTTOM: 111.67,96.65 111.46,96.85 111.46,97.92 111.92,98.37 114.76,98.37 115.07,98.68 115.07,99.64 115.22,99.8 120,99.8 120.02,99.82 120.43,99.82 120.56,99.69 120.56,97.41 120.28,97.13 113.29,97.13 112.81,96.65 ; 6 cut-outs
DVCC1D8V_O2 on BOTTOM: 119.67,101.73 119.41,101.98 119.41,103.84 119.59,104.01 121.78,104.01 122.08,103.71 122.08,101.98 121.83,101.73 ; 3 cut-outs
DVCC3 on TOP: 116.19,105.28 115.83,105.64 115.83,107.47 116.14,107.77 117.28,107.77 117.48,107.98 120.23,107.98 120.51,107.7 120.51,106.35 119.92,105.77 119.06,105.77 118.57,105.28 ; 6 cut-outs
DVCC3_O2 on TOP: 68.08,87.15 67.9,87.33 67.9,89.26 67.98,89.33 70.04,89.33 70.11,89.41 70.11,90.75 69.91,90.96 64.85,90.96 64.37,91.44 64.37,94.89 64.49,95.01 65.27,95.01 65.39,94.89 65.39,93.68 65.69,93.37 66.5,93.37 66.73,93.14 66.73,92.33 66.91,92.15 68.64,92.15 69.25,92.76 71.1,92.76 72.17,91.69 76.23,91.69 76.36,91.82 76.36,94.11 76.11,94.36 74.33,94.36 74.2,94.49 74.2,95.25 74.33,95.38 76.56,95.38 77.07,95.89 81.52,95.89 81.69,95.71 81.69,89.03 81.57,88.9 79.13,88.9 77.38,87.15 ; 9 cut-outs
DVCC3_O2 on BOTTOM: 78.24,94.77 76.11,96.9 73.31,96.9 73.08,97.13 73.08,99.21 73.19,99.31 74.46,99.31 74.84,98.93 74.84,98.68 75.22,98.3 76.87,98.3 77.25,98.68 77.25,104.39 76.74,104.9 74.84,104.9 74.07,105.66 72.42,105.66 72.3,105.79 72.3,106.43 72.42,106.55 74.96,106.55 75.22,106.3 77.99,106.3 78.01,106.27 78.01,105.41 78.65,104.78 78.65,98.48 79.1,98.02 79.1,94.97 78.9,94.77 ; 8 cut-outs
GND on TOP: 32.8,35.56 32.42,35.94 32.42,38.1 32.67,38.35 34.83,38.35 35.47,37.72 35.47,35.81 35.21,35.56
GND on TOP: 76.36,213.87 76.23,214 76.23,218.44 76.36,218.57 81.82,218.57 81.95,218.44 81.95,214.25 81.57,213.87 ; 13 cut-outs
GND on TOP: 119.67,14.73 119.29,15.11 119.29,22.23 119.41,22.35 122.33,22.35 122.46,22.23 122.46,18.16 123.1,17.53 123.1,14.99 122.84,14.73
GND on TOP: outline of 275 points within 0.76,0.76 184.24,229.24 ; 45 cut-outs
GND on TOP: 100.36,77.47 100.11,77.72 100.11,79.25 100.26,79.4 105.16,79.4 106.08,78.49 106.08,77.72 105.86,77.51 101.72,77.51 101.68,77.47 ; 8 cut-outs
GND on TOP: 59.98,98.93 59.6,99.31 59.6,100.71 59.98,101.09 61.63,101.09 62.52,100.2 65.23,100.2 65.36,100.08 65.36,99.39 65.31,99.34 64.09,99.34 63.69,98.93 ; 3 cut-outs
GND on TOP: 19.97,202.31 19.85,202.44 19.85,206.63 19.97,206.76 22.13,206.76 22.26,206.63 22.26,202.44 22.13,202.31
GND on TOP: 49.69,214 49.44,214.25 49.44,224.79 50.2,225.55 65.31,225.55 65.44,225.43 65.44,219.71 65.18,219.46 56.8,219.46 51.34,214
GND on TOP: 47.15,202.31 47.15,206.63 47.28,206.76 52.23,206.76 52.61,206.38 52.61,204.6 50.33,202.31
GND on TOP: 40.8,218.95 40.44,219.3 40.44,222.76 40.98,223.29 44.48,223.29 44.66,223.11 44.66,219.63 43.98,218.95
GND on TOP: 52.99,29.08 49.56,32.51 49.56,37.47 50.83,38.73 54.64,38.73 54.77,38.61 54.77,31.75 55.15,31.37 55.15,29.34 54.9,29.08
GND on TOP: 170.09,125.86 169.83,126.11 169.83,127.25 169.96,127.38 172.37,127.38 172.5,127.25 172.5,125.98 172.37,125.86 ; 2 cut-outs
GND on TOP: 30.51,163.96 30.26,164.21 30.26,165.86 30.51,166.12 33.69,166.12 33.82,165.99 33.82,164.08 33.69,163.96 ; 1 cut-out
GND on TOP: 63.79,19.81 63.53,20.07 63.53,21.97 63.79,22.23 66.96,22.23 67.22,21.97 67.22,20.07 66.96,19.81
GND on TOP: 123.73,96.14 121.32,98.55 121.32,109.04 119.31,111.05 115.35,111.05 113.9,109.6 101,109.6 90.97,119.63 88.81,119.63 87.16,121.28 83.98,121.28 82.96,120.27 82.96,117.86 83.98,116.84 89.95,116.84 99.22,107.57 112.43,107.57 112.81,107.19 112.81,106.05 112.56,105.79 97.32,105.79 94.52,108.58 88.04,108.58 85.38,111.25 80.93,111.25 79.66,112.52 59.85,112.52 58.58,113.79 58.58,129.79 60.74,131.95 86.77,131.95 89.44,134.62 89.44,140.59 90.71,141.86 101.13,141.86 103.92,144.65 103.92,160.4 110.65,167.13 129.32,167.13 130.08,166.37 130.08,152.02 131.35,150.75 131.35,128.91 131.22,128.78 131.22,126.49 132.11,125.6 140.11,125.6 140.88,124.84 140.88,119.13 140.75,119 134.91,119 132.75,116.84 132.75,97.41 131.48,96.14
GND on TOP: 39.99,211.61 39.91,211.68 39.91,214.33 39.99,214.4 41.64,214.4 41.79,214.25 41.79,211.76 41.64,211.61
GND on TOP: 87.54,10.92 87.41,11.05 87.41,12.57 87.54,12.7 88.04,12.7 88.55,12.19 92.11,12.19 92.62,12.7 93.12,12.7 93.25,12.57 93.25,11.05 93.12,10.92 92.62,10.92 92.11,11.43 88.55,11.43 88.04,10.92 ; 4 cut-outs
GND on TOP: 47.28,17.91 45.37,19.81 45.37,23.24 47.66,25.53 47.66,31.24 48.29,31.88 49.56,31.88 52.48,28.96 52.48,26.6 52.57,26.6 52.63,26.6 52.7,26.62 52.74,26.69 52.74,28.7 52.74,20.32 50.33,17.91 ; 6 cut-outs
GND on TOP: 139.99,86.23 138.59,87.63 138.59,89.41 138.84,89.66 139.61,89.66 139.73,89.79 139.73,91.44 139.99,91.69 144.18,91.69 144.69,91.19 144.69,87.88 144.18,87.38 144.18,86.49 143.92,86.23
GND on TOP: 27.72,215.52 27.47,215.77 27.47,220.47 27.59,220.6 36.23,220.6 36.36,220.47 36.36,219.33 35.97,218.95 33.05,218.95 32.93,218.82 32.93,215.65 32.8,215.52 ; 18 cut-outs
GND on TOP: 97.19,19.18 96.93,19.43 96.93,25.15 97.32,25.53 97.32,26.42 98.71,27.81 99.98,27.81 100.11,27.69 100.11,19.3 99.98,19.18 ; 2 cut-outs
GND on TOP: outline of 104 points within 44.43,65.91 126.02,129.03 ; 9 cut-outs
GND on TOP: 71.79,101.47 71.66,101.6 71.66,102.49 71.28,102.49 71.15,102.62 71.28,102.74 72.68,102.74 72.68,102.75 72.93,102.5 72.93,101.47
GND on TOP: 149.89,5.33 149.77,5.46 149.77,8.64 149.89,8.76 151.42,8.76 151.54,8.64 151.54,5.71 151.16,5.33 ; 3 cut-outs
GND on TOP: 61.76,22.73 61.12,23.37 61.12,25.4 61.88,26.16 65.57,26.16 66.33,26.92 66.33,30.1 66.45,30.23 68.23,30.23 68.36,30.1 68.36,29.34 67.85,28.83 67.85,22.86 67.72,22.73 ; 4 cut-outs
GND on TOP: 31.66,71.63 31.4,71.88 31.4,72.9 31.78,73.28 36.48,73.28 36.99,72.77 36.99,72.01 36.61,71.63 ; 1 cut-out
GND on TOP: 107.73,57.66 107.6,57.78 107.6,61.21 106.59,62.23 106.59,63.12 106.71,63.25 109.25,63.25 110.9,61.59 110.9,59.44 109.13,57.66 ; 1 cut-out
GND on TOP: 42.58,195.33 42.07,195.83 42.07,196.47 41.82,196.72 41.31,196.72 41.31,195.45 37.5,195.45 37.5,196.98 37.37,197.1 34.7,197.1 34.58,197.23 34.58,202.31 34.7,202.44 41.05,202.44 41.31,202.18 41.31,198.88 43.85,196.34 43.85,195.83 43.34,195.33 ; 3 cut-outs
GND on TOP: 26.07,195.33 25.94,195.45 25.94,196.98 27.97,199.01 27.97,201.93 28.48,202.44 33.82,202.44 34.2,202.06 34.2,196.98 34.07,196.85 33.43,196.85 33.18,196.6 33.18,195.33 29.5,195.33 29.5,196.72 29.24,196.98 27.85,196.98 27.47,196.6 27.47,195.83 26.96,195.33 ; 3 cut-outs
GND on TOP: 43.31,52.58 43.19,52.7 43.19,54.23 42.81,54.61 42.81,56.82 42.91,56.92 45.37,56.92 45.5,56.79 45.5,55.37 45.63,55.24 47.28,55.24 47.53,54.99 47.53,52.7 47.4,52.58 ; 2 cut-outs
GND on TOP: 51.85,41.91 51.72,42.04 50.2,42.04 50.07,42.16 50.07,45.75 50.33,46 52.26,46 52.38,45.87 52.38,42.16 52.13,41.91
GND on TOP: 73.57,21.59 72.3,22.86 72.3,26.29 72.42,26.42 81.44,26.42 81.57,26.29 81.57,22.86 80.3,21.59
GND on TOP: 25.18,150.88 24.54,151.51 24.54,153.92 25.18,154.56 25.18,157.23 25.31,157.35 29.75,157.35 30.01,157.1 30.01,155.57 29.24,154.81 29.24,151 29.12,150.88
GND on TOP: 27.47,146.94 25.43,148.97 24.29,148.97 23.91,149.35 23.91,151 24.04,151.13 24.29,151.13 25.05,150.37 26.07,150.37 26.96,149.48 28.86,149.48 29.62,148.72 32.67,148.72 33.05,148.34 33.05,147.07 32.93,146.94 ; 1 cut-out
GND on TOP: 135.92,10.41 134.15,12.19 134.15,16.76 135.92,18.54 137.57,18.54 137.7,18.41 137.7,10.54 137.57,10.41
GND on TOP: 157.64,32.26 157.26,32.64 156.5,32.64 156.37,32.77 156.37,34.16 156.75,34.54 158.15,34.54 158.4,34.29 158.4,32.38 158.28,32.26
GND on BOTTOM: 139.99,86.23 139.1,87.12 139.1,93.09 139.23,93.22 143.34,93.22 144.18,92.38 144.18,86.49 143.92,86.23 ; 3 cut-outs
GND on BOTTOM: 62.77,20.19 62.52,20.45 62.52,22.61 62.9,22.99 64.93,22.99 65.57,22.35 66.96,22.35 67.22,22.1 67.22,20.32 67.09,20.19
GND on BOTTOM: 49.36,41.73 49.16,41.94 49.16,51.41 49.44,51.69 50.93,51.69 51.42,51.21 51.42,46.41 52.36,45.47 52.36,42.04 52.05,41.73
GND on BOTTOM: 75.34,98.68 74.71,99.31 74.71,102.62 74.2,103.12 74.2,104.52 74.33,104.65 76.61,104.65 76.74,104.52 76.74,98.81 76.61,98.68 ; 8 cut-outs
GND on BOTTOM: 119.67,14.48 119.41,14.73 119.41,22.3 119.62,22.5 121.88,22.5 123.17,21.21 123.17,20.75 122.72,20.29 122.72,19.68 122.33,19.3 122.33,18.03 122.59,17.78 123.6,17.78 123.73,17.65 123.73,14.73 123.48,14.48 ; 3 cut-outs
GND on BOTTOM: 50.71,74.42 49.56,75.56 49.56,79.76 45.63,83.69 45.63,117.47 47.15,119 52.87,119 60.49,111.38 60.49,106.43 60.74,106.17 61.76,106.17 62.14,106.55 62.14,107.44 63.15,108.46 63.15,110.11 63.53,110.49 71.15,110.49 72.04,109.6 72.04,105.92 71.79,105.66 71.03,105.66 70.65,105.28 70.65,103.63 69.62,102.6 68.78,102.6 63.89,97.71 63.89,97.23 64.24,96.88 65.57,96.88 67.83,99.14 69.93,99.14 72.7,96.37 76.46,96.37 79.03,93.8 79.03,82.17 77.25,80.39 70.39,80.39 64.42,74.42 ; 3 cut-outs
GND on BOTTOM: 39.66,11.81 39.53,11.94 39.53,12.57 39.4,12.7 36.61,12.7 36.36,12.95 36.36,17.27 36.48,17.4 38.64,17.4 39.02,17.78 39.91,17.78 40.29,17.4 40.29,11.94 40.17,11.81 ; 10 cut-outs
GND on BOTTOM: 152.56,29.21 152.43,29.34 152.43,32.13 152.56,32.26 156.12,32.26 156.62,31.75 156.62,29.72 156.12,29.21 ; 1 cut-out
GND on BOTTOM: 28.74,195.45 28.61,195.58 28.61,202.31 28.74,202.44 34.07,202.44 34.2,202.31 34.2,196.85 33.31,196.85 33.18,196.72 33.18,195.45
GND on BOTTOM: 80.04,90.42 79.41,91.06 79.41,97.92 78.87,98.45 78.87,103.5 79.2,103.84 82.28,103.84 82.96,104.52 82.96,106.68 82.71,106.93 80.6,106.93 80.45,107.09 75.65,107.09 75.29,106.73 73.64,106.73 73.19,107.19 73.19,111.38 73.69,111.89 83.09,111.89 84.87,110.11 85.38,110.11 85.63,110.36 85.63,111.12 83.98,112.78 62.64,112.78 56.68,118.75 56.68,129.41 57.44,130.18 73.44,130.18 77.88,125.73 77.88,122.17 76.49,120.78 75.73,120.78 74.84,119.89 74.84,118.49 77.25,116.08 110.65,116.08 115.48,111.25 115.48,109.22 114.97,108.71 113.44,108.71 112.68,107.95 112.68,105.66 112.3,105.28 98.2,105.28 94.9,108.58 93.63,108.58 93.25,108.2 93.25,97.41 95.41,95.25 97.16,95.25 98.51,96.6 106.66,96.6 106.84,96.42 106.84,94.16 107.07,93.93 108.14,93.93 108.36,94.16 108.36,95.66 108.67,95.96 108.67,99.09 108.87,99.29 110.42,99.29 111.16,98.55 111.16,96.75 111.56,96.34 112.94,96.34 113.24,96.65 121.06,96.65 122.08,95.63 122.08,91.31 121.19,90.42 ; 12 cut-outs
GND on BOTTOM: 31.91,71.63 31.68,71.86 31.68,72.29 32.42,73.03 35.34,73.03 35.85,72.52 36.86,72.52 36.99,72.39 36.99,71.75 36.86,71.63
GND on BOTTOM: 49.06,20.57 43.34,26.29 43.34,32.89 43.59,33.15 47.66,33.15 50.07,30.73 54.9,30.73 55.15,30.48 55.15,29.46 54.77,29.08 53.25,29.08 52.99,28.83 52.99,23.62 49.94,20.57
GND on BOTTOM: 24.8,151.26 24.54,151.51 24.54,153.97 25,154.43 25.03,154.43 25.13,154.53 25.13,157.15 25.33,157.35 29.12,157.35 29.37,157.1 29.37,151.64 28.99,151.26
GND on BOTTOM: 120.18,7.82 120.05,7.95 120.05,13.21 120.23,13.39 123.71,13.39 123.73,13.36 123.73,10.9 123.65,10.82 122.89,10.82 122.79,10.72 122.79,9.53 123.1,9.22 123.1,8.66 123.02,8.59 122.69,8.59 121.93,7.82 ; 3 cut-outs
GND on BOTTOM: 144.43,202.69 138.84,208.28 128.94,208.28 128.56,208.66 128.56,211.07 128.94,211.46 130.46,211.46 130.97,210.95 131.48,210.95 132.49,211.96 132.49,216.66 133.26,217.42 148.5,217.42 151.04,214.88 151.04,212.6 150.53,212.09 150.53,206.5 151.16,205.87 151.16,205.1 150.66,204.6 150.66,203.2 150.15,202.69 ; 4 cut-outs
GND on BOTTOM: 106.46,200.53 104.55,202.44 104.55,204.98 105.57,205.99 105.57,215.26 104.17,216.66 102.78,216.66 102.4,216.28 102.4,213.36 99.35,210.31 98.46,210.31 97.44,211.33 92.74,211.33 92.36,211.71 92.36,224.28 94.01,225.93 94.01,225.81 123.48,225.81 125.64,223.65 125.64,212.34 124.49,211.2 123.99,211.2 121.06,208.28 121.06,202.69 121.57,202.18 127.54,202.18 127.8,201.93 127.8,200.79 127.54,200.53 ; 7 cut-outs
GND on BOTTOM: 129.45,126.87 124.87,131.44 118.4,131.44 110.65,139.19 110.65,160.02 110.14,160.53 108.24,160.53 106.46,162.31 106.46,166.24 103.28,169.42 103.28,175.51 103.92,176.15 103.92,198.5 104.94,199.52 147.48,199.52 151.29,195.71 157.51,195.71 157.72,195.5 157.72,194.72 157.49,194.49 156.8,194.49 156.65,194.34 156.65,192 157.34,191.31 157.34,187.81 156.55,187.02 156.55,184.73 156.17,184.35 154.57,184.35 154.52,184.4 154.52,184.86 155.07,185.42 155.07,188.62 153.2,190.5 150.91,190.5 149.26,192.15 149.13,192.02 134.02,192.02 131.99,189.99 131.99,169.29 132.75,168.53 140.88,168.53 141.64,167.77 156.37,167.77 157.13,167 157.13,157.48 158.53,156.08 158.53,134.49 153.83,129.79 151.54,129.79 150.78,130.56 150.78,130.81 151.29,131.32 152.05,131.32 152.18,131.44 152.18,132.59 151.93,132.84 150.91,132.84 150.4,133.35 150.4,136.53 150.02,136.91 150.02,138.18 150.4,138.56 150.4,149.94 148.45,151.89 131.73,151.89 131.22,151.38 131.1,151.38 131.1,130.43 130.46,129.79 130.46,128.02 130.84,127.64 130.84,127 130.72,126.87 ; 78 cut-outs
GND on BOTTOM: 34.83,195.33 34.58,195.58 34.58,202.31 34.7,202.44 40.55,202.44 40.93,202.06 40.93,195.45 40.8,195.33
GND on BOTTOM: 17.69,155.07 17.56,155.19 17.56,157.86 17.69,157.99 18.96,157.99 19.08,157.86 19.08,155.32 18.83,155.07 ; 3 cut-outs
GND on BOTTOM: 5.24,168.02 4.61,168.66 4.61,184.4 5.75,185.55 9.18,185.55 9.56,185.17 9.56,169.67 7.91,168.02
GND on BOTTOM: outline of 252 points within 0.76,0.76 184.24,229.24 ; 28 cut-outs
GND on BOTTOM: 43.59,52.58 43.47,52.7 43.47,54.48 42.63,55.32 42.63,56.69 42.76,56.82 45.4,56.82 45.65,56.57 45.65,55.6 45.75,55.5 47.53,55.5 47.66,55.37 47.66,52.7 47.53,52.58
GND on BOTTOM: 50.33,215.52 50.07,215.77 50.07,216.66 49.69,217.04 49.69,224.92 50.33,225.55 65.31,225.55 65.57,225.3 65.57,221.74 65.44,221.62 54.52,221.62 54.14,221.23 52.61,221.23 52.36,220.98 52.36,215.65 52.23,215.52 ; 3 cut-outs
GND on L2GND: outline of 118 points within 0.76,0.76 184.24,229.24 ; 39 cut-outs
GND on L2GND: 160.62,15.76 160.62,21.77 163.18,24.32 167.63,24.32 168.37,25.07 168.37,66.47 170.17,68.26 173.98,68.26 177.02,71.31 179.15,71.31 180.17,70.29 184.24,70.29 184.24,67.9 184.17,67.73 184,67.66 178,67.66 176.75,67.15 176.24,65.9 176.24,60.9 176.17,60.73 176,60.66 171,60.66 169.75,60.15 169.24,58.9 169.24,16 169.17,15.83 169,15.76
GND on L3: outline of 138 points within 0.76,0.76 184.24,229.24 ; 1 cut-out
GND on L3: 49.44,31.75 51.85,31.75 52.74,30.86 52.74,22.99 50.33,20.57 47.53,20.57 46.77,21.34 46.77,29.08
GND on L3: 49.82,117.73 118.27,117.73 130.46,105.54 130.46,99.95 129.07,98.55 129.07,86.11 127.16,84.2 118.52,84.2 115.35,87.38 115.35,96.77 115.1,97.03 113.95,97.03 113.32,96.39 113.32,87.63 112.3,86.61 78.9,86.61 78.52,86.23 52.36,86.23 48.29,90.3 48.29,116.2 ; 1 cut-out
GND on L4: 47.53,32 52.1,32 52.87,31.24 52.87,21.97 51.09,20.19 48.04,20.19 46.64,21.59 46.64,31.11
GND on L4: 76.74,115.06 126.4,115.06 131.48,109.98 131.48,95.12 128.18,91.82 120.68,91.82 115.86,87 105.82,87 99.73,80.9 86.52,80.9 81.87,85.55 81.87,87.3 80.63,88.54 75.7,88.54 75.09,89.15 75.09,113.41 ; 1 cut-out
GND on L4: 53.25,135.51 69.38,135.51 72.3,132.59 72.3,105.92 71.41,105.03 71.41,86.87 70.26,85.72 63.91,85.72 54.39,95.25 47.4,95.25 46.64,96.01 46.64,120.02 49.31,122.68 49.31,125.6 52.74,129.03 52.74,135
GND on L4: outline of 145 points within 0.76,0.76 184.24,229.24 ; 1 cut-out
GND on L5GND: outline of 115 points within 0.76,0.76 184.24,229.24 ; 23 cut-outs
VCC on TOP: 146.34,7.62 146.21,7.75 146.21,8.89 146.34,9.02 149.39,9.02 149.49,8.92 149.49,7.98 149.39,7.87 148.24,7.87 147.99,7.62 ; 1 cut-out
VCC on TOP: 107.48,30.61 107.22,30.86 107.22,33.53 107.35,33.66 108.49,33.66 109.76,32.38 109.76,30.73 109.63,30.61 ; 1 cut-out
VCC on TOP: 5.24,188.34 5.11,188.47 5.11,208.53 5.37,208.79 8.67,208.79 8.8,208.66 8.8,188.47 8.67,188.34
VCC on BOTTOM: 30.23,107.19 30.13,107.29 30.13,115.9 30.46,116.23 32.37,116.23 32.55,116.05 32.55,107.21 32.52,107.19 ; 2 cut-outs
VCC on BOTTOM: 141.28,22.73 140.29,23.72 140.29,25.55 140.65,25.91 147.48,25.91 147.61,25.78 147.61,23.11 147.23,22.73
VCC on BOTTOM: 4.73,186.69 4.61,186.82 4.61,190.37 4.73,190.5 8.29,190.5 8.42,190.37 8.42,186.82 8.29,186.69
VCC on BOTTOM: 108.24,30.73 108.11,30.86 108.11,32.89 108.24,33.02 111.92,33.02 112.05,32.89 112.05,30.86 111.92,30.73
VCC on BOTTOM: 5.37,207.77 5.24,207.9 5.24,209.93 5.37,210.06 9.05,210.06 9.18,209.93 9.18,207.9 9.05,207.77
VCC on BOTTOM: 92.36,59.05 91.98,59.44 85.5,59.44 84.62,60.33 84.62,68.45 84.87,68.71 86.65,68.71 86.9,68.45 86.9,62.99 87.66,62.23 93.63,62.23 94.01,61.85 94.01,59.18 93.89,59.05
VCC on L3: 85.89,64.9 86.39,65.41 86.39,68.07 85.76,68.71 84.36,68.71 82.58,66.93 75.34,66.93 75.09,66.67 75.09,65.28 75.47,64.9
VCC on L3: 31.02,113.92 31.28,114.17 32.8,114.17 33.05,113.92 33.05,109.6 32.93,109.47 31.15,109.47 31.02,109.6
VCC on L4: 148.88,7.49 148.75,7.37 146.97,7.37 146.59,7.75 146.59,11.56 146.85,11.81 148.75,11.81 148.88,11.68
VCC on L4: 149.64,21.84 149.51,21.72 145.45,21.72 145.32,21.84 145.32,25.4 145.58,25.65 149.51,25.65 149.64,25.53
VCC on L4: 107.35,34.92 107.35,31.24 107.6,30.99 109.63,30.99 109.76,31.11 109.76,34.92 109.63,35.05 107.48,35.05
VCC on L4: 92.24,59.82 92.24,58.29 92.62,57.91 96.05,57.91 96.3,58.17 96.3,59.94 96.05,60.2 92.62,60.2
VCC3 on TOP: 115.68,108.13 115.5,108.31 115.5,110.19 115.7,110.39 117.33,110.39 117.61,110.11 117.61,108.56 117.18,108.13 ; 2 cut-outs
VCC3 on TOP: 79.54,86.59 79.2,86.92 79.2,88.27 79.36,88.42 80.32,88.42 80.47,88.27 80.47,86.69 80.37,86.59
VCC3 on TOP: 162.44,86.51 162.34,86.61 162.34,87.38 162.21,87.5 161.27,87.5 160.94,87.83 160.94,91.44 161.55,92.05 163,92.05 163.18,91.87 163.18,90.35 163.41,90.12 164.14,90.12 165.11,89.15 165.11,87.48 164.7,87.07 163.2,87.07 162.64,86.51 ; 2 cut-outs
VCC3 on TOP: 156.62,140.46 156.5,140.59 156.5,146.18 156.75,146.43 158.28,146.43 158.4,146.3 158.4,142.62 158.53,142.49 162.85,142.49 162.97,142.37 162.97,140.84 162.59,140.46 ; 2 cut-outs
VCC3 on TOP: 146.41,4.29 146.21,4.5 146.21,6.35 146.34,6.48 148.37,6.48 148.71,6.13 149.4,6.13 149.49,6.05 149.49,4.6 149.18,4.29
VCC3 on TOP: 84.54,117.68 84.36,117.86 84.36,119.18 84.69,119.51 87.71,119.51 87.87,119.35 87.87,117.91 87.64,117.68 ; 2 cut-outs
VCC3 on BOTTOM: 159.8,81.18 159.67,81.31 159.67,82.68 159.95,82.96 162.52,82.96 163.18,83.62 165.23,83.62 165.29,83.57 165.29,81.66 164.8,81.18 ; 1 cut-out
VCC3 on BOTTOM: 150.4,54.36 150.27,54.48 150.27,55.75 150.4,55.88 155.86,55.88 155.99,55.75 155.99,54.48 155.86,54.36 ; 3 cut-outs
VCC3_CAM on BOTTOM: 158.12,188.14 157.92,188.34 157.92,191.36 157.01,192.28 157.01,194.06 157.13,194.18 161.37,194.18 161.63,193.93 161.63,188.37 161.4,188.14 ; 4 cut-outs
VCC5_PANEL on TOP: 41.82,107.2 41.69,107.33 41.69,108.73 41.82,108.86 43.85,108.86 43.98,108.73 43.98,107.33 43.85,107.2
VCC5_PANEL on BOTTOM: 41.51,104.14 41.44,104.22 41.44,106.38 41.21,106.6 39.99,106.6 39.91,106.68 39.91,109.73 40.04,109.86 43.85,109.86 43.98,109.73 43.98,107.19 43.85,107.06 42.45,107.06 42.2,106.81 42.2,104.27 42.07,104.14 ; 6 cut-outs
VCC5_USB on TOP: 87.28,45.72 87.16,45.85 87.16,48.9 87.54,49.28 103.92,49.28 104.68,48.51 110.65,48.51 111.67,49.53 113.06,49.53 113.32,49.28 113.32,46.86 112.17,45.72
VCC5_USB on TOP: 167.67,123.83 167.55,123.95 167.55,127.13 168.18,127.76 169.45,127.76 169.58,127.64 169.58,126.11 168.82,125.35 168.82,123.95 168.69,123.83 ; 2 cut-outs
VCC5_USB on TOP: 88.93,21.72 88.3,22.35 86.65,22.35 86.39,22.61 86.39,27.05 86.77,27.43 89.95,27.43 90.2,27.18 90.2,23.75 89.95,23.5 89.95,21.84 89.82,21.72 ; 5 cut-outs
VCC5_USB on TOP: 104.66,16.61 104.02,17.25 104.02,18.06 104.12,18.16 106.61,18.16 106.69,18.08 106.69,17.58 107.09,17.17 107.75,17.17 107.81,17.12 107.81,16.69 107.73,16.61
VCC5_USB on BOTTOM: 164.75,124.38 164.27,124.87 164.27,126.82 165.34,127.89 169.02,127.89 169.43,127.48 169.43,125.17 168.64,124.38
VCC5_USB on BOTTOM: 111.67,48.51 111.29,48.9 111.29,58.29 113.57,60.58 113.57,68.45 115.86,70.74 123.71,70.74 125,72.03 126.37,72.03 126.53,71.88 126.53,68.88 125.97,68.33 118.4,68.33 116.37,66.29 116.37,60.2 113.57,57.4 113.57,48.9 113.19,48.51
VCC5_USB on BOTTOM: 23.32,3.84 22.64,4.52 22.64,6.99 22.77,7.11 23.78,7.11 24.09,6.81 24.09,5.33 24.39,5.03 26.93,5.03 27.06,4.9 27.06,4.09 26.8,3.84
VCC5_USB on BOTTOM: 123.53,88.67 122.87,89.33 122.87,93.75 123.15,94.03 127.01,94.03 127.41,93.62 127.41,89.38 126.7,88.67
VCC5_USB on L3: 87.82,18.87 87.08,18.87 86.7,18.49 86.7,17.73 88.7,15.72 97.7,15.72 100.44,18.47 102.9,18.47 104.17,17.2 105.16,17.2 105.37,17.4 105.37,19 104.45,19.91 99.88,19.91 97.32,17.35 89.34,17.35
VCC5_USB on L4: 88.55,48.13 88.93,47.75 88.93,45.09 88.55,44.7 86.9,44.7 86.39,45.21 86.39,47.75 86.77,48.13
VCC5_USB on L4: 123.22,91.31 125.81,91.31 126.3,90.83 126.3,68.73 126.02,68.45 123.05,68.45 122.79,68.71 122.79,90.88
VCC_FAN on BOTTOM: 5.37,210.69 5.24,210.82 5.24,213.74 5.37,213.87 13.11,213.87 13.37,213.61 15.4,213.61 15.53,213.49 15.53,211.07 15.4,210.95 13.24,210.95 12.99,210.69
VCC_VTT on TOP: 136.3,75.82 136.18,75.95 136.18,80.77 134.4,82.55 134.4,83.44 134.53,83.57 136.05,83.57 136.18,83.44 136.18,82.17 136.43,81.92 139.45,81.92 141.27,80.1 141.27,79.49 141.26,79.48 141.05,79.48 140.93,79.35 140.93,78.77 140.83,78.66 139.28,78.66 138.97,78.36 138.97,77.09 137.7,75.82
VDDNB on TOP: 26.53,167.92 26.17,168.28 26.17,178.28 26.58,178.69 33.82,178.69 34.72,177.79 34.72,174.79 34.86,174.65 38.51,174.65 39.35,173.81 39.35,168.76 38.51,167.92
VDDNB on BOTTOM: 81.95,155.32 81.82,155.45 81.82,156.08 81.69,156.21 79.66,156.21 79.15,156.72 79.15,158.88 79.66,159.38 81.57,159.38 81.69,159.26 81.69,157.61 81.82,157.48 84.11,157.48 84.23,157.61 84.23,159.26 84.36,159.38 86.39,159.38 86.9,158.88 86.9,156.72 86.39,156.21 82.84,156.21 82.71,156.08 82.71,155.45 82.58,155.32 ; 12 cut-outs
VDDNB on BOTTOM: 27.72,168.15 27.34,168.53 27.34,173.99 27.85,174.5 39.28,174.5 39.53,174.24 39.53,168.4 39.28,168.15
VDDNB on L3: 78.65,159 78.65,157.35 79.15,156.84 86.77,156.84 87.03,157.1 87.03,158.62 86.39,159.26 78.9,159.26
VDDNB on L4: 78.14,159 75.73,156.59 74.46,156.59 68.36,162.69 61.37,162.69 57.95,166.12 51.21,166.12 47.91,169.42 47.91,173.23 45.37,175.77 28.48,175.77 27.34,174.62 27.34,169.16 27.97,168.53 36.99,168.53 50.33,155.19 61.5,155.19 62.77,153.92 63.91,153.92 66.71,151.13 69.63,151.13 72.8,147.96 87.41,147.96 88.43,148.97 88.43,158.88 88.3,159
0D95V_S0 on TOP: 82.96,151 82.71,151.26 82.71,152.15 82.84,152.27 82.84,152.65 82.71,152.78 82.71,152.91 82.96,153.16 83.09,153.16 83.35,152.91 83.85,152.91 84.11,153.16 84.23,153.16 84.49,152.91 84.87,152.91 85.12,152.65 85.12,151.89 84.23,151
0D95V_S0 on TOP: 46.74,134.37 46.34,134.77 46.34,135.56 46.01,135.89 44.61,135.89 44.48,136.02 44.48,138.05 45.88,139.45 49.06,139.45 49.31,139.19 49.31,134.75 48.93,134.37 ; 4 cut-outs
0D95V_S0 on BOTTOM: 81.19,121.16 78.77,123.57 78.77,124.21 79.28,124.71 82.71,124.71 83.47,123.95 83.47,122.3 82.33,121.16
0D95V_S0 on BOTTOM: 97.75,134.87 97.19,135.43 97.19,139.93 95.82,141.3 90.63,141.3 86.65,145.29 86.65,148.46 84.87,150.24 83.35,150.24 83.22,150.37 83.22,152.27 83.35,152.4 86.52,152.4 87.16,151.76 97.57,151.76 98.39,150.94 99.79,150.94 100.55,150.18 107.09,150.18 107.19,150.08 107.19,135 107.06,134.87 ; 17 cut-outs
0D95V_S0 on L3: 69.63,127.13 52.99,127.13 49.18,130.94 46.9,130.94 45.88,131.95 45.88,135.89 46.11,136.12 46.11,136.14 49.87,136.14 49.91,136.11 54.3,136.11 55.91,134.49 69.25,134.49 79.15,124.59 81.06,124.59 82.71,122.94 82.71,119.38 82.58,119.25 77.5,119.25
0D95V_S0 on L4: 97.06,136.78 98.46,136.78 103.28,131.95 103.28,131.06 92.11,119.89 79.66,119.89 79.03,120.52 79.03,124.71 81.19,126.87 87.16,126.87
0D95V_S5 on TOP: 42.2,141.86 40.17,143.89 40.17,149.99 40.8,150.62 40.8,153.03 40.55,153.29 40.55,157.86 40.93,158.24 43.85,158.24 45.37,156.72 49.69,156.72 50.45,155.96 50.45,142.62 49.69,141.86 ; 4 cut-outs
1D5V_S5 on TOP: 34.13,142.56 33.94,142.75 33.94,145.41 34.07,145.54 35.72,145.54 36.1,145.16 36.1,142.88 35.78,142.56
1D8V_S0 on TOP: 43.47,124.08 43.34,124.21 43.34,130.43 43.47,130.56 45.25,130.56 45.37,130.43 45.37,128.91 45.25,128.78 45.25,126.11 44.74,125.6 44.74,124.21 44.61,124.08 ; 5 cut-outs
1D8V_S0 on BOTTOM: 119.54,100.2 119.41,100.33 119.41,101.09 119.67,101.35 121.83,101.35 121.95,101.22 121.95,100.33 121.83,100.2
1D8V_S5 on TOP: 100.36,72.39 100.24,72.52 100.24,75.82 100.36,75.95 100.36,77.09 100.49,77.22 105.82,77.22 105.95,77.09 105.95,76.07 106.84,75.18 106.84,73.41 105.82,72.39 ; 8 cut-outs
1D8V_S5 on TOP: 41.69,130.81 40.67,131.83 40.67,133.35 40.93,133.6 45.12,133.6 45.5,133.22 45.5,130.94 45.37,130.81
1D8V_S5 on BOTTOM: 116.87,100.08 116.62,100.33 116.62,102.87 116.87,103.12 118.78,103.12 119.03,102.87 119.03,101.85 118.78,101.6 118.27,101.6 118.14,101.47 118.14,100.46 117.76,100.08 ; 4 cut-outs
1D8V_S5 on L3: 105.57,83.57 112.81,83.57 113.32,84.07 113.32,85.47 112.56,86.23 105.7,86.23 105.44,85.98 105.44,83.69
1D8V_S5 on L3: 40.72,130.07 40.72,132.41 41.79,133.48 42.91,133.48 43.01,133.38 43.01,130.02 42.86,129.87 40.93,129.87
1D8V_S5 on L4: 99.73,73.66 112.17,73.66 113.44,74.93 113.44,85.09 112.56,85.98 106.21,85.98 105.57,85.34 105.57,78.61 105.32,78.36 99.6,78.36 99.22,77.98 99.22,74.17
1D8V_S5 on L4: 43.21,133.6 43.09,133.73 41.18,133.73 40.17,132.72 40.17,131.19 40.42,130.94 42.96,130.94 43.21,131.19
1D35V_S3 on TOP: 134.91,104.14 134.53,104.52 134.53,106.55 135.03,107.06 135.03,108.58 134.78,108.84 134.78,118.24 135.29,118.75 141.13,118.75 141.26,118.87 141.26,121.41 141.38,121.54 151.04,121.54 151.29,121.28 151.29,109.98 145.45,104.14 ; 2 cut-outs
1D35V_S3 on BOTTOM: 90.84,156.59 90.71,156.72 90.71,171.7 90.84,171.83 96.68,171.83 98.46,173.61 98.71,173.61 106.21,166.12 106.21,161.8 101,156.59 ; 26 cut-outs
1D35V_S3 on L2GND: 108.95,147.76 101.2,155.51 99.55,155.51 98.92,156.15 96.12,156.15 95.49,156.78 88.76,156.78 88.49,157.05 88.49,170.36 89.01,170.88 94.85,170.88 95.98,172.01 95.98,172.77 97.27,174.05 102.6,174.05 102.98,174.43 123.91,174.43 127.21,171.13 130.13,171.13 131.53,169.74 139.4,169.74 141.43,167.7 158.2,167.7 158.47,167.43 158.47,156.29 153.37,151.19 145.88,151.19 144.99,150.3 140.54,150.3 139.15,148.91 135.97,148.91 135.59,148.53 132.29,148.53 131.53,147.76
1D35V_S3 on L3: 140.88,121.16 141.26,120.78 160.18,120.78 164.37,124.97 164.37,166.88 163.99,167.26 156.88,167.26 156.37,166.75 156.37,133.35 154.02,131 154.02,127.57 152.5,126.05 141.32,126.05 140.88,125.6
1D35V_S3 on L4: 88.81,170.69 88.68,170.56 88.68,158.24 90.33,156.59 97.7,156.59 97.95,156.84 97.95,164.59 97.57,164.97 97.57,165.48 97.95,165.86 97.95,170.31 97.57,170.69
1D35V_S3 on L5GND: 140.83,151.83 139.43,153.23 132.83,153.23 132.43,153.62 132.43,164.89 133.46,165.93 141.59,165.93 142.99,167.32 153.37,167.32 153.51,167.18 153.51,152.1 153.24,151.83
AD+_2 on TOP: 66.58,30.73 66.33,30.99 66.33,34.04 67.6,35.31 67.6,37.21 67.72,37.34 68.61,37.34 68.74,37.21 68.74,31.24 68.23,30.73 ; 6 cut-outs
AD+_TO_SYS on TOP: 57.18,40.26 56.55,40.89 53.75,40.89 53.63,41.02 53.63,42.04 52.87,42.8 52.87,46.23 53.25,46.61 57.18,46.61 57.31,46.48 57.31,45.34 57.44,45.21 57.82,45.21 57.95,45.34 57.95,46.48 58.07,46.61 59.09,46.61 59.22,46.48 59.22,40.39 59.09,40.26 ; 1 cut-out
AD+_TO_SYS on BOTTOM: 56.8,38.86 56.68,38.99 56.68,46.48 56.8,46.61 59.22,46.61 59.34,46.48 59.34,38.99 59.22,38.86
AD_JK on TOP: 54.39,23.5 53.5,24.38 53.5,28.19 54.01,28.7 54.9,28.7 56.29,30.1 56.29,30.86 56.55,31.11 56.55,38.61 56.68,38.73 62.01,38.73 63.41,37.34 67.22,37.34 67.34,37.21 67.34,35.56 66.07,34.29 66.07,27.43 65.44,26.8 61.88,26.8 60.23,25.15 60.23,24.38 59.34,23.5 ; 8 cut-outs
AD_JK on BOTTOM: 54.01,20.57 53.5,21.08 53.5,28.7 53.63,28.83 55.02,28.83 55.53,29.34 55.53,30.73 56.42,31.62 59.47,31.62 59.72,31.37 66.33,31.37 66.45,31.24 66.45,28.19 58.83,20.57
AD_JK on L3: 53.75,32.13 64.68,32.13 65.44,31.37 65.44,29.21 60.36,24.13 54.01,24.13 53.25,24.89 53.25,31.62
AD_JK on L4: 53.5,31.75 64.8,31.75 65.44,31.11 65.44,29.59 60.1,24.26 53.88,24.26 53.25,24.89 53.25,31.5
AUD_DVDD on TOP: 162.29,81.89 162.16,82.02 162.16,83.52 161.63,84.05 160.82,84.05 160.64,84.23 160.64,84.89 160.43,85.09 160.05,85.09 159.93,85.22 159.93,87.1 160.05,87.22 161.98,87.22 162.1,87.11 162.1,85.1 163.18,84.02 163.18,82.3 162.77,81.89 ; 2 cut-outs
BT+ on TOP: 48.29,61.09 47.02,62.36 42.45,62.36 40.42,64.39 37.37,64.39 37.24,64.52 37.24,66.93 36.99,67.18 30.64,67.18 30.51,67.31 30.51,71.25 30.64,71.37 39.61,71.37 40.34,70.64 41.54,70.64 41.82,70.36 41.82,66.67 42.32,66.17 48.55,66.17 50.2,64.52 51.72,64.52 51.85,64.39 51.85,61.21 51.72,61.09 ; 4 cut-outs
BT+ on BOTTOM: 34.22,68.02 33.84,68.4 33.84,71.12 34.09,71.37 36.81,71.37 37.09,71.09 37.09,68.25 36.86,68.02 ; 2 cut-outs
BT+ on BOTTOM: 48.93,61.21 48.67,61.47 48.67,65.28 48.8,65.41 49.82,65.41 50.07,65.66 50.96,65.66 51.85,64.77 51.85,61.47 51.6,61.21
BT+_R on BOTTOM: 46.9,61.59 45.88,62.61 40.93,62.61 40.67,62.87 40.67,65.66 40.93,65.91 46.52,65.91 47.02,65.41 48.04,65.41 48.17,65.28 48.17,61.72 48.04,61.59
CAGND on TOP: 34.32,29.84 33.43,30.73 33.43,34.8 33.69,35.05 35.72,35.05 36.23,35.56 36.23,38.35 36.36,38.48 38.46,38.48 38.84,38.86 38.84,39.7 39.02,39.88 40.37,39.88 40.5,39.75 40.5,37.52 40.27,37.29 40.27,36.63 40.65,36.25 40.65,34.29 41.13,33.81 41.13,33.35 41.05,33.27 40.6,33.27 39.76,34.11 39.76,34.8 39.5,35.05 37.88,35.05 36.74,33.91 35.85,33.91 35.34,33.4 35.34,32.13 35.59,31.88 37.88,31.88 38.01,31.75 38.01,30.35 37.5,29.84 ; 17 cut-outs
CPU_VCORE on TOP: 41.94,171.7 38.62,175.03 35.44,175.03 35.21,175.26 35.21,178.13 35.64,178.56 42.2,178.56 42.58,178.94 42.58,180.21 45.18,182.82 47.72,182.82 48.17,183.26 48.17,185.8 48.52,186.16 59.47,186.16 60.36,185.27 60.36,179.96 52.1,171.7
CPU_VCORE on BOTTOM: 73.69,156.84 73.57,156.97 73.57,168.4 73.69,168.53 88.55,168.53 88.68,168.4 88.68,159.64 88.55,159.51 78.39,159.51 75.73,156.84 ; 33 cut-outs
CPU_VCORE on L3: 77.88,167 77.88,159.64 78.14,159.38 88.04,159.38 88.17,159.51 88.17,167 88.04,167.13 78.01,167.13
CPU_VCORE on L4: 75.47,175.39 87.28,175.39 88.43,174.24 88.43,159.51 88.17,159.26 77.88,159.26 75.6,156.97 74.58,156.97 74.33,157.23 74.33,157.35 62.9,168.78 50.96,168.78 49.56,170.18 49.56,183.9 49.58,183.91 49.58,185.33 50.17,185.93 64.93,185.93
DC_19V on TOP: 59.85,39.12 59.72,39.24 59.72,46.35 59.98,46.61 63.15,46.61 63.41,46.35 63.41,43.94 63.53,43.81 68.61,43.81 68.74,43.69 68.74,39.24 68.61,39.12 ; 4 cut-outs
DC_19V on TOP: 42.53,70.31 42.37,70.46 42.37,71.35 42.68,71.65 42.68,72.54 42.81,72.67 43.8,72.67 44.53,71.93 48.65,71.93 48.72,71.86 48.72,70.71 48.32,70.31 ; 3 cut-outs
DC_19V on BOTTOM: 59.98,38.86 59.85,38.99 59.85,46.35 59.98,46.48 63.03,46.48 63.53,45.97 63.53,39.62 62.77,38.86
DCBATOUT on TOP: 67.95,44.42 66.84,45.54 66.15,45.54 65.87,45.82 65.87,47.29 66.78,48.21 69.25,48.21 69.6,47.85 69.6,44.91 69.12,44.42 ; 1 cut-out
DCBATOUT on TOP: 38.54,52.3 38.29,52.55 38.29,58.37 38.46,58.55 42.27,58.55 42.53,58.29 42.53,54.38 42.81,54.1 42.81,52.5 42.6,52.3 ; 2 cut-outs
DCBATOUT on TOP: 51.09,46.48 50.71,46.86 50.71,50.62 50.96,50.88 55.68,50.88 57.56,49 57.56,47.37 57.31,47.12 53.12,47.12 52.48,46.48 ; 1 cut-out
DCBATOUT on TOP: 130.4,86.3 129.95,86.74 129.95,94.87 130.59,95.5 139.23,95.5 139.35,95.38 139.35,90.17 139.23,90.04 138.46,90.04 138.08,89.66 138.08,87.5 137.57,87 135.03,87 134.34,86.3
DCBATOUT on TOP: 22.44,162.31 21.88,162.86 21.88,166.17 22.13,166.42 24.65,166.42 25.05,166.01 25.05,162.56 24.8,162.31
DCBATOUT on TOP: 112.17,19.68 111.03,20.83 111.03,26.92 111.29,27.18 114.08,27.18 114.21,27.05 114.21,19.81 114.08,19.68
DCBATOUT on TOP: 50.96,86.61 49.18,88.39 49.18,127.03 46.06,130.15 46.06,131.57 46.97,132.49 55.94,132.49 56.55,131.88 56.55,87.33 55.84,86.61
DCBATOUT on TOP: 7.02,151.13 6.89,151.26 6.89,154.31 10.45,157.86 10.45,162.18 7.53,165.1 7.53,167.77 9.69,169.93 12.99,169.93 13.37,169.54 13.37,161.93 14.13,161.16 14.13,159 13.11,157.99 13.11,151.26 12.99,151.13
DCBATOUT on TOP: 97.44,57.4 94.65,60.2 90.46,60.2 88.81,61.85 88.81,64.9 88.93,65.02 90.46,65.02 90.58,64.9 90.58,62.87 91.47,61.98 95.92,61.98 98.59,59.31 103.67,59.31 103.79,59.18 103.79,57.48 103.72,57.4
DCBATOUT on TOP: 19.21,191.52 19.08,191.64 19.08,201.68 19.34,201.93 22.64,201.93 22.89,202.18 22.89,208.91 23.4,209.42 40.04,209.42 42.4,211.79 42.4,218.44 42.55,218.59 48.57,218.59 48.93,218.24 48.93,209.68 46.9,207.65 46.9,202.06 50.07,202.06 50.2,201.93 50.2,191.64 50.07,191.52 44.74,191.52 44.61,191.64 44.61,196.22 41.56,199.26 41.56,202.44 41.18,202.82 28.1,202.82 27.59,202.31 27.59,198.88 24.93,196.22 24.93,191.64 24.8,191.52 ; 4 cut-outs
DCBATOUT on TOP: 68.51,26.19 68.33,26.37 68.33,28.93 68.82,29.41 69.76,29.41 70.09,29.08 70.09,26.44 69.83,26.19 ; 1 cut-out
DCBATOUT on TOP: 42.32,66.67 42.07,66.93 42.07,69.65 42.43,70 48.65,70 48.93,69.72 48.93,67.06 48.55,66.67 ; 2 cut-outs
DCBATOUT on BOTTOM: 36.99,51.94 36.86,52.07 36.86,53.04 38.21,54.38 42.93,54.38 42.96,54.36 42.96,52.07 42.83,51.94 ; 1 cut-out
DCBATOUT on BOTTOM: 16.67,163.19 16.29,163.58 12.73,163.58 8.92,167.39 8.92,168.66 9.94,169.67 9.94,186.31 14.13,190.5 14.13,195.58 20.99,202.44 20.99,206.5 21.5,207.01 35.34,207.01 37.37,209.04 39.66,209.04 42.45,211.84 42.45,218.72 43.26,219.53 48.83,219.53 49.31,219.05 49.31,216.66 49.69,216.28 49.69,215.39 50.2,214.88 54.14,214.88 54.26,214.76 54.26,209.42 54.14,209.3 50.07,209.3 49.82,209.04 49.82,197.74 49.44,197.36 41.31,197.36 41.18,197.49 41.18,202.31 40.8,202.69 28.61,202.69 28.23,202.31 28.23,195.83 23.15,190.75 23.15,188.09 20.48,185.42 20.48,171.2 23.78,167.89 23.78,163.58 23.4,163.19 ; 2 cut-outs
DCBATOUT on BOTTOM: 89.19,62.87 88.81,63.25 88.81,66.87 84.23,71.44 73.88,71.44 73.19,70.74 68.74,70.74 68.61,70.87 68.61,77.98 69.25,78.61 79.92,78.61 88.93,87.63 126.27,87.63 129.95,91.31 129.95,94.87 130.84,95.76 138.34,95.76 138.59,95.5 138.59,87.88 130.46,79.76 93,79.76 91.09,77.85 91.09,73.41 90.58,72.9 90.58,63.25 90.2,62.87 ; 2 cut-outs
DCBATOUT on BOTTOM: 34.96,126.75 32.67,129.03 32.67,132.72 29.37,136.02 16.92,136.02 15.78,137.16 15.78,139.83 15.91,139.95 34.7,139.95 42.58,132.08 49.06,132.08 49.56,131.57 49.56,127 49.31,126.75
DCBATOUT on BOTTOM: 113.32,4.32 113.19,4.45 113.19,20.32 111.03,22.48 111.03,26.8 111.16,26.92 117.76,26.92 118.52,26.16 118.52,14.1 119.54,13.08 119.54,9.78 117.76,8 117.76,4.39 117.69,4.32
DCBATOUT on L3: 49.82,43.94 46.9,46.86 40.67,46.86 37.88,49.66 37.88,53.78 38.13,54.04 50.52,54.04 54.01,50.55 68.74,50.55 69.25,50.04 69.25,45.72 67.47,43.94
DCBATOUT on L3: 6.89,155.96 6.89,151.26 7.15,151 9.56,151 10.07,151.51 10.07,165.48 12.99,168.4 12.99,169.54 12.61,169.93 9.81,169.93 8.42,168.53 8.42,157.48
DCBATOUT on L3: 113.19,28.07 113.19,24.51 111.54,22.86 68.61,22.86 68.49,22.99 68.49,28.07 68.61,28.19 113.06,28.19
DCBATOUT on L4: 15.02,140.72 15.02,146.43 14.13,147.32 14.13,150.88 11.84,153.16 11.84,166.75 12.86,167.77 12.86,169.67 12.61,169.93 9.56,169.93 8.67,169.04 7.02,169.04 6.64,168.66 6.64,163.83 8.67,161.8 8.67,158.12 6.64,156.08 6.64,134.24 7.02,133.86 19.21,133.86 19.46,134.11 19.46,136.27
DCBATOUT on L4: 70.52,26.16 68.61,26.16 66.84,27.94 66.84,47.73 69.73,50.62 69.73,60.71 67.8,62.64 67.8,65.02 67.42,65.41 63.15,65.41 62.77,65.79 62.77,65.91 61.76,66.93 58.33,66.93 56.23,64.83 44.67,64.83 44.48,65.02 44.48,69.47 46.77,71.75 55.02,71.75 56.68,73.41 56.68,80.77 48.42,89.03 48.42,93.09 49.69,94.36 53.75,94.36 72.55,75.56 72.55,72.39 76.23,68.71 76.23,47.37 73.69,44.83 72.55,44.83 71.92,44.2 71.92,27.56
EMMC_VCC on TOP: 114.92,103.4 114.61,103.71 114.61,104.83 114.82,105.03 117,105.03 117.15,104.88 117.15,103.63 116.92,103.4 ; 1 cut-out
EMMC_VCC on BOTTOM: 107.09,102.49 106.59,103 106.59,103.63 106.71,103.76 107.73,103.76 107.98,103.5 108.24,103.5 108.62,103.89 108.62,104.14 109.38,104.9 112.56,104.9 113.16,105.51 115.3,105.51 115.88,104.93 115.88,103.56 115.58,103.25 110.52,103.25 109.76,102.49 ; 3 cut-outs
EMMC_VCCQ on BOTTOM: 110.98,99.21 110.57,99.62 108.85,99.62 108.52,99.95 108.52,100.46 109.2,101.14 109.2,102.01 109.46,102.26 109.86,102.26 110.33,102.73 116.1,102.73 116.24,102.59 116.24,100.25 116.19,100.2 115.1,100.2 114.1,99.21 ; 2 cut-outs
GFX_VCORE on TOP: 55.02,186.94 54.39,187.58 54.39,202.18 57.18,204.98 65.31,204.98 65.44,204.85 65.44,195.83 56.55,186.94
GFX_VCORE on BOTTOM: 74.33,168.91 74.2,169.04 74.2,171.96 74.96,172.72 74.96,173.99 63.28,185.67 56.04,185.67 55.02,186.69 55.02,196.34 55.28,196.6 66.58,196.6 70.26,200.28 101.51,200.28 103.67,198.12 103.67,176.53 101.95,174.82 90.65,174.82 88.68,172.85 88.68,169.04 88.55,168.91 ; 31 cut-outs
GFX_VCORE on L3: 73.95,176.02 73.95,171.2 76.36,168.78 87.92,168.78 88.17,169.04 88.17,177.04 86.65,178.56 76.49,178.56
ISW_1 on BOTTOM: 47.3,44.02 46.57,44.75 44.91,44.75 44.79,44.88 44.79,50.22 44.91,50.34 48.47,50.34 48.6,50.22 48.6,44.17 48.45,44.02
LX on TOP: 39.38,40.51 37.05,42.84 37.05,49.95 38.41,51.31 41.44,51.31 41.66,51.08 41.66,43.87 40.77,42.98 40.77,40.56 40.72,40.51
LX on BOTTOM: 37.37,43.18 37.24,43.31 37.24,48.77 37.37,48.9 41.1,48.9 41.54,48.46 41.54,43.48 41.23,43.18
MCT_R on TOP: 60.23,9.65 60.1,9.78 60.1,14.1 60.23,14.22 62.52,14.22 62.77,13.97 63.79,13.97 63.91,14.1 63.91,17.4 64.04,17.53 66.33,17.53 66.45,17.4 66.45,14.17 65.06,12.78 65.06,10.54 64.42,9.91 62.77,9.91 62.52,9.65 ; 2 cut-outs
PWR_1D8V_LX on TOP: 105.95,64.14 105.82,64.26 105.82,66.04 105.57,66.29 101.51,66.29 101.38,66.42 101.38,69.72 101.51,69.85 107.09,69.85 107.35,69.6 107.35,64.39 107.09,64.14 ; 1 cut-out
PWR_1D8V_LX on BOTTOM: 102.9,66.55 102.78,66.67 102.78,69.6 102.9,69.72 104.68,69.72 104.94,69.47 104.94,66.8 104.68,66.55
PWR_1D8V_SNB on BOTTOM: 105.7,66.29 105.57,66.42 105.57,69.34 105.7,69.47 106.97,69.47 107.09,69.34 107.09,66.42 106.97,66.29 ; 1 cut-out
PWR_3D3V_PHASE2 on TOP: 125.38,5.21 124.24,6.35 124.24,13.84 124.75,14.35 128.3,14.35 129.19,13.46 129.19,5.84 128.56,5.21
PWR_3D3V_PHASE2 on BOTTOM: 126.09,5.84 126.02,5.92 126.02,7.82 127.01,8.81 127.01,10.31 126.25,11.07 124.32,11.07 124.24,11.15 124.24,14.48 124.29,14.53 128.89,14.53 129.19,14.22 129.19,6.15 128.89,5.84
PWR_3D3V_SNB on BOTTOM: 124.47,8.79 124.42,8.84 124.42,9.42 124.29,9.55 123.15,9.55 123.1,9.6 123.1,10.44 123.15,10.49 125.76,10.49 126.45,9.8 126.47,9.8 126.47,9.09 126.17,8.79
PWR_5V_PHASE1 on TOP: 124.8,14.94 124.11,15.62 124.11,24.38 124.87,25.15 128.81,25.15 129.42,24.54 129.42,15.16 129.19,14.94
PWR_5V_PHASE1 on BOTTOM: 124.24,14.86 124.11,14.99 124.11,18.85 124.34,19.08 126.14,19.08 126.37,19.3 126.37,21.01 126.55,21.18 127.57,21.18 127.8,21.41 127.8,22.1 127.39,22.5 127.39,23.04 127.21,23.22 126.19,23.22 126.12,23.29 126.12,24.89 126.13,24.9 126.13,25.01 126.4,25.27 129.07,25.27 129.45,24.89 129.45,15.11 129.19,14.86
PWR_CHG_PHASE on TOP: 43.09,57.15 42.83,57.4 42.83,58.67 42.71,58.8 40.17,58.8 40.04,58.93 40.04,60.33 39.91,60.45 39.78,60.45 39.66,60.58 39.66,60.96 39.78,61.09 45.75,61.09 46.77,60.07 46.77,57.28 46.64,57.15
PWR_CHG_PHASE on BOTTOM: 40.93,57.15 39.53,58.55 39.53,60.83 39.78,61.09 44.86,61.09 45.12,60.83 45.12,57.53 44.74,57.15
PWR_CPU_SNBNB on TOP: 25.69,192.53 25.43,192.79 25.43,194.56 25.94,195.07 27.21,195.07 27.47,194.82 27.47,192.66 27.34,192.53 ; 1 cut-out
PWR_CPU_SNBVDD1 on TOP: 42.07,192.53 41.94,192.66 41.94,194.82 42.2,195.07 43.59,195.07 43.85,194.82 43.85,192.66 43.72,192.53 ; 1 cut-out
PWR_CPU_SW1 on TOP: 35.72,185.04 35.59,185.17 35.59,194.94 35.72,195.07 41.31,195.07 41.44,194.94 41.44,191.39 41.56,191.26 48.42,191.26 48.55,191.13 48.55,188.72 44.86,185.04
PWR_CPU_SW1 on BOTTOM: 35.47,185.29 35.21,185.55 35.21,194.56 35.72,195.07 41.18,195.07 41.31,194.94 41.31,190.88 41.94,190.25 44.48,190.25 45.75,188.98 45.75,186.31 44.74,185.29
PWR_CPU_SW2 on TOP: 20.99,185.04 19.59,186.44 19.59,191.13 19.72,191.26 27.97,191.26 28.1,191.39 28.1,194.94 28.23,195.07 33.69,195.07 33.82,194.94 33.82,185.17 33.69,185.04
PWR_CPU_SW2 on BOTTOM: 24.29,185.04 23.78,185.55 23.78,187.96 25.05,189.23 27.47,189.23 27.72,189.48 27.72,194.82 27.97,195.07 33.69,195.07 33.82,194.94 33.82,185.29 33.56,185.04
PWR_DCBATOUT_1D8V on TOP: 104.17,57.4 104.05,57.53 104.05,59.18 104.3,59.44 104.3,63.12 104.43,63.25 106.08,63.25 106.21,63.12 106.21,61.72 106.84,61.09 106.84,57.53 106.71,57.4
PWR_DCBATOUT_3V on BOTTOM: 118.52,4.27 118.4,4.39 118.4,7.7 118.45,7.75 119.64,7.75 119.87,7.52 122.21,7.52 123.32,8.64 123.32,9.27 123.38,9.32 124.06,9.32 124.11,9.27 124.11,8.56 124.32,8.36 125.28,8.36 125.51,8.13 125.51,4.34 125.43,4.27
PWR_DCBATOUT_5V on TOP: 115.1,19.56 114.97,19.68 114.97,27.18 115.1,27.3 122.46,27.3 123.73,26.04 123.73,24.64 122.21,23.11 119.67,23.11 116.11,19.56
PWR_DCBATOUT_5V on BOTTOM: 123.55,20.8 123.48,20.88 123.48,21.39 121.04,23.83 119.64,23.83 119.46,24 119.46,25.63 120.23,26.39 124.49,26.39 125.51,25.37 125.51,22.07 125.43,22 124.42,22 124.19,21.77 124.19,20.93 124.06,20.8
PWR_DCBATOUT_VDDP on TOP: 25.31,157.73 25.18,157.86 25.18,161.67 25.56,162.05 25.56,165.99 25.94,166.37 28.86,166.37 29.24,165.99 29.24,164.08 29.62,163.7 32.67,163.7 33.05,163.32 33.05,157.99 32.8,157.73 ; 2 cut-outs
PWR_DCBATOUT_VDDP on BOTTOM: 24.77,158.5 24.53,158.73 24.53,162.2 24.64,162.31 27.34,162.31 27.72,161.93 27.72,158.62 27.59,158.5
PWR_GFX_SNB1 on BOTTOM: 52.74,218.57 52.61,218.69 52.61,220.85 52.69,220.93 54.44,220.93 54.52,220.85 54.52,218.69 54.39,218.57 ; 1 cut-out
PWR_GFX_SW1 on TOP: 54.64,211.58 54.52,211.71 54.52,215.77 54.77,216.03 66.96,216.03 67.22,215.77 67.22,214.76 64.04,211.58
